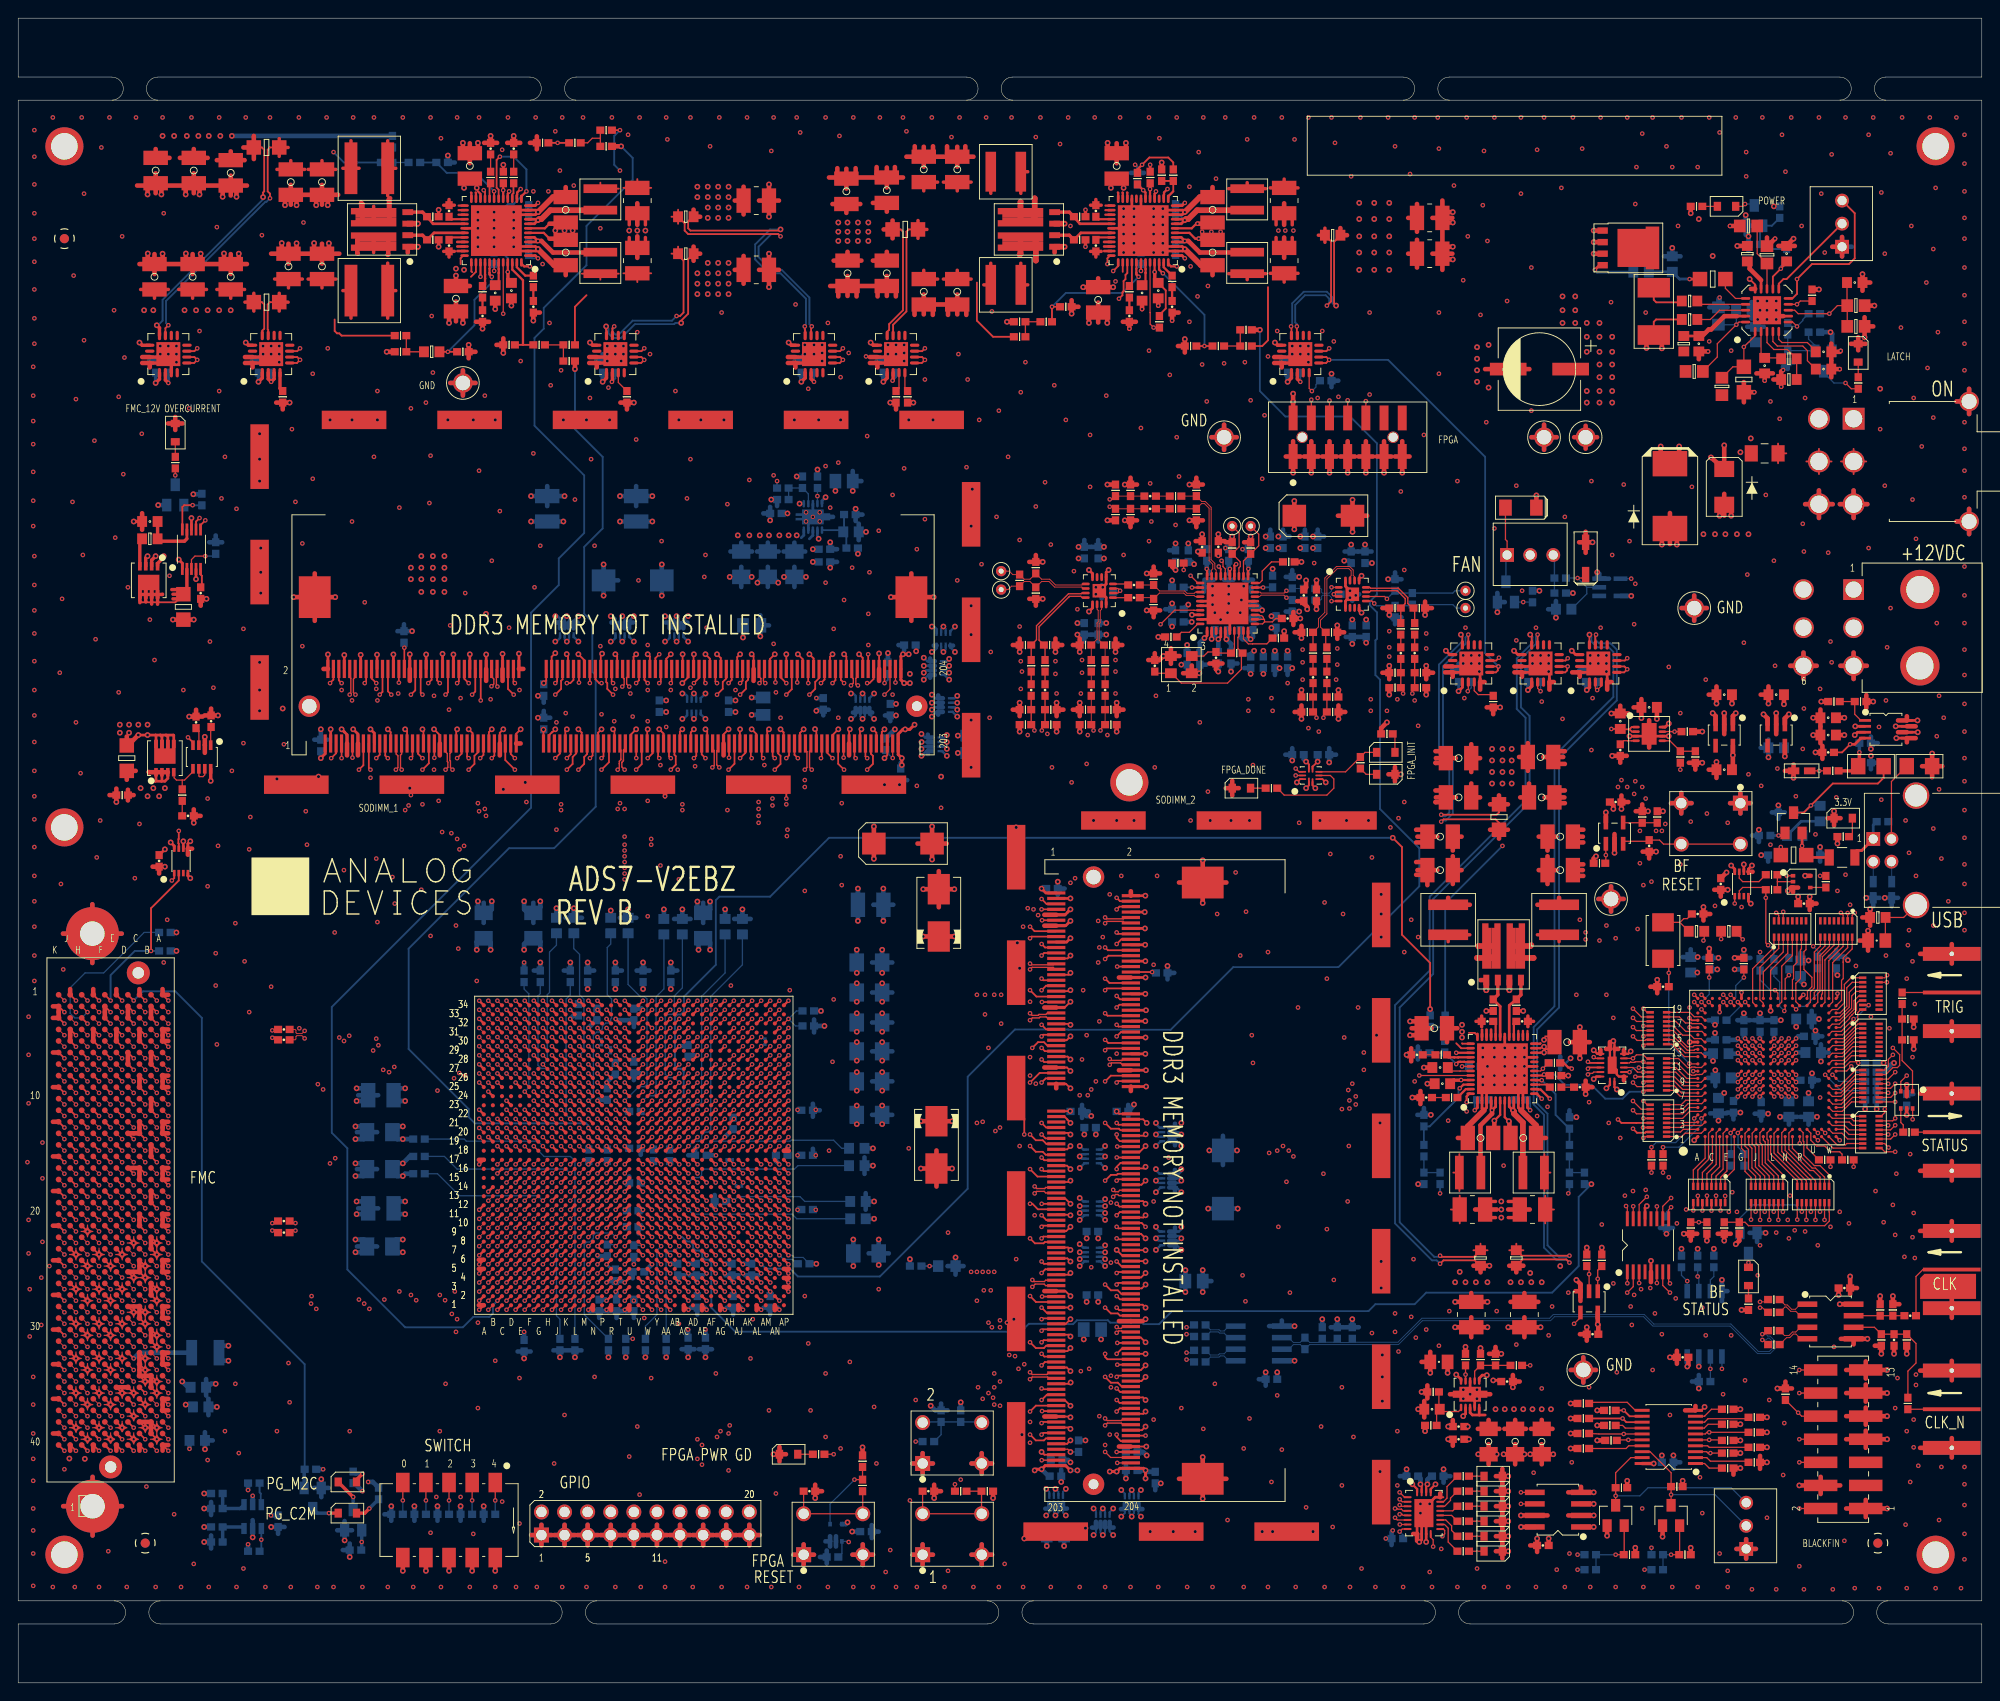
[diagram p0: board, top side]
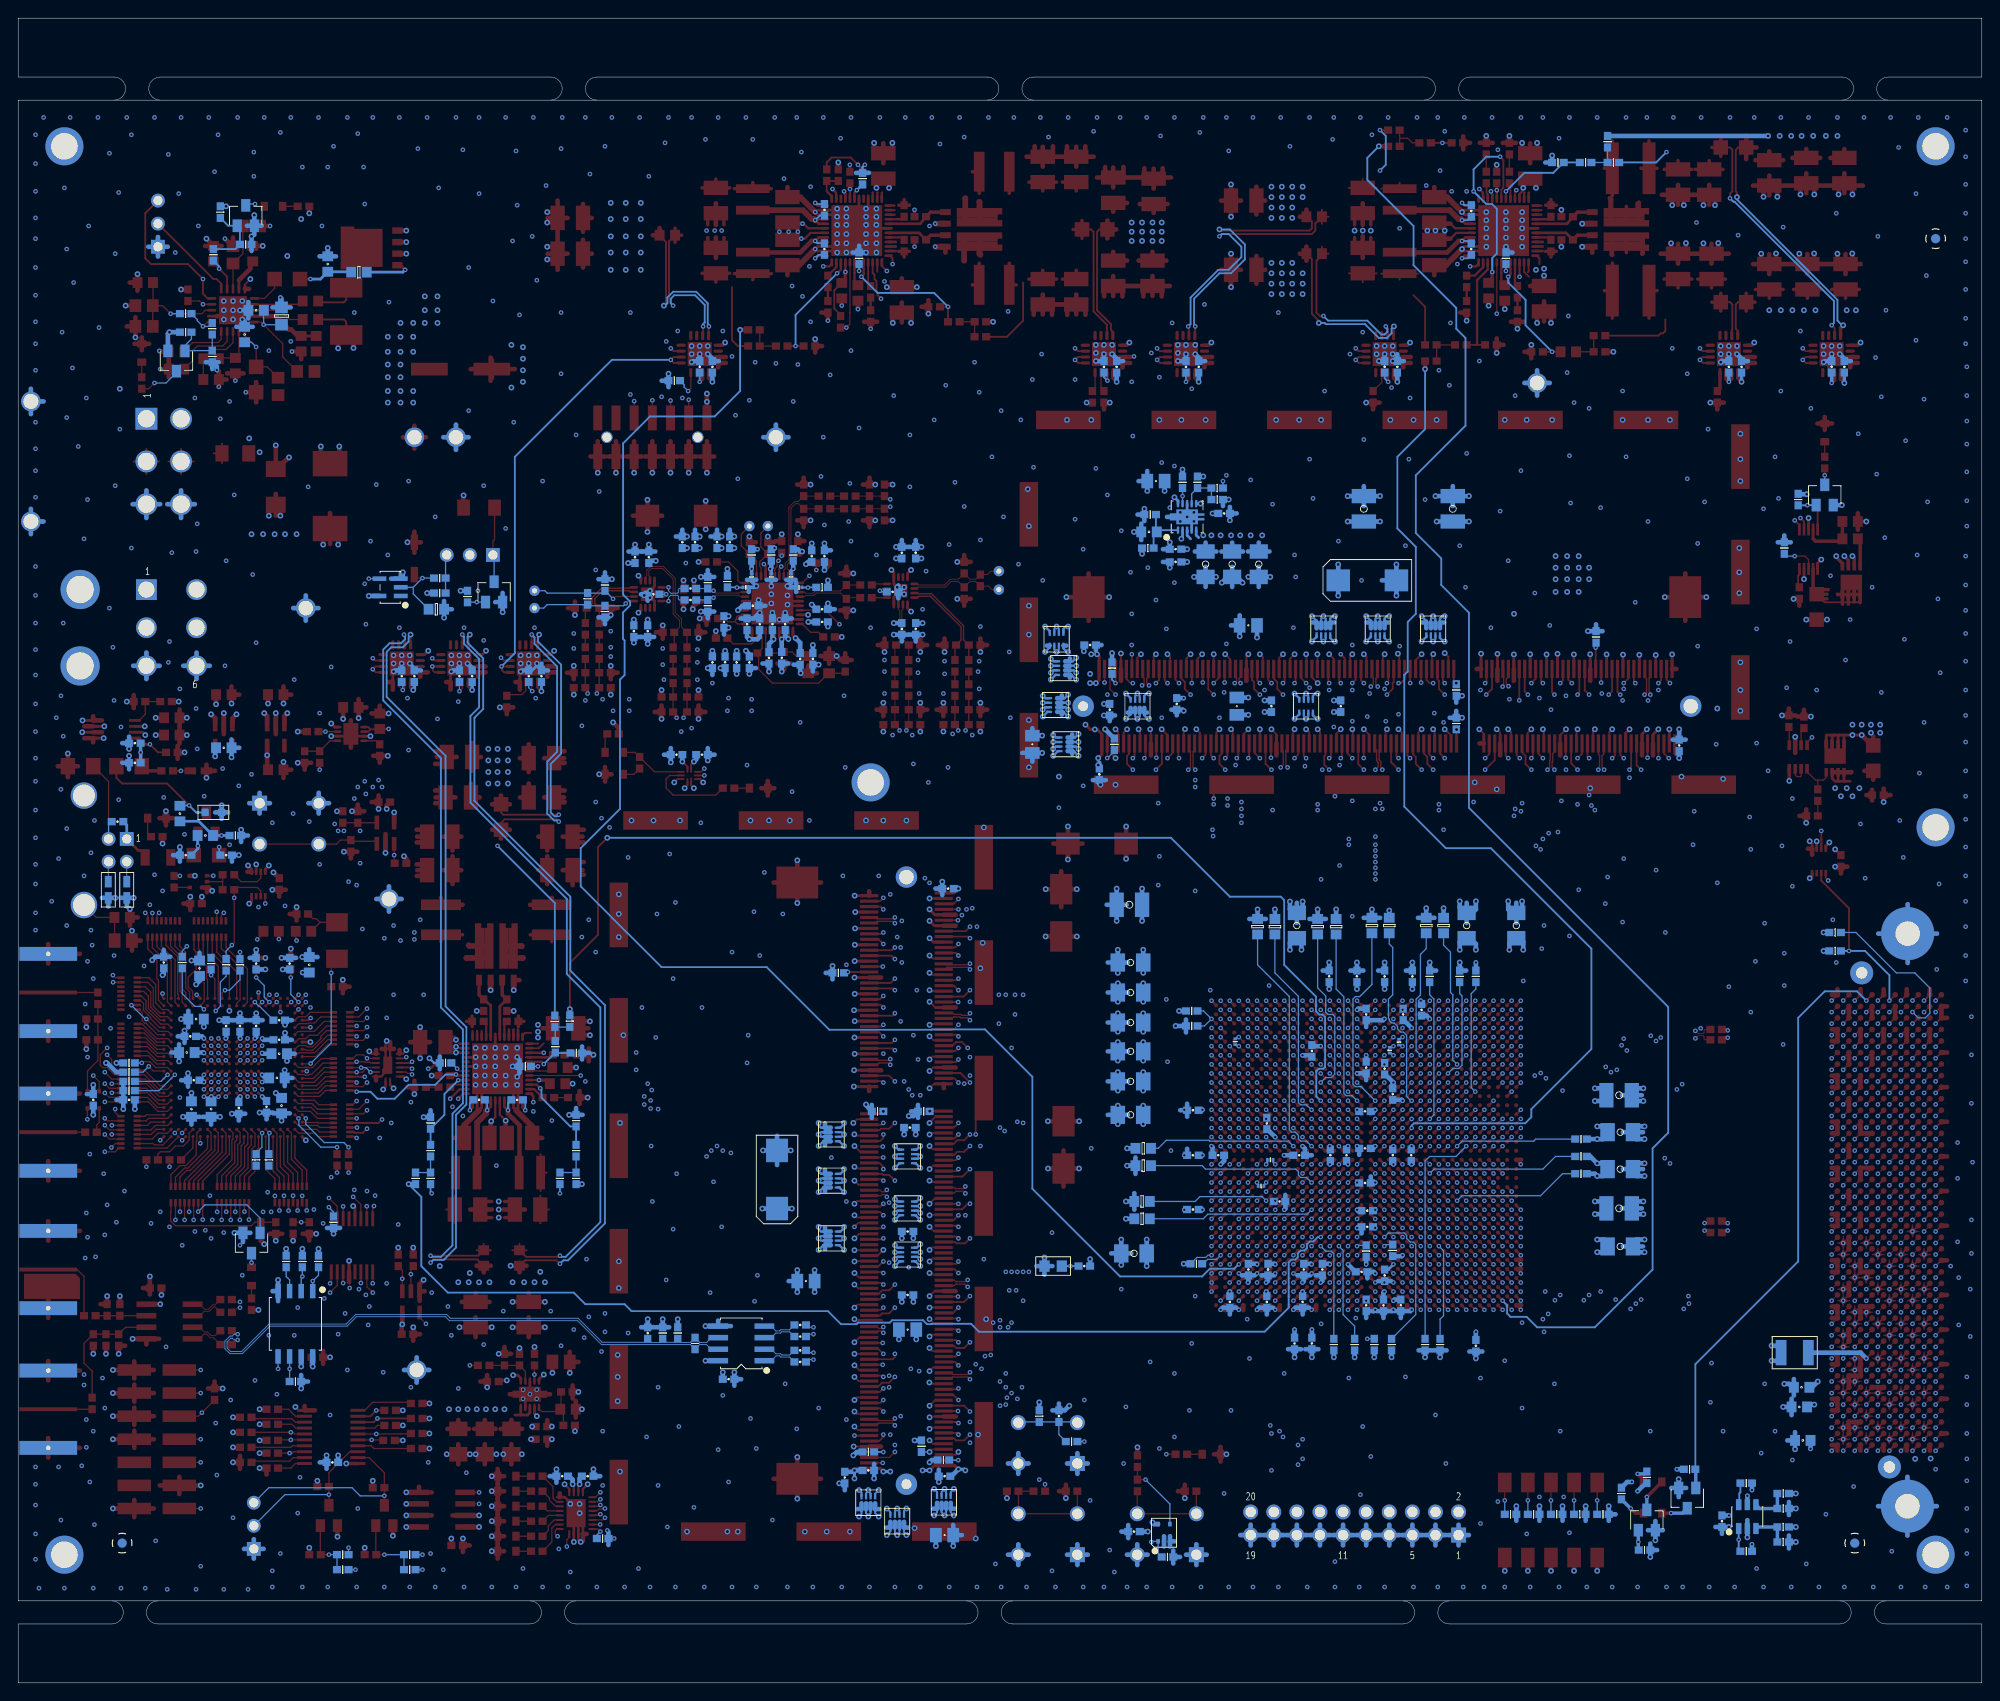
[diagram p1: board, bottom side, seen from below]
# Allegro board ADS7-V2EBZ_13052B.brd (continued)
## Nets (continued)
ADCMP671-1_OVB: R323.1(N1) U44.6(OV_N)
ADCMP671-1_PWRGD_3P3: R335.1(N1) U23.1(A1) U44.1(PWRGD)
ADDR1: RN1.3(N1) U31.AP27(IO_L24N_T3_A00_D16_14)
ADDR2: RN1.2(N1) U31.AN27(IO_L24P_T3_A01_D17_14)
ADDR3: RN1.1(N1) U31.AP26(IO_L23N_T3_A02_D18_14)
ADDR4: RN4.16(N2) U31.AP25(IO_L23P_T3_A03_D19_14)
ADDR5: RN4.15(N2) U31.AN28(IO_L22N_T3_A04_D20_14)
ADM1178_ALERTB_3P3: Q12.1(G) R223.2(N2) U10.10(ALERTB)
ADM1178_EN: R340.1(N1) RN6.14(N2) U10.3(ON)
ADM1276_GPO2_1P8: R28.1(N1) RN8.15(N2) U9.9(GPO2/ALERT2_N)
ADM1276_LATCHB: R219.2(N2) R342.1(N1) U9.6(LATCH_N)
ADM1276_PWRGD: C29.2(N2) R214.1(N1) U9.12(PWRGD)
ADP1715_EN: R111.2(N2) R112.1(N1) U21.1(EN)
ADP5054_#1_BST1: C110.1(N1) U27.32(BST1)
ADP5054_#1_BST2: C111.1(N1) U27.28(BST2)
ADP5054_#1_BST3: C282.1(N1) U27.1(BST3)
ADP5054_#1_BST4: C281.1(N1) U27.12(BST4)
ADP5054_#1_COMP1: R146.2(N2) U27.40(COMP1)
ADP5054_#1_COMP3: R150.2(N2) U27.47(COMP3)
ADP5054_#1_COMP4: R149.2(N2) U27.15(COMP4)
ADP5054_#1_DL1: Q7.2(G) R44.1(N1) U27.31(DL1)
ADP5054_#1_DL2: Q7.4(G) R143.1(N1) U27.29(DL2)
ADP5054_#1_FB1: R265.2(N2) R267.1(N1) U27.41(FB1)
ADP5054_#1_FB3: R280.1(N1) R290.2(N2) U27.46(FB3)
ADP5054_#1_FB4: R279.1(N1) R287.2(N2) U27.16(FB4)
ADP5054_#1_PWRGD: R148.2(N2) RN8.16(N2) U27.17(PWRGD)
ADP5054_#1_SENSE1: C91.1(N1) C94.1(N1) C98.1(N1) C99.1(N1) L9.2(N2) L10.2(N2) R127.1(N1) R264.1(N1) U14.11(SENSEN)
ADP5054_#1_SENSE3: C122.1(N1) L11.2(N2) R157.1(N1) R289.1(N1) U15.11(SENSEN)
ADP5054_#1_SENSE4: C123.1(N1) L12.2(N2) R158.1(N1) R288.1(N1) U16.11(SENSEN)
ADP5054_#1_VREG: C115.1(N1) R147.1(N1) U27.13(CFG34) U27.45(VREG) U27.48(EN3)
ADP5054_#2_BST1: C24.1(N1) U2.32(BST1)
ADP5054_#2_BST2: C18.1(N1) U2.28(BST2)
ADP5054_#2_BST3: C146.1(N1) U2.1(BST3)
ADP5054_#2_BST4: C144.1(N1) U2.12(BST4)
ADP5054_#2_COMP1: R25.2(N2) U2.40(COMP1)
ADP5054_#2_COMP3: R26.2(N2) U2.47(COMP3)
ADP5054_#2_DL1: Q2.2(G) R15.1(N1) U2.31(DL1)
ADP5054_#2_DL2: Q2.4(G) R14.1(N1) U2.29(DL2)
ADP5054_#2_FB1: R23.2(N2) R24.1(N1) U2.41(FB1)
ADP5054_#2_FB3: R45.1(N1) R47.2(N2) U2.46(FB3)
ADP5054_#2_PWRGD: R6.2(N2) RN8.13(N2) U2.17(PWRGD)
ADP5054_#2_SENSE1: C4.1(N1) C5.1(N1) C42.1(N1) C43.1(N1) L5.2(N2) L6.2(N2) R13.1(N1) R41.1(N1) U7.11(SENSEN)
ADP5054_#2_SENSE3: C20.1(N1) C26.1(N1) L7.2(N2) L8.2(N2) R16.1(N1) R49.1(N1) U8.11(SENSEN)
ADP5054_#2_VREG: C46.1(N1) R5.1(N1) R8.1(N1) R42.1(N1) U2.45(VREG)
ADP5054_#3_BST1: C21.1(N1) U1.32(BST1)
ADP5054_#3_BST2: C12.1(N1) U1.28(BST2)
ADP5054_#3_BST3: C147.1(N1) U1.1(BST3)
ADP5054_#3_BST4: C145.1(N1) U1.12(BST4)
ADP5054_#3_COMP1: R20.2(N2) U1.40(COMP1)
ADP5054_#3_COMP2: R2.2(N2) U1.20(COMP2)
ADP5054_#3_COMP3: R21.2(N2) U1.47(COMP3)
ADP5054_#3_COMP4: R4.2(N2) U1.15(COMP4)
ADP5054_#3_DL1: Q1.2(G) R10.1(N1) U1.31(DL1)
ADP5054_#3_DL2: Q1.4(G) R9.1(N1) U1.29(DL2)
ADP5054_#3_FB1: R32.2(N2) R33.1(N1) U1.41(FB1)
ADP5054_#3_FB2: R207.1(N1) R208.2(N2) U1.19(FB2)
ADP5054_#3_FB3: R34.1(N1) R35.2(N2) U1.46(FB3)
ADP5054_#3_FB4: R37.1(N1) R38.2(N2) U1.16(FB4)
ADP5054_#3_PWRGD: R3.2(N2) RN8.14(N2) U1.17(PWRGD)
ADP5054_#3_SENSE1: C33.1(N1) C34.1(N1) L2.2(N2) R19.1(N1) R30.1(N1) U4.11(SENSEN)
ADP5054_#3_SENSE2: C10.1(N1) C11.1(N1) L1.2(N2) R1.1(N1) R210.1(N1) U3.11(SENSEN)
ADP5054_#3_SENSE3: C23.1(N1) L4.2(N2) R12.1(N1) R36.1(N1) U5.11(SENSEN)
ADP5054_#3_SENSE4: C14.1(N1) L3.2(N2) R11.1(N1) R39.1(N1) U6.11(SENSEN)
ADP5054_#3_VREG: C37.1(N1) U1.13(CFG34) U1.18(CFG12) U1.45(VREG)
ADP5054_SYNC: R42.2(N2) U1.44(SYNC/MODE) U2.44(SYNC/MODE) U27.44(SYNC/MODE)
ADP7105_PWRGD: R121.2(N2) RN7.11(N2) U18.7(PG)
ARDY: R260.1(N1) U31.AP29(IO_L20N_T3_A07_D23_14)
AREB: R263.2(N2) U25.1(A1) U31.AN25(IO_L21N_T3_DQS_A06_D22_14)
ASYNC_AMS1: RN2.15(N2) U26.1(OE_N) U31.AM28(IO_L22P_T3_A05_D21_14)
AWEB: R135.2(N2) R262.2(N2) U25.2(B1) U31.AM25(IO_L21P_T3_DQS_14)
BF_CLKBUF: R138.1(N1) U29.C19(CLKBUF)
BF_CLKOUT: RN2.14(N2) U31.AK28(IO_L13P_T2_MRCC_14)
BF_FPGA_RESET: R320.2(N2) RN7.10(N2) U43.1(OE)
BF_JTAG_EMU: P10.2(N1) R153.2(N2)
BF_JTAG_TCK: P10.8(N4) U29.V2(TCK)
BF_JTAG_TDI: P10.12(N6) U29.R1(TDI)
BF_JTAG_TDO: P10.14(N7) R152.2(N2)
BF_JTAG_TMS: P10.6(N3) U29.U2(TMS)
BF_JTAG_TRST: P10.10(N5) R174.1(N1) U29.U1(TRST)
BF_PCA9545_RESETB: R160.1(N1) RN7.12(N2) U34.1(A)
BF_RESETB: R133.2(N2) U24.1(RESET_N) U29.B18(RESET_N)
BF_SCL: R326.2(N2) R640.1(N1)
BF_SDA: R339.2(N2) R639.1(N1)
BF_SPARE0: RN7.9(N2) U31.AM26(IO_L19P_T3_A10_D26_14)
BF_SPARE1: RN11.11(N2) U31.AL26(IO_L18N_T2_A11_D27_14)
BF_SPARE2: RN10.12(N2) U31.AL25(IO_L18P_T2_A12_D28_14)
BF_SPARE3: RN9.15(N2) U31.AJ25(IO_L17N_T2_A13_D29_14)
BF_SPARE4: U31.AH24(IO_L17P_T2_A14_D30_14)
BF_SPI_CLK: R314.1(N1) RN11.14(N2) U32.6(S4) U41.6(SCLK)
BF_SPI_FLASH_CS: R302.2(N2) RN11.15(N2) U41.1(CS_N)
BF_SPI_FPGA_CS: RN10.16(N2) U32.3(S1)
BF_SPI_MISO: R300.2(N2) RN11.13(N2) U32.11(S3) U41.2(SO/SIO1)
BF_SPI_MOSI: RN11.12(N2) U32.14(S2) U41.5(SI/SIO0)
BF_STATUS: Q14.1(G) RN11.10(N2)
BF_VCC1V2: C88.2(N2) C255.1(N1) C256.1(N1) C257.1(N1) C258.1(N1) C259.1(N1) C261.1(N1) C266.1(N1) C269.1(N1) R130.1(N1) U21.3(OUT) U29.G12(VDDINT1) U29.G13(VDDINT2) U29.G14(VDDINT3) U29.H14(VDDINT4) U29.J14(VDDINT5) U29.K14(VDDINT6) U29.L14(VDDINT7) U29.M14(VDDINT8) U29.N14(VDDINT9) U29.P12(VDDINT10) U29.P13(VDDINT11) U29.P14(VDDINT12)
BF_VCC1V8: C87.2(N2) C101.1(N1) C102.1(N1) C132.2(N2) C133.1(N1) C267.1(N1) C268.1(N1) C275.1(N1) C276.1(N1) C277.1(N1) C278.1(N1) C279.1(N1) C280.1(N1) C340.1(N1) C343.1(N1) Q8.1(G) Q9.1(G) R3.1(N1) R6.1(N1) R28.2(N2) R111.1(N1) R121.1(N1) R123.2(N2) R133.1(N1) R140.1(N1) R141.1(N1) R148.1(N1) R156.1(N1) R159.2(N2) R160.2(N2) R204.2(N2) R205.2(N2) R275.1(N1) R276.1(N1) R299.1(N1) R300.1(N1) R302.1(N1) R382.1(N1) R557.2(N2) U19.5(VOUT) U25.8(VCC) U26.5(VCC) U28.1(VCCA) U28.15(T_R1_N) U29.G7(VDDEXT1) U29.G8(VDDEXT2) U29.G9(VDDEXT3) U29.G10(VDDEXT4) U29.G11(VDDEXT5) U29.H7(VDDEXT6) U29.H8(VDDEXT7) U29.J7(VDDEXT8) U29.J8(VDDEXT9) U29.K7(VDDEXT10) U29.K8(VDDEXT11) U29.L7(VDDEXT12) U29.L8(VDDMEM1) U29.M7(VDDMEM2) U29.M8(VDDMEM3) U29.N7(VDDMEM4) U29.N8(VDDMEM5) U29.P7(VDDMEM6) U29.P8(VDDMEM7) U29.P9(VDDMEM8) U29.P10(VDDMEM9) U29.P11(VDDMEM10) U32.13(VDD) U34.5(VCC) U37.1(VCCA) U37.2(T_R_N) U41.7(RESET_N/SIO3) U41.8(VCC) U43.5(VCC)
BF_VCC2V5: C228.2(N2) C244.1(N1) C245.1(N1) U19.3(EN) U20.5(OUT) U29.L19(VPPOTP) U29.R20(VDDOTP)
CCLK: R136.2(N2) R311.1(N1) U31.T9(CCLK_0)
CSIB: RN9.13(N2) U31.AG25(IO_L16P_T2_CSI_B_14)
DATA0: RN12.16(N2) U31.AN33(IO_L1P_T0_D00_MOSI_14)
DATA1: RN12.15(N2) U31.AN34(IO_L1N_T0_D01_DIN_14)
DATA2: RN12.14(N2) U31.AK34(IO_L2P_T0_D02_14)
DATA3: RN12.13(N2) U31.AL34(IO_L2N_T0_D03_14)
DATA4: RN12.12(N2) U31.AK32(IO_L4P_T0_D04_14)
DATA5: RN12.11(N2) U31.AK33(IO_L4N_T0_D05_14)
DATA6: RN12.10(N2) U31.AM32(IO_L5P_T0_D06_14)
DATA7: RN12.9(N2) U31.AN32(IO_L5N_T0_D07_14)
DATA8: RN5.16(N2) U31.AM33(IO_L6N_T0_D08_VREF_14)
DATA9: RN5.15(N2) U31.AP30(IO_L7P_T1_D09_14)
DATA10: RN5.14(N2) U31.AP31(IO_L7N_T1_D10_14)
DATA11: RN5.13(N2) U31.AJ30(IO_L8P_T1_D11_14)
DATA12: RN5.12(N2) U31.AK31(IO_L8N_T1_D12_14)
DATA13: RN5.11(N2) U31.AN30(IO_L9N_T1_DQS_D13_14)
DATA14: RN5.10(N2) U31.AJ29(IO_L10P_T1_D14_14)
DATA15: RN5.9(N2) U31.AK29(IO_L10N_T1_D15_14)
DDR1_PWRGD_1P8: R557.1(N1) RN10.10(N2) U39.9(PGOOD)
DDR2_PWRGD_1P8: R123.1(N1) RN10.9(N2) U35.9(PGOOD)
DDR3-1_ADDR00: P6.98(N50) U31.U31(IO_L10P_T1_17)
DDR3-1_ADDR01: P6.97(N50) U31.R32(IO_L9N_T1_DQS_17)
DDR3-1_ADDR02: P6.96(N49) U31.T31(IO_L9P_T1_DQS_17)
DDR3-1_ADDR03: P6.95(N49) U31.M31(IO_L8N_T1_17)
DDR3-1_ADDR04: P6.92(N47) U31.M30(IO_L8P_T1_17)
DDR3-1_ADDR05: P6.91(N47) U31.N30(IO_L7N_T1_17)
DDR3-1_ADDR06: P6.90(N46) U31.N29(IO_L7P_T1_17)
DDR3-1_ADDR07: P6.86(N44) U31.P26(IO_L6P_T0_17)
DDR3-1_ADDR08: P6.89(N46) U31.T25(IO_L5N_T0_17)
DDR3-1_ADDR09: P6.85(N44) U31.T24(IO_L5P_T0_17)
DDR3-1_ADDR10: P6.107(N55) U31.P25(IO_L4N_T0_17)
DDR3-1_ADDR11: P6.84(N43) U31.P24(IO_L4P_T0_17)
DDR3-1_ADDR12: P6.83(N43) U31.N28(IO_L2N_T0_17)
DDR3-1_ADDR13: P6.119(N61) U31.N27(IO_L2P_T0_17)
DDR3-1_ADDR14: P6.80(N41) U31.N25(IO_L1N_T0_17)
DDR3-1_ADDR15: P6.78(N40) U31.N24(IO_L1P_T0_17)
DDR3-1_BA0: P6.109(N56) U31.N33(IO_L22P_T3_17)
DDR3-1_BA1: P6.108(N55) U31.N34(IO_L22N_T3_17)
DDR3-1_BA2: P6.79(N41) U31.U33(IO_L23P_T3_17)
DDR3-1_CASB: P6.115(N59) U31.R33(IO_L24P_T3_17)
DDR3-1_CK0_N: P6.103(N53) U31.T30(IO_L14N_T2_SRCC_17)
DDR3-1_CK0_P: P6.101(N52) U31.T29(IO_L14P_T2_SRCC_17)
DDR3-1_CK1_N: P6.104(N53) U31.P31(IO_L11N_T1_SRCC_17)
DDR3-1_CK1_P: P6.102(N52) U31.R31(IO_L11P_T1_SRCC_17)
DDR3-1_CKE0: P6.73(N38) R243.2(N2) U31.R26(IO_L15P_T2_DQS_17)
DDR3-1_CKE1: P6.74(N38) R242.2(N2) U31.U27(IO_L17N_T2_17)
DDR3-1_CLK_REF_N: C77.2(N2) R102.2(N2) R116.1(N1) R626.2(N2) U31.P30(IO_L12N_T1_MRCC_17)
DDR3-1_CLK_REF_P: C78.2(N2) R103.1(N1) R117.1(N1) R626.1(N1) U31.P29(IO_L12P_T1_MRCC_17)
DDR3-1_DM0: P6.11(N6) U31.L23(IO_L1P_T0_18)
DDR3-1_DM1: P6.28(N14) U31.G33(IO_L7P_T1_18)
DDR3-1_DM2: P6.46(N23) U31.K28(IO_L16P_T2_18)
DDR3-1_DM3: P6.63(N32) U31.K31(IO_L19P_T3_18)
DDR3-1_DM4: P6.136(N69) U31.AA33(IO_L1P_T0_16)
DDR3-1_DM5: P6.153(N45) U31.AB31(IO_L7P_T1_16)
DDR3-1_DM6: P6.170(N53) U31.V29(IO_L16P_T2_16)
DDR3-1_DM7: P6.187(N62) U31.Y26(IO_L19P_T3_16)
DDR3-1_DQ00: P6.5(N3) U31.K23(IO_L1N_T0_18)
DDR3-1_DQ01: P6.7(N4) U31.M27(IO_L2P_T0_18)
DDR3-1_DQ02: P6.15(N8) U31.L28(IO_L2N_T0_18)
DDR3-1_DQ03: P6.17(N9) U31.M26(IO_L4P_T0_18)
DDR3-1_DQ04: P6.4(N2) U31.L26(IO_L4N_T0_18)
DDR3-1_DQ05: P6.6(N3) U31.K26(IO_L5P_T0_18)
DDR3-1_DQ06: P6.16(N8) U31.K27(IO_L5N_T0_18)
DDR3-1_DQ07: P6.18(N9) U31.M25(IO_L6P_T0_18)
DDR3-1_DQ08: P6.21(N11) U31.F34(IO_L7N_T1_18)
DDR3-1_DQ09: P6.23(N12) U31.E32(IO_L8P_T1_18)
DDR3-1_DQ10: P6.33(N17) U31.E33(IO_L8N_T1_18)
DDR3-1_DQ11: P6.35(N18) U31.F33(IO_L10P_T1_18)
DDR3-1_DQ12: P6.22(N11) U31.E34(IO_L10N_T1_18)
DDR3-1_DQ13: P6.24(N12) U31.H32(IO_L11P_T1_SRCC_18)
DDR3-1_DQ14: P6.34(N17) U31.G32(IO_L11N_T1_SRCC_18)
DDR3-1_DQ15: P6.36(N18) U31.G30(IO_L12P_T1_MRCC_18)
DDR3-1_DQ16: P6.39(N20) U31.H29(IO_L13P_T2_MRCC_18)
DDR3-1_DQ17: P6.41(N21) U31.H30(IO_L13N_T2_MRCC_18)
DDR3-1_DQ18: P6.51(N26) U31.J30(IO_L14P_T2_SRCC_18)
DDR3-1_DQ19: P6.53(N27) U31.J31(IO_L14N_T2_SRCC_18)
DDR3-1_DQ20: P6.40(N20) U31.J29(IO_L16N_T2_18)
DDR3-1_DQ21: P6.42(N21) U31.G28(IO_L17P_T2_18)
DDR3-1_DQ22: P6.50(N25) U31.F29(IO_L17N_T2_18)
DDR3-1_DQ23: P6.52(N26) U31.L29(IO_L18P_T2_18)
DDR3-1_DQ24: P6.57(N29) U31.K32(IO_L20P_T3_18)
DDR3-1_DQ25: P6.59(N30) U31.K33(IO_L20N_T3_18)
DDR3-1_DQ26: P6.67(N34) U31.L33(IO_L22P_T3_18)
DDR3-1_DQ27: P6.69(N35) U31.L34(IO_L22N_T3_18)
DDR3-1_DQ28: P6.56(N28) U31.K34(IO_L23P_T3_18)
DDR3-1_DQ29: P6.58(N29) U31.J34(IO_L23N_T3_18)
DDR3-1_DQ30: P6.68(N34) U31.L30(IO_L24P_T3_18)
DDR3-1_DQ31: P6.70(N35) U31.L31(IO_L24N_T3_18)
DDR3-1_DQ32: P6.129(N66) U31.AA34(IO_L1N_T0_16)
DDR3-1_DQ33: P6.131(N67) U31.V34(IO_L2P_T0_16)
DDR3-1_DQ34: P6.141(N39) U31.W34(IO_L2N_T0_16)
DDR3-1_DQ35: P6.143(N40) U31.Y33(IO_L4P_T0_16)
DDR3-1_DQ36: P6.130(N66) U31.Y34(IO_L4N_T0_16)
DDR3-1_DQ37: P6.132(N67) U31.AC32(IO_L5P_T0_16)
DDR3-1_DQ38: P6.140(N38) U31.AC33(IO_L5N_T0_16)
DDR3-1_DQ39: P6.142(N39) U31.V32(IO_L6P_T0_16)
DDR3-1_DQ40: P6.147(N42) U31.AB32(IO_L7N_T1_16)
DDR3-1_DQ41: P6.149(N43) U31.U30(IO_L8P_T1_16)
DDR3-1_DQ42: P6.157(N47) U31.V30(IO_L8N_T1_16)
DDR3-1_DQ43: P6.159(N48) U31.W32(IO_L10P_T1_16)
DDR3-1_DQ44: P6.146(N41) U31.Y32(IO_L10N_T1_16)
DDR3-1_DQ45: P6.148(N42) U31.Y31(IO_L11P_T1_SRCC_16)
DDR3-1_DQ46: P6.158(N47) U31.AA31(IO_L11N_T1_SRCC_16)
DDR3-1_DQ47: P6.160(N48) U31.W30(IO_L12P_T1_MRCC_16)
DDR3-1_DQ48: P6.163(N50) U31.AA28(IO_L13P_T2_MRCC_16)
DDR3-1_DQ49: P6.165(N51) U31.AA29(IO_L13N_T2_MRCC_16)
DDR3-1_DQ50: P6.175(N56) U31.Y28(IO_L14P_T2_SRCC_16)
DDR3-1_DQ51: P6.177(N57) U31.Y29(IO_L14N_T2_SRCC_16)
DDR3-1_DQ52: P6.164(N50) U31.W29(IO_L16N_T2_16)
DDR3-1_DQ53: P6.166(N51) U31.W26(IO_L17P_T2_16)
DDR3-1_DQ54: P6.174(N55) U31.W27(IO_L17N_T2_16)
DDR3-1_DQ55: P6.176(N56) U31.AB27(IO_L18P_T2_16)
DDR3-1_DQ56: P6.181(N59) U31.V24(IO_L20P_T3_16)
DDR3-1_DQ57: P6.183(N60) U31.V25(IO_L20N_T3_16)
DDR3-1_DQ58: P6.191(N64) U31.W24(IO_L22P_T3_16)
DDR3-1_DQ59: P6.193(N65) U31.W25(IO_L22N_T3_16)
DDR3-1_DQ60: P6.180(N58) U31.Y24(IO_L23P_T3_16)
DDR3-1_DQ61: P6.182(N59) U31.AA25(IO_L23N_T3_16)
DDR3-1_DQ62: P6.192(N64) U31.AA23(IO_L24P_T3_16)
DDR3-1_DQ63: P6.194(N65) U31.AA24(IO_L24N_T3_16)
DDR3-1_DQS0_N: P6.10(N5) U31.K24(IO_L3N_T0_DQS_18)
DDR3-1_DQS0_P: P6.12(N6) U31.L24(IO_L3P_T0_DQS_18)
DDR3-1_DQS1_N: P6.27(N14) U31.F31(IO_L9N_T1_DQS_18)
DDR3-1_DQS1_P: P6.29(N15) U31.F30(IO_L9P_T1_DQS_18)
DDR3-1_DQS2_N: P6.45(N23) U31.H28(IO_L15N_T2_DQS_18)
DDR3-1_DQS2_P: P6.47(N24) U31.J27(IO_L15P_T2_DQS_18)
DDR3-1_DQS3_N: P6.62(N31) U31.H34(IO_L21N_T3_DQS_18)
DDR3-1_DQS3_P: P6.64(N32) U31.H33(IO_L21P_T3_DQS_18)
DDR3-1_DQS4_N: P6.135(N69) U31.AC34(IO_L3N_T0_DQS_16)
DDR3-1_DQS4_P: P6.137(N70) U31.AB33(IO_L3P_T0_DQS_16)
DDR3-1_DQS5_N: P6.152(N44) U31.AB30(IO_L9N_T1_DQS_16)
DDR3-1_DQS5_P: P6.154(N45) U31.AA30(IO_L9P_T1_DQS_16)
DDR3-1_DQS6_N: P6.169(N53) U31.V28(IO_L15N_T2_DQS_16)
DDR3-1_DQS6_P: P6.171(N54) U31.V27(IO_L15P_T2_DQS_16)
DDR3-1_DQS7_N: P6.186(N61) U31.AB26(IO_L21N_T3_DQS_16)
DDR3-1_DQS7_P: P6.188(N62) U31.AA26(IO_L21P_T3_DQS_16)
DDR3-1_ODT0: P6.116(N59) U31.R27(IO_L15N_T2_DQS_17)
DDR3-1_ODT1: P6.120(N61) U31.U28(IO_L16P_T2_17)
DDR3-1_RASB: P6.110(N56) U31.P34(IO_L24N_T3_17)
DDR3-1_REF_EN: R559.1(N1) RN6.16(N2)
DDR3-1_RESETB: P6.30(N15) R241.2(N2) U31.G31(IO_L12N_T1_MRCC_18)
DDR3-1_S0B: P6.114(N58) U31.T28(IO_L16N_T2_17)
DDR3-1_S1B: P6.121(N62) U31.U26(IO_L17P_T2_17)
DDR3-1_SYS_CLK_N: C69.2(N2) R104.1(N1) R105.2(N2) R627.2(N2) U31.R29(IO_L13N_T2_MRCC_17)
DDR3-1_SYS_CLK_P: C70.2(N2) R106.1(N1) R107.1(N1) R627.1(N1) U31.R28(IO_L13P_T2_MRCC_17)
DDR3-1_TEMP_EVENTB: P6.198(N67) R240.2(N2) U31.U25(IO_L18P_T2_17)
DDR3-1_WEB: P6.113(N58) U31.T34(IO_L23N_T3_17)
DDR3-2_ADDR00: P5.98(N50) U31.AJ17(IO_L10P_T1_AD15P_35)
DDR3-2_ADDR01: P5.97(N50) U31.AL14(IO_L9N_T1_DQS_AD7N_35)
DDR3-2_ADDR02: P5.96(N49) U31.AK14(IO_L9P_T1_DQS_AD7P_35)
DDR3-2_ADDR03: P5.95(N49) U31.AL18(IO_L8N_T1_AD14N_35)
DDR3-2_ADDR04: P5.92(N47) U31.AK18(IO_L8P_T1_AD14P_35)
DDR3-2_ADDR05: P5.91(N47) U31.AM15(IO_L7N_T1_AD6N_35)
DDR3-2_ADDR06: P5.90(N46) U31.AL15(IO_L7P_T1_AD6P_35)
DDR3-2_ADDR07: P5.86(N44) U31.AM17(IO_L6P_T0_35)
DDR3-2_ADDR08: P5.89(N46) U31.AP14(IO_L5N_T0_AD13N_35)
DDR3-2_ADDR09: P5.85(N44) U31.AN14(IO_L5P_T0_AD13P_35)
DDR3-2_ADDR10: P5.107(N55) U31.AP16(IO_L4N_T0_35)
DDR3-2_ADDR11: P5.84(N43) U31.AP17(IO_L4P_T0_35)
DDR3-2_ADDR12: P5.83(N43) U31.AN18(IO_L2N_T0_AD12N_35)
DDR3-2_ADDR13: P5.119(N61) U31.AM18(IO_L2P_T0_AD12P_35)
DDR3-2_ADDR14: P5.80(N41) U31.AP15(IO_L1N_T0_AD4N_35)
DDR3-2_ADDR15: P5.78(N40) U31.AN15(IO_L1P_T0_AD4P_35)
DDR3-2_BA0: P5.109(N56) U31.AC17(IO_L22P_T3_35)
DDR3-2_BA1: P5.108(N55) U31.AD17(IO_L22N_T3_35)
DDR3-2_BA2: P5.79(N41) U31.AD14(IO_L23P_T3_35)
DDR3-2_CASB: P5.115(N59) U31.AD16(IO_L24P_T3_35)
DDR3-2_CK0_N: P5.103(N53) U31.AG16(IO_L14N_T2_SRCC_35)
DDR3-2_CK0_P: P5.101(N52) U31.AF16(IO_L14P_T2_SRCC_35)
DDR3-2_CK1_N: P5.104(N53) U31.AK16(IO_L11N_T1_SRCC_35)
DDR3-2_CK1_P: P5.102(N52) U31.AJ16(IO_L11P_T1_SRCC_35)
DDR3-2_CKE0: P5.73(N38) R282.2(N2) U31.AF18(IO_L15P_T2_DQS_35)
DDR3-2_CKE1: P5.74(N38) R281.2(N2) U31.AH18(IO_L17N_T2_35)
DDR3-2_CLK_REF_N: C75.2(N2) R100.2(N2) R114.1(N1) R301.2(N2) U31.AJ15(IO_L12N_T1_MRCC_35)
DDR3-2_CLK_REF_P: C76.2(N2) R101.1(N1) R115.1(N1) R301.1(N1) U31.AH15(IO_L12P_T1_MRCC_35)
DDR3-2_DM0: P5.11(N6) U31.AN24(IO_L1P_T0_36)
DDR3-2_DM1: P5.28(N14) U31.AM20(IO_L7P_T1_36)
DDR3-2_DM2: P5.46(N23) U31.AJ19(IO_L16P_T2_36)
DDR3-2_DM3: P5.63(N32) U31.AC19(IO_L19P_T3_36)
DDR3-2_DM4: P5.136(N69) U31.AE9(IO_L1P_T0_34)
DDR3-2_DM5: P5.153(N45) U31.AF11(IO_L7P_T1_34)
DDR3-2_DM6: P5.170(N53) U31.AL10(IO_L16P_T2_34)
DDR3-2_DM7: P5.187(N62) U31.AM12(IO_L19P_T3_34)
DDR3-2_DQ00: P5.5(N3) U31.AP24(IO_L1N_T0_36)
DDR3-2_DQ01: P5.7(N4) U31.AN20(IO_L2P_T0_36)
DDR3-2_DQ02: P5.15(N8) U31.AP20(IO_L2N_T0_36)
DDR3-2_DQ03: P5.17(N9) U31.AN19(IO_L4P_T0_36)
DDR3-2_DQ04: P5.4(N2) U31.AP19(IO_L4N_T0_36)
DDR3-2_DQ05: P5.6(N3) U31.AP21(IO_L5P_T0_36)
DDR3-2_DQ06: P5.16(N8) U31.AP22(IO_L5N_T0_36)
DDR3-2_DQ07: P5.18(N9) U31.AM23(IO_L6P_T0_36)
DDR3-2_DQ08: P5.21(N11) U31.AM21(IO_L7N_T1_36)
DDR3-2_DQ09: P5.23(N12) U31.AK24(IO_L8P_T1_36)
DDR3-2_DQ10: P5.33(N17) U31.AL24(IO_L8N_T1_36)
DDR3-2_DQ11: P5.35(N18) U31.AK23(IO_L10P_T1_36)
DDR3-2_DQ12: P5.22(N11) U31.AL23(IO_L10N_T1_36)
DDR3-2_DQ13: P5.24(N12) U31.AL20(IO_L11P_T1_SRCC_36)
DDR3-2_DQ14: P5.34(N17) U31.AL21(IO_L11N_T1_SRCC_36)
DDR3-2_DQ15: P5.36(N18) U31.AJ22(IO_L12P_T1_MRCC_36)
DDR3-2_DQ16: P5.39(N20) U31.AG22(IO_L13P_T2_MRCC_36)
DDR3-2_DQ17: P5.41(N21) U31.AH22(IO_L13N_T2_MRCC_36)
DDR3-2_DQ18: P5.51(N26) U31.AJ21(IO_L14P_T2_SRCC_36)
DDR3-2_DQ19: P5.53(N27) U31.AK21(IO_L14N_T2_SRCC_36)
DDR3-2_DQ20: P5.40(N20) U31.AJ20(IO_L16N_T2_36)
DDR3-2_DQ21: P5.42(N21) U31.AH23(IO_L17P_T2_36)
DDR3-2_DQ22: P5.50(N25) U31.AJ24(IO_L17N_T2_36)
DDR3-2_DQ23: P5.52(N26) U31.AG20(IO_L18P_T2_36)
DDR3-2_DQ24: P5.57(N29) U31.AD22(IO_L20P_T3_36)
DDR3-2_DQ25: P5.59(N30) U31.AE22(IO_L20N_T3_36)
DDR3-2_DQ26: P5.67(N34) U31.AD21(IO_L22P_T3_36)
DDR3-2_DQ27: P5.69(N35) U31.AE21(IO_L22N_T3_36)
DDR3-2_DQ28: P5.56(N28) U31.AD19(IO_L23P_T3_36)
DDR3-2_DQ29: P5.58(N29) U31.AE19(IO_L23N_T3_36)
DDR3-2_DQ30: P5.68(N34) U31.AF21(IO_L24P_T3_36)
DDR3-2_DQ31: P5.70(N35) U31.AG21(IO_L24N_T3_36)
DDR3-2_DQ32: P5.129(N66) U31.AE8(IO_L1N_T0_34)
DDR3-2_DQ33: P5.131(N67) U31.AC10(IO_L2P_T0_34)
DDR3-2_DQ34: P5.141(N39) U31.AC9(IO_L2N_T0_34)
DDR3-2_DQ35: P5.143(N40) U31.AD10(IO_L4P_T0_34)
DDR3-2_DQ36: P5.130(N66) U31.AD9(IO_L4N_T0_34)
DDR3-2_DQ37: P5.132(N67) U31.AF9(IO_L5P_T0_34)
DDR3-2_DQ38: P5.140(N38) U31.AF8(IO_L5N_T0_34)
DDR3-2_DQ39: P5.142(N39) U31.AD12(IO_L6P_T0_34)
DDR3-2_DQ40: P5.147(N42) U31.AG11(IO_L7N_T1_34)
DDR3-2_DQ41: P5.149(N43) U31.AG8(IO_L8P_T1_34)
DDR3-2_DQ42: P5.157(N47) U31.AH8(IO_L8N_T1_34)
DDR3-2_DQ43: P5.159(N48) U31.AF10(IO_L10P_T1_34)
DDR3-2_DQ44: P5.146(N41) U31.AG10(IO_L10N_T1_34)
DDR3-2_DQ45: P5.148(N42) U31.AH10(IO_L11P_T1_SRCC_34)
DDR3-2_DQ46: P5.158(N47) U31.AJ10(IO_L11N_T1_SRCC_34)
DDR3-2_DQ47: P5.160(N48) U31.AH9(IO_L12P_T1_MRCC_34)
DDR3-2_DQ48: P5.163(N50) U31.AJ11(IO_L13P_T2_MRCC_34)
DDR3-2_DQ49: P5.165(N51) U31.AK11(IO_L13N_T2_MRCC_34)
DDR3-2_DQ50: P5.175(N56) U31.AJ12(IO_L14P_T2_SRCC_34)
DDR3-2_DQ51: P5.177(N57) U31.AK12(IO_L14N_T2_SRCC_34)
DDR3-2_DQ52: P5.164(N50) U31.AM10(IO_L16N_T2_34)
DDR3-2_DQ53: P5.166(N51) U31.AK9(IO_L17P_T2_34)
DDR3-2_DQ54: P5.174(N55) U31.AL9(IO_L17N_T2_34)
DDR3-2_DQ55: P5.176(N56) U31.AL11(IO_L18P_T2_34)
DDR3-2_DQ56: P5.181(N59) U31.AN9(IO_L20P_T3_34)
DDR3-2_DQ57: P5.183(N60) U31.AP9(IO_L20N_T3_34)
DDR3-2_DQ58: P5.191(N64) U31.AP12(IO_L22P_T3_34)
DDR3-2_DQ59: P5.193(N65) U31.AP11(IO_L22N_T3_34)
DDR3-2_DQ60: P5.180(N58) U31.AM13(IO_L23P_T3_34)
DDR3-2_DQ61: P5.182(N59) U31.AN13(IO_L23N_T3_34)
DDR3-2_DQ62: P5.192(N64) U31.AK13(IO_L24P_T3_34)
DDR3-2_DQ63: P5.194(N65) U31.AL13(IO_L24N_T3_34)
DDR3-2_DQS0_N: P5.10(N5) U31.AN22(IO_L3N_T0_DQS_36)
DDR3-2_DQS0_P: P5.12(N6) U31.AM22(IO_L3P_T0_DQS_36)
DDR3-2_DQS1_N: P5.27(N14) U31.AL19(IO_L9N_T1_DQS_36)
DDR3-2_DQS1_P: P5.29(N15) U31.AK19(IO_L9P_T1_DQS_36)
DDR3-2_DQS2_N: P5.45(N23) U31.AG23(IO_L15N_T2_DQS_36)
DDR3-2_DQS2_P: P5.47(N24) U31.AF23(IO_L15P_T2_DQS_36)
DDR3-2_DQS3_N: P5.62(N31) U31.AF20(IO_L21N_T3_DQS_36)
DDR3-2_DQS3_P: P5.64(N32) U31.AF19(IO_L21P_T3_DQS_36)
DDR3-2_DQS4_N: P5.135(N69) U31.AE11(IO_L3N_T0_DQS_34)
DDR3-2_DQS4_P: P5.137(N70) U31.AE12(IO_L3P_T0_DQS_34)
DDR3-2_DQS5_N: P5.152(N44) U31.AH12(IO_L9N_T1_DQS_34)
DDR3-2_DQS5_P: P5.154(N45) U31.AG12(IO_L9P_T1_DQS_34)
DDR3-2_DQS6_N: P5.169(N53) U31.AL8(IO_L15N_T2_DQS_34)
DDR3-2_DQS6_P: P5.171(N54) U31.AK8(IO_L15P_T2_DQS_34)
DDR3-2_DQS7_N: P5.186(N61) U31.AP10(IO_L21N_T3_DQS_34)
DDR3-2_DQS7_P: P5.188(N62) U31.AN10(IO_L21P_T3_DQS_34)
DDR3-2_ODT0: P5.116(N59) U31.AG18(IO_L15N_T2_DQS_35)
DDR3-2_ODT1: P5.120(N61) U31.AF15(IO_L16P_T2_35)
DDR3-2_RASB: P5.110(N56) U31.AD15(IO_L24N_T3_35)
DDR3-2_REF_EN: R658.1(N1) RN6.15(N2)
DDR3-2_RESETB: P5.30(N15) R268.2(N2) U31.AK22(IO_L12N_T1_MRCC_36)
DDR3-2_S0B: P5.114(N58) U31.AG15(IO_L16N_T2_35)
DDR3-2_S1B: P5.121(N62) U31.AH19(IO_L17P_T2_35)
DDR3-2_SYS_CLK_N: C71.2(N2) R98.2(N2) R108.1(N1) R331.2(N2) U31.AH17(IO_L13N_T2_MRCC_35)
DDR3-2_SYS_CLK_P: C72.2(N2) R99.1(N1) R109.1(N1) R331.1(N1) U31.AG17(IO_L13P_T2_MRCC_35)
DDR3-2_TEMP_EVENTB: P5.198(N67) R316.2(N2) U31.AH14(IO_L18P_T2_35)
DDR3-2_WEB: P5.113(N58) U31.AE13(IO_L23N_T3_35)
DDR3_1V5_EN: RN7.15(N2) U2.39(EN1)
DONE: R304.1(N1) RN9.12(N2) U22.9(A2) U31.V8(DONE_0)
FAN_PWM: Q13.1(G) R235.2(N2) RN10.14(N2) U31.AH28(IO_L18N_T2_A23_15)
FAN_TACH: RN10.15(N2) U31.AD26(IO_L19P_T3_A22_15) U40.4(Y)
FMC-1_3P3VAUX: F2.2(N2) P1.D32(N32)
FMC-1_CLK0_M2C_N: P1.H5(N5) U31.F21(IO_L13N_T2_MRCC_37)
FMC-1_CLK0_M2C_P: P1.H4(N4) U31.G21(IO_L13P_T2_MRCC_37)
FMC-1_CLK1_M2C_N: P1.G3(N3) U31.D16(IO_L13N_T2_MRCC_38)
FMC-1_CLK1_M2C_P: P1.G2(N2) U31.E16(IO_L13P_T2_MRCC_38)
FMC-1_CLK2_BIDIR_N: P1.K5(N5) U31.G22(IO_L14N_T2_SRCC_37)
FMC-1_CLK2_BIDIR_P: P1.K4(N4) U31.H22(IO_L14P_T2_SRCC_37)
FMC-1_CLK3_BIDIR_N: P1.J3(N3) U31.D17(IO_L14N_T2_SRCC_38)
FMC-1_CLK3_BIDIR_P: P1.J2(N2) U31.E17(IO_L14P_T2_SRCC_38)
FMC-1_CLK_DIR_1P8: RN8.11(N2) U28.3(A0) U31.AG32(IO_L3P_T0_DQS_AD1P_15)
FMC-1_CLK_DIR_3P3: P1.B1(N1) U28.14(B0)
FMC-1_DP0_C2M_N: P1.C3(N3) U31.D1(MGTHTXN0_118)
FMC-1_DP0_C2M_P: P1.C2(N2) U31.D2(MGTHTXP0_118)
FMC-1_DP0_M2C_N: P1.C7(N7) U31.G3(MGTHRXN0_118)
FMC-1_DP0_M2C_P: P1.C6(N6) U31.G4(MGTHRXP0_118)
FMC-1_DP1_C2M_N: P1.A23(N23) U31.C3(MGTHTXN1_118)
FMC-1_DP1_C2M_P: P1.A22(N22) U31.C4(MGTHTXP1_118)
FMC-1_DP1_M2C_N: P1.A3(N3) U31.E3(MGTHRXN1_118)
FMC-1_DP1_M2C_P: P1.A2(N2) U31.E4(MGTHRXP1_118)
FMC-1_DP2_C2M_N: P1.A27(N27) U31.B1(MGTHTXN2_118)
FMC-1_DP2_C2M_P: P1.A26(N26) U31.B2(MGTHTXP2_118)
FMC-1_DP2_M2C_N: P1.A7(N7) U31.D5(MGTHRXN2_118)
FMC-1_DP2_M2C_P: P1.A6(N6) U31.D6(MGTHRXP2_118)
FMC-1_DP3_C2M_N: P1.A31(N31) U31.A3(MGTHTXN3_118)
FMC-1_DP3_C2M_P: P1.A30(N30) U31.A4(MGTHTXP3_118)
FMC-1_DP3_M2C_N: P1.A11(N11) U31.B5(MGTHRXN3_118)
FMC-1_DP3_M2C_P: P1.A10(N10) U31.B6(MGTHRXP3_118)
FMC-1_DP4_C2M_N: P1.A35(N35) U31.M1(MGTHTXN0_117)
FMC-1_DP4_C2M_P: P1.A34(N34) U31.M2(MGTHTXP0_117)
FMC-1_DP4_M2C_N: P1.A15(N15) U31.N3(MGTHRXN0_117)
FMC-1_DP4_M2C_P: P1.A14(N14) U31.N4(MGTHRXP0_117)
FMC-1_DP5_C2M_N: P1.A39(N39) U31.K1(MGTHTXN1_117)
FMC-1_DP5_C2M_P: P1.A38(N38) U31.K2(MGTHTXP1_117)
FMC-1_DP5_M2C_N: P1.A19(N19) U31.L3(MGTHRXN1_117)
FMC-1_DP5_M2C_P: P1.A18(N18) U31.L4(MGTHRXP1_117)
FMC-1_DP6_C2M_N: P1.B37(N37) U31.H1(MGTHTXN2_117)
FMC-1_DP6_C2M_P: P1.B36(N36) U31.H2(MGTHTXP2_117)
FMC-1_DP6_M2C_N: P1.B17(N17) U31.K5(MGTHRXN2_117)
FMC-1_DP6_M2C_P: P1.B16(N16) U31.K6(MGTHRXP2_117)
FMC-1_DP7_C2M_N: P1.B33(N33) U31.F1(MGTHTXN3_117)
FMC-1_DP7_C2M_P: P1.B32(N32) U31.F2(MGTHTXP3_117)
FMC-1_DP7_M2C_N: P1.B13(N13) U31.J3(MGTHRXN3_117)
FMC-1_DP7_M2C_P: P1.B12(N12) U31.J4(MGTHRXP3_117)
FMC-1_DP8_C2M_N: P1.B29(N29) U31.Y1(MGTHTXN0_116)
FMC-1_DP8_C2M_P: P1.B28(N28) U31.Y2(MGTHTXP0_116)
FMC-1_DP8_M2C_N: P1.B9(N9) U31.AA3(MGTHRXN0_116)
FMC-1_DP8_M2C_P: P1.B8(N8) U31.AA4(MGTHRXP0_116)
FMC-1_DP9_C2M_N: P1.B25(N25) U31.V1(MGTHTXN1_116)
FMC-1_DP9_C2M_P: P1.B24(N24) U31.V2(MGTHTXP1_116)
FMC-1_DP9_M2C_N: P1.B5(N5) U31.W3(MGTHRXN1_116)
FMC-1_DP9_M2C_P: P1.B4(N4) U31.W4(MGTHRXP1_116)
FMC-1_GBTCLK0_M2C_C_N: C107.2(N2) U31.M5(MGTREFCLK0N_117)
FMC-1_GBTCLK0_M2C_C_P: C108.2(N2) U31.M6(MGTREFCLK0P_117)
FMC-1_GBTCLK0_M2C_N: C107.1(N1) P1.D5(N5)
FMC-1_GBTCLK0_M2C_P: C108.1(N1) P1.D4(N4)
FMC-1_GBTCLK1_M2C_C_N: C124.2(N2) U31.F5(MGTREFCLK0N_118)
FMC-1_GBTCLK1_M2C_C_P: C121.2(N2) U31.F6(MGTREFCLK0P_118)
FMC-1_GBTCLK1_M2C_N: C124.1(N1) P1.B21(N21)
FMC-1_GBTCLK1_M2C_P: C121.1(N1) P1.B20(N20)
FMC-1_HA00_N_CC: P1.F5(N5) U31.F10(IO_L12N_T1_MRCC_39)
FMC-1_HA00_P_CC: P1.F4(N4) U31.F11(IO_L12P_T1_MRCC_39)
FMC-1_HA01_N_CC: P1.E3(N3) U31.D11(IO_L11N_T1_SRCC_39)
FMC-1_HA01_P_CC: P1.E2(N2) U31.E11(IO_L11P_T1_SRCC_39)
FMC-1_HA02_N: P1.K8(N8) U31.A8(IO_L1N_T0_39)
FMC-1_HA02_P: P1.K7(N7) U31.A9(IO_L1P_T0_39)
FMC-1_HA03_N: P1.J7(N7) U31.A10(IO_L2N_T0_39)
FMC-1_HA03_P: P1.J6(N6) U31.A11(IO_L2P_T0_39)
FMC-1_HA04_N: P1.F8(N8) U31.B8(IO_L3N_T0_DQS_39)
FMC-1_HA04_P: P1.F7(N7) U31.C9(IO_L3P_T0_DQS_39)
FMC-1_HA05_N: P1.E7(N7) U31.B10(IO_L4N_T0_39)
FMC-1_HA05_P: P1.E6(N6) U31.B11(IO_L4P_T0_39)
FMC-1_HA06_N: P1.K11(N11) U31.C8(IO_L5N_T0_39)
FMC-1_HA06_P: P1.K10(N10) U31.D9(IO_L5P_T0_39)
FMC-1_HA07_N: P1.J10(N10) U31.B12(IO_L6N_T0_VREF_39)
FMC-1_HA07_P: P1.J9(N9) U31.C12(IO_L6P_T0_39)
FMC-1_HA08_N: P1.F11(N11) U31.E8(IO_L7N_T1_39)
FMC-1_HA08_P: P1.F10(N10) U31.E9(IO_L7P_T1_39)
FMC-1_HA09_N: P1.E10(N10) U31.D12(IO_L8N_T1_39)
FMC-1_HA09_P: P1.E9(N9) U31.E12(IO_L8P_T1_39)
FMC-1_HA10_N: P1.K14(N14) U31.F8(IO_L9N_T1_DQS_39)
FMC-1_HA10_P: P1.K13(N13) U31.F9(IO_L9P_T1_DQS_39)
FMC-1_HA11_N: P1.J13(N13) U31.C10(IO_L10N_T1_39)
FMC-1_HA11_P: P1.J12(N12) U31.D10(IO_L10P_T1_39)
FMC-1_HA12_N: P1.F14(N14) U31.J9(IO_L15N_T2_DQS_39)
FMC-1_HA12_P: P1.F13(N13) U31.J10(IO_L15P_T2_DQS_39)
FMC-1_HA13_N: P1.E13(N13) U31.G12(IO_L16N_T2_39)
FMC-1_HA13_P: P1.E12(N12) U31.H12(IO_L16P_T2_39)
FMC-1_HA14_N: P1.J16(N16) U31.J11(IO_L17N_T2_39)
FMC-1_HA14_P: P1.J15(N15) U31.K11(IO_L17P_T2_39)
FMC-1_HA15_N: P1.F17(N17) U31.G8(IO_L18N_T2_39)
FMC-1_HA15_P: P1.F16(N16) U31.H8(IO_L18P_T2_39)
FMC-1_HA16_N: P1.E16(N16) U31.J12(IO_L19N_T3_VREF_39)
FMC-1_HA16_P: P1.E15(N15) U31.K12(IO_L19P_T3_39)
FMC-1_HA17_N_CC: P1.K17(N17) U31.G10(IO_L13N_T2_MRCC_39)
FMC-1_HA17_P_CC: P1.K16(N16) U31.G11(IO_L13P_T2_MRCC_39)
FMC-1_HA18_N: P1.J19(N19) U31.H9(IO_L14N_T2_SRCC_39)
FMC-1_HA18_P: P1.J18(N18) U31.H10(IO_L14P_T2_SRCC_39)
FMC-1_HA19_N: P1.F20(N20) U31.K9(IO_L20N_T3_39)
FMC-1_HA19_P: P1.F19(N19) U31.L9(IO_L20P_T3_39)
FMC-1_HA20_N: P1.E19(N19) U31.K13(IO_L21N_T3_DQS_39)
FMC-1_HA20_P: P1.E18(N18) U31.L13(IO_L21P_T3_DQS_39)
FMC-1_HA21_N: P1.K20(N20) U31.L10(IO_L22N_T3_39)
FMC-1_HA21_P: P1.K19(N19) U31.M10(IO_L22P_T3_39)
FMC-1_HA22_N: P1.J22(N22) U31.M12(IO_L23N_T3_39)
FMC-1_HA22_P: P1.J21(N21) U31.M13(IO_L23P_T3_39)
FMC-1_HA23_N: P1.K23(N23) U31.L11(IO_L24N_T3_39)
FMC-1_HA23_P: P1.K22(N22) U31.M11(IO_L24P_T3_39)
FMC-1_HB00_N_CC: P1.K26(N26) U31.B28(IO_L12N_T1_MRCC_19)
FMC-1_HB00_P_CC: P1.K25(N25) U31.C27(IO_L12P_T1_MRCC_19)
FMC-1_HB01_N: P1.J25(N25) U31.B32(IO_L1N_T0_19)
FMC-1_HB01_P: P1.J24(N24) U31.B31(IO_L1P_T0_19)
FMC-1_HB02_N: P1.F23(N23) U31.C34(IO_L2N_T0_19)
FMC-1_HB02_P: P1.F22(N22) U31.D34(IO_L2P_T0_19)
FMC-1_HB03_N: P1.E22(N22) U31.A33(IO_L3N_T0_DQS_19)
FMC-1_HB03_P: P1.E21(N21) U31.B33(IO_L3P_T0_DQS_19)
FMC-1_HB04_N: P1.F26(N26) U31.B34(IO_L4N_T0_19)
FMC-1_HB04_P: P1.F25(N25) U31.C33(IO_L4P_T0_19)
FMC-1_HB05_N: P1.E25(N25) U31.D31(IO_L5N_T0_19)
FMC-1_HB05_P: P1.E24(N24) U31.E31(IO_L5P_T0_19)
FMC-1_HB06_N_CC: P1.K29(N29) U31.D27(IO_L11N_T1_SRCC_19)
FMC-1_HB06_P_CC: P1.K28(N28) U31.E27(IO_L11P_T1_SRCC_19)
FMC-1_HB07_N: P1.J28(N28) U31.C32(IO_L6N_T0_VREF_19)
FMC-1_HB07_P: P1.J27(N27) U31.D32(IO_L6P_T0_19)
FMC-1_HB08_N: P1.F29(N29) U31.B25(IO_L7N_T1_19)
FMC-1_HB08_P: P1.F28(N28) U31.C25(IO_L7P_T1_19)
FMC-1_HB09_N: P1.E28(N28) U31.A26(IO_L8N_T1_19)
FMC-1_HB09_P: P1.E27(N27) U31.A25(IO_L8P_T1_19)
FMC-1_HB10_N: P1.K32(N32) U31.D26(IO_L9N_T1_DQS_19)
FMC-1_HB10_P: P1.K31(N31) U31.E26(IO_L9P_T1_DQS_19)
FMC-1_HB11_N: P1.J31(N31) U31.B27(IO_L10N_T1_19)
FMC-1_HB11_P: P1.J30(N30) U31.B26(IO_L10P_T1_19)
FMC-1_HB12_N: P1.F32(N32) U31.C29(IO_L14N_T2_SRCC_19)
FMC-1_HB12_P: P1.F31(N31) U31.C28(IO_L14P_T2_SRCC_19)
FMC-1_HB13_N: P1.E31(N31) U31.A29(IO_L15N_T2_DQS_19)
FMC-1_HB13_P: P1.E30(N30) U31.A28(IO_L15P_T2_DQS_19)
FMC-1_HB14_N: P1.K35(N35) U31.D30(IO_L16N_T2_19)
FMC-1_HB14_P: P1.K34(N34) U31.D29(IO_L16P_T2_19)
FMC-1_HB15_N: P1.J34(N34) U31.A31(IO_L17N_T2_19)
FMC-1_HB15_P: P1.J33(N33) U31.A30(IO_L17P_T2_19)
FMC-1_HB16_N: P1.F35(N35) U31.E29(IO_L18N_T2_19)
FMC-1_HB16_P: P1.F34(N34) U31.E28(IO_L18P_T2_19)
FMC-1_HB17_N_CC: P1.K38(N38) U31.B30(IO_L13N_T2_MRCC_19)
FMC-1_HB17_P_CC: P1.K37(N37) U31.C30(IO_L13P_T2_MRCC_19)
FMC-1_HB18_N: P1.J37(N37) U31.H24(IO_L19N_T3_VREF_19)
FMC-1_HB18_P: P1.J36(N36) U31.J24(IO_L19P_T3_19)
FMC-1_HB19_N: P1.E34(N34) U31.H25(IO_L20N_T3_19)
FMC-1_HB19_P: P1.E33(N33) U31.J25(IO_L20P_T3_19)
FMC-1_HB20_N: P1.F38(N38) U31.F25(IO_L21N_T3_DQS_19)
FMC-1_HB20_P: P1.F37(N37) U31.G25(IO_L21P_T3_DQS_19)
FMC-1_HB21_N: P1.E37(N37) U31.F26(IO_L22N_T3_19)
FMC-1_HB21_P: P1.E36(N36) U31.G26(IO_L22P_T3_19)
FMC-1_LA00_N_CC: P1.G7(N7) U31.D21(IO_L12N_T1_MRCC_37)
FMC-1_LA00_P_CC: P1.G6(N6) U31.E21(IO_L12P_T1_MRCC_37)
FMC-1_LA01_N_CC: P1.D9(N9) U31.C20(IO_L11N_T1_SRCC_37)
FMC-1_LA01_P_CC: P1.D8(N8) U31.D20(IO_L11P_T1_SRCC_37)
FMC-1_LA02_N: P1.H8(N8) U31.K19(IO_L1N_T0_37)
FMC-1_LA02_P: P1.H7(N7) U31.L19(IO_L1P_T0_37)
FMC-1_LA03_N: P1.G10(N10) U31.L18(IO_L2N_T0_37)
FMC-1_LA03_P: P1.G9(N9) U31.M18(IO_L2P_T0_37)
FMC-1_LA04_N: P1.H11(N11) U31.H20(IO_L3N_T0_DQS_37)
FMC-1_LA04_P: P1.H10(N10) U31.J20(IO_L3P_T0_DQS_37)
FMC-1_LA05_N: P1.D12(N12) U31.J19(IO_L4N_T0_37)
FMC-1_LA05_P: P1.D11(N11) U31.K18(IO_L4P_T0_37)
FMC-1_LA06_N: P1.C11(N11) U31.L20(IO_L5N_T0_37)
FMC-1_LA06_P: P1.C10(N10) U31.M20(IO_L5P_T0_37)
FMC-1_LA07_N: P1.H14(N14) U31.G20(IO_L6N_T0_VREF_37)
FMC-1_LA07_P: P1.H13(N13) U31.H19(IO_L6P_T0_37)
FMC-1_LA08_N: P1.G13(N13) U31.A20(IO_L7N_T1_37)
FMC-1_LA08_P: P1.G12(N12) U31.A19(IO_L7P_T1_37)
FMC-1_LA09_N: P1.D15(N15) U31.D19(IO_L8N_T1_37)
FMC-1_LA09_P: P1.D14(N14) U31.E19(IO_L8P_T1_37)
FMC-1_LA10_N: P1.C15(N15) U31.A21(IO_L9N_T1_DQS_37)
FMC-1_LA10_P: P1.C14(N14) U31.B21(IO_L9P_T1_DQS_37)
FMC-1_LA11_N: P1.H17(N17) U31.B20(IO_L10N_T1_37)
FMC-1_LA11_P: P1.H16(N16) U31.C19(IO_L10P_T1_37)
FMC-1_LA12_N: P1.G16(N16) U31.F20(IO_L15N_T2_DQS_37)
FMC-1_LA12_P: P1.G15(N15) U31.F19(IO_L15P_T2_DQS_37)
FMC-1_LA13_N: P1.D18(N18) U31.G23(IO_L16N_T2_37)
FMC-1_LA13_P: P1.D17(N17) U31.H23(IO_L16P_T2_37)
FMC-1_LA14_N: P1.C19(N19) U31.J21(IO_L17N_T2_37)
FMC-1_LA14_P: P1.C18(N18) U31.K21(IO_L17P_T2_37)
FMC-1_LA15_N: P1.H20(N20) U31.J22(IO_L18N_T2_37)
FMC-1_LA15_P: P1.H19(N19) U31.K22(IO_L18P_T2_37)
FMC-1_LA16_N: P1.G19(N19) U31.D22(IO_L19N_T3_VREF_37)
FMC-1_LA16_P: P1.G18(N18) U31.E22(IO_L19P_T3_37)
FMC-1_LA17_N_CC: P1.D21(N21) U31.F15(IO_L12N_T1_MRCC_38)
FMC-1_LA17_P_CC: P1.D20(N20) U31.G15(IO_L12P_T1_MRCC_38)
FMC-1_LA18_N_CC: P1.C23(N23) U31.F16(IO_L11N_T1_SRCC_38)
FMC-1_LA18_P_CC: P1.C22(N22) U31.G16(IO_L11P_T1_SRCC_38)
FMC-1_LA19_N: P1.H23(N23) U31.H15(IO_L1N_T0_38)
FMC-1_LA19_P: P1.H22(N22) U31.J15(IO_L1P_T0_38)
FMC-1_LA20_N: P1.G22(N22) U31.L15(IO_L2N_T0_38)
FMC-1_LA20_P: P1.G21(N21) U31.M15(IO_L2P_T0_38)
FMC-1_LA21_N: P1.H26(N26) U31.M16(IO_L3N_T0_DQS_38)
FMC-1_LA21_P: P1.H25(N25) U31.M17(IO_L3P_T0_DQS_38)
FMC-1_LA22_N: P1.G25(N25) U31.K14(IO_L4N_T0_38)
FMC-1_LA22_P: P1.G24(N24) U31.L14(IO_L4P_T0_38)
FMC-1_LA23_N: P1.D24(N24) U31.J17(IO_L5N_T0_38)
FMC-1_LA23_P: P1.D23(N23) U31.K17(IO_L5P_T0_38)
FMC-1_LA24_N: P1.H29(N29) U31.J16(IO_L6N_T0_VREF_38)
FMC-1_LA24_P: P1.H28(N28) U31.K16(IO_L6P_T0_38)
FMC-1_LA25_N: P1.G28(N28) U31.E13(IO_L7N_T1_38)
FMC-1_LA25_P: P1.G27(N27) U31.F14(IO_L7P_T1_38)
FMC-1_LA26_N: P1.D27(N27) U31.H14(IO_L8N_T1_38)
FMC-1_LA26_P: P1.D26(N26) U31.J14(IO_L8P_T1_38)
FMC-1_LA27_N: P1.C27(N27) U31.G17(IO_L9N_T1_DQS_38)
FMC-1_LA27_P: P1.C26(N26) U31.H17(IO_L9P_T1_DQS_38)
FMC-1_LA28_N: P1.H32(N32) U31.F13(IO_L10N_T1_38)
FMC-1_LA28_P: P1.H31(N31) U31.G13(IO_L10P_T1_38)
FMC-1_LA29_N: P1.G31(N31) U31.D14(IO_L15N_T2_DQS_38)
FMC-1_LA29_P: P1.G30(N30) U31.E14(IO_L15P_T2_DQS_38)
FMC-1_LA30_N: P1.H35(N35) U31.E18(IO_L16N_T2_38)
FMC-1_LA30_P: P1.H34(N34) U31.F18(IO_L16P_T2_38)
FMC-1_LA31_N: P1.G34(N34) U31.C14(IO_L17N_T2_38)
FMC-1_LA31_P: P1.G33(N33) U31.D15(IO_L17P_T2_38)
FMC-1_LA32_N: P1.H38(N38) U31.C17(IO_L18N_T2_38)
FMC-1_LA32_P: P1.H37(N37) U31.C18(IO_L18P_T2_38)
FMC-1_LA33_N: P1.G37(N37) U31.B13(IO_L19N_T3_VREF_38)
FMC-1_LA33_P: P1.G36(N36) U31.C13(IO_L19P_T3_38)
FMC-1_PG_C2M_1P8: RN8.12(N2) U28.4(A1) U31.AH32(IO_L3N_T0_DQS_AD1N_15)
FMC-1_PG_C2M_3P3: P1.D1(N1) Q15.1(G) R322.1(N1) U28.13(B1)
FMC-1_PG_M2C_1P8: RN8.10(N2) U28.5(A2) U31.AH34(IO_L4P_T0_15)
FMC-1_PG_M2C_3P3: P1.F1(N1) R259.1(N1) U23.2(B1) U28.12(B2)
FMC-1_PRSNT_M2C_B_1P8: RN8.9(N2) U28.6(A3) U31.AJ34(IO_L4N_T0_15)
FMC-1_PRSNT_M2C_B_3P3: P1.H2(N2) R256.1(N1) U28.11(B3)
FMC-1_SCL: P1.C30(N30) R187.1(N1) U36.6(SC0)
FMC-1_SDA: P1.C31(N31) R184.1(N1) U36.5(SD0)
FMC-1_VIO_B_M2C: P1.J39(N39) P1.K40(N40) Q5.5(D1) Q5.6(D2) Q5.7(D3) Q5.8(D4) R113.1(N1) R324.2(N2) R336.2(N2)
FMC-1_VIO_B_M2C_ON: Q16.1(G) R486.2(N2) U17.4(ON-CLR_N) U23.7(Y1)
FMC-1_VIO_B_M2C_S: C243.2(N2) Q5.1(S1) Q5.2(S2) Q5.3(S3) R113.2(N2) R124.1(N1) R271.2(N2) U31.A32(VCCO_19_1) U31.B29(VCCO_19_2) U31.C26(VCCO_19_3) U31.D33(VCCO_19_4) U31.E30(VCCO_19_5) U31.F27(VCCO_19_6) U31.G24(VCCO_19_7)
FMC_1V8: C7.1(N1) C8.1(N1) C9.1(N1) C290.2(N2) C301.2(N2) C317.2(N2) C337.2(N2) P1.E39(N39) P1.F40(N40) P1.G39(N39) P1.H40(N40) R1.2(N2) R209.1(N1) R283.2(N2) R294.2(N2) R295.2(N2) U3.12(SENSEP) U3.13(VIN) U31.A12(VCCO_38_1) U31.A22(VCCO_37_1) U31.B9(VCCO_39_1) U31.B19(VCCO_37_2) U31.C16(VCCO_38_2) U31.D13(VCCO_38_3) U31.D23(VCCO_37_3) U31.E10(VCCO_39_2) U31.E20(VCCO_37_4) U31.F17(VCCO_38_4) U31.G14(VCCO_38_5) U31.H11(VCCO_39_3) U31.H21(VCCO_37_5) U31.J8(VCCO_39_4) U31.J18(VCCO_37_6) U31.K15(VCCO_38_6) U31.L12(VCCO_39_5) U31.M9(VCCO_39_6) U31.M19(VCCO_37_7)
FMC_1V8_EN: RN7.14(N2) U1.21(EN2)
FMC_3V3: C30.1(N1) C31.1(N1) C32.1(N1) C96.2(N2) C341.2(N2) C348.2(N2) P1.C39(N39) P1.D36(N36) P1.D38(N38) P1.D40(N40) R19.2(N2) R31.1(N1) R259.2(N2) R321.2(N2) R322.2(N2) R323.2(N2) R334.2(N2) R335.2(N2) U4.12(SENSEP) U4.13(VIN) U17.8(VCC) U23.8(VCC) U44.5(VDD)
FMC_3V3_EN: RN7.13(N2) U1.39(EN1)
FMC_12V0: C338.2(N2) P1.C35(N35) P1.C37(N37) Q4.1(S1) Q4.2(S2) Q4.3(S3)
FPGA_1V0: C84.1(N1) C85.1(N1) C92.1(N1) C93.1(N1) C97.P(N1) C103.P(N1) C120.P(N1) C287.2(N2) C295.2(N2) C296.2(N2) C297.2(N2) C298.2(N2) C299.2(N2) C300.2(N2) C305.2(N2) C306.2(N2) R127.2(N2) R266.1(N1) U14.12(SENSEP) U14.13(VIN) U31.AA10(VCCINT1) U31.AA12(VCCINT2) U31.AA16(VCCINT3) U31.AA18(VCCBRAM1) U31.AA22(VCCINT4) U31.AB11(VCCINT5) U31.AB15(VCCINT6) U31.AB17(VCCBRAM2) U31.AB19(VCCINT7) U31.AB23(VCCINT8) U31.M21(VCCINT9) U31.M23(VCCINT10) U31.N10(VCCINT11) U31.N12(VCCINT12) U31.N16(VCCINT13) U31.N18(VCCBRAM3) U31.N22(VCCINT14) U31.P11(VCCINT15) U31.P13(VCCINT16) U31.P15(VCCINT17) U31.P17(VCCINT18) U31.P19(VCCINT19) U31.P21(VCCINT20) U31.R10(VCCINT21) U31.R12(VCCINT22) U31.R16(VCCINT23) U31.R18(VCCBRAM4) U31.R22(VCCINT24) U31.T11(VCCINT25) U31.T15(VCCINT26) U31.T19(VCCINT27) U31.T23(VCCINT28) U31.U10(VCCINT29) U31.U12(VCCINT30) U31.U18(VCCBRAM5) U31.U22(VCCINT31) U31.V11(VCCINT32) U31.V15(VCCINT33) U31.V19(VCCINT34) U31.W10(VCCINT35) U31.W12(VCCINT36) U31.W18(VCCBRAM6) U31.W22(VCCINT37) U31.Y9(VCCINT38) U31.Y11(VCCINT39) U31.Y15(VCCINT40) U31.Y17(VCCINT41) U31.Y19(VCCINT42) U31.Y23(VCCINT43)
FPGA_1V0_EN: RN6.13(N2) U27.39(EN1)
FPGA_1V0_MGT: C27.1(N1) C28.1(N1) C310.2(N2) C311.2(N2) C312.2(N2) C314.2(N2) C315.2(N2) R16.2(N2) R48.1(N1) U8.12(SENSEP) U8.13(VIN) U31.AA6(MGTAVCC_G10_1) U31.AC6(MGTAVCC_G10_2) U31.AE6(MGTAVCC_G10_3) U31.AG6(MGTAVCC_G10_4) U31.AJ6(MGTAVCC_G10_5) U31.AL6(MGTAVCC_G10_6) U31.AN6(MGTAVCC_G10_7) U31.C6(MGTAVCC_G11_1) U31.E6(MGTAVCC_G11_2) U31.G6(MGTAVCC_G11_3) U31.J6(MGTAVCC_G11_4) U31.L6(MGTAVCC_G11_5) U31.U6(MGTAVCC_G10_8) U31.W6(MGTAVCC_G10_9)
FPGA_1V0_MGT_EN: RN6.10(N2) U2.48(EN3)
FPGA_1V2_MGT: C15.1(N1) C320.2(N2) C321.2(N2) C322.2(N2) C324.2(N2) C325.2(N2) R11.2(N2) R40.1(N1) R303.1(N1) U6.12(SENSEP) U6.13(VIN) U31.AC2(MGTAVTT_G10_1) U31.AD3(MGTAVTT_G10_2) U31.AG2(MGTAVTT_G10_3) U31.AH3(MGTAVTT_G10_4) U31.AL2(MGTAVTT_G10_5) U31.AM3(MGTAVTT_G10_6) U31.AP7(MGTAVTTRCAL_115) U31.C2(MGTAVTT_G11_1) U31.D3(MGTAVTT_G11_2) U31.G2(MGTAVTT_G11_3) U31.H3(MGTAVTT_G11_4) U31.L2(MGTAVTT_G11_5) U31.M3(MGTAVTT_G11_6) U31.R2(MGTAVTT_G10_7) U31.T3(MGTAVTT_G10_8) U31.W2(MGTAVTT_G10_9) U31.Y3(MGTAVTT_G10_10)
FPGA_1V2_MGT_EN: RN6.9(N2) U1.14(EN4)
FPGA_1V8: C125.1(N1) C129.1(N1) C230.2(N2) C240.2(N2) C249.2(N2) C262.2(N2) C271.2(N2) C308.2(N2) P3.2(N2) P9.2(N2) P9.20(N20) R62.2(N2) R65.2(N2) R144.1(N1) R158.2(N2) R191.2(N2) R193.2(N2) R235.1(N1) R272.2(N2) R286.1(N1) R304.2(N2) R305.2(N2) R308.2(N2) R309.2(N2) R310.2(N2) R311.2(N2) R319.2(N2) S4.6(N6) S4.7(N7) S4.8(N8) S4.9(N9) S4.10(N10) U16.12(SENSEP) U16.13(VIN) U22.1(DIR2) U22.7(VCCA) U22.10(DIR1) U30.5(VCC) U31.AB9(VCCO_0_1) U31.AB13(VCCAUX1) U31.AB21(VCCAUX2) U31.AC26(VCCO_15_1) U31.AD23(VCCO_15_2) U31.AD33(VCCO_15_3) U31.AE30(VCCO_15_4) U31.AF27(VCCO_15_5) U31.AG24(VCCO_14_1) U31.AG34(VCCO_15_6) U31.AH31(VCCO_15_7) U31.AJ28(VCCO_14_2) U31.AL32(VCCO_14_3) U31.AM29(VCCO_14_4) U31.AN26(VCCO_14_5) U31.AP34(VCCO_14_6) U31.T13(VCCAUX3) U31.T17(VCCADC_0) U31.T21(VCCAUX4) U31.V13(VCCAUX5) U31.V21(VCCAUX6) U31.W8(VCCO_0_2) U31.Y13(VCCAUX7) U31.Y21(VCCAUX8) U40.5(VCC)
FPGA_1V8_EN: RN6.12(N2) U27.14(EN4)
FPGA_1V8_MGT: C79.2(N2) C316.2(N2) C323.2(N2) C332.2(N2) C333.2(N2) C334.2(N2) U18.1(VOUT) U18.2(SENSE/ADJ) U31.N6(MGTVCCAUX_G11) U31.R6(MGTVCCAUX_G10)
FPGA_1V8_MGT_EN: R120.1(N1) RN7.16(N2)
FPGA_2V0: C39.1(N1) C166.2(N2) C167.2(N2) C289.2(N2) C307.2(N2) R12.2(N2) R54.1(N1) U5.12(SENSEP) U5.13(VIN) U31.AA14(VCCAUX_IO_G2_2) U31.AA20(VCCAUX_IO_G0_2) U31.AC14(VCCAUX_IO_G2_1) U31.AC20(VCCAUX_IO_G0_1) U31.N14(VCCAUX_IO_G3_3) U31.N20(VCCAUX_IO_G1_3) U31.R14(VCCAUX_IO_G3_2) U31.R20(VCCAUX_IO_G1_2) U31.U14(VCCAUX_IO_G3_1) U31.U20(VCCAUX_IO_G1_1) U31.W14(VCCAUX_IO_G2_3) U31.W20(VCCAUX_IO_G0_3)
FPGA_2V0_EN: RN6.11(N2) U1.48(EN3)
FPGA_DIP_SW0: R333.2(N2) S4.5(N5) U31.AC27(IO_0_VRN_15)
FPGA_DIP_SW1: R332.2(N2) S4.4(N4) U31.AJ31(IO_L5P_T0_AD9P_15)
FPGA_DIP_SW2: R330.2(N2) S4.3(N3) U31.AJ32(IO_L5N_T0_AD9N_15)
FPGA_DIP_SW3: R329.2(N2) S4.2(N2) U31.AG33(IO_L6P_T0_15)
FPGA_DIP_SW4: R328.2(N2) S4.1(N1) U31.AH33(IO_L6N_T0_VREF_15)
FPGA_GPIO_PB1: R192.2(N2) U31.AG27(IO_L20N_T3_A19_15)
FPGA_GPIO_PB2: R190.2(N2) U31.AG26(IO_L20P_T3_A20_15)
FPGA_LED0_1P8: U31.AE32(IO_L7P_T1_AD2P_15) U37.8(A5)
FPGA_LED0_3P3: R203.2(N2) U37.16(B5)
FPGA_LED1_1P8: U31.AE33(IO_L7N_T1_AD2N_15) U37.7(A4)
FPGA_LED1_3P3: R202.2(N2) U37.17(B4)
FPGA_LED2_1P8: U31.AC30(IO_L8P_T1_AD10P_15) U37.6(A3)
FPGA_LED2_3P3: R201.2(N2) U37.18(B3)
FPGA_LED3_1P8: U31.AD30(IO_L8N_T1_AD10N_15) U37.5(A2)
FPGA_LED3_3P3: R196.2(N2) U37.19(B2)
FPGA_LED4_1P8: U31.AG30(IO_L9P_T1_DQS_AD3P_15) U37.4(A1)
FPGA_LED4_3P3: R195.2(N2) U37.20(B1)
FPGA_LED5_1P8: U31.AH30(IO_L9N_T1_DQS_AD3N_15) U37.3(A0)
FPGA_LED5_3P3: R194.2(N2) U37.21(B0)
FPGA_PCA9545_RESETB: R159.1(N1) U31.AC23(IO_25_VRP_15) U34.2(B)
FPGA_RESETB: R315.2(N2) R319.1(N1) U31.AH27(IO_L18P_T2_A24_15) U43.4(Y)
FPGA_SCL: R338.2(N2) U31.AK26(IO_L14P_T2_SRCC_14)
FPGA_SDA: R327.2(N2) U31.AK27(IO_L14N_T2_SRCC_14)
FPGA_SPI_CLK: U31.AF30(IO_L11P_T1_SRCC_15) U32.7(D4)
FPGA_SPI_CS: U31.AF33(IO_L1P_T0_AD0P_15) U32.2(D1)
FPGA_SPI_EN: R296.1(N1) RN10.13(N2) U32.1(IN1) U32.8(IN4) U32.9(IN3) U32.16(IN2)
FPGA_SPI_MISO: U31.AD34(IO_L2P_T0_AD8P_15) U32.10(D3)
FPGA_SPI_MOSI: U31.AF34(IO_L1N_T0_AD0N_15) U32.15(D2)
HEADER_GPIO00_1P8: P9.18(N18) U31.AD24(IO_L24N_T3_RS0_15)
HEADER_GPIO01_1P8: P9.16(N16) U31.AC24(IO_L24P_T3_RS1_15)
HEADER_GPIO02_1P8: P9.14(N14) U31.AD25(IO_L23N_T3_FWE_B_15)
HEADER_GPIO03_1P8: P9.12(N12) U31.AC25(IO_L23P_T3_FOE_B_15)
HEADER_GPIO04_1P8: P9.10(N10) U31.AE24(IO_L22N_T3_A16_15)
HEADER_GPIO05_1P8: P9.8(N8) U31.AE23(IO_L22P_T3_A17_15)
HEADER_GPIO06_1P8: P9.6(N6) U31.AF26(IO_L21N_T3_DQS_A18_15)
HEADER_GPIO07_1P8: P9.4(N4) U31.AE26(IO_L21P_T3_DQS_15)
INITB: R305.1(N1) RN9.10(N2) U22.8(A1) U31.T8(INIT_B_0)
JTAG_TCK: P3.6(N6) U31.M8(TCK_0)
JTAG_TDI: P3.10(N10) U31.L8(TDI_0)
JTAG_TDO: P3.8(N8) U31.N8(TDO_0)
JTAG_TMS: P3.4(N4) U31.N9(TMS_0)
MGT_ALT_CLK_N: C326.1(N1) R167.2(N2) R306.1(N1) R307.2(N2) R343.2(N2) U42.6(NCLK)
MGT_ALT_CLK_P: R166.2(N2) R343.1(N1) U42.7(CLK)
MGTREFCLK1_117_C_N: C329.2(N2) U31.P5(MGTREFCLK1N_117)
MGTREFCLK1_117_C_P: C330.2(N2) U31.P6(MGTREFCLK1P_117)
MGTREFCLK1_117_N: C329.1(N1) U42.2(NQ0)
MGTREFCLK1_117_P: C330.1(N1) U42.1(Q0)
MGTREFCLK1_118_C_N: C327.2(N2) U31.H5(MGTREFCLK1N_118)
MGTREFCLK1_118_C_P: C328.2(N2) U31.H6(MGTREFCLK1P_118)
MGTREFCLK1_118_N: C327.1(N1) U42.4(NQ1)
MGTREFCLK1_118_P: C328.1(N1) U42.3(Q1)
PCA9545_RESETB_1P8: U34.4(Y) U37.9(A6)
PCA9545_RESETB_3P3: R185.1(N1) U36.3(RESET_N) U37.15(B6)
PCA9545_SCL_MAIN_1P8: Q9.2(S) R205.1(N1) R326.1(N1) R338.1(N1)
PCA9545_SCL_MAIN_3P3: P11.2(N2) Q9.3(D) R198.1(N1) U36.18(SCL)
PCA9545_SDA_MAIN_1P8: Q8.2(S) R204.1(N1) R327.1(N1) R339.1(N1)
PCA9545_SDA_MAIN_3P3: P11.3(N3) Q8.3(D) R197.1(N1) U36.19(SDA)
PG0: R155.1(N1) R156.2(N2) RN11.16(N2)
PG7: R154.1(N1) R382.2(N2) RN11.9(N2)
PMU_#3_VCAP: C206.1(N1) U16.2(VCAP) U16.3(ADR1)
PMU_#6_VCAP: C159.1(N1) U4.2(VCAP) U4.3(ADR1)
PMU_SCL: P2.2(N2) R178.1(N1) U3.7(SCL) U4.7(SCL) U5.7(SCL) U6.7(SCL) U7.7(SCL) U8.7(SCL) U9.11(SCL) U10.6(SCL) U14.7(SCL) U15.7(SCL) U16.7(SCL) U36.13(SC2)
PMU_SDA: P2.3(N3) R172.1(N1) U3.5(SDAI) U3.6(SDAO) U4.5(SDAI) U4.6(SDAO) U5.5(SDAI) U5.6(SDAO) U6.5(SDAI) U6.6(SDAO) U7.5(SDAI) U7.6(SDAO) U8.5(SDAI) U8.6(SDAO) U9.10(SDA) U10.7(SDA) U14.5(SDAI) U14.6(SDAO) U15.5(SDAI) U15.6(SDAO) U16.5(SDAI) U16.6(SDAO) U36.12(SD2)
PROGB: R310.1(N1) RN9.14(N2) U31.U8(PROGRAM_B_0)
PWRGD_LED: R341.1(N1) RN9.9(N2) U37.10(A7)
RD_RDY: RN10.11(N2) U31.AN29(IO_L20P_T3_A08_D24_14)
RDWRB: RN9.16(N2) U31.AJ26(IO_L15P_T2_DQS_RDWR_B_14)
SCL: P5.202(N69) P6.202(N69) R182.1(N1) U12.37(SCL) U36.16(SC3) U38.6(SCL)
SDA: P5.200(N68) P6.200(N68) R179.1(N1) U12.31(SDA) U36.15(SD3) U38.5(SDA)
SMA_GPIO0_N: R162.2(N2) U31.AF31(IO_L12N_T1_MRCC_15)
SMA_GPIO0_P: R161.2(N2) U31.AE31(IO_L12P_T1_MRCC_15)
SMA_GPIO_J5: U30.6(Y1) U31.AD29(IO_L13P_T2_MRCC_15)
SMA_GPIO_J6: U30.3(A2) U31.AE29(IO_L13N_T2_MRCC_15)
SYS_CLK_N: C56.2(N2) R62.1(N1) R63.2(N2) R670.2(N2) U31.AL30(IO_L12N_T1_MRCC_14)
SYS_CLK_P: C57.2(N2) R65.1(N1) R66.1(N1) R670.1(N1) U31.AL29(IO_L12P_T1_MRCC_14)
UNNAMED_1_CAP_I16_N1: C308.1(N1) E3.2(N2) U31.T16(GNDADC_0) U31.V16(VREFN_0) U31.V17(VREFP_0)
UNNAMED_1_CAP_I46_N2: C336.2(N2) R315.1(N1) S5.3(N3) S5.4(N4)
UNNAMED_1_CMOSNC7SZ125_I41_A: R134.1(N1) R135.1(N1) U26.2(A)
UNNAMED_1_CMOSNC7SZ125_I41_Y: R136.1(N1) U26.4(Y)
UNNAMED_1_DIOLED_I22_P: DS15.A(P) R126.1(N1)
UNNAMED_1_DIOLED_I25_P: DS16.A(P) R118.1(N1)
UNNAMED_1_DIOLED_I29_N: DS17.C(N) R118.2(N2) U22.5(B1)
UNNAMED_1_DIOLED_I29_P: DS17.A(P) R119.1(N1)
UNNAMED_1_ICNC7WZ08K_I31_Y1: R134.2(N2) U25.7(Y1)
UNNAMED_1_ICXC7VX330T_I1_M10: R308.1(N1) U31.AB8(M1_0)
UNNAMED_1_ICXC7VX330T_I1_M20: R309.1(N1) U31.Y8(M2_0)
UNNAMED_1_ICXC7VX330T_I2_IOL3PT: R272.1(N1) R274.2(N2) U31.AP32(IO_L3P_T0_DQS_PUDC_B_14)
UNNAMED_1_RES_I23_N2: R126.2(N2) U22.4(B2)
UNNAMED_5_ICXC7VX330T_I9_MGTRRE: R303.2(N2) U31.AN7(MGTRREF_115)
UNNAMED_10_ADSPBF52XV3_I35_EMU: R153.1(N1) U29.T2(EMU)
UNNAMED_10_ADSPBF52XV3_I35_TDO: R152.1(N1) U29.T1(TDO)
UNNAMED_10_ADSPBF52XV3_I35_US_1: C260.1(N1) U29.H19(USB_VREF)
UNNAMED_10_ADSPBF52XV3_I35_USBV: CR2.1(N1) R128.1(N1) U29.E19(USB_VBUS)
UNNAMED_10_ADSPBF52XV3_I35_USBX: R138.2(N2) U29.A19(USB_XI)
UNNAMED_10_CAP_I42_N1: C105.1(N1) P8.G2(GND2) R139.1(N1)
UNNAMED_10_CAP_I105_N1: C226.1(N1) C227.1(N1) E1.1(N1) R128.2(N2)
UNNAMED_10_CAP_I111_N1: C233.2(N2) C238.1(N1) E1.2(N2) Q6.3(D) R131.2(N2) V1.1(N1)
UNNAMED_10_CAP_I113_N1: C236.1(N1) C237.1(N1) F3.2(N2) Q6.2(S) R131.1(N1)
UNNAMED_10_CAP_I113_N2: C233.1(N1) C237.2(N2) Q6.1(G) R247.2(N2)
UNNAMED_10_CAP_I121_N1: C235.1(N1) F3.1(N1) P8.1(N1)
UNNAMED_10_CAP_I121_N2: C235.2(N2) E2.1(N1) P8.4(N4)
UNNAMED_11_ADP1715B_I46_SS: C89.2(N2) U21.4(SS)
UNNAMED_11_ADP7105_I21_EN: R120.2(N2) R122.1(N1) U18.5(EN/UVLO)
UNNAMED_11_ADP7105_I21_SS: C86.1(N1) U18.4(SS)
UNNAMED_11_DIOLED_I23_P: DS7.A(P) R132.1(N1)
UNNAMED_12_ADSPBF52XV3_I42_PF0: RN6.1(N1) U29.F1(PF0)
UNNAMED_12_ADSPBF52XV3_I42_PF1: RN6.2(N1) U29.E1(PF1)
UNNAMED_12_ADSPBF52XV3_I42_PF2: RN6.3(N1) U29.E2(PF2)
UNNAMED_12_ADSPBF52XV3_I42_PF3: RN6.4(N1) U29.D1(PF3)
UNNAMED_12_ADSPBF52XV3_I42_PF4: RN6.5(N1) U29.D2(PF4)
UNNAMED_12_ADSPBF52XV3_I42_PF5: RN6.6(N1) U29.C1(PF5)
UNNAMED_12_ADSPBF52XV3_I42_PF6: RN6.7(N1) U29.C2(PF6)
UNNAMED_12_ADSPBF52XV3_I42_PF7: RN6.8(N1) U29.B1(PF7)
UNNAMED_12_ADSPBF52XV3_I42_PF8: RN7.1(N1) U29.B2(PF8)
UNNAMED_12_ADSPBF52XV3_I42_PF9: RN7.2(N1) U29.A2(PF9)
UNNAMED_12_ADSPBF52XV3_I42_PF10: RN7.3(N1) U29.B3(PF10)
UNNAMED_12_ADSPBF52XV3_I42_PF11: RN7.4(N1) U29.A3(PF11)
UNNAMED_12_ADSPBF52XV3_I42_PF12: RN7.5(N1) U29.B5(PF12)
UNNAMED_12_ADSPBF52XV3_I42_PF13: RN7.6(N1) U29.A5(PF13)
UNNAMED_12_ADSPBF52XV3_I42_PF14: RN7.7(N1) U29.B6(PF14)
UNNAMED_12_ADSPBF52XV3_I42_PF15: RN7.8(N1) U29.A6(PF15)
UNNAMED_12_ADSPBF52XV3_I42_PG0: RN11.1(N1) U29.R2(PG0)
UNNAMED_12_ADSPBF52XV3_I42_PG1: RN11.2(N1) U29.P1(PG1)
UNNAMED_12_ADSPBF52XV3_I42_PG2: RN11.3(N1) U29.P2(PG2)
UNNAMED_12_ADSPBF52XV3_I42_PG3: RN11.4(N1) U29.N1(PG3)
UNNAMED_12_ADSPBF52XV3_I42_PG4: RN11.5(N1) U29.N2(PG4)
UNNAMED_12_ADSPBF52XV3_I42_PG5: RN11.6(N1) U29.M1(PG5)
UNNAMED_12_ADSPBF52XV3_I42_PG6: RN11.7(N1) U29.M2(PG6)
UNNAMED_12_ADSPBF52XV3_I42_PG7: RN11.8(N1) U29.L1(PG7)
UNNAMED_12_ADSPBF52XV3_I42_PG8: RN10.1(N1) U29.L2(PG8)
UNNAMED_12_ADSPBF52XV3_I42_PG9: RN10.2(N1) U29.K1(PG9)
UNNAMED_12_ADSPBF52XV3_I42_PG10: RN10.3(N1) U29.K2(PG10)
UNNAMED_12_ADSPBF52XV3_I42_PG11: RN10.4(N1) U29.J1(PG11)
UNNAMED_12_ADSPBF52XV3_I42_PG12: RN10.5(N1) U29.J2(PG12)
UNNAMED_12_ADSPBF52XV3_I42_PG13: RN10.6(N1) U29.H1(PG13)
UNNAMED_12_ADSPBF52XV3_I42_PG14: RN10.7(N1) U29.H2(PG14)
UNNAMED_12_ADSPBF52XV3_I42_PG15: RN10.8(N1) U29.G1(PG15)
UNNAMED_12_ADSPBF52XV3_I42_PH0: RN8.2(N1) U29.A7(PH0)
UNNAMED_12_ADSPBF52XV3_I42_PH1: RN8.1(N1) U29.B7(PH1)
UNNAMED_12_ADSPBF52XV3_I42_PH2: RN8.4(N1) U29.A8(PH2)
UNNAMED_12_ADSPBF52XV3_I42_PH3: RN8.3(N1) U29.B8(PH3)
UNNAMED_12_ADSPBF52XV3_I42_PH4: RN8.6(N1) U29.A9(PH4)
UNNAMED_12_ADSPBF52XV3_I42_PH5: RN8.5(N1) U29.B9(PH5)
UNNAMED_12_ADSPBF52XV3_I42_PH6: RN8.7(N1) U29.B10(PH6)
UNNAMED_12_ADSPBF52XV3_I42_PH7: RN8.8(N1) U29.B11(PH7)
UNNAMED_12_ADSPBF52XV3_I42_PH8: RN9.1(N1) U29.A12(PH8)
UNNAMED_12_ADSPBF52XV3_I42_PH9: RN9.2(N1) U29.B12(PH9)
UNNAMED_12_ADSPBF52XV3_I42_PH10: RN9.3(N1) U29.A13(PH10)
UNNAMED_12_ADSPBF52XV3_I42_PH11: RN9.4(N1) U29.B13(PH11)
UNNAMED_12_ADSPBF52XV3_I42_PH12: RN9.5(N1) U29.B14(PH12)
UNNAMED_12_ADSPBF52XV3_I42_PH13: RN9.6(N1) U29.B15(PH13)
UNNAMED_12_ADSPBF52XV3_I42_PH14: RN9.7(N1) U29.B16(PH14)
UNNAMED_12_ADSPBF52XV3_I42_PH15: RN9.8(N1) U29.B17(PH15)
UNNAMED_12_ADSPBF52XV3_I42_PPIC: R284.2(N2) U29.G2(PPI_CLK_TMRCLK)
UNNAMED_12_ADSPBF52XV3_I42_PPIF: R285.2(N2) U29.F2(PPI_FS1_TMR0)
UNNAMED_12_ADSPBF52XV3_I42_SCL: R640.2(N2) U29.A4(SCL)
UNNAMED_12_ADSPBF52XV3_I42_SDA: R639.2(N2) U29.B4(SDA)
UNNAMED_12_DIOLED_I83_N: DS32.C(N) Q14.3(D)
UNNAMED_12_DIOLED_I83_P: DS32.A(P) R165.1(N1)
UNNAMED_14_ADM6306_I147_MRN: C100.2(N2) S2.3(N3) S2.4(N4) U24.3(MR_N)
UNNAMED_14_ADM6306_I147_RSTIN: R129.1(N1) R130.2(N2) U24.4(RST IN)
UNNAMED_14_ADSPBF52XV3_I94_A_10: RN4.8(N1) U29.Y15(ADDR11)
UNNAMED_14_ADSPBF52XV3_I94_A_11: RN3.1(N1) U29.W14(ADDR12)
UNNAMED_14_ADSPBF52XV3_I94_A_12: RN3.2(N1) U29.Y14(ADDR13)
UNNAMED_14_ADSPBF52XV3_I94_A_13: RN3.3(N1) U29.W13(ADDR14)
UNNAMED_14_ADSPBF52XV3_I94_A_14: RN3.4(N1) U29.Y13(ADDR15)
UNNAMED_14_ADSPBF52XV3_I94_A_15: RN3.5(N1) U29.W12(ADDR16)
UNNAMED_14_ADSPBF52XV3_I94_A_16: RN3.6(N1) U29.Y12(ADDR17)
UNNAMED_14_ADSPBF52XV3_I94_A_17: RN3.7(N1) U29.W11(ADDR18)
UNNAMED_14_ADSPBF52XV3_I94_A_18: RN3.8(N1) U29.Y11(ADDR19)
UNNAMED_14_ADSPBF52XV3_I94_ABE0: RN1.13(N2) U29.V19(ABE0_N_SDQM0)
UNNAMED_14_ADSPBF52XV3_I94_ABE1: RN1.12(N2) U29.V20(ABE1_N_SDQM1)
UNNAMED_14_ADSPBF52XV3_I94_AD_1: RN1.15(N2) U29.W19(ADDR2)
UNNAMED_14_ADSPBF52XV3_I94_AD_2: RN1.16(N2) U29.Y19(ADDR3)
UNNAMED_14_ADSPBF52XV3_I94_AD_3: RN4.1(N1) U29.W18(ADDR4)
UNNAMED_14_ADSPBF52XV3_I94_AD_4: RN4.2(N1) U29.Y18(ADDR5)
UNNAMED_14_ADSPBF52XV3_I94_AD_5: RN4.3(N1) U29.W17(ADDR6)
UNNAMED_14_ADSPBF52XV3_I94_AD_6: RN4.4(N1) U29.Y17(ADDR7)
UNNAMED_14_ADSPBF52XV3_I94_AD_7: RN4.5(N1) U29.W16(ADDR8)
UNNAMED_14_ADSPBF52XV3_I94_AD_8: RN4.6(N1) U29.Y16(ADDR9)
UNNAMED_14_ADSPBF52XV3_I94_AD_9: RN4.7(N1) U29.W15(ADDR10)
UNNAMED_14_ADSPBF52XV3_I94_ADDR: RN1.14(N2) U29.W20(ADDR1)
UNNAMED_14_ADSPBF52XV3_I94_AMS0: RN2.1(N1) U29.J19(AMS0_N)
UNNAMED_14_ADSPBF52XV3_I94_AMS1: RN2.2(N1) U29.K19(AMS1_N)
UNNAMED_14_ADSPBF52XV3_I94_AMS2: RN2.5(N1) U29.M19(AMS2_N)
UNNAMED_14_ADSPBF52XV3_I94_AMS3: RN2.4(N1) U29.L20(AMS3_N)
UNNAMED_14_ADSPBF52XV3_I94_AOEN: R261.1(N1) U29.N20(AOE_N)
UNNAMED_14_ADSPBF52XV3_I94_ARDY: R260.2(N2) U29.P19(ARDY)
UNNAMED_14_ADSPBF52XV3_I94_AREN: R263.1(N1) U29.M20(ARE_N)
UNNAMED_14_ADSPBF52XV3_I94_AWEN: R262.1(N1) U29.N19(AWE_N)
UNNAMED_14_ADSPBF52XV3_I94_BM_1: R275.2(N2) U29.W10(BMODE1)
UNNAMED_14_ADSPBF52XV3_I94_BM_2: R277.1(N1) U29.Y9(BMODE2)
UNNAMED_14_ADSPBF52XV3_I94_BM_3: R278.1(N1) U29.W9(BMODE3)
UNNAMED_14_ADSPBF52XV3_I94_BMOD: R276.2(N2) U29.Y10(BMODE0)
UNNAMED_14_ADSPBF52XV3_I94_CLKI: C106.1(N1) U29.A11(CLKIN) Y2.1(N1)
UNNAMED_14_ADSPBF52XV3_I94_CLKO: RN2.3(N1) U29.K20(CLKOUT)
UNNAMED_14_ADSPBF52XV3_I94_D_10: RN5.3(N1) U29.Y3(DATA10)
UNNAMED_14_ADSPBF52XV3_I94_D_11: RN5.4(N1) U29.W3(DATA11)
UNNAMED_14_ADSPBF52XV3_I94_D_12: RN5.5(N1) U29.Y2(DATA12)
UNNAMED_14_ADSPBF52XV3_I94_D_13: RN5.6(N1) U29.W2(DATA13)
UNNAMED_14_ADSPBF52XV3_I94_D_14: RN5.7(N1) U29.W1(DATA14)
UNNAMED_14_ADSPBF52XV3_I94_D_15: RN5.8(N1) U29.V1(DATA15)
UNNAMED_14_ADSPBF52XV3_I94_DA_1: RN12.2(N1) U29.W8(DATA1)
UNNAMED_14_ADSPBF52XV3_I94_DA_2: RN12.3(N1) U29.Y7(DATA2)
UNNAMED_14_ADSPBF52XV3_I94_DA_3: RN12.4(N1) U29.W7(DATA3)
UNNAMED_14_ADSPBF52XV3_I94_DA_4: RN12.5(N1) U29.Y6(DATA4)
UNNAMED_14_ADSPBF52XV3_I94_DA_5: RN12.6(N1) U29.W6(DATA5)
UNNAMED_14_ADSPBF52XV3_I94_DA_6: RN12.7(N1) U29.Y5(DATA6)
UNNAMED_14_ADSPBF52XV3_I94_DA_7: RN12.8(N1) U29.W5(DATA7)
UNNAMED_14_ADSPBF52XV3_I94_DA_8: RN5.1(N1) U29.Y4(DATA8)
UNNAMED_14_ADSPBF52XV3_I94_DA_9: RN5.2(N1) U29.W4(DATA9)
UNNAMED_14_ADSPBF52XV3_I94_DATA: RN12.1(N1) U29.Y8(DATA0)
UNNAMED_14_ADSPBF52XV3_I94_NMIN: R140.2(N2) U29.B19(NMI_N)
UNNAMED_14_ADSPBF52XV3_I94_SA10: RN1.11(N2) U29.U19(SA10)
UNNAMED_14_ADSPBF52XV3_I94_SCAS: RN1.10(N2) U29.U20(SCAS_N)
UNNAMED_14_ADSPBF52XV3_I94_SCKE: RN2.6(N1) U29.P20(SCKE)
UNNAMED_14_ADSPBF52XV3_I94_SMSN: RN2.7(N1) U29.R19(SMS_N)
UNNAMED_14_ADSPBF52XV3_I94_SRAS: RN1.9(N2) U29.T19(SRAS_N)
UNNAMED_14_ADSPBF52XV3_I94_SWEN: RN2.8(N1) U29.T20(SWE_N)
UNNAMED_14_ADSPBF52XV3_I94_VRSE: R141.2(N2) U29.F19(VRSEL_VDDEXT)
UNNAMED_14_ADSPBF52XV3_I94_XTAL: R137.1(N1) U29.A10(XTAL)
UNNAMED_14_CAP_I115_N1: C104.1(N1) R137.2(N2) Y2.2(N2)
UNNAMED_14_ICMX25U3235F_I151_WP: R299.2(N2) U41.3(WP_N/SIO2)
UNNAMED_15_ADP5054_I113_CFG12: R43.1(N1) R147.2(N2) U27.18(CFG12)
UNNAMED_15_ADP5054_I113_RT: R46.2(N2) U27.42(RT)
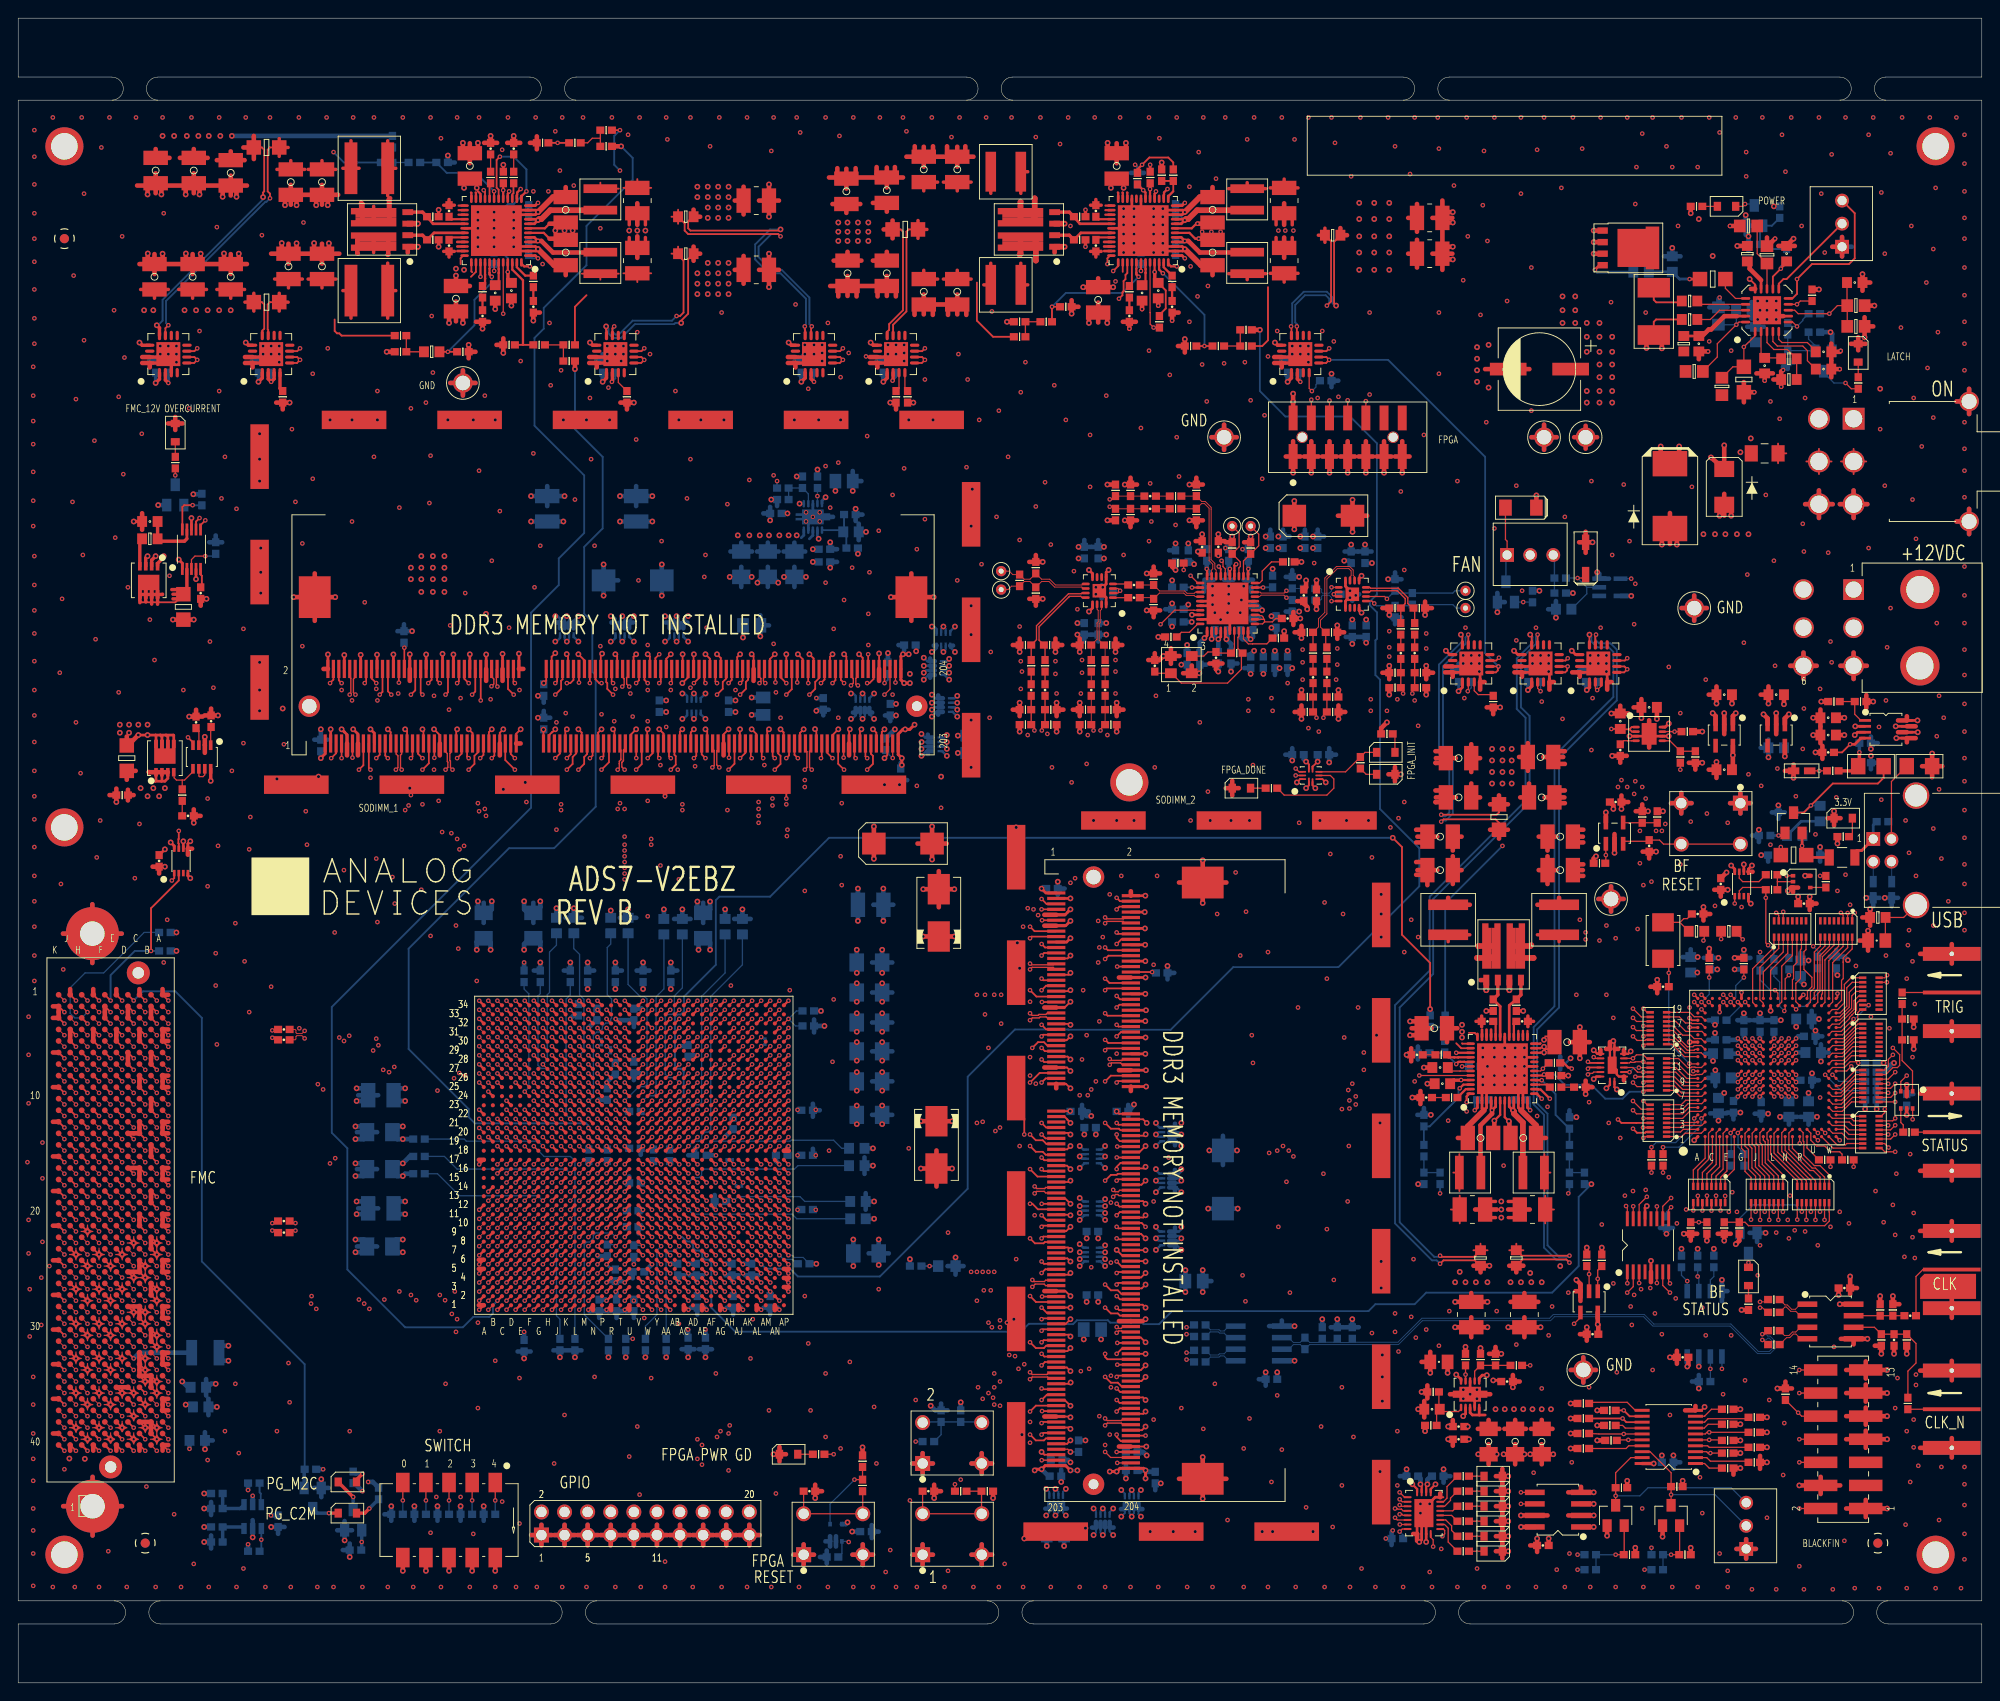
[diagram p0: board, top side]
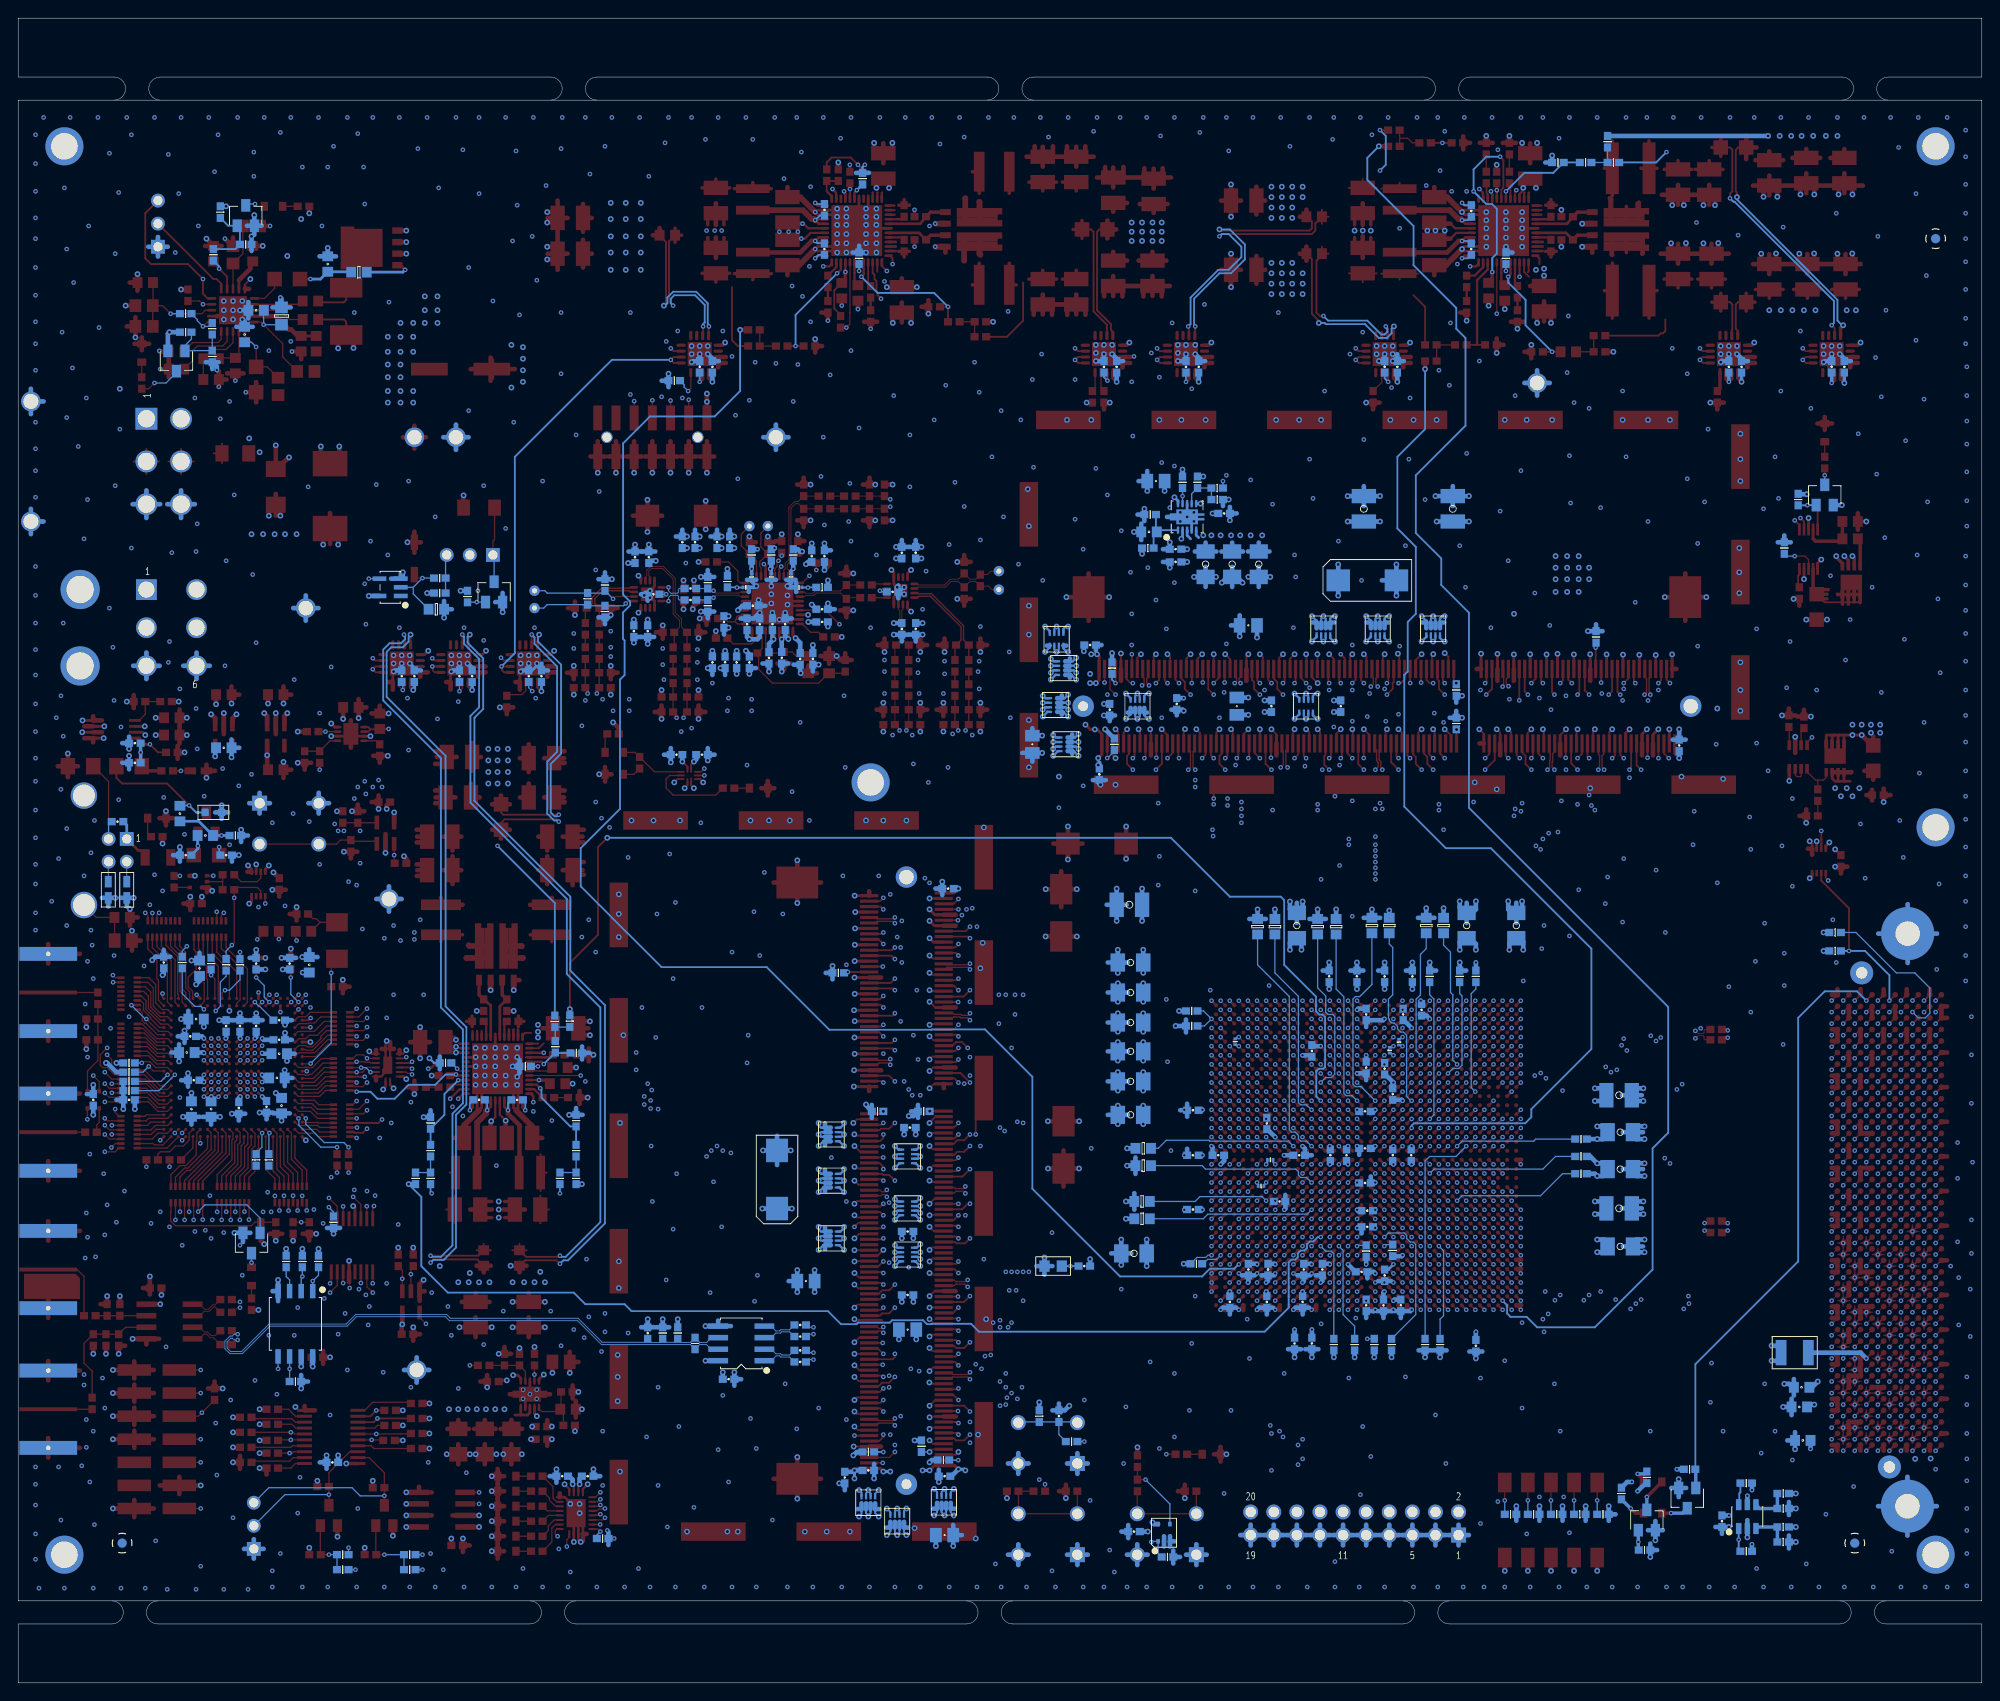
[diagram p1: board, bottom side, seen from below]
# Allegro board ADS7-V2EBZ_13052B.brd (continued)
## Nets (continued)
UNNAMED_15_ADP5054_I113_SW31: C282.2(N2) L11.1(N1) U27.4(SW3_1) U27.5(SW3_2)
UNNAMED_15_ADP5054_I113_VDD: C114.2(N2) U27.43(VDD)
UNNAMED_15_CAP_I13_N2: C110.2(N2) L9.1(N1) Q7.7(D_2) Q7.8(D_1) U27.33(SW1_1) U27.34(SW1_2) U27.35(SW1_3)
UNNAMED_15_CAP_I14_N2: C111.2(N2) L10.1(N1) Q7.5(D_2) Q7.6(D_1) U27.25(SW2_1) U27.26(SW2_2) U27.27(SW2_3)
UNNAMED_15_CAP_I42_N2: C281.2(N2) L12.1(N1) U27.8(SW4_1) U27.9(SW4_2)
UNNAMED_15_CAP_I71_N2: C113.2(N2) R146.1(N1)
UNNAMED_15_CAP_I84_N2: C117.2(N2) R150.1(N1)
UNNAMED_15_CAP_I87_N2: C116.2(N2) R149.1(N1)
UNNAMED_15_RES_I100_N2: R264.2(N2) R265.1(N1) R266.2(N2)
UNNAMED_15_RES_I105_N2: R289.2(N2) R290.1(N1) R291.2(N2)
UNNAMED_15_RES_I106_N2: R286.2(N2) R287.1(N1) R288.2(N2)
UNNAMED_16_ADCMP671_I40_INH: R336.1(N1) R337.2(N2) U44.3(INH)
UNNAMED_16_ADCMP671_I40_INL: R324.1(N1) R325.2(N2) U44.4(INL)
UNNAMED_16_ADM1170_I73_GATE: Q5.4(G) R125.1(N1) U17.5(GATE)
UNNAMED_16_ADM1170_I73_SENSE: U17.6(SENSE-) U17.7(SENSE+)
UNNAMED_16_ADM1170_I73_SS: C73.1(N1) U17.3(SS)
UNNAMED_16_ADM1170_I73_TIMER: C74.1(N1) U17.1(TIMER)
UNNAMED_16_CAP_I78_N1: C90.1(N1) R125.2(N2)
UNNAMED_16_DIOLED_I37_N: DS39.C(N) Q15.3(D)
UNNAMED_16_DIOLED_I37_P: DS39.A(P) R334.1(N1)
UNNAMED_16_DIOLED_I63_N: DS40.C(N) Q16.3(D)
UNNAMED_16_DIOLED_I63_P: DS40.A(P) R321.1(N1)
UNNAMED_17_ADM1293_I1_ADR1: R110.2(N2) U14.3(ADR1)
UNNAMED_17_ADM1293_I1_VCAP: C210.1(N1) U14.2(VCAP)
UNNAMED_17_ADM1293_I33_VCAP: C208.1(N1) U15.2(VCAP)
UNNAMED_17_ADM1293_I59_ADR1: R56.2(N2) U7.3(ADR1)
UNNAMED_17_ADM1293_I59_ADR2: R57.2(N2) U7.4(ADR2)
UNNAMED_17_ADM1293_I59_VCAP: C153.1(N1) U7.2(VCAP)
UNNAMED_17_ADM1293_I68_ADR2: R221.2(N2) U8.4(ADR2)
UNNAMED_17_ADM1293_I68_VCAP: C151.1(N1) U8.2(VCAP)
UNNAMED_17_ADM1293_I77_ADR2: R53.2(N2) U4.4(ADR2)
UNNAMED_17_ADM1293_I86_VCAP: C161.1(N1) U3.2(VCAP)
UNNAMED_17_ADM1293_I97_ADR1: R55.2(N2) U5.3(ADR1)
UNNAMED_17_ADM1293_I97_VCAP: C157.1(N1) U5.2(VCAP)
UNNAMED_17_ADM1293_I106_VCAP: C155.1(N1) U6.2(VCAP)
UNNAMED_18_CN204P2GND_I14_N69: P6.201(N69) R246.2(N2)
UNNAMED_18_CN204P2GND_I32_N67: P5.197(N67) R317.2(N2)
UNNAMED_18_CN204P2GND_I32_N69: P5.201(N69) R318.2(N2)
UNNAMED_19_AD9577_I478_LDO: C64.2(N2) U12.11(TST1B) U12.12(TST2B) U12.13(LDO)
UNNAMED_19_AD9577_I478_MARGIN: R76.2(N2) U12.20(MARGIN)
UNNAMED_19_AD9577_I478_MAXBW: R91.2(N2) U12.40(MAX_BW)
UNNAMED_19_AD9577_I478_OUT0N: C59.1(N1) R72.2(N2) U12.33(OUT0N)
UNNAMED_19_AD9577_I478_OUT0P: C63.1(N1) R78.2(N2) U12.34(OUT0P)
UNNAMED_19_AD9577_I478_OUT2N: C191.1(N1) R238.2(N2) U12.17(OUT2N)
UNNAMED_19_AD9577_I478_OUT2P: C190.1(N1) R226.2(N2) U12.18(OUT2P)
UNNAMED_19_AD9577_I478_OUT3N: R75.2(N2) U12.22(OUT3N) W2.1(N1)
UNNAMED_19_AD9577_I478_OUT3P: R74.2(N2) U12.23(OUT3P) W1.1(N1)
UNNAMED_19_AD9577_I478_REFSEL: R93.2(N2) U12.9(REFSEL)
UNNAMED_19_AD9577_I478_SSCG: R73.2(N2) U12.26(SSCG)
UNNAMED_19_AD9577_I478_VSM: C175.1(N1) R229.2(N2) U12.25(VSM)
UNNAMED_19_AD9577_I478_VSOB0A: C199.1(N1) R239.2(N2) U12.32(VSOB0A)
UNNAMED_19_AD9577_I478_VSOB1A: C176.1(N1) R230.2(N2) U12.30(VSOB1A)
UNNAMED_19_AD9577_I478_VSOB2B: C193.1(N1) R227.2(N2) U12.19(VSOB2B)
UNNAMED_19_AD9577_I478_VSOB3B: C174.1(N1) R228.2(N2) U12.21(VSOB3B)
UNNAMED_19_ADCLK944_I308_Q0: R89.1(N1) R90.2(N2) U11.15(Q0)
UNNAMED_19_ADCLK944_I308_Q0N: R87.2(N2) R88.1(N1) U11.14(Q0_N)
UNNAMED_19_ADCLK944_I308_Q1: R85.1(N1) R86.2(N2) U11.12(Q1)
UNNAMED_19_ADCLK944_I308_Q1N: R83.2(N2) R84.1(N1) U11.11(Q1_N)
UNNAMED_19_ADCLK944_I308_Q2: R70.2(N2) R77.2(N2) U11.10(Q2) W10.1(N1)
UNNAMED_19_ADCLK944_I308_Q2N: R70.1(N1) R71.2(N2) U11.9(Q2_N) W8.1(N1)
UNNAMED_19_ADCLK944_I308_VREF: C202.2(N2) U11.2(VT) U11.3(VREF)
UNNAMED_19_ADCLK944_I355_Q0: R96.1(N1) R97.2(N2) U13.15(Q0)
UNNAMED_19_ADCLK944_I355_Q0N: R94.2(N2) R95.1(N1) U13.14(Q0_N)
UNNAMED_19_ADCLK944_I355_Q1: R81.1(N1) R82.2(N2) U13.12(Q1)
UNNAMED_19_ADCLK944_I355_Q1N: R79.2(N2) R80.1(N1) U13.11(Q1_N)
UNNAMED_19_ADCLK944_I355_Q2: R225.2(N2) R236.2(N2) U13.10(Q2) W11.1(N1)
UNNAMED_19_ADCLK944_I355_Q2N: R236.1(N1) R237.2(N2) U13.9(Q2_N) W9.1(N1)
UNNAMED_19_ADCLK944_I355_VREF: C189.2(N2) U13.2(VT) U13.3(VREF)
UNNAMED_19_CAP_I319_N1: C57.1(N1) R68.2(N2)
UNNAMED_19_CAP_I321_N1: C56.1(N1) R67.2(N2)
UNNAMED_19_CAP_I331_N1: C78.1(N1) R89.2(N2)
UNNAMED_19_CAP_I334_N1: C77.1(N1) R88.2(N2)
UNNAMED_19_CAP_I342_N1: C76.1(N1) R85.2(N2)
UNNAMED_19_CAP_I347_N1: C75.1(N1) R84.2(N2)
UNNAMED_19_CAP_I362_N1: C70.1(N1) R96.2(N2)
UNNAMED_19_CAP_I366_N1: C69.1(N1) R95.2(N2)
UNNAMED_19_CAP_I375_N1: C72.1(N1) R81.2(N2)
UNNAMED_19_CAP_I380_N1: C71.1(N1) R80.2(N2)
UNNAMED_20_ADP5054_I24_CFG12: R5.2(N2) R213.1(N1) U2.18(CFG12)
UNNAMED_20_ADP5054_I24_CFG34: R7.1(N1) R8.2(N2) U2.13(CFG34)
UNNAMED_20_ADP5054_I24_RT: R216.2(N2) U2.42(RT)
UNNAMED_20_ADP5054_I24_SW11: C24.2(N2) L6.1(N1) Q2.7(D_2) Q2.8(D_1) U2.33(SW1_1) U2.34(SW1_2) U2.35(SW1_3)
UNNAMED_20_ADP5054_I24_SW21: C18.2(N2) L5.1(N1) Q2.5(D_2) Q2.6(D_1) U2.25(SW2_1) U2.26(SW2_2) U2.27(SW2_3)
UNNAMED_20_ADP5054_I24_SW31: C146.2(N2) L8.1(N1) U2.4(SW3_1) U2.5(SW3_2)
UNNAMED_20_ADP5054_I24_SW41: C144.2(N2) L7.1(N1) U2.8(SW4_1) U2.9(SW4_2)
UNNAMED_20_ADP5054_I24_VDD: C45.2(N2) U2.43(VDD)
UNNAMED_20_CAP_I5_N2: C47.2(N2) R26.1(N1)
UNNAMED_20_CAP_I9_N2: C50.2(N2) R25.1(N1)
UNNAMED_20_RES_I31_N2: R47.1(N1) R48.2(N2) R49.2(N2)
UNNAMED_20_RES_I78_N2: R22.2(N2) R23.1(N1) R41.2(N2)
UNNAMED_21_ADP5054_I24_RT: R217.2(N2) U1.42(RT)
UNNAMED_21_ADP5054_I24_SW11: C21.2(N2) L2.1(N1) Q1.7(D_2) Q1.8(D_1) U1.33(SW1_1) U1.34(SW1_2) U1.35(SW1_3)
UNNAMED_21_ADP5054_I24_SW21: C12.2(N2) L1.1(N1) Q1.5(D_2) Q1.6(D_1) U1.25(SW2_1) U1.26(SW2_2) U1.27(SW2_3)
UNNAMED_21_ADP5054_I24_SW31: C147.2(N2) L4.1(N1) U1.4(SW3_1) U1.5(SW3_2)
UNNAMED_21_ADP5054_I24_SW41: C145.2(N2) L3.1(N1) U1.8(SW4_1) U1.9(SW4_2)
UNNAMED_21_ADP5054_I24_VDD: C36.2(N2) U1.43(VDD)
UNNAMED_21_CAP_I3_N2: C3.2(N2) R4.1(N1)
UNNAMED_21_CAP_I5_N2: C38.2(N2) R21.1(N1)
UNNAMED_21_CAP_I9_N2: C49.2(N2) R20.1(N1)
UNNAMED_21_CAP_I83_N2: C2.2(N2) R2.1(N1)
UNNAMED_21_RES_I100_N1: R208.1(N1) R209.2(N2) R210.2(N2)
UNNAMED_21_RES_I103_N2: R30.2(N2) R31.2(N2) R32.1(N1)
UNNAMED_21_RES_I104_N2: R35.1(N1) R36.2(N2) R54.2(N2)
UNNAMED_21_RES_I105_N2: R38.1(N1) R39.2(N2) R40.2(N2)
UNNAMED_22_ADM1178_I115_GATE: C55.2(N2) R211.1(N1) U10.9(GATE)
UNNAMED_22_ADM1178_I115_SENSE: Q4.5(D1) Q4.6(D2) Q4.7(D3) Q4.8(D4) R273.2(N2) U10.2(SENSE)
UNNAMED_22_ADM1178_I115_TIMER: C62.2(N2) U10.5(TIMER)
UNNAMED_22_ADM1276_I200_ENABLE: C48.2(N2) R29.1(N1) R51.2(N2) R342.2(N2) U9.8(ENABLE)
UNNAMED_22_ADM1276_I200_FLB: R17.1(N1) R18.2(N2) U9.13(FLB)
UNNAMED_22_ADM1276_I200_GATE: R231.1(N1) U9.16(GATE)
UNNAMED_22_ADM1276_I200_ISET: R257.1(N1) R258.2(N2) U9.3(ISET)
UNNAMED_22_ADM1276_I200_OV: C149.2(N2) R59.1(N1) R60.2(N2) U9.1(OV)
UNNAMED_22_ADM1276_I200_SENSE: R245.1(N1) U9.18(SENSE+)
UNNAMED_22_ADM1276_I200_SENSE_1: R27.1(N1) U9.17(SENSE-)
UNNAMED_22_ADM1276_I200_SS: C54.2(N2) U9.4(SS)
UNNAMED_22_ADM1276_I200_TIMER: C52.2(N2) U9.5(TIMER)
UNNAMED_22_ADM1276_I200_UV: C150.2(N2) R58.1(N1) R538.2(N2) U9.20(UV)
UNNAMED_22_ADM1276_I200_VCAP: C53.2(N2) R257.2(N2) U9.2(VCAP)
UNNAMED_22_ADM1276_I200_VCC: C51.2(N2) R244.1(N1) U9.19(VCC)
UNNAMED_22_ADM1276_I200_VOUT: R206.1(N1) U9.14(VOUT)
UNNAMED_22_CAP_I213_N1: C148.1(N1) R231.2(N2) R518.1(N1)
UNNAMED_22_CN6P_I262_N1: P7.1(N1) P7.4(N4) S1.1(NC1) S1.4(NC2)
UNNAMED_22_DIOLED_I216_N: DS13.C(N) Q10.3(D)
UNNAMED_22_DIOLED_I216_P: DS13.A(P) R199.1(N1)
UNNAMED_22_DIOLED_I315_P: DS18.A(P) R52.1(N1)
UNNAMED_22_DIOLED_I318_P: DS14.A(P) R61.1(N1)
UNNAMED_22_FSFUSE_I289_N1: F1.1(N1) S1.2(C1) S1.5(C2)
UNNAMED_22_RES_I56_N2: Q4.4(G) R211.2(N2)
UNNAMED_22_RES_I206_N2: Q3.PAD R27.2(N2) R50.2(N2)
UNNAMED_22_RES_I212_N2: Q3.4(N4) R518.2(N2)
UNNAMED_22_RES_I217_N2: Q10.1(G) R212.1(N1) R214.2(N2) R215.1(N1)
UNNAMED_22_RES_I227_N1: Q11.1(G) R218.2(N2) R219.1(N1) R220.1(N1)
UNNAMED_22_RES_I263_N2: Q11.3(D) R52.2(N2)
UNNAMED_22_RES_I265_N2: Q12.3(D) R61.2(N2)
UNNAMED_24_CAP_I8_N2: C164.2(N2) R232.2(N2) R556.2(N2) U39.1(REFIN)
UNNAMED_24_CAP_I26_N2: C134.2(N2) R177.2(N2) R664.2(N2) U35.1(REFIN)
UNNAMED_24_ICTPS51200_I1_EN: R222.1(N1) R558.1(N1) R559.2(N2) U39.7(EN)
UNNAMED_24_ICTPS51200_I33_EN: R170.1(N1) R658.2(N2) R660.1(N1) U35.7(EN)
UNNAMED_25_74LVC1G17_I357_A: CR1.C(N) R224.2(N2) R233.1(N1) U40.2(A)
UNNAMED_25_CAP_I36_N2: C142.2(N2) R192.1(N1) R193.1(N1) S6.3(N3) S6.4(N4)
UNNAMED_25_CAP_I49_N2: C141.2(N2) R190.1(N1) R191.1(N1) S3.3(N3) S3.4(N4)
UNNAMED_25_CAP_I423_N2: C130.2(N2) R168.2(N2) R169.1(N1) R175.2(N2) U33.6(NCLK)
UNNAMED_25_CN3P_I305_N1: D3.A(P) P4.1(N1) Q13.3(D)
UNNAMED_25_CN3P_I305_N3: P4.3(N3) R224.1(N1) R234.2(N2)
UNNAMED_25_CNBNC5P_I329_CNTR: J6.1(CNTR) R151.2(N2)
UNNAMED_25_CNBNC5P_I336_CNTR: J5.1(CNTR) R142.1(N1)
UNNAMED_25_CNBNC5P_I370_CNTR: C127.2(N2) J3.1(CNTR)
UNNAMED_25_CNBNC5P_I378_CNTR: J4.1(CNTR) R175.1(N1)
UNNAMED_25_DIOLED_I452_P: DS8.A(P) R176.1(N1)
UNNAMED_25_DIOLED_I458_P: DS1.A(P) R203.1(N1)
UNNAMED_25_DIOLED_I459_P: DS2.A(P) R202.1(N1)
UNNAMED_25_DIOLED_I460_P: DS3.A(P) R201.1(N1)
UNNAMED_25_DIOLED_I461_P: DS4.A(P) R196.1(N1)
UNNAMED_25_DIOLED_I462_P: DS5.A(P) R195.1(N1)
UNNAMED_25_DIOLED_I463_P: DS6.A(P) R194.1(N1)
UNNAMED_25_ICFXL4245_I446_B7: R176.2(N2) U37.14(B7)
UNNAMED_25_ICICS85411_I427_NQ0: R162.1(N1) U33.2(NQ0)
UNNAMED_25_ICICS85411_I427_NQ1: R167.1(N1) U33.4(NQ1)
UNNAMED_25_ICICS85411_I427_Q0: R161.1(N1) U33.1(Q0)
UNNAMED_25_ICICS85411_I427_Q1: R166.1(N1) U33.3(Q1)
UNNAMED_25_NC7WZ04P6X_I339_A1: R142.2(N2) R144.2(N2) R145.1(N1) U30.1(A1)
UNNAMED_25_NC7WZ04P6X_I339_Y2: R151.1(N1) U30.4(Y2)
UNNAMED_25_RES_I367_N2: C127.1(N1) R163.2(N2) R164.1(N1) U33.7(CLK)
UNNAMED_28_ICPCA9545_I1_A0: R200.2(N2) U36.1(A0)
UNNAMED_28_ICPCA9545_I1_A1: R189.2(N2) U36.2(A1)
UNNAMED_28_ICPCA9545_I1_INT0N: R188.1(N1) U36.4(INT0_N)
UNNAMED_28_ICPCA9545_I1_INT1N: R183.1(N1) U36.7(INT1_N)
UNNAMED_28_ICPCA9545_I1_INT2N: R171.1(N1) U36.11(INT2_N)
UNNAMED_28_ICPCA9545_I1_INT3N: R181.1(N1) U36.14(INT3_N)
UNNAMED_28_ICPCA9545_I1_INTN: R180.1(N1) U36.17(INT_N)
UNNAMED_28_ICPCA9545_I1_SC1: R173.1(N1) U36.9(SC1)
UNNAMED_28_ICPCA9545_I1_SD1: R186.1(N1) U36.8(SD1)
USB_D_N: CR5.1(N1) P8.2(N2) U29.F20(USB_DM)
USB_D_P: CR4.1(N1) P8.3(N3) U29.E20(USB_DP)
VRN_16: R251.1(N1) U31.V23(IO_0_VRN_16)
VRN_17: R253.1(N1) U31.N23(IO_0_VRN_17)
VRN_18: R255.1(N1) U31.H27(IO_0_VRN_18)
VRN_19: R271.1(N1) U31.F24(IO_0_VRN_19)
VRN_34: R298.1(N1) U31.AC12(IO_0_VRN_34)
VRN_35: R292.1(N1) U31.AE18(IO_0_VRN_35)
VRN_36: R249.1(N1) U31.AC22(IO_0_VRN_36)
VRN_37: R283.1(N1) U31.H18(IO_0_VRN_37)
VRN_38: R294.1(N1) U31.L16(IO_0_VRN_38)
VRN_39: R295.1(N1) U31.H13(IO_0_VRN_39)
VRP_16: R250.2(N2) U31.AB25(IO_25_VRP_16)
VRP_17: R252.2(N2) U31.U23(IO_25_VRP_17)
VRP_18: R254.2(N2) U31.M28(IO_25_VRP_18)
VRP_19: R270.2(N2) U31.J26(IO_25_VRP_19)
VRP_34: R297.2(N2) U31.AH13(IO_25_VRP_34)
VRP_35: R293.2(N2) U31.AC15(IO_25_VRP_35)
VRP_36: R248.2(N2) U31.AC18(IO_25_VRP_36)
VRP_37: R269.2(N2) U31.L21(IO_25_VRP_37)
VRP_38: R312.2(N2) U31.G18(IO_25_VRP_38)
VRP_39: R313.2(N2) U31.K8(IO_25_VRP_39)
VTTDDR1: C183.2(N2) C184.2(N2) C185.2(N2) C220.2(N2) C221.2(N2) C222.2(N2) C223.2(N2) C224.2(N2) C225.2(N2) C231.2(N2) C234.2(N2) CN1.5(N5) CN1.6(N6) CN1.7(N7) CN1.8(N8) CN5.5(N5) CN5.6(N6) CN5.7(N7) CN5.8(N8) CN7.5(N5) CN7.6(N6) CN7.7(N7) CN7.8(N8) CN9.5(N5) CN9.6(N6) CN9.7(N7) CN9.8(N8) CN15.5(N5) CN15.6(N6) CN15.7(N7) CN15.8(N8) CN17.5(N5) CN17.6(N6) CN17.7(N7) CN17.8(N8) P6.203(N70) P6.204(N70) U39.3(VO) U39.5(VOSNS)
VTTDDR2: C138.2(N2) C139.2(N2) C140.2(N2) C283.2(N2) C302.2(N2) C319.2(N2) C331.2(N2) C344.2(N2) C345.2(N2) C346.2(N2) C347.2(N2) CN2.5(N5) CN2.6(N6) CN2.7(N7) CN2.8(N8) CN6.5(N5) CN6.6(N6) CN6.7(N7) CN6.8(N8) CN8.5(N5) CN8.6(N6) CN8.7(N7) CN8.8(N8) CN10.5(N5) CN10.6(N6) CN10.7(N7) CN10.8(N8) CN16.5(N5) CN16.6(N6) CN16.7(N7) CN16.8(N8) CN18.5(N5) CN18.6(N6) CN18.7(N7) CN18.8(N8) P5.203(N70) P5.204(N70) U35.3(VO) U35.5(VOSNS)
VTTREF1: C165.2(N2) C232.2(N2) C251.2(N2) C252.2(N2) C253.2(N2) C254.2(N2) C263.2(N2) C273.2(N2) P6.1(N1) P6.126(N64) U31.J32(IO_L19N_T3_VREF_18) U31.L25(IO_L6N_T0_VREF_18) U31.N32(IO_L19N_T3_VREF_17) U31.P27(IO_L6N_T0_VREF_17) U31.V33(IO_L6N_T0_VREF_16) U31.Y27(IO_L19N_T3_VREF_16) U39.6(REFOUT)
VTTREF2: C135.2(N2) C239.2(N2) C285.2(N2) C292.2(N2) C293.2(N2) C294.2(N2) C303.2(N2) C304.2(N2) P5.1(N1) P5.126(N64) U31.AD11(IO_L6N_T0_VREF_34) U31.AD20(IO_L19N_T3_VREF_36) U31.AG13(IO_L19N_T3_VREF_35) U31.AN12(IO_L19N_T3_VREF_34) U31.AN17(IO_L6N_T0_VREF_35) U31.AN23(IO_L6N_T0_VREF_36) U35.6(REFOUT)
WR_RDY: RN9.11(N2) U31.AM27(IO_L19N_T3_A09_D25_VREF_14)
XTAL1_25MHZ_AD9577: C67.1(N1) R92.1(N1) U12.8(XT1) Y1.1(N1)
XTAL2_25MHZ_AD9577: C68.1(N1) R92.2(N2) U12.7(XT2) Y1.3(N2)

Pads without a net: P1 B40 D29 D30 D31 D33 D34 H1 K1; P3 12 14; P5 77 122 125; P6 77 122 125; P7 2 5; P8 G1; P10 3 5; R261 2; R284 1; R285 1; RN1 4 5 6 7 8; RN2 9 10 11 12 13 16; RN3 9 10 11 12 13 14 15 16; RN4 9 10 11 12 13 14; U2 15 20; U3 4 8 9 10 14; U4 8 9 10 14; U5 4 8 9 10 14; U6 3 4 8 9 10 14; U7 8 9 10 14; U8 3 8 9 10 14; U11 6 7; U12 3; U13 6 7; U14 8 9 10 14; U15 3 8 9 10 14; U16 8 9 10 14; U19 4; U20 4; U23 3; U25 3; U27 20; U29 A15 A18 C20 D20 H20 J20; U31 A13 A14 A15 A16 A18 A23 A24 AB1 AB2 AB5 AB6 AB28 AC28 AC29 AD1 AD2 AD5 AD6 AD27 AD31 AD32 AE14 AE16 AE17 AE27 AE28 AE34 AF1 AF2 AF13 AF14 AF24 AF25 AF28 AF29 AG28 AG31 AH1 AH2 AH5 AH6 AH20 AH25 AH29 AJ9 AJ14 AJ27 AK1 AK2 AK5 AK6 AK17 AL16 AL28 AL31 AL33 AM1 AM2 AM11 AM16 AM30 AM31 AN3 AN4 AP1 AP2 AP33 B15 B16 B17 B18 B22 B23 C15 C22 C23 C24 D24 D25 E23 E24 F23 F28 G27 K29 M32 M33 P1 P2 P32 R7 R8 R23 R24 R34 T1 T2 T5 T6 T26 T33 U32 V5 V6 W31; U32 4 12; U40 1

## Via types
v1: diameter 0.508, hole 0.254, TOP to BOTTOM, 3374 vias
v2: diameter 0.635, hole 0.305, TOP to BOTTOM, 1433 vias
v3: diameter 0.635, hole 0.33, TOP to BOTTOM, 76 vias
v4: diameter 0.508, hole 0.305, TOP to BOTTOM, 10 vias

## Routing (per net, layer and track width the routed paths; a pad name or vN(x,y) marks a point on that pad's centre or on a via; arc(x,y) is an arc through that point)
DGND: length 3008
  TOP w0.203: v2(89.53,113.16) 89.26,112.88 P6.178 ; 4.45,46.48 v1(5.08,45.85) ; v2(142.62,98.42) 142.31,98.73 U22.2 ; 14.61,68.07 v1(15.24,67.44) ; U29.Y1 v1(200.28,59.69) ; 5.71,36.32 v1(6.35,35.69) ; 13.34,70.61 v1(13.97,69.98) ; U29.A17 184.01,72.89 183.77,73.13 v1(183.75,73.13) ; 12.07,73.15 v1(12.7,72.52) ; U29.J13 v1(190.68,70.09) ; P1.H36 v1(7.62,30.61) ; P5.189 115.54,28.09 v2(115.7,27.94) ; P1.A24 v1(16.51,45.85) ; P5.65 115.31,67.7 v2(115.7,67.31) ; P1.G4 v1(8.89,71.25) ; v1(110.62,60.33) 110.62,62.1 110.24,62.48 ; P1.D28 v1(12.7,40.77) ; 5.71,70.61 v1(6.35,69.98) ; P1.C13 v1(13.97,59.82) ; P6.173 87.75,104.78 v2(87.61,104.92) ; P6.138 77.26,112.74 v2(76.84,113.16) ; U29.K11 v1(191.48,68.49) ; U22.3 143.4,99.42 v2(143.76,99.06) ; P6.37 44.55,104.67 44.45,104.78 v2(44.45,104.9) ; U29.M11 v1(193.88,68.49) ; P1.G26 v1(8.89,43.31) ; v2(115.7,68.58) 115.38,68.89 P5.61 ; 15.88,70.61 v1(16.51,69.98) ; v2(115.7,74.93) 115.06,74.3 P5.43 ; v2(185.42,30.35) 185.04,29.98 U36.10 ; v2(45.72,104.9) 46.36,104.27 P6.43 ; v2(190.37,154.43) 190.98,153.83 U9.15 ; P6.150 80.86,112.95 v2(80.64,113.16) ; P6.65 52.95,104.52 v2(53.34,104.9) ; U29.N13 v1(194.68,70.09) ; P1.C24 v1(13.97,45.85) ; P1.C12 v1(13.97,61.09) ; 9.53,69.34 v1(10.16,68.71) ; v2(123.95,29.85) 123.7,29.6 P5.184 ; P1.A1 v1(16.51,75.06) ; v2(75.56,113.16) 76.05,112.67 P6.134 ; P5.49 115.59,72.49 v2(115.7,72.39) ; P5.156 123.42,38 v2(123.95,37.47) ; P5.138 123.53,43.39 v2(123.95,43.81) ; v2(115.7,80.01) 115.38,79.7 P5.25 ; v2(123.95,46.36) 123.91,46.39 P5.128 ; U29.M12 v1(193.88,69.29) ; 14.61,74.42 v1(15.24,73.79) ; U29.K10 v1(191.48,66.89) ; U29.H10 v1(189.88,66.89) ; P6.196 v2(94.65,113.24) ; v2(79.38,113.16) 79.05,112.84 P6.144 ; P1.J1 v1(6.35,75.06) ; P1.C17 v1(13.97,54.74) ; U29.N11 v1(194.68,68.49) ; v2(123.95,31.11) 123.67,31.39 P5.178 ; 14.61,64.26 v1(15.24,63.63) ; P6.197 94.96,104.61 v2(95.25,104.9) ; 9.53,61.72 v1(10.16,61.09) ; 15.88,36.32 v1(16.51,35.69) ; 9.53,42.67 v1(10.16,42.04) ; P1.H18 v1(7.62,53.47) ; U29.H11 v1(189.88,68.49) ; P1.B34 v1(15.24,33.15) ; P6.195 94.35,104.53 v2(93.98,104.9) ; v1(200.03,75.83) 200.03,75.83 200.03,75.44 U29.Y20 ; P6.145 79.35,104.75 79.38,104.78 v2(79.38,104.9) ; U29.L9 v1(193.08,66.09) ; v2(123.95,34.92) 123.42,34.39 P5.168 ; P1.F30 v1(10.16,38.23) ; P1.F21 v1(10.16,49.66) ; P1.B18 v1(15.24,53.47) ; P6.155 82.35,104.71 v2(82.55,104.9) ; v2(55.25,104.9) 54.76,104.41 P6.71 ; P5.37 115.47,76.1 115.57,76.2 v2(115.7,76.2) ; U29.N9 v1(194.68,66.09) ; 14.61,69.34 v1(15.24,68.71) ; P1.C16 v1(13.97,56.01) ; 4.45,65.53 v1(5.08,64.9) ; v2(91.44,104.9) 91.35,104.82 P6.185 ; P1.G35 v1(8.89,31.88) ; P1.E32 v1(11.43,35.69) ; 15.88,35.05 v1(16.51,34.42) ; U29.A20 v1(184.28,75.69) ; P1.J17 v1(6.35,54.74) ; v2(52.07,104.9) 51.76,104.59 P6.61 ; 13.34,40.13 v1(13.97,39.5) ; v2(87,113.16) 87.45,112.7 P6.172 ; 13.34,28.7 v1(13.97,28.07) ; P1.B22 v1(15.24,48.39) ; v2(115.7,78.11) 115.49,77.89 P5.31 ; U29.N12 v1(194.68,69.29) ; P5.134 123.46,44.6 v2(123.95,45.08) ; U29.L11 v1(193.08,68.49) ; P1.J11 v1(6.35,62.36) ; P1.D39 v1(12.7,26.8) ; U29.H9 v1(189.88,66.09) ; 12.07,52.83 v1(12.7,52.2) ; 5.71,28.7 v1(6.35,28.07) ; U29.H12 v1(189.88,69.29) ; U29.B20 v1(185.08,75.69) ; P1.A16 v1(16.51,56.01) ; 9.53,74.42 v1(10.16,73.79) ; P5.190 123.55,27.79 v2(123.95,28.19) ; P5.161 115.36,36.49 v2(115.7,36.83) ; P6.156 82.65,112.63 v2(83.19,113.16) ; v2(40.64,104.9) 40.95,104.59 P6.25 ; U29.K9 v1(191.48,66.09) ; 14.61,42.67 v1(15.24,42.04) ; P1.J23 v1(6.35,47.12) ; 4.45,50.29 v1(5.08,49.66) ; v2(123.95,33.66) 123.49,33.2 P5.172 ; v2(115.7,71.12) 115.27,70.7 P5.55 ; P1.H39 v1(7.62,26.8) ; P1.F24 v1(10.16,45.85) ; v2(115.7,38.1) 115.5,38.3 P5.155 ; P1.A13 v1(16.51,59.82) ; P1.J26 v1(6.35,43.31) ; U29.L13 v1(193.08,70.09) ; 8.26,70.61 v1(8.89,69.98) ; P1.B35 v1(15.24,31.88) ; v2(74.3,104.9) 73.95,104.56 P6.127 ; P1.E8 v1(11.43,66.17) ; v2(83.82,104.9) 84.16,104.57 P6.161 ; 12.07,64.26 v1(12.7,63.63) ; v2(123.95,40) 123.87,39.92 122.46,39.92 P5.150 ; P1.C9 v1(13.97,64.9) ; P1.H33 v1(7.62,34.42) ; P5.71 115.21,65.89 v2(115.7,65.41) ; v2(86.36,104.9) 85.96,104.5 P6.167 ; 8.26,28.7 v1(8.89,28.07) ; v2(74.3,113.16) 74.26,113.12 P6.128 ; P1.K36 v1(5.08,30.61) ; P6.31 42.76,104.69 v2(42.55,104.9) ; 5.71,32.51 v1(6.35,31.88) ; P5.133 115.51,44.9 v2(115.7,45.08) ; P1.C20 v1(13.97,50.93) ; U29.K12 v1(191.48,69.29) ; P1.E26 v1(11.43,43.31) ; v2(80.64,104.9) 81.16,104.39 P6.151 ; P1.A20 v1(16.51,50.93) ; P1.A17 v1(16.51,54.74) ; P1.E23 v1(11.43,47.12) ; P1.C28 v1(13.97,40.77) ; 6.98,69.34 v1(7.62,68.71) ; 12.07,49.02 v1(12.7,48.39) ; 15.88,31.24 v1(16.51,30.61) ; 6.98,61.72 v1(7.62,61.09) ; v2(115.7,46.36) 115.36,46.7 P5.127 ; 12.07,69.34 v1(12.7,68.71) ; v2(92.71,104.9) 92.56,104.75 P6.189 ; P1.C1 v1(13.97,75.06) ; P1.J8 v1(6.35,66.17) ; P1.D35 v1(12.7,31.88) ; 14.61,52.83 v1(15.24,52.2) ; P5.179 115.08,31.09 v2(115.7,30.48) ; P1.A25 v1(16.51,44.58) ; v2(123.95,41.28) 123.63,41.6 P5.144 ; P6.55 49.95,104.48 v2(49.53,104.9) ; P1.A21 v1(16.51,49.66) ; P1.K39 v1(5.08,26.8) ; P1.F33 v1(10.16,34.42) ; P1.K33 v1(5.08,34.42) ; 4.45,57.91 v1(5.08,57.28) ; v2(90.81,113.16) 91.05,112.91 P6.184 ; P1.A4 v1(16.51,71.25) ; P5.151 115.19,39.49 v2(115.7,40) ; P1.F39 v1(10.16,26.8) ; P5.162 v2(123.95,36.19) ; v2(75.56,104.9) 75.75,104.71 P6.133 ; P6.162 v2(84.45,113.16) ; v2(90.17,104.9) 89.56,104.29 P6.179 ; P1.B39 v1(15.24,26.8) ; P1.G32 v1(8.89,35.69) ; 5.71,40.13 v1(6.35,39.5) ; P1.B23 v1(15.24,47.12) ; 4.45,69.34 v1(5.08,68.71) ; 8.26,40.13 v1(8.89,39.5) ; P1.A9 v1(16.51,64.9) ; U29.L10 v1(193.08,66.89) ; P6.139 77.56,104.35 v2(78.11,104.9) ; P1.E14 v1(11.43,58.55) ; 4.45,54.1 v1(5.08,53.47) ; P6.190 92.86,112.76 v2(92.46,113.16) ; P1.B38 v1(15.24,28.07) ; P1.H21 v1(7.62,49.66) ; U29.J9 v1(190.68,66.09) ; 15.88,26.16 v1(16.51,25.53) ; P1.G20 v1(8.89,50.93) ; U29.N10 v1(194.68,66.89) ; 14.61,62.99 v1(15.24,62.36) ; P1.H15 v1(7.62,57.28) ; P1.E11 v1(11.43,62.36) ; P1.E17 v1(11.43,54.74) ; P1.G8 v1(8.89,66.17) ; 10.79,28.7 v1(11.43,28.07) ; P1.C32 v1(13.97,35.69) ; 12.07,74.42 v1(12.7,73.79) ; v1(84.45,97.28) 84.45,98.17 ; 6.98,65.53 v1(7.62,64.9) ; P1.G11 v1(8.89,62.36) ; P1.E4 v1(11.43,71.25) ; P1.E35 v1(11.43,31.88) ; 12.07,68.07 v1(12.7,67.44) ; P5.145 115.55,41.3 115.57,41.28 v2(115.7,41.28) ; 15.88,29.97 v1(16.51,29.34) ; P1.K30 v1(5.08,38.23) ; U29.H13 v1(189.88,70.09) ; P1.A12 v1(16.51,61.09) ; 8.26,26.16 v1(8.89,25.53) ; P1.F36 v1(10.16,30.61) ; 4.45,73.15 v1(5.08,72.52) ; U29.J12 v1(190.68,69.29) ; 12.07,60.45 v1(12.7,59.82) ; v2(115.7,29.21) 115.61,29.3 P5.185 ; v2(48.26,104.9) 48.16,104.8 P6.49 ; P1.C4 v1(13.97,71.25) ; P1.H30 v1(7.62,38.23) ; 12.07,56.64 v1(12.7,56.01) ; P1.B15 v1(15.24,57.28) ; U29.K13 v1(191.48,70.09) ; U29.M9 v1(193.88,66.09) ; 4.45,61.72 v1(5.08,61.09) ; P1.A8 v1(16.51,66.17) ; P5.167 115.29,34.69 v2(115.7,34.29) ; v2(115.7,26.67) 115.32,26.3 P5.195 ; 6.98,73.15 v1(7.62,72.52) ; P1.C36 v1(13.97,30.61) ; 6.98,42.67 v1(7.62,42.04) ; P1.D37 v1(12.7,29.34) ; P5.196 v2(124.04,26) ; 194.07,150.35 U9.7 ; P1.C33 v1(13.97,34.42) ; U29.M13 v1(193.88,70.09) ; P1.C34 v1(13.97,33.15) ; 5.71,26.16 v1(6.35,25.53) ; P1.G14 v1(8.89,58.55) ; P1.C25 v1(13.97,44.58) ; P1.J4 v1(6.35,71.25) ; P1.J20 v1(6.35,50.93) ; v2(85.73,113.16) 86.26,112.63 P6.168 ; P1.F15 v1(10.16,57.28) ; P1.B30 v1(15.24,38.23) ; 13.34,26.16 v1(13.97,25.53) ; P5.173 115.57,32.9 v2(115.72,33.04) ; P1.J14 v1(6.35,58.55) ; P5.139 115.15,43.09 v2(115.7,42.55) ; U29.J10 v1(190.68,66.89) ; 9.53,73.15 v1(10.16,72.52) ; P1.B26 v1(15.24,43.31) ; P1.E20 v1(11.43,50.93) ; 15.88,40.13 v1(16.51,39.5) ; P1.G1 v1(8.89,75.06) ; 15.88,41.4 v1(16.51,40.77) ; 14.61,59.18 v1(15.24,58.55) ; P1.E1 v1(11.43,75.06) ; U29.L12 v1(193.08,69.29) ; 4.45,74.42 v1(5.08,73.79) ; P1.H24 v1(7.62,45.85) ; 9.53,65.53 v1(10.16,64.9) ; P1.C8 v1(13.97,66.17) ; P1.G23 v1(8.89,47.12) ; 14.61,37.59 v1(15.24,36.96) ; P1.C21 v1(13.97,49.66) ; 10.79,70.61 v1(11.43,69.98) ; 12.07,45.21 v1(12.7,44.58) ; U29.J11 v1(190.68,68.49) ; 14.61,73.15 v1(15.24,72.52) ; 10.79,40.13 v1(11.43,39.5) ; 4.45,42.67 v1(5.08,42.04) ; P1.F18 v1(10.16,53.47) ; P1.G17 v1(8.89,54.74) ; 10.79,26.16 v1(11.43,25.53) ; U29.M10 v1(193.88,66.89)
  TOP w0.254: v1(75.69,47.04) U31.AE7 ; v1(64.69,43.04) U31.R3 ; v1(70.69,71.04) U31.Y30 ; v1(74.69,44.04) U31.AD4 ; v1(71.69,45.04) U31.AA5 ; v1(74.69,48.04) U31.AD8 ; v2(175.39,70.61) 175.51,70.49 U28.8 175.51,68.19 U28.PAD ; v1(81.69,68.04) U31.AL27 ; v1(70.69,56.04) U31.Y16 ; v1(60.69,47.04) U31.L7 ; v1(53.69,48.04) U31.D8 ; v1(69.69,49.04) U31.W9 ; v1(63.69,56.04) U31.P16 ; v1(68.69,44.04) U31.V4 ; v1(76.69,73.04) U31.AF32 ; U2.16 124.95,163.81 125.09,163.96 v1(125.09,164.08) ; v1(69.69,53.04) U31.W13 ; v1(63.69,59.04) U31.P18 ; U28.PAD 175.77,67.44 175.77,66.93 176,66.7 U28.2 ; U28.PAD 175.01,68.19 U28.9 ; v1(70.69,44.04) U31.Y4 ; v2(177.29,69.47) 177.02,69.19 U28.7 ; v1(66.69,42.04) U31.U2 ; v1(62.69,55.04) U31.N15 ; v1(54.69,41.04) U31.E1 ; v1(75.69,44.04) U31.AE4 ; v1(65.69,50.04) U31.T10 ; v1(69.69,41.04) U31.W1 ; v1(68.69,59.04) U31.V18 ; v1(68.69,67.04) U31.V26 ; v1(75.69,45.04) U31.AE5 ; v1(73.69,41.04) U31.AC1 ; v1(69.69,57.04) U31.W17 ; v1(63.69,69.04) U31.P28 ; v1(71.69,57.04) U31.AA17 ; v1(73.69,48.04) U31.AC8 ; v1(52.69,72.04) U31.C31 ; v1(58.69,41.04) U31.J1 ; v1(75.69,55.04) U31.AE15 ; v1(82.69,54.04) U31.AM14 ; v1(77.69,44.04) U31.AG4 ; v1(68.69,50.04) U31.V10 ; v1(61.69,75.04) U31.M34 ; v1(54.69,55.04) U31.E15 ; v1(84.69,48.04) U31.AP8 ; v1(58.69,74.04) U31.J33 ; v1(65.69,59.04) U31.T18 ; v1(66.69,45.04) U31.U5 ; v1(74.69,69.04) U31.AD28 ; v1(63.69,49.04) U31.P9 ; v1(79.69,64.04) U31.AJ23 ; v1(60.69,57.04) U31.L17 ; v1(70.69,63.04) U31.Y22 ; v1(70.69,47.04) U31.Y7 ; v1(68.69,49.04) U31.V9 ; v1(65.69,61.04) U31.T20 ; v1(72.69,44.04) U31.AB4 ; v1(70.69,59.04) U31.Y18 ; v1(64.69,41.04) U31.R1 ; v1(72.69,54.04) U31.AB14 ; v1(79.69,47.04) U31.AJ7 ; v1(80.69,71.04) U31.AK30 ; v1(63.69,50.04) U31.P10 ; v1(77.69,45.04) U31.AG5 ; v1(62.69,57.04) U31.N17 ; v1(63.69,61.04) U31.P20 ; v1(79.69,44.04) U31.AJ4 ; v1(59.69,50.04) U31.K10 ; v1(76.69,45.04) U31.AF5 ; v1(65.69,47.04) U31.T7 ; v1(58.69,53.04) U31.J13 ; v1(63.69,63.04) U31.P22 ; v1(62.69,62.04) U31.N21 ; v1(84.69,45.04) U31.AP5 ; v1(77.69,60.04) U31.AG19 ; v1(50.69,68.04) U31.A27 ; v1(79.69,42.04) U31.AJ2 ; v1(55.69,44.04) U31.F4 ; v1(57.69,67.04) U31.H26 ; U31.P8 v1(63.69,48.04) U31.P7 ; v1(82.69,46.04) U31.AM6 ; v1(72.69,75.04) U31.AB34 ; v1(81.69,47.04) U31.AL7 ; v1(61.69,65.04) U31.M24 ; v1(62.69,60.04) U31.N19 ; v1(72.69,63.04) U31.AB22 ; v1(62.69,42.04) U31.N2 ; v1(81.69,57.04) U31.AL17 ; v1(72.69,59.04) U31.AB18 ; v1(83.69,48.04) U31.AN8 ; v1(50.69,75.04) U31.A34 ; v1(50.69,45.04) U31.A5 ; v1(52.69,45.04) U31.C5 ; v1(63.69,44.04) U31.P4 ; v1(84.69,69.04) U31.AP28 ; v1(66.69,57.04) U31.U17 ; v1(56.69,49.04) U31.G9 ; v1(65.69,63.04) U31.T22 ; v1(66.69,53.04) U31.U13 ; v1(62.69,47.04) U31.N7 ; v1(65.69,73.04) U31.T32 ; v1(62.69,51.04) U31.N11 ; v1(72.69,43.04) U31.AB3 ; v1(82.69,45.04) U31.AM5 ; v1(80.69,61.04) U31.AK20 ; v1(71.69,47.04) U31.AA7 ; v1(71.69,51.04) U31.AA11 ; v1(81.69,45.04) U31.AL5 ; v1(82.69,44.04) U31.AM4 ; v1(79.69,41.04) U31.AJ1 ; v1(58.69,42.04) U31.J2 ; v1(75.69,66.04) U31.AE25 ; v1(54.69,42.04) U31.E2 ; v1(66.69,49.04) U31.U9 ; v1(66.69,62.04) U31.U21 ; v1(64.69,45.04) U31.R5 ; v1(76.69,47.04) U31.AF7 ; v1(55.69,63.04) U31.F22 ; v1(83.69,45.04) U31.AN5 ; v1(77.69,49.04) U31.AG9 ; v1(58.69,45.04) U31.J5 ; v1(57.69,44.04) U31.H4 ; v1(77.69,70.04) U31.AG29 ; v1(55.69,47.04) U31.F7 ; v1(68.69,47.04) U31.V7 ; v1(62.69,45.04) U31.N5 ; v1(58.69,47.04) U31.J7 ; v1(69.69,56.04) U31.W16 ; v1(50.69,57.04) U31.A17 ; v1(75.69,43.04) U31.AE3 ; v1(70.69,52.04) U31.Y12 ; v1(71.69,62.04) U31.AA21 ; v1(55.69,73.04) U31.F32 ; v1(71.69,60.04) U31.AA19 ; v1(52.69,62.04) U31.C21 ; v1(56.69,47.04) U31.G7 ; v1(78.69,47.04) U31.AH7 ; v1(72.69,56.04) U31.AB16 ; v1(83.69,41.04) U31.AN1 ; v1(81.69,43.04) U31.AL3 ; U2.14 125.95,163.68 125.98,163.72 125.98,163.96 v1(126.37,164.34) ; v1(64.69,44.04) U31.R4 ; v1(54.69,47.04) U31.E7 ; v1(64.69,57.04) U31.R17 ; v1(50.69,46.04) U31.A6 ; v1(50.69,41.04) U31.A1 ; v1(68.69,52.04) U31.V12 ; v1(78.69,44.04) U31.AH4 ; v1(78.69,56.04) U31.AH16 ; v1(70.69,45.04) U31.Y5 ; v1(83.69,51.04) U31.AN11 ; v1(68.69,61.04) U31.V20 ; v1(55.69,43.04) U31.F3 ; v1(73.69,72.04) U31.AC31 ; v1(53.69,44.04) U31.D4 ; v1(76.69,44.04) U31.AF4 ; v1(81.69,41.04) U31.AL1 ; v1(60.69,41.04) U31.L1 ; v1(68.69,63.04) U31.V22 ; v1(71.69,48.04) U31.AA8 ; v1(82.69,65.04) U31.AM24 ; v1(82.69,75.04) U31.AM34 ; v1(68.69,43.04) U31.V3 ; v1(84.69,59.04) U31.AP18 ; v1(65.69,52.04) U31.T12 ; v1(66.69,47.04) U31.U7 ; v1(55.69,52.04) U31.F12 ; v1(79.69,53.04) U31.AJ13 ; v1(70.69,50.04) U31.Y10 ; v1(80.69,47.04) U31.AK7 ; v1(66.69,56.04) U31.U16 ; v1(59.69,61.04) U31.K20 ; v1(80.69,50.04) U31.AK10 ; v1(59.69,44.04) U31.K4 ; v1(69.69,60.04) U31.W19 ; v1(62.69,72.04) U31.N31 ; v1(69.69,47.04) U31.W7 ; v1(61.69,63.04) U31.M22 ; v1(66.69,43.04) U31.U3 ; v1(53.69,59.04) U31.D18 ; v1(76.69,52.04) U31.AF12 ; v1(69.69,55.04) U31.W15 ; v1(70.69,61.04) U31.Y20 ; v1(63.69,52.04) U31.P12 ; v1(71.69,41.04) U31.AA1 ; v1(65.69,44.04) U31.T4 ; v1(56.69,70.04) U31.G29 ; v1(70.69,46.04) U31.Y6 ; v1(84.69,46.04) U31.AP6 ; v1(73.69,51.04) U31.AC11 ; v1(80.69,44.04) U31.AK4 ; v1(52.69,41.04) U31.C1 ; v1(70.69,54.04) U31.Y14 ; v1(72.69,61.04) U31.AB20 ; v1(82.69,48.04) U31.AM8 ; v1(51.69,54.04) U31.B14 ; v1(53.69,47.04) U31.D7 ; v1(73.69,62.04) U31.AC21 ; v1(51.69,65.04) U31.B24 ; v1(54.69,66.04) U31.E25 ; v1(51.69,47.04) U31.B7 ; v1(73.69,53.04) U31.AC13 ; v1(83.69,62.04) U31.AN21 ; v1(62.69,41.04) U31.N1 ; v1(66.69,60.04) U31.U19 ; v1(62.69,53.04) U31.N13 ; v1(57.69,47.04) U31.H7 ; v1(71.69,68.04) U31.AA27 ; v1(69.69,45.04) U31.W5 ; v1(69.69,62.04) U31.W21 ; v1(71.69,53.04) U31.AA13 ; v2(173.23,69.6) 173.63,69.19 U28.10 ; v1(52.69,47.04) U31.C7 ; v1(61.69,44.04) U31.M4 ; v1(66.69,70.04) U31.U29 ; v1(77.69,41.04) U31.AG1 ; v1(65.69,54.04) U31.T14 ; v1(54.69,45.04) U31.E5 ; v1(66.69,44.04) U31.U4 ; v1(63.69,43.04) U31.P3 ; v1(76.69,43.04) U31.AF3 ; v1(83.69,42.04) U31.AN2 ; v1(50.69,47.04) U31.A7 ; v1(83.69,72.04) U31.AN31 ; v1(79.69,74.04) U31.AJ33 ; v1(71.69,55.04) U31.AA15 ; v1(77.69,43.04) U31.AG3 ; v1(69.69,74.04) U31.W33 ; v1(60.69,45.04) U31.L5 ; v1(63.69,54.04) U31.P14 ; v1(60.69,68.04) U31.L27 ; v1(69.69,51.04) U31.W11 ; v1(74.69,47.04) U31.AD7 ; v1(56.69,45.04) U31.G5 ; v1(75.69,42.04) U31.AE2 ; v1(50.69,42.04) U31.A2 ; v1(52.69,51.04) U31.C11 ; v1(80.69,43.04) U31.AK3 ; v1(72.69,65.04) U31.AB24 ; v1(64.69,51.04) U31.R11 ; v1(64.69,55.04) U31.R15 ; v1(76.69,63.04) U31.AF22 ; v1(64.69,49.04) U31.R9 ; v1(59.69,43.04) U31.K3 ; v1(73.69,43.04) U31.AC3 ; v1(61.69,54.04) U31.M14 ; v1(79.69,45.04) U31.AJ5 ; v1(81.69,44.04) U31.AL4 ; v1(73.69,45.04) U31.AC5 ; v1(59.69,47.04) U31.K7 ; v1(68.69,54.04) U31.V14 ; v1(72.69,52.04) U31.AB12 ; v1(72.69,50.04) U31.AB10 ; v1(66.69,51.04) U31.U11 ; v1(66.69,41.04) U31.U1 ; v1(58.69,64.04) U31.J23 ; v1(53.69,69.04) U31.D28 ; v1(77.69,47.04) U31.AG7 ; v1(73.69,44.04) U31.AC4 ; v1(72.69,47.04) U31.AB7 ; v1(69.69,64.04) U31.W23 ; v1(84.69,44.04) U31.AP4 ; v1(51.69,43.04) U31.B3 ; v1(61.69,47.04) U31.M7 ; v1(74.69,59.04) U31.AD18 ; v1(71.69,49.04) U31.AA9 ; v1(56.69,41.04) U31.G1 ; v1(79.69,43.04) U31.AJ3 ; v1(75.69,41.04) U31.AE1 ; v1(64.69,53.04) U31.R13 ; v1(84.69,43.04) U31.AP3 ; v1(57.69,56.04) U31.H16 ; v1(59.69,71.04) U31.K30 ; v1(66.69,55.04) U31.U15 ; v1(64.69,66.04) U31.R25 ; v1(82.69,47.04) U31.AM7 ; v1(78.69,67.04) U31.AH26 ; v1(64.69,60.04) U31.R19 ; v1(73.69,47.04) U31.AC7 ; v1(56.69,60.04) U31.G19 ; v1(51.69,44.04) U31.B4 ; v1(76.69,46.04) U31.AF6 ; v1(64.69,62.04) U31.R21 ; v1(71.69,42.04) U31.AA2
  TOP w0.305: 158.88,111.25 158.79,111.17 U14.16 ; 158.88,111.25 v2(158.88,112.14) ; 158.88,111.25 159.13,111.51 ; v2(38.73,104.9) 39.16,104.48 P6.19 ; U12.16 133.22,118.99 U12.PAD ; P6.44 v2(46.65,113.2) ; 125.45,161.52 125.95,162.02 U2.11 128.05,162.02 v1(128.27,161.8) 127.99,161.52 U2.10 125.45,161.52 ; 125.45,161.52 U2.PAD ; 154.31,18.42 153.81,17.92 U37.11 ; 154.31,18.42 U37.PAD 154.81,18.42 U37.13 v2(154.81,15.5) ; 154.31,18.42 U37.12 154.31,15.75 v2(154.05,15.49) ; P6.2 v2(34.06,113.14) ; 123.45,160.02 U2.19 ; 123.45,160.02 122.45,161.02 U2.21 ; 123.45,160.02 U2.PAD ; 123.45,160.02 U2.30 ; P5.32 v2(123.95,77.59) ; 163.44,67.81 U27.PAD ; 163.44,67.81 U27.19 ; 163.44,67.81 v2(163.45,67.82) 164.44,68.81 U27.21 ; 163.44,67.81 U27.30 ; U27.PAD 161.44,65.81 ; U27.PAD 164.95,65.81 ; U13.16 145.93,120.64 v2(146.43,120.14) ; v2(177.17,104.14) U18.3 179.07,104.14 U18.PAD 179.57,104.14 U18.6 v2(181.48,104.14) ; v2(36.83,104.9) 37.36,104.38 P6.13 ; 132.72,118.5 U12.36 ; 132.72,118.5 131.22,116.99 U12.39 ; 132.72,118.5 U12.PAD ; P5.66 v2(123.99,67.4) ; 133.22,118.5 U12.15 ; 133.22,118.5 U12.PAD ; 133.22,118.5 U12.6 ; P6.48 v2(47.86,113.13) ; U23.6 v2(18.16,92.58) ; 164.95,65.81 165.44,65.31 U27.11 165.44,63.21 165.23,62.99 164.95,63.27 U27.10 164.95,65.81 ; P5.2 v2(123.93,86.59) ; P6.32 v2(43.06,113.15) ; U37.22 155.8,20.42 155.19,19.81 v2(155.19,19.68) 155.19,19.3 ; U21.5 v2(206.5,103.93) ; U25.6 v2(189.73,90.04) ; P6.3 v2(34.36,104.9) ; v2(190.63,89.92) 190.23,89.52 U25.5 ; U1.30 52.33,160.02 U1.PAD 54.33,158.02 ; P6.9 36.16,104.32 35.85,104.62 35.84,104.62 v2(35.56,104.9) ; U35.4 160.14,31 v4(160.39,31.25) ; U12.35 132.72,118.99 U12.PAD ; P6.38 v2(44.85,113.13) ; P5.44 v2(124,74) ; 173.41,111.82 v2(173.74,112.14) v2(174.62,111.25) 174.71,111.17 U16.4 ; 173.41,111.82 U16.15 ; 173.41,111.82 172.76,111.17 U16.16 ; P5.72 v2(124.02,65.59) ; P5.14 v2(123.89,83) ; 161.44,65.81 U27.3 161.44,63.27 161.16,62.99 160.95,63.21 U27.2 160.95,65.31 161.44,65.81 ; U13.5 145.93,119.01 U13.PAD ; v2(115.7,85.09) 115.42,84.81 115.42,84.8 115.11,84.49 P5.9 ; U2.PAD 125.45,158.02 ; U15.15 167.06,111.82 ; 167.06,111.82 v2(167.39,112.14) v2(168.28,111.25) 168.36,111.17 U15.4 ; 167.06,111.82 166.41,111.17 U15.16 ; P6.20 v2(39.46,113.12) ; P5.19 115.28,81.49 v2(115.7,81.92) ; P5.8 v2(123.87,84.8) ; C96.1 v2(16.13,89.79) ; U10.8 v2(19.05,128.14) ; U10.4 v2(19.55,121.42) ; 54.48,161.67 54.83,162.02 U1.11 56.93,162.02 v2(57.15,161.8) 56.87,161.52 U1.10 54.33,161.52 ; v2(119.89,122.43) 119.62,122.16 U11.5 119.62,120.89 v2(119.25,120.52) U11.PAD 119.62,119.39 U11.16 ; P5.54 v2(123.95,71) ; 125.45,158.02 125.95,157.52 U2.2 128.05,157.52 v1(128.27,157.73) 127.99,158.02 U2.3 125.45,158.02 ; U14.4 160.74,111.17 v2(160.66,111.25) v2(159.77,112.14) ; P5.60 v2(123.93,69.19) ; U32.5 v2(179.52,46.43) ; 54.33,158.02 54.83,157.52 U1.2 56.93,157.52 v2(57.15,157.73) 56.87,158.02 U1.3 54.33,158.02 ; v2(190.5,85.73) 190.23,85.99 U25.4 ; v2(115.7,83.82) 115.17,83.29 P5.13 ; P5.3 v2(115.7,86.29) ; P5.26 v2(123.93,79.4) ; P6.8 v2(35.85,113.07) ; U35.8 v4(159.64,31.75) ; v2(18.92,92.58) 18.66,92.32 U23.5 ; P5.48 v2(123.93,72.79) ; P5.20 v2(123.91,81.19) ; U21.8 v2(208.83,105.88) ; U29.A1 v2(184.28,59.69) ; U21.6 v2(208.86,104.58) ; P6.72 v2(55.06,113.22) ; P6.60 v2(51.46,113.14) ; U29.A14 v2(183.78,70.49) ; U29.G19 v1(189.08,74.89) ; U23.4 18.66,88.78 v2(18.92,88.52) ; 159.44,111.82 U14.15 ; P6.54 v2(49.65,113.15) ; P6.26 v2(41.25,113.14) ; P5.38 v2(123.93,75.8) ; P6.66 v2(53.25,113.2) ; P6.14 v2(37.65,113.09) ; U21.7 v2(206.43,105.23)
  TOP w0.381: U5.16 64.68,145.2 65.33,145.85 ; U30.2 v2(207.65,65.79) ; 138.3,159 138.3,158.24 138.68,157.86 C26.2 139.7,157.86 140.08,158.24 140.08,159 ; 67.18,160.4 67.18,161.29 67.56,161.67 C14.2 68.45,161.67 68.96,161.16 68.96,160.4 ; 138.3,160.4 138.3,161.29 138.68,161.67 C20.2 139.57,161.67 140.08,161.16 140.08,160.4 ; v2(65.66,146.18) 65.33,145.85 ; 65.33,145.85 U5.15 ; U6.15 87.18,145.85 ; 87.18,145.85 v2(87.5,146.18) ; 87.18,145.85 86.53,145.2 U6.16 ; R10.2 v2(46.23,157.99) ; 163.83,51.18 164.59,51.18 165.1,51.69 C123.2 165.1,52.58 164.72,52.96 163.83,52.96 ; R14.2 v1(117.35,162.05) ; U8.16 139.99,145.2 140.64,145.85 ; U3.3 16.84,145.85 v2(16.51,146.18) 16.18,145.85 ; 16.18,145.85 15.53,145.2 U3.16 ; 16.18,145.85 U3.15 ; 96.19,145.85 U7.15 ; 96.19,145.85 v2(96.52,146.18) ; 96.19,145.85 95.54,145.2 U7.16 ; 68.96,159 68.96,158.24 68.58,157.86 C23.2 67.56,157.86 67.18,158.24 67.18,159 ; 140.64,145.85 v2(140.97,146.18) ; 140.64,145.85 U8.15 ; 162.43,52.96 161.67,52.96 161.29,52.58 C122.2 161.29,51.56 161.67,51.18 162.43,51.18 ; v2(27.81,146.18) 27.49,145.85 U4.15 ; R143.2 v2(165.48,73.91) ; R44.2 v2(161.42,73.91) ; C55.1 v2(12.7,127.76) ; R9.2 v2(46.23,162.05) ; 26.84,145.2 U4.16 ; R15.2 v1(117.35,157.99)
  TOP w0.508: P10.7 203.14,27.74 ; P10.7 203.14,25.86 ; P10.7 200.99,26.8 ; P10.7 v2(205.49,26.8) ; U38.4 v2(173.23,20.96) ; U38.4 171.83,21.57 ; U38.4 170.43,20.96 ; 141.38,134.91 P3.3 ; P3.3 142.18,136.59 ; P3.3 v2(142.18,133.13) ; P3.3 142.98,134.91 ; R7.2 v2(125.73,167.26) ; 115.96,114.17 116.71,114.17 ; 116.71,114.17 v2(116.71,113.41) ; 116.71,114.17 116.71,114.88 ; 133.49,97.62 DS15.C ; DS15.C 133.49,99.23 ; DS15.C 132.77,98.42 ; DS15.C 134.2,98.42 ; 12.71,56.64 P1.C16 13.34,56.02 ; TP2.1 133.97,137.03 ; TP2.1 132.59,135.65 ; TP2.1 131.2,137.03 ; TP2.1 132.59,138.42 ; 129.46,125.6 C60.1 v2(130.17,126.37) ; 69.1,16.26 P9.11 ; P9.11 70.23,17.39 ; P9.11 71.36,16.26 ; P9.11 70.23,15.13 ; 122.3,127.14 R66.2 ; R66.2 123.01,127.89 ; R66.2 v2(121.67,127.89) ; C129.2 v2(167.39,39.12) ; C129.2 165.61,40.21 ; C129.2 165.61,38.02 ; C129.2 v2(163.83,39.12) ; v2(157.73,156.59) 157.1,156.59 156.59,157.1 ; 15.88,71.23 15.88,70.61 16.5,70.61 ; CR2.2 195.2,101.02 ; CR2.2 v2(195.2,99.57) ; CR2.2 194.26,100.33 ; C34.2 32.89,157.23 ; C34.2 33.4,158.32 ; C34.2 33.78,157.23 ; C34.2 33.4,156.13 ; 32.89,157.23 30.23,157.23 ; 32.89,157.23 32.53,157.59 v2(32.53,158.39) ; 209.12,49.72 J3.2 ; J3.2 212.6,48.65 ; J3.2 212.6,50.78 ; 162.47,14.48 DS1.C ; DS1.C 163.19,13.68 ; DS1.C v2(163.83,14.48) ; DS1.C 163.19,15.28 ; C39.2 83.64,155.45 ; C39.2 v2(82.55,157.23) ; C39.2 v2(82.55,153.54) ; C39.2 81.46,155.45 ; C52.1 200.28,146.43 v1(200.38,146.53) ; C52.1 199.35,147.33 ; C52.1 199.35,145.53 ; R94.1 141.1,116.28 ; R94.1 v2(141.1,114.94) ; R94.1 140.35,115.57 ; C138.1 v2(160.53,25.15) ; C138.1 161.67,24.04 ; C138.1 v2(162.56,25.15) ; C138.1 161.67,26.25 ; C140.1 v2(166.24,25.15) ; C140.1 v2(168.78,25.15) ; C140.1 167.51,26.25 ; C140.1 167.51,24.04 ; 61.48,16.26 P9.5 ; P9.5 62.61,15.13 ; P9.5 63.74,16.26 ; P9.5 62.61,17.39 ; 33.4,162.61 C11.2 ; C11.2 33.4,164.8 ; C11.2 33.02,163.7 ; C11.2 33.78,163.7 ; 15.88,66.15 P1.A9 16.5,65.53 ; GP1.2 8.18,22.66 ; GP1.2 4.95,19.43 ; GP1.2 11.41,19.43 ; GP1.2 8.18,16.2 ; U31.AP5 84.73,45.54 ; v2(188.34,128.4) 188.34,129.16 187.9,129.6 D1.A ; 80.39,15.13 P9.19 ; P9.19 80.39,17.39 ; P9.19 81.52,16.26 ; P9.19 79.26,16.26 ; C94.2 172.03,93.09 ; C94.2 170.94,93.47 171.32,93.85 172.09,93.85 ; C94.2 170.94,92.84 171.32,92.46 172.09,92.46 ; 98.31,24.13 S3.1 ; S3.1 100.57,24.13 ; S3.1 99.44,23 ; S3.1 99.44,25.26 ; C133.2 182.37,36.53 ; C133.2 v2(181.61,35.81) ; C133.2 182.37,35.1 ; 201.51,147.31 DS18.C ; DS18.C 202.31,146.6 ; DS18.C 203.11,147.31 ; DS18.C 202.31,148.02 ; C112.2 v2(171.7,72.14) ; C112.2 v2(171.7,68.71) ; C112.2 170.61,70.48 ; C112.2 172.8,70.48 ; C91.2 154.94,92.84 154.56,92.46 153.71,92.46 ; C91.2 153.85,93.09 ; C91.2 154.94,93.47 154.56,93.85 153.71,93.85 ; C91.2 156.03,93.09 ; 15.88,35.7 15.88,36.32 16.5,36.32 ; 160.2,52.07 C122.2 162.56,52.07 ; C120.N v2(102.68,56.58) ; C120.N 100.97,54.6 ; C120.N v2(99.25,56.58) ; C120.N 100.97,58.56 ; 110.11,114.17 110.11,114.88 ; 110.11,114.17 109.36,114.17 ; 110.11,114.17 v2(110.11,113.41) ; 15.88,56.02 P1.A16 16.5,56.64 ; C31.2 19.18,157.18 ; C31.2 18.8,156.08 ; C31.2 19.68,156.08 ; C31.2 19.18,154.99 ; 191.59,108.71 C82.1 ; C82.1 192.44,109.61 ; C82.1 v2(192.44,107.73) ; C313.N 161.29,144.53 ; C313.N 166.15,144.53 ; C313.N 163.83,143.52 ; C313.N 163.83,145.53 ; 77.56,102.03 P6.139 ; 27.81,157.23 29.34,157.23 ; 29.34,157.23 28.98,157.59 v2(28.98,158.39) ; 29.34,157.23 C33.2 ; C15.2 83.64,163.07 ; C15.2 v2(82.55,164.85) ; C15.2 81.46,163.07 ; C15.2 v2(82.55,161.29) ; 77.19,41 U31.AG1 ; 209.12,56.33 J6.4 ; J6.4 212.6,57.4 ; J6.4 212.6,55.26 ; C113.1 v2(152.65,69.09) ; C113.1 153.16,69.8 ; C113.1 153.16,68.38 ; P10.1 v2(205.49,19.18) ; P10.1 200.99,19.18 ; P10.1 203.14,18.24 ; P10.1 203.14,20.12 ; 112.83,43.09 P5.139 ; P3.1 v2(140.18,133.13) ; P3.1 140.18,136.59 ; P3.1 140.98,134.91 ; P3.1 139.38,134.91 ; C35.2 47.88,150.88 47.37,150.37 v2(47.37,149.61) ; C35.2 48.39,150.88 48.9,150.37 v2(48.9,149.61) ; C35.2 48.13,151.97 ; C35.2 48.13,149.78 ; P7.6 197.74,111.89 ; P7.6 194.84,111.89 ; P7.6 196.29,113.34 ; P7.6 196.29,110.44 ; 187.58,128.41 D1.A ; D1.A 187.52,129.6 187.07,129.16 v2(187.07,128.4) ; D1.A 187.58,130.8 ; 86.36,12.97 S5.1 ; S5.1 86.36,15.23 ; S5.1 87.49,14.1 ; S5.1 85.23,14.1 ; 57.53,15.13 P9.1 ; P9.1 58.66,16.26 ; P9.1 57.53,17.39 ; P9.1 56.4,16.26 ; J6.2 212.6,65.9 ; J6.2 209.12,64.83 ; J6.2 212.6,63.76 ; 160.74,109.27 U14.4 161.22,110.1 ; 3.82,65.53 4.45,65.53 ; 90.06,166.62 90.06,165.84 90.42,165.48 C16.2 ; 203.14,33.48 P10.13 ; P10.13 200.99,34.42 ; P10.13 203.14,35.36 ; P10.13 v2(205.49,34.42) ; 5.71,70.61 5.71,71.23 ; R51.1 v2(203.01,148.02) ; R51.1 203.01,150.23 ; R51.1 203.96,149.22 ; R71.1 v2(112.65,123.32) ; R71.1 111.18,123.32 ; R71.1 111.89,124.07 ; R64.1 129.54,132.58 ; R64.1 v2(128.78,131.83) ; R64.1 130.25,131.83 ; 151.38,134.91 P3.13 ; P3.13 152.18,136.59 ; P3.13 v2(152.18,133.13) ; P3.13 152.98,134.91 ; v2(173.23,18.41) U38.2 170.43,18.41 ; 168.36,109.27 U15.4 168.84,110.1 ; 127.58,150.75 C47.1 v1(126.87,149.86) ; C336.1 87.63,21.79 ; C336.1 v2(87.63,20.32) ; C336.1 88.38,21.08 ; S6.2 105.94,15.23 ; S6.2 105.94,12.97 ; S6.2 104.81,14.1 ; S6.2 107.07,14.1 ; C116.1 173.09,65.53 ; C116.1 v2(172.34,64.77) ; C116.1 172.34,66.24 ; C89.1 v2(197.61,102.36) ; C89.1 198.37,103.07 ; C89.1 198.37,101.65 ; S6.1 99.44,15.23 ; S6.1 99.44,12.97 ; S6.1 98.31,14.1 ; S6.1 100.57,14.1 ; C73.2 v2(18.8,106.3) ; C73.2 20.27,106.3 ; C73.2 19.56,107.05 ; v2(150.75,117.47) R79.1 150,118.24 ; C104.2 v2(185.29,85.34) ; C104.2 185.29,83.87 ; C104.2 186.04,84.58 ; R99.2 v2(154.81,111.89) ; R99.2 154.81,110.41 ; R99.2 155.56,111.12 ; 162.47,16.13 DS2.C ; DS2.C 163.19,15.33 ; DS2.C v2(163.83,16.13) ; DS2.C 163.19,16.93 ; R124.2 10.79,98.37 ; R124.2 v2(10.79,96.9) ; R124.2 10.05,97.66 ; 209.12,80.2 J5.2 ; J5.2 212.6,81.26 ; J5.2 212.6,79.13 ; 192.28,159 R18.1 192.34,158.05 v1(193.17,158.88) ; C98.2 156.03,89.41 ; C98.2 154.94,87.76 ; C98.2 154.94,89.92 154.56,90.3 153.71,90.3 ; C98.2 154.43,88.9 153.71,88.9 ; C98.2 153.85,89.41 ; 63.61,144.72 U5.16 62.79,145.2 ; 201.8,37.24 U33.5 ; U33.5 200.41,37.85 ; U33.5 203.2,37.85 ; D2.A 181.34,126.99 180.72,126.37 v2(180.72,125.22) ; D2.A 182,126.99 182.37,126.62 v2(182.37,125.22) ; D2.A 181.61,125.28 ; D2.A 181.61,128.69 ; 3.82,74.42 4.45,74.42 4.45,73.8 ; 157.72,110.68 U14.16 156.9,111.17 ; 14.61,63.64 14.61,64.26 ; 33.02,163.7 32.77,163.45 v2(32.77,162.56) ; 33.02,163.7 30.23,163.7 ; v2(22.63,157.25) 22.63,156.44 22.99,156.08 ; P5.GND2 132.84,22.44 ; P5.GND2 127.63,22.44 ; P5.GND2 v2(130.24,24.83) ; P5.GND2 v2(130.24,20.25) ; 14.61,68.72 14.61,69.34 ; R122.2 v2(185.17,101.22) ; R122.2 184.4,100.47 ; R122.2 183.69,101.22 ; C80.1 178.47,108.22 ; C80.1 v2(178.47,106.13) ; C80.1 177.62,107.31 ; R189.1 191.52,24.97 ; R189.1 v2(192.28,24.26) ; R189.1 191.52,23.55 ; C42.2 99.57,152.73 ; C42.2 98.93,151.64 98.55,151.26 98.55,150.5 ; C42.2 100.2,151.64 ; C42.2 99.57,150.55 ; 196.98,85.01 C102.2 ; C102.2 197.73,85.73 ; C102.2 v2(196.98,86.49) ; P2.1 200.53,159.06 ; P2.1 199.47,157.99 ; P2.1 200.53,156.92 ; 93.65,145.2 U7.16 94.48,144.72 ; v2(193.29,106.68) U20.2 193.29,104.37 ; 121.03,26 P5.196 ; 102.49,167.89 100.2,167.89 ; 102.49,167.89 C5.2 ; 102.49,167.89 102.13,168.25 102.13,169.04 ; 100.2,167.89 C4.2 ; 100.2,167.89 100.58,168.28 100.58,169.04 ; v2(19.94,163.74) 19.94,164.47 19.43,164.97 C8.2 ; 23.49,164.72 24,164.21 v2(24,163.49) ; 23.49,164.72 25.15,164.72 ; 23.49,164.72 C9.2 ; 145.11,128.4 C58.N ; C58.N v2(146.71,130.15) ; C58.N v2(146.71,126.62) ; C58.N 148.31,128.4 ; C10.2 29.97,164.8 ; C10.2 29.97,162.61 ; C10.2 29.72,163.7 29.34,163.32 v2(29.34,162.56) ; C10.2 30.23,163.7 ; 84.63,145.2 U6.16 85.46,144.72 ; 203.14,30.94 P10.11 ; P10.11 v2(205.49,31.88) ; P10.11 200.99,31.88 ; P10.11 203.14,32.82 ; U1.PAD 54.48,161.67 v2(54.48,161.8) ; C132.1 v2(172.47,39.12) ; C132.1 172.47,37.64 ; C132.1 171.72,38.35 ; v2(153.03,72.77) 153.8,72.77 154.31,72.26 C109.2 ; 203.62,83.3 R139.2 ; R139.2 202.77,84.2 ; R139.2 v2(203.62,85.13) ; 124.26,112.52 C67.2 ; C67.2 124.97,113.27 ; C67.2 125.48,112.52 v2(125.91,112.96) Y1.4 ; v2(48.9,169.42) 48.9,168.66 49.28,168.28 C1.2 ; P9.13 73.9,16.26 ; P9.13 72.77,15.13 ; P9.13 72.77,17.39 ; P9.13 71.64,16.26 ; 14.61,73.8 14.61,74.42 ; TP1.1 48.9,144.39 ; TP1.1 47.51,143 ; TP1.1 48.9,141.62 ; TP1.1 50.28,143 ; R98.1 v2(150.75,111.89) ; R98.1 150.75,110.41 ; R98.1 150,111.12 ; 139.19,156.77 C26.2 139.19,159 ; DS4.C 163.19,20.23 ; DS4.C v2(163.83,19.43) ; DS4.C 162.47,19.43 ; DS4.C 163.19,18.63 ; 162.18,106.57 R110.1 ; R110.1 v2(162.94,107.31) ; R110.1 161.47,107.31 ; P7.3 203.25,111.89 ; P7.3 201.8,113.34 ; P7.3 200.35,111.89 ; P7.3 201.8,110.44 ; C27.2 156.59,161.42 ; C27.2 157.68,161.16 ; C27.2 157.1,160.66 v2(157.73,160.66) ; C27.2 156.59,157.48 ; C27.2 155.5,161.16 ; 156.59,161.42 156.59,163.07 ; 156.59,161.42 156.97,161.8 v2(157.73,161.8) ; R78.1 125.55,117.98 ; R78.1 124.84,117.23 ; R78.1 v2(124.08,117.98) ; v2(18.41,163.74) 18.41,164.47 18.92,164.97 C8.2 ; 121.03,39.79 P5.150 123.65,39.79 ; 189.74,140.88 189.74,141.99 ; 189.74,141.99 v1(190.88,141.99) ; 189.74,141.99 189.74,143.09 ; 16.5,71.88 P1.A4 15.88,71.26 ; 16.5,66.8 P1.A8 15.88,66.18 ; 188.92,14.73 P11.1 ; P11.1 189.99,13.66 ; P11.1 191.06,14.73 ; P11.1 189.99,15.8 ; 13.34,66.18 P1.C8 ; P1.B39 14.61,28.05 ; v2(30.61,162.56) 30.61,163.32 30.23,163.7 ; C84.2 156.97,102.11 156.59,102.49 155.83,102.49 ; C84.2 158.06,101.73 ; C84.2 155.88,101.73 ; C84.2 156.97,101.6 156.57,101.2 155.85,101.2 155.83,101.22 ; C85.2 168.78,102.11 169.16,102.49 170.05,102.49 ; C85.2 167.69,101.85 ; C85.2 169.88,101.85 ; C85.2 168.78,101.47 169.16,101.09 170.05,101.09 ; 94.74,165.61 94.38,165.97 94.38,166.75 ; 94.74,165.61 C17.2 ; 94.74,165.61 89.15,165.61 ; 209.33,100.84 E2.2 ; E2.2 211.54,100.84 ; E2.2 210.44,99.63 ; E2.2 v2(210.44,102.23) ; 97.66,167.89 98.93,167.89 ; 98.93,167.89 98.57,168.25 98.57,169.04 ; 98.93,167.89 C4.2 ; P9.15 75.31,17.39 ; P9.15 74.18,16.26 ; P9.15 75.31,15.13 ; P9.15 76.44,16.26 ; C1.2 50.16,168.28 50.55,168.66 v2(50.55,169.42) ; C1.2 49.66,169.37 ; C1.2 49.66,167.18 ; 127.52,147.07 R45.2 ; R45.2 v2(128.27,147.83) ; R45.2 128.27,146.35 ; 96.01,165.61 96.39,165.99 96.39,166.75 ; 96.01,165.61 97.28,165.61 ; 96.01,165.61 C17.2 ; 185.88,100.46 C87.1 ; C87.1 v2(186.73,101.31) ; C87.1 186.73,99.55 ; C117.1 154.18,65.1 ; C117.1 v2(153.29,64.39) ; C117.1 154.18,63.68 ; C79.1 v2(175.17,106.64) ; C79.1 177.05,106.64 ; C79.1 176.15,107.49 ; C100.1 v2(180.09,91.44) ; C100.1 178.61,91.44 ; C100.1 179.32,90.69 ; 162.47,21.08 DS5.C ; DS5.C 163.19,21.88 ; DS5.C 163.19,20.28 ; DS5.C v2(163.83,21.08) ; J4.4 212.6,26.92 ; J4.4 209.12,25.85 ; J4.4 212.6,24.78 ; 14.61,53.48 P1.B18 ; C46.2 v1(125.35,151.51) ; 105.03,167.89 103.76,167.89 ; 103.76,167.89 C5.2 ; 103.76,167.89 104.14,168.28 104.14,169.04 ; R112.2 v2(203.96,107.95) ; R112.2 203.2,108.66 ; R112.2 203.2,107.24 ; 163.96,145.8 163.96,143.26 ; 128.08,111.07 Y1.2 ; Y1.2 v2(129.86,111.07) ; Y1.2 129.04,111.92 ; 94.87,153.67 94.49,153.29 94.49,152.53 ; 94.87,153.67 91.82,153.67 ; 94.87,153.67 C41.2 ; P1.C9 13.34,66.15 ; 8.26,70.61 8.26,71.23 ; C50.1 v1(122.17,148.97) ; C50.1 122.89,149.73 ; C50.1 121.46,149.73 ; 166.26,15.11 C143.1 ; C143.1 v2(167,15.88) ; C143.1 167,14.4 ; 150.66,99.95 DS16.C ; DS16.C 151.37,100.75 ; DS16.C 151.37,99.15 ; DS16.C v2(152.02,99.95) ; 175.01,70.49 U28.9 174.59,69.74 ; P3.7 146.98,134.91 ; P3.7 145.38,134.91 ; P3.7 v2(146.18,133.13) ; P3.7 146.18,136.59 ; 84.63,145.85 U6.15 ; U28.8 175.93,69.74 ; 114.14,65.41 P5.71 ; v2(201.42,44.7) C126.2 ; C126.2 202.17,43.43 ; C126.2 201.42,42.72 ; 177.85,95.89 R129.2 ; R129.2 v2(179.2,95.89) ; R129.2 178.56,96.63 ; R34.2 53.34,147.9 ; R34.2 52.59,147.19 ; R34.2 v2(53.34,146.3) ; S2.2 182.86,97.9 ; S2.2 182.86,95.64 ; S2.2 183.99,96.77 ; S2.2 181.73,96.77 ; 167.82,97.41 C93.2 ; C93.2 168.91,97.66 169.42,98.17 170.05,98.17 ; C93.2 170,97.41 ; C93.2 168.91,97.16 169.29,96.77 170.05,96.77 ; TP5.1 185.66,118.24 ; TP5.1 184.28,116.85 ; TP5.1 184.28,119.62 ; TP5.1 182.89,118.24 ; 13.34,35.67 P1.C33 13.34,34.43 ; 159.77,38.02 C128.2 ; C128.2 159.77,40.21 ; C128.2 v2(157.99,39.12) ; C128.2 v2(161.54,39.12) ; 190.52,153.35 U9.15 ; 112.83,74.3 P5.43 ; C86.2 176.86,101.98 ; C86.2 176.15,101.23 ; C86.2 v2(175.26,101.98) ; 98.88,92.33 C97.N ; C97.N v2(100.48,90.58) ; C97.N 102.08,92.33 ; C97.N v2(100.48,94.21) ; 212.6,33.28 J4.2 ; J4.2 209.12,34.35 ; J4.2 212.6,35.42 ; 112.83,84.49 P5.9 ; R101.2 114.92,107.06 ; R101.2 114.17,106.35 ; R101.2 v2(114.17,107.82) ; 166.19,52.07 C123.2 163.83,52.07 ; 156.9,111.82 U14.15 ; 4.93,82.42 GP1.1 ; GP1.1 8.15,79.2 ; GP1.1 11.38,82.42 ; GP1.1 8.15,85.65 ; 95.5,152.58 C41.2 ; C41.2 96.14,153.67 96.5,153.31 96.5,152.53 ; C41.2 95.5,154.76 ; C6.2 121.41,168.28 121.79,168.66 v2(121.79,169.42) ; C6.2 120.78,169.37 ; C6.2 120.14,168.28 119.78,168.63 v2(119.78,169.42) ; C6.2 120.78,167.18 ; 206.83,41.66 206.12,41.66 v2(206.12,42.55) ; v2(133.48,126.11) R74.1 132.77,125.48 ; P9.3 60.07,17.39 ; P9.3 60.07,15.13 ; P9.3 61.2,16.26 ; P9.3 58.94,16.26 ; 91.06,164.39 C16.2 ; C16.2 91.69,165.48 92.08,165.86 92.08,166.62 ; C16.2 91.06,166.57 ; v2(159.77,112.14) 159.13,111.51 v2(158.88,112.14) ; C3.1 55.19,169.42 ; C3.1 v2(54.48,170.18) ; C3.1 53.77,169.42 ; C48.1 v2(202.78,154.98) ; C48.1 203.63,154.05 ; C48.1 202.78,153.15 ; 29.72,156.13 C33.2 ; C33.2 29.72,158.32 ; C33.2 30.23,157.23 ; R72.1 v2(124.08,122.05) ; R72.1 124.84,122.8 ; R72.1 125.55,122.05 ; v2(15.88,157.23) 15.88,156.46 15.49,156.08 ; 14.61,156.08 14.25,156.44 v2(14.25,157.25) ; 14.61,156.08 C30.2 ; 14.61,156.08 13.34,156.08 ; P1.C21 13.34,50.91 ; 100.2,151.64 102.62,151.64 ; 100.2,151.64 100.56,151.28 100.56,150.5 ; 16.47,138.55 DS14.C ; DS14.C 17.27,137.84 ; DS14.C 18.07,138.55 ; DS14.C 17.27,139.26 ; P9.7 65.15,17.39 ; P9.7 65.15,15.13 ; P9.7 64.02,16.26 ; P9.7 66.28,16.26 ; v2(194.57,87.13) 194.93,87.49 U26.3 ; DS3.C v2(163.83,17.78) ; DS3.C 163.19,18.58 ; DS3.C 163.19,16.98 ; DS3.C 162.47,17.78 ; C139.1 v2(163.32,25.15) ; C139.1 v2(165.61,25.15) ; C139.1 164.59,26.25 ; C139.1 164.59,24.04 ; C99.2 172.03,89.41 ; C99.2 170.94,89.15 171.32,88.77 172.09,88.77 ; C99.2 170.94,89.66 171.32,90.04 172.09,90.04 ; 3.82,69.34 4.45,69.34 ; CR1.A v2(173.1,125.48) ; CR1.A 171.63,125.48 ; CR1.A 172.34,126.63 ; CR1.A 172.34,124.32 ; 16.5,60.45 P1.A13 15.88,61.07 ; R63.1 122.3,132.58 ; R63.1 v2(121.67,131.83) ; R63.1 123.01,131.83 ; 194.07,150.35 192.93,150.35 v2(192.28,151) ; 15.88,35.67 15.88,35.05 16.5,35.05 ; 15.88,50.94 P1.A20 16.5,51.56 ; 122.34,65.11 P5.72 ; 32.6,116.84 P6.GND1 ; P6.GND1 32.6,122.05 ; P6.GND1 v2(34.86,119.44) ; P6.GND1 v2(30.29,119.44) ; 162.47,22.73 DS6.C ; DS6.C 163.19,23.53 ; DS6.C v2(163.83,22.73) ; DS6.C 163.19,21.93 ; DS8.C 84.41,25.15 ; DS8.C 83.7,25.95 ; DS8.C v2(83.06,25.15) ; DS8.C 83.7,24.35 ; 3.82,42.67 4.45,42.67 ; C95.2 176.28,97.61 ; C95.2 v2(176.28,96.14) ; C95.2 177.03,96.9 ; 14.61,52.83 14.61,53.45 ; 179.32,105.89 U18.PAD 179.32,102.89 ; 207.66,106.33 U21.8 206.69,105.88 ; 77.85,15.13 P9.17 ; P9.17 77.85,17.39 ; P9.17 76.72,16.26 ; P9.17 78.98,16.26 ; C28.2 157.68,157.23 ; C28.2 156.59,157.1 ; C28.2 155.5,157.23 ; C28.2 156.59,157.48 ; 14.61,43.32 P1.B26 ; 16.5,41.4 15.88,41.4 15.88,40.78 ; 13.34,45.83 P1.C25 12.71,45.21 ; C131.1 155.26,36.41 ; C131.1 v2(155.26,34.1) ; C131.1 154.3,35.31 ; 155.88,97.41 C92.2 ; C92.2 156.97,97.79 156.59,98.17 155.83,98.17 ; C92.2 158.06,97.41 ; C92.2 156.97,97.28 156.57,96.88 155.85,96.88 155.83,96.9 ; R258.1 193.84,144.29 ; R258.1 192.99,143.38 ; R258.1 v1(193.84,142.58) ; 96.52,140.09 R56.1 v2(95.89,140.84) ; 14.78,89.79 C96.1 15.49,89.04 ; 14.61,58.56 14.61,59.18 ; P5.GND1 v2(130.24,90.49) ; P5.GND1 132.84,88.05 ; P5.GND1 127.63,88.05 ; P5.GND1 v2(130.24,85.79) ; 140.64,119 C65.1 141.35,118.75 141.73,118.36 v2(141.73,118.11) ; P10.4 v2(195.83,21.72) ; P10.4 198.18,20.78 ; P10.4 200.33,21.72 ; P10.4 198.18,22.66 ; 51.23,169.42 C2.1 ; C2.1 v2(51.94,170.18) ; C2.1 52.65,169.42 ; TP3.1 169.15,137.03 ; TP3.1 167.77,138.42 ; TP3.1 166.38,137.03 ; TP3.1 167.77,135.65 ; 180.21,75.87 C106.2 ; C106.2 v2(180.21,77.34) ; C106.2 179.46,76.58 ; 16.5,50.29 P1.A21 15.88,50.91 ; 139.19,162.76 C20.2 139.19,160.4 ; 201.8,128.16 S1.3 ; S1.3 201.8,131.18 ; S1.3 203.31,129.67 ; S1.3 200.29,129.67 ; C135.1 165.09,33.15 ; C135.1 164.34,33.86 ; C135.1 v2(164.34,32.51) ; C68.2 132.41,112.14 ; C68.2 130.99,112.14 ; C68.2 131.7,111.51 v2(131.95,111.25) ; 14.61,28.08 P1.B38 13.98,28.7 ; 16.5,31.24 15.88,31.24 15.88,30.62 ; S2.1 189.36,97.9 ; S2.1 188.23,96.77 ; S2.1 189.36,95.64 ; S2.1 190.49,96.77 ; 16.5,40.13 15.88,40.13 15.88,40.75 ; 13.34,40.78 P1.C28 12.71,41.4 ; 12.71,60.45 P1.C13 13.34,61.07 ; 67.19,41 U31.U1 ; 138.93,144.72 U8.16 138.1,145.2 ; 173.75,86.23 TP6.1 ; TP6.1 175.13,87.62 ; TP6.1 175.13,84.85 ; TP6.1 176.52,86.23 ; C8.2 19.3,166.07 ; C8.2 19.3,163.88 ; C30.2 14.99,154.99 ; C30.2 14.99,157.18 ; C30.2 15.49,156.08 ; 16.5,61.72 P1.A12 15.88,61.1 ; v2(189.36,23.62) R200.1 188.59,22.91 ; v2(119.74,149.61) 119.74,150.39 119.38,150.75 C44.2 ; v2(20.52,104.07) U17.2 20.52,102.32 ; 184.41,30.45 U36.10 183.28,29.98 ; 16.5,46.48 P1.A24 15.88,45.86 ; U34.3 171.77,43.88 v2(171.32,44.32) ; U34.3 171.21,43.08 ; U34.3 171.77,42.01 ; 50.66,41.54 U31.A1 ; 14.61,37.59 14.61,38.21 ; C17.2 95.5,166.7 ; C17.2 95.5,164.52 ; C40.2 91.82,153.67 ; C40.2 90.55,153.67 ; C40.2 91.19,152.58 ; C40.2 91.19,154.76 ; 91.82,153.67 92.18,153.31 92.18,152.53 ; S5.2 92.86,15.23 ; S5.2 93.99,14.1 ; S5.2 91.73,14.1 ; S5.2 92.86,12.97 ; C81.1 186.73,109.61 ; C81.1 v2(186.73,107.73) ; C81.1 185.88,108.71 ; 186.87,49.4 R155.2 ; R155.2 188.29,49.4 ; R155.2 v2(187.58,48.64) ; 12.07,68.72 12.07,69.34 ; 62.79,145.85 U5.15 ; C36.1 v2(52.45,151.13) ; 10.79,25.54 10.79,26.16 ; P3.5 v2(144.18,133.13) ; P3.5 144.98,134.91 ; P3.5 143.38,134.91 ; P3.5 144.18,136.59 ; 3.82,38.86 P1.K30 ; C5.2 103.25,168.99 ; C5.2 103.25,166.8 ; v2(34.16,158.37) 34.16,157.61 33.78,157.23 ; P6.71 55.24,103.34 ; 35.31,157.23 33.78,157.23 ; 212.6,42.28 J3.4 212.6,40.15 ; R170.2 v2(163.07,36.19) ; R170.2 161.72,36.19 ; R170.2 162.43,36.94 ; 196.48,129.67 S1.6 ; S1.6 197.99,131.18 ; S1.6 197.99,128.16 ; S1.6 199.5,129.67 ; 15.88,30.59 15.88,29.97 16.5,29.97 ; 113.95,157.35 Q2.1 ; 46.36,102.03 P6.43 ; 13.64,145.85 U3.15 ; 16.5,75.69 P1.A1 15.88,76.31 ; S1.GND2 214.5,129.15 ; S1.GND2 213.12,127.76 ; S1.GND2 214.5,126.38 ; C37.2 v2(54.23,151.51) ; 100.71,21.08 100.71,21.79 ; 100.71,21.08 v2(100.71,20.32) ; 100.71,21.08 101.46,21.08 ; 3.82,46.48 4.45,46.48 ; v2(20.07,157.23) 20.07,156.46 19.68,156.08 ; 29.08,140.09 R53.1 ; R53.1 v2(29.84,140.84) ; R53.1 28.37,140.84 ; C83.1 198.16,107.07 ; C83.1 198.16,105.27 ; C83.1 v2(197.36,106.17) ; 68.07,162.76 C14.2 68.07,160.4 ; 75.19,41 U31.AE1 ; 156.59,157.1 156.59,155.45 ; C4.2 99.57,166.8 ; C4.2 99.57,168.99 ; C44.2 118.75,149.66 ; C44.2 118.11,150.75 117.73,150.37 v2(117.73,149.61) ; C44.2 118.75,151.84 ; R174.2 195.02,32.39 ; R174.2 194.31,33.13 ; R174.2 v2(193.42,32.39) ; 91.35,102.03 P6.185 ; 3.82,73.15 4.45,73.15 4.45,73.77 ; R77.1 v2(112.65,119.25) ; R77.1 111.89,118.5 ; R77.1 111.18,119.25 ; C29.1 195.34,158.08 ; C29.1 194.44,158.12 v2(195.2,158.88) ; C29.1 193.53,158.08 ; C19.2 131.32,164.54 ; 9.53,73.8 9.53,74.42 ; R82.1 154.69,118.95 ; R82.1 v2(154.69,117.47) ; R82.1 155.44,118.24 ; 183.9,48.65 R154.2 ; R154.2 v2(183.13,49.4) ; R154.2 184.61,49.4 ; C103.N 101.22,89.29 ; C103.N v2(99.51,87.31) ; C103.N v2(102.93,87.31) ; C103.N 101.22,85.33 ; 12.07,73.8 12.07,74.42 ; TP7.1 173.47,34.42 ; TP7.1 172.09,33.03 ; TP7.1 170.7,34.42 ; TP7.1 172.09,35.8 ; C66.1 v2(142.75,118.11) ; 83.19,41 U31.AN1 ; 22.99,164.72 22.48,164.21 v2(22.48,163.49) ; 22.99,164.72 13.08,164.72 ; 22.99,164.72 C9.2 ; U28.7 176.55,69.61 ; R107.2 145.16,107.52 ; R107.2 145.91,106.81 ; R107.2 v2(145.16,106.05) ; 207.66,103.47 U21.5 208.62,103.93 ; 14.61,73.15 14.61,73.77 ; 14.61,48.4 P1.B22 ; v2(187.58,106.68) U19.2 187.58,104.37 ; R37.2 57.02,170.13 ; R37.2 56.27,169.42 ; R37.2 57.02,168.71 ; 171.69,110.68 U16.16 170.87,111.17 ; 126.74,112.11 Y1.4 ; Y1.4 126.74,113.81 ; Y1.4 127.69,112.96 ; 15.88,45.83 P1.A25 16.5,45.21 ; 176.55,66.28 U28.2 ; 14.61,33.16 P1.B34 13.98,33.78 ; 112.83,29.3 P5.185 ; 90.55,153.67 90.17,153.29 90.17,152.53 ; 90.55,153.67 89.28,153.67 ; 13.96,33.78 P1.C34 13.34,34.4 ; P1.J1 5.71,76.31 ; 51.46,110.23 P6.60 ; S3.2 105.94,25.26 ; S3.2 105.94,23 ; S3.2 104.81,24.13 ; S3.2 107.07,24.13 ; v2(24.26,157.23) 24.26,156.46 23.88,156.08 ; 199.35,143.62 C54.1 ; C54.1 v1(200.28,144.53) ; C54.1 199.35,145.43 ; 207.65,64.53 U30.2 ; 37.36,102.03 P6.13 ; 73.19,41 U31.AC1 ; v2(157.23,26.8) C137.1 157.73,26.09 ; v2(30.61,158.37) 30.61,157.61 30.23,157.23 ; 104.25,150.5 104.25,151.28 103.89,151.64 C43.2 ; v1(71.12,97.54) 71.12,98.42 ; v2(135.51,126.11) R75.1 134.8,125.48 ; R57.1 v2(98.42,140.84) ; 157.43,31.75 v4(159.64,31.75) 161.85,31.75 ; 191.12,144.06 C53.1 ; C53.1 192.93,144.06 ; C53.1 v1(192.02,143.26) ; 13.34,28.7 13.96,28.7 ; P6.GND2 98.21,122.05 ; P6.GND2 v2(95.95,119.44) ; P6.GND2 v2(100.65,119.44) ; P6.GND2 98.21,116.84 ; 147.38,134.91 P3.9 ; P3.9 v2(148.18,133.13) ; P3.9 148.18,136.59 ; P3.9 148.98,134.91 ; 138.1,145.85 U8.15 ; 14.47,144.72 U3.16 13.64,145.2 ; 213.12,140.97 S1.GND1 ; S1.GND1 214.5,142.35 ; S1.GND1 214.5,139.59 ; 23.37,154.99 C32.2 ; C32.2 23.37,157.18 ; C32.2 23.88,156.08 ; C32.2 22.99,156.08 ; 140.21,116.38 C64.1 ; C64.1 v2(140.97,117.09) ; C64.1 140.21,117.81 ; v2(165.23,18.41) U38.7 168.15,18.41 ; 153.81,15.62 U37.11 153.39,16.37 ; C119.2 167.97,59.94 ; 206.25,36.33 C130.1 ; R86.1 v2(114.05,113.41) ; R86.1 114.05,114.88 ; R86.1 114.8,114.17 ; 115.96,107.06 116.71,107.06 ; 116.71,107.06 v2(116.71,107.82) ; 116.71,107.06 116.71,106.35 ; P1.E35 11.42,32.51 ; 66.22,140.84 R55.1 ; R55.1 66.93,140.09 ; R55.1 v2(67.69,140.84) ; v2(34.04,162.56) 34.04,163.45 33.78,163.7 ; 102.62,151.64 C43.2 ; 102.62,151.64 102.23,151.26 102.23,150.5 ; R24.2 v2(115.82,150.62) ; R24.2 115.82,152.1 ; R24.2 116.57,151.38 ; 81.19,41 U31.AL1 ; P9.9 68.82,16.26 ; P9.9 66.56,16.26 ; P9.9 67.69,15.13 ; P9.9 67.69,17.39 ; P5.2 122.34,87.08 ; R105.1 141.1,107.52 ; R105.1 140.35,106.81 ; R105.1 v2(141.1,106.05) ; 156.59,157.48 157.1,157.99 v2(157.73,157.99) ; U26.3 195.7,87.49 ; U26.3 195.14,86.98 ; 49.53,145.72 R33.2 ; R33.2 50.28,146.43 ; R33.2 v2(49.53,147.19) ; 157.73,28.91 C136.1 v2(157.23,28.19) ; 20.5,106.43 C74.2 ; C74.2 v2(21.97,106.43) ; C74.2 21.21,107.18 ; v1(185.8,146.47) C51.1 184.78,145.62 ; 8.26,25.54 8.26,26.16 ; C114.1 v2(154.56,67.69) ; C43.2 103.25,152.73 ; C43.2 103.25,150.55 ; 22.99,156.08 19.68,156.08 ; 3.82,27.43 P1.K39 ; 36.16,102.03 P6.9 ; 18.8,156.08 18.44,156.44 v2(18.44,157.25) ; 18.8,156.08 15.49,156.08 ; 63.19,41 U31.N1 ; C90.2 19.3,96.09 ; C90.2 v2(19.3,94.62) ; C90.2 20.05,95.38 ; U31.AP4 84.73,44.54 ; P3.11 150.98,134.91 ; P3.11 150.18,136.59 ; P3.11 149.38,134.91 ; P3.11 v2(150.18,133.13) ; 25.77,144.72 U4.16 24.94,145.2 ; 13.63,126.86 C55.1 13.63,128.66 ; C45.1 v1(123.57,151.13) ; 3.82,31.24 P1.K36 ; 79.19,41 U31.AJ1 ; 110.11,107.06 v2(110.11,107.82) ; 110.11,107.06 109.36,107.06 ; 110.11,107.06 110.11,106.35 ; 145.03,114.86 R97.1 ; R97.1 145.78,115.57 ; R97.1 v2(145.03,116.33) ; C101.2 v2(187.96,87.25) ; C101.2 186.49,87.25 ; C101.2 187.2,86.5 ; R69.1 v2(128.78,127.89) ; R69.1 130.25,127.89 ; R69.1 129.54,127.14 ; 212.6,70.63 J5.4 212.6,72.76 ; 50.66,57.54 U31.A17 ; 50.34,149.73 C49.1 ; C49.1 51.77,149.73 ; C49.1 v2(51.05,148.97) ; 24.94,145.85 U4.15 ; v2(14.22,163.74) 14.22,164.47 14.73,164.97 C7.2 ; P1.C1 13.34,76.31 ; C9.2 23.37,165.81 ; C9.2 23.37,163.63 ; 13.34,25.54 13.34,26.16 ; 43.06,110.23 P6.32 ; 175.51,93.37 U24.2 v2(175.51,91.31) ; 164.52,111.17 U15.16 165.34,110.68 ; 35.18,163.7 33.78,163.7 ; 3.82,50.29 4.45,50.29 ; 5.71,25.54 5.71,26.16 ; 20.07,118.5 C62.1 v2(20.7,119.25) ; 203.39,80.56 C105.2 ; C105.2 v2(203.39,82.74) ; C105.2 202.44,81.66 ; C109.2 155.4,72.01 ; C109.2 154.31,71.76 153.8,71.25 v2(153.03,71.25) ; C109.2 153.21,72.01 ; 154.6,29.2 C134.1 ; C134.1 154.6,31 ; C134.1 v2(153.92,30.1) ; U31.AP3 84.73,43.54 ; R664.1 154.94,32.72 ; R664.1 154.94,31.29 ; R664.1 v2(154.31,32) ; 23.88,156.08 25.15,156.08 ; 204.14,37.08 R168.1 v2(204.85,36.19) ; P1.C17 13.34,55.99 ; 5.71,71.26 P1.J4 ; R90.1 120.65,114.88 ; R90.1 v2(120.65,113.41) ; R90.1 121.4,114.17 ; 174.71,109.27 U16.4 175.19,110.1 ; 18.66,91.11 U23.5 19.11,91.77 ; 33.57,111.54 P6.2 ; 12.07,68.07 12.07,68.69 ; 131.32,154.86 C25.2 ; 203.14,28.4 P10.9 ; P10.9 203.14,30.28 ; P10.9 v2(205.49,29.34) ; P10.9 200.99,29.34 ; DS7.C 200.37,95.12 ; DS7.C v2(199.65,95.89) ; DS7.C 199.65,94.32 ; DS7.C 198.94,95.12 ; 179.52,44.08 U32.5 ; 12.07,45.21 12.69,45.21 ; 14.61,38.24 P1.B30 ; 16.5,55.37 P1.A17 15.88,55.99 ; 13.34,70.61 13.34,71.23 ; 10.79,71.26 P1.E4 ; C7.2 15.11,166.07 ; C7.2 15.11,163.88 ; C7.2 15.24,164.97 15.75,164.47 v2(15.75,163.74) ; C88.1 v2(197.36,104.27) ; C88.1 198.16,105.17 ; C88.1 198.16,103.36 ; 3.82,35.05 P1.K33 ; 14.61,68.07 14.61,68.69 ; 112.83,83.29 P5.13 ; 155.19,19.3 U37.PAD ; 14.61,62.99 14.61,63.61 ; U31.AP18 84.73,58.54 ; 8.26,71.26 P1.G4 ; 53.25,110.23 P6.66 ; 50.66,45.54 U31.A5 ; 160.78,77.31 Q7.1 ; P1.D28 12.69,41.4 ; 9.53,73.15 9.53,73.77 ; 13.34,50.94 P1.C20 ; 50.66,46.54 U31.A6 ; 121.03,67.4 P5.66 ; P1.G1 8.26,76.31 ; 112.83,67.7 P5.65 ; 3.82,57.91 4.45,57.91 ; 80.86,110.23 P6.150 ; 13.34,40.13 13.34,40.75 ; R103.2 121.53,107.06 ; R103.2 v2(120.78,107.82) ; R103.2 120.78,106.35 ; v2(131.95,126.37) C61.1 132.66,125.6 ; 121.03,77.59 P5.32 ; 3.82,54.1 4.45,54.1 ; 15.88,25.54 15.88,26.16 16.5,26.16 ; 60.2,154.86 C22.2 ; v2(56.64,149.86) C38.1 57.35,150.75 ; U37.22 156.35,20.84 ; 11.44,32.51 P1.D35 ; C13.2 60.2,164.54 ; P1.B15 14.61,58.53 ; 158.29,59.94 C118.2 ; 164.52,111.82 U15.15 ; P1.B35 14.61,33.13 ; 13.34,35.7 P1.C32 ; 12.07,56.64 12.69,56.64 ; U25.5 190.69,89.23 ; 13.34,45.86 P1.C24 ; 3.82,61.72 4.45,61.72 ; 13.34,71.26 P1.C4 ; 65.19,41 U31.R1 ; 93.65,145.85 U7.15 ; 42.83,157.35 Q1.1 ; P1.B23 14.61,48.37 ; 12.07,73.15 12.07,73.77 ; R145.2 v2(208.41,69.72) ; 12.07,60.45 12.69,60.45 ; 52.95,102.03 P6.65 ; 10.79,70.61 10.79,71.23 ; P6.72 55.54,111.54 ; 14.61,42.67 14.61,43.29 ; U28.10 173.97,69.61 ; P1.E1 10.79,76.31 ; 94.65,110.23 P6.196 ; 13.34,61.1 P1.C12 ; C115.2 v2(154.94,65.91) ; 206.69,104.58 U21.6 ; U21.7 208.62,105.23 ; 68.07,156.77 C23.2 68.07,159.13
  TOP w0.635: C25.2 130.05,155.96 v1(128.27,157.73) ; v2(57.15,157.73) 58.93,155.96 C22.2 ; C13.2 58.8,163.45 v2(57.15,161.8) ; Q7.1 v2(161.42,76.2) ; Q1.1 v2(43.94,157.99) ; 165.23,62.99 166.88,61.34 C119.2 ; v1(128.27,161.8) 129.92,163.45 C19.2 ; Q7.3 v2(163.96,76.2) ; C118.2 159.38,61.21 161.16,62.99 ; Q1.3 v2(43.94,160.53) ; Q2.1 v1(115.06,157.99) ; Q2.3 v1(115.06,160.53)
  L11_POWER w0.508: J3.4 212.6,42.16 ; J3.4 212.6,40.28 ; J3.4 209.24,41.22 ; 212.6,72.64 J5.4 212.6,70.76 ; 172.09,33.16 TP7.1 ; TP7.1 170.83,34.42 ; TP7.1 172.09,35.67 ; TP7.1 173.34,34.42 ; P7.6 197.61,111.89 ; P7.6 196.29,110.57 ; P7.6 194.97,111.89 ; P7.6 196.29,113.21 ; 183.02,118.24 TP5.1 ; TP5.1 184.28,119.49 ; TP5.1 184.28,116.98 ; TP5.1 185.53,118.24 ; 212.6,24.91 J4.4 ; J4.4 209.24,25.85 ; J4.4 212.6,26.79 ; 209.24,56.33 J6.4 ; J6.4 212.6,57.27 ; J6.4 212.6,55.39 ; P11.1 189.99,15.67 ; P11.1 189.05,14.73 ; P11.1 189.99,13.79 ; P11.1 190.93,14.73 ; 212.6,65.77 J6.2 212.6,63.89 ; 212.6,48.78 J3.2 ; J3.2 212.6,50.66 ; J3.2 209.24,49.72 ; 212.6,79.26 J5.2 212.6,81.14 ; 209.24,34.35 J4.2 ; J4.2 212.6,35.29 ; J4.2 212.6,33.41 ; 200.48,111.89 P7.3 ; P7.3 201.8,113.21 ; P7.3 201.8,110.57 ; P7.3 203.12,111.89
  L12_POWER w0.508: S6.1 99.44,15.1 ; S6.1 98.44,14.1 ; S6.1 99.44,13.09 ; S6.1 100.44,14.1 ; 209.24,49.72 J3.2 ; J3.2 212.6,50.66 ; J3.2 212.6,48.78 ; P7.3 203.12,111.89 ; P7.3 200.48,111.89 ; P7.3 201.8,110.57 ; P7.3 201.8,113.21 ; 62.61,15.25 P9.5 ; P9.5 63.61,16.26 ; P9.5 61.61,16.26 ; P9.5 62.61,17.26 ; 72.77,15.25 P9.13 ; P9.13 73.77,16.26 ; P9.13 71.77,16.26 ; P9.13 72.77,17.26 ; J6.2 212.6,65.77 ; J6.2 212.6,63.89 ; J6.2 209.24,64.83 ; S5.2 93.86,14.1 ; S5.2 92.86,13.09 ; S5.2 92.86,15.1 ; S5.2 91.86,14.1 ; S5.1 87.36,14.1 ; S5.1 86.36,13.09 ; S5.1 86.36,15.1 ; S5.1 85.36,14.1 ; 212.6,24.91 J4.4 ; J4.4 209.24,25.85 ; J4.4 212.6,26.79 ; TP6.1 176.39,86.23 ; TP6.1 175.13,87.49 ; TP6.1 173.88,86.23 ; TP6.1 175.13,84.98 ; 212.6,79.26 J5.2 ; J5.2 212.6,81.14 ; J5.2 209.24,80.2 ; J3.4 212.6,42.16 ; J3.4 209.24,41.22 ; J3.4 212.6,40.28 ; S3.2 106.94,24.13 ; S3.2 105.94,23.13 ; S3.2 105.94,25.13 ; S3.2 104.94,24.13 ; 209.24,56.33 J6.4 ; J6.4 212.6,57.27 ; J6.4 212.6,55.39 ; TP7.1 173.34,34.42 ; TP7.1 172.09,35.67 ; TP7.1 172.09,33.16 ; P9.9 67.69,17.26 ; P9.9 67.69,15.25 ; P9.9 66.69,16.26 ; P9.9 68.69,16.26 ; P9.3 61.07,16.26 ; P9.3 60.07,17.26 ; P9.3 59.07,16.26 ; P9.3 60.07,15.25 ; 75.31,15.25 P9.15 ; P9.15 76.31,16.26 ; P9.15 74.31,16.26 ; P9.15 75.31,17.26 ; 182.86,95.77 S2.2 ; S2.2 181.85,96.77 ; S2.2 182.86,97.78 ; P9.17 77.85,17.26 ; P9.17 76.85,16.26 ; P9.17 77.85,15.25 ; P9.17 78.85,16.26 ; 56.53,16.26 P9.1 ; P9.1 58.53,16.26 ; P9.1 57.53,17.26 ; P9.1 57.53,15.25 ; 64.15,16.26 P9.7 ; P9.7 65.15,15.25 ; P9.7 66.15,16.26 ; P9.7 65.15,17.26 ; GP1.2 8.18,22.53 ; GP1.2 8.18,16.33 ; GP1.2 5.08,19.43 ; GP1.2 11.28,19.43 ; 104.94,14.1 S6.2 ; S6.2 106.94,14.1 ; S6.2 105.94,15.1 ; S6.2 105.94,13.09 ; 212.6,33.41 J4.2 ; J4.2 209.24,34.35 ; J4.2 212.6,35.29 ; S3.1 100.44,24.13 ; S3.1 99.44,25.13 ; S3.1 99.44,23.13 ; S3.1 98.44,24.13 ; P9.11 70.23,17.26 ; P9.11 70.23,15.25 ; P9.11 71.23,16.26 ; P9.11 69.23,16.26 ; P11.1 189.99,15.67 ; P11.1 190.93,14.73 ; P11.1 189.99,13.79 ; P11.1 189.05,14.73 ; P9.19 80.39,17.26 ; P9.19 81.39,16.26 ; P9.19 79.39,16.26 ; P9.19 80.39,15.25 ; 212.6,70.76 J5.4 ; J5.4 209.24,71.7 ; J5.4 212.6,72.64 ; 196.29,110.57 P7.6 ; P7.6 194.97,111.89 ; P7.6 197.61,111.89 ; P7.6 196.29,113.21
  BOTTOM w0.203: CN12.3 60.57,117.1 v2(60.33,117.35) 60.08,117.1 CN12.2 ; CN13.2 127.64,55.49 v2(127.89,55.25) 127.64,55 CN13.3 ; CN11.3 127.64,60.08 v2(127.89,60.33) 127.64,60.57 CN11.2 ; v2(113.03,18.41) 113.37,18.76 CN8.4 ; CN10.2 119.5,16.51 v2(119.25,16.26) 119,16.51 CN10.3 ; CN2.2 122.68,18.66 122.43,18.41 122.43,18.41 ; v2(115.19,18.41) 114.87,18.73 CN8.1 ; CN10.1 120,16.65 v2(120.4,16.26) ; CN4.3 72.64,117.1 v2(72.39,117.35) 72.14,117.1 CN4.2 ; CN2.1 123.18,18.55 v2(123.44,18.29) ; 122.43,18.41 v2(122.43,18.29) ; 122.43,18.41 122.18,18.66 CN2.3 ; CN10.4 118.5,16.52 v2(118.24,16.26) ; CN3.2 66.17,117.1 v2(66.42,117.35) 66.67,117.1 CN3.3 ; CN14.3 127.64,48.65 v2(127.89,48.89) 127.64,49.14 CN14.2 ; v2(121.28,18.29) 121.68,18.68 CN2.4 ; CN8.3 113.87,18.59 v2(114.05,18.41) 114.37,18.74 CN8.2 ; C150.1 190.82,151
  BOTTOM w0.254: v2(103.25,107.06) 102.99,107.32 CN9.3 ; CN7.1 102.1,112.38 v2(102.36,112.65) ; CN7.2 v2(102.36,111.88) ; v2(59.05,117.35) 59.31,117.35 59.57,117.08 CN12.1 ; CN1.3 101.85,103 v2(102.11,102.74) ; v2(127.89,50.17) 127.89,49.91 127.62,49.65 CN14.1 ; CN9.4 102.73,106.82 v2(103.25,106.3) ; CN9.2 v2(103.25,107.82) ; v2(127.89,59.06) 127.37,59.57 CN11.4 ; CN11.1 127.62,61.08 127.89,61.34 v2(127.89,61.59) ; 123.06,166.12 123.06,166.75 v1(122.81,167) ; v2(71.12,117.35) 71.37,117.35 71.64,117.08 CN4.1 ; v2(102.36,111.12) 102.1,111.38 CN7.3 ; CN1.4 101.59,102.5 v2(102.11,101.98) ; CN14.4 127.37,48.14 v2(127.89,47.62) ; v2(170.69,68.71) 170.18,68.2 169.55,68.2 ; v2(127.89,56.52) 127.89,56.26 127.62,56 CN13.1 ; v2(102.36,110.36) 101.84,110.88 CN7.4 ; v2(127.89,53.98) 127.37,54.49 CN13.4 ; CN1.1 101.84,104 v2(102.11,104.27) ; v2(65.15,117.35) 65.41,117.35 65.67,117.08 CN3.1 ; v2(61.59,117.35) 61.08,116.83 CN12.4 ; v2(67.69,117.35) 67.17,116.83 CN3.4 ; CN1.2 v2(102.1,103.5) ; CN9.1 102.99,108.32 v2(103.25,108.59) ; v2(73.66,117.35) 73.14,116.83 CN4.4
  BOTTOM w0.305: C210.2 159.38,111.38 158.88,111.89 ; C202.1 119,120.02 v2(118.49,120.52) ; C211.2 158.88,111.89 ; 158.88,111.89 v2(158.88,112.14) ; U39.8 v4(87.38,128.27) ; v4(86.63,127.77) 86.88,127.52 U39.4
  BOTTOM w0.381: C174.2 135.25,121.16 v2(134.75,120.65) 134.87,120.52 C193.2 ; C227.2 v2(203.71,101.98) ; C206.2 v2(173.74,112.14) ; C175.2 v2(133.1,120.65) ; C207.2 172.34,111.63 v2(172.85,112.14)
  BOTTOM w0.508: C285.1 88.13,62.99 ; C285.1 87.42,63.04 v1(87.69,63.04) ; C285.1 87.38,62.28 ; C285.1 87.38,63.7 ; v2(122.68,63.63) 122.68,63.58 122.09,62.87 122.05,62.87 ; R248.1 80.53,84.04 ; R248.1 v2(79.63,85.09) ; R248.1 78.73,84.04 ; v2(191.26,149.99) 191.01,149.73 C149.1 ; TP5.1 184.28,119.62 ; TP5.1 185.66,118.24 ; TP5.1 184.28,116.85 ; TP5.1 182.89,118.24 ; 125.02,21.2 C344.1 v2(125.63,21.95) ; 32.51,21.44 Q15.2 ; Q15.2 33.32,20.43 ; Q15.2 34.14,21.44 ; Q15.2 v2(33.32,22.4) ; 168.22,118.11 R233.2 ; R233.2 v2(169.08,117.18) ; R233.2 169.08,119.01 ; 79.5,120.56 79.5,121.67 ; 79.5,121.67 v2(78.23,121.67) ; 79.5,121.67 79.5,122.77 ; 79.5,121.67 v2(80.64,121.67) ; 146.56,124.46 v2(146.56,125.22) ; 146.56,124.46 145.85,124.46 ; 146.56,124.46 147.27,124.46 ; 67.18,55.7 C298.1 66.74,54.99 v1(66.69,55.04) ; 21.21,14.78 21.21,15.49 ; 21.21,15.49 v2(20.45,15.49) ; 21.21,15.49 21.21,16.21 ; 138.3,115.33 C192.1 v2(137.8,116.08) ; v2(135.51,111) C215.1 134.8,111.63 ; C340.2 93.85,17.35 ; C340.2 93.85,15.93 ; C340.2 94.6,16.64 ; v2(50.55,85.98) 50.55,85.09 50.93,84.71 C243.1 ; C256.2 v2(197.99,73.03) ; C256.2 197.19,72.12 ; C256.2 197.19,73.93 ; v1(69.69,57.04) 69.85,57.2 C296.1 ; C312.1 74.55,44.18 v1(74.69,44.04) ; C312.1 73.84,44.83 ; C312.1 75.26,44.83 ; 40.27,18.54 R333.1 ; R333.1 41.02,17.83 ; R333.1 v2(41.02,19.43) ; C274.1 65.58,66.93 v1(64.69,66.04) 64.77,65.96 C288.1 ; 160.48,111.38 C210.2 159.77,112.13 ; 63.88,40.14 C325.1 ; C325.1 62.84,40.89 v1(62.69,41.04) ; C325.1 64.59,40.89 ; 134.06,112.14 C216.1 v2(133.35,111.25) ; S5.2 93.99,14.1 ; S5.2 92.86,15.23 ; S5.2 91.73,14.1 ; S5.2 92.86,12.97 ; 171.63,111.38 C207.2 ; GP1.1 11.38,82.42 ; GP1.1 4.93,82.42 ; GP1.1 8.15,79.2 ; GP1.1 8.15,85.65 ; C295.1 71.63,57.1 v1(71.69,57.04) ; 191.59,102.87 C228.1 ; C228.1 192.44,103.77 ; C228.1 v2(192.44,101.82) ; 62.61,15.13 P9.5 ; P9.5 62.61,17.39 ; P9.5 61.48,16.26 ; P9.5 63.74,16.26 ; C176.2 131.45,121.35 ; C176.2 130.94,121.03 v2(131.32,120.65) 131.19,120.52 C199.2 ; C176.2 130.43,121.35 ; S6.2 105.94,15.23 ; S6.2 107.07,14.1 ; S6.2 105.94,12.97 ; S6.2 104.81,14.1 ; R216.1 124.16,157.35 ; R216.1 123.44,158.1 ; R216.1 v2(122.68,157.35) ; R486.1 v2(36.45,13.84) ; R486.1 35.7,14.61 ; R486.1 36.45,15.32 ; 192.82,95.76 V1.2 ; V1.2 194.24,95.76 ; V1.2 193.53,95.05 ; V1.2 v2(193.53,96.54) ; Q16.2 35.89,17.79 ; Q16.2 35.08,16.79 ; Q16.2 36.7,16.79 ; Q16.2 v2(35.89,15.67) ; C275.2 v2(204.34,63.12) ; C275.2 R278.2 R277.2 ; C275.2 205.09,64.14 ; R250.1 v2(73.03,85.09) ; R250.1 73.93,84.04 ; R250.1 72.12,84.04 ; 93.51,47.24 C309.1 ; C309.1 95.72,47.24 ; C309.1 v2(94.62,48.77) ; C309.1 v2(94.62,45.97) ; 71.64,116.02 CN4.1 71.21,116.65 ; 204.46,101.22 C227.2 203.71,100.51 ; 170.56,62.98 R279.2 v2(171.32,62.23) ; 190.59,151.91 C150.1 190.59,150.1 ; R220.2 195.28,145.29 ; R220.2 194.56,144.54 ; R220.2 193.85,145.29 ; R220.2 194.06,144.78 v1(194.06,144.42) ; C291.N v2(134.01,58.57) ; C291.N v2(130.96,58.57) ; C291.N 132.46,56.97 ; C291.N 132.46,60.17 ; v2(46.1,19.43) R330.1 46.1,17.83 ; v2(37.21,64.01) 38.1,64.01 38.48,64.39 C289.1 ; TP6.1 176.52,86.23 ; TP6.1 175.13,87.62 ; TP6.1 175.13,84.85 ; TP6.1 173.75,86.23 ; v2(140.97,146.18) C151.2 141.68,145.41 ; C250.1 v2(95,74.93) ; C250.1 96.1,75.95 ; C250.1 93.89,75.95 ; C250.1 v2(95,76.96) ; 190.25,157.53 R215.2 v2(190.25,159.13) ; C266.2 198.21,70.24 ; C266.2 199.06,69.34 ; C266.2 v2(198.21,68.36) ; 123.61,19.11 CN2.1 123.18,19.75 ; 74.18,16.26 P9.15 ; P9.15 75.31,17.39 ; P9.15 76.44,16.26 ; P9.15 75.31,15.13 ; S1.GND1 214.5,142.35 ; S1.GND1 213.12,140.97 ; S1.GND1 214.5,139.59 ; 185.5,69.22 C269.2 v2(186.35,68.41) ; v1(87.69,58.04) C292.1 87.38,58.75 ; 21.21,19.18 21.21,19.89 ; 21.21,19.18 21.21,18.47 ; 21.21,19.18 v2(20.45,19.18) ; CN8.2 114.37,19.8 ; C284.1 v2(95,61.47) ; C284.1 v2(95,63.5) ; C284.1 96.1,62.48 ; C284.1 93.89,62.48 ; 214.5,126.38 S1.GND2 ; S1.GND2 213.12,127.76 ; S1.GND2 214.5,129.15 ; 191.52,72.9 v2(191.52,73.66) ; 191.52,72.9 190.8,72.9 ; 191.52,72.9 192.23,72.9 ; 92.08,127.81 R556.1 ; R556.1 92.82,128.52 ; R556.1 v2(92.08,129.16) ; R296.2 v2(181.23,49.4) ; R296.2 181.94,50.04 ; R296.2 180.52,50.04 ; 65.67,116.02 CN3.1 65.24,116.65 ; C278.2 v2(192.41,62.61) ; C278.2 190.93,62.61 ; C278.2 191.64,61.86 ; C277.2 v2(193.71,62.27) ; C277.2 194.69,61.42 ; C277.2 195.59,62.27 ; C321.1 79.46,41.28 v1(79.69,41.04) ; C321.1 78.61,40.53 ; C321.1 77.9,41.28 ; 59.14,116.65 CN12.1 59.57,116.02 ; TP1.1 48.9,144.39 ; TP1.1 47.51,143 ; TP1.1 48.9,141.62 ; TP1.1 50.28,143 ; 138.18,110.88 C213.1 v2(138.68,111.63) ; C255.2 198.36,71.12 ; C255.2 197.61,70.41 ; C255.2 v2(197.61,71.76) ; 57.79,107.84 R242.1 v2(57.15,108.59) ; C158.2 64.26,146.16 ; C158.2 63.55,145.41 ; C158.2 v2(64.77,145.41) ; R221.1 v2(144.4,144.02) ; R221.1 145.15,143.26 ; R221.1 144.4,142.54 ; 139.33,102.11 C230.1 ; C230.1 v2(140.08,101.47) ; C230.1 140.08,102.82 ; R312.1 61.93,36.58 ; R312.1 60.5,36.58 ; R312.1 v2(61.21,35.81) ; v2(81.28,121.03) 81.92,121.67 82.42,121.67 ; C222.1 v1(87.76,108.33) ; C332.1 v2(75.56,35.81) ; C332.1 76.28,36.7 ; C332.1 74.85,36.7 ; 196.48,129.67 S1.6 ; S1.6 199.5,129.67 ; S1.6 197.99,131.18 ; S1.6 197.99,128.16 ; 190.37,49.5 Q14.2 ; Q14.2 191.19,48.5 ; Q14.2 v2(192.13,49.5) ; R254.1 v2(61.09,85.22) ; R254.1 61.99,84.16 ; R254.1 60.18,84.16 ; C339.1 v2(181.99,25.02) ; C339.1 181.99,23.55 ; C339.1 182.74,24.26 ; C234.1 97.74,99.31 ; C234.1 96.32,99.31 ; C234.1 97.03,98.93 v3(96.9,98.81) ; v2(186.56,72.39) C260.2 185.81,72.9 ; C280.2 187.85,62.65 ; C280.2 186.04,62.65 ; C280.2 v2(186.94,61.85) ; 66.56,16.26 P9.9 ; P9.9 67.69,15.13 ; P9.9 68.82,16.26 ; P9.9 67.69,17.39 ; C264.1 63.55,72.9 v1(62.69,72.04) ; 66.67,116.02 CN3.3 ; R340.2 21.72,126.23 ; R340.2 22.43,125.48 ; R340.2 21.01,125.48 ; 156.72,22.02 C342.2 ; C342.2 v2(156.72,23.5) ; C342.2 157.47,22.73 ; 85.39,145.41 C156.2 86.11,145.8 v2(86.49,146.18) ; C163.1 v2(91.76,131.13) ; C163.1 91.76,133.31 ; C163.1 92.71,132.21 ; 189.36,95.64 S2.1 ; S2.1 188.23,96.77 ; S2.1 190.49,96.77 ; S2.1 189.36,97.9 ; v2(89.28,125.48) C181.1 90.03,124.71 ; 82.68,40.53 C320.1 ; C320.1 83.46,41.28 v1(83.69,41.04) ; C320.1 81.97,41.28 ; 105.94,23 S3.2 ; S3.2 104.81,24.13 ; S3.2 107.07,24.13 ; S3.2 105.94,25.26 ; 207.65,65.52 207.65,64.77 208.36,64.77 ; v2(74.68,85.95) 74.68,85.09 75.06,84.71 C241.1 ; TP2.1 132.59,138.42 ; TP2.1 132.59,135.65 ; TP2.1 131.2,137.03 ; TP2.1 133.97,137.03 ; v2(15.62,146.18) 15.11,145.67 C162.2 14.4,145.41 ; v4(87.38,128.27) 89.59,128.27 ; R225.1 152.1,121.41 ; R225.1 v2(150.62,121.41) ; R225.1 151.38,122.16 ; 113.37,19.8 CN8.4 112.94,19.16 ; 128.52,111.26 C219.1 v2(127.89,112.01) ; 116.97,62.87 117.48,62.36 v2(117.98,62.36) ; 116.97,62.87 116.97,63.58 ; 116.97,62.87 117.72,62.87 ; 116.97,62.87 116.97,62.15 ; 187.32,41.99 U41.4 ; U41.4 187.94,43.09 ; U41.4 v2(187.32,44.32) ; C186.N v2(64.36,123.04) ; C186.N 65.96,121.28 ; C186.N v2(64.36,119.61) ; C205.1 81.6,117.44 ; C205.1 82.55,116.33 ; C205.1 v2(81.6,115.13) ; 118.03,124.97 C179.1 ; C179.1 v2(119.38,124.97) ; C179.1 118.75,125.72 ; 72.95,36.7 C333.1 ; C333.1 74.37,36.7 ; C333.1 v2(73.66,35.81) ; v2(140.08,146.18) 139.57,145.67 C152.2 138.86,145.41 ; CR5.2 204.65,86.36 ; CR5.2 v2(203.2,86.36) ; CR5.2 203.96,85.42 ; 115.3,19.16 CN8.1 114.87,19.8 ; 126.56,55.49 CN13.2 ; 65.15,15.13 P9.7 ; P9.7 66.28,16.26 ; P9.7 65.15,17.39 ; P9.7 64.02,16.26 ; P9.11 71.36,16.26 ; P9.11 69.1,16.26 ; P9.11 70.23,15.13 ; P9.11 70.23,17.39 ; C316.1 66.37,44.2 ; C316.1 64.95,44.2 ; C316.1 65.66,44.07 v1(65.69,44.04) ; 169.55,67.49 169.55,68.91 ; 85.34,121.67 85.34,122.77 ; 85.34,121.67 v2(84.2,121.67) ; 85.34,121.67 v2(86.61,121.67) ; 85.34,121.67 85.34,120.56 ; C248.2 183.9,80.7 ; C248.2 182.99,79.84 ; C248.2 v2(184.66,79.84) ; U40.3 174.9,121.47 ; U40.3 173.84,122.03 ; U40.3 173.68,121.47 173.61,121.54 v2(173.61,122.17) ; 86.36,12.97 S5.1 ; S5.1 86.36,15.23 ; S5.1 85.23,14.1 ; S5.1 87.49,14.1 ; 122.05,62.15 122.05,62.87 ; 122.05,62.87 122.05,63.58 ; 93.89,66.17 C271.1 ; C271.1 v2(95,65.15) ; C271.1 96.1,66.17 ; C271.1 v2(95,67.18) ; R293.1 v2(93.98,56.9) ; R293.1 93.05,55.99 ; R293.1 93.05,57.8 ; C148.2 182.77,156.93 ; C148.2 v2(181.86,157.86) ; C148.2 180.96,156.93 ; v2(37.08,48.77) 37.97,48.77 38.35,48.39 C317.1 ; 67.56,44.5 C315.1 66.86,45.21 v1(66.69,45.04) ; R243.1 57.79,106.92 ; R243.1 v2(57.15,106.17) ; R243.1 58.5,106.17 ; 200.35,111.89 P7.3 ; P7.3 201.8,110.44 ; P7.3 201.8,113.34 ; P7.3 203.25,111.89 ; 168.1,111.38 C208.2 v2(167.39,112.14) ; 127.19,59.14 CN11.4 126.56,59.57 ; S1.3 201.8,131.18 ; S1.3 201.8,128.16 ; S1.3 203.31,129.67 ; S1.3 200.29,129.67 ; v1(68.69,63.04) 68.52,62.87 C287.1 ; 89.92,15 U43.2 89.92,16.12 ; 63.32,78.36 C254.1 v2(62.61,79.25) ; R297.1 v2(94.11,52.96) ; R297.1 93.18,52.06 ; R297.1 93.18,53.86 ; C289.1 37.39,64.64 ; C289.1 38.48,64.77 38.35,64.9 38.48,65.02 38.1,65.41 v2(37.21,65.41) ; C289.1 39.57,64.64 ; C270.1 v2(95,70.48) ; C270.1 v2(95,68.45) ; C270.1 93.89,69.47 ; C270.1 96.1,69.47 ; 112.14,16.26 C347.1 ; C347.1 v2(113.09,15.05) ; C347.1 113.09,17.36 ; 80.39,15.13 P9.19 ; P9.19 80.39,17.39 ; P9.19 81.52,16.26 ; P9.19 79.26,16.26 ; v1(84.69,59.04) 84.58,58.93 C293.1 ; 73.23,44.83 C314.1 72.52,44.21 v1(72.69,44.04) ; C244.2 200.79,79.88 v2(201.17,79.5) ; C244.2 199.9,80.63 ; C244.2 199.19,79.88 ; 20.92,29.45 C337.1 ; C337.1 v2(21.84,30.35) ; C337.1 20.92,31.26 ; P7.6 196.29,113.34 ; P7.6 194.84,111.89 ; P7.6 197.74,111.89 ; P7.6 196.29,110.44 ; CN2.2 122.68,19.75 ; v2(37.08,59.82) 37.97,59.82 38.35,60.2 C290.1 ; 93.89,72.64 C262.1 ; C262.1 v2(95,71.63) ; C262.1 96.1,72.64 ; C262.1 v2(95,73.66) ; v2(83.57,121.03) 82.93,121.67 82.42,121.67 ; v2(186.94,79.76) C247.2 185.34,79.76 ; 37.25,48.01 C317.1 ; C317.1 39.46,48.01 ; C317.1 38.35,47.75 37.97,47.37 v2(37.08,47.37) ; 103.06,44.91 E3.1 ; E3.1 102.18,45.85 ; E3.1 103.94,45.85 ; E3.1 v2(103.06,46.8) ; C324.1 66.5,40.89 ; C324.1 64.84,40.89 v1(64.69,41.04) ; C324.1 65.79,40.14 ; 92.42,125.72 C164.1 ; C164.1 92.42,127.52 ; C164.1 v2(93.22,126.62) ; 8.18,16.2 GP1.2 ; GP1.2 11.41,19.43 ; GP1.2 4.95,19.43 ; GP1.2 8.18,22.66 ; v1(87.69,52.04) 87.66,52.07 C303.1 ; v1(78.69,44.04) 78.49,44.24 C311.1 ; C149.1 191.91,149.19 ; C149.1 190.11,149.19 ; C249.1 v2(95,80.64) ; C249.1 96.1,79.25 ; C249.1 93.89,79.25 ; C249.1 v2(95,78.11) ; v2(98.73,113.49) 98.73,114.12 C220.1 ; 133.74,118.49 C195.1 v2(134.49,119.13) ; 126.56,49.14 CN14.2 ; v2(52.32,157.99) R217.1 51.61,157.35 ; 72.64,116.02 CN4.3 ; v1(68.69,50.04) 68.57,50.17 C306.1 68.2,49.45 ; C232.1 v2(33.27,104.9) ; C232.1 32.56,103.76 ; C232.1 33.99,103.76 ; C267.2 v2(197.23,67.06) ; C267.2 197.23,65.58 ; C267.2 197.98,66.29 ; 151.9,22.73 C343.2 v2(152.65,23.5) ; 37.25,56.52 C301.1 ; C301.1 38.35,56.77 37.97,57.15 v2(37.08,57.15) ; C301.1 39.46,56.52 ; C301.1 38.35,56.13 37.97,55.75 v2(37.08,55.75) ; 74.68,40.53 C322.1 ; C322.1 75.46,41.28 v1(75.69,41.04) ; C322.1 73.96,41.28 ; v2(140.08,111.63) C212.1 139.57,110.88 ; v2(66.29,145.41) C157.2 65.66,146.16 ; 139.37,121.67 R226.1 ; R226.1 140.08,122.42 ; R226.1 v2(140.84,121.67) ; 56.64,83.6 C242.1 ; C242.1 56.64,85.81 ; C242.1 56.77,84.71 57.4,85.34 v2(57.4,85.98) ; C242.1 56.01,84.71 55.63,85.09 v2(55.63,85.98) ; P2.1 200.53,159.06 ; P2.1 201.6,157.99 ; P2.1 200.53,156.92 ; P2.1 199.47,157.99 ; 198.12,90.35 C236.2 ; C236.2 v2(198.12,91.95) ; C236.2 198.87,91.06 ; 140.08,117.11 140.08,117.86 ; 140.08,117.86 v2(140.84,117.86) ; 140.08,117.86 139.37,117.86 ; S6.1 100.57,14.1 ; S6.1 99.44,12.97 ; S6.1 98.31,14.1 ; S6.1 99.44,15.23 ; v2(89.28,122.68) C182.1 90.03,123.32 ; 189.74,72.9 v2(189.74,73.66) ; 189.74,72.9 190.45,72.9 ; 189.74,72.9 189.03,72.9 ; 191.39,92.51 R247.1 ; R247.1 v2(191.39,93.85) ; R247.1 190.64,93.22 ; C180.1 117.22,125.72 ; C180.1 v2(116.59,124.97) ; C180.1 117.93,124.97 ; 126.56,48.14 CN14.4 127.19,47.71 ; 134.75,121.35 C174.2 135.76,121.35 ; P9.3 61.2,16.26 ; P9.3 58.94,16.26 ; P9.3 60.07,15.13 ; P9.3 60.07,17.39 ; C286.1 78.56,60.91 v1(77.69,60.04) ; 144.15,102.11 144.89,102.11 ; 144.15,102.11 v2(144.15,101.26) ; 144.15,102.11 144.15,102.82 ; C335.2 v2(137.16,34.16) ; C335.2 136.41,33.4 ; C335.2 137.16,32.69 ; 72.14,116.02 CN4.2 ; C276.2 v2(197.78,62.27) ; C276.2 196.85,61.42 ; C276.2 195.95,62.27 ; C241.1 75.31,83.6 ; C241.1 75.69,84.71 76.07,85.09 v2(76.07,85.95) ; C241.1 75.31,85.81 ; v2(95.63,146.18) 95.12,145.67 C154.2 94.41,145.41 ; C231.1 v2(103.31,102.3) ; C231.1 104.39,101.35 ; C231.1 105.5,102.3 ; 43.56,17.83 R332.1 v2(43.56,19.43) ; Q13.2 163.45,118.9 ; Q13.2 162.64,119.9 ; Q13.2 v2(162.64,117.78) ; 126.56,60.08 CN11.3 ; 66.15,84.16 R252.1 ; R252.1 v2(67.06,85.09) ; R252.1 67.96,84.16 ; C226.2 v2(203.71,102.74) ; C226.2 204.46,103.38 ; C226.2 203.71,104.09 ; v1(74.69,69.04) 73.81,69.04 C272.1 ; R313.1 60.27,36.58 ; R313.1 v2(59.56,35.81) ; R313.1 58.85,36.58 ; Q10.2 190.75,160.3 ; Q10.2 189.94,159.3 ; Q10.2 189.13,160.3 ; Q10.2 v2(189.94,161.47) ; 96.52,146.16 C153.2 v2(97.41,145.41) ; 58.17,130.56 v2(60.07,130.56) ; 58.17,130.56 v2(56.39,130.56) ; 58.17,130.56 58.17,129.46 ; 58.17,130.56 58.17,131.65 ; 187.88,62.74 C279.2 ; C279.2 v2(189.36,62.74) ; C279.2 188.59,61.99 ; 20.66,31.61 C338.1 ; C338.1 20.66,33.41 ; C338.1 20.83,32.51 21.21,32.89 v2(21.72,32.89) ; v2(57.4,79.25) R270.1 56.69,78.36 ; U43.3 89.27,16.12 ; U43.3 88.76,15.56 ; U43.3 89.27,15 ; R237.1 151,117.22 v2(150.75,117.47) ; R237.1 152.1,117.22 ; R237.1 151.38,116.47 ; R314.2 184.78,33.86 ; R314.2 v2(184.78,32.39) ; R314.2 184.04,33.15 ; 66.17,116.02 CN3.2 ; C341.1 21.39,26.67 ; C341.1 20.54,27.57 ; C341.1 v2(20.54,25.69) ; 82.42,121.67 82.42,122.77 ; 82.42,121.67 82.42,120.56 ; 121.68,19.75 CN2.4 121.25,19.11 ; 188.92,14.73 P11.1 ; P11.1 189.99,15.8 ; P11.1 191.06,14.73 ; P11.1 189.99,13.66 ; v2(131.95,111.25) C217.1 131.24,112.14 ; 114.3,86.66 C239.1 ; C239.1 v2(114.3,88.14) ; C239.1 115.05,87.38 ; C318.1 v2(130.24,45.4) ; C318.1 131.19,44.2 ; C318.1 v2(130.24,42.99) ; R280.2 v2(155.32,62.48) ; R280.2 153.85,62.48 ; R280.2 154.56,63.23 ; R267.2 153.09,69.29 ; R267.2 153.9,70 ; R267.2 153.9,68.58 ; R268.1 v2(126.37,78.87) ; R268.1 126.37,77.39 ; R268.1 127.11,78.11 ; CN2.3 122.18,19.75 ; 37.25,60.58 C290.1 ; C290.1 38.35,60.83 37.97,61.21 v2(37.08,61.21) ; C290.1 39.46,60.58 ; C252.1 69.42,78.36 ; C252.1 v2(68.71,79.25) ; C252.1 68,78.36 ; 157.66,111.38 C211.2 158.37,112.13 ; C334.1 56.34,36.45 ; C334.1 54.91,36.45 ; C334.1 v2(55.63,35.69) ; C204.1 117.93,115.32 ; C204.1 v2(116.46,115.32) ; C204.1 117.22,114.57 ; 66.37,78.36 C253.1 v2(65.66,79.25) ; S3.1 100.57,24.13 ; S3.1 98.31,24.13 ; S3.1 99.44,23 ; S3.1 99.44,25.26 ; 77.77,44.83 C311.1 ; C311.1 79.2,44.83 ; C214.1 v2(136.91,111) ; 122.35,166.12 123.77,166.12 ; 126.56,55 CN13.3 ; 151,16.59 R341.2 151,15.16 ; 61.51,116.65 CN12.4 61.08,116.02 ; C307.1 38.48,52.32 38.35,52.45 38.48,52.58 38.1,52.96 v2(37.21,52.96) ; C307.1 39.57,52.2 ; C307.1 38.48,51.94 38.1,51.56 v2(37.21,51.56) ; C307.1 37.39,52.2 ; 72.47,78.36 C251.1 v2(71.75,79.25) ; v2(196.85,79.46) C245.2 195.96,80.32 ; C243.1 51.18,83.6 ; C243.1 51.69,84.71 52.07,85.09 v2(52.07,85.98) ; C243.1 51.18,85.81 ; v2(131.57,117.73) C198.1 130.86,117.09 ; 17.22,145.41 C161.2 v2(16.51,146.18) ; C188.1 147.4,115.06 ; C188.1 v2(146.69,114.3) ; C188.1 145.97,115.06 ; 87.5,72.26 v2(88.65,72.26) ; 87.5,72.26 87.5,72.97 ; 87.5,72.26 87.5,71.55 ; v1(68.69,52.04) 68.59,51.94 C305.1 ; C199.2 130.37,120.01 ; C199.2 130.37,121.03 ; 76.58,53.67 C304.1 76.58,52.15 v1(76.69,52.04) ; v2(186.56,71.5) C261.2 185.81,70.74 ; S2.2 182.86,97.9 ; S2.2 182.86,95.64 ; S2.2 183.99,96.77 ; S2.2 181.73,96.77 ; R538.1 187.95,151.32 ; R538.1 186.94,152.27 ; R538.1 185.94,151.32 ; R538.1 187.07,151.45 v1(187.07,152.4) ; v2(127.25,125.35) C178.1 126.54,124.59 ; 126.56,60.57 CN11.2 ; 205.99,85.42 CR4.2 ; CR4.2 v2(205.23,86.36) ; CR4.2 206.68,86.36 ; 56.4,16.26 P9.1 ; P9.1 57.53,17.39 ; P9.1 58.66,16.26 ; P9.1 57.53,15.13 ; P9.13 72.77,17.39 ; P9.13 72.77,15.13 ; P9.13 71.64,16.26 ; P9.13 73.9,16.26 ; C172.1 139.06,126.86 ; C172.1 139.78,126.11 ; C172.1 v2(138.56,126.11) ; 127.19,50.08 CN14.1 126.56,49.65 ; U42.5 v2(140.34,39.24) ; U42.5 138.94,39.85 ; U42.5 137.54,39.24 ; 126.56,48.65 CN14.3 ; CN8.3 113.87,19.8 ; v2(48.64,19.43) R329.1 48.64,17.83 ; 133.6,121.35 C175.2 132.59,121.35 ; 118.07,17.08 CN10.4 118.5,17.72 ; v1(68.69,59.04) C297.1 68.45,58.09 ; 118.75,114.57 C203.1 ; C203.1 118.03,115.32 ; C203.1 v2(119.63,115.32) ; v1(80.69,44.04) 80.64,44.09 C310.1 ; 67.95,130.56 67.95,131.65 ; 67.95,130.56 v2(69.72,130.56) ; 67.95,130.56 v2(66.17,130.56) ; 67.95,130.56 67.95,129.46 ; 114.68,23.44 C346.1 v2(114.68,22.1) ; C310.1 81.36,44.83 ; C310.1 79.93,44.83 ; 127.19,61.51 CN11.1 126.56,61.08 ; C170.1 v2(142.37,126.11) ; C170.1 142.88,126.86 ; C170.1 143.59,126.11 ; R46.1 160.78,68.53 ; R46.1 160.78,67.11 ; R46.1 v2(161.54,67.82) ; v2(25.78,16) U44.2 25.78,17.89 ; 135.57,120.01 C193.2 ; C209.2 165.99,111.63 v2(166.5,112.14) ; 59.99,78.36 R269.1 v2(60.71,79.25) ; R241.1 v2(43.31,115.7) ; R241.1 42.42,116.45 ; R241.1 41.71,115.7 ; 119.13,120.73 C202.1 119.13,119.3 ; TP3.1 167.77,138.42 ; TP3.1 167.77,135.65 ; TP3.1 169.15,137.03 ; TP3.1 166.38,137.03 ; v2(189.74,80.64) C246.2 190.45,79.76 ; 144.32,39.12 R306.2 ; R306.2 v2(145.03,40) ; R306.2 145.75,39.12 ; 130.63,112.01 C218.1 129.92,111.12 v2(129.86,111.07) ; v2(126.87,118.75) 126.87,118.11 126.12,118.11 ; 147.37,124.46 148.08,124.46 ; 148.08,124.46 148.79,124.46 ; 148.08,124.46 v2(148.08,125.22) ; 192.33,72.9 v2(193.8,72.9) ; v2(137.16,126.11) C173.1 137.67,126.86 ; 25.7,145.41 C160.2 26.42,145.67 v2(26.92,146.18) ; v2(82.8,130.18) R222.2 83.44,129.46 ; C326.2 v2(146.69,40) ; C326.2 147.4,39.12 ; C326.2 145.97,39.12 ; 87.5,146.16 C155.2 v2(88.39,145.41) ; 73.14,116.02 CN4.4 73.57,116.65 ; C299.1 64.77,57.12 v1(64.69,57.04) ; C240.1 v2(95.12,87.38) ; C240.1 v2(95.12,83.82) ; C240.1 96.22,85.6 ; C240.1 94.03,85.6 ; 67.69,72.15 C263.1 65.83,72.9 v1(65.69,73.04) ; 88.15,13.84 R320.1 ; R320.1 88.9,13.13 ; R320.1 88.9,14.55 ; 67.69,40.14 C323.1 66.84,40.89 v1(66.69,41.04) ; U13.PAD 147.43,119.76 ; U13.PAD 146.69,119.05 ; U13.PAD 146.69,119.89 v2(146.43,120.14) ; C141.1 101.47,30.72 ; C141.1 102.18,29.97 ; C141.1 100.84,29.97 v2(100.33,30.48) ; v1(62.69,57.04) 62.74,57.09 C300.1 ; 67.6,116.65 CN3.4 67.17,116.02 ; C206.2 174.45,111.38 ; v2(28.7,145.29) 28.57,145.41 C159.2 27.81,146.16 ; 192.41,90.35 C238.2 v2(191.64,91.06) ; 121.79,24.08 v2(121.79,22.48) ; C177.1 v2(128.65,125.35) ; 126.56,56 CN13.1 127.19,56.43 ; v2(51.18,19.43) R328.1 51.18,17.83 ; P9.17 78.98,16.26 ; P9.17 77.85,17.39 ; P9.17 77.85,15.13 ; P9.17 76.72,16.26 ; v1(74.69,59.04) 74.42,58.77 C294.1 73.67,58.04 ; C265.1 61.69,74.77 v1(61.69,75.04) ; v2(148.21,114.43) C187.1 147.5,115.06 ; 82.68,128.65 82.68,129.36 ; 82.68,128.65 81.93,128.65 ; 82.68,128.65 v2(82.68,127.89) ; C348.1 29.29,17.14 ; C348.1 28.57,16.4 ; C348.1 v2(27.81,17.14) ; 60.57,116.02 CN12.3 ; 120.44,17.08 CN10.1 120,17.72 ; 172.09,33.03 TP7.1 ; TP7.1 170.7,34.42 ; TP7.1 172.09,35.8 ; TP7.1 173.47,34.42 ; CN10.3 119,17.72 ; 185.75,66.55 C268.2 ; C268.2 v2(186.6,67.4) ; C268.2 186.6,65.65 ; 190.82,151 v2(191.52,151) ; 127.19,54.06 CN13.4 126.56,54.49 ; 141.48,126.86 C171.1 v2(140.97,126.11) ; 60.08,116.02 CN12.2 ; v1(68.69,67.04) 68.67,67.06 C273.1 67.69,66.31 ; v2(47.24,168.02) R207.2 47.99,167.26 ; CN10.2 119.5,17.72 ; C196.1 v2(134.37,117.73) 135,117.09 C194.1 136.47,117.09 ; 126.87,116.71 v2(126.87,116.2) ; C197.1 v2(132.97,117.73)
  vias: v1(1.02,57.28) v1(1.14,73.28) v1(1.14,69.09) v1(1.14,63.75) v1(1.14,50.93) v1(1.14,47.24) v1(1.27,43.31) v1(1.27,38.1) v1(1.65,144.78) v1(1.65,141.6) v1(1.65,138.81) v1(1.65,136.27) v1(1.65,133.22) v1(1.65,130.05) v1(1.65,127.25) v1(1.65,33.66) v1(1.65,30.61) v1(1.65,27.43) v1(1.65,24.64) v1(1.65,22.22) v1(1.65,19.18) v1(1.65,16.76) v1(1.65,14.22) v1(1.65,10.67) v1(1.78,170.81) v1(1.78,167.89) v1(1.78,164.85) v1(1.78,161.67) v1(1.78,158.88) v1(1.78,156.34) v1(1.78,153.29) v1(1.78,150.11) v1(1.78,147.32) v1(1.78,123.95) v1(1.78,120.78) v1(1.78,117.98) v1(1.78,115.44) v1(1.78,112.39) v1(1.78,109.22) v1(1.78,106.43) v1(1.78,103.51) v1(1.78,100.33) v1(1.78,97.54) v1(1.78,95) v1(1.78,91.95) v1(1.78,88.77) v1(1.78,85.98) v1(1.78,83.19) v1(1.78,80.01) v1(1.78,77.22) v1(2.54,39.37) v1(2.67,59.44) v1(2.67,55.5) v1(2.67,48.51) v1(3.81,172.21) v1(3.81,10.54) v1(4.57,111.12) v1(4.7,87.88) v1(4.83,119.25) v1(4.95,78.49) v1(5.08,23.5) v1(5.97,129.92) v1(6.1,154.81) v1(6.22,10.54) v1(6.35,141.22) v1(6.35,105.66) v1(6.86,100.08) v1(6.98,172.21) v1(7.11,124.08) v1(7.24,163.83) v1(7.24,147.7) v1(8.38,136.65) v1(8.51,114.81) v1(8.64,90.81) v1(8.89,10.54) v1(9.02,94.87) v1(9.14,168.91) v1(9.91,14.48) v1(10.03,172.21) v1(10.54,151) v1(10.67,125.98) v1(11.05,141.48) v1(11.05,108.97) v1(11.43,159.13) v1(11.56,132.97) v1(11.68,145.8) v1(11.94,10.54) v1(12.07,120.52) v1(12.83,88.52) v1(12.95,172.21) v1(13.34,94.49) v1(13.59,137.41) v1(14.1,21.59) v1(14.48,116.97) v1(14.99,112.52) v1(15.11,10.54) v1(15.88,172.21) v1(16,161.67) v1(16,79.25) v1(16.38,83.95) v1(16.64,121.79) v1(17.14,18.54) v1(17.91,10.54) v1(18.16,109.22) v1(18.8,140.21) v1(19.05,172.21) v1(19.3,13.08) v1(19.94,148.72) v1(20.83,97.28) v1(20.83,87.63) v1(20.83,24.51) v1(20.95,10.54) v1(21.08,114.55) v1(21.46,109.47) v1(21.72,80.26) v1(21.72,76.71) v1(21.84,160.15) v1(21.84,70.23) v1(21.97,92.08) v1(22.1,172.21) v1(22.1,142.11) v1(22.35,130.3) v1(22.73,134.87) v1(22.73,27.69) v1(23.49,100.33) v1(23.88,83.57) v1(23.88,32.89) v1(24,129.16) v1(24,10.54) v1(24.26,25.27) v1(24.76,115.95) v1(24.76,103.38) v1(24.76,12.57) v1(24.89,79.38) v1(25.02,172.21) v1(25.4,91.69) v1(25.4,73.79) v1(25.53,95.25) v1(26.8,159.26) v1(27.18,10.54) v1(27.69,172.21) v1(27.81,76.58) v1(28.45,27.69) v1(29.08,88.01) v1(29.21,103.25) v1(29.72,35.18) v1(29.84,30.86) v1(29.97,10.54) v1(30.1,137.92) v1(30.48,129.92) v1(30.86,172.21) v1(30.91,72.01) v1(31.24,125.35) v1(31.24,114.05) v1(31.37,160.66) v1(31.62,95.89) v1(31.75,92.2) v1(32.26,42.55) v1(32.38,144.02) v1(32.38,132.46) v1(32.89,10.54) v1(33.91,172.21) v1(34.04,146.81) v1(34.67,10.54) v1(34.8,82.55) v1(35.31,70.99) v1(35.56,109.22) v1(35.81,89.41) v1(36.45,27.69) v1(36.7,127.76) v1(36.7,108.08) v1(36.83,172.21) v1(37.47,42.16) v1(37.85,10.54) v1(38.1,118.87) v1(38.73,99.57) v1(39.12,172.21) v1(39.12,134.87) v1(39.37,109.35) v1(39.37,90.68) v1(39.37,70.87) v1(39.5,142.11) v1(39.5,108.08) v1(39.5,83.69) v1(40.13,67.44) v1(40.26,42.16) v1(40.64,10.54) v1(41.15,88.65) v1(41.4,85.73) v1(41.78,108.84) v1(41.91,129.29) v1(41.91,43.05) v1(42.29,172.21) v1(42.93,96.52) v1(43.18,140.21) v1(43.18,97.66) v1(43.43,10.54) v1(44.32,87.25) v1(44.83,140.84) v1(45.21,129.79) v1(45.34,172.21) v1(45.34,135) v1(45.34,82.17) v1(45.34,16.51) v1(45.47,150.37) v1(45.59,144.15) v1(45.72,108.59) v1(45.97,20.45) v1(46.1,65.15) v1(46.36,27.69) v1(46.48,169.93) v1(46.48,10.54) v1(46.61,93.6) v1(46.99,32.89) v1(47.37,107.06) v1(47.5,116.33) v1(48.01,43.05) v1(48.13,83.31) v1(48.13,38.61) v1(48.26,172.21) v1(48.39,80.77) v1(48.51,91.69) v1(48.64,108.33) v1(48.64,20.45) v1(49.15,119.89) v1(49.15,66.8) v1(49.66,10.54) v1(50.04,16.38) v1(50.42,77.22) v1(50.55,39.62) v1(50.55,30.23) v1(50.67,172.21) v1(50.67,133.35) v1(51.31,141.6) v1(51.31,96.14) v1(51.94,108.2) v1(52.07,123.44) v1(52.45,35.43) v1(52.45,10.54) v1(52.96,128.91) v1(53.21,168.66) v1(53.21,19.94) v1(53.85,172.21) v1(53.98,116.08) v1(54.74,10.54) v1(55.12,109.22) v1(55.12,33.53) v1(55.12,17.53) v1(55.25,145.41) v1(55.88,96.9) v1(56.64,164.08) v1(56.64,135.25) v1(56.77,120.52) v1(56.9,172.21) v1(57.02,10.54) v1(57.4,125.09) v1(57.66,156.08) v1(58.29,164.08) v1(58.42,149.61) v1(58.55,142.75) v1(58.93,24.13) v1(59.05,170.69) v1(59.18,105.66) v1(59.18,93.85) v1(59.56,166.37) v1(59.69,144.4) v1(59.69,96.01) v1(59.82,172.21) v1(59.82,10.54) v1(60.07,29.46) v1(60.2,106.68) v1(61.09,164.72) v1(61.21,130.18) v1(62.1,172.21) v1(62.48,10.54) v1(62.87,141.35) v1(62.99,134.62) v1(63.37,125.09) v1(63.37,33.66) v1(64.01,160.02) v1(64.01,114.05) v1(64.14,106.55) v1(64.9,142.49) v1(65.28,172.21) v1(65.53,105.79) v1(65.66,109.35) v1(65.66,10.54) v1(66.17,96.77) v1(66.67,93.09) v1(66.67,91.57) v1(66.67,90.3) v1(66.67,89.03) v1(67.06,170.31) v1(67.18,24.89) v1(67.31,108.84) v1(67.56,106.3) v1(67.95,136.78) v1(68.07,148.59) v1(68.07,28.19) v1(68.2,121.28) v1(68.33,172.21) v1(68.33,20.7) v1(68.45,10.54) v1(68.83,40.13) v1(69.22,114.17) v1(69.22,109.22) v1(69.22,105.79) v1(69.22,97.03) v1(69.22,84.33) v1(69.47,146.18) v1(69.6,92.84) v1(69.6,33.53) v1(70.61,100.97) v1(70.61,89.92) v1(70.74,125.6) v1(71.12,13.34) v1(71.12,10.54) v1(71.25,172.21) v1(71.25,105.16) v1(71.37,169.8) v1(71.75,109.22) v1(72.26,142.11) v1(72.52,100.46) v1(72.64,88.39) v1(72.64,39.5) v1(73.03,96.01) v1(73.53,130.3) v1(73.91,172.21) v1(73.91,134.62) v1(73.91,109.47) v1(74.17,10.54) v1(74.42,100.84) v1(74.68,26.8) v1(74.68,24.64) v1(75.44,121.67) v1(75.56,124.08) v1(75.69,116.08) v1(76.07,169.04) v1(76.71,34.04) v1(76.84,27.05) v1(77.09,172.21) v1(77.34,150.75) v1(77.34,10.54) v1(77.98,129.67) v1(77.98,96.01) v1(78.11,27.43) v1(78.11,23.37) v1(78.36,76.71) v1(78.87,109.22) v1(80.14,172.21) v1(80.14,10.54) v1(80.39,132.33) v1(80.52,35.69) v1(80.77,40) v1(82.04,100.97) v1(82.55,29.97) v1(82.8,168.53) v1(82.8,10.54) v1(83.06,172.21) v1(83.06,132.84) v1(83.06,114.3) v1(83.31,20.83) v1(84.58,93.85) v1(84.84,76.2) v1(85.47,151.64) v1(85.6,172.21) v1(85.85,10.54) v1(85.98,170.56) v1(86.49,87.12) v1(86.49,42.55) v1(86.87,142.37) v1(86.87,37.34) v1(87.12,29.97) v1(88.77,172.21) v1(88.77,133.86) v1(88.77,121.03) v1(88.77,27.05) v1(89.03,149.61) v1(89.03,10.54) v1(89.15,58.55) v1(89.28,129.29) v1(89.53,68.33) v1(89.66,115.95) v1(89.66,75.18) v1(90.17,134.24) v1(90.17,106.17) v1(90.3,170.18) v1(90.42,143.64) v1(90.42,90.93) v1(90.42,25.78) v1(90.55,96.77) v1(90.55,87.76) v1(90.81,119.13) v1(91.31,146.3) v1(91.44,35.31) v1(91.69,122.68) v1(91.82,172.21) v1(91.82,10.54) v1(93.22,145.92) v1(93.34,137.16) v1(93.47,143.13) v1(93.47,117.6) v1(93.47,114.17) v1(93.6,122.17) v1(93.98,10.54) v1(94.11,30.35) v1(94.36,24.13) v1(94.62,126.75) v1(94.62,43.31) v1(94.74,172.21) v1(95.38,12.19) v1(95.89,14.61) v1(96.14,130.68) v1(96.14,108.71) v1(96.52,10.54) v1(97.28,172.21) v1(97.41,133.6) v1(97.66,170.69) v1(97.92,58.8) v1(98.04,20.07) v1(98.68,31.11) v1(98.81,124.71) v1(98.81,98.68) v1(98.81,10.54) v1(99.7,143.38) v1(99.7,128.02) v1(100.46,172.21) v1(101.47,96.27) v1(101.85,10.54) v1(102.23,49.53) v1(102.23,12.32) v1(102.62,170.05) v1(103.25,121.28) v1(103.38,146.18) v1(103.5,172.21) v1(103.63,22.35) v1(104.27,133.73) v1(104.39,143.38) v1(105.03,10.54) v1(105.41,61.59) v1(105.41,45.21) v1(105.54,32.51) v1(105.66,138.94) v1(105.92,123.06) v1(106.17,43.18) v1(106.43,172.21) v1(106.68,69.85) v1(106.68,45.21) v1(106.68,39.62) v1(106.81,106.17) v1(106.93,113.41) v1(107.06,150.88) v1(107.19,31.37) v1(107.31,34.04) v1(107.44,60.71) v1(107.57,128.27) v1(107.82,139.95) v1(107.82,10.54) v1(107.95,30.48) v1(108.08,75.69) v1(108.46,13.08) v1(108.71,39.62) v1(108.84,134.87) v1(109.22,172.21) v1(109.6,35.94) v1(109.73,46.61) v1(109.98,34.54) v1(110.11,125.73) v1(110.11,116.2) v1(110.11,59.06) v1(110.24,141.99) v1(110.24,112.39) v1(110.24,109.35) v1(110.36,111.25) v1(110.49,10.54) v1(110.74,145.29) v1(111,104.27) v1(111,85.22) v1(111.25,74.93) v1(111.25,68.83) v1(111.25,66.8) v1(111.25,26.42) v1(111.76,51.44) v1(111.89,170.05) v1(111.89,129.41) v1(111.89,65.91) v1(112.14,84.45) v1(112.39,172.21) v1(112.9,132.08) v1(113.16,104.39) v1(113.54,125.22) v1(113.54,10.54) v1(113.67,100.71) v1(113.92,142.75) v1(114.05,112.39) v1(114.05,111) v1(114.17,108.84) v1(114.55,169.29) v1(115.19,138.94) v1(115.44,172.21) v1(115.7,160.27) v1(115.82,99.06) v1(116.08,122.3) v1(116.2,88.52) v1(116.46,118.11) v1(116.71,10.54) v1(116.84,108.84) v1(116.97,112.52) v1(116.97,111.12) v1(117.09,76.2) v1(117.48,101.09) v1(117.48,71.25) v1(117.6,104.27) v1(117.86,137.29) v1(117.86,131.57) v1(117.98,65.28) v1(117.98,45.72) v1(118.36,172.21) v1(118.49,66.17) v1(118.75,83.82) v1(118.75,79.25) v1(118.87,72.77) v1(118.87,29.34) v1(119.25,82.04) v1(119.51,26.16) v1(119.51,10.54) v1(119.63,141.6) v1(119.76,104.27) v1(120.02,86.74) v1(120.02,27.3) v1(120.14,52.83) v1(120.14,46.23) v1(120.14,33.78) v1(120.14,32.51) v1(120.65,112.52) v1(120.65,111.25) v1(120.65,108.84) v1(120.78,69.22) v1(121.16,172.21) v1(121.28,88.77) v1(121.54,124.08) v1(122.17,116.08) v1(122.3,10.54) v1(123.44,138.05) v1(124.33,172.21) v1(124.33,146.56) v1(124.33,125.6) v1(124.46,131.95) v1(124.59,127.76) v1(124.84,78.99) v1(124.84,52.96) v1(124.84,28.96) v1(124.97,100.71) v1(125.09,108.59) v1(125.22,88.77) v1(125.35,10.54) v1(125.48,169.93) v1(126.49,57.78) v1(126.62,143.89) v1(127.25,127.38) v1(127.38,172.21) v1(127.38,137.03) v1(127.64,132.72) v1(127.89,30.23) v1(128.52,10.54) v1(128.78,164.59) v1(128.78,149.73) v1(128.91,155.83) v1(128.91,94.87) v1(129.67,152.53) v1(129.79,168.4) v1(129.92,105.66) v1(130.17,145.03) v1(130.3,172.21) v1(130.3,27.94) v1(130.68,140.97) v1(130.81,153.67) v1(130.81,98.04) v1(131.32,10.54) v1(131.57,32.89) v1(131.7,165.48) v1(131.83,84.58) v1(132.59,145.16) v1(132.72,172.21) v1(132.97,17.91) v1(133.86,89.15) v1(134.37,80.01) v1(134.62,44.83) v1(134.75,25.78) v1(134.75,10.54) v1(134.87,145.29) v1(135,84.84) v1(135.13,169.8) v1(135.25,108.2) v1(135.25,106.93) v1(135.38,29.08) v1(135.51,141.1) v1(135.64,71.25) v1(135.76,100.97) v1(135.76,68.2) v1(135.89,172.21) v1(136.78,132.46) v1(137.03,139.45) v1(137.41,145.92) v1(137.41,80.39) v1(137.41,10.54) v1(137.54,58.29) v1(137.8,108.33) v1(137.8,22.1) v1(137.92,106.93) v1(138.43,148.72) v1(138.43,31.62) v1(138.56,159.77) v1(138.56,50.17) v1(138.94,172.21) v1(138.94,25.65) v1(139.06,59.06) v1(139.32,159.77) v1(139.45,55.12) v1(139.57,109.98) v1(139.83,42.93) v1(140.21,159.77) v1(140.21,57.91) v1(140.34,169.8) v1(140.46,10.54) v1(140.72,74.3) v1(140.84,94.62) v1(141.22,113.67) v1(141.22,112.27) v1(141.22,110.36) v1(141.6,19.3) v1(141.86,172.21) v1(141.86,105.03) v1(142.49,123.19) v1(142.88,141.35) v1(143,104.65) v1(143.26,28.19) v1(143.38,148.72) v1(143.51,56.01) v1(143.64,85.85) v1(143.64,10.54) v1(143.89,77.47) v1(143.89,49.91) v1(144.27,91.19) v1(144.4,172.21) v1(144.53,17.14) v1(144.65,147.57) v1(144.65,44.32) v1(144.78,169.42) v1(144.91,110.36) v1(145.03,113.79) v1(145.03,112.01) v1(145.16,141.48) v1(145.54,63.12) v1(145.54,32.51) v1(145.54,21.72) v1(145.8,70.99) v1(146.18,52.96) v1(146.3,59.06) v1(146.43,10.54) v1(146.56,165.74) v1(146.69,65.91) v1(146.81,27.05) v1(147.07,64.52) v1(147.07,63.63) v1(147.32,74.3) v1(147.57,172.21) v1(147.7,12.57) v1(147.96,69.34) v1(147.96,67.44) v1(148.59,150.75) v1(148.59,141.73) v1(148.72,108.2) v1(148.72,106.93) v1(148.84,90.81) v1(148.84,38.48) v1(149.22,10.54) v1(150.37,15.88) v1(150.5,106.93) v1(150.62,172.21) v1(150.75,115.7) v1(150.75,113.92) v1(150.75,112.9) v1(150.88,94.11) v1(151.13,16.76) v1(151.38,169.04) v1(151.38,40.64) v1(151.38,38.61) v1(151.64,108.2) v1(151.64,27.69) v1(151.64,21.72) v1(151.77,36.45) v1(152.02,131.06) v1(152.27,10.54) v1(152.4,122.43) v1(152.4,80.39) v1(153.03,165.99) v1(153.16,83.95) v1(153.16,40.26) v1(153.42,46.61) v1(153.54,172.21) v1(153.54,108.08) v1(153.54,66.17) v1(153.67,37.97) v1(153.92,105.28) v1(153.92,82.04) v1(154.56,137.29) v1(154.81,115.44) v1(154.81,113.79) v1(154.81,38.86) v1(155.19,12.19) v1(155.45,10.54) v1(156.08,172.21) v1(156.21,168.78) v1(156.21,150.75) v1(156.21,144.02) v1(156.21,37.08) v1(156.46,14.73) v1(157.23,61.85) v1(157.35,40.89) v1(157.86,164.72) v1(158.24,132.21) v1(158.24,10.54) v1(158.88,154.31) v1(159,108.33) v1(159.13,116.08) v1(159.26,172.21) v1(159.26,62.87) v1(159.38,159.13) v1(160.4,12.57) v1(160.78,150.5) v1(161.04,162.56) v1(161.16,168.53) v1(161.16,10.54) v1(161.42,138.68) v1(161.54,158.62) v1(162.31,172.21) v1(162.31,127) v1(162.56,40.89) v1(163.32,56.9) v1(163.7,152.02) v1(163.83,10.54) v1(164.72,131.7) v1(164.72,114.68) v1(164.72,37.21) v1(165.23,172.21) v1(165.23,163.83) v1(165.35,120.14) v1(166.37,155.7) v1(166.37,139.95) v1(166.62,23.11) v1(166.88,116.08) v1(166.88,10.54) v1(167,168.66) v1(167,62.36) v1(167.51,107.95) v1(167.51,32.39) v1(167.77,172.21) v1(168.15,63.37) v1(168.28,38.23) v1(168.66,41.4) v1(169.16,12.45) v1(169.67,164.47) v1(169.8,106.05) v1(170.05,128.27) v1(170.05,10.54) v1(170.43,42.93) v1(170.56,14.22) v1(170.81,24.26) v1(170.94,172.21) v1(171.32,75.69) v1(171.96,168.78) v1(172.72,63.88) v1(172.72,32.51) v1(172.85,10.54) v1(172.97,132.21) v1(172.97,102.62) v1(173.1,108.33) v1(173.99,172.21) v1(173.99,116.08) v1(174.12,50.42) v1(174.62,75.69) v1(174.88,61.59) v1(175.13,151.89) v1(175.26,124.08) v1(175.39,73.15) v1(175.39,43.94) v1(175.64,10.54) v1(175.77,34.16) v1(176.15,59.94) v1(176.28,99.31) v1(176.53,131.83) v1(176.66,53.59) v1(176.91,172.21) v1(177.16,125.6) v1(177.29,41.4) v1(177.42,39.37) v1(177.55,54.1) v1(177.67,116.46) v1(177.67,42.67) v1(177.8,162.69) v1(177.8,120.9) v1(177.8,99.19) v1(177.93,166.75) v1(178.05,82.93) v1(178.31,90.17) v1(178.44,43.31) v1(178.56,170.43) v1(178.56,19.18) v1(178.69,10.54) v1(178.94,150.75) v1(178.94,97.28) v1(178.94,54.23) v1(179.45,43.43) v1(179.58,88.14) v1(179.71,172.21) v1(179.71,34.42) v1(179.96,40.64) v1(180.72,38.35) v1(181.1,94.49) v1(181.23,169.04) v1(181.48,111.76) v1(181.48,55.63) v1(181.61,29.46) v1(181.86,166.75) v1(181.86,10.54) v1(182.25,42.29) v1(182.37,50.55) v1(182.5,160.27) v1(182.75,106.68) v1(182.75,90.04) v1(182.88,172.21) v1(183.39,52.07) v1(183.9,94.74) v1(184.02,131.57) v1(184.66,166.75) v1(184.66,10.54) v1(184.91,22.61) v1(185.17,41.28) v1(185.17,18.67) v1(185.55,110.36) v1(185.55,38.23) v1(185.67,95.63) v1(185.93,172.21) v1(185.93,147.57) v1(186.56,85.47) v1(187.07,170.56) v1(187.07,14.22) v1(187.45,31.75) v1(187.96,94.62) v1(187.96,12.32) v1(187.96,10.54) v1(188.09,51.82) v1(188.34,146.56) v1(188.34,38.23) v1(188.47,53.98) v1(188.85,172.21) v1(189.48,85.34) v1(189.74,114.43) v1(189.87,33.27) v1(189.99,168.4) v1(189.99,165.74) v1(190.12,121.92) v1(190.25,99.95) v1(190.63,10.29) v1(191.26,44.83) v1(191.52,48.13) v1(191.64,98.68) v1(191.77,172.21) v1(192.15,130.68) v1(192.28,18.16) v1(192.53,31.11) v1(192.66,140.97) v1(193.04,123.44) v1(193.17,111.89) v1(193.29,49.53) v1(193.29,10.29) v1(193.42,100.58) v1(193.68,139.06) v1(193.93,170.31) v1(194.06,22.86) v1(194.18,28.57) v1(194.31,166.24) v1(194.56,50.93) v1(194.69,48.89) v1(194.82,53.59) v1(194.94,172.21) v1(195.33,49.78) v1(195.45,97.54) v1(195.83,12.83) v1(196.09,160.27) v1(196.22,127.51) v1(196.22,102.74) v1(196.34,124.46) v1(196.34,107.19) v1(196.34,10.29) v1(196.47,141.35) v1(196.47,49.66) v1(197.61,93.34) v1(197.87,48.13) v1(197.99,172.21) v1(198.12,109.35) v1(198.12,64.39) v1(198.25,163.83) v1(198.63,157.35) v1(199.01,124.33) v1(199.26,114.55) v1(199.26,50.17) v1(199.39,168.15) v1(199.39,112.27) v1(199.52,10.29) v1(199.64,36.96) v1(199.9,97.41) v1(200.03,87.12) v1(200.28,51.82) v1(200.79,15.62) v1(200.91,172.21) v1(200.91,88.9) v1(201.3,50.55) v1(201.42,85.6) v1(201.93,10.41) v1(202.06,78.87) v1(203.45,170.31) v1(203.45,124.84) v1(203.71,73.28) v1(203.96,172.21) v1(204.22,54.1) v1(204.6,105.16) v1(204.6,10.41) v1(204.72,137.92) v1(204.85,163.96) v1(204.85,97.16) v1(205.1,50.67) v1(205.23,157.23) v1(205.23,131.7) v1(205.36,108.08) v1(205.36,80.01) v1(205.49,113.92) v1(205.74,72.01) v1(205.87,168.28) v1(205.87,118.24) v1(206.12,52.58) v1(206.38,49.28) v1(206.38,30.23) v1(206.5,56.01) v1(206.63,33.53) v1(207.01,149.1) v1(207.14,172.21) v1(207.39,46.86) v1(207.52,94.87) v1(207.52,17.4) v1(207.65,77.47) v1(207.65,27.69) v1(207.65,10.41) v1(207.77,81.15) v1(207.9,91.31) v1(207.9,82.8) v1(208.03,58.17) v1(208.03,22.1) v1(208.15,160.27) v1(208.28,130.18) v1(208.28,79.38) v1(208.28,68.83) v1(208.28,49.02) v1(208.41,141.35) v1(208.41,51.69) v1(208.41,28.96) v1(208.41,25.91) v1(208.53,74.68) v1(208.53,46.74) v1(208.66,125.86) v1(208.66,88.77) v1(208.66,33.91) v1(208.66,32.77) v1(208.91,23.88) v1(209.3,136.02) v1(209.8,154.05) v1(209.93,144.65) v1(210.19,172.21) v1(210.57,157.73) v1(210.57,139.19) v1(210.57,93.98) v1(210.57,83.31) v1(210.82,164.47) v1(210.82,10.41) v1(210.95,116.59) v1(210.95,104.14) v1(211.07,148.59) v1(211.2,108.59) v1(211.2,98.3) v1(211.2,17.91) v1(211.46,90.68) v1(211.46,23.75) v1(211.71,106.17) v1(212.22,85.98) v1(213.11,172.21) v1(213.61,10.41) v1(214,170.31) v1(214,167.13) v1(214,164.08) v1(214,161.16) v1(214,158.88) v1(214,155.7) v1(214,152.65) v1(214,149.73) v1(214,147.32) v1(214,144.4) v1(214,138.68) v1(214,135.76) v1(214,133.35) v1(214,130.43) v1(214,122.81) v1(214,119.63) v1(214,116.59) v1(214,113.67) v1(214,110.87) v1(214,107.7) v1(214,104.65) v1(214,101.73) v1(214,99.19) v1(214,96.01) v1(214,92.96) v1(214,90.04) v1(214,87.88) v1(214,84.71) v1(214,82.8) v1(214,23.75) v1(214,21.84) v1(214,19.56) v1(214,16.38) v1(214,13.59) v2(5.63,24.68) v2(15.62,147.07) v2(16.51,147.07) v2(17.4,147.07) v2(17.4,146.18) v2(17.4,145.29) v2(26.92,147.07) v2(27.81,147.07) v2(28.7,147.07) v2(28.7,146.18) v2(29.08,107.19) v2(43.18,122.68) v2(43.18,121.41) v2(44.32,123.95) v2(44.32,122.68) v2(44.32,121.41) v2(44.32,120.02) v2(45.59,123.95) v2(45.59,122.68) v2(45.59,121.41) v2(45.59,120.02) v2(46.86,123.95) v2(46.86,122.68) v2(46.86,121.41) v2(46.86,120.02) v2(50.55,161.8) v2(50.55,160.91) v2(50.55,160.02) v2(50.55,159) v2(50.55,157.99) v2(51.44,117.6) v2(52.32,161.8) v2(52.32,160.91) v2(52.32,160.02) v2(52.32,159) v2(54.48,160.91) v2(54.48,160.02) v2(54.48,159) v2(54.48,157.99) v2(64.77,147.07) v2(64.77,146.18) v2(65.66,147.07) v2(66.55,147.07) v2(66.55,146.18) v2(67.18,159.77) v2(68.07,159.77) v2(68.96,159.77) v2(86.49,147.19) v2(87.5,147.19) v2(88.39,147.19) v2(88.39,146.3) v2(95.63,147.19) v2(96.52,147.19) v2(97.41,147.19) v2(97.41,146.3) v2(98.04,111) v2(101.47,99.7) v2(118.49,119.76) v2(121.54,162.18) v2(121.54,161.29) v2(121.54,160.4) v2(121.54,159.38) v2(121.54,158.37) v2(121.54,157.35) v2(122.68,162.18) v2(122.68,161.29) v2(122.68,160.4) v2(122.68,159.38) v2(122.68,158.37) v2(124.84,162.18) v2(124.84,161.29) v2(124.84,160.4) v2(124.84,159.38) v2(124.84,158.37) v2(124.84,157.35) v2(125.86,162.18) v2(125.86,161.29) v2(125.86,160.4) v2(125.86,159.38) v2(125.86,158.37) v2(125.86,157.35) v2(131.32,119.63) v2(131.32,118.62) v2(132.21,116.97) v2(133.1,119.76) v2(133.1,118.75) v2(140.08,147.07) v2(140.97,147.07) v2(141.86,147.07) v2(141.86,146.18) v2(141.86,145.29) v2(146.43,119.38) v2(147.07,119.63) v2(154.18,19.68) v2(154.18,18.67) v2(158.88,113.03) v2(159.77,113.03) v2(160.4,146.94) v2(160.4,145.67) v2(160.4,144.4) v2(160.4,143.13) v2(160.66,113.03) v2(160.66,112.14) v2(161.04,69.85) v2(161.04,68.83) v2(161.04,66.67) v2(161.04,65.79) v2(161.67,147.19) v2(161.67,142.49) v2(162.31,69.85) v2(162.31,68.83) v2(162.31,66.8) v2(162.31,65.79) v2(163.07,52.96) v2(163.07,52.07) v2(163.07,51.18) v2(163.45,69.85) v2(163.45,68.83) v2(163.45,66.8) v2(163.45,65.79) v2(164.59,69.85) v2(164.59,68.83) v2(164.59,67.82) v2(164.59,66.8) v2(164.59,65.79) v2(165.61,69.85) v2(165.61,68.83) v2(165.61,67.82) v2(165.61,66.8) v2(165.61,65.79) v2(166.5,113.03) v2(167.39,113.03) v2(168.28,113.03) v2(168.28,112.14) v2(169.55,45.85) v2(172.85,113.03) v2(173.74,113.03) v2(174.62,113.03) v2(174.62,112.14) v2(184.78,161.04) v2(185.29,126.37) v2(186.31,156.97) v2(186.56,126.37) v2(187.71,126.37) v2(188.98,126.37) v2(190.25,126.37) v2(191.26,152.02) v2(192.28,152.02) v2(192.28,149.99) v2(193.29,152.02) v2(193.29,151) v2(193.29,149.99) v2(203.33,37.85) v2(204.72,142.37) v2(206.25,36.19) v3(26.54,137.41) v3(26.54,134.62) v3(26.54,132.21) v3(26.54,112.27) v3(26.54,109.22) v3(26.54,106.93) v3(26.67,124.84) v3(26.67,122.17) v3(26.67,119.89) v3(28.45,99.44) v3(33.02,99.7) v3(34.29,138.94) v3(36.7,138.94) v3(39.5,138.94) v3(43.05,98.42) v3(47.24,138.94) v3(50.04,138.94) v3(52.45,138.94) v3(53.34,98.3) v3(55.75,99.06) v3(59.94,138.94) v3(62.48,138.94) v3(65.02,138.94) v3(72.64,138.94) v3(75.06,138.94) v3(77.6,138.94) v3(85.34,138.94) v3(88.01,138.94) v3(90.42,138.94) v3(95.25,98.81) v3(97.92,138.94) v3(100.58,138.94) v3(104.78,127.25) v3(104.78,118.49) v3(104.78,115.32) v3(104.78,105.92) v3(104.78,100.71) v3(104.9,131.32) v3(109.47,40) v3(109.73,94.11) v3(109.86,81.41) v3(110.11,78.61) v3(110.36,27.3) v3(110.62,15.88) v3(117.35,17.02) v3(118.24,94.87) v3(120.78,94.87) v3(122.68,94.87) v3(124.46,16.64) v3(127,16.64) v3(129.41,16.64) v3(131.06,94.87) v3(133.35,94.87) v3(135.38,94.87) v3(136.78,16.64) v3(137.92,16.64) v3(142.37,16.64) v3(143.13,94.87) v3(146.05,94.87) v3(148.46,94.87) v3(149.35,71.25) v3(149.73,61.59) v3(149.73,23.24) v3(149.86,86.74) v3(149.86,84.58) v3(149.86,82.04) v3(149.86,46.36) v3(149.86,43.43) v3(149.99,36.07) v3(149.99,33.66) v3(149.99,30.99) v4(86.63,128.77) v4(88.13,128.77) v4(88.13,127.77) v4(158.89,32.25) v4(158.89,31.25) v4(160.39,32.25)
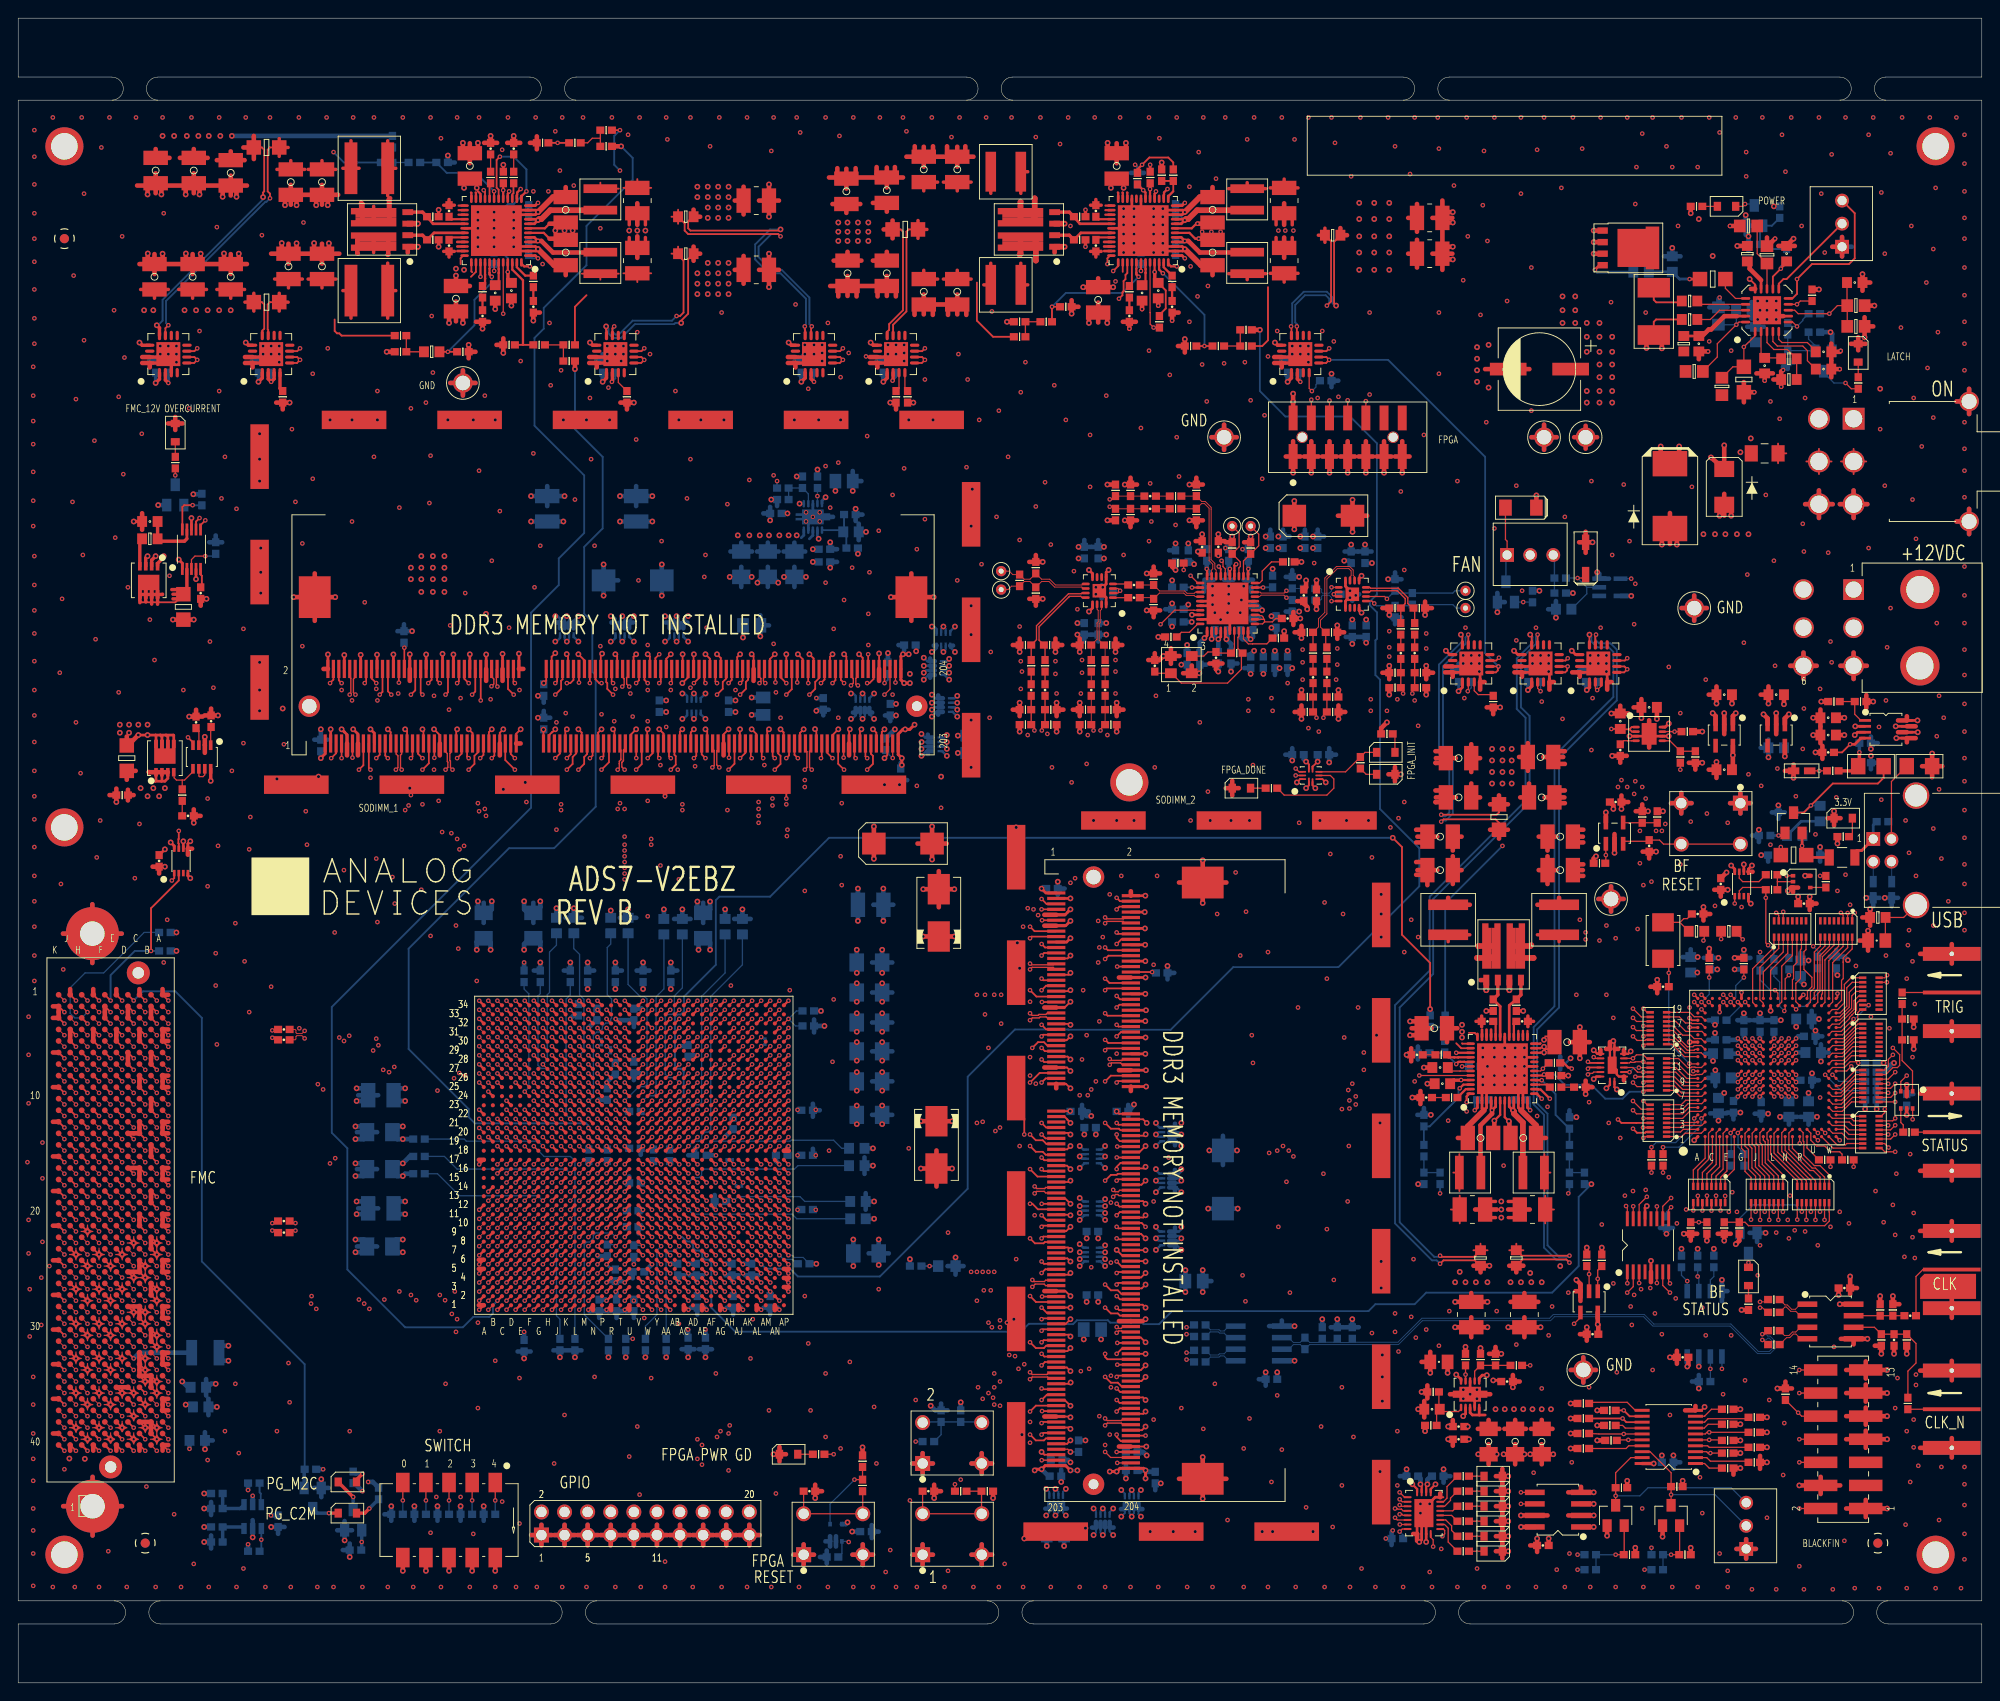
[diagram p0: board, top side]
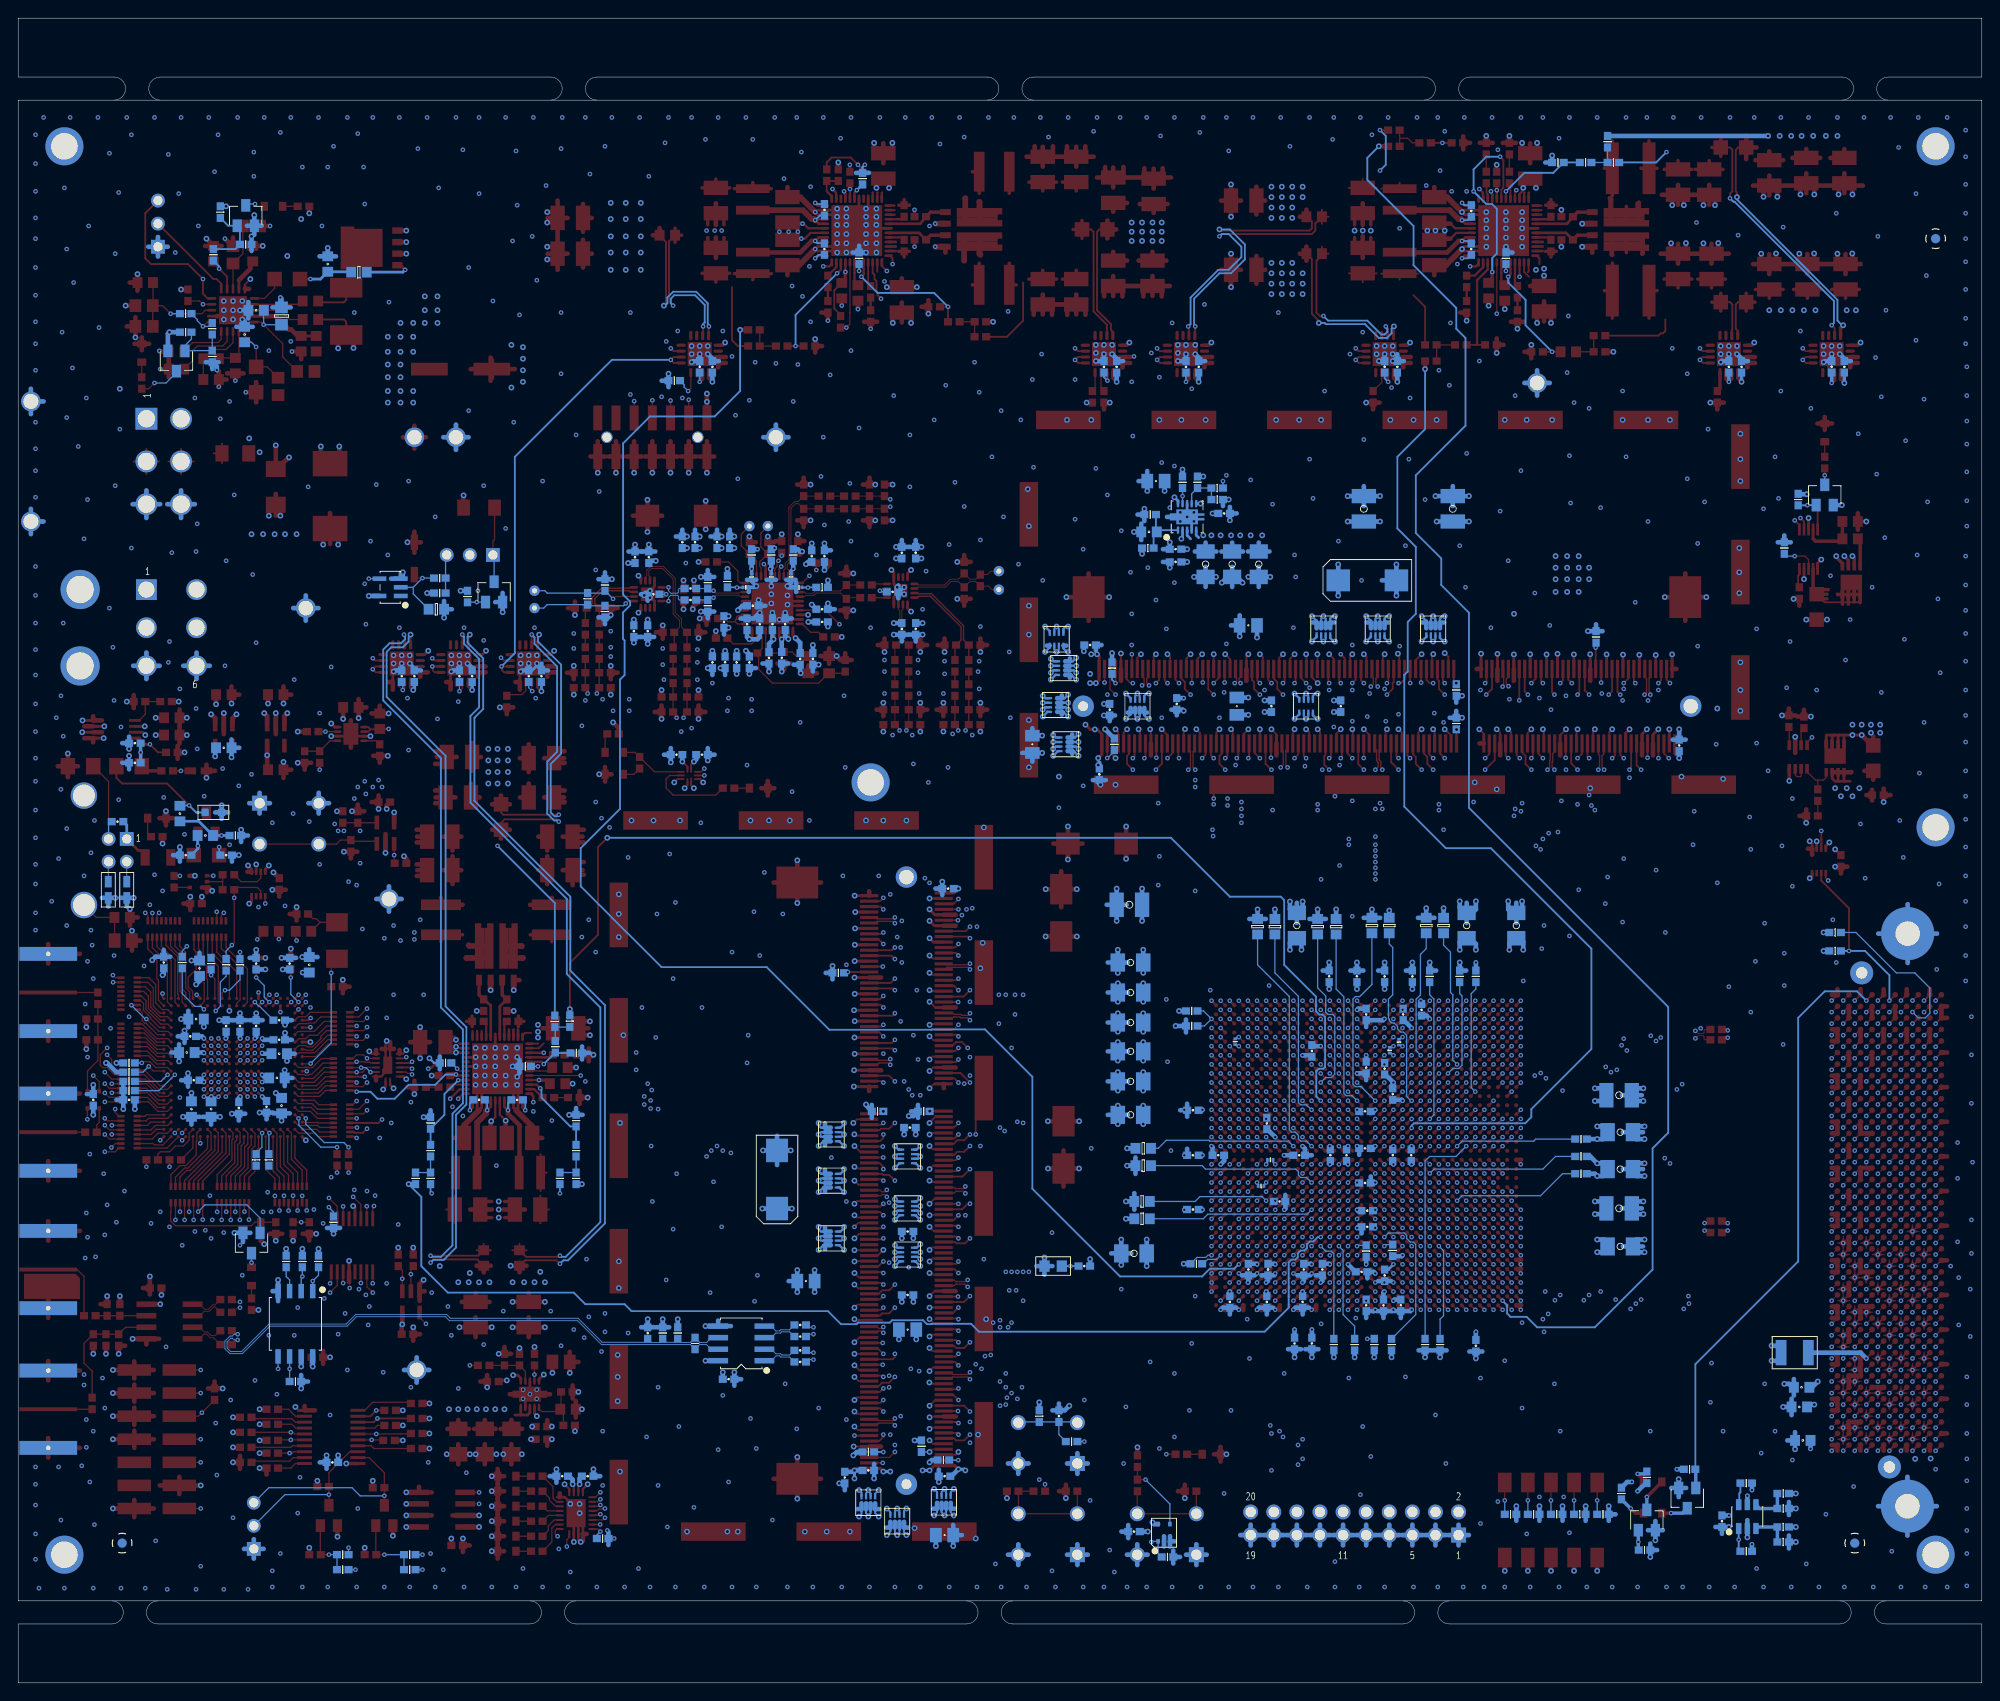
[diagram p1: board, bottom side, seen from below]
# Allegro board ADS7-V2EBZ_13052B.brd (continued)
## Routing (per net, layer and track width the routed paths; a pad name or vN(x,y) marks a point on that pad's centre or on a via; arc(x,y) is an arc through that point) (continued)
VCC1V5: length 218.1
  TOP w0.203: P5.75 115.04,62.3 115.37,61.97 115.37,61.92 v2(115.7,61.59) ; P6.82 60.46,113.03 v2(60.31,113.17) ; P6.75 58.35,104.25 58.68,104.57 58.73,104.57 v2(59.05,104.9) ; v2(69.22,104.9) 69.16,104.84 P6.111 ; P5.117 115.23,49.7 v2(115.7,50.17) ; v2(71.75,113.16) 71.25,112.66 P6.118 ; v1(68.69,72.04) U31.V31 ; v2(61.59,104.9) 61.95,104.54 P6.87 ; P5.99 115.55,55.09 v2(115.7,55.25) ; v2(123.97,60.34) 123.82,60.19 P5.82 ; P5.105 115.11,53.3 v2(115.7,52.7) ; v2(60.33,104.9) 60.16,104.73 P6.81 ; v2(115.7,59.06) 115.34,58.7 P5.87 ; P6.94 64.05,113.08 v2(64.2,113.22) ; v2(123.95,51.44) 123.71,51.19 P5.112 ; P5.93 115.32,56.89 v2(115.7,56.52) ; P6.105 67.35,104.31 v2(67.95,104.9) ; P6.93 63.76,104.52 v2(64.14,104.9) ; P5.106 123.66,53 v2(123.95,52.7) ; v2(115.7,60.33) 115.53,60.49 P5.81 ; v2(115.7,51.44) 115.64,51.49 P5.111 ; v2(123.95,48.89) 123.45,49.4 P5.118 ; P6.88 62.25,112.5 v2(61.59,113.16) ; v1(79.69,59.04) U31.AJ18 ; P6.123 72.75,104.63 v2(73.03,104.9) ; P6.76 58.65,112.88 v2(59.05,113.28) ; v2(123.95,59.06) 123.29,58.4 P5.88 ; P6.117 70.95,104.43 v2(70.48,104.9) ; v1(66.69,75.04) U31.U34 ; v2(123.95,55.25) 123.5,54.79 P5.100 ; P6.124 v2(73.05,113.16) ; P6.99 65.56,104.75 v2(65.41,104.9) ; v2(67.95,113.16) 67.65,112.87 P6.106 ; v2(124.08,61.59) 123.68,62 P5.76 ; v2(69.22,113.16) 69.46,112.92 P6.112 ; U7.12 95.54,148.63 95.76,148.84 95.76,149.48 97.28,151 97.28,159.64 97.03,159.89 R13.2 ; v2(115.7,47.62) 115.43,47.9 P5.123 ; P5.94 123.78,56.6 v2(123.95,56.77) ; P5.124 v2(123.95,47.6) ; P6.100 65.86,112.96 v2(65.66,113.16) ; v1(66.69,65.04) U31.U24
  TOP w0.254: v1(71.69,73.04) U31.AA32 ; v1(61.69,70.04) U31.M29 ; v1(78.69,51.04) U31.AH11 ; v1(60.69,73.04) U31.L32 ; v1(72.69,70.04) U31.AB29 ; v1(69.69,69.04) U31.W28 ; v1(83.69,56.04) U31.AN16 ; v1(81.69,63.04) U31.AL22 ; v1(79.69,48.04) U31.AJ8 ; v1(58.69,69.04) U31.J28 ; v1(80.69,55.04) U31.AK15 ; v1(75.69,50.04) U31.AE10 ; v1(64.69,71.04) U31.R30 ; v1(56.69,75.04) U31.G34 ; v1(80.69,66.04) U31.AK25 ; v1(57.69,72.04) U31.H31 ; v1(62.69,67.04) U31.N26 ; v1(59.69,66.04) U31.K25 ; v1(65.69,68.04) U31.T27 ; v1(82.69,49.04) U31.AM9 ; v1(75.69,61.04) U31.AE20 ; v1(70.69,66.04) U31.Y25 ; v1(84.69,53.04) U31.AP13 ; v1(60.69,63.04) U31.L22 ; v1(73.69,56.04) U31.AC16 ; v1(63.69,74.04) U31.P33 ; v1(63.69,64.04) U31.P23 ; v1(78.69,62.04) U31.AH21 ; v1(82.69,60.04) U31.AM19 ; v1(77.69,54.04) U31.AG14 ; v1(76.69,57.04) U31.AF17 ; v1(84.69,64.04) U31.AP23 ; v1(74.69,53.04) U31.AD13 ; v1(81.69,52.04) U31.AL12
  TOP w0.305: U35.2 159.14,29.6 v2(158.88,29.34)
  TOP w0.381: U7.13 94.02,147.15 v2(93.73,147.45)
  TOP w0.508: 95.16,159.89 R13.2 ; R13.2 96.14,160.87 ; R13.2 96.14,158.91 ; R106.2 v2(145.16,109.22) ; R109.2 v2(154.81,108.71) ; C137.2 v2(159.51,26.8) ; R108.2 v2(150.75,108.71) ; C40.1 91.19,157.43 ; C40.1 92.71,156.46 ; C40.1 89.66,156.46 ; R177.1 v2(154.69,27.69) ; 93.98,156.46 C41.1 95.5,157.43 ; 116.71,105.41 v2(116.71,104.65) ; 93.98,162.81 95.5,162.81 95.5,161.85 ; 110.11,105.41 v2(110.11,104.65) ; C16.1 92.58,162.69 ; C16.1 91.06,161.72 ; C16.1 89.53,162.69 ; R104.2 v2(141.1,109.22) ; C136.2 v2(159.38,28.19) ; R117.2 v2(120.78,104.65) ; R115.2 v2(114.17,104.65) ; R22.1 v2(108.71,149.73)
  BOTTOM w0.203: CN3.6 66.67,114.8 v2(66.42,114.55) 66.17,114.8 CN3.7 ; CN11.7 125.34,60.57 v2(125.09,60.33) 125.34,60.08 CN11.6 ; CN6.2 119.26,58.16 v2(119.51,57.91) ; CN13.7 125.34,55.49 v2(125.09,55.25) 125.34,55 CN13.6 ; CN5.3 74.54,108.59 v2(74.3,108.84) 74.05,108.59 CN5.2 ; CN4.6 72.64,114.8 v2(72.39,114.55) 72.14,114.8 CN4.7 ; CN12.7 60.08,114.8 v2(60.33,114.55) 60.57,114.8 CN12.6 ; CN15.3 93.09,108.59 v2(92.84,108.84) 92.59,108.59 CN15.2 ; CN17.3 101.98,115.96 v2(101.73,116.2) 101.48,115.96 CN17.2 ; CN14.6 125.34,48.65 v2(125.09,48.89) 125.34,49.14 CN14.7
  BOTTOM w0.254: CN18.2 v2(119.5,52.45) ; CN3.5 67.17,115.07 v2(67.69,114.55) ; v2(94.11,108.84) 93.59,108.32 CN15.4 ; v2(119.51,53.21) 119.24,52.95 CN18.1 ; v2(73.66,114.55) 73.14,115.07 CN4.5 ; CN17.4 102.48,115.69 v2(103,116.2) ; v2(119.51,56.64) 118.99,57.16 CN6.4 ; CN16.3 119.25,46.87 v2(119.51,46.61) ; v2(119.51,48.13) 119.24,47.87 CN16.1 ; CN4.8 71.64,114.95 71.25,114.55 v2(71.12,114.55) ; CN15.1 92.09,108.57 91.82,108.84 v2(91.57,108.84) ; CN13.8 125.49,56 125.09,56.39 v2(125.09,56.52) ; v2(119.51,51.69) 119.25,51.95 CN18.3 ; CN16.2 v2(119.5,47.37) ; v2(119.51,59.06) 119.11,58.66 CN6.1 ; CN12.8 59.57,114.95 59.18,114.55 v2(59.05,114.55) ; v2(125.09,53.98) 125.61,54.49 CN13.5 ; CN6.3 119.26,57.66 v2(119.51,57.91) ; CN17.1 100.98,115.94 100.71,116.2 v2(100.46,116.2) ; v2(73.03,108.84) 73.28,108.84 73.54,108.57 CN5.1 ; v2(119.51,50.93) 118.99,51.45 CN18.4 ; CN14.5 125.61,48.14 v2(125.09,47.62) ; CN12.5 61.08,115.07 v2(61.59,114.55) ; v2(75.56,108.84) 75.05,108.32 CN5.4 ; v2(125.09,50.17) 125.09,50.04 125.49,49.65 CN14.8 ; CN16.4 118.99,46.37 v2(119.51,45.85) ; CN11.5 125.61,59.57 v2(125.09,59.06) ; CN3.8 65.67,114.95 65.28,114.55 v2(65.15,114.55) ; CN11.8 125.49,61.08 125.09,61.47 v2(125.09,61.59)
  BOTTOM w0.305: v2(88.01,125.86) 87.88,125.99 U39.2
  BOTTOM w0.508: v1(63.69,64.04) 63.79,64.14 C288.2 ; R316.1 123.65,25.4 123.75,25.3 123.8,25.3 v2(124.08,25.02) ; R298.2 v2(94.11,51.05) ; v1(63.69,74.04) 63.69,74.1 C264.2 ; C205.2 v2(79.69,115) ; v2(70.76,119.61) C186.P v2(70.76,123.04) ; v2(134.09,52.17) C291.P v2(130.84,52.17) ; v1(78.69,62.04) 78.69,62.1 C286.2 ; v2(74.8,80.64) 74.8,81.41 C241.2 75.56,81.92 76.07,81.41 v2(76.07,80.64) ; v2(128.33,42.99) C318.2 v2(128.33,45.4) ; R240.1 v2(95.63,113.28) ; C221.1 v2(96.52,107.7) ; 118.49,61.09 v2(118.49,60.33) ; C181.2 v2(87.38,124.71) ; C225.1 v2(71.25,108.08) ; v2(91.82,45.85) C309.2 v2(91.82,48.77) ; C302.1 v2(118.75,48.89) ; C331.1 v2(119.06,37.78) ; v1(60.69,73.04) 61.06,73.41 C265.2 ; C224.1 v2(78.87,108.08) ; C319.1 v2(118.75,41.91) ; v1(72.69,70.04) 73.54,70.04 C272.2 ; v2(92.2,74.93) C250.2 v2(92.2,76.96) ; v2(92.2,68.45) C270.2 v2(92.2,70.48) ; R249.2 v2(77.72,85.09) ; C223.1 v2(80.64,106.49) ; v2(92.2,63.5) C284.2 v2(92.2,61.47) ; R253.2 v2(65.15,84.96) ; v2(55.63,80.64) 55.63,81.28 56.26,81.92 C242.2 57.02,81.92 57.4,81.53 v2(57.4,80.64) ; R292.2 v2(93.98,58.8) ; R251.2 v2(70.99,85.09) ; R232.1 v2(92.33,124.21) ; C182.2 v2(87.38,123.32) ; R255.2 v2(59.18,85.22)
  vias: v1(84.45,96.65) v2(90.17,160.66) v2(90.17,159.64) v2(90.17,158.62) v2(91.19,160.66) v2(91.19,159.64) v2(91.19,158.62) v2(92.33,160.66) v2(92.33,159.64) v2(92.33,158.62) v2(93.47,160.66) v2(93.47,159.64) v2(93.47,158.62)
VCC3V3: length 235.4
  TOP w0.203: P5.199 112.83,25.09 v2(112.52,25.4) ; U22.6 142.31,100.78 v2(142.88,101.35) ; 160.74,45.89 160.15,46.48 156.72,46.48 v1(156.34,46.1) ; U15.12 166.41,115.15 v2(166.24,115.32) ; v1(132,122.81) 131.95,122.81 132.22,122.54 U12.27 ; U29.A16 183.79,72.09 v1(183.77,72.12) ; v2(95.25,101.73) 95.56,102.03 P6.199
  TOP w0.254: U12.24 133.72,122.33 133.73,122.34 133.73,122.93 133.86,123.06 133.99,123.06 133.99,123.06 v1(133.92,123.06) ; v2(155.83,21.84) 155.31,21.32 U37.23 ; U37.24 154.81,21.71 v2(154.94,21.84) ; v2(174.62,65.41) 175.01,65.79 U28.16 ; U12.14 v2(136.77,117.99)
  TOP w0.305: v2(147.7,117.73) 147.44,117.99 U13.8 ; U11.13 118.12,118.25 v2(117.73,117.86) ; v2(135.51,114.81) 135.22,115.1 U12.10 ; U14.1 158.79,109.51 v2(158.37,109.09) ; U29.D19 187.08,73.79 v1(187.07,73.79) ; U11.8 118.12,122.04 v2(117.73,122.43) ; v2(132.84,114.81) 132.72,114.93 U12.5 ; v2(181.48,105.54) 181.09,105.14 U18.8 ; U12.1 130.72,115.23 v2(130.43,114.94) ; v2(164.47,113.54) 164.89,113.12 U15.13 ; U21.2 v2(201.99,105.23) ; v2(131.95,114.81) 132.22,115.07 U12.4 ; U29.G20 v1(189.48,75.95) ; v2(158.12,33.91) 158.64,33.38 U35.10 ; U13.13 147.44,121.53 v2(147.7,121.79) ; U12.38 v2(129.05,117.5) ; U12.2 v2(131.22,114.84)
  TOP w0.381: U8.1 139.99,143.55 v2(139.57,143.13) ; U7.1 95.54,143.55 v2(95.12,143.13) ; v2(26.42,143.13) 26.84,143.55 U4.1 ; v2(172.47,109.22) 172.76,109.51 U16.1 ; v2(64.26,143.13) 64.68,143.55 U5.1 ; v2(15.11,143) 15.53,143.42 U3.1 ; v2(86.11,143.13) 86.53,143.55 U6.1 ; v2(165.99,109.22) 166.41,109.64 U15.1 ; U36.20 v2(179.83,24.13)
  TOP w0.508: U33.8 v2(200.28,41.66) ; R119.2 149.86,105.03 v2(150.5,105.66) ; U38.3 v2(173.23,19.68) ; R180.2 v2(170.69,25.78) ; v2(175.39,96.14) 175.39,96.52 C95.1 ; R132.2 v2(200.03,92.33) ; R157.2 160.01,45.89 ; R157.2 v2(161.76,45.89) ; R157.2 160.78,45.16 ; U24.5 v2(174.56,95.76) ; R178.2 v2(170.69,29.08) ; v2(140.31,126.9) C58.P v2(140.31,130.02) ; C83.2 v2(200.79,106.17) ; R187.2 v2(192.28,27.56) ; R76.1 v2(141.1,123.32) ; 126.87,123.19 126.87,122.81 v2(127.25,122.43) ; v2(191.9,106.55) 192.34,106.11 U20.3 ; R179.2 v2(170.69,27.43) ; C143.2 v2(168.28,15.88) ; v2(188.85,106.68) 188.53,106.36 U19.1 ; C131.2 v2(157.16,34.1) ; R183.2 v2(189.36,28.45) ; C128.1 159.77,42.88 ; C128.1 v2(161.54,41.91) ; C128.1 v2(157.99,41.91) ; R93.1 v2(139.19,115.7) ; R181.2 v2(173.61,28.32) ; U38.1 v2(173.23,17.14) ; R198.2 v2(183.01,22.22) ; R197.2 v2(176.91,22.22) ; R171.2 v2(170.69,30.73) ; R172.2 v2(173.61,29.97) ; R184.2 v2(189.36,26.67) ; R165.2 v2(189.48,41.02) ; R173.2 v2(189.36,30.1) ; C61.2 v1(131.95,123.99) ; R660.2 v2(160.78,36.83) ; R185.2 v2(189.36,25.27) ; U38.8 v2(165.23,17.14) ; v2(129.71,124.46) 129.83,124.33 C60.2 ; R91.1 v2(125.35,115.06) ; C80.2 v2(180.17,106.05) ; C81.2 v2(188.43,107.73) ; R188.2 v2(192.28,25.91) ; R169.2 v2(207.65,36.19) ; C65.2 141.6,120.52 v2(141.6,121.28) ; U20.1 194.24,106.11 v2(194.69,106.55) ; C66.2 v2(142.75,121.28) ; 204.72,41.66 v2(204.72,42.55) ; C126.1 v2(200.15,42.67) ; R182.2 v2(173.61,26.67) ; C82.2 v2(194.14,107.66) ; R186.2 v2(192.28,29.21)
  BOTTOM w0.203: v2(166.24,115.32) 166.5,115.06 166.5,114.43 164.77,112.7 164.77,107.14 165.74,106.17 165.74,97.03 155.19,86.49 155.19,78.36 151.38,74.55 151.38,50.55 155.45,46.48 155.96,46.48 v1(156.34,46.1)
  BOTTOM w0.305: U39.10 88.38,130.03 v2(88.77,130.43) ; v2(158.37,109.09) C211.1
  BOTTOM w0.381: C209.1 v2(165.99,109.22) ; v2(26.42,143.13) C160.1 ; v2(172.47,109.22) 172.34,109.35 C207.1 ; v2(15.11,143) C162.1
  BOTTOM w0.508: C152.1 v2(139.57,143.13) ; v2(145.8,123.44) 146.3,123.44 C169.2 ; C194.2 135.76,115.06 v2(135.51,114.81) 134.62,114.81 134.37,115.06 C196.2 ; C215.2 135.51,113.16 v2(135.89,113.54) ; C179.2 v2(119.38,123.7) ; C172.2 v2(138.56,124.84) ; C195.2 136.27,118.49 v2(136.77,117.99) ; v2(19.25,130.76) 20.14,130.76 R223.1 ; v2(154.94,21.84) 154.94,22.35 155.32,22.73 C342.1 ; v2(129.29,123.06) 129.03,123.32 C177.2 ; C212.2 v2(139.57,113.54) ; v2(129.71,124.46) 129.92,124.46 130.17,124.71 R230.1 ; R229.1 132.84,124.71 132.72,124.84 v1(132.74,124.84) ; R291.1 v2(153.92,54.86) ; C213.2 v2(138.18,113.54) ; C198.2 131.57,115.19 v2(131.22,114.84) ; C248.1 v2(184.62,78.14) ; C335.1 v2(138.43,34.16) ; C158.1 v2(64.26,143.13) ; C163.2 v2(89.85,131.13) ; C173.2 v2(137.16,124.84) ; C219.2 v2(128.52,114.17) ; C168.2 v2(148.84,123.19) ; R228.1 v1(134.62,124.71) ; v2(130.43,114.94) 129.92,114.43 C218.2 ; C214.2 v2(136.91,113.54) ; R317.1 v2(117.35,26.67) ; C170.2 v2(142.37,124.84) ; C339.2 v2(180.72,25.02) ; v2(23.11,37.08) 22.48,37.08 22.07,36.68 F2.1 22.07,35.71 22.35,35.43 v2(23.11,35.43) ; C247.1 v2(186.82,78.49) ; C156.1 v2(86.11,143.13) ; R256.2 v2(17.4,82.55) ; C171.2 v2(140.97,124.84) ; R307.1 v2(143.38,40) ; 118.75,116.59 v2(119.63,116.59) ; R318.1 115.44,24.51 v2(115.7,24.26) ; R246.1 v2(96.39,104.9) ; 138.3,117.35 v2(137.8,117.35) ; R558.2 v2(85.6,132.72) ; 126.87,120.52 v2(126.87,121.28) ; C187.2 v2(148.21,116.97) ; R227.1 v2(137.92,122.56) ; C178.2 v2(127.25,122.43) ; C246.1 v2(188.72,78.49) ; 117.22,116.59 v2(116.46,116.59) ; C217.2 v2(131.95,114.81) ; C197.2 132.97,114.94 v2(132.84,114.81) 133.35,114.3 C216.2 ; C154.1 v2(95.12,143.13) ; Q12.2 v2(15.39,129.57) ; C201.2 v2(129.03,116.71) ; C180.2 v2(116.59,123.7) ; U42.8 v2(140.34,35.43) ; C188.2 v2(146.69,116.97) ; C229.2 v2(142.88,101.35) ; C200.2 v2(128.65,118.62)
  vias: v1(152.4,96.9) v2(157.99,44.07) v2(158.5,45.21) v2(159.13,44.07) v2(160.27,44.07) v2(161.54,44.07)
VIN: length 22.7
  TOP w0.203: R50.1 179.83,149.73 180.09,149.99 R245.2
  TOP w0.508: v2(180.59,136.02) 180.59,134.87 181.34,134.12 D2.C 182.13,134.12 182.63,134.62 v2(182.63,136.02) ; v2(179.03,146.85) 179.03,147.92 179.39,148.28 R50.1 180.27,148.28 180.72,147.83 v2(180.72,146.81) ; v2(187.58,136.14) D1.C v2(186.12,134.81) ; R29.2 v2(204.09,151.51)
  BOTTOM w0.508: Q11.2 199.44,148.41 v2(199.26,148.59) R218.1
  vias: v2(189.36,135.38) v2(190.5,136.91)
VIN_12V: length 98.3
  TOP w0.203: 49.91,155.19 49.83,155.28 U1.37 ; v1(119.76,156.08) 119.76,156.72 120.06,157.02 U2.36 ; U27.37 158.79,70.31 158.75,70.36 ; 158.12,70.36 158.66,69.81 U27.38 ; v1(120.4,155.32) 120.95,155.87 U2.37 ; 121.45,155.23 U2.38 ; v2(120.14,164.47) 120.14,165.23 120.4,165.48 C6.1 121.16,165.48 121.54,165.1 v2(121.54,164.47) ; U27.36 160.44,71.2 160.15,71.5 159.51,71.5 ; 49.78,154.69 50.33,155.23 U1.38 ; 167.89,71.12 168.66,71.12 168.91,70.87 C112.1 168.91,70.1 168.53,69.72 167.89,69.72 167.77,69.6 ; 48.64,156.08 48.64,156.72 48.94,157.02 U1.36 ; v2(49.02,164.47) 49.02,165.23 49.28,165.48 C1.1 50.04,165.48 50.42,165.1 v2(50.42,164.47) 50.55,164.34
  TOP w0.254: U2.23 121.45,163.92 121.41,163.96 ; 49.78,163.96 49.83,163.91 U1.24 ; 50.55,164.08 50.83,163.8 U1.22 ; U1.23 50.33,163.92 50.29,163.96 ; 167.39,70.36 167.34,70.31 U27.24 ; U2.24 120.95,163.91 120.9,163.96 ; U2.22 121.95,163.93 121.92,163.96 ; v1(129.67,160.53) 129.54,160.53 129.03,160.02 U2.7 ; 58.42,158.88 57.78,159.52 U1.6 ; 167.39,69.34 167.36,69.31 U27.22 ; v2(162.31,61.85) 162.95,62.49 U27.6 ; 58.42,160.53 57.91,160.02 U1.7 ; U27.23 167.35,69.81 167.39,69.85 ; U2.6 128.77,159.52 129.41,158.88 v1(129.79,158.88) ; U27.7 163.44,62.23 v2(163.89,61.79) 163.96,61.72
  TOP w0.305: U10.1 18.05,123.17 v2(17.65,123.57)
  TOP w0.508: v1(129.67,160.53) 131.06,160.53 C19.1 ; 172.34,135.78 TP4.1 ; TP4.1 172.34,138.29 ; TP4.1 173.6,137.03 ; TP4.1 171.08,137.03 ; 158.24,72.01 C109.1 157.1,70.48 ; Q3.1 v2(173.23,159.77) ; C118.1 162.31,60.07 v2(162.31,61.85) ; C13.1 59.94,160.53 58.42,160.53 ; 58.42,158.88 60.07,158.88 C22.1 ; v2(19.3,116.97) R273.1 v2(17.02,116.97) ; C44.1 118.75,154.51 ; C44.1 v2(120.4,153.54) ; C44.1 v2(117.09,153.54) ; C25.1 131.19,158.88 v1(129.79,158.88) ; R206.2 v2(189.01,158.08) ; Q3.3 v2(173.23,157.23) ; v2(48.13,154.81) C35.1 49.66,153.67 ; 174.21,158.5 v2(173.23,158.5) ; 163.96,61.72 163.96,60.2 C119.1 ; R199.2 v2(183.9,161.67) ; D3.C v2(166.93,130.63) ; R17.2 v1(188.21,160.27)
  L11_POWER w0.508: 172.34,135.78 TP4.1 ; TP4.1 172.34,138.29 ; TP4.1 171.08,137.03 ; TP4.1 173.6,137.03 ; P4.2 167.18,124.08 ; P4.2 166.24,125.02 ; P4.2 166.24,123.14 ; P4.2 165.3,124.08
  L12_POWER w0.508: P4.2 166.24,125.02 ; P4.2 166.24,123.14 ; P4.2 165.3,124.08 ; P4.2 167.18,124.08 ; 171.08,137.03 TP4.1 ; TP4.1 172.34,138.29 ; TP4.1 173.6,137.03 ; TP4.1 172.34,135.78
  BOTTOM w0.508: R234.1 v2(170.94,119.89) ; R212.2 v2(193.04,162.43)
  vias: v1(120.65,154.18) v1(130.17,159.64) v1(131.19,159.64) v1(132.21,159.64) v2(48.13,155.57) v2(49.02,155.45) v2(59.05,159.77) v2(60.07,159.77) v2(60.96,159.77) v2(158.75,72.39) v2(158.75,71.63) v2(158.75,70.99) v2(167.77,70.74) v2(167.77,69.98) v2(167.77,69.34) v2(169.8,152.53) v2(169.8,151) v2(169.8,149.61) v2(171.2,152.53) v2(171.2,151) v2(171.2,149.61) v2(172.47,149.61) v2(172.47,148.08) v2(172.47,146.43) v2(172.47,142.11) v2(172.47,140.84) v2(173.86,149.61) v2(173.86,148.08) v2(173.86,146.43) v2(173.86,145.03) v2(173.86,143.64) v2(173.86,142.11) v2(173.86,140.84) v2(175.26,148.08) v2(175.26,146.43) v2(175.26,145.03) v2(175.26,143.64) v2(175.26,142.11) v2(175.26,140.84)
AD9577_OUT0_N: length 1.7
  TOP w0.14: C59.2 121.93,120.89 U11.4
AD9577_OUT0_P: length 1.7
  TOP w0.14: U11.1 120.38,119.38 C63.2
AD9577_OUT1_N: length 11.6
  TOP w0.102: U12.28 131.72,122.41 131.57,122.56 131.57,123.16 131.17,123.56 131.17,129.13 131.17,129.13 131.17,129.32 130.52,129.96 130.14,129.96 R64.2 R67.1
AD9577_OUT1_P: length 11.2
  TOP w0.102: R68.1 R69.2 130.11,129.73 130.43,129.73 130.94,129.22 130.94,123.47 131.34,123.06 131.34,122.56 131.22,122.43 U12.29
AD9577_OUT2_N: length 3.5
  TOP w0.102: U13.4 145.17,119 v1(144.4,119)
  BOTTOM w0.102: v1(144.4,119) 144.4,119.39 144.15,119.65 143.42,119.65 143.32,119.55 143.32,119.23 143.21,119.13 142.62,119.13
AD9577_OUT2_P: length 3.5
  TOP w0.102: U13.1 145.17,120.52 v1(144.4,120.52)
  BOTTOM w0.102: v1(144.4,120.52) 144.4,120.13 144.15,119.88 143.42,119.88 143.32,119.98 143.32,120.29 143.21,120.4 142.62,120.4
ADCMP671-1_OVB: length 2.5
  BOTTOM w0.203: U44.6 26.67,19.66 26.67,20.83 26.54,20.96 R323.1
ADCMP671-1_PWRGD_3P3: length 80.1
  TOP w0.203: v1(16.89,88.27) 17.16,88.53 U23.1
  L13_POWER w0.203: v1(16.89,88.27) 16.89,86.49 22.48,80.9 22.48,46.99 26.54,42.93 26.54,16.76 26.73,16.58 v1(26.73,15.75)
  BOTTOM w0.203: U44.1 v1(26.73,15.75) 26.73,14.67 R335.1
ADDR1: length 136.6
  TOP w0.14: RN1.3 200.65,84.47 v1(200.41,84.71) ; v1(84.69,68.04) U31.AP27
  L16_SIGNAL w0.095: v1(84.69,68.04) 85.56,68.04 88.01,70.48 88.01,72.77 91.06,75.82 100.81,75.82 108.46,83.47 108.46,87.79 112.49,91.82 127.28,91.82 130.97,88.14 145.55,88.14 146.69,89.28 151.13,89.28 152.9,87.5 170.18,87.5 171.2,88.52 176.15,88.52 178.18,86.49 187.71,86.49 187.96,86.74 188.72,86.74 189.36,87.38 192.28,87.38 194.18,85.47 199.64,85.47 v1(200.41,84.71)
ADDR2: length 139.4
  TOP w0.14: RN1.2 v1(201.15,84.69) ; v1(83.69,68.04) U31.AN27
  L16_SIGNAL w0.095: v1(201.15,84.69) 199.86,85.98 194.56,85.98 192.66,87.88 186.44,87.88 185.55,87 178.31,87 176.4,88.9 170.94,88.9 169.93,87.88 153.06,87.88 151.28,89.66 146.53,89.66 145.39,88.52 131.13,88.52 127.44,92.2 112.33,92.2 108.08,87.95 108.08,83.63 100.65,76.2 89.28,76.2 87.63,74.55 87.63,70.74 85.34,68.45 84.2,68.45 83.79,68.04 v1(83.69,68.04)
ADDR3: length 137.3
  TOP w0.14: RN1.1 201.65,84.43 v1(201.93,84.71) ; v1(84.69,67.04) U31.AP26
  L16_SIGNAL w0.095: v1(201.93,84.71) 201.3,84.07 193.04,84.07 190.88,86.23 188.47,86.23 187.07,84.84 173.99,84.84 172.09,86.74 152.59,86.74 150.81,88.52 147,88.52 145.86,87.38 130.49,87.38 126.81,91.06 112.84,91.06 109.22,87.44 109.22,83.12 99.13,73.03 91.06,73.03 89.92,71.88 89.88,71.88 89.79,71.79 89.79,70.74 86.09,67.04 v1(84.69,67.04)
ADDR4: length 146
  TOP w0.14: v1(205.49,77.85) 205.2,77.57 RN4.16 ; v1(84.69,66.04) U31.AP25
  L16_SIGNAL w0.095: v1(205.49,77.85) 205.99,77.34 205.99,76.58 204.85,75.44 201.3,75.44 200.28,74.42 195.65,74.42 195.62,74.44 195.33,74.44 195.31,74.42 193.93,74.42 191.9,76.45 170.81,76.45 161.29,85.98 152.27,85.98 150.5,87.76 147.32,87.76 146.18,86.61 130.17,86.61 126.49,90.3 113.16,90.3 109.98,87.12 109.98,82.8 99.44,72.26 91.57,72.26 90.55,71.25 90.55,70.36 86.23,66.04 v1(84.69,66.04)
ADDR5: length 150.6
  TOP w0.14: v1(83.69,69.04) U31.AN28 ; RN4.15 v1(205.47,77.07)
  L16_SIGNAL w0.095: v1(205.47,77.07) 202.56,79.97 202.56,86.36 200.79,88.14 193.29,88.14 192.41,89.03 188.37,89.03 188.03,88.69 187.64,88.69 187.3,89.03 178.05,89.03 177.04,90.04 170.31,90.04 169.29,89.03 153.73,89.03 149.92,92.84 130.11,92.84 129.6,93.34 111.83,93.34 106.93,88.45 106.93,84.14 102.55,79.76 91.57,79.76 90.17,78.36 88.52,78.36 86.49,76.33 86.49,72.01 85.09,70.61 84.45,70.61 84.2,70.36 84.2,69.47 83.77,69.04 v1(83.69,69.04)
ADM1178_ALERTB_3P3: length 5.7
  TOP w0.203: v1(19.18,129.56) 18.25,129.56 18.05,129.35 U10.10
  BOTTOM w0.203: R223.2 19.19,129.54 v1(19.18,129.56) 19.17,129.57 Q12.1
ADM1178_EN: length 240.2
  TOP w0.14: v1(20.57,123.95) 19.43,123.95 19.05,123.57 U10.3 ; RN6.14 v1(186.68,53.58)
  L22_SIGNAL w0.095: v1(186.68,53.58) 186.68,51.68 185.1,50.1 180.02,50.1 178.31,51.82 178.31,54.23 175.9,56.64 173.61,56.64 166.37,63.88 166.37,79.88 164.85,81.41 164.85,85.09 158.12,91.82 158.12,98.68 157.23,99.57 157.23,105.41 151.64,111 138.43,111 137.16,112.27 135.64,112.27 133.86,114.05 133.86,121.16 132.84,122.17 132.84,124.08 131.19,125.73 131.19,128.14 129.54,129.79 122.3,129.79 121.16,130.94 109.6,130.94 105.54,135 76.96,135 74.93,132.97 52.45,132.97 50.8,131.32 27.94,131.32 v1(20.57,123.95)
  BOTTOM w0.14: R340.1 21.46,123.95 v1(20.57,123.95)
ADM1276_GPO2_1P8: length 99
  TOP w0.14: RN8.15 178.97,65.68 178.88,65.59 178,65.59 v1(177.55,66.04) ; U9.9 v1(195.58,151.65) 195.95,152.02 R28.1
  L7_SIGNAL w0.095: v1(177.55,66.04) 178.05,66.04 178.69,66.67 179.96,66.67 182.37,69.09 182.37,85.47 186.44,89.53 186.44,97.54 190.37,101.47 190.37,110.36 194.56,114.55 194.56,150.64 v1(195.58,151.65)
ADM1276_LATCHB: length 4.2
  TOP w0.14: U9.6 195.1,149.7 v1(195.58,149.22)
  BOTTOM w0.14: R219.2 194.94,149.22 v1(195.58,149.22) 196.22,149.86 196.22,149.99 R342.1
ADM1276_PWRGD: length 4.8
  TOP w0.203: U9.12 192.93,154.7 v1(193.8,155.57) 194.44,156.21 C29.2
  BOTTOM w0.203: R214.1 193.8,155.83 v1(193.8,155.57)
ADP1715_EN: length 4.5
  TOP w0.14: R111.2 R112.1 201.93,106.55 202.61,105.88 U21.1
ADP5054_#1_BST1: length 1.8
  TOP w0.254: C110.1 162.44,72.51 U27.32
ADP5054_#1_BST2: length 1.8
  TOP w0.254: U27.28 164.44,72.5 164.72,72.77
ADP5054_#1_BST3: length 2.4
  TOP w0.305: v1(160.15,62.99) 160.44,63.29 U27.1
  BOTTOM w0.203: v1(160.15,62.99) 160.15,63.88 C282.1
ADP5054_#1_BST4: length 2.5
  TOP w0.305: v1(166.24,62.99) 165.95,63.29 U27.12
  BOTTOM w0.203: C281.1 166.24,63.75 v1(166.24,62.99)
ADP5054_#1_COMP1: length 2.9
  TOP w0.254: R146.2 157.22,69.09 157.24,68.81 157.9,68.81 157.9,68.81 158.33,68.81 158.33,68.81 U27.40
ADP5054_#1_COMP3: length 1.8
  TOP w0.254: U27.47 159.17,65.31 R150.2
ADP5054_#1_COMP4: length 1.8
  TOP w0.203: R149.2 168.12,65.81 167.24,65.81 167.24,65.81 U27.15
ADP5054_#1_DL1: length 6.8
  TOP w0.305: U27.31 162.95,74.42 R44.1
  TOP w0.381: R44.1 162.69,75.69 Q7.2
ADP5054_#1_DL2: length 6.8
  TOP w0.305: U27.29 163.95,74.53 R143.1
  TOP w0.381: R143.1 165.23,75.69 Q7.4
ADP5054_#1_FB1: length 5.2
  TOP w0.203: U27.41 159.02,68.31
  TOP w0.254: 159.02,68.31 159.01,68.32 158.54,68.32 158.54,68.31 158.36,68.31 v1(158.12,68.07)
  BOTTOM w0.203: R267.1 156.79,69.29 R265.2 v1(158.12,68.07)
ADP5054_#1_FB3: length 9.6
  TOP w0.254: v1(158.5,65.41) 158.9,65.81 U27.46
  BOTTOM w0.203: v1(158.5,65.41) 158.37,65.28 158.37,64.39 155.19,61.21 R280.1 R290.2
ADP5054_#1_FB4: length 9.2
  TOP w0.254: U27.16 166.86,66.31 166.88,66.29 v1(167.51,66.29)
  BOTTOM w0.203: R287.2 170.56,60.96 169.04,62.48 169.04,64.77 v1(167.51,66.29)
ADP5054_#1_PWRGD: length 15
  TOP w0.203: RN8.16 178.84,65.18 v1(178.69,65.02) ; v1(167.77,66.93) 167.89,66.8 R148.2
  TOP w0.254: v1(167.77,66.93) 167.65,66.81 U27.17
  BOTTOM w0.203: v1(178.69,65.02) 177.16,65.02 176.4,64.26 174.5,64.26 172.97,65.79 170.05,65.79 168.91,66.93 v1(167.77,66.93)
ADP5054_#1_SENSE1: length 76.9
  TOP w0.203: U14.11 v1(159.44,115.32) ; R127.1 162.81,94.62 162.43,95 156.72,95 v1(156.46,94.74)
  TOP w0.508: 158.7,93.09 C91.1 157.73,91.57 ; C99.1 168.15,90.93 ; C99.1 169.11,89.41 ; C99.1 167.18,89.41 ; C99.1 168.15,87.88 ; 162.81,92.87 R127.1 ; R127.1 163.79,93.85 ; R127.1 161.84,93.85 ; 159.6,85.6 L9.2 157.23,86.36 ; 169.42,86.36 L10.2 167.04,85.6 ; 168.15,91.57 C94.1 ; C94.1 167.18,93.09 ; C94.1 169.11,93.09 ; C98.1 158.7,89.41 ; C98.1 157.73,90.93 ; C98.1 157.73,87.88
  BOTTOM w0.203: R264.1 156.9,85.78 v1(163.19,92.08) ; v1(156.46,94.74) 156.59,94.87 156.97,94.87 157.73,95.63 157.73,101.35 156.65,102.43 156.65,111.82 159.13,114.3 159.13,115.01 v1(159.44,115.32)
ADP5054_#1_SENSE3: length 96
  TOP w0.203: L11.2 158.46,58.17 ; L11.2 158.46,54.1 ; L11.2 157.8,56.13 ; v1(156.34,46.99) 156.46,46.86 160.06,46.86 R157.1 ; R157.1 160.78,48.31 ; R157.1 160.01,47.59 ; R157.1 161.56,47.59 ; 157.53,52.07 C122.1 ; C122.1 158.5,50.55 ; C122.1 158.5,53.59 ; U15.11 167.06,115.24 167.13,115.32 v1(167.06,115.32)
  BOTTOM w0.203: R289.1 v1(156.34,53.85) ; v1(156.34,46.99) 156.21,46.86 155.7,46.86 151.89,50.67 151.89,74.3 155.57,77.98 155.57,86.23 166.18,96.84 166.18,106.36 165.23,107.31 165.23,112.65 166.88,114.3 166.88,115.06 167.13,115.32 v1(167.06,115.32)
ADP5054_#1_SENSE4: length 95.5
  TOP w0.203: R158.1 164.72,48.31 ; R158.1 165.32,46.99 v1(170.56,46.99) ; R158.1 165.49,47.59 ; R158.1 163.94,47.59 ; C123.1 167.89,53.59 ; C123.1 167.89,50.55 ; C123.1 168.86,52.07 ; 167.81,54.1 L12.2 ; L12.2 168.47,56.13 ; L12.2 167.81,58.17 ; U16.11 173.41,115.19 173.54,115.32 v1(173.48,115.32)
  BOTTOM w0.203: R288.1 170.56,53.98 v1(170.43,53.85) ; v1(170.56,46.99) 170.43,46.86 169.42,46.86 168.15,48.13 168.15,62.61 167,63.75 167,71.88 169.42,74.3 169.42,101.73 175.77,108.08 175.77,113.67 175.07,114.36 173.8,114.36 173.35,114.81 173.35,115.19 v1(173.48,115.32)
ADP5054_#1_VREG: length 6.2
  TOP w0.254: 169.55,68.2 169.93,68.2 170.43,67.69 170.69,67.69 v1(170.81,67.56) ; U27.48 159.56,64.81 159.26,64.52 v1(159.26,63.88) ; v1(158.64,66.31) U27.45 ; U27.13 166.96,64.81 v1(167.51,64.26)
  TOP w0.381: C115.1 157.82,66.29 158.62,66.29 v1(158.64,66.31)
ADP5054_#2_BST1: length 1.8
  TOP w0.254: U2.32 118.76,159.02 C24.1
ADP5054_#2_BST2: length 1.8
  TOP w0.254: U2.28 118.77,161.02 118.49,161.29
ADP5054_#2_BST3: length 2.4
  TOP w0.305: v1(128.27,156.72) 127.97,157.02 U2.1
  BOTTOM w0.203: C146.1 127.89,157.1 v1(128.27,156.72)
ADP5054_#2_BST4: length 2.3
  TOP w0.305: v1(128.27,162.81) 127.97,162.52 U2.12
  BOTTOM w0.203: C144.1 128.14,162.69 v1(128.27,162.81)
ADP5054_#2_COMP1: length 2.7
  TOP w0.203: U2.40 122.45,153.94 R25.2
ADP5054_#2_COMP3: length 1.8
  TOP w0.254: R26.2 125.95,155.74 U2.47
ADP5054_#2_DL1: length 6.8
  TOP w0.305: R15.1 116.84,159.52 U2.31
  TOP w0.381: R15.1 115.57,159.26 Q2.2
ADP5054_#2_DL2: length 6.8
  TOP w0.305: R14.1 116.73,160.52 U2.29
  TOP w0.381: R14.1 115.57,161.8 Q2.4
ADP5054_#2_FB1: length 15.1
  TOP w0.203: R23.2 v1(113.67,151.38) R24.1 ; 122.95,155.59 U2.41
  TOP w0.254: v1(123.19,154.69) 122.95,154.93 122.95,155.11 122.94,155.11 122.94,155.58 122.95,155.59
  BOTTOM w0.203: v1(113.67,151.38) 115.19,152.91 121.41,152.91 v1(123.19,154.69)
ADP5054_#2_FB3: length 13
  TOP w0.203: R45.1 v1(130.43,147.07) R47.2
  TOP w0.254: U2.46 125.45,155.48 v1(125.86,155.07)
  BOTTOM w0.203: v1(130.43,147.07) 130.43,150.5 v1(125.86,155.07)
ADP5054_#2_PWRGD: length 141
  TOP w0.203: RN8.13 v1(177.8,66.68)
  TOP w0.254: U2.17 v1(124.45,164.34) 124.45,164.96 R6.2
  L20_SIGNAL w0.203: v1(124.45,164.34) 124.46,164.34 125.6,165.48 130.3,165.48 133.35,162.43 133.35,140.59 137.92,136.02 137.92,134.11 139.83,132.21 141.99,132.21 143.89,130.3 143.89,122.94 145.29,121.54 145.29,117.6 145.92,116.97 145.92,111.76 147.57,110.11 147.57,78.99 149.35,77.22 156.72,77.22 161.8,72.14 169.16,72.14 170.43,70.87 173.74,70.87 175.01,69.6 175.01,67.82 176.15,66.67 177.8,66.67 v1(177.8,66.68)
ADP5054_#2_SENSE1: length 43.9
  TOP w0.203: 105.41,154.05 105.41,149.86 107.19,148.08 R41.1 ; U7.11 96.19,149.41 97.66,150.88 97.66,159.64 97.92,159.89 R13.1
  TOP w0.381: 103.25,154.43 104.78,154.43 ; 103.25,154.43 101.73,154.43 ; 103.25,154.43 103.25,155.4 ; 98.93,158.91 R13.1 ; R13.1 98.93,160.87 ; R13.1 99.91,159.89 ; 101.73,165.1 C5.1 ; C5.1 103.25,164.13 ; C5.1 104.78,165.1 ; 99.57,155.4 99.57,154.43 101.09,154.43 ; 106.93,156.17 L6.2 106.17,153.8 ; 99.57,164.13 C4.1 101.09,165.1 ; 106.93,163.87 L5.2
ADP5054_#2_SENSE3: length 44.5
  TOP w0.203: v1(140.59,149.22) 140.59,148.28 U8.11 ; v1(143.89,151.51) 144.35,151.97 144.35,158.58 R16.1 ; 137.41,153.54 137.41,147.7 136.78,147.07 R49.1
  TOP w0.381: C20.1 139.19,165.43 ; C20.1 140.72,164.47 ; C20.1 137.67,164.47 ; C26.1 140.72,155.07 ; C26.1 137.67,155.07 ; C26.1 139.19,154.1 ; L7.2 137.16,164.38 ; L7.2 135.13,165.04 ; L7.2 133.1,164.38 ; R16.1 143.68,160.03 ; R16.1 143.68,158.48 ; R16.1 142.95,159.26 ; L8.2 137.16,155.03 ; L8.2 135.13,154.37 ; L8.2 133.1,155.03
  BOTTOM w0.203: v1(143.89,151.51) 144.15,151.77 144.15,152.27 143.76,152.65 141.48,152.65 140.41,151.59 140.41,149.66 140.59,149.48 v1(140.59,149.22)
ADP5054_#2_VREG: length 25.4
  TOP w0.203: R42.1 125.48,150.5 126.17,151.19 126.17,153.19 C46.1 ; v1(123.57,167) 124.37,167.81 126.45,167.81 127,167.26 R8.1
  TOP w0.254: v1(123.57,167) 123.06,166.5 123.06,166.12 ; U2.45 v1(124.95,155.21)
  TOP w0.381: C46.1 124.97,154.39 124.97,155.19 v1(124.95,155.21)
  L20_SIGNAL w0.203: v1(123.57,167) 122.94,166.37 122.94,163.45 123.83,162.56 123.83,156.34 v1(124.95,155.21)
ADP5054_#3_BST1: length 1.8
  TOP w0.254: C21.1 47.64,159.02 U1.32
ADP5054_#3_BST2: length 1.8
  TOP w0.254: U1.28 47.65,161.02 47.37,161.29
ADP5054_#3_BST3: length 2.4
  TOP w0.305: v1(57.15,156.72) 56.85,157.02 U1.1
  BOTTOM w0.203: C147.1 56.52,156.72 v1(57.15,156.72)
ADP5054_#3_BST4: length 2.3
  TOP w0.305: v1(57.15,162.81) 56.85,162.52 U1.12
  BOTTOM w0.203: C145.1 56.9,162.56 v1(57.15,162.81)
ADP5054_#3_COMP1: length 2.9
  TOP w0.254: U1.40 51.33,154.9 51.34,154.9 51.34,154.48 51.33,154.47 51.33,153.81 51.05,153.79 R20.2
ADP5054_#3_COMP2: length 1.8
  TOP w0.203: U1.20 51.83,164.86 R2.2
ADP5054_#3_COMP3: length 2.7
  TOP w0.254: U1.47 54.83,155.74 55.75,154.81 R21.2
ADP5054_#3_COMP4: length 1.8
  TOP w0.203: U1.15 54.33,163.75 54.46,163.88 54.46,164.95 R4.2
ADP5054_#3_DL1: length 6.8
  TOP w0.305: R10.1 45.72,159.52 U1.31
  TOP w0.381: Q1.2 44.45,159.26 R10.1
ADP5054_#3_DL2: length 6.8
  TOP w0.305: U1.29 45.61,160.52 R9.1
  TOP w0.381: R9.1 44.45,161.8 Q1.4
ADP5054_#3_FB1: length 13.9
  TOP w0.203: R32.2 v1(47.24,146.43) R33.1 ; U1.41 51.83,155.59
  TOP w0.254: v1(52.07,154.69) 51.83,154.93 51.83,155.11 51.82,155.11 51.82,155.58 51.83,155.59
  BOTTOM w0.203: v1(52.07,154.69) 52.07,154.05 50.16,152.15 50.16,149.35 v1(47.24,146.43)
ADP5054_#3_FB2: length 10.3
  TOP w0.203: v1(52.32,164.08) 52.32,163.27 U1.19
  BOTTOM w0.203: R208.2 R207.1 47.12,166.12 50.29,166.12 v1(52.32,164.08)
ADP5054_#3_FB3: length 11.6
  TOP w0.203: R34.1 R35.2
  TOP w0.254: U1.46 54.33,155.48 55.5,154.31 55.5,147.19
ADP5054_#3_FB4: length 10.7
  TOP w0.203: R37.1 v1(59.31,169.42) 60.58,169.42
  TOP w0.254: v1(53.98,164.08) 53.98,163.96 53.83,163.81 U1.16
  L5_SIGNAL w0.254: v1(53.98,164.08) v1(59.31,169.42)
ADP5054_#3_PWRGD: length 195.2
  TOP w0.203: RN8.14 178.83,66.18 v1(178.69,66.04)
  TOP w0.254: R3.2 53.33,164.96 v1(53.33,164.21) U1.17
  L22_SIGNAL w0.203: v1(53.33,164.21) 53.33,163.59 54.1,162.81 55.5,162.81 56.13,162.18 56.13,160.27 56.9,159.51 58.04,159.51 62.1,155.45 66.04,155.45 80.14,141.35 93.22,141.35 93.98,142.11 108.33,142.11 115.32,135.13 129.29,135.13 130.81,133.6 132.84,133.6 138.43,128.02 150.24,128.02 156.72,121.54 160.02,121.54 161.67,119.89 161.67,110.36 166.37,105.66 166.37,91.31 173.1,84.58 177.16,84.58 179.45,82.3 179.45,66.8 v1(178.69,66.04)
ADP5054_#3_SENSE1: length 27.8
  TOP w0.203: R30.1 35.56,148.21 35.31,148.46 35.05,148.46 34.8,148.72 34.8,149.99 ; U4.11 27.49,148.84 27.43,148.9 27.43,151.64 27.69,151.89 R19.1
  TOP w0.381: 36.59,150.14 L2.2 35.7,153.16 ; 29.72,153.47 C33.1 ; C33.1 28.19,154.43 ; C33.1 31.24,154.43 ; 28.7,150.91 R19.1 ; R19.1 28.7,152.87 ; R19.1 29.68,151.89 ; C34.1 34.93,154.43 ; C34.1 33.4,153.47 ; C34.1 31.88,154.43
ADP5054_#3_SENSE2: length 48.4
  TOP w0.203: v1(27.69,163.32) 27.69,163.83 27.43,164.08 27.43,168.66 27.69,168.91 R1.1 ; v1(16.51,149.35) 16.18,149.03 U3.11
  TOP w0.381: R1.1 29.68,168.91 ; R1.1 28.7,169.89 ; R1.1 28.7,167.93 ; 28.45,166.5 C10.1 ; C10.1 31.5,166.5 ; C10.1 29.97,167.46 ; 35.7,166.62 L1.2 ; L1.2 37.48,166.62 ; L1.2 36.59,169.65 ; C11.1 34.93,166.5 ; C11.1 33.4,167.46 ; C11.1 31.88,166.5
  BOTTOM w0.203: v1(27.69,163.32) 27.3,162.94 27.18,162.94 16.26,152.02 16.26,149.61 v1(16.51,149.35) ; R210.1 35.81,167.26 v1(34.67,168.4)
ADP5054_#3_SENSE3: length 33.6
  TOP w0.203: R12.1 72.56,157.06 73.15,156.46 73.15,150.75 72.77,150.37 v1(72.39,150.37) ; R12.1 71.83,157.23 ; R12.1 72.56,158 ; R36.1 61.21,151.38 62.48,152.65 ; v1(65.53,149.22) 65.33,149.03 U5.11 ; C23.1 69.6,155.07 ; C23.1 68.07,154.1 ; C23.1 66.55,155.07 ; 64.01,154.37 L4.2 ; L4.2 61.98,155.03 ; L4.2 66.04,155.03
  BOTTOM w0.203: v1(72.39,150.37) 71.88,149.86 67.56,149.86 66.04,148.34 65.66,148.34 65.36,148.64 65.36,148.92 65.53,149.1 v1(65.53,149.22)
ADP5054_#3_SENSE4: length 43.5
  TOP w0.203: R39.1 v1(66.17,170.81) ; C14.1 68.07,165.43 ; C14.1 69.6,164.47 ; C14.1 66.55,164.47 ; R11.1 72.56,162.07 ; R11.1 73.28,160.57 73.28,159.77 73.66,159.38 83.57,159.38 v1(83.82,159.13) ; R11.1 71.83,161.29 ; R11.1 72.56,160.51 ; v1(87.25,149.22) 87.18,149.15 U6.11 ; 66.04,164.38 L3.2 64.01,165.04
  BOTTOM w0.203: v1(66.17,170.81) 65.53,170.18 65.53,167 v1(66.17,166.37) ; v1(87.25,149.22) 87,149.48 87,152.4 83.95,155.45 82.8,155.45 81.41,156.84 81.41,157.99 82.8,159.38 83.57,159.38 v1(83.82,159.13)
ADP5054_#3_VREG: length 24.7
  TOP w0.203: v1(52.96,167.89) 52.6,167.54 52.6,164.49 52.83,164.26 U1.18
  TOP w0.254: U1.13 55.33,163.53 v1(55.88,164.08) ; v1(53.83,155.21) U1.45
  TOP w0.381: v1(53.83,155.21) 53.85,155.19 53.85,154.39 C37.1
  BOTTOM w0.203: v1(53.83,155.21) 53.83,156.74 53.34,157.23 53.34,162.18 53.85,162.69 54.48,162.69 v1(55.88,164.08) 55.88,166.5 54.48,167.89 v1(52.96,167.89)
ADP5054_SYNC: length 190.3
  TOP w0.14: R42.2 v1(124.84,149.1) 124.46,149.48 124.46,150.74 124.45,150.75 U2.44 ; v1(53.33,150.62) U1.44 ; v1(154.05,66.81) U27.44
  L9_SIGNAL w0.095: v1(124.84,149.1) 123.7,149.1 122.05,147.45 103.12,147.45 102.11,148.46 84.58,148.46 83.69,147.57 63.63,147.57 63.25,147.96 56,147.96 v1(53.33,150.62)
  L20_SIGNAL w0.095: v1(154.05,66.81) 154.04,66.8 152.4,66.8 142.11,77.09 142.11,92.08 134.62,99.57 134.62,115.44 135.76,116.59 135.76,119.25 136.4,119.89 136.4,129.67 129.29,136.78 129.29,142.49 126.87,144.91 126.87,147.07 v1(124.84,149.1)
ADP7105_PWRGD: length 49.2
  TOP w0.14: R121.2 182.88,104.64 v1(182.12,104.64) 181.71,104.64 181.69,104.66 181.27,104.66 181.25,104.64 U18.7 ; v1(177.55,62.99) 177.94,62.6 RN7.11
  L20_SIGNAL w0.095: v1(177.55,62.99) 178.69,62.99 180.21,64.52 180.21,74.42 179.2,75.44 179.2,94.87 179.96,95.63 179.96,98.93 182.12,101.09 v1(182.12,104.64)
ARDY: length 146.3
  TOP w0.14: v1(84.69,70.04) U31.AP29
  L16_SIGNAL w0.095: v1(197.36,81.03) 199.77,81.03 202.31,83.57 202.31,85.73 200.28,87.76 193.17,87.76 192.66,88.27 187.45,88.27 187.07,88.65 177.93,88.65 176.91,89.66 170.69,89.66 169.67,88.65 153.57,88.65 149.76,92.46 129.95,92.46 129.44,92.96 111.98,92.96 107.31,88.3 107.31,83.98 102.71,79.38 91.82,79.38 90.42,77.98 88.77,77.98 86.87,76.07 86.87,71.63 85.28,70.04 v1(84.69,70.04)
  BOTTOM w0.14: R260.1 197.87,80.52 v1(197.36,81.03)
AREB: length 131.3
  TOP w0.14: U25.1 v1(188.73,85.74) ; v1(83.69,66.04) U31.AN25
  L7_SIGNAL w0.095: v1(191.52,80.39) 191.52,81.53 188.73,84.32 v1(188.73,85.74)
  L16_SIGNAL w0.095: v1(188.73,85.74) 187.32,84.33 173.86,84.33 171.83,86.36 152.43,86.36 150.65,88.14 147.16,88.14 146.02,87 130.33,87 126.65,90.68 113,90.68 109.6,87.28 109.6,82.96 99.28,72.64 91.31,72.64 90.17,71.5 90.17,70.48 86.23,66.55 84.45,66.55 83.95,66.04 v1(83.69,66.04)
  BOTTOM w0.14: R263.2 v1(191.52,80.39)
ASYNC_AMS1: length 138
  TOP w0.14: v1(82.69,69.04) U31.AM28 ; v1(193.29,84.71) 193.57,84.43 RN2.15 ; U26.1 v1(194.45,88.79)
  L7_SIGNAL w0.095: v1(193.29,84.71) 193.29,87.63 v1(194.45,88.79)
  L16_SIGNAL w0.095: v1(194.45,88.79) 193.7,89.53 191.77,89.53 190.75,90.55 186.82,90.55 185.67,89.41 178.18,89.41 177.16,90.42 170.81,90.42 170.56,90.68 152.62,90.68 150.08,93.22 130.27,93.22 129.76,93.73 111.67,93.73 106.55,88.61 106.55,84.29 102.4,80.14 91.44,80.14 90.04,78.74 88.14,78.74 86.11,76.71 86.11,72.52 85.22,71.63 83.44,71.63 83.19,71.37 83.19,69.6 82.69,69.1 v1(82.69,69.04)
AWEB: length 141.2
  TOP w0.14: U25.2 189.23,87.13 189.61,87.5 191.9,87.5 R135.2 v1(192.15,86.36) 192.15,81.41 v1(192.41,81.15) ; v1(82.69,66.04) U31.AM25
  L16_SIGNAL w0.095: v1(82.69,66.04) 82.69,66.05 83.19,66.55 83.95,66.55 84.2,66.8 84.2,67.18 84.58,67.56 85.85,67.56 89.28,70.99 89.28,73.41 91.31,75.44 100.97,75.44 108.84,83.31 108.84,87.63 112.65,91.44 127.13,91.44 130.81,87.76 145.7,87.76 146.85,88.9 150.97,88.9 152.75,87.12 170.56,87.12 171.58,88.14 175.9,88.14 178.05,85.98 187.58,85.98 188.09,86.49 189.48,86.49 189.87,86.87 191.64,86.87 v1(192.15,86.36)
  BOTTOM w0.14: R262.2 193.04,80.52 v1(192.41,81.15)
BF_CLKBUF: length 12.6
  TOP w0.14: U29.C19 v1(185.88,74.89) ; R138.1 188.94,82.46 v1(189.61,81.79)
  L7_SIGNAL w0.095: v1(189.61,81.79) 189.23,81.41 189.23,77.98 188.72,77.47 188.72,74.68 188.21,74.17 186.56,74.17 185.88,74.85 v1(185.88,74.89)
BF_CLKOUT: length 139.4
  TOP w0.14: RN2.14 v1(194.07,84.82) ; v1(80.69,69.04) U31.AK28
  L16_SIGNAL w0.095: v1(192.66,92.2) 191.47,93.39 191.2,93.39 191.11,93.47 181.36,93.47 180.47,92.58 177.16,92.58 175.77,93.98 158.75,93.98 156.4,96.33 108.93,96.33 100.97,88.36 100.97,87.09 96.81,82.93 91.57,82.93 88.9,80.26 86.87,80.26 83.19,76.58 83.19,72.77 82.68,72.26 82.17,72.26 81.28,71.37 81.28,69.6 80.72,69.04 v1(80.69,69.04)
  L18_SIGNAL w0.095: v1(192.66,92.2) 192.66,86.23 v1(194.07,84.82)
BF_FPGA_RESET: length 112.2
  TOP w0.14: v1(177.55,64.01) 178.46,63.1 RN7.10
  L16_SIGNAL w0.095: v1(177.55,64.01) 176.66,63.12 176.66,61.47 173.74,58.55 167.39,58.55 139.06,30.23 130.17,30.23 126.75,26.8 119,26.8 118.24,26.04 110.74,26.04 105.92,21.21 97.66,21.21 91.95,15.49 v1(91.31,15.49)
  BOTTOM w0.14: v1(91.31,15.49) 91.25,15.56 U43.1 90.57,14.24 R320.2
BF_JTAG_EMU: length 44.5
  TOP w0.14: P10.2 v1(195.83,19.18) ; R153.2 v1(201.8,56.77)
  L3_SIGNAL w0.095: v1(201.8,56.77) 201.8,55.12 203.45,53.47 203.45,42.04 202.69,41.28 202.69,26.04 v1(195.83,19.18)
BF_JTAG_TCK: length 41
  TOP w0.14: P10.8 v1(195.83,26.8) ; U29.V2 v1(198.68,60.49)
  L3_SIGNAL w0.095: v1(198.68,60.49) 198.68,59.89 201.04,57.53 201.04,54.23 202.56,52.7 202.56,42.67 201.93,42.04 201.93,32.89 v1(195.83,26.8)
BF_JTAG_TDI: length 35.2
  TOP w0.14: P10.12 v1(195.83,31.88) ; U29.R1 v1(195.88,59.35)
  L3_SIGNAL w0.095: v1(195.83,31.88) 195.2,32.51 195.2,35.05 199.26,39.12 199.26,49.53 199.77,50.04 199.77,52.83 198.63,53.98 198.63,58.04 197.31,59.35 v1(195.88,59.35)
BF_JTAG_TDO: length 28.1
  TOP w0.14: R152.2 v1(199.26,56.77) ; P10.14 v1(195.83,34.42)
  L3_SIGNAL w0.095: v1(195.83,34.42) 200.79,39.37 200.79,52.83 199.26,54.36 v1(199.26,56.77)
BF_JTAG_TMS: length 46.7
  TOP w0.14: P10.6 v1(195.83,24.26) ; U29.U2 v1(197.88,60.49)
  L3_SIGNAL w0.095: v1(195.83,24.26) 202.31,30.73 202.31,41.78 203.07,42.55 203.07,52.89 201.45,54.52 201.45,56.92 201.55,57.01 201.55,59.56 199.9,61.21 198.37,61.21 197.88,60.72 v1(197.88,60.49)
BF_JTAG_TRST: length 39.5
  TOP w0.14: R174.1 v1(195.71,29.72) 196.09,29.34 P10.10 ; U29.U1 v1(197.88,59.69)
  L3_SIGNAL w0.095: v1(195.71,29.72) 201.42,35.43 201.42,42.55 201.93,43.05 201.93,52.58 200.53,53.98 200.53,57.28 198.12,59.69 v1(197.88,59.69)
BF_PCA9545_RESETB: length 23.5
  TOP w0.14: U34.1 v1(173.67,44.45) 173.67,45.4 R160.1 ; RN7.12 v1(178.69,62.1)
  L9_SIGNAL w0.095: v1(178.69,62.1) 178.18,61.59 178.18,60.45 175.39,57.66 175.39,46.1 173.74,44.45 v1(173.67,44.45)
BF_RESETB: length 26.2
  TOP w0.14: R133.2 174.56,90.24 v1(174.56,91.06) U24.1 ; U29.B18 v1(185.08,74.09)
  L9_SIGNAL w0.095: v1(185.08,74.09) 184.77,73.79 182.12,73.79 177.55,78.36 177.55,87.12 174.56,90.1 v1(174.56,91.06)
BF_SCL: length 43.5
  TOP w0.14: R640.1 v1(179.58,56.13)
  L16_SIGNAL w0.095: v1(179.58,14.86) 179.58,22.22 178.82,22.99 178.82,49.91 179.71,50.8 179.71,54.23 179.58,54.36 v1(179.58,56.13)
  BOTTOM w0.14: R326.2 v1(179.58,14.86)
BF_SDA: length 51.7
  TOP w0.14: R639.1 v1(180.85,56.13)
  L16_SIGNAL w0.095: v1(180.85,56.13) 179.96,57.02 179.2,57.02 178.18,56.01 178.18,51.82 177.67,51.31 177.67,43.31 178.18,42.8 178.18,26.67 172.34,20.83 172.34,13.34 v1(171.45,12.45)
  BOTTOM w0.14: R339.2 v1(171.45,12.45)
BF_SPARE0: length 117.4
  TOP w0.14: RN7.9 179.1,63.6 v1(178.69,64.01) ; v1(82.69,67.04) U31.AM26
  L3_SIGNAL w0.095: v1(178.69,64.01) 179.58,64.9 179.58,74.04 176.53,77.09 159,77.09 155.45,73.53 124.2,73.53 124.19,73.53 120.65,73.53 119.76,74.42 118.36,74.42 116.97,73.03 116.97,71.88 116.59,71.5 115.98,71.5 115.89,71.59 112.01,71.59 107.48,67.06 99.06,67.06 97.92,65.91 91.44,65.91 91.06,65.53 83.57,65.53 83.19,65.91 83.19,66.55 82.69,67.04 v1(82.69,67.04)
BF_SPARE1: length 146.8
  TOP w0.14: v1(81.69,67.04) U31.AL26 ; RN11.11 v1(196.61,50.93)
  L3_SIGNAL w0.095: 82.17,67.56 82.17,67.52 v1(81.69,67.04) 81.69,67.09 82.17,67.56 ; 82.17,67.56 82.17,68.2 82.42,68.45 87.38,68.45 88.27,67.56 91.57,67.56 91.82,67.82 106.93,67.82 112.65,73.53 116.33,73.53 118.11,75.31 120.53,75.31 120.63,75.21 120.92,75.21 121.02,75.31 151.16,75.31 151.42,75.05 155.28,75.05 158.21,77.98 176.69,77.98 181.74,72.93 181.74,59.06 184.02,56.77 188.59,56.77 189.74,55.63 189.74,50.93 190.37,50.29 195.97,50.29 v1(196.61,50.93)
BF_SPARE2: length 140.9
  TOP w0.14: v1(81.69,66.04) U31.AL25 ; RN10.12 v1(192.03,51.82)
  L3_SIGNAL w0.095: v1(81.69,66.04) 81.69,66.07 82.17,66.55 82.17,67.06 82.68,67.56 86.49,67.56 87.5,66.55 97.79,66.55 98.68,67.44 107.19,67.44 111.63,71.88 116.2,71.88 116.46,72.14 116.46,73.28 118.11,74.93 151,74.93 151.26,74.68 155.45,74.68 158.37,77.6 176.53,77.6 180.34,73.79 180.34,58.55 182.63,56.26 187.58,56.26 188.98,54.86 v1(188.98,51.82)
  L5_SIGNAL w0.095: v1(192.03,51.82) 191.27,52.58 189.74,52.58 v1(188.98,51.82)
BF_SPARE3: length 150.2
  TOP w0.14: v1(177.55,71.12) 178,70.67 178.88,70.67 178.97,70.76 RN9.15 ; v1(79.69,66.04) U31.AJ25
  L16_SIGNAL w0.095: v1(180.09,93.73) 179.32,92.96 177.42,92.96 176.02,94.36 159.1,94.36 156.68,96.77 153.39,96.77 153.16,96.55 151.77,96.55 151.54,96.77 144.17,96.77 143.58,97.37 142.17,97.37 141.58,96.77 108.84,96.77 100.58,88.52 100.58,87.25 96.65,83.31 91.31,83.31 88.65,80.64 86.36,80.64 82.17,76.45 82.17,72.9 80.66,71.39 80.54,71.39 80.34,71.19 80.34,66.62 79.75,66.04 v1(79.69,66.04)
  L18_SIGNAL w0.095: v1(177.55,71.12) 178.05,70.61 179.71,70.61 180.72,71.63 180.72,91.95 180.09,92.58 v1(180.09,93.73)
BF_SPARE4: length 0.7
  TOP w0.14: v1(78.69,65.04) U31.AH24
BF_SPI_CLK: length 39.8
  TOP w0.14: U32.6 v1(180.17,43.98) ; RN11.14 v1(198.11,51.83)
  L20_SIGNAL w0.095: v1(180.17,43.98) 180.17,42.08 186.06,36.19 v1(186.06,34.54)
  L22_SIGNAL w0.095: v1(198.11,51.83) 198.12,51.82 198.12,50.29 193.68,45.85 183.77,45.85 182.5,44.58 182.5,43.94 181.93,43.37 180.78,43.37 v1(180.17,43.98)
  BOTTOM w0.14: U41.6 v1(186.06,34.54) R314.1
BF_SPI_FLASH_CS: length 23.3
  TOP w0.14: v1(198.61,50.93) RN11.15
  L22_SIGNAL w0.095: v1(198.61,50.93) 198.61,49.89 194.18,45.47 187.2,45.47 185.93,44.2 v1(183.52,44.2)
  BOTTOM w0.14: R302.2 182.88,44.83 v1(183.52,44.2) U41.1
BF_SPI_FPGA_CS: length 22.7
  TOP w0.14: v1(194.03,51.82) RN10.16 ; U32.3 v1(178.22,43.98)
  L22_SIGNAL w0.095: v1(194.03,51.82) 194.06,51.79 194.06,49.4 192.41,47.75 190.12,47.75 188.72,46.36 183.39,46.36 181.74,44.7 178.94,44.7 v1(178.22,43.98)
BF_SPI_MISO: length 33.9
  TOP w0.14: U32.11 v1(180.17,52.41) ; RN11.13 v1(197.61,50.93)
  L3_SIGNAL w0.095: v1(184.66,44.7) 180.17,49.19 v1(180.17,52.41)
  L18_SIGNAL w0.095: v1(180.17,52.41) 180.81,52.41 181.23,52.83 182.12,52.83 183.52,51.44 197.1,51.44 v1(197.61,50.93)
  BOTTOM w0.14: U41.2 184.78,44.58 v1(184.66,44.7) R300.2
BF_SPI_MOSI: length 49.8
  TOP w0.14: RN11.12 v1(197.11,51.82) ; v1(179.07,53.47) 178.22,52.62 U32.14
  L18_SIGNAL w0.095: v1(179.07,53.47) 179.83,54.23 182.63,54.23 183.9,52.96 195.97,52.96 v1(197.11,51.82)
  L22_SIGNAL w0.095: v1(187.32,34.54) 198.75,45.97 198.75,48.89 199.77,49.91 199.77,51.31 198.63,52.45 197.74,52.45 v1(197.11,51.82)
  BOTTOM w0.14: U41.5 v1(187.32,34.54)
BF_STATUS: length 10.3
  TOP w0.14: RN11.10 v1(196.11,51.84)
  BOTTOM w0.14: Q14.1 189.31,51.13 190.75,52.58 195.37,52.58 v1(196.11,51.84)
BF_VCC1V2: length 17.1
  TOP w0.203: U29.P12 v1(195.48,69.29) ; U29.P13 v1(195.48,70.09) ; U29.G12 v1(189.08,69.29) ; U29.G14 v1(189.08,70.89) ; U29.K14 v1(191.48,70.89) ; U29.H14 v1(189.88,70.89) ; U29.M14 v1(193.88,70.89) ; U29.J14 v1(190.68,70.89) ; U29.G13 v1(189.08,70.09) ; U29.P14 v1(195.48,70.89) ; U29.N14 v1(194.68,70.89) ; U29.L14 v1(193.08,70.89)
  TOP w0.305: v2(201.93,104.27) 202.24,104.58 U21.3
  TOP w0.508: C88.2 v2(200.79,104.27) ; R130.1 v2(180.85,95.89)
  BOTTOM w0.508: C258.1 191.52,70.93 v1(191.48,70.89) ; C261.1 188.93,70.74 v1(189.08,70.89) ; v1(189.08,69.29) 189,69.22 C269.1 ; v1(193.08,70.89) 193.04,70.93 C257.1 ; v1(189.88,70.89) 189.74,71.03 C259.1 ; C256.1 v2(195.49,72.17) ; v1(195.48,70.89) 195.71,71.12 C255.1 ; v1(195.48,69.29) 195.53,69.34 C266.1
BF_VCC1V8: length 192.2
  TOP w0.203: U29.K8 v1(191.48,65.29) ; U29.H8 v1(189.88,65.29) ; U29.G11 v1(189.08,68.49) ; U29.P8 v1(195.48,65.29) ; U29.P10 v1(195.48,66.89) ; U29.G9 v1(189.08,66.09) ; U29.G7 v1(189.08,64.49) ; U29.L7 v1(193.08,64.49) ; U29.P11 v1(195.48,68.49) ; U29.N8 v1(194.68,65.29) ; U29.J8 v1(190.68,65.29) ; U29.M8 v1(193.88,65.29) ; U29.G10 v1(189.08,66.89) ; U29.K7 v1(191.48,64.49) ; U29.H7 v1(189.88,64.49) ; U29.P7 v1(195.48,64.49) ; U29.N7 v1(194.68,64.49) ; U29.M7 v1(193.88,64.49) ; U29.J7 v1(190.68,64.49) ; U29.L8 v1(193.08,65.29) ; U29.G8 v1(189.08,65.29) ; U29.P9 v1(195.48,66.09)
  TOP w0.254: U37.2 153.81,21.32 v2(153.29,21.84) ; U37.1 154.31,21.71 v2(154.18,21.84) ; v2(175.77,65.28) 175.51,65.54 U28.1 ; v2(173.23,66.42) 173.5,66.7 U28.15
  TOP w0.305: R3.1 v2(53.34,167) ; R6.1 v1(124.46,167) ; v2(179.07,52.45) 178.87,52.25 U32.13 ; v2(188.34,89.92) 188.73,89.52 U25.8 ; R148.1 v2(170.43,66.8)
  TOP w0.508: R382.1 v2(185.67,48.64) ; R204.2 v2(177.8,14.86) ; C132.2 173.74,39.36 v2(173.67,39.43) U34.5 ; R160.2 v2(174.12,47.88) ; 195.71,85.73 v2(195.71,86.49) ; v2(173.48,90.93) 173.23,90.68 R133.1 ; U26.5 v2(196.47,88.79) ; U19.5 v2(188.53,102.05) 188.53,100.56 C87.2 ; R121.1 v2(185.17,104.65) ; R156.1 189.23,48.64 v2(188.85,48.26) ; v2(183.52,34.8) 183.64,34.92 C133.1 ; Q8.1 v2(174.7,16.18) ; R123.2 v2(159.13,36.96) ; C101.1 v2(187.83,89.15) ; R141.1 v2(188.72,79.76) ; Q9.1 v2(180.8,16.08) ; R159.2 v2(172.47,47.88) ; R28.2 v2(197.99,153.29) ; R205.2 v2(183.9,14.86) ; R140.1 v2(185.93,80.77) ; R111.1 v2(198.25,107.95)
  L3_SIGNAL w0.508: v2(53.34,167) 53.85,167.51 69.09,167.51 70.87,165.74 70.87,146.56 75.44,141.99 80.64,141.99 87.88,134.75 v2(87.88,133.48)
  L9_SIGNAL w0.508: v2(91.19,17.65) 91.69,17.14 v2(91.69,16.64) 92.08,16.26 107.31,16.26 108.46,17.4 114.55,17.4 116.97,14.99 151.77,14.99 153.29,16.51 v2(153.29,21.84) v2(154.18,21.84)
  BOTTOM w0.508: C277.1 194.69,64.48 v1(194.68,64.49) ; R300.1 v2(184.66,47.75) ; v2(91.19,17.65) 90.99,17.46 U43.5 ; C280.1 187.03,64.35 v2(187.58,64.9) ; C278.1 191.64,64.33 v1(191.48,64.49) ; v1(189.08,66.89) 188.74,66.55 C268.1 ; v2(154.18,21.84) 154.18,22.48 C343.1 ; R557.2 v2(87.88,133.48) ; U41.7 v2(184.78,34.8) ; v1(195.48,66.09) 195.68,66.29 C267.1 ; R302.1 v2(182.88,47.75) ; U41.8 v2(183.52,34.8) ; C276.1 v2(196.85,64.9) ; R299.1 v2(186.44,47.75) ; C275.1 v2(203.07,63.12) ; C279.1 v1(189.08,64.49) ; R276.1 205.1,67.18 206.12,68.2 v2(206.25,68.2) ; C340.1 v2(91.69,16.64) ; R275.1 v2(205.1,68.2)
BF_VCC2V5: length 16.2
  TOP w0.305: U29.R20 v1(196.28,75.69) ; U29.L19 v2(192.68,73.93)
  TOP w0.508: v2(186.31,106.68) 186.63,106.36 U19.3 ; U20.5 v2(194.24,101.92)
  L7_SIGNAL w0.508: v2(200.03,77.85) 199.01,76.84 v2(196.34,76.84) 196.28,76.77 v1(196.28,75.69) 195.77,75.18 193.8,75.18 192.68,74.06 v2(192.68,73.93)
  BOTTOM w0.508: C228.2 194.24,102.77 v2(194.24,101.92) ; C244.1 199.9,77.98 v2(200.03,77.85) ; v2(196.34,76.84) 195.96,77.22 C245.1
CCLK: length 182.5
  TOP w0.14: R136.2 v1(198.12,88.77) ; v1(65.69,49.04) U31.T9
  L3_SIGNAL w0.095: v1(198.12,88.77) 197.49,88.14 185.8,88.14 184.91,89.03 170.69,89.03 167.39,85.73 148.46,85.73 147.32,84.58 v1(145.67,84.58)
  L16_SIGNAL w0.095: v1(65.69,49.04) 65.69,49.05 66.17,49.53 95.38,49.53 97.41,51.56 105.16,51.56 108.84,47.88 114.43,47.88 116.71,50.17 119.25,50.17 120.02,49.4 124.21,49.4 124.46,49.66 124.46,51.44 126.24,53.21 126.24,56.26 127.76,57.78 134.49,57.78 137.03,60.33 137.03,73.53 145.67,82.17 v1(145.67,84.58)
  BOTTOM w0.14: v1(65.69,49.04) 65.24,49.49 63.5,49.49 63.24,49.23 63.24,48.89 62.84,48.49 62.5,48.49 62.24,48.23 62.24,40.5 R311.1
CSIB: length 153
  TOP w0.14: v1(77.69,66.04) U31.AG25 ; v1(177.55,72.14) 177.92,71.76 RN9.13
  L16_SIGNAL w0.095: v1(178.31,93.73) 176.91,95.12 174.12,95.12 173.48,95.76 160.69,95.76 156.42,100.02 155.65,100.8 154.08,102.36 112.14,102.36 102.11,92.33 100.33,92.33 96.01,88.01 96.01,86.74 95,85.73 92.58,85.73 88.27,81.41 86.11,81.41 80.26,75.56 80.26,72.9 79.88,72.52 78.49,72.52 78.23,72.26 78.23,66.55 77.72,66.04 v1(77.69,66.04)
  L18_SIGNAL w0.095: v1(178.31,93.73) 178.31,92.08 180.09,90.3 180.09,78.87 179.58,78.36 179.58,76.62 180.09,76.11 180.09,73.15 179.58,72.64 179.58,72.14 179.2,71.76 177.93,71.76 v1(177.55,72.14)
DATA0: length 157.7
  TOP w0.14: v1(83.69,74.04) U31.AN33 ; RN12.16 205.2,67.41 205.62,67.82 205.62,68.59 v1(206.12,69.09)
  L16_SIGNAL w0.095: v1(206.12,69.09) 205.61,69.6 205.61,70.74 206.76,71.88 206.76,83.06 203.84,85.98 203.84,87 200.66,90.17 191.77,90.17 191.13,90.81 186.18,90.81 186.06,90.68 179.45,90.68 178.56,91.57 176.91,91.57 175.26,93.22 156.34,93.22 153.92,95.63 109.32,95.63 101.73,88.04 101.73,86.77 97.12,82.17 92.2,82.17 89.53,79.5 87.38,79.5 84.2,76.33 84.2,74.55 v1(83.69,74.04)
DATA1: length 160.1
  TOP w0.14: v1(206.12,69.85) 206.87,69.1 206.87,67.93 206.62,67.68 206.11,67.68 205.34,66.91 RN12.15 ; v1(83.69,75.04) U31.AN34
  L16_SIGNAL w0.095: v1(206.12,69.85) 207.26,70.99 207.26,83.57 204.47,86.36 204.47,87.5 201.42,90.55 193.17,90.55 192.02,91.69 191.01,91.69 190.5,91.19 185.8,91.19 185.55,90.93 179.71,90.93 178.69,91.95 177.16,91.95 175.51,93.6 156.59,93.6 154.18,96.01 109.16,96.01 101.35,88.2 101.35,86.93 96.97,82.55 91.82,82.55 89.15,79.88 87.12,79.88 83.69,76.45 v1(83.69,75.04)
DATA2: length 163.5
  TOP w0.14: v1(80.69,75.04) U31.AK34 ; v1(206.38,67.18) 205.6,66.41 RN12.14
  L5_SIGNAL w0.095: v1(206.38,67.18) 205.23,67.18 199.39,61.34 188.98,61.34 187.23,63.09 184.24,63.09 183.09,64.24 183.09,70.78 183.1,70.79 183.1,79.34 181.89,80.55 158.15,80.55 155.77,82.93 144.94,82.93 133.89,93.98 110.49,93.98 104.14,87.63 104.14,87.25 102.23,85.34 98.3,85.34 95.89,82.93 84.96,82.93 81.03,78.99 81.03,77.09 80.69,76.75 v1(80.69,75.04)
DATA3: length 159.6
  TOP w0.14: RN12.13 v1(205.61,65.91) ; v1(81.69,75.04) U31.AL34
  L5_SIGNAL w0.095: v1(205.61,65.91) 204.47,65.91 199.52,60.96 188.72,60.96 186.82,62.87 184.15,62.87 182.86,64.15 182.86,70.87 182.88,70.89 182.88,79.25 181.8,80.33 158.06,80.33 155.68,82.71 144.85,82.71 133.8,93.76 110.86,93.76 104.54,87.43 104.54,87.01 102.47,84.95 98.44,84.95 96.05,82.55 86.61,82.55 83.31,79.25 83.31,76.84 81.69,75.21 v1(81.69,75.04)
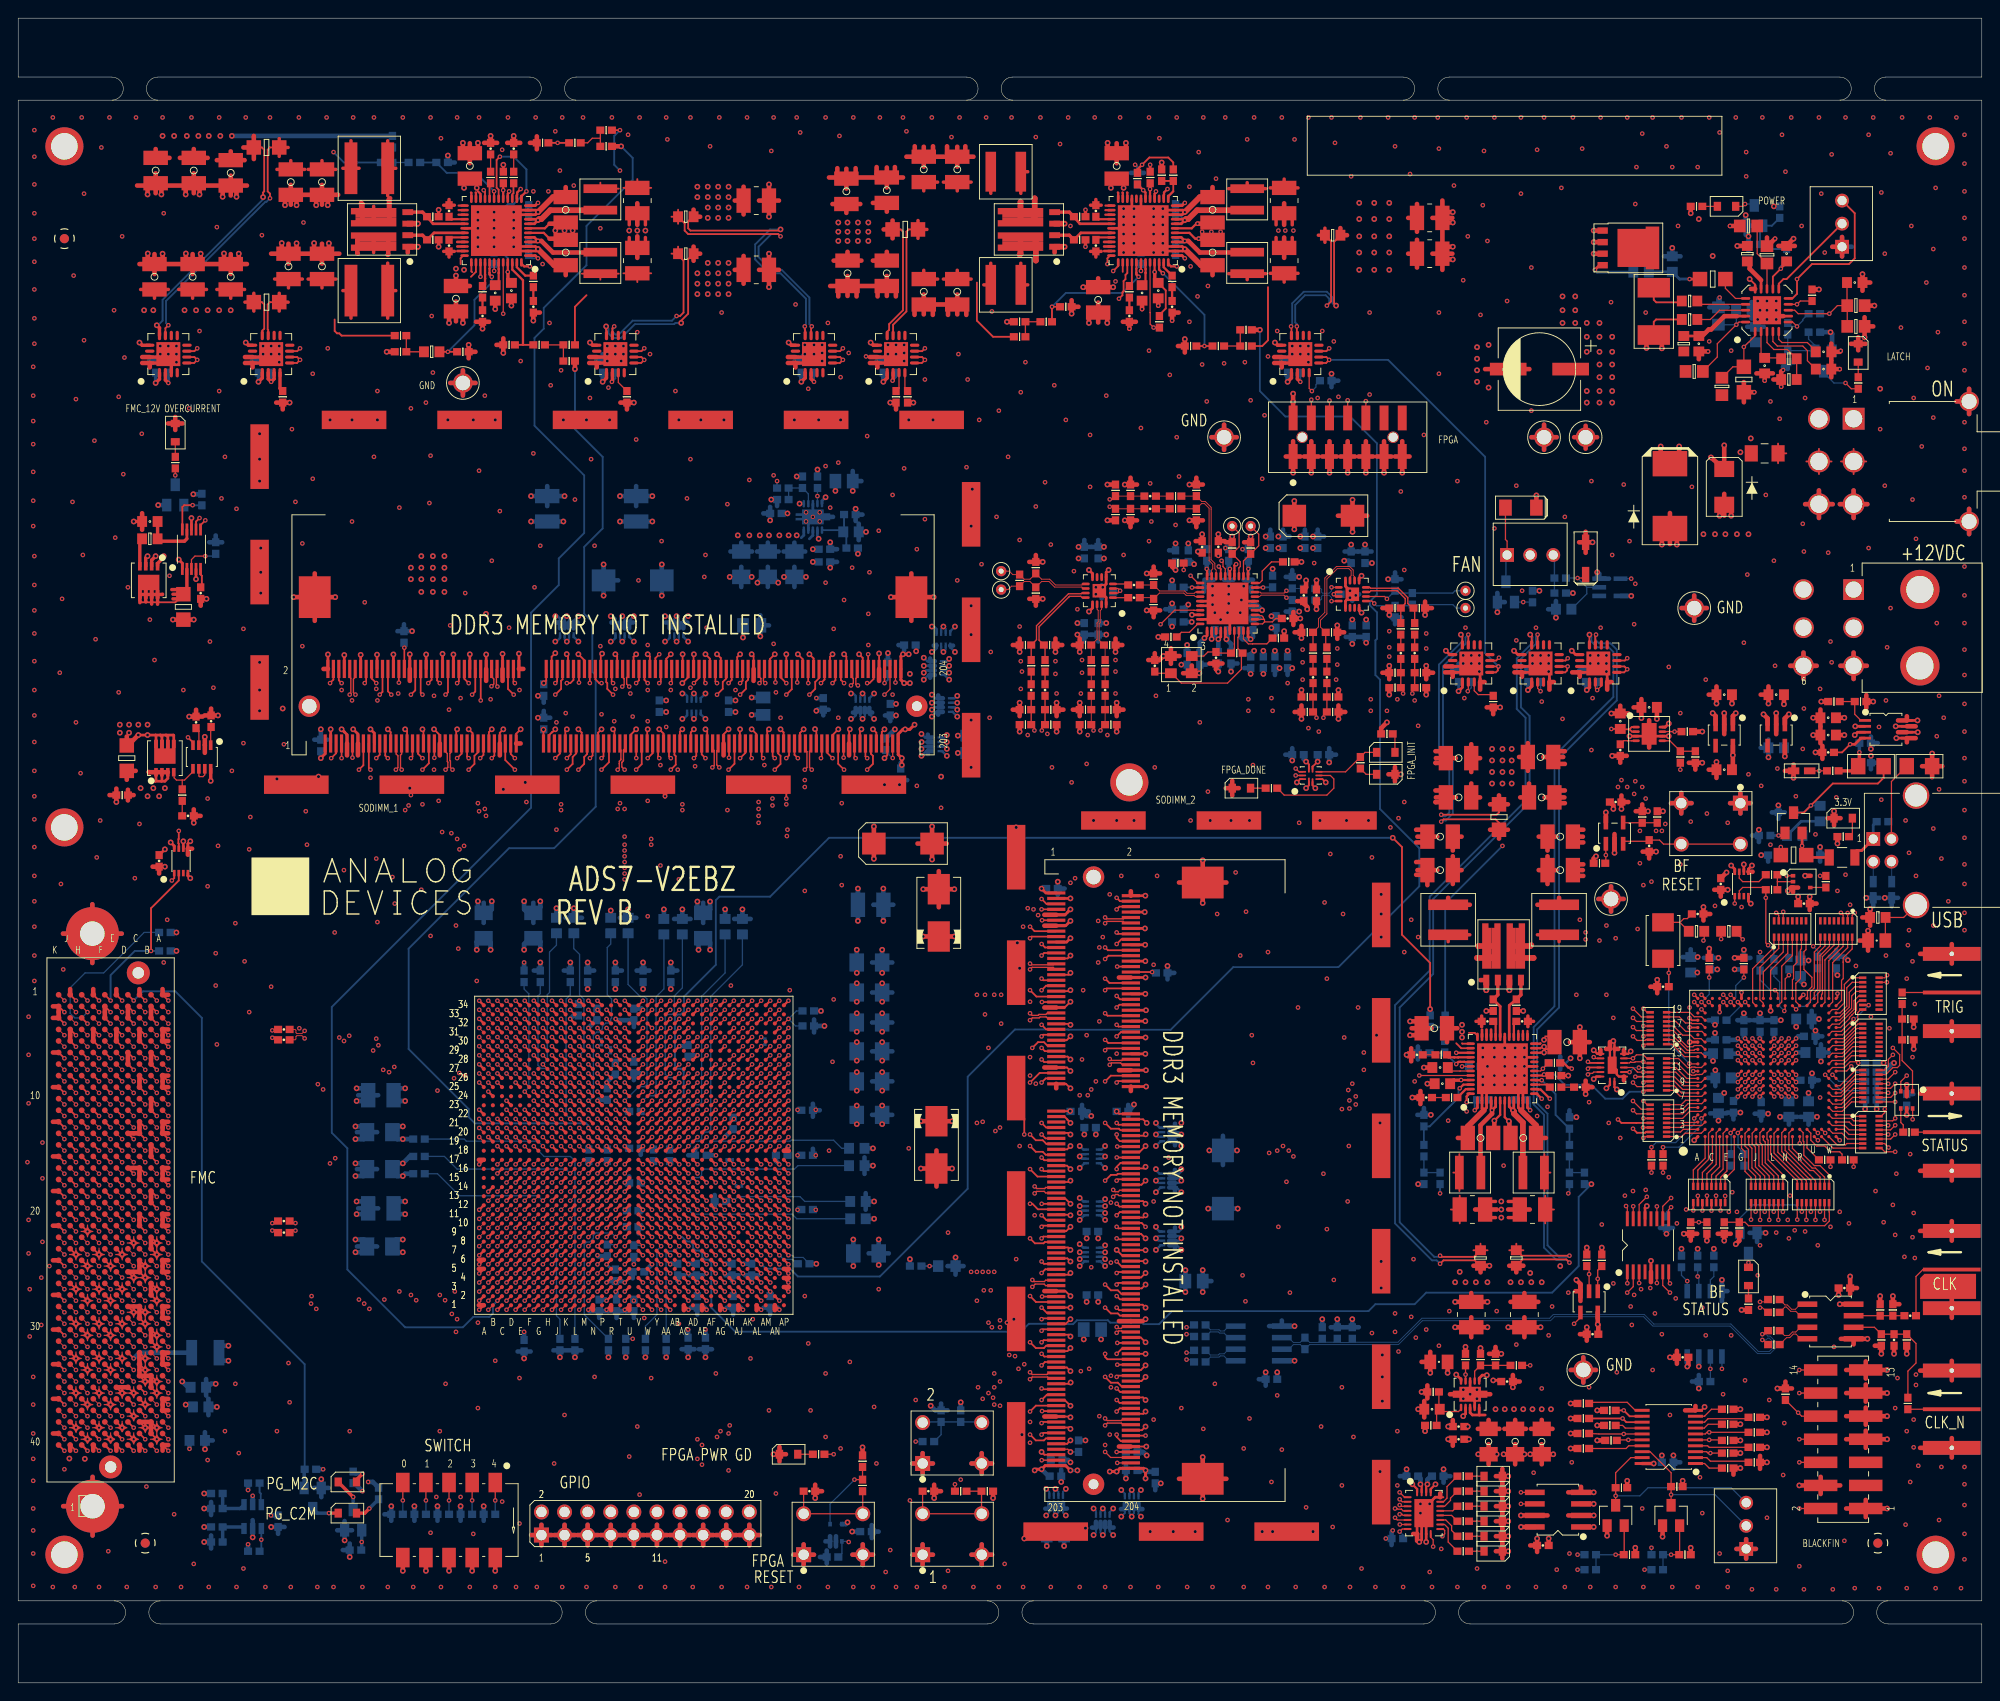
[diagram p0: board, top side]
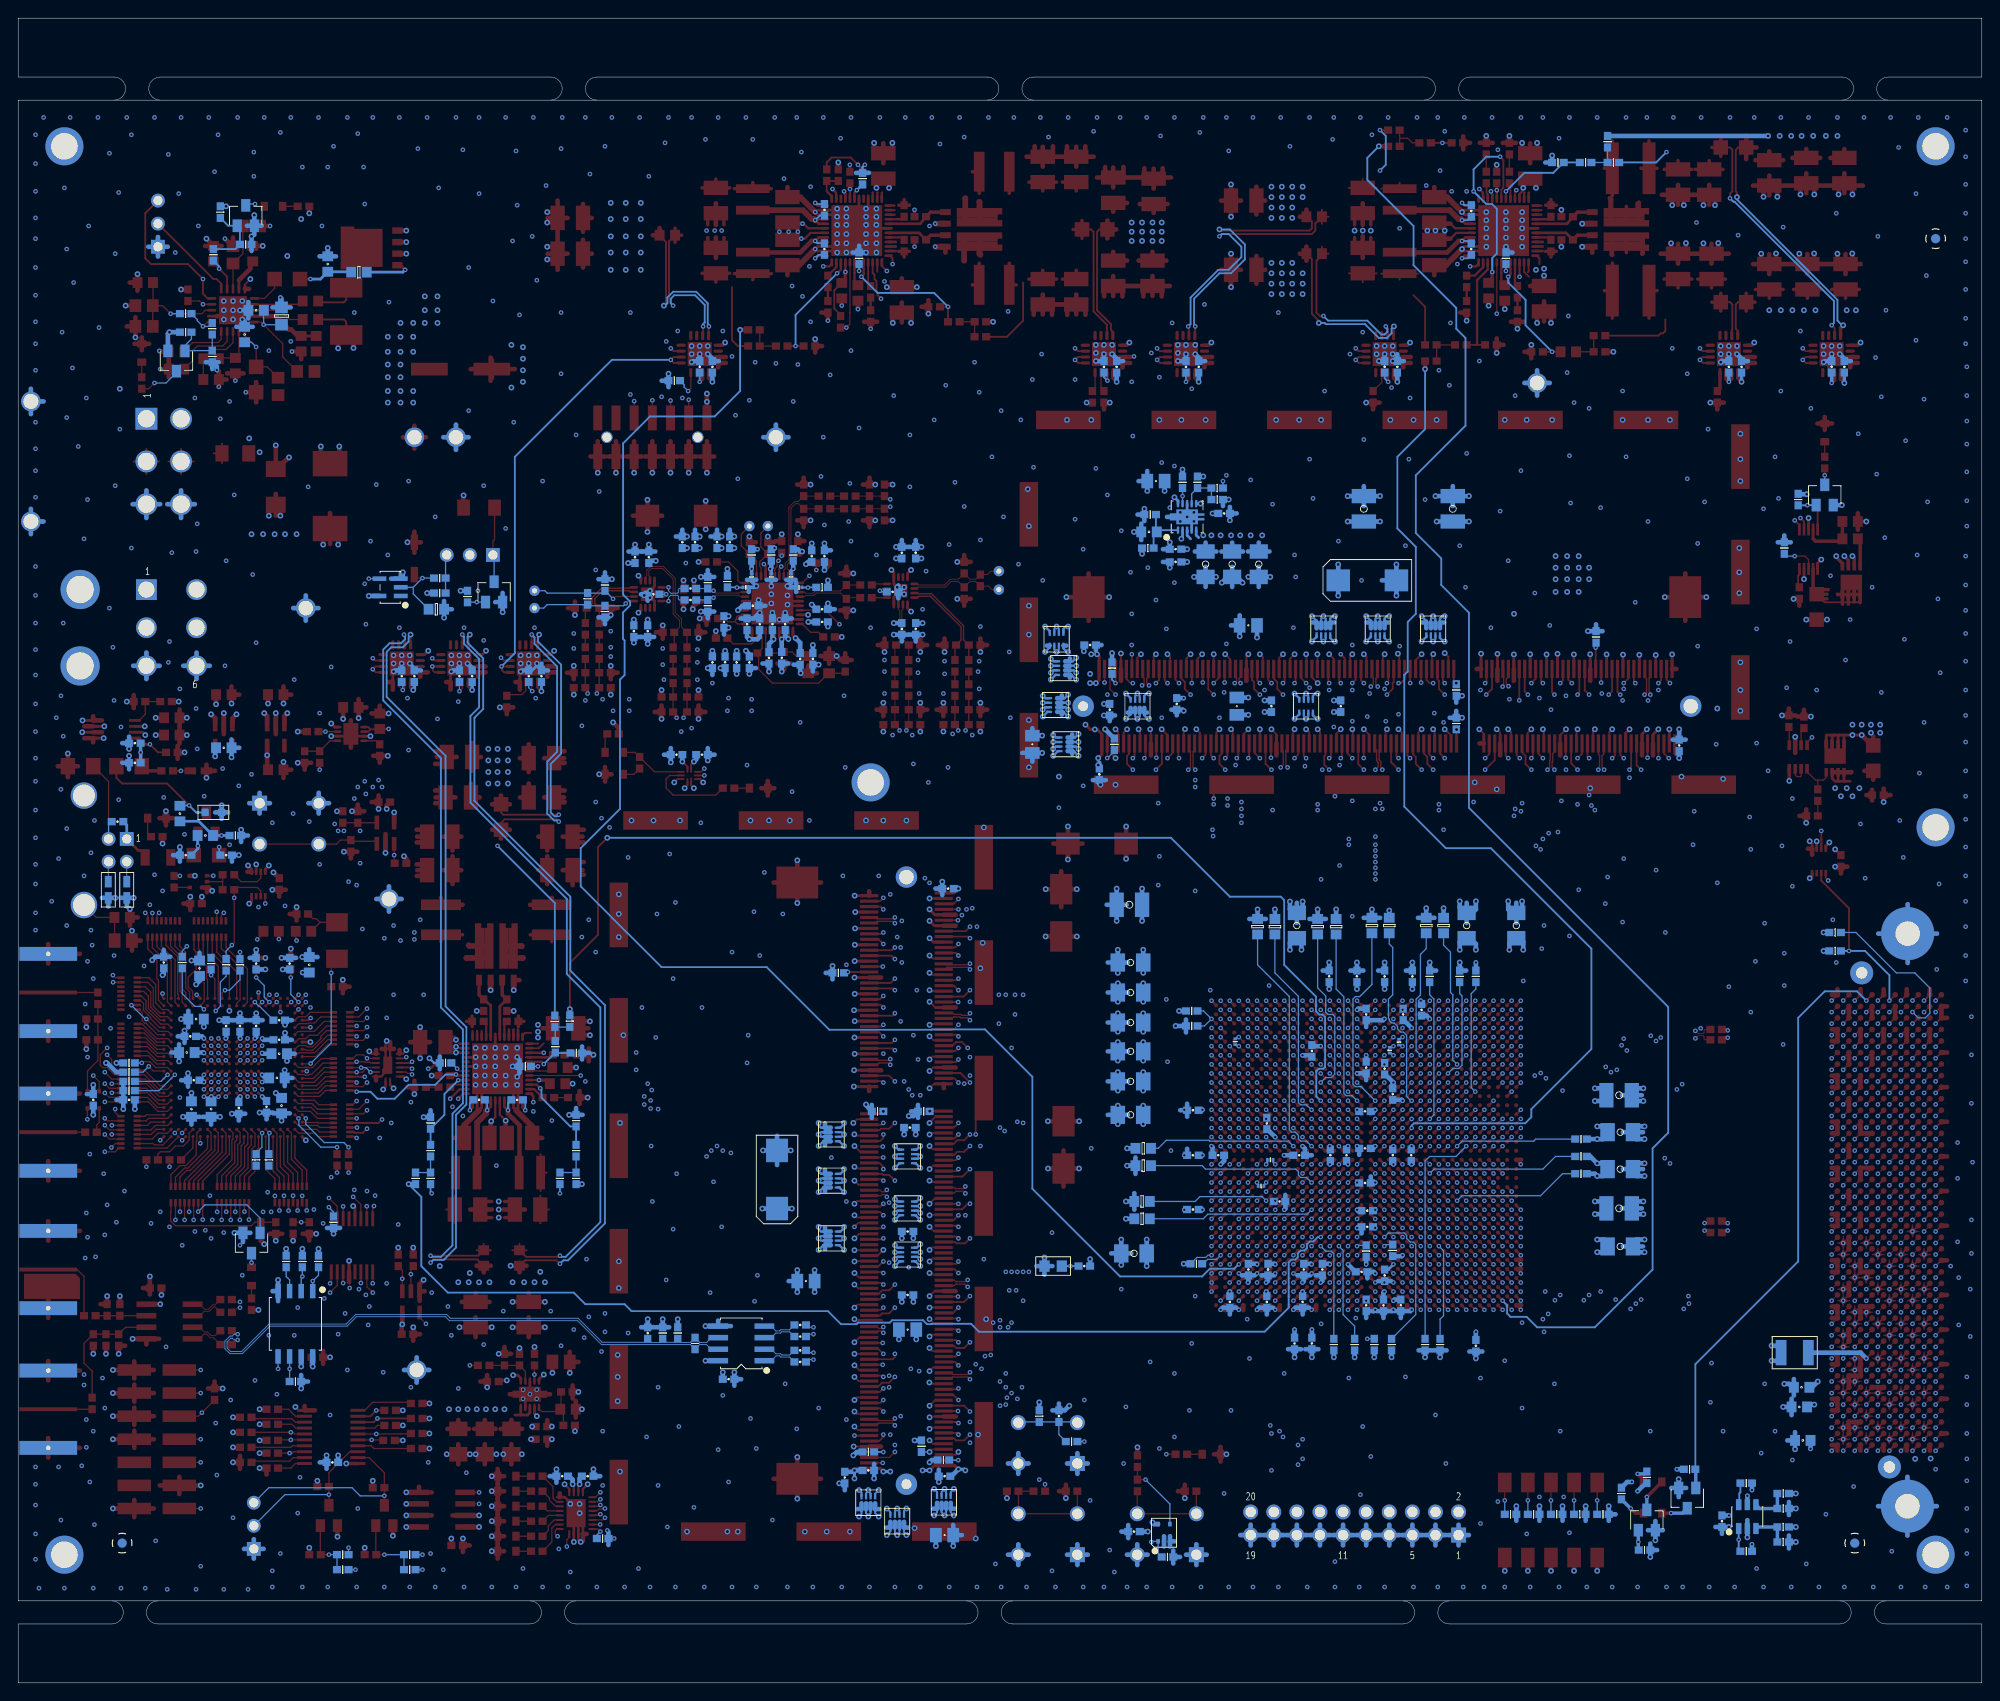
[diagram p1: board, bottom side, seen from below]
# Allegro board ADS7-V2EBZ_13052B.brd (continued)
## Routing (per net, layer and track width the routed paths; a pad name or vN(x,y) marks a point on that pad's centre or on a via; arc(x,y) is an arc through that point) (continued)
DATA4: length 167.6
  TOP w0.14: v1(206.38,65.91) 205.87,65.41 RN12.12 ; v1(80.69,73.04) U31.AK32
  L5_SIGNAL w0.095: v1(206.38,65.91) 205.99,65.53 205.99,64.52 205.73,64.25 205.73,62.98 205.23,62.48 203.58,62.48 201.3,60.2 200.15,60.2 198.88,58.93 198.37,58.93 197.61,58.17 188.09,58.17 185.29,60.96 184.28,60.96 182.12,63.12 182.12,78.61 181.07,79.66 157.78,79.66 157.69,79.76 146.68,79.76 133.47,92.96 111.51,92.96 105.73,87.19 105.73,86.15 101.24,81.66 99.71,81.66 99.69,81.64 99.31,81.64 99.29,81.66 88.14,81.66 85.47,78.99 85.47,75.06 84.07,73.66 81.28,73.66 80.69,73.07 v1(80.69,73.04)
DATA5: length 163.5
  TOP w0.14: v1(80.69,74.04) U31.AK33 ; RN12.11 v1(205.6,64.91)
  L5_SIGNAL w0.095: v1(205.6,64.91) 203.97,64.91 199.14,60.07 197.61,60.07 197.23,59.69 197.23,59.31 196.85,58.93 188.34,58.93 185.8,61.47 185.8,62.23 185.42,62.61 184.02,62.61 182.63,64.01 182.63,78.99 181.51,80.11 157.97,80.11 156.66,81.41 145.84,81.41 133.71,93.54 110.95,93.54 105.03,87.61 105.03,87 101.47,83.43 97.29,83.43 96.15,82.3 86.87,82.3 84.2,79.63 84.2,77.22 83.19,76.2 83.19,74.93 82.68,74.42 81.15,74.42 80.77,74.04 v1(80.69,74.04)
DATA6: length 164.2
  TOP w0.14: RN12.10 205.89,64.41 v1(206.38,64.9) ; v1(82.69,73.04) U31.AM32
  L5_SIGNAL w0.095: v1(206.38,64.9) 206.38,64.56 205.95,64.14 205.95,62.82 205.36,62.23 203.71,62.23 201.23,59.75 200.91,59.75 199.84,58.67 198.63,58.67 197.74,57.78 187.96,57.78 185.04,60.71 184.02,60.71 181.86,62.87 181.86,78.49 180.91,79.44 157.69,79.44 157.63,79.5 146.57,79.5 133.37,92.71 111.8,92.71 105.95,86.86 105.95,86.01 101.35,81.41 89.28,81.41 87,79.12 87,76.2 84.2,73.41 83.06,73.41 v1(82.69,73.04)
DATA7: length 162.3
  TOP w0.14: RN12.9 v1(206.38,63.91) ; v1(83.69,73.04) U31.AN32
  L5_SIGNAL w0.095: v1(206.38,63.91) 206.38,62.74 205.61,61.98 203.96,61.98 200.41,58.42 198.88,58.42 197.87,57.4 187.83,57.4 184.78,60.45 183.77,60.45 181.61,62.61 181.61,77.34 179.74,79.22 157.6,79.22 157.56,79.25 146.51,79.25 133.27,92.49 112.18,92.49 106.17,86.48 106.17,84.23 101.95,80.01 89.28,80.01 87.63,78.36 87.63,76.2 84.82,73.39 84.54,73.39 84.19,73.04 v1(83.69,73.04)
DATA8: length 161.1
  TOP w0.14: RN5.16 204.82,62.33 205.23,62.74 v1(205.23,63.12) ; v1(82.69,74.04) U31.AM33
  L5_SIGNAL w0.095: v1(82.69,74.04) 83.19,74.04 83.54,74.39 83.66,74.39 84.2,74.93 84.2,76.58 84.84,77.22 84.84,79.25 87.5,81.92 96.31,81.92 97.2,82.8 101.6,82.8 105.41,86.61 105.41,87.5 111.12,93.22 133.58,93.22 145.64,81.15 156.6,81.15 157.87,79.88 181.36,79.88 182.37,78.87 182.37,63.25 184.4,61.21 185.55,61.21 188.21,58.55 197.36,58.55 197.99,59.18 198.63,59.18 199.9,60.45 201.17,60.45 203.71,62.99 203.71,63.37 203.96,63.63 204.72,63.63 v1(205.23,63.12)
DATA9: length 161.5
  TOP w0.14: v1(84.69,71.04) U31.AP30 ; RN5.15 206.1,61.83 206.38,62.1 v1(206.38,62.1)
  L5_SIGNAL w0.095: v1(206.38,62.1) 206.38,62.1 206.88,61.59 206.88,59.82 206.5,59.44 205.23,59.44 201.3,55.5 186.44,55.5 180.09,61.85 180.09,74.93 177.04,77.98 145.4,77.98 136.13,87.25 129.54,87.25 125.84,90.95 113.44,90.95 108.59,86.09 108.59,84.06 102.88,78.36 97.03,78.36 96.2,77.53 91.76,77.53 90.39,76.17 89.76,76.17 86.11,72.52 86.11,71.37 85.77,71.04 v1(84.69,71.04)
DATA10: length 157.3
  TOP w0.14: v1(84.69,72.04) U31.AP31 ; RN5.14 v1(205.6,61.33)
  L5_SIGNAL w0.095: v1(205.6,61.33) 205.59,61.34 204.85,61.34 201.42,57.91 199.52,57.91 198.25,56.64 186.69,56.64 184.11,59.22 184.08,59.22 180.97,62.33 180.97,75.56 177.8,78.74 146.08,78.74 133,91.82 112.87,91.82 107.57,86.52 107.57,84.48 102.46,79.38 90.42,79.38 88.52,77.47 88.52,76.2 85.34,73.03 85.34,72.52 84.87,72.04 v1(84.69,72.04)
DATA11: length 165.1
  TOP w0.14: v1(79.69,71.04) U31.AJ30 ; RN5.13 205.86,60.83 v1(206.38,61.34)
  L5_SIGNAL w0.095: v1(206.38,61.34) 206.38,60.93 206.02,60.58 206.02,60.1 205.87,59.94 203.96,59.94 201.68,57.66 201.3,57.66 199.9,56.26 186.69,56.26 180.59,62.36 180.59,75.44 177.55,78.49 145.92,78.49 132.84,91.57 112.98,91.57 107.82,86.41 107.82,84.38 102.57,79.12 90.55,79.12 88.77,77.34 88.77,76.07 85.6,72.9 85.6,72.26 85.34,72.01 85.19,72.01 85.09,71.91 85.09,71.88 84.84,71.63 82.93,71.63 82.69,71.39 80.15,71.39 79.8,71.04 v1(79.69,71.04)
DATA12: length 164.3
  TOP w0.14: v1(80.69,72.04) U31.AK31 ; RN5.12 v1(205.61,60.33)
  L5_SIGNAL w0.095: v1(80.69,72.04) 80.69,72.05 81.15,72.52 84.74,72.52 84.84,72.61 84.84,72.64 85.09,72.9 85.09,73.15 88.01,76.07 88.01,77.85 89.79,79.63 102.11,79.63 106.55,84.07 106.55,86.07 112.69,92.2 133.1,92.2 146.3,78.99 179.58,78.99 181.36,77.22 181.36,62.48 183.64,60.2 184.53,60.2 187.71,57.02 198.12,57.02 199.26,58.17 200.66,58.17 204.22,61.72 205.74,61.72 205.99,61.47 205.99,61.09 205.61,60.71 205.61,60.33 v1(205.61,60.33)
DATA13: length 160.4
  TOP w0.14: RN5.11 205.88,59.83 v1(206.38,60.33) ; v1(83.69,71.04) U31.AN30
  L5_SIGNAL w0.095: v1(206.38,60.33) 206.38,59.94 206.12,59.69 204.34,59.69 201.93,57.28 201.55,57.28 200.15,55.88 186.56,55.88 180.34,62.1 180.34,75.18 177.29,78.23 145.69,78.23 132.73,91.19 113.14,91.19 108.2,86.25 108.2,84.22 102.72,78.74 90.81,78.74 89.53,77.47 89.53,76.45 85.85,72.77 85.85,71.76 85.49,71.39 84.22,71.39 83.87,71.04 v1(83.69,71.04)
DATA14: length 162.2
  TOP w0.14: v1(205.65,58.89) 205.21,59.33 RN5.10 ; v1(79.69,70.04) U31.AJ29
  L5_SIGNAL w0.095: v1(79.69,70.04) 80.27,70.61 84.93,70.61 85.98,70.61 86.49,71.12 86.49,72.01 87.88,73.41 88.65,73.41 91.69,76.45 95.76,76.45 97.28,77.98 103.04,77.98 108.97,83.9 108.97,85.94 113.45,90.42 115.24,90.42 115.26,90.45 118.98,90.45 119,90.42 125.83,90.42 129.25,87 135.84,87 145.24,77.6 177.04,77.6 179.83,74.8 179.83,61.59 186.31,55.12 202.18,55.12 205.65,58.59 v1(205.65,58.89)
DATA15: length 162.2
  TOP w0.14: RN5.9 204.82,58.83 205.23,58.42 v1(206.38,58.42) ; v1(80.69,70.04) U31.AK29
  L5_SIGNAL w0.095: v1(80.69,70.04) 80.71,70.04 81.06,70.39 84.84,70.39 84.87,70.36 86.11,70.36 86.74,70.99 86.74,71.5 88.39,73.15 88.9,73.15 91.69,75.95 95.89,75.95 97.66,77.72 103.15,77.72 109.22,83.8 109.22,85.83 113.56,90.17 115.3,90.17 115.35,90.22 118.89,90.22 118.94,90.17 125.77,90.17 129.19,86.75 135.73,86.75 145.14,77.34 176.78,77.34 179.58,74.55 179.58,61.34 186.18,54.74 202.69,54.74 v1(206.38,58.42)
DDR1_PWRGD_1P8: length 155.5
  TOP w0.14: RN10.10 v1(191.03,51.84)
  L18_SIGNAL w0.095: v1(191.03,51.84) 190.29,52.58 183.39,52.58 182.12,53.85 180.85,53.85 180.09,53.09 177.67,53.09 171.7,59.06 154.31,59.06 150.18,63.18 v1(146.37,63.18)
  L20_SIGNAL w0.095: v1(146.37,63.18) 126.11,83.44 126.11,101.22 118.63,108.7 118.63,118.36 118.11,118.87 112.93,118.87 112.84,118.79 107.53,118.79 100.71,125.6 96.77,125.6 92.58,129.79 88.14,129.79 87.88,130.05 87.88,130.55 v1(87.88,130.56)
  BOTTOM w0.14: R557.1 87.88,131.44 v1(87.88,130.56) U39.9
DDR2_PWRGD_1P8: length 45.8
  TOP w0.14: RN10.9 v1(190.53,50.95) ; R123.1 159.14,34.92 v1(159.14,33.91) U35.9
  L22_SIGNAL w0.095: v1(159.14,33.91) 160.03,34.8 163.7,34.8 164.47,34.04 168.02,34.04 171.32,37.34 173.48,37.34 175.83,39.69 175.83,45.02 179.2,48.39 184.4,48.39 185.42,49.4 186.31,49.4 187.86,50.95 v1(190.53,50.95)
DDR3-1_ADDR00: length 68.3
  TOP w0.197: v1(66.69,72.04) U31.U31 ; v1(65.41,109.98) 65.25,110.13 P6.98
  L9_SIGNAL w0.14: v1(65.41,109.98) 66.04,110.62 66.04,112.85 66.15,112.95 66.15,113.36 66.04,113.47 66.04,114.24 65.93,114.35 65.93,114.76 66.04,114.86 66.04,117.04 65.93,117.15 65.93,117.55 66.04,117.66 66.04,122.05 65.79,122.3 65.28,122.3 65.02,122.05 65.02,118.87 64.77,118.62 64.77,117.66 64.66,117.55 64.66,117.15 64.77,117.04 64.77,114.86 64.66,114.76 64.66,114.35 64.77,114.24 64.77,107.95 67.18,105.54 67.18,99.82 67.95,99.06 67.95,73.41 66.69,72.15 v1(66.69,72.04)
DDR3-1_ADDR01: length 71.8
  TOP w0.197: v1(64.14,100.46) 64.95,101.28 P6.97 ; v1(64.69,73.04) U31.R32
  L9_SIGNAL w0.14: v1(64.14,100.46) 63.37,101.22 63.37,117.73 63.12,117.98 62.48,117.98 62.23,117.73 62.23,101.22 64.14,99.31 64.14,84.84 67.44,81.53 67.44,74.17 66.67,73.41 65.85,73.41 65.85,73.41 65.07,73.41 v1(64.69,73.04)
DDR3-1_ADDR02: length 69.4
  TOP w0.197: v1(65.69,72.04) U31.T31 ; P6.96 64.65,110.1 64.77,109.98 64.77,109.35 v1(65.41,108.71)
  L7_SIGNAL w0.14: v1(65.69,72.04) 66.55,72.9 66.55,73.65 66.32,73.88 66.32,75.19 66.55,75.43 66.55,83.69 73.53,90.68 73.53,96.39 73.28,96.65 v1(73.03,96.65)
  L16_SIGNAL w0.14: v1(65.41,108.71) 66.29,107.82 69.22,107.82 71.75,105.28 71.75,102.74 71.12,102.11 71.12,99.44 72.01,98.55 73.03,98.55 73.66,99.19 73.66,106.81 73.91,107.06 74.68,107.06 74.93,106.81 74.93,99.57 73.03,97.66 v1(73.03,96.65)
DDR3-1_ADDR03: length 65.1
  TOP w0.197: P6.95 64.35,101.95 v1(64.14,101.73) ; v1(61.69,72.04) U31.M31
  L22_SIGNAL w0.14: v1(64.14,101.73) 64.62,102.22 64.62,107.46 63.37,108.71 63.37,110.24 62.36,111.25 62.36,116.59 62.1,116.84 61.34,116.84 61.09,116.59 61.09,86.74 61.72,86.11 61.72,84.45 61.21,83.95 61.21,72.52 v1(61.69,72.04)
DDR3-1_ADDR04: length 69.5
  TOP w0.197: P6.92 63.46,110.41 63.88,109.98 v1(64.14,109.98) ; v1(61.69,71.04) U31.M30
  L22_SIGNAL w0.14: v1(64.14,109.98) 63.5,110.62 63.5,120.65 62.99,121.16 60.2,121.16 59.69,120.65 59.69,112.9 60.71,111.89 60.71,108.33 59.69,107.31 59.69,99.7 60.2,99.19 60.2,71.88 60.58,71.5 61.21,71.5 61.68,71.04 v1(61.69,71.04)
DDR3-1_ADDR05: length 65.9
  TOP w0.197: P6.91 63.16,102.02 v1(62.87,101.73) ; v1(62.69,71.04) U31.N30
  L22_SIGNAL w0.14: v1(62.87,101.73) 63.25,101.35 63.25,99.57 62.61,98.93 62.61,95.4 62.46,95.25 62.25,95.25 62.1,95.4 62.1,99.06 62.74,99.7 62.74,100.71 61.98,101.47 61.98,103.38 62.74,104.14 62.74,105.92 62.48,106.17 62.48,109.22 62.23,109.47 61.72,109.47 61.47,109.22 61.47,105.79 62.1,105.16 62.1,104.14 61.59,103.63 61.59,101.35 62.1,100.84 62.1,99.95 61.59,99.44 61.59,87 62.48,86.11 62.48,83.82 61.98,83.31 61.98,78.23 62.23,77.98 62.23,76.64 62.12,76.53 62.12,71.74 62.69,71.17 v1(62.69,71.04)
DDR3-1_ADDR06: length 70.3
  TOP w0.197: v1(62.69,70.04) U31.N29 ; P6.90 v1(62.86,109.99)
  L3_SIGNAL w0.14: v1(62.86,109.99) 62.87,110 62.87,110.62 62.61,110.87 62.61,122.93 62.87,123.19 63.24,123.19 63.5,122.93 63.5,109.47 62.86,108.83 62.86,106.82 63.63,106.05 63.63,75.95 63.25,75.56 63.25,70.59 v1(62.69,70.04)
DDR3-1_ADDR07: length 66.7
  TOP w0.197: P6.86 v1(61.65,110.04) ; v1(63.69,67.04) U31.P26
  L16_SIGNAL w0.14: v1(61.65,110.04) 62.36,110.74 62.36,118.49 62.61,118.75 63.12,118.75 63.37,118.49 63.37,109.22 62.23,108.08 62.23,98.42 65.28,95.38 65.28,88.01 65.66,87.63 65.66,84.33 65.15,83.82 65.15,67.82 64.75,67.41 64.54,67.41 64.16,67.04 v1(63.69,67.04)
DDR3-1_ADDR08: length 69.6
  TOP w0.197: P6.89 62.56,102.18 62.23,101.85 62.23,101.09 v1(61.59,100.46) ; v1(65.69,66.04) U31.T25
  L5_SIGNAL w0.14: v1(61.59,100.46) 62.48,101.35 62.48,109.83 62.48,109.84 62.48,110.15 62.48,110.15 62.48,114.68 62.74,114.94 63.25,114.94 63.5,114.68 63.5,101.22 63.25,100.97 63.25,77.85 65.15,75.95 65.15,66.55 65.66,66.04 v1(65.69,66.04)
DDR3-1_ADDR09: length 72.5
  TOP w0.197: P6.85 61.35,102.25 60.96,101.85 60.96,101.09 v1(60.33,100.46) ; v1(65.69,65.04) U31.T24
  L5_SIGNAL w0.14: v1(65.69,65.04) 65.14,65.04 64.26,65.91 64.26,76.2 61.98,78.49 61.98,98.81 60.96,99.82 60.96,114.94 60.71,115.19 60.2,115.19 59.69,114.68 59.69,100.71 59.94,100.46 v1(60.33,100.46)
DDR3-1_ADDR10: length 66.6
  TOP w0.197: v1(63.69,66.04) U31.P25 ; P6.107 v1(67.95,101.74)
  L16_SIGNAL w0.14: v1(67.95,101.74) 68.45,102.23 68.45,106.93 68.2,107.19 67.44,107.19 67.18,106.93 67.18,98.93 66.8,98.55 65.91,98.55 65.53,98.93 65.53,104.01 65.28,104.27 64.9,104.27 64.64,104.01 64.64,98.93 67.18,96.39 67.18,95.38 66.17,94.36 66.17,67.18 65.53,66.55 64.26,66.55 63.75,66.04 v1(63.69,66.04)
DDR3-1_ADDR11: length 70.2
  TOP w0.197: P6.84 61.05,110.33 60.71,109.98 v1(60.33,109.98) ; v1(63.69,65.04) U31.P24
  L3_SIGNAL w0.14: v1(60.33,109.98) 59.69,110.62 59.69,119.52 60.06,119.89 60.59,119.89 60.96,119.52 60.96,110.74 60.81,110.6 60.81,100.42 60.58,100.18 60.58,84.07 61.47,83.19 61.47,78.36 62.23,77.6 62.23,76.64 62.12,76.53 62.12,68.18 62.32,67.99 62.32,67.88 62.54,67.66 62.64,67.66 63.32,66.99 63.32,65.88 63.69,65.51 v1(63.69,65.04)
DDR3-1_ADDR12: length 66.6
  TOP w0.197: v1(62.69,69.04) U31.N28 ; v1(60.33,101.73) 60.76,102.16 P6.83
  L16_SIGNAL w0.14: v1(62.69,69.04) 62.82,69.04 63.25,69.47 63.88,69.47 64.26,69.85 64.26,94.11 61.09,97.28 61.09,115.32 60.83,115.57 59.94,115.57 59.69,115.32 59.69,102.36 v1(60.33,101.73)
DDR3-1_ADDR13: length 66.3
  TOP w0.197: v1(71.75,101.73) 71.56,101.93 P6.119 ; v1(62.69,68.04) U31.N27
  L20_SIGNAL w0.14: v1(62.69,68.04) 63.32,67.41 63.32,66.88 63.54,66.66 64.07,66.66 64.31,66.42 67.06,66.42 67.58,66.94 67.58,68.39 68.07,68.88 68.07,69.19 67.56,69.7 67.56,75.18 66.8,75.95 66.8,82.93 68.96,85.09 68.96,90.55 70.48,92.08 70.48,95.38 70.1,95.76 70.1,104.59 70,104.7 70,105.1 70.1,105.21 70.1,111.25 70.36,111.51 70.87,111.51 71.12,111.25 71.12,108.99 71.75,108.36 v1(71.75,101.73)
DDR3-1_ADDR14: length 67.6
  TOP w0.197: v1(59.05,108.71) 59.69,109.35 59.69,110.24 59.86,110.4 P6.80 ; v1(62.69,66.04) U31.N25
  L22_SIGNAL w0.14: v1(62.69,66.04) 62.69,66.25 63.12,66.67 63.12,68.14 62.85,68.41 62.65,68.41 62.07,69 62.07,69.19 61.85,69.41 61.65,69.41 61.07,70 61.07,70.19 60.85,70.41 60.65,70.41 60.2,70.87 60.2,71.12 60.14,71.12 59.85,71.41 59.65,71.41 59.18,71.88 59.18,78.68 59.54,79.05 59.54,79.45 59.18,79.81 59.18,82.04 58.55,82.68 58.55,102.87 57.29,104.13 57.29,104.65 57.27,104.67 57.27,105.4 57.91,106.05 57.91,106.55 59.82,108.46 59.82,112.01 59.56,112.27 58.67,112.27 58.42,112.52 58.42,115.26 58.23,115.44 57.97,115.44 57.79,115.26 57.79,111.76 58.04,111.51 59.18,111.51 59.44,111.25 59.44,108.97 59.18,108.71 v1(59.05,108.71)
DDR3-1_ADDR15: length 66.5
  TOP w0.197: v1(62.69,65.04) U31.N24 ; P6.78 59.25,110.18 v1(59.05,109.98)
  L22_SIGNAL w0.14: v1(59.05,109.98) 59.05,110.49 58.8,110.74 57.66,110.74 57.4,111 57.4,116.97 57.15,117.22 56.9,117.22 56.64,116.97 56.64,104.01 57.91,102.74 57.91,82.04 58.32,81.64 58.32,71.88 58.54,71.66 58.64,71.66 59.31,70.99 59.31,70.61 60.51,69.41 60.85,69.41 61.07,69.19 61.07,68.88 61.54,68.41 61.85,68.41 62.07,68.19 62.07,65.82 62.23,65.66 62.69,65.2 v1(62.69,65.04)
DDR3-1_BA0: length 71
  TOP w0.197: P6.109 68.56,101.07 v1(67.95,100.46) ; v1(62.69,74.04) U31.N33
  L22_SIGNAL w0.14: v1(67.95,100.46) 67.44,100.97 66.29,100.97 66.04,101.22 66.04,103.51 66.8,104.27 66.8,109.98 66.55,110.24 66.55,112.14 66.29,112.39 65.66,112.39 65.41,112.14 65.41,111 66.13,110.27 66.13,109.84 66.05,109.76 66.05,104.4 65.41,103.76 65.41,100.08 63.63,98.3 63.63,88.01 63.5,87.88 63.12,87.88 62.99,88.01 62.99,93.16 62.81,93.34 62.54,93.34 62.36,93.16 62.36,87.5 63.63,86.23 63.63,76.07 63.25,75.69 63.25,74.55 62.74,74.04 v1(62.69,74.04)
DDR3-1_BA1: length 65.2
  TOP w0.197: P6.108 68.25,110.29 v1(67.95,109.98) ; v1(62.69,75.04) U31.N34
  L22_SIGNAL w0.14: v1(62.69,75.04) 62.69,75.65 63.12,76.07 63.12,86.11 61.98,87.25 61.98,94.23 63.12,95.38 63.12,98.68 65.02,100.58 65.02,104.59 64.92,104.7 64.92,105.1 65.02,105.21 65.02,113.79 64.52,114.3 64.52,117.86 65.02,118.36 65.02,121.41 65.28,121.67 66.67,121.67 66.93,121.41 66.93,116.08 67.06,115.95 67.06,110.87 v1(67.95,109.98)
DDR3-1_BA2: length 66.3
  TOP w0.197: v1(66.69,74.04) U31.U33 ; v1(59.05,101.73) 59.56,102.23 P6.79
  L9_SIGNAL w0.14: v1(66.69,74.04) 66.68,74.04 66.17,74.55 66.17,81.03 62.23,84.96 62.23,96.39 61.98,96.65 v1(59.69,96.65)
  L18_SIGNAL w0.14: v1(59.69,96.65) 59.69,99.19 59.31,99.57 59.05,99.57 58.67,99.19 58.67,94.19 58.34,93.85 57.87,93.85 57.53,94.19 57.53,99.31 57.15,99.7 56.39,99.7 56.01,100.08 56.01,107.44 56.39,107.82 58.04,107.82 58.42,107.44 58.42,100.71 58.8,100.33 59.31,100.33 59.69,100.71 59.69,101.09 v1(59.05,101.73)
DDR3-1_CASB: length 65.5
  TOP w0.197: v1(70.48,101.73) 70.35,101.86 P6.115 ; v1(64.69,74.04) U31.R33
  L7_SIGNAL w0.14: v1(66.67,89.66) 68.2,89.66 71.85,93.32 71.85,98.58 71.12,99.31 71.12,100.71 71.5,101.09 73.66,101.09 73.91,100.84 73.91,94.49 74.17,94.23 74.68,94.23 74.93,94.49 74.93,107.06 74.68,107.31 72.26,107.31 72.01,107.06 72.01,103.25 v1(70.48,101.73)
  L22_SIGNAL w0.14: v1(64.69,74.04) 64.69,84.73 64.66,84.76 64.66,87.65 v1(66.67,89.66)
DDR3-1_CK0_N: length 81.3
  TOP w0.152: P6.103 66.76,102.82 66.55,102.62 66.55,101.51 66.54,101.51 66.54,101.43 66.37,101.26 66.37,101.24 66.37,100.76 v1(66.67,100.46) ; v1(65.69,71.04) U31.T30
  L3_SIGNAL w0.127: v1(65.69,71.04) 66.07,70.66 66.84,70.66 67.31,71.13 67.31,78.49 65.77,80.03 65.77,94.47 66.17,94.87 66.17,95.89 v1(65.91,96.14)
  L5_SIGNAL w0.13: v1(65.91,96.14) 66.16,95.9 66.16,95.64 66.55,95.25 66.87,95.25 68.71,95.25 69.98,96.52 69.98,117.45 69.57,117.86 68.88,117.86 68.47,117.45 68.47,108.69 68.22,108.44 68.22,107.44 68.47,107.19 68.47,106.66 68.2,106.38 68.2,105.54 68.47,105.26 68.47,99.7 67.97,99.19 66.78,99.19 66.42,99.55 66.42,100.2 v1(66.67,100.46)
DDR3-1_CK0_P: length 80.8
  TOP w0.127: v1(65.69,70.04) U31.T29
  TOP w0.152: v1(65.91,100.46) 66.09,100.63 66.09,101.12 66.09,101.38 66.26,101.55 66.26,101.62 66.27,101.63 66.27,102.62 66.16,102.73 P6.101
  L3_SIGNAL w0.127: v1(66.67,96.14) 66.42,95.89 66.42,94.76 66.02,94.37 66.02,80.13 67.56,78.59 67.56,71.02 66.95,70.41 66.06,70.41 v1(65.69,70.04)
  L5_SIGNAL w0.13: v1(65.91,100.46) 66.16,100.21 66.16,99.44 66.67,98.93 68.07,98.93 68.73,99.59 68.73,105.37 68.45,105.64 68.45,106.27 68.73,106.55 68.73,107.29 68.48,107.55 68.48,108.33 68.73,108.59 68.73,117.35 68.99,117.6 69.47,117.6 69.72,117.35 69.72,96.63 68.6,95.51 66.76,95.51 66.65,95.51 66.41,95.75 66.41,95.88 v1(66.67,96.14)
DDR3-1_CK1_N: length 82.2
  TOP w0.152: P6.104 67.05,110.74 66.89,110.58 66.9,110.56 66.9,109.88 v1(67.18,109.6) ; v1(63.69,72.04) U31.P31
  L3_SIGNAL w0.127: v1(67.18,109.6) 66.93,109.86 66.93,114.02 67.16,114.25 67.16,114.86 66.93,115.09 66.93,116.59 66.67,116.84 64.9,116.84 64.64,116.59 64.64,115.09 64.41,114.86 64.41,114.25 64.64,114.02 64.64,113.81 64.9,113.56 64.9,112.63 64.64,112.37 64.64,108.23 65.05,107.82 66.54,107.82 66.65,107.72 66.65,106.13 66.65,106.13 66.65,105.92 66.65,105.92
  L3_SIGNAL w0.13: 66.65,105.92 66.65,104.36 66.65,104.36 66.65,104.15 66.67,104.13 66.67,103.39 67.07,102.99 68.1,102.99 68.51,102.57 68.51,92.76 68.21,92.46 67.78,92.46 67.47,92.76 67.47,101.09 66.96,101.6 65.24,101.6 64.64,101 64.64,86.97 64.13,86.47 64.13,74.73 64.06,74.66 64.06,72.41 v1(63.69,72.04)
DDR3-1_CK1_P: length 81.3
  TOP w0.127: v1(64.69,72.04) U31.R31
  TOP w0.152: P6.102 66.46,110.62 66.61,110.46 66.62,110.45 66.62,109.8 v1(66.42,109.6)
  L3_SIGNAL w0.127: v1(66.42,109.6) 66.67,109.86 66.67,114.13 66.9,114.35 66.9,114.75 66.67,114.98 66.67,116.48 66.57,116.59 65,116.59 64.9,116.48 64.9,114.98 64.67,114.75 64.67,114.35 64.9,114.13 64.9,113.92 65.15,113.67 65.15,112.52 64.9,112.27 64.9,108.33 65.15,108.08 66.65,108.08 66.9,107.82 66.9,106.03
  L3_SIGNAL w0.13: v1(64.69,72.04) 64.32,72.41 64.32,74.55 64.39,74.62 64.39,86.36 64.9,86.87 64.9,100.89 65.35,101.34 66.86,101.34 67.21,100.99 67.21,92.66 67.67,92.2 68.31,92.2 68.77,92.66 68.77,102.68 68.21,103.24 67.17,103.24 66.92,103.49 66.92,104.24 66.9,104.25 66.9,106.02 66.9,106.03
DDR3-1_CKE0: length 69.6
  TOP w0.197: P6.73 v3(57.76,104.87) ; v1(64.69,67.04) U31.R26
  L20_SIGNAL w0.14: v1(64.69,67.04) 65.09,67.44 66.55,67.44 66.78,67.66 66.85,67.66 67.31,68.13 67.31,69.22 67.06,69.47 65.79,69.47 65.59,69.66 65.54,69.66 65.32,69.88 65.32,74 65.02,74.3 65.02,83.19 63.5,84.71 63.5,102.49 63.88,102.87 64.39,102.87 64.77,103.25 64.77,113.54 64.52,113.79 64.52,114.94 64.26,115.19 63.75,115.19 63.5,114.94 63.5,109.73 62.99,109.22 62.1,109.22 v3(57.76,104.87)
DDR3-1_CKE1: length 69.2
  TOP w0.197: v3(57.79,109.98) 58.06,110.25 P6.74 ; v1(66.69,68.04) U31.U27
  L20_SIGNAL w0.14: v3(57.79,109.98) 57.79,117.86 58.04,118.11 59.44,118.11 59.69,117.86 59.69,108.46 57.79,106.55 57.79,105.92 57.27,105.4 57.27,104.66 59.82,102.1 60.48,102.1 60.73,101.85 61.98,101.85 62.99,100.84 62.99,84.45 64.39,83.06 64.39,74.27 64.32,74.19 64.32,68.88 64.54,68.66 64.56,68.66 64.77,68.45 66.28,68.45 v1(66.69,68.04)
DDR3-1_CLK_REF_N: length 78.2
  TOP w0.102: v1(118.24,104.78) 118.24,105.16 R116.1 R102.2 C77.2
  TOP w0.127: v1(63.69,71.04) U31.P30
  L18_SIGNAL w0.089: v1(63.69,71.04) 64.11,70.62 66.93,70.62 67.18,70.87 67.18,76.51 74.59,83.91 80.55,83.91 94.52,97.88 112.56,97.88 118.53,103.85 118.53,104.48 v1(118.24,104.78)
  BOTTOM w0.102: R626.2 63.93,70.8 v1(63.69,71.04)
DDR3-1_CLK_REF_P: length 78.6
  TOP w0.102: R117.1 R103.1 C78.2
  TOP w0.127: v1(63.69,70.04) U31.P29
  TOP w0.14: v1(119,104.78) 119,104.9 R117.1
  L18_SIGNAL w0.089: v1(63.69,70.04) 64.05,70.4 66.97,70.4 66.97,70.4 67.02,70.4 67.4,70.78 67.4,70.82 67.4,70.83 67.4,76.42 74.67,83.69 80.64,83.69 94.62,97.66 112.65,97.66 118.75,103.76 118.75,104.52 v1(119,104.78)
  BOTTOM w0.14: v1(63.69,70.04) 63.82,70.17 R626.1
DDR3-1_DM0: length 63.7
  TOP w0.197: v1(60.69,64.04) U31.L23 ; P6.11 v1(36.76,101.78)
  L5_SIGNAL w0.14: v1(60.69,64.04) 60.74,64.04 61.21,64.52 61.21,68.05 60.85,68.41 60.75,68.41 60.58,68.58 59.56,68.58 59.07,69.08 59.07,72.19 58.85,72.41 58.78,72.41 58.17,73.03 58.17,75.82 57.54,76.44 54.62,76.44 51.31,79.76 51.31,88.14 52.2,89.03 52.2,91.34 51.97,91.57 51.66,91.57 51.44,91.34 51.44,90.17 51.18,89.92 50.48,89.92 50.23,90.17 50.23,93.98 49.72,94.49 38.99,94.49 36.83,96.65 36.83,101.7 v1(36.76,101.78)
DDR3-1_DM1: length 63.7
  TOP w0.197: v1(56.69,74.04) U31.G33 ; P6.28 v1(41.85,110.04)
  L7_SIGNAL w0.14: v1(56.69,74.04) 56.39,74.04 56.13,74.29 56.13,77.98 56.52,78.36 56.52,82.3 53.98,84.84 53.98,98.42 52.58,99.82 52.58,103.12 50.29,105.41 49.4,105.41 49.15,105.66 49.15,109.09 48.64,109.6 48.01,109.6 47.62,109.98 47.62,110.49 47.37,110.74 45.85,110.74 45.59,110.49 45.59,109.09 44.45,107.95 40.64,107.95 40.39,108.2 40.39,110.62 40.13,110.87 38.73,110.87 38.48,111.12 38.48,111.89 38.73,112.14 40.26,112.14 40.64,111.76 41.6,111.76 41.85,111.51 v1(41.85,110.04)
DDR3-1_DM2: length 62.3
  TOP w0.197: v1(46.99,108.71) 47.25,108.98 P6.46 ; v1(59.69,69.04) U31.K28
  L16_SIGNAL w0.14: v1(59.69,69.04) 60.07,69.42 60.07,70.1 60.63,70.66 60.85,70.66 61.32,71.13 61.32,71.19 61.54,71.41 61.76,71.41 62.23,71.88 62.23,75.31 61.99,75.55 61.87,75.55 61.23,76.19 61.07,76.19 59.44,77.82 59.44,78.94 59.54,79.05 59.54,80.51 57.04,83.01 57.04,83.04 56.26,83.82 56.26,89.92 52.32,93.85 52.32,96.27 51.44,97.16 51.44,103.38 51.18,103.63 51.18,106.81 50.29,107.7 49.91,107.7 49.02,108.59 49.02,113.54 48.77,113.79 47.5,113.79 47.24,113.54 47.24,108.97 v1(46.99,108.71)
DDR3-1_DM3: length 50
  TOP w0.197: P6.63 52.35,102.01 v1(52.07,101.73) ; v1(59.69,72.04) U31.K31
  L20_SIGNAL w0.14: v1(52.07,101.73) 52.07,103.63 51.82,103.89 51.69,103.89 51.44,104.14 51.44,105.92 51.69,106.17 52.58,106.17 52.83,105.92 52.83,104.14 53.09,103.89 53.09,101.35 52.83,101.09 52.32,101.09 52.07,100.84 52.07,100.58 52.32,100.33 52.83,100.33 53.09,100.08 53.09,99.57 54.1,98.55 54.1,94.55 54.29,94.36 54.55,94.36 54.74,94.55 54.74,95 54.86,95.12 55.37,95.12 56.26,94.23 56.26,92.84 58.42,90.68 58.42,83.95 61.21,81.15 61.21,76.71 60.2,75.69 60.2,72.55 v1(59.69,72.04)
DDR3-1_DM4: length 50.9
  TOP w0.197: P6.136 76.65,110.16 v1(76.84,109.98) ; v1(71.69,74.04) U31.AA33
  L3_SIGNAL w0.14: v1(76.84,109.98) 76.84,110.11 77.72,111 79.63,111 82.68,107.95 82.68,107.44 83.19,106.93 83.19,104.14 83.57,103.76 83.57,95.63 82.55,94.62 v1(81.41,94.62)
  L20_SIGNAL w0.14: v1(81.41,94.62) 81.41,93.09 75.58,87.26 75.58,84.98 71.12,80.52 71.12,77.85 72.39,76.58 72.39,75.82 72.05,75.48 72.05,75.21 72.07,75.19 72.07,74.88 72.05,74.87 72.05,74.47 71.69,74.1 v1(71.69,74.04)
DDR3-1_DM5: length 54.2
  TOP w0.197: v1(72.69,72.04) U31.AB31 ; v1(81.92,101.73) 81.75,101.89 P6.153
  L5_SIGNAL w0.14: v1(81.92,101.73) 81.92,103.51 82.17,103.76 86.23,103.76 86.49,103.51 86.49,101.73 85.98,101.22 85.98,99.83 86.49,99.32 v1(86.49,99.31)
  L16_SIGNAL w0.14: v1(72.69,72.04) 73.17,72.52 73.79,72.52 75.32,74.05 75.32,74.19 75.54,74.41 75.68,74.41 76.2,74.93 76.2,75.44 84.45,83.69 84.45,85.34 84.71,85.6 85.34,85.6 85.6,85.34 85.6,83.95 85.85,83.69 86.23,83.69 88.01,85.47 88.01,99.31 87.5,99.82 86.61,99.82 86.49,99.7 v1(86.49,99.31)
DDR3-1_DM6: length 64.6
  TOP w0.197: P6.170 86.86,109.99 v1(86.87,109.98) ; v1(68.69,70.04) U31.V29
  L7_SIGNAL w0.14: v1(84.52,93.15) 84.52,92.65 76.71,84.84 76.71,83.69 73.66,80.64 73.66,80.26 68.96,75.56 68.45,75.56 68.2,75.31 68.2,70.53 v1(68.69,70.04)
  L9_SIGNAL w0.14: v1(86.87,109.98) 86.49,109.98 86.23,110.24 86.23,115.78 85.94,116.08 85.51,116.08 85.22,115.78 85.22,107.95 87,106.17 87,103.89 85.22,102.11 85.22,93.85 v1(84.52,93.15)
DDR3-1_DM7: length 65.2
  TOP w0.197: v1(92.08,101.73) 91.96,101.85 P6.187 ; v1(70.69,67.04) U31.Y26
  L3_SIGNAL w0.14: v1(92.08,101.73) 92.2,101.85 92.2,104.14 91.95,104.39 87.25,104.39 86.23,103.38 86.23,101.6 85.6,100.97 85.6,95.12 85.85,94.87 85.85,89.53 78.36,82.04 74.55,82.04 73.66,81.15 73.66,80.46 71.96,78.76 71.77,78.76 70.99,77.98 70.1,77.98 69.2,77.07 69.2,76.12 69.09,76.02 69.09,70.87 68.64,70.41 68.54,70.41 68.07,69.94 68.07,68.88 67.97,68.78 67.97,64.88 68.33,64.52 68.96,64.52 69.22,64.77 69.22,65.28 69.47,65.53 69.98,65.53 70.23,65.79 70.23,66.58 v1(70.69,67.04)
DDR3-1_DQ00: length 63.6
  TOP w0.197: v1(59.69,64.04) U31.K23 ; v1(34.42,101.73) 34.95,102.26 P6.5
  L5_SIGNAL w0.14: v1(59.69,64.04) 59.66,64.04 59.07,64.63 59.07,67.19 58.85,67.41 58.7,67.41 58.07,68.05 58.07,68.19 57.85,68.41 57.7,68.41 57.07,69.05 57.07,69.19 56.85,69.41 56.7,69.41 56.13,69.98 56.13,75.31 55.88,75.56 53.34,75.56 49.28,79.63 49.28,89.41 45.47,93.22 38.35,93.22 34.42,97.16 34.42,99.95 33.78,100.58 33.78,102.23 32.77,103.25 32.77,104.07 33.09,104.39 33.54,104.39 33.87,104.07 33.87,103.67 34.42,103.12 v1(34.42,101.73)
DDR3-1_DQ01: length 63.7
  TOP w0.197: P6.7 v1(35.55,101.73) ; v1(61.69,68.04) U31.M27
  L5_SIGNAL w0.14: v1(35.55,101.73) 35.81,101.73 36.07,101.98 36.07,103.25 36.32,103.51 37.58,103.51 37.83,103.25 37.83,100.62 37.84,100.61 37.84,100.3 37.83,100.3 37.83,97.29 39.75,95.38 46.86,95.38 47.12,95.63 47.12,97.41 47.37,97.66 50.42,97.66 53.34,94.74 53.34,79.5 55.63,77.22 58.67,77.22 60.32,75.57 60.32,72.88 60.54,72.66 60.69,72.66 61.21,72.14 61.21,68.52 v1(61.69,68.04)
DDR3-1_DQ02: length 63.6
  TOP w0.197: v1(37.47,100.46) 37.95,100.95 P6.15 ; v1(60.69,69.04) U31.L28
  L5_SIGNAL w0.14: v1(37.47,100.46) 37.47,96.77 39.37,94.87 47.5,94.87 47.75,95.12 47.75,96.9 48.01,97.16 48.51,97.16 48.77,96.9 48.77,95.12 49.02,94.87 50.8,94.87 51.05,94.62 51.05,92.3 51.28,92.08 51.59,92.08 51.82,92.3 51.82,94.62 52.07,94.87 52.45,94.87 52.83,94.49 52.83,79.38 55.5,76.71 58.42,76.71 59.18,75.95 59.18,72.64 59.31,72.52 59.94,72.52 60.2,72.26 60.2,69.6 60.69,69.1 v1(60.69,69.04)
DDR3-1_DQ03: length 63.8
  TOP w0.197: P6.17 38.55,100.64 v1(38.73,100.46) ; v1(61.69,67.04) U31.M26
  L5_SIGNAL w0.14: v1(38.73,100.46) 39.24,100.46 39.75,99.95 39.75,97.79 40.39,97.16 45.09,97.16 45.34,96.9 45.34,96.14 45.59,95.89 46.48,95.89 46.74,96.14 46.74,99.57 46.99,99.82 47.24,99.82 47.5,99.57 47.5,98.55 47.75,98.3 48.01,98.3 48.26,98.55 48.26,99.57 48.51,99.82 48.77,99.82 53.98,94.62 53.98,79.63 55.88,77.72 59.05,77.72 61.21,75.56 61.21,73.53 62.23,72.52 62.23,67.58 v1(61.69,67.04)
DDR3-1_DQ04: length 63.7
  TOP w0.197: v1(60.69,67.04) U31.L26 ; P6.4 34.65,110.36 34.29,110 v1(34.29,109.98)
  L5_SIGNAL w0.14: v1(34.29,109.98) 34.29,108.97 34.54,108.71 34.54,107.57 34.29,107.31 34.29,106.55 34.92,105.92 34.92,98.68 35.69,97.92 35.69,96.52 38.1,94.11 45.34,94.11 50.8,88.65 50.8,87.25 49.91,86.36 49.91,79.76 53.59,76.07 56.64,76.07 57.32,75.4 57.32,69.88 57.79,69.41 57.85,69.41 58.32,68.94 58.32,68.88 58.79,68.41 58.85,68.41 59.32,67.94 59.32,67.88 59.54,67.66 59.59,67.66 59.69,67.56 60.17,67.56 v1(60.69,67.04)
DDR3-1_DQ05: length 63.7
  TOP w0.197: P6.6 35.25,110.29 v1(35.56,109.98) ; v1(59.69,67.04) U31.K26
  L3_SIGNAL w0.14: v1(42.55,96.01) 47.75,96.01 52.2,91.57 52.2,90.42 56.26,86.36 56.26,85.34 60.07,81.53 60.07,78.23 61.21,77.09 61.21,68.03 60.85,67.66 60.32,67.66 v1(59.69,67.04)
  L5_SIGNAL w0.14: v1(42.55,96.01) 42.04,96.52 39.5,96.52 38.23,97.79 38.23,101.73 38.1,101.85 38.1,108.97 36.83,110.24 36.83,110.62 36.58,110.87 35.81,110.87 35.56,110.62 v1(35.56,109.98)
DDR3-1_DQ06: length 64.1
  TOP w0.197: v1(38.1,109.98) 38.25,110.14 P6.16 ; v1(59.69,68.04) U31.K27
  L3_SIGNAL w0.14: v1(59.69,68.04) 59.69,68.07 60.2,68.58 60.2,77.47 59.69,77.98 59.69,81.03 51.44,89.28 51.44,91.19 47.12,95.5 42.42,95.5 41.78,96.14 41.78,98.81 41.02,99.57 41.02,100.97 41.28,101.22 41.28,101.85 39.37,103.76 39.37,106.07 38.86,106.58 38.86,110.24 40.13,111.51 40.39,111.51 40.64,111.76 40.64,112.27 40.39,112.52 38.99,112.52 38.1,111.63 v1(38.1,109.98)
DDR3-1_DQ07: length 63.5
  TOP w0.197: v1(39.37,109.98) 38.85,110.5 P6.18 ; v1(61.69,66.04) U31.M25
  L5_SIGNAL w0.14: v1(61.69,66.04) 61.72,66.04 62.23,66.55 62.74,66.55 63.12,66.93 63.12,75.44 62.8,75.76 62.04,75.76 59.69,78.11 56.01,78.11 54.61,79.5 54.61,94.49 47.5,101.6 47.5,105.28 45.85,106.93 43.69,106.93 42.42,108.2 42.42,110.24 42.16,110.49 39.62,110.49 39.37,110.24 v1(39.37,109.98)
DDR3-1_DQ08: length 63.5
  TOP w0.197: v1(39.37,101.73) 39.76,102.11 P6.21 ; v1(55.69,75.04) U31.F34
  L5_SIGNAL w0.14: v1(46.23,97.03) 44.45,98.81 44.45,99.62 44.12,99.95 43.94,99.95 43.69,100.2 43.69,103 43.43,103.25 42.93,103.25 42.67,103 42.67,100.08 42.29,99.7 42.29,98.68 42.04,98.42 41.66,98.42 41.4,98.68 41.4,99.7 41.15,99.95 40.39,99.95 40.13,100.2 40.13,101.5 39.91,101.73 v1(39.37,101.73)
  L7_SIGNAL w0.14: v1(55.69,75.04) 55.69,78.3 56.13,78.74 56.13,81.41 53.47,84.07 53.47,97.16 52.58,98.04 52.58,99.19 51.44,100.33 51.44,103.38 50.67,104.14 48.9,104.14 48.64,103.89 48.64,98.3 47.88,97.54 46.36,97.54 46.23,97.41 v1(46.23,97.03)
DDR3-1_DQ09: length 63.6
  TOP w0.197: P6.23 40.36,102.01 v1(40.64,101.73) ; v1(54.69,73.04) U31.E32
  L5_SIGNAL w0.14: v1(45.72,100.46) 45.09,101.09 45.09,103.51 44.7,103.89 41.02,103.89 40.64,103.51 v1(40.64,101.73)
  L7_SIGNAL w0.14: v1(54.69,73.04) 54.6,73.04 54.1,73.53 53.34,73.53 53.09,73.79 53.09,81.79 49.66,85.22 49.66,89.79 49.4,90.04 49.02,90.04 48.77,89.79 48.77,88.39 48.51,88.14 47.37,88.14 45.97,89.53 45.97,92.71 45.72,92.96 45.34,92.96 45.09,92.71 45.09,90.93 44.83,90.68 44.58,90.68 44.32,90.93 44.32,94.36 44.07,94.62 43.82,94.62 43.56,94.36 43.56,92.33 43.31,92.08 42.42,92.08 42.16,92.33 42.16,98.23 42.85,98.91 42.91,98.91 42.93,98.93 45.21,98.93 45.59,99.31 45.59,99.44 45.72,99.57 v1(45.72,100.46)
DDR3-1_DQ10: length 63.4
  TOP w0.197: P6.33 43.36,101.9 v1(43.18,101.73) ; v1(54.69,74.04) U31.E33
  L7_SIGNAL w0.14: v1(43.18,101.73) 43.82,101.09 46.1,101.09 46.36,100.84 46.36,99.06 45.85,98.55 44.2,98.55 43.69,98.04 43.69,95.38 43.94,95.12 45.21,95.12 45.47,94.87 45.47,93.73 45.72,93.47 45.97,93.47 46.23,93.73 46.23,94.74 46.48,95 46.86,95 47.12,94.74 47.12,89.41 47.37,89.15 47.62,89.15 47.88,89.41 47.88,91.95 48.13,92.2 48.65,92.2 48.65,92.23 48.87,92.45 48.9,92.45 48.9,94.87 49.15,95.12 49.78,95.12 50.04,94.87 50.04,92.71 50.29,92.46 50.67,92.46 50.93,92.71 50.93,94.62 51.18,94.87 51.44,94.87 51.69,94.62 51.69,92.2 51.44,91.95 50.67,91.95 50.04,91.31 50.04,85.73 54.23,81.53 54.23,74.42 54.61,74.04 v1(54.69,74.04)
DDR3-1_DQ11: length 63.8
  TOP w0.197: v1(55.69,74.04) U31.F33 ; P6.35 43.95,102.22 v1(44.45,101.73)
  L7_SIGNAL w0.14: v1(55.69,74.04) 55.69,74.1 55.25,74.55 55.25,79.76 55.12,79.88 55.12,81.79 52.83,84.07 52.83,97.16 51.05,98.93 51.05,99.31 50.8,99.57 49.4,99.57 49.15,99.31 49.15,98.17 48.26,97.28 48.26,96.79 48.01,96.53 45.61,96.53 45.34,96.8 45.34,97.66 45.72,98.04 47.75,98.04 48.26,98.55 48.26,100.71 47.88,101.09 47.88,104.59 47.77,104.7 47.77,105.1 47.88,105.21 47.88,109.22 47.62,109.47 46.48,109.47 46.23,109.22 46.23,103 45.97,102.74 44.7,102.74 44.45,102.49 v1(44.45,101.73)
DDR3-1_DQ12: length 63.6
  TOP w0.197: v1(39.75,108.71) 40.06,109.02 P6.22 ; v1(54.69,75.04) U31.E34
  L3_SIGNAL w0.14: v1(39.75,108.71) 39.75,108.97 40.13,109.35 44.59,109.35 44.97,108.97 44.97,98.56 44.45,98.04 v1(44.45,96.65)
  L7_SIGNAL w0.14: v1(44.45,96.65) 44.45,96.14 44.96,95.63 49.4,95.63 49.66,95.89 49.66,98.04 49.91,98.3 51.05,98.3 52.32,97.03 52.32,88.87 52.1,88.65 51.79,88.65 51.56,88.87 51.56,91.06 51.31,91.31 50.93,91.31 50.67,91.06 50.67,87.63 51.18,87.12 51.18,85.22 54.69,81.71 v1(54.69,75.04)
DDR3-1_DQ13: length 63.5
  TOP w0.197: P6.24 40.65,109.08 v1(41.02,108.71) ; v1(57.69,73.04) U31.H32
  L7_SIGNAL w0.14: v1(57.69,73.04) 57.93,73.04 58.42,73.53 58.93,73.53 59.18,73.79 59.18,77.72 58.55,78.36 58.55,81.79 54.99,85.34 54.99,99.19 53.98,100.2 53.98,106.81 49.02,111.76 49.02,113.79 48.39,114.43 42.29,114.43 41.91,114.05 41.91,112.65 42.42,112.14 42.42,109.86 42.04,109.47 41.78,109.47 v1(41.02,108.71)
DDR3-1_DQ14: length 63.8
  TOP w0.197: P6.34 43.65,109.19 v1(43.18,108.71) ; v1(56.69,73.04) U31.G32
  L7_SIGNAL w0.14: v1(43.18,108.71) 43.43,108.71 43.69,108.97 43.69,113.67 43.94,113.92 48.39,113.92 48.64,113.67 48.64,111.63 51.31,108.97 51.31,106.17 51.56,105.92 52.2,105.92 52.45,106.17 52.45,107.19 52.58,107.31 52.83,107.31 53.59,106.55 53.59,106.05 52.71,105.16 52.71,104.27 53.47,103.51 53.47,100.2 54.61,99.06 54.61,85.22 58.17,81.66 58.17,73.91 57.79,73.53 57.15,73.53 56.69,73.07 v1(56.69,73.04)
DDR3-1_DQ15: length 63.8
  TOP w0.197: v1(44.45,108.71) 44.25,108.91 P6.36 ; v1(56.69,71.04) U31.G30
  L7_SIGNAL w0.14: v1(44.45,108.71) 44.45,112.27 44.7,112.52 45.34,112.52 45.59,112.27 45.59,111.38 45.85,111.12 46.61,111.12 46.86,111.38 46.86,112.27 47.12,112.52 47.5,112.52 47.75,112.27 47.75,111.38 48.39,110.74 48.64,110.74 49.15,110.24 49.15,109.6 49.28,109.47 50.16,109.47 50.29,109.35 50.29,108.2 49.53,107.44 49.53,105.92 49.66,105.79 50.04,105.79 50.16,105.92 50.16,107.31 50.29,107.44 50.67,107.44 50.93,107.19 50.93,105.28 52.96,103.25 52.96,99.95 54.34,98.56 54.34,85.11 56.9,82.55 56.9,78.36 57.28,77.98 57.28,74.17 57.07,73.96 57.07,73.88 56.85,73.66 56.77,73.66 56.26,73.15 56.26,71.5 56.69,71.07 v1(56.69,71.04)
DDR3-1_DQ16: length 62.4
  TOP w0.197: v1(44.45,100.46) 45.16,101.16 P6.39 ; v1(57.69,70.04) U31.H29
  L16_SIGNAL w0.14: v1(57.69,70.04) 57.07,70.66 56.54,70.66 56.32,70.88 56.32,75.13 55.63,75.82 54.36,75.82 51.31,78.87 51.31,83.82 49.53,85.6 49.53,92.2 49.21,92.52 48.84,92.52 48.78,92.46 48.1,92.46 47.89,92.68 47.89,92.99 47.89,93 47.89,93.1 48.13,93.34 48.13,93.85 45.47,96.52 45.47,99.31 44.96,99.82 44.96,105.66 45.21,105.92 45.72,105.92 45.97,106.17 45.97,107.31 45.72,107.57 45.21,107.57 44.96,107.82 44.96,109.35 44.7,109.6 44.2,109.6 43.94,109.35 43.94,100.71 44.2,100.46 v1(44.45,100.46)
DDR3-1_DQ17: length 62
  TOP w0.197: P6.41 v1(45.76,101.76) ; v1(57.69,71.04) U31.H30
  L16_SIGNAL w0.14: v1(48.26,92.84) 49.28,92.84 52.71,89.41 52.71,78.11 54.61,76.2 55.75,76.2 56.26,75.69 56.77,75.69 57.15,75.31 57.15,71.58 v1(57.69,71.04)
  L18_SIGNAL w0.14: v1(48.26,92.84) 48.26,99.69 48,99.95 47.63,99.95 47.37,99.69 47.37,98.42 47.12,98.17 46.1,98.17 45.72,98.55 45.72,98.68 46.1,99.06 46.48,99.06 46.86,99.44 46.86,99.82 46.23,100.46 46.23,101.09 46.86,101.73 46.86,103.25 47.74,104.13 47.74,105.12 47.75,105.13 47.75,106.43 47.5,106.68 43.31,106.68 43.05,106.43 43.05,104.39 43.31,104.14 45.34,104.14 45.72,103.76 45.72,101.8 v1(45.76,101.76)
DDR3-1_DQ18: length 61.8
  TOP w0.197: v1(58.69,71.04) U31.J30 ; P6.51 48.76,102.22 v1(48.26,101.73)
  L16_SIGNAL w0.14: v1(50.67,95.89) 50.67,94.23 54.61,90.3 54.61,84.07 56.64,82.04 56.64,78.61 57.4,77.85 57.91,77.85 60.32,75.45 60.32,72.66 60.07,72.41 60.07,71.88 59.85,71.66 59.32,71.66 v1(58.69,71.04)
  L18_SIGNAL w0.14: v1(50.67,95.89) 50.42,95.89 50.16,95.63 50.16,95.12 50.42,94.87 50.8,94.87 51.69,93.98 51.69,90.39 51.47,90.17 51.15,90.17 50.93,90.39 50.93,93.98 50.67,94.23 50.42,94.23 50.16,93.98 50.16,90.48 49.98,90.3 49.72,90.3 49.53,90.48 49.53,98.04 50.04,98.55 50.04,100.71 49.66,101.09 48.9,101.09 v1(48.26,101.73)
DDR3-1_DQ19: length 62.1
  TOP w0.197: v1(49.53,101.73) 49.35,101.9 P6.53 ; v1(58.69,72.04) U31.J31
  L16_SIGNAL w0.14: v1(50.55,96.77) 50.28,97.04 49.16,97.04 49.06,96.94 49.06,96.74 49.98,95.81 49.98,95.45 49.88,95.35 49.69,95.35 48.64,96.39 48.39,96.39 48.23,96.24 48.23,96.04 54.23,90.04 54.23,83.95 56.26,81.92 56.26,77.98 57.28,76.96 58.17,76.96 59.18,75.95 59.18,72.53 v1(58.69,72.04)
  L18_SIGNAL w0.14: v1(49.53,101.73) 49.53,104.01 50.16,104.65 50.16,107.23 50.5,107.57 50.97,107.57 51.31,107.23 51.31,106.05 50.8,105.54 50.8,102.74 50.29,102.23 50.29,101.35 50.67,100.97 51.69,100.97 52.07,100.58 52.07,98.23 51.88,98.04 51.62,98.04 51.44,98.23 51.44,99.82 51.18,100.08 50.8,100.08 50.55,99.82 v1(50.55,96.77)
DDR3-1_DQ20: length 62
  TOP w0.197: v1(58.69,70.04) U31.J29 ; P6.40 45.46,110.35 v1(45.09,109.98)
  L16_SIGNAL w0.14: v1(58.69,70.04) 59.32,70.66 59.85,70.66 60.32,71.13 60.32,71.19 60.54,71.41 60.6,71.41 61.21,72.03 61.21,75.56 58.42,78.36 58.42,80.9 54.99,84.33 54.99,90.55 51.44,94.11 v1(51.44,95.38)
  L18_SIGNAL w0.14: v1(51.44,95.38) 52.71,96.65 52.71,108.2 51.31,109.6 51.31,111.38 51.05,111.63 43.41,111.63 42.93,111.15 42.93,110.47 43.41,109.98 v1(45.09,109.98)
DDR3-1_DQ21: length 61.9
  TOP w0.197: v1(46.36,109.98) 46.06,110.28 P6.42 ; v1(56.69,69.04) U31.G28
  L16_SIGNAL w0.14: v1(47.62,93.47) 47.12,92.96 47.12,86.49 49.28,84.33 49.28,79.5 53.21,75.56 53.21,70.74 53.54,70.41 53.85,70.41 54.07,70.19 54.07,69.89 54.54,69.41 54.85,69.41 55.22,69.04 v1(56.69,69.04)
  L18_SIGNAL w0.14: v1(46.36,109.98) 45.72,109.35 44.28,109.35 43.94,109.01 43.94,108.54 44.28,108.2 47.02,108.2 47.24,107.98 47.24,107.67 47.02,107.44 42.16,107.44 41.91,107.19 41.91,103.63 43.69,101.85 43.69,99.44 45.59,97.54 47.24,97.54 47.62,97.16 v1(47.62,93.47)
DDR3-1_DQ22: length 61.8
  TOP w0.197: P6.50 48.46,110.18 v1(48.26,109.98) ; v1(55.69,70.04) U31.F29
  L16_SIGNAL w0.14: v1(49.02,92.08) 49.02,85.34 49.78,84.58 49.78,79.76 54.32,75.22 54.32,70.88 54.54,70.66 55.07,70.66 v1(55.69,70.04)
  L18_SIGNAL w0.14: v1(49.02,92.08) 49.02,100.08 47.37,101.73 47.37,103.25 47.61,103.49 47.9,103.49 48.13,103.25 48.13,102.62 48.26,102.49 48.64,102.49 48.9,102.74 48.9,105.16 49.53,105.79 49.53,107.82 49.91,108.2 50.29,108.2 50.55,108.46 50.55,111 50.29,111.25 49.38,111.25 49.12,111 49.12,106.42 48.87,106.17 48.51,106.17 48.26,106.42 v1(48.26,109.98)
DDR3-1_DQ23: length 62.7
  TOP w0.197: v1(60.69,70.04) U31.L29 ; P6.52 49.06,110.46 v1(49.53,109.98)
  L16_SIGNAL w0.14: v1(49.53,109.98) 49.91,109.98 50.16,110.24 50.16,115.7 50.42,115.95 50.8,115.95 51.05,115.7 51.05,113.43 50.97,113.34 50.97,112.93 51.05,112.85 51.05,109.98 51.44,109.6 51.44,107.57 51.69,107.31 51.69,106.3 52.71,105.28 52.71,97.41 53.34,96.77 53.34,93.47 56.64,90.17 56.64,83.95 59.82,80.77 59.82,77.98 61.98,75.82 62.36,75.82 62.76,75.41 62.85,75.41 63.16,75.1 63.16,71.17 63.07,71.07 63.07,70.88 62.79,70.61 61.59,70.61 61.02,70.04 v1(60.69,70.04)
DDR3-1_DQ24: length 50
  TOP w0.197: v1(49.53,100.46) 50.16,101.09 50.16,101.98 50.55,102.37 P6.57 ; v1(59.69,73.04) U31.K32
  L20_SIGNAL w0.14: v1(59.69,73.04) 59.32,73.41 58.54,73.41 58.07,73.89 58.07,81.25 56.39,82.93 56.01,82.93 55.75,82.68 55.75,82.1 55.57,81.92 55.3,81.92 55.12,82.1 55.12,89.41 49.4,95.12 49.4,99.06 49.02,99.44 49.02,105.41 49.28,105.66 49.66,105.66 49.91,105.41 49.91,105.21 50.02,105.1 50.02,104.7 49.91,104.59 49.91,100.71 49.66,100.46 v1(49.53,100.46)
DDR3-1_DQ25: length 50.2
  TOP w0.197: v1(50.8,101.73) 51.16,102.08 P6.59 ; v1(59.69,74.04) U31.K33
  L20_SIGNAL w0.14: v1(59.69,74.04) 59.18,74.55 59.18,75.82 59.56,76.2 59.56,81.41 56.64,84.33 56.64,89.92 56.8,90.07 56.99,90.07 57.15,89.92 57.15,87.26 57.29,87.12 57.43,87.12 57.57,87.26 57.57,90.26 55.25,92.58 53.85,92.58 53.28,93.15 53.28,96.71 53.09,96.9 52.89,96.9 52.71,96.72 52.71,95.79 52.55,95.63 52.32,95.63 52.16,95.79 52.16,97.95 51.82,98.3 51.82,99.67 51.67,99.82 51.46,99.82 51.31,99.67 51.31,97.3 51.16,97.16 50.95,97.16 50.8,97.3 v1(50.8,101.73)
DDR3-1_DQ26: length 50.1
  TOP w0.197: P6.67 53.55,101.51 v1(54.61,100.46) ; v1(60.69,74.04) U31.L33
  L20_SIGNAL w0.14: v1(60.69,74.04) 61.21,74.56 61.21,75.69 62.1,76.58 62.1,82.17 60.2,84.07 60.2,86.36 59.69,86.87 59.69,90.68 57.4,92.96 57.4,96.21 57.22,96.39 55.63,96.39 55.37,96.65 55.37,97.41 55.63,97.66 57.31,97.66 57.53,97.89 57.53,100.33 57.28,100.58 57.15,100.58 56.9,100.33 56.9,98.81 56.64,98.55 56.52,98.55 56.26,98.81 56.26,99.7 55.88,100.08 55.88,104.04 55.66,104.27 55.34,104.27 55.12,104.04 55.12,100.58 54.99,100.46 v1(54.61,100.46)
DDR3-1_DQ27: length 50.2
  TOP w0.197: v1(60.69,75.04) U31.L34 ; v1(54.61,101.73) 54.16,102.18 P6.69
  L20_SIGNAL w0.14: v1(60.69,75.04) 60.69,75.68 61.59,76.58 61.59,81.66 59.69,83.57 59.69,85.85 59.05,86.49 59.05,90.68 56.71,93.03 56.71,94.42 54.74,96.39 54.74,98.81 53.72,99.82 53.72,104.59 53.83,104.7 53.83,105.1 53.72,105.21 53.72,105.66 53.98,105.92 53.98,106.3 53.72,106.55 51.53,106.55 51.31,106.78 51.31,107.09 51.53,107.31 54.36,107.31 54.61,107.06 54.61,106.81 54.86,106.55 54.99,106.55 55.25,106.3 55.25,105.92 54.61,105.28 v1(54.61,101.73)
DDR3-1_DQ28: length 50
  TOP w0.197: v1(49.91,108.71) 50.25,109.06 P6.56 ; v1(59.69,75.04) U31.K34
  L20_SIGNAL w0.14: v1(49.91,108.71) 51.44,108.71 51.56,108.84 52.45,108.84 52.58,108.71 53.2,108.71 53.45,108.46 53.45,107.96 53.2,107.71 52.59,107.71 52.58,107.7 51.44,107.7 50.8,107.06 50.8,103.25 51.05,103 51.31,103 51.56,102.74 51.56,100.46 52.58,99.44 52.58,98.04 53.72,96.9 53.72,93.47 53.98,93.22 54.99,93.22 55.12,93.34 55.12,94.23 55.25,94.36 55.5,94.36 55.88,93.98 55.88,92.58 57.91,90.55 57.91,83.69 59.94,81.66 59.94,75.95 59.69,75.69 v1(59.69,75.04)
DDR3-1_DQ29: length 50.2
  TOP w0.197: P6.58 v1(50.86,108.08) ; v1(58.69,75.04) U31.J34
  L20_SIGNAL w0.14: v1(58.69,75.04) 58.42,75.31 58.42,81.66 56.13,83.95 56.13,89.28 49.91,95.5 49.91,97.16 50.29,97.54 50.29,105.92 50.04,106.17 48.9,106.17 48.64,106.43 48.64,107.09 48.42,107.31 48.1,107.31 47.88,107.09 47.88,106.43 47.62,106.17 47.24,106.17 46.99,106.43 46.99,107.31 47.62,107.95 49.4,107.95 49.66,107.7 49.66,107.31 49.91,107.06 50.04,107.06 50.29,107.31 50.29,107.51 v1(50.86,108.08)
DDR3-1_DQ30: length 50.2
  TOP w0.197: v1(60.69,71.04) U31.L30 ; v1(54.48,108.71) 53.86,109.34 P6.68
  L20_SIGNAL w0.14: v1(60.69,71.04) 61.32,71.66 61.85,71.66 62.07,71.88 62.07,72.19 62.54,72.66 62.85,72.66 63.07,72.88 63.07,73.41 63.25,73.59 63.25,75.44 63.88,76.07 63.88,82.68 62.48,84.07 62.48,86.11 60.83,87.76 60.83,91.31 58.42,93.73 58.42,102.87 56.52,104.78 56.52,109.6 56.26,109.86 55.88,109.86 55.63,109.6 55.63,108.97 55.37,108.71 v1(54.48,108.71)
DDR3-1_DQ31: length 50
  TOP w0.197: v1(54.61,109.98) 54.46,110.14 P6.70 ; v1(60.69,72.04) U31.L31
  L20_SIGNAL w0.14: v1(54.61,109.98) 54.61,111.63 54.36,111.89 53.98,111.89 53.72,111.63 53.72,108.33 53.98,108.08 54.36,108.08 55.88,106.55 55.88,104.78 57.91,102.74 57.91,93.34 60.2,91.06 60.2,87.5 61.72,85.98 61.72,83.95 63.37,82.3 63.37,76.4 62.81,75.84 62.76,75.84 62.23,75.31 62.23,73.58 v1(60.69,72.04)
DDR3-1_DQ32: length 51
  TOP w0.197: v1(74.3,101.73) 74.56,101.99 P6.129 ; v1(71.69,75.04) U31.AA34
  L3_SIGNAL w0.14: v1(74.3,101.73) 74.3,103.76 74.68,104.14 75.56,104.14 76.07,103.63 76.07,103.25 75.16,102.34 75.16,99.7 75.67,99.19 77.85,99.19 78.11,98.93 78.11,96.65 78.36,96.39 79.38,96.39 79.63,96.65 79.63,98.93 79.88,99.19 80.01,99.19 80.26,98.93 80.26,95.63 80.52,95.38 v1(81.41,95.38)
  L20_SIGNAL w0.14: v1(81.41,95.38) 80.9,94.87 80.9,93.09 75.31,87.5 75.31,85.09 70.74,80.52 70.74,76.65 71.51,75.88 71.51,75.22 v1(71.69,75.04)
DDR3-1_DQ33: length 51.1
  TOP w0.197: P6.131 75.16,102.14 v1(75.56,101.73) ; v1(68.69,75.04) U31.V34
  L20_SIGNAL w0.14: v1(68.69,75.04) 68.69,75.56 69.22,76.09 69.22,82.68 70.23,83.69 70.23,88.01 73.15,90.93 73.28,90.93 73.53,91.19 73.53,99.95 73.79,100.2 74.04,100.2 74.3,99.95 74.3,91.19 74.55,90.93 74.93,90.93 75.18,91.19 75.18,101.47 75.44,101.73 v1(75.56,101.73)
DDR3-1_DQ34: length 51.3
  TOP w0.197: P6.141 v1(78.16,101.78) ; v1(69.69,75.04) U31.W34
  L20_SIGNAL w0.14: v1(69.69,75.04) 69.69,82.52 71.5,84.33 71.5,88.39 72.83,89.73 75.76,89.73 77.34,91.31 77.34,98.81 77.09,99.06 76.71,99.06 76.45,98.81 76.45,91.88 76.27,91.69 76,91.69 75.82,91.88 75.82,99.57 76.07,99.82 77.34,99.82 77.6,100.08 77.6,101.22 v1(78.16,101.78)
DDR3-1_DQ35: length 51
  TOP w0.197: v1(78.11,100.46) 78.75,101.11 P6.143 ; v1(70.69,74.04) U31.Y33
  L3_SIGNAL w0.14: v1(81.41,96.14) 80.9,96.14 80.64,96.39 80.64,99.44 80.39,99.7 79.5,99.7 79.25,99.44 79.25,97.89 79.02,97.66 78.71,97.66 78.49,97.89 78.49,99.44 78.23,99.7 75.95,99.7 75.69,99.95 75.69,100.97 75.95,101.22 76.58,101.22 76.71,101.35 76.71,102.87 76.84,103 77.34,103 77.72,102.62 77.72,101.09 78.11,100.71 v1(78.11,100.46)
  L20_SIGNAL w0.14: v1(70.69,74.04) 70.98,74.33 70.98,74.41 71.25,74.67 71.25,75.56 70.36,76.45 70.36,80.64 74.04,84.33 74.04,86.87 80.52,93.34 80.52,95.25 v1(81.41,96.14)
DDR3-1_DQ36: length 51.1
  TOP w0.197: P6.130 74.86,110.54 v1(74.3,109.98) ; v1(70.69,75.04) U31.Y34
  L3_SIGNAL w0.14: v1(81.41,96.9) 81.86,96.9 82.04,97.09 82.04,99.13 80.01,101.16 80.01,101.85 78.99,102.87 78.74,102.87 77.91,103.7 77.91,103.95 76.45,105.41 76.45,106.55 74.93,108.08 74.93,112.08 74.74,112.27 74.48,112.27 74.3,112.08 v1(74.3,109.98)
  L20_SIGNAL w0.14: v1(81.41,96.9) 80.14,95.63 80.14,93.5 73.66,87.03 73.66,84.49 69.98,80.8 69.98,76.28 70.69,75.56 v1(70.69,75.04)
DDR3-1_DQ37: length 50.9
  TOP w0.197: v1(73.69,73.04) U31.AC32 ; v1(75.56,109.98) 75.46,110.09 P6.132
  L3_SIGNAL w0.14: v1(82.93,96.52) 82.52,96.93 82.52,99.57 81.28,100.81 81.28,104.01 81.03,104.27 80.77,104.27 80.52,104.01 80.52,103.56 80.33,103.38 80.07,103.38 79.88,103.56 79.88,104.01 79.63,104.27 78.99,104.27 78.74,104.52 78.74,105.28 76.33,107.7 76.33,109.22 v1(75.56,109.98)
  L20_SIGNAL w0.14: v1(82.93,96.52) 83.44,96.01 83.44,92.2 78.49,87.25 78.49,84.84 77.85,84.2 76.58,84.2 73.41,81.03 73.41,77.85 74.17,77.09 74.17,74.8 73.91,74.55 73.53,74.55 73.28,74.3 73.28,73.45 v1(73.69,73.04)
DDR3-1_DQ38: length 51.2
  TOP w0.197: v1(73.69,74.04) U31.AC33 ; P6.140 77.86,110.49 77.47,110.11 77.47,109.35 v1(76.84,108.71)
  L3_SIGNAL w0.14: v1(82.93,97.28) 82.93,99.82 82.68,100.08 82.68,102.18 82.17,102.69 82.17,103.76 82.01,103.92 82.01,107.1 81.79,107.31 81.49,107.31 81.28,107.1 81.28,106.17 81.03,105.92 79.83,105.92 79.58,106.17 79.58,106.99 78.99,107.57 77.98,107.57 v1(76.84,108.71)
  L20_SIGNAL w0.14: v1(82.93,97.28) 83.82,96.39 83.82,91.31 78.99,86.49 78.99,84.2 78.36,83.57 76.96,83.57 75.44,82.04 75.44,79.76 75.18,79.5 75.18,74.8 74.93,74.55 74.42,74.55 73.91,74.04 v1(73.69,74.04)
DDR3-1_DQ39: length 51.3
  TOP w0.197: P6.142 78.46,110.33 v1(78.11,109.98) ; v1(68.69,73.04) U31.V32
  L20_SIGNAL w0.14: v1(68.69,73.04) 68.07,73.66 68.07,82.17 69.72,83.82 69.72,88.39 72.26,90.93 72.26,99.44 73.28,100.46 73.28,104.01 73.53,104.27 74.68,104.27 74.93,104.52 74.93,112.39 75.18,112.65 77.85,112.65 78.11,112.39 v1(78.11,109.98)
DDR3-1_DQ40: length 54.1
  TOP w0.197: v1(72.69,73.04) U31.AB32 ; v1(79.38,101.73) 79.95,102.31 P6.147
  L5_SIGNAL w0.14: v1(86.49,98.55) 86.36,98.42 84.58,98.42 84.45,98.55 84.45,100.58 83.95,101.09 82.69,101.09 82.55,100.95 82.55,99.31 82.3,99.06 79.63,99.06 79.38,99.31 v1(79.38,101.73)
  L16_SIGNAL w0.14: v1(72.69,73.04) 72.7,73.03 73.15,73.03 73.32,73.19 73.32,73.19 73.54,73.41 73.6,73.41 74.07,73.88 74.07,73.94 74.54,74.41 74.67,74.41 75.06,74.8 75.07,74.8 75.07,75.07 83.95,83.95 83.95,87.5 84.2,87.76 85.6,87.76 85.85,87.5 85.85,85.98 86.11,85.73 86.87,85.73 87.12,85.98 87.12,98.3 86.87,98.55 v1(86.49,98.55)
DDR3-1_DQ41: length 54.3
  TOP w0.197: v1(66.69,71.04) U31.U30 ; P6.149 80.56,101.82 v1(80.64,101.73)
  L16_SIGNAL w0.14: v1(66.69,71.04) 67.18,71.53 67.18,76.84 69.47,79.12 69.98,79.12 72.01,81.15 72.01,81.79 75.44,85.22 75.44,86.49 78.74,89.79 78.74,100.46 80.14,101.85 80.14,108.71 80.39,108.97 80.9,108.97 81.15,108.71 81.15,102.23 v1(80.64,101.73)
DDR3-1_DQ42: length 54.2
  TOP w0.197: v1(83.19,101.73) 82.95,101.96 P6.157 ; v1(68.69,71.04) U31.V30
  L16_SIGNAL w0.14: v1(68.69,71.04) 67.69,72.04 67.69,76.58 69.96,78.85 70.09,78.85 70.1,78.87 70.48,78.87 72.77,81.15 72.77,81.66 79.12,88.01 79.12,100.33 79.38,100.58 81.28,100.58 81.53,100.84 81.53,107.76 81.72,107.95 81.98,107.95 82.17,107.76 82.17,107.44 82.42,107.19 82.8,107.19 83.06,106.93 83.06,101.85 v1(83.19,101.73)
DDR3-1_DQ43: length 54.3
  TOP w0.197: v1(83.19,100.46) 83.82,101.09 83.82,101.98 83.56,102.25 P6.159 ; U31.W32 v1(69.69,72.04)
  L16_SIGNAL w0.14: v1(83.19,100.46) 82.17,100.46 81.79,100.08 79.88,100.08 79.5,99.7 79.5,94.42 79.69,94.23 79.95,94.23 80.14,94.42 80.14,99.26 80.32,99.44 80.59,99.44 80.77,99.26 80.77,94.36 79.63,93.22 79.63,86.23 72.01,78.61 70.61,78.61 68.81,76.82 68.5,76.82 67.96,76.27 67.96,74.13 68.07,74.01 68.07,73.13 68.68,72.52 69.37,72.52 69.69,72.19 v1(69.69,72.04)
DDR3-1_DQ44: length 54.1
  TOP w0.197: v1(79.38,109.98) 79.65,110.26 P6.146 ; v1(70.69,73.04) U31.Y32
  L5_SIGNAL w0.14: v1(79.38,109.98) 80.01,109.35 82.93,109.35 v1(83.31,108.97)
  L16_SIGNAL w0.14: v1(70.69,73.04) 70.69,73.23 71.25,73.79 71.25,75.44 71.5,75.69 72.14,75.69 72.9,76.45 72.9,76.71 73.28,77.09 74.17,77.09 78.11,81.03 78.23,81.03 81.03,83.82 81.03,92.08 81.92,92.96 82.42,92.96 82.68,92.71 82.68,91.79 82.9,91.57 83.22,91.57 83.44,91.79 83.44,98.81 83.69,99.06 84.71,99.06 84.96,99.31 84.96,106.81 83.31,108.46 v1(83.31,108.97)
DDR3-1_DQ45: length 54.4
  TOP w0.197: v1(70.69,72.04) U31.Y31 ; v1(79.38,108.71) 80.01,109.35 80.01,110.11 80.26,110.35 P6.148
  L5_SIGNAL w0.14: v1(83.82,106.17) 82.93,106.17 82.68,106.43 82.68,108.2 81.92,108.97 79.63,108.97 v1(79.38,108.71)
  L16_SIGNAL w0.14: v1(83.82,106.17) 84.33,105.66 84.33,104.39 83.57,103.63 83.57,100.97 83.82,100.71 83.82,100.2 83.44,99.82 82.55,99.82 81.92,99.19 81.92,94.49 80.14,92.71 80.14,84.71 76.56,81.13 76.56,80.44 76.28,80.16 75.33,80.16 73.53,78.36 72.9,78.36 72.77,78.23 71.75,78.23 69.22,75.69 69.22,73.83 69.85,73.19 69.85,72.42 69.85,72.41 70.07,72.19 70.07,72.13 70.16,72.04 v1(70.69,72.04)
DDR3-1_DQ46: length 54
  TOP w0.197: v1(71.69,72.04) U31.AA31 ; P6.158 v1(83.26,110.05)
  L16_SIGNAL w0.14: v1(71.69,72.04) 71.32,72.41 71.32,73.19 71.54,73.41 71.64,73.41 72.26,74.04 72.26,75.31 73.53,76.58 74.55,76.58 81.72,83.76 81.72,91.49 81.93,91.69 82.22,91.69 82.42,91.49 82.42,89.36 82.5,89.28 83.19,89.28 85.34,91.44 85.34,101.98 85.85,102.49 85.85,105.92 85.34,106.43 85.34,108.71 84.71,109.35 83.96,109.35 v1(83.26,110.05)
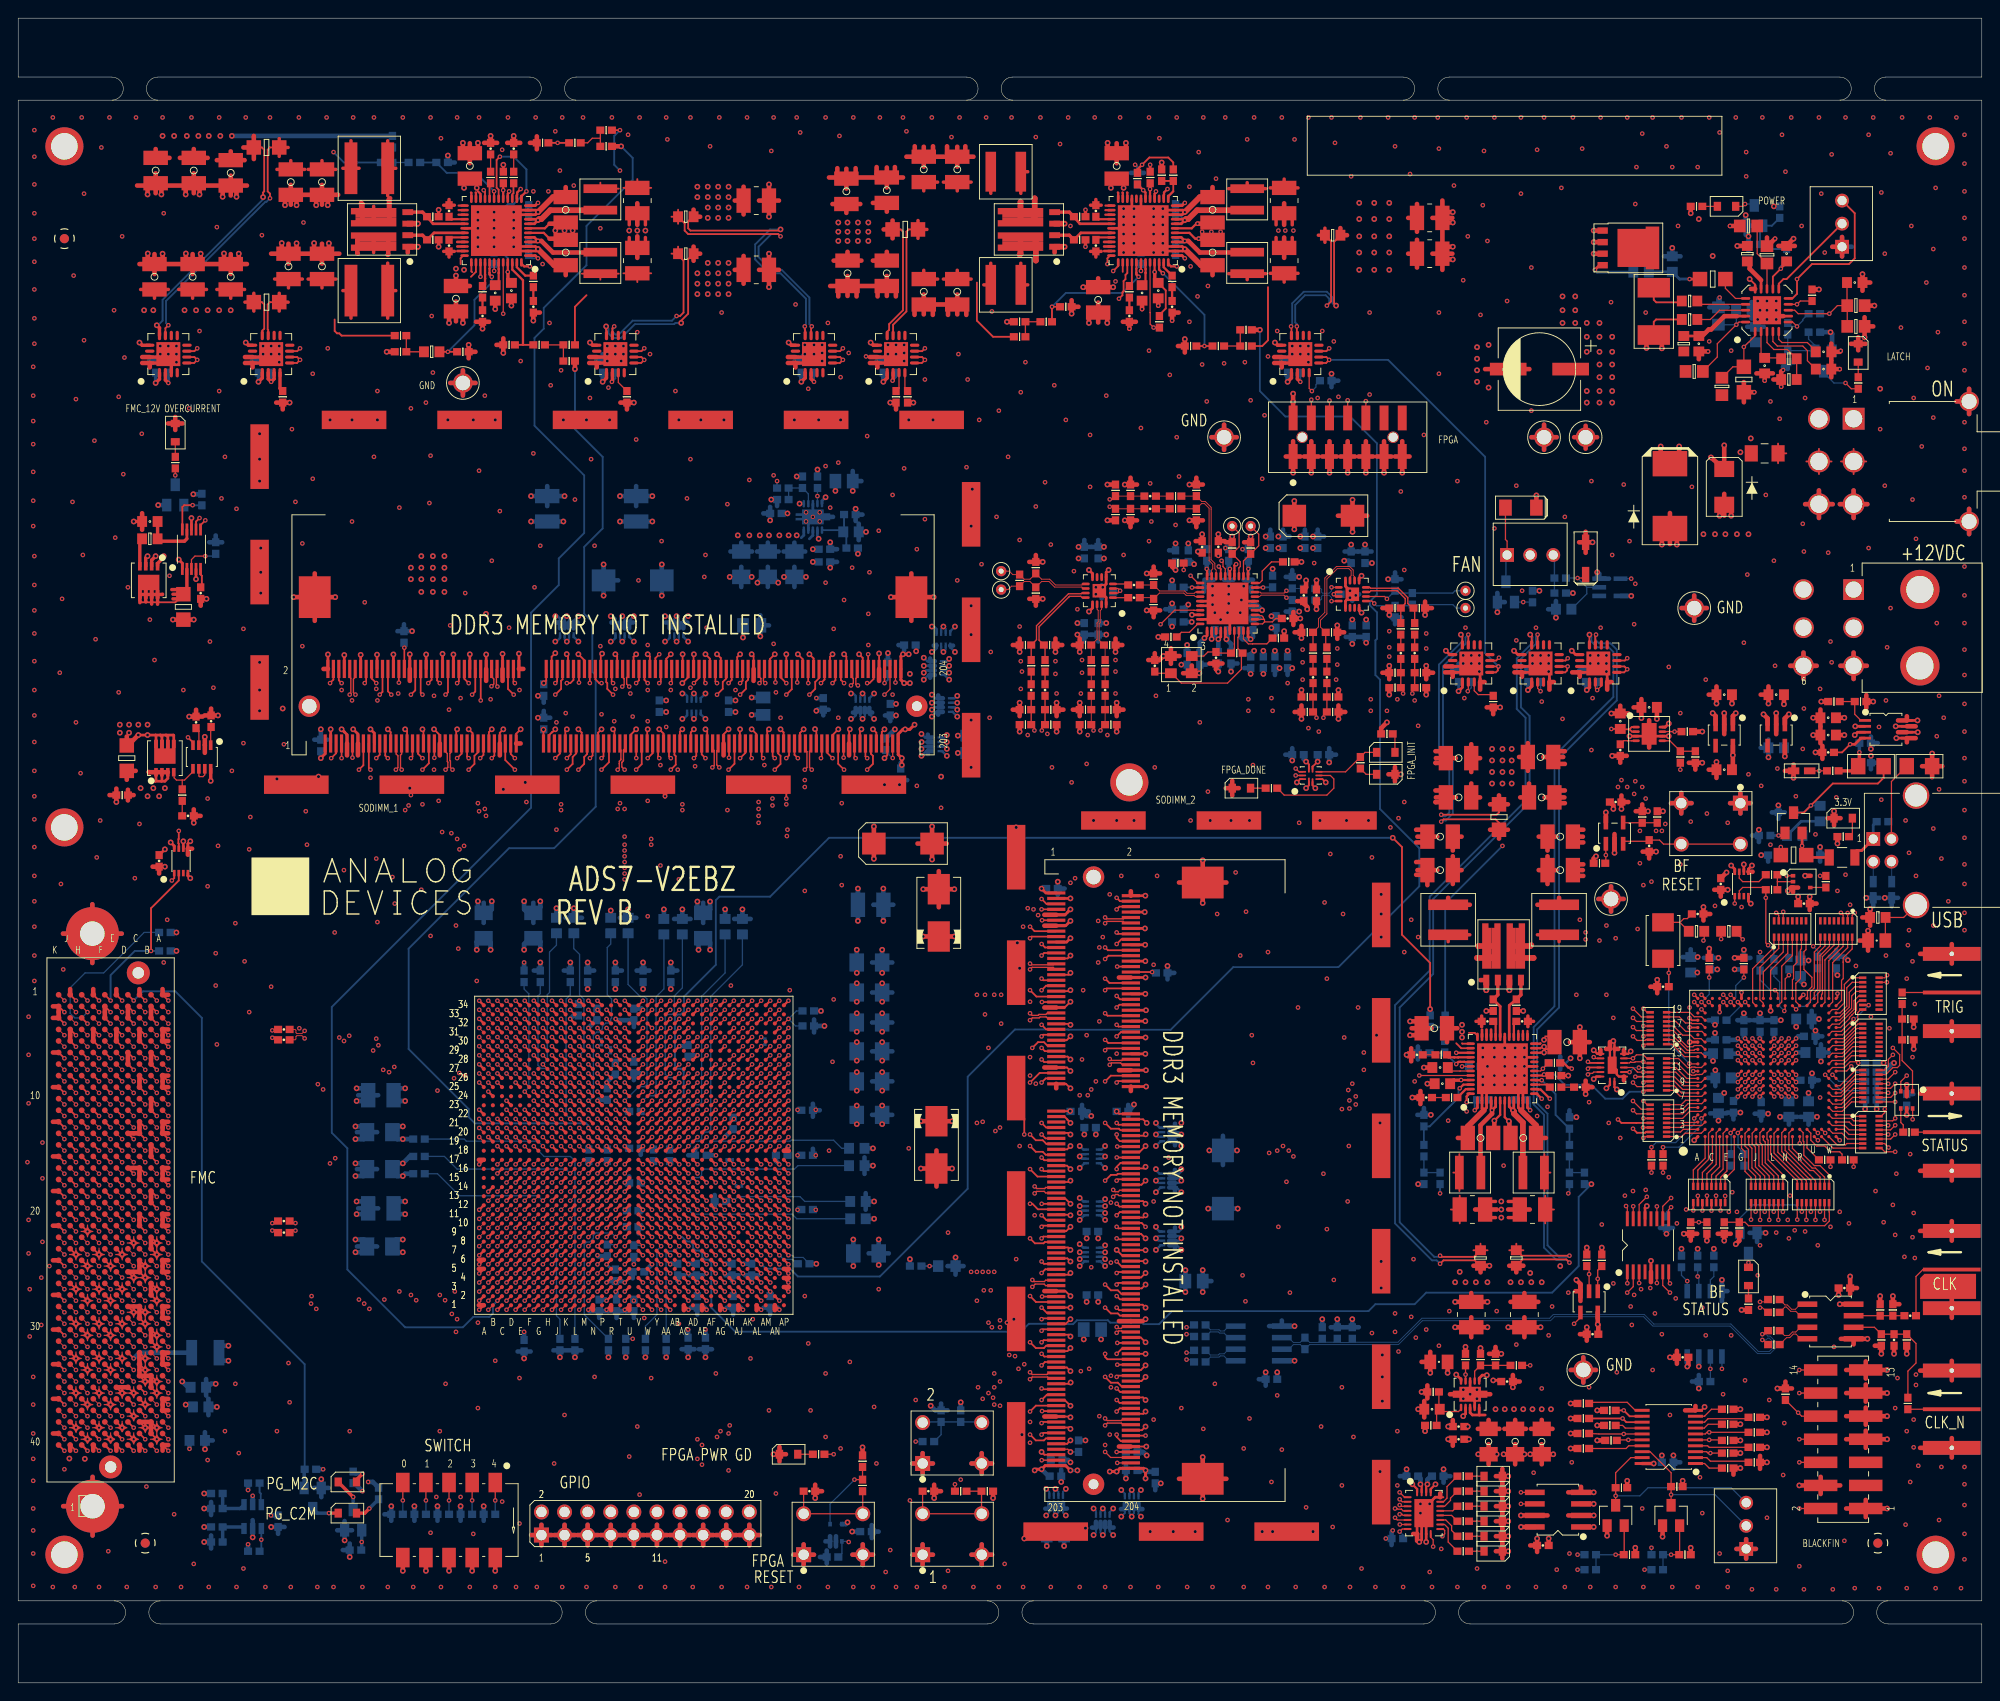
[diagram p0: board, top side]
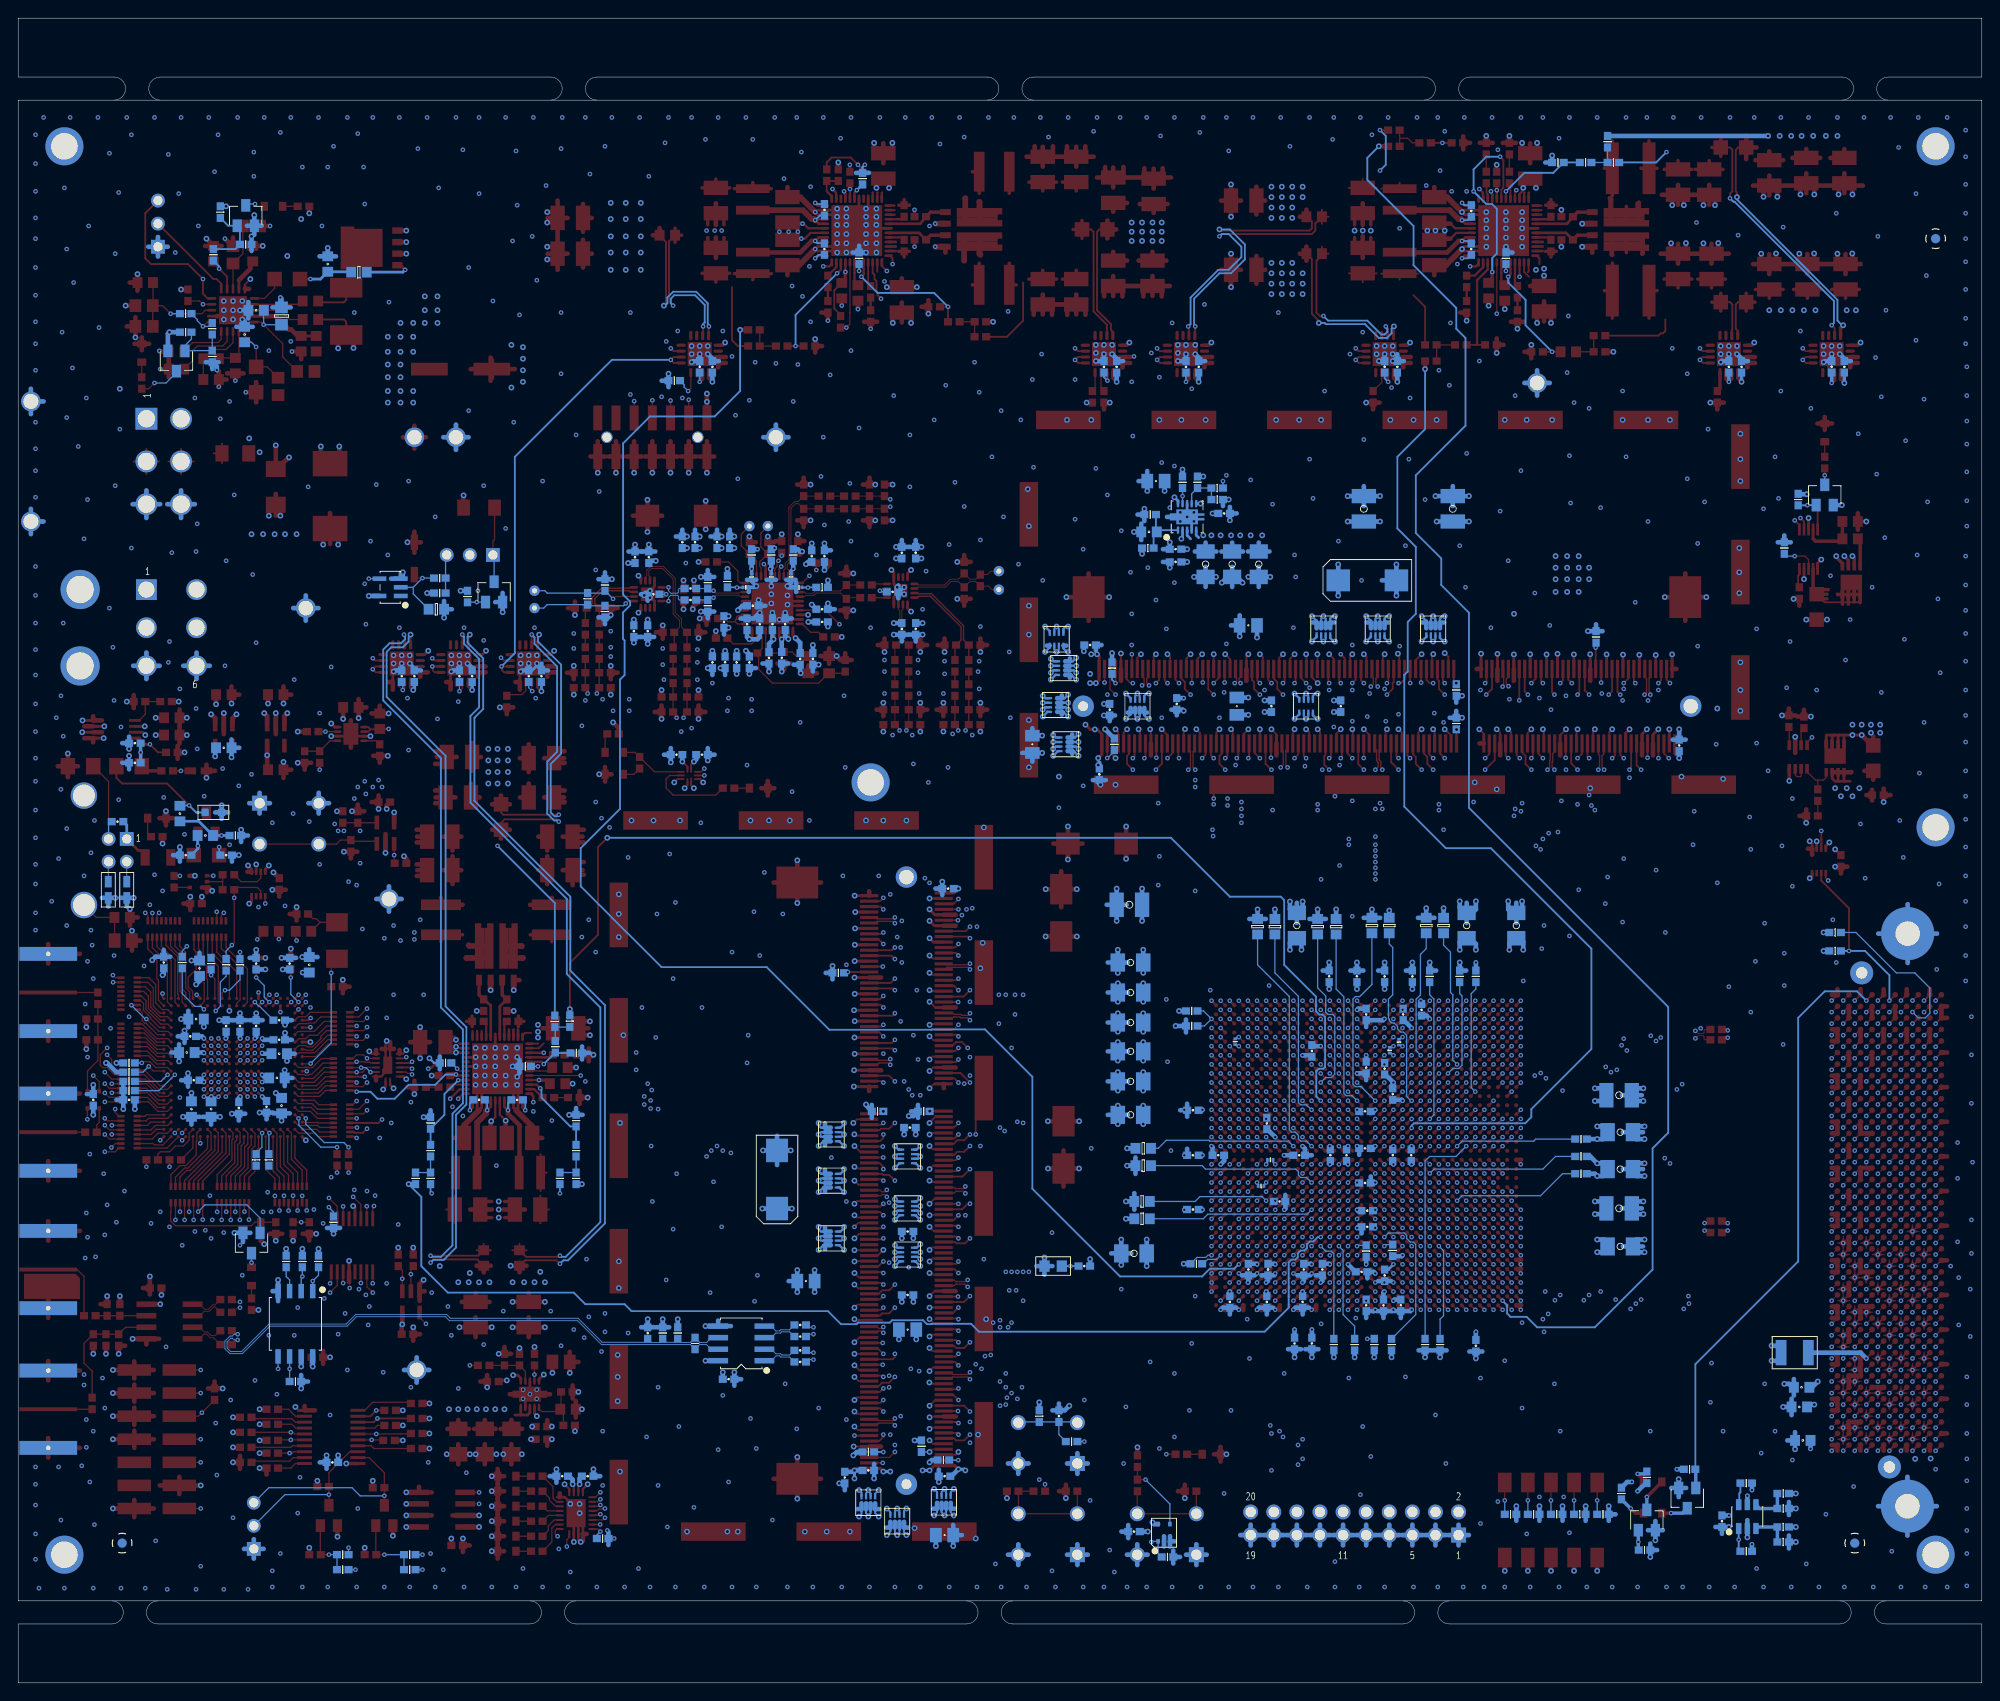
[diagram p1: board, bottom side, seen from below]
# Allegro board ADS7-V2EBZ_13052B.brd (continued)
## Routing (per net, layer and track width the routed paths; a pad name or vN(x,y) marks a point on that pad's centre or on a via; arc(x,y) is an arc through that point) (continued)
DDR3-1_DQ47: length 54.4
  TOP w0.197: P6.160 83.86,110.58 v1(84.45,109.98) ; v1(69.69,71.04) U31.W30
  L16_SIGNAL w0.14: v1(69.69,71.04) 70.16,71.04 70.54,71.41 70.68,71.41 71.16,71.89 71.16,72.09 71.07,72.19 71.07,72.19 70.85,72.41 70.59,72.41 70.23,72.77 70.23,75.82 71.12,76.71 71.12,76.84 72.2,77.91 74.49,77.91 80.52,83.95 80.52,92.33 82.3,94.11 82.3,98.93 82.92,99.56 83.68,99.56 84.33,100.2 84.33,100.97 83.95,101.35 83.95,103.38 84.65,104.08 84.65,106.36 82.68,108.33 82.68,110.24 82.93,110.49 84.2,110.49 84.45,110.24 v1(84.45,109.98)
DDR3-1_DQ48: length 62
  TOP w0.197: P6.163 84.75,102.03 v1(84.45,101.73) ; v1(71.69,69.04) U31.AA28
  L20_SIGNAL w0.14: v1(71.69,69.04) 72.47,69.04 74.32,70.89 74.32,71.19 74.54,71.41 74.84,71.41 75.32,71.89 75.32,72.19 75.54,72.41 75.84,72.41 76.32,72.89 76.32,73.19 76.54,73.41 76.84,73.41 77.32,73.89 77.32,74.19 77.54,74.41 77.84,74.41 78.23,74.8 78.23,75.31 77.85,75.69 77.85,80.39 81.15,83.69 81.15,85.34 83.82,88.01 85.09,88.01 88.01,90.93 88.01,98.17 87.76,98.42 87.25,98.42 87,98.68 87,99.44 87.25,99.7 87.76,99.7 88.01,99.95 88.01,100.97 87.76,101.22 87.76,103 88.14,103.38 88.14,106.17 87.88,106.43 87.12,106.43 86.85,106.15 86.85,104.7 86.74,104.59 86.74,101.47 86.49,101.22 86.23,101.22 85.98,100.97 85.98,99.95 85.73,99.7 84.71,99.7 84.45,99.95 v1(84.45,101.73)
DDR3-1_DQ49: length 62.2
  TOP w0.197: P6.165 85.35,102.1 v1(85.73,101.73) ; v1(71.69,70.04) U31.AA29
  L20_SIGNAL w0.14: v1(85.73,101.73) 85.73,103 85.34,103.38 85.34,105.03 85.6,105.28 85.82,105.28 86.23,105.69 86.23,106.27 85.82,106.68 85.35,106.68 85.09,106.94 85.09,107.31 85.35,107.57 85.85,107.57 86.11,107.82 86.11,109.35 85.85,109.6 85.47,109.6 85.22,109.35 85.22,108.33 84.96,108.08 84.71,108.08 84.45,107.82 84.45,103.49 83.96,103 83.96,99.81 87.12,96.65 87.12,91.82 84.2,88.9 83.82,88.9 80.64,85.73 80.64,84.07 79.12,82.55 78.61,82.55 77.32,81.25 77.32,75.03 76.7,74.41 76.54,74.41 76.32,74.19 76.32,74.03 75.7,73.41 75.54,73.41 75.32,73.19 75.32,73.03 73.7,71.41 73.54,71.41 73.32,71.19 73.32,71.03 72.77,70.48 72.14,70.48 v1(71.69,70.04)
DDR3-1_DQ50: length 64.8
  TOP w0.197: P6.175 88.35,101.82 v1(88.27,101.73) ; v1(70.69,69.04) U31.Y28
  L7_SIGNAL w0.14: v1(70.69,69.04) 70.23,69.5 70.23,75.56 74.82,80.16 75.01,80.16 75.29,80.44 75.29,81.01 77.47,83.19 77.85,83.19 79.12,84.45 79.12,85.6 86.87,93.34 86.87,96.52 87.12,96.77 87.5,96.77 87.76,96.52 87.76,93.34 83.06,88.65 83.06,88.39 83.19,88.27 83.69,88.27 88.65,93.22 88.65,101.35 v1(88.27,101.73)
DDR3-1_DQ51: length 64.9
  TOP w0.197: P6.177 88.96,102.31 v1(89.53,101.73) ; v1(70.69,70.04) U31.Y29
  L7_SIGNAL w0.14: v1(89.53,101.73) 89.53,102.49 89.28,102.74 89.15,102.74 88.9,103 88.9,109.12 89.12,109.35 89.44,109.35 89.66,109.12 89.66,103.63 90.17,103.12 90.17,101.47 90.3,101.35 90.3,99.7 90.55,99.44 90.55,98.27 90.33,98.04 90.01,98.04 89.79,98.27 89.79,100.58 89.66,100.71 89.41,100.71 89.15,100.46 89.15,92.84 83.57,87.25 83.05,87.25 78.36,82.56 78.36,82.17 71.6,75.41 71.54,75.41 71.07,74.94 71.07,70.88 70.69,70.51 v1(70.69,70.04)
DDR3-1_DQ52: length 62.2
  TOP w0.197: v1(84.45,108.71) 85.05,109.31 P6.164 ; v1(69.69,70.04) U31.W29
  L20_SIGNAL w0.14: v1(69.69,70.04) 70.23,70.58 70.23,70.99 70.32,71.08 70.32,71.19 70.54,71.41 70.65,71.41 71.32,72.08 71.32,72.19 71.54,72.41 73.68,72.41 75.32,74.05 75.32,74.19 75.54,74.41 75.6,74.41 76.07,74.88 76.07,75.05 76.58,75.56 76.58,81.92 77.85,83.19 78.87,83.19 80.14,84.45 80.14,86.36 84.96,91.19 84.96,98.17 83.69,99.44 83.69,102.62 83.19,103.12 83.19,106.81 82.68,107.31 82.68,111.51 82.42,111.76 81.88,111.76 81.66,111.98 81.66,112.3 81.88,112.52 83.57,112.52 83.82,112.27 83.82,109.35 v1(84.45,108.71)
DDR3-1_DQ53: length 64.9
  TOP w0.197: P6.166 v1(85.65,110.05) ; v1(69.69,67.04) U31.W26
  L7_SIGNAL w0.14: v1(85.65,110.05) 85.22,110.49 85.22,111.89 84.84,112.27 84.2,112.27 83.82,111.89 83.82,108.08 84.71,107.19 85.98,107.19 87,106.17 87.62,106.17 88.13,105.66 88.13,104.01 87.38,103.26 87.38,101.22 87.76,100.84 87.76,98.93 85.87,97.05 85.87,95.78 83.57,93.47 83.57,92.2 75.69,84.33 73.03,84.33 67.82,79.12 67.82,70.38 68.54,69.66 68.77,69.66 69.09,69.34 69.09,67.64 v1(69.69,67.04)
DDR3-1_DQ54: length 65
  TOP w0.197: v1(69.69,68.04) U31.W27 ; P6.174 88.05,110.53 87.63,110.11 87.63,109.35 v1(87,108.71)
  L7_SIGNAL w0.14: v1(69.69,68.04) 70.07,68.41 70.07,69.29 69.69,69.66 69.54,69.66 69.22,69.98 69.22,75.18 74.3,80.26 74.3,80.9 78.85,85.46 78.85,86.35 86.36,93.85 86.36,96.77 88.27,98.68 88.27,100.97 87.76,101.47 87.76,102.74 88.52,103.51 88.52,108.33 87.76,109.09 87.76,113.29 87.39,113.67 86.86,113.67 86.84,113.65 86.79,113.65 86.51,113.36 86.51,113.31 86.49,113.29 86.49,109.22 v1(87,108.71)
DDR3-1_DQ55: length 64.8
  TOP w0.197: v1(72.69,68.04) U31.AB27 ; P6.176 88.65,110.37 v1(88.27,109.98)
  L7_SIGNAL w0.14: v1(72.69,68.04) 72.14,68.59 72.14,75.31 79.38,82.55 80.64,82.55 89.66,91.57 89.66,97.28 89.92,97.54 91.31,97.54 91.57,97.79 91.57,103.12 90.81,103.89 90.81,107.31 90.17,107.95 90.17,113.92 89.92,114.17 88.52,114.17 88.27,113.92 v1(88.27,109.98)
DDR3-1_DQ56: length 65.4
  TOP w0.197: v1(68.69,65.04) U31.V24 ; v1(90.81,100.46) 90.16,101.11 P6.181
  L3_SIGNAL w0.14: v1(90.81,100.46) 90.17,101.09 90.17,102.11 89.79,102.49 89.25,102.49 89.03,102.71 89.03,103.03 89.25,103.25 91.6,103.25 91.82,103.47 91.82,103.79 91.6,104.01 87.5,104.01 86.61,103.12 86.61,101.35 85.98,100.71 85.98,95.76 86.36,95.38 86.36,89.28 78.61,81.53 74.68,81.53 74.04,80.9 74.04,80.39 71.37,77.72 71.12,77.72 71.1,77.71 70.85,77.71 70.07,76.92 70.07,70.88 69.85,70.66 69.74,70.66 69.07,69.99 69.07,68.88 68.85,68.66 68.66,68.66 68.32,68.32 68.32,65.41 v1(68.69,65.04)
DDR3-1_DQ57: length 65.1
  TOP w0.197: P6.183 v1(90.75,101.78) ; v1(68.69,66.04) U31.V25
  L3_SIGNAL w0.14: v1(68.69,66.04) 69.32,66.66 69.32,68.19 69.54,68.41 69.56,68.41 69.81,68.66 69.85,68.66 70.07,68.88 70.07,68.92 70.32,69.17 70.32,70.32 70.66,70.66 70.85,70.66 71.07,70.88 71.07,71.07 71.25,71.25 71.25,75.31 70.99,75.56 70.99,76.84 72.26,78.11 75.82,78.11 86.74,89.03 86.74,97.79 87.12,98.17 87.12,99.57 87.63,100.08 87.63,100.71 87.25,101.09 87.25,101.73 87.63,102.11 88.01,102.11 88.14,102.23 88.14,102.62 88.01,102.74 87.38,102.74 87.25,102.87 87.25,103.25 87.5,103.51 88.39,103.51 88.65,103.25 88.65,102.23 88.9,101.98 88.9,100.46 89.41,99.95 91.19,99.95 91.44,100.2 92.46,100.2 92.84,100.58 92.84,100.84 92.58,101.09 91.95,101.09 91.69,101.35 91.69,102.62 91.44,102.87 90.93,102.87 90.68,102.62 90.68,101.85 v1(90.75,101.78)
DDR3-1_DQ58: length 65.5
  TOP w0.197: v1(69.69,65.04) U31.W24 ; v1(93.34,101.73) 93.16,101.92 P6.191
  L3_SIGNAL w0.14: v1(69.69,65.04) 69.92,65.27 70.09,65.27 70.49,65.66 70.85,65.66 71.07,65.88 71.07,67.26 71.32,67.51 71.32,68.19 71.54,68.41 71.8,68.41 72.26,68.87 72.26,70.1 72.32,70.16 72.32,70.19 72.54,70.41 72.6,70.41 73.07,70.88 73.07,70.94 73.54,71.41 73.6,71.41 74.3,72.11 74.3,73.03 75.32,74.05 75.32,74.19 75.54,74.41 75.68,74.41 76.32,75.05 76.32,75.3 80.9,79.88 80.9,80.52 86.74,86.36 87,86.36 87.12,86.23 87.12,85.98 82.3,81.15 82.3,80.9 82.55,80.64 82.68,80.64 87.5,85.47 87.5,92.71 93.73,98.93 93.73,100.97 93.34,101.35 v1(93.34,101.73)
DDR3-1_DQ59: length 65.2
  TOP w0.197: v1(69.69,66.04) U31.W25 ; P6.193 93.75,102.21 93.98,101.98 93.98,101.09 v1(93.34,100.46)
  L3_SIGNAL w0.14: v1(69.69,66.04) 69.69,66.51 70.07,66.88 70.07,68.03 70.7,68.66 70.85,68.66 71.07,68.88 71.07,69.03 71.25,69.22 71.25,70.23 71.68,70.66 71.85,70.66 72.07,70.88 72.07,71.05 72.14,71.12 72.14,75.31 72.64,75.82 72.64,76.07 74.17,77.6 75.95,77.6 87.12,88.77 87.12,97.54 87.5,97.92 87.5,99.09 87.73,99.31 88.04,99.31 88.27,99.09 88.27,97.54 87.76,97.03 87.76,94.87 88.01,94.62 88.52,94.62 88.84,94.93 88.84,99.07 89.08,99.31 89.42,99.31 89.66,99.07 89.66,97.38 89.89,97.16 90.2,97.16 90.42,97.38 90.42,98.93 90.81,99.31 92.2,99.31 v1(93.34,100.46)
DDR3-1_DQ60: length 65.3
  TOP w0.197: P6.180 89.86,110.3 v1(89.53,109.98) ; v1(70.69,65.04) U31.Y24
  L3_SIGNAL w0.14: v1(70.69,65.04) 70.23,64.58 70.23,64.01 69.72,63.5 68.45,63.5 67.18,64.77 67.18,69.47 68.07,70.36 68.07,77.09 74.93,83.95 79.5,83.95 85.47,89.92 85.47,94.62 85.22,94.87 85.22,102.11 85.6,102.49 85.6,105.66 87.5,107.57 88.39,107.57 88.77,107.95 88.77,109.22 v1(89.53,109.98)
DDR3-1_DQ61: length 65.1
  TOP w0.197: v1(71.69,66.04) U31.AA25 ; v1(90.81,109.98) 90.45,110.33 P6.182
  L3_SIGNAL w0.14: v1(71.69,66.04) 72.32,66.66 72.85,66.66 73.07,66.88 73.07,67.41 73.32,67.66 73.32,68.19 73.66,68.54 73.66,68.83 74.49,69.66 74.85,69.66 75.07,69.88 75.07,70.19 75.54,70.66 75.85,70.66 76.07,70.88 76.07,71.19 76.54,71.66 76.85,71.66 77.07,71.88 77.07,72.19 77.54,72.66 77.85,72.66 78.07,72.88 78.07,73.19 78.54,73.66 78.85,73.66 79.07,73.88 79.07,74.19 79.54,74.66 79.85,74.66 80.07,74.88 80.07,75.24 88.65,83.82 88.65,91.95 94.74,98.04 94.74,105.23 95.05,105.54 95.5,105.54 95.76,105.79 95.76,106.17 95.5,106.43 94.62,106.43 94.36,106.68 94.36,106.93 94.74,107.31 95.5,107.31 95.76,107.57 95.76,107.82 95.5,108.08 91.06,108.08 90.42,108.71 90.42,108.97 90.81,109.35 v1(90.81,109.98)
DDR3-1_DQ62: length 65.1
  TOP w0.197: P6.192 v1(93.45,113.16) ; v1(71.69,64.04) U31.AA23
  L3_SIGNAL w0.14: v1(71.69,64.04) 72.16,64.04 72.54,64.41 73.6,64.41 74.07,64.88 74.07,65.05 74.68,65.66 74.85,65.66 75.07,65.88 75.07,66.05 75.31,66.29 75.31,68.2 75.78,68.66 75.85,68.66 76.07,68.88 76.07,68.95 77.78,70.66 77.85,70.66 78.07,70.88 78.07,70.95 78.78,71.66 78.85,71.66 79.07,71.88 79.07,71.95 79.78,72.66 79.85,72.66 80.07,72.88 80.07,72.95 80.78,73.66 80.85,73.66 82.07,74.88 82.07,74.95 89.66,82.55 89.66,91.62 92.1,94.06 92.28,94.06 96.39,98.17 96.39,101.45 96.53,101.59 96.53,101.9 96.39,102.04 96.39,103.63 97.01,104.25 97.01,108.96 96.08,109.89 96.08,110.04 95.38,110.74 95.38,111.76 93.98,113.16 v1(93.45,113.16)
DDR3-1_DQ63: length 65.3
  TOP w0.197: v1(71.69,65.04) U31.AA24 ; P6.194 94.05,110.44 93.6,109.98 v1(93.34,109.98)
  L3_SIGNAL w0.14: v1(71.69,65.04) 72.16,65.04 72.54,65.41 72.65,65.41 73.32,66.08 73.32,66.19 73.54,66.41 73.65,66.41 74.17,66.93 74.17,68.07 74.76,68.66 74.85,68.66 75.07,68.88 75.07,68.97 75.76,69.66 75.85,69.66 76.07,69.88 76.07,69.97 76.76,70.66 76.85,70.66 77.07,70.88 77.07,70.97 78.76,72.66 78.85,72.66 79.07,72.88 79.07,72.97 79.76,73.66 79.85,73.66 80.07,73.88 80.07,73.97 80.76,74.66 80.85,74.66 81.07,74.88 81.07,74.97 89.15,83.06 89.15,91.49 91.99,94.33 92.17,94.33 96.01,98.17 96.01,101.36 95.78,101.59 95.78,104.98 96.02,105.23 96.02,108.3 95.62,108.7 95.62,108.87 95.41,109.09 95.17,109.09 94.88,109.38 94.88,111.63 94.37,112.14 93.34,112.14 92.84,111.63 92.84,110.49 v1(93.34,109.98)
DDR3-1_DQS0_N: length 64.3
  TOP w0.152: v1(59.69,65.04) U31.K24 ; v1(36.45,108.71) 36.58,108.84 36.58,110.5 36.46,110.62 P6.10
  L3_SIGNAL w0.13: v1(36.45,108.71) 36.7,108.96 36.7,109.35 36.95,109.6 37.98,109.6 38.23,109.35 38.23,104.25 40.13,102.34 40.13,96.37 42.4,94.11 45.34,94.11 58.42,81.02 58.42,78.08 59.32,77.19 59.32,63.89 59.54,63.67 59.84,63.67 60.06,63.89 60.06,64.54 60.06,64.54 60.06,64.67 v1(59.69,65.04)
DDR3-1_DQS0_P: length 64.3
  TOP w0.14: v1(60.69,65.04) U31.L24
  TOP w0.152: v1(37.08,108.71) 36.86,108.94 36.86,110.42 37.06,110.62 P6.12
  L3_SIGNAL w0.13: v1(60.69,65.04) 60.32,64.67 60.32,64.43 60.32,64.43 60.32,63.78 59.95,63.41 59.43,63.41 59.06,63.78 59.06,77.08 58.17,77.98 58.17,80.92 45.23,93.85 42.29,93.85 39.88,96.27 39.88,97.26 39.88,97.26 39.88,97.37 39.88,102.24 37.97,104.14 37.97,109.24 37.87,109.34 37.06,109.34 36.96,109.24 36.96,108.84 v1(37.08,108.71)
DDR3-1_DQS1_N: length 64
  TOP w0.152: v1(55.69,72.04) U31.F31 ; P6.27 41.55,102.19 41.75,101.99 41.75,100.68 v1(41.53,100.46)
  L7_SIGNAL w0.13: v1(41.53,100.46) 41.66,100.59 41.65,100.6 41.65,105.81 41.55,105.92 40.54,105.92 40.13,106.32 40.13,107.31 40.39,107.57 44.96,107.57 45.21,107.31 45.21,103.51 44.96,103.25 42.91,103.25 42.8,103.15 42.8,99.57 42.55,99.31 42.04,99.31 41.79,99.06 41.79,91.67 41.89,91.57 42.78,91.57 51.31,83.04 51.31,79.99 52.32,78.98 52.32,71.89 52.54,71.67 55.32,71.67 v1(55.69,72.04)
DDR3-1_DQS1_P: length 63.6
  TOP w0.152: P6.29 42.16,102.18 42.03,102.06 42.03,100.66 42.16,100.53 v1(42.16,100.46) ; v1(55.69,71.04) U31.F30
  L7_SIGNAL w0.13: v1(42.16,100.46) 41.91,100.71 41.91,105.92 41.66,106.17 40.64,106.17 40.39,106.43 40.39,107.21 40.49,107.31 44.85,107.31 44.96,107.21 44.96,103.61 44.85,103.51 42.8,103.51 42.55,103.25 42.55,99.67 42.44,99.57 41.93,99.57 41.53,99.17 41.53,91.57 41.78,91.31 42.67,91.31 51.05,82.93 51.05,79.88 52.06,78.87 52.06,71.78 52.43,71.41 55.32,71.41 v1(55.69,71.04)
DDR3-1_DQS2_N: length 63
  TOP w0.152: v1(46.99,100.46) 47.24,100.71 47.24,101.29 47.18,101.36 47.18,102.23 46.95,102.46 P6.45 ; v1(57.69,69.04) U31.H28
  L16_SIGNAL w0.13: v1(46.99,100.46) 47.31,100.14 47.31,98.98 47.77,98.52 48.61,98.52 48.99,98.9 48.99,104.58 49,104.59 49,106.68 49.38,107.06 49.8,107.06 50.16,106.7 50.16,98.55 49.28,97.67 47.99,97.67 47.75,97.67 47.24,97.16 47.24,95.27 53.47,89.05 53.47,79.39 56.79,76.07 57.66,76.07 58.06,75.67 58.06,69.45 58.06,69.45 58.06,68.78 58.07,68.78 58.07,68.48 58,68.42 57.82,68.42 57.66,68.58 57.66,69.01 v1(57.69,69.04)
DDR3-1_DQS2_P: length 62.5
  TOP w0.14: v1(58.69,68.04) U31.J27
  TOP w0.152: P6.47 47.55,102.33 47.46,102.23 47.46,101.47 47.52,101.41 47.52,100.69 v1(47.75,100.46)
  L16_SIGNAL w0.13: v1(58.69,68.04) 58.32,68.41 58.32,68.89 58.32,69.56 58.32,69.56 58.32,75.78 57.77,76.33 56.9,76.33 53.72,79.5 53.72,89.15 47.5,95.37 47.5,97.05 47.86,97.41 47.88,97.41 49.38,97.41 50.42,98.45 50.42,106.8 49.91,107.31 49.28,107.31 48.74,106.78 48.74,104.7 48.73,104.69 48.73,99.01 48.5,98.78 47.87,98.78 47.56,99.09 47.56,100.27 v1(47.75,100.46)
DDR3-1_DQS3_N: length 49
  TOP w0.152: v1(57.69,75.04) U31.H34 ; v1(52.04,109.64) 52.3,109.9 52.3,110.43 52.06,110.67 P6.62
  L20_SIGNAL w0.13: v1(57.69,75.04) 57.69,74.92 57.44,74.67 56.54,74.67 56.32,74.89 56.32,76.63 54.1,78.85 54.1,88.75 48.64,94.21 48.64,98.78 48.51,98.91 48.51,100.95 47.12,102.34 47.12,105.48 46.23,106.37 46.23,107.7 46.61,108.07 47.11,108.07 47.13,108.09 47.25,108.09 48.26,109.09 50.17,109.09 51.31,110.23 51.96,110.23 52.19,110 52.19,109.79 v1(52.04,109.64)
DDR3-1_DQS3_P: length 50.2
  TOP w0.152: v1(52.69,109.6) 52.6,109.69 52.6,109.75 52.58,109.78 52.58,111.47 P6.64 ; v1(57.69,74.04) U31.H33
  L20_SIGNAL w0.13: v1(52.69,109.6) 52.45,109.84 52.45,110.11 52.07,110.49 51.2,110.49 50.06,109.35 48.15,109.35 47.14,108.34 47.02,108.34 47.01,108.33 46.5,108.33 45.97,107.8 45.97,106.26 46.86,105.37 46.86,102.24 48.26,100.84 48.26,98.81 48.39,98.68 48.39,94.11 53.85,88.65 53.85,78.74 56.06,76.52 56.06,74.78 56.43,74.41 57.32,74.41 v1(57.69,74.04)
DDR3-1_DQS4_N: length 50.9
  TOP w0.152: P6.135 76.35,102.74 76.53,102.57 76.53,100.91 v1(76.33,100.71) ; v1(73.69,75.04) U31.AC34
  L20_SIGNAL w0.13: v1(73.69,75.04) 73.28,75.45 73.28,76.96 72.57,77.67 72.57,80.97 76.96,85.36 76.96,87.5 82.8,93.34 82.8,95.87 82.43,96.25 82.43,97.01 80.27,99.17 80.27,103.63 80.01,103.89 79.23,103.89 78.87,104.25 78.87,105.92 78.36,106.43 77.34,106.43 76.96,106.04 76.96,104.25 76.73,104.01 75.82,104.01 75.31,103.51 75.31,102.99 75.82,102.49 76.35,102.49 76.58,102.26 76.58,100.96 v1(76.33,100.71)
DDR3-1_DQS4_P: length 51.1
  TOP w0.152: P6.137 76.95,102.69 76.81,102.55 76.81,100.99 v1(77.09,100.71) ; v1(72.69,74.04) U31.AB33
  L20_SIGNAL w0.13: v1(72.69,74.04) 72.9,74.25 72.9,74.72 73.06,74.89 73.06,75.31 73.02,75.34 73.02,76.86 72.31,77.56 72.31,81.08 76.71,85.47 76.71,87.61 82.55,93.45 82.55,95.76 82.17,96.14 82.17,96.9 80.01,99.06 80.01,103.53 79.91,103.63 79.12,103.63 78.61,104.14 78.61,105.81 78.25,106.17 77.45,106.17 77.22,105.94 77.22,104.14 76.83,103.76 75.93,103.76 75.57,103.4 75.57,103.1 75.93,102.74 76.45,102.74 76.84,102.36 76.84,100.97 v1(77.09,100.71)
DDR3-1_DQS5_N: length 55
  TOP w0.152: v1(72.69,71.04) U31.AB30 ; P6.152 81.46,110.7 81.66,110.49 81.66,110.13 v1(81.51,109.98)
  L16_SIGNAL w0.13: v1(72.69,71.04) 72.32,71.41 72.32,73.21 72.52,73.4 72.76,73.41 72.95,73.41 73.32,73.78 73.32,74.19 73.54,74.41 73.95,74.41 74.32,74.78 74.32,75.19 82.95,83.82 82.95,87.52 86.2,90.77 86.2,97.13 85.95,97.39 85.95,100.81 87.1,101.96 87.1,105.69 86.36,106.43 86.36,110.47 85.58,111.25 82.44,111.25 81.66,110.47 81.66,110.13 v1(81.51,109.98)
DDR3-1_DQS5_P: length 54.2
  TOP w0.152: v1(82.14,109.98) 82.14,110 81.94,110.2 81.94,110.52 82.05,110.63 P6.154 ; v1(71.69,71.04) U31.AA30
  L16_SIGNAL w0.13: v1(82.14,109.98) 81.92,110.21 81.92,110.36 82.55,111 85.47,111 86.1,110.36 86.1,106.32 86.84,105.58 86.84,102.07 85.69,100.91 85.69,97.28 85.94,97.03 85.94,90.88 82.7,87.63 82.7,83.93 74.06,75.29 74.06,74.89 73.84,74.67 73.43,74.67 73.06,74.29 73.06,73.89 72.84,73.67 72.58,73.67 72.58,73.66 72.57,73.66 72.41,73.66 72.06,73.31 72.06,71.41 v1(71.69,71.04)
DDR3-1_DQS6_N: length 63.7
  TOP w0.152: P6.169 86.56,102.62 86.73,102.44 86.73,100.7 v1(86.49,100.46) ; v1(68.69,69.04) U31.V28
  L7_SIGNAL w0.13: v1(86.49,100.46) 86.74,100.71 86.74,104.28 86.74,104.28 86.74,104.6 86.84,104.7 86.84,105.1 86.56,105.39 86.56,105.39 86.41,105.53 85.72,105.53 85.57,105.38 85.49,105.31 85.34,105.16 85.34,100.22 84.82,99.69 83.44,99.69 82.68,98.93 82.68,98.43 82.89,98.22 84.66,98.22 85.34,97.54 85.34,96.03 83,93.68 83,92.54 77.83,87.37 71.37,87.37 67.32,83.32 67.32,68.89 67.54,68.67 68.54,68.67 68.69,68.82 v1(68.69,69.04)
DDR3-1_DQS6_P: length 65
  TOP w0.14: v1(68.69,68.04) U31.V27
  TOP w0.152: P6.171 87.16,102.62 87.01,102.47 87.01,100.7 v1(87.25,100.46)
  L7_SIGNAL w0.13: v1(68.69,68.04) 68.69,68.3 68.58,68.41 67.43,68.41 67.06,68.78 67.06,83.43 71.27,87.63 77.72,87.63 82.74,92.65 82.74,93.79 85.09,96.14 85.09,97.09 85.09,97.09 85.09,97.43 84.56,97.96 82.78,97.96 82.7,98.04 82.42,98.32 82.42,99.04 83.33,99.95 84.71,99.95 85.09,100.33 85.09,105.26 85.39,105.56 85.46,105.64 85.54,105.71 85.62,105.79 86.51,105.79 86.66,105.64 86.67,105.64 87.1,105.21 87.1,104.59 87,104.49 87,104.39 87,100.71 v1(87.25,100.46)
DDR3-1_DQS7_N: length 64.4
  TOP w0.152: v1(91.57,109.73) 91.82,109.98 91.82,110.45 91.65,110.62 P6.186 ; v1(72.69,67.04) U31.AB26
  L3_SIGNAL w0.13: v1(91.57,109.73) 91.57,109.75 91.8,109.98 91.8,111.27 91.69,111.38 90.4,111.38 90.3,111.27 90.3,109.22 89.92,108.84 89.92,107.8 90.17,107.54 93.34,107.54 93.6,107.29 93.6,105.21 93.5,105.1 93.5,104.35 94.36,103.48 94.36,98.45 88.14,92.22 88.14,84.97 78.58,75.41 78.54,75.41 78.32,75.19 78.32,74.78 77.95,74.41 77.54,74.41 77.32,74.19 77.32,73.78 76.95,73.41 76.54,73.41 76.32,73.19 76.32,72.78 75.95,72.41 75.54,72.41 74.32,71.19 74.32,70.78 73.95,70.41 73.54,70.41 73.32,70.19 73.32,69.19 72.32,68.2 72.32,67.54 72.32,67.54 72.32,67.41 v1(72.69,67.04)
DDR3-1_DQS7_P: length 65.3
  TOP w0.14: v1(71.69,67.04) U31.AA26
  TOP w0.152: P6.188 92.26,110.64 92.1,110.49 92.1,109.87 92.09,109.86 92.22,109.73 v1(92.33,109.73)
  L3_SIGNAL w0.13: v1(92.33,109.73) 92.05,110 92.05,111.38 91.8,111.63 90.29,111.63 90.04,111.38 90.04,109.33 89.66,108.95 89.66,107.69 90.06,107.28 93.24,107.28 93.34,107.18 93.34,105.31 93.24,105.21 93.24,104.25 94.11,103.38 94.11,98.55 87.88,92.33 87.88,85.07 78.48,75.67 78.43,75.67 78.06,75.3 78.06,74.89 77.84,74.67 77.44,74.67 77.06,74.29 77.06,73.89 76.84,73.67 76.44,73.67 76.06,73.29 76.06,72.89 75.84,72.67 75.44,72.67 74.06,71.29 74.06,70.89 73.84,70.67 73.44,70.67 73.06,70.29 73.06,69.3 72.06,68.31 72.06,67.65 72.06,67.65 72.06,67.41 v1(71.69,67.04)
DDR3-1_ODT0: length 69.7
  TOP w0.197: v1(70.48,109.98) 70.65,110.15 P6.116 ; v1(64.69,68.04) U31.R27
  L7_SIGNAL w0.14: v1(70.48,109.98) 69.85,110.62 69.85,114.17 70.23,114.55 70.23,120.14 69.72,120.65 68.71,120.65 68.2,120.14 68.2,116.71 68.58,116.33 68.58,109.6 68.07,109.09 68.07,105.92 67.31,105.16 67.31,92.84 v1(66.67,92.2)
  L22_SIGNAL w0.14: v1(66.67,92.2) 67.18,91.69 67.18,86.23 65.15,84.2 65.15,68.58 64.69,68.12 v1(64.69,68.04)
DDR3-1_ODT1: length 69.5
  TOP w0.197: v1(66.69,69.04) U31.U28 ; P6.120 71.86,110.08 v1(71.75,109.98)
  L5_SIGNAL w0.14: v1(66.69,69.04) 66.69,69.1 67.31,69.72 67.31,83.57 66.57,84.31 66.57,86.63 67.44,87.5 67.44,90.17 v1(66.67,90.93)
  L7_SIGNAL w0.14: v1(71.75,109.98) 72.39,110.62 72.39,113.54 73.03,114.17 73.03,120.4 72.64,120.78 72.26,120.78 71.75,120.27 71.75,114.17 71.12,113.54 71.12,109.6 69.85,108.33 69.85,104.14 68.81,103.1 68.81,101.56 68.83,101.53 68.83,99.7 68.2,99.06 68.2,92.46 v1(66.67,90.93)
DDR3-1_RASB: length 40
  TOP w0.197: P6.110 68.86,110.34 v1(69.22,109.98) ; v1(63.69,75.04) U31.P34
  L22_SIGNAL w0.14: v1(69.22,109.98) 68.45,109.22 68.45,101.73 68.83,101.35 68.83,100.2 64.14,95.5 64.14,75.95 63.69,75.5 v1(63.69,75.04)
DDR3-1_REF_EN: length 159.7
  TOP w0.14: RN6.16 v1(187.68,53.57)
  L18_SIGNAL w0.095: v1(187.68,53.57) 183.84,57.4 177.55,57.4 174.75,60.2 154.05,60.2 150.18,64.07 v1(146.37,64.07)
  L20_SIGNAL w0.095: v1(146.37,64.07) 126.49,83.95 126.49,102.36 122.81,106.05 122.81,124.21 120.52,126.49 97.92,126.49 92.46,131.95 83.69,131.95 v1(83.44,132.21)
  BOTTOM w0.14: R559.1 v1(83.44,132.21)
DDR3-1_RESETB: length 58.5
  TOP w0.197: v1(56.69,72.04) U31.G31 ; P6.30 v1(42.46,113.88)
  L3_SIGNAL w0.14: v1(42.46,113.88) 39.33,113.88 36.07,110.62 36.07,98.93 53.85,81.15 53.85,78.36 56.13,76.07 56.13,72.52 56.61,72.04 v1(56.69,72.04)
  BOTTOM w0.197: R241.2 42.46,114.39 v1(42.46,113.88)
DDR3-1_S0B: length 48.6
  TOP w0.197: v1(65.69,69.04) U31.T28 ; P6.114 70.05,112.73 v1(70.48,113.16)
  L22_SIGNAL w0.14: v1(70.48,113.16) 69.98,112.65 69.98,100.46 67.82,98.3 67.82,84.45 66.17,82.8 66.17,69.6 65.69,69.12 v1(65.69,69.04)
DDR3-1_S1B: length 42.2
  TOP w0.197: v1(66.69,67.04) U31.U26 ; P6.121 72.16,102.09 72.3,101.95 72.3,101 v1(71.75,100.46)
  L5_SIGNAL w0.14: v1(66.67,88.39) 66.04,87.76 66.04,84.2 65.02,83.19 65.02,78.36 66.17,77.22 66.17,67.56 v1(66.69,67.04)
  L7_SIGNAL w0.14: v1(66.67,88.39) 68.33,88.39 72.26,92.33 72.26,99.95 v1(71.75,100.46)
DDR3-1_SYS_CLK_N: length 102.1
  TOP w0.127: v1(64.69,70.04) U31.R29
  TOP w0.14: v1(142.75,106.17) 142.75,106.43 R105.2 R104.1 C69.2
  L18_SIGNAL w0.089: v1(64.69,70.04) 65.12,69.61 67.14,69.61 67.98,70.45 67.98,75.09 67.98,75.27 68.49,75.78 69.76,75.78 74.08,80.1 74.26,80.1 80.94,80.1 96.46,95.63 114.24,95.63 123.1,104.49 135.29,104.49 141.9,104.49 143.04,105.63 143.04,105.88 v1(142.75,106.17)
  BOTTOM w0.102: R627.2 64.82,69.91 v1(64.69,70.04)
DDR3-1_SYS_CLK_P: length 102.4
  TOP w0.102: v1(64.69,69.04) U31.R28
  TOP w0.14: C70.2 143.89,106.81 143.51,106.43 v1(143.51,106.17)
  L18_SIGNAL w0.089: v1(143.51,106.17) 143.26,105.92 143.26,105.54 141.99,104.27 123.19,104.27 114.33,95.42 113.7,95.42 113.7,95.41 96.55,95.41 81.02,79.89 80.85,79.89 80.84,79.88 74.17,79.88 69.85,75.56 68.58,75.56 68.2,75.18 68.2,70.48 68.2,70.48 68.2,70.36 67.23,69.39 67.11,69.39 67.11,69.39 65.04,69.39 v1(64.69,69.04)
  BOTTOM w0.14: v1(64.69,69.04) 64.93,69.28 R627.1
DDR3-1_TEMP_EVENTB: length 66
  TOP w0.197: v1(66.69,66.04) U31.U25 ; P6.198 v1(95.26,109.98)
  L5_SIGNAL w0.14: v1(66.69,66.04) 66.8,66.04 68.07,67.31 68.07,80.39 68.71,81.03 68.71,85.47 76.71,93.47 83.31,93.47 85.09,95.25 87.5,95.25 90.17,97.92 90.17,103.38 90.81,104.01 90.81,106.93 91.69,107.82 94.11,107.82 94.74,108.46 94.74,109.47 v1(95.26,109.98)
  BOTTOM w0.197: R240.2 95.63,110.36 v1(95.26,109.98)
DDR3-1_WEB: length 32.3
  TOP w0.197: v1(65.69,75.04) U31.T34 ; P6.113 69.76,102.27 v1(69.22,101.73)
  L7_SIGNAL w0.14: v1(69.22,101.73) 70.36,100.58 70.36,92.96 v1(69.6,92.2)
  L20_SIGNAL w0.14: v1(69.6,92.2) 68.33,90.93 68.33,87.88 65.69,85.25 65.69,79.91 66.15,79.45 66.15,79.05 65.86,78.76 65.86,76.82 66.15,76.53 66.15,76.12 65.69,75.67 v1(65.69,75.04)
DDR3-2_ADDR00: length 65.5
  TOP w0.197: P5.98 120.93,55.4 v1(120.78,55.25) ; v1(79.69,57.04) U31.AJ17
  L3_SIGNAL w0.14: v1(120.78,55.25) 120.78,54.86 121.03,54.61 124.24,54.61 124.46,54.39 124.46,54.07 124.24,53.85 116.84,53.85 116.59,54.1 116.59,55.63 116.33,55.88 115.32,55.88 115.06,55.63 105.79,55.63 105.54,55.88 105.54,56.26 105.79,56.52 110.36,56.52 110.62,56.77 110.62,57.4 110.36,57.66 80.26,57.66 79.69,57.08 v1(79.69,57.04)
DDR3-2_ADDR01: length 64.1
  TOP w0.197: v1(81.69,54.04) U31.AL14 ; P5.97 112.07,55.7 v1(111.25,56.52)
  L9_SIGNAL w0.14: v1(111.25,56.52) 111.25,56.26 111.51,56.01 124.21,56.01 124.46,55.75 124.46,54.86 124.21,54.61 117.73,54.61 117.35,54.23 110.74,54.23 110.49,53.98 110.49,52.7 110.24,52.45 82.55,52.45 82.07,52.94 82.07,53.19 81.69,53.57 v1(81.69,54.04)
DDR3-2_ADDR02: length 63
  TOP w0.197: P5.96 120.89,56 120.78,55.88 120.14,55.88 v1(119.51,55.25) ; v1(80.69,54.04) U31.AK14
  L18_SIGNAL w0.14: v1(119.51,55.25) 119.76,54.99 119.76,54.16 118.75,53.14 118.75,51.68 116.37,49.3 114.91,49.3 113.28,50.93 111.12,50.93 110.49,51.56 105.21,51.56 105.03,51.38 105.03,51.11 105.21,50.93 110.39,50.93 110.62,50.7 110.62,50.39 110.39,50.17 104.01,50.17 103.12,51.05 99.44,51.05 95.5,54.99 89.03,54.99 88.39,55.63 82.75,55.63 82.32,55.19 82.32,55.01 82.04,54.74 81.92,54.74 81.66,54.48 81.13,54.48 v1(80.69,54.04)
DDR3-2_ADDR03: length 66.6
  TOP w0.197: v1(112.52,56.52) 112.74,56.3 P5.95 ; v1(81.69,59.04) U31.AL18
  L22_SIGNAL w0.14: v1(112.52,56.52) 112.52,57.02 112.78,57.28 127.39,57.28 127.76,57.65 127.76,58.18 127.39,58.55 106.3,58.55 106.05,58.29 106.05,58.04 105.79,57.78 88.77,57.78 87.88,58.67 85.73,58.67 85.22,58.17 82.56,58.17 v1(81.69,59.04)
DDR3-2_ADDR04: length 65.5
  TOP w0.197: v1(120.78,56.52) 120.78,56.77 121.2,57.19 P5.92 ; v1(80.69,59.04) U31.AK18
  L3_SIGNAL w0.14: v1(80.69,59.04) 81.32,59.66 81.85,59.66 82.07,59.88 82.07,60.19 82.45,60.58 85.6,60.58 86.23,59.94 102.36,59.94 103.76,58.55 110.62,58.55 111.12,58.04 111.76,58.04 112.14,58.42 112.14,58.93 112.39,59.18 112.78,59.18 113.16,58.8 113.16,58.04 113.54,57.66 113.79,57.66 114.05,57.91 114.05,58.8 114.43,59.18 114.81,59.18 115.06,58.93 115.06,57.66 115.44,57.28 117.09,57.28 117.48,57.66 117.48,59.44 117.73,59.69 118.62,59.69 118.87,59.44 118.87,57.66 119.13,57.4 123.77,57.4 123.9,57.53 125.73,57.53 125.98,57.28 125.98,56.13 125.73,55.88 121.03,55.88 120.78,56.13 v1(120.78,56.52)
DDR3-2_ADDR05: length 65.1
  TOP w0.197: v1(112.52,57.78) 112.81,57.49 P5.91 ; v1(82.69,55.04) U31.AM15
  L9_SIGNAL w0.14: v1(82.69,55.04) 82.73,55.04 83.19,55.5 99.31,55.5 102.74,58.93 107.19,58.93 109.47,61.21 114.43,61.21 114.68,60.96 125.35,60.96 125.86,60.45 125.86,57.78 125.35,57.28 112.78,57.28 112.52,57.53 v1(112.52,57.78)
DDR3-2_ADDR06: length 62.2
  TOP w0.197: v1(81.69,55.04) U31.AL15 ; P5.90 v1(120.79,57.79)
  L18_SIGNAL w0.14: v1(120.79,57.79) 121.54,57.79 121.79,58.05 121.79,58.29 121.54,58.55 120.4,58.55 120.14,58.29 120.14,56.41 119.89,56.15 119.67,56.15 119.13,55.62 119.13,55.09 119.14,55.08 119.14,54.24 118.24,53.34 118.24,51.69 116.2,49.66 115.44,49.66 114.17,50.93 114.17,51.31 114.43,51.56 114.71,51.56 114.94,51.79 114.94,52.11 114.71,52.33 112.7,52.33 112.69,52.32 112.38,52.32 112.37,52.33 110.61,52.33 109.86,53.09 103.31,53.09 103.12,52.9 103.12,52.64 103.31,52.45 104.55,52.45 104.78,52.23 104.78,51.91 104.55,51.69 101.98,51.69 101.6,52.07 100.2,52.07 99.82,51.69 99.57,51.69 97.66,53.59 97.66,54.23 98.04,54.61 98.04,54.86 97.54,55.37 89.79,55.37 88.78,56.39 84.87,56.39 84.85,56.41 82.96,56.41 81.69,55.15 v1(81.69,55.04)
DDR3-2_ADDR07: length 72.3
  TOP w0.197: P5.86 v1(120.84,59) ; v1(82.69,57.04) U31.AM17
  L3_SIGNAL w0.14: v1(120.84,59) 121.6,59 122.3,58.29 130.05,58.29 130.3,58.04 131.83,58.04 132.08,57.78 132.08,57.28 131.83,57.02 127.25,57.02 126.62,56.39 126.62,52.45 126.24,52.07 122.3,52.07 121.16,50.93 120.65,50.93 120.02,50.29 116.46,50.29 115.95,50.8 112.01,50.8 111.51,50.29 96.52,50.29 94.87,51.94 91.95,51.94 87.48,56.41 83.32,56.41 v1(82.69,57.04)
DDR3-2_ADDR08: length 64.2
  TOP w0.197: v1(84.69,54.04) U31.AP14 ; v1(111.25,59.06) 111.89,58.42 112.65,58.42 112.97,58.09 P5.89
  L9_SIGNAL w0.14: v1(84.69,54.04) 109.73,54.04 109.98,54.29 109.98,54.74 109.73,54.99 102.62,54.99 102.36,55.25 102.36,55.75 102.62,56.01 110.36,56.01 110.62,56.26 110.62,56.52 110.36,56.77 103.5,56.77 103.25,57.02 103.25,57.28 103.5,57.53 111,57.53 111.25,57.78 v1(111.25,59.06)
DDR3-2_ADDR09: length 65.4
  TOP w0.197: P5.85 113.04,59.3 112.65,59.69 111.89,59.69 v1(111.25,60.33) ; v1(83.69,54.04) U31.AN14
  L9_SIGNAL w0.14: v1(83.69,54.04) 83.69,54.1 84.2,54.61 99.44,54.61 103,58.17 107.31,58.17 108.71,59.56 114.11,59.56 114.3,59.38 114.3,59.11 114.11,58.93 113.16,58.93 113.03,58.8 113.03,58.55 113.16,58.42 124.21,58.42 124.46,58.67 124.46,59.44 124.21,59.69 115.32,59.69 114.17,60.83 111.51,60.83 111.25,60.58 v1(111.25,60.33)
DDR3-2_ADDR10: length 66.7
  TOP w0.197: P5.107 v1(112.53,52.7) ; v1(84.69,56.04) U31.AP16
  L22_SIGNAL w0.14: v1(84.69,56.04) 84.72,56.01 85.6,56.01 85.85,55.75 94.74,55.75 102.49,48.01 104.14,48.01 104.78,47.37 107.31,47.37 108.2,48.26 111.63,48.26 113.54,46.36 114.55,46.36 114.94,46.74 114.94,47.12 114.81,47.24 113.54,47.24 113.05,47.74 113.05,48.02 113.19,48.17 114.94,48.17 115.19,48.42 115.19,48.77 114.94,49.02 113.41,49.02 112.9,49.53 111.12,49.53 110.49,48.89 106.14,48.89 105.92,49.12 105.92,49.43 106.14,49.66 108.97,49.66 109.22,49.91 109.22,50.67 109.47,50.93 114.43,50.93 114.81,51.31 114.81,52.31 114.43,52.7 v1(112.53,52.7)
DDR3-2_ADDR11: length 63.2
  TOP w0.197: v1(120.78,60.33) 120.78,59.94 121.13,59.6 P5.84 ; v1(84.69,57.04) U31.AP17
  L18_SIGNAL w0.14: v1(84.69,57.04) 84.83,56.9 88.65,56.9 89.66,55.88 97.92,55.88 101.09,52.7 102.11,52.7 103,53.59 110.62,53.59 111,53.21 112.27,53.21 112.9,53.85 118.24,53.85 118.87,54.48 118.87,54.97 118.87,54.98 118.87,58.29 118.61,58.55 111,58.55 110.74,58.8 110.74,59.44 111,59.69 120.52,59.69 120.78,59.94 v1(120.78,60.33)
DDR3-2_ADDR12: length 61.6
  TOP w0.197: v1(83.69,59.04) U31.AN18 ; v1(112.52,60.33) 112.95,59.89 P5.83
  L22_SIGNAL w0.14: v1(112.52,60.33) 113.16,60.96 126.49,60.96 126.75,60.71 126.75,59.94 126.49,59.69 114.68,59.69 114.55,59.56 91.31,59.56 90.81,59.06 85.6,59.06 85.21,58.66 84.07,58.66 v1(83.69,59.04)
DDR3-2_ADDR13: length 64.3
  TOP w0.197: v1(82.69,59.04) U31.AM18 ; v1(112.52,48.89) 112.72,49.09 P5.119
  L9_SIGNAL w0.14: v1(112.52,48.89) 116.74,48.89 117.51,49.66 122.68,49.66 122.94,49.91 122.94,50.29 122.68,50.55 119.82,50.55 119.71,50.44 119.3,50.44 119.2,50.55 117.35,50.55 116.46,49.66 109.6,49.66 108.84,50.42 92.33,50.42 91.31,51.44 82.68,51.44 82.07,52.05 82.07,52.19 81.85,52.41 81.7,52.41 81.07,53.05 81.07,56.19 81.03,56.23 81.03,57.4 82.66,59.04 v1(82.69,59.04)
DDR3-2_ADDR14: length 62.5
  TOP w0.197: v1(84.69,55.04) U31.AP15 ; v1(119.51,61.59) 120.14,60.96 121.03,60.96 121.2,60.79 P5.80
  L18_SIGNAL w0.14: v1(119.51,61.59) 119,61.59 118.75,61.85 118.75,62.99 119,63.25 119.89,63.25 120.14,62.99 120.14,61.28 120.4,61.02 121.73,61.02 121.92,60.83 121.92,58.8 122.17,58.55 122.81,58.55 123.06,58.29 123.06,55.12 122.81,54.86 122.3,54.86 121.92,54.48 121.92,53.32 120.68,52.08 120.51,52.08 120.27,51.83 120.27,50.67 119.89,50.29 117.73,50.29 116.48,49.03 114.16,49.03 113.53,49.67 103.38,49.67 102.5,50.55 99.19,50.55 95.38,54.36 87.63,54.36 87,54.99 84.74,54.99 v1(84.69,55.04)
DDR3-2_ADDR15: length 62.6
  TOP w0.197: v1(120.78,61.59) 120.98,61.4 P5.78 ; v1(83.69,55.04) U31.AN15
  L18_SIGNAL w0.14: v1(83.69,55.04) 84.12,54.61 86.36,54.61 89.28,51.69 95.5,51.69 98.81,48.39 100.2,48.39 102.87,45.72 112.78,45.72 115.19,48.13 115.95,48.13 116.22,48.41 116.22,48.46 116.51,48.75 116.57,48.75 117.35,49.53 121.16,49.53 121.79,50.17 121.79,51.94 123.44,53.59 124.21,53.59 124.59,53.98 124.59,60.58 124.33,60.83 123.44,60.83 123.19,61.09 123.19,61.34 122.94,61.59 v1(120.78,61.59)
DDR3-2_BA0: length 61.4
  TOP w0.197: v1(73.69,57.04) U31.AC17 ; v1(111.25,52.7) 111.51,52.7 112.12,52.09 P5.109
  L22_SIGNAL w0.14: v1(73.69,57.04) 74.21,56.52 85.98,56.52 86.23,56.26 97.03,56.26 102.23,51.05 108.71,51.05 108.97,51.31 108.97,51.82 108.71,52.07 102.74,52.07 102.49,52.32 102.49,52.7 102.74,52.96 108.71,52.96 108.97,53.21 108.97,54.48 109.22,54.74 110.24,54.74 110.49,54.48 110.49,52.96 110.74,52.7 v1(111.25,52.7)
DDR3-2_BA1: length 64.7
  TOP w0.197: P5.108 121.09,52.4 v1(120.78,52.7) ; v1(74.69,57.04) U31.AD17
  L22_SIGNAL w0.14: v1(120.78,52.7) 121.54,53.47 127,53.47 127.25,53.72 127.25,55.75 127,56.01 105.92,56.01 104.78,57.15 94.87,57.15 94.61,57.41 75.07,57.41 v1(74.69,57.04)
DDR3-2_BA2: length 66.1
  TOP w0.197: P5.79 113.02,61.09 v1(112.52,61.59) ; v1(74.69,54.04) U31.AD14
  L5_SIGNAL w0.14: v1(74.69,54.04) 77.03,54.04 77.65,54.66 77.85,54.66 78.07,54.88 78.07,55.08 78.23,55.25 78.23,57.28 78.74,57.78 85.09,57.78 85.34,57.53 111.51,57.53 111.76,57.78 111.76,58.17 112.01,58.42 121.28,58.42 121.54,58.67 121.54,59.44 121.28,59.69 112.01,59.69 111.76,59.94 111.76,61.34 112.01,61.59 v1(112.52,61.59)
DDR3-2_CASB: length 66.5
  TOP w0.197: v1(74.69,56.04) U31.AD16 ; v1(112.52,50.17) 112.65,50.3 P5.115
  L22_SIGNAL w0.14: v1(74.69,56.04) 75.23,55.5 85.09,55.5 85.34,55.25 94.23,55.25 101.85,47.62 103.5,47.62 104.27,46.86 108.71,46.86 109.09,47.24 110.74,47.24 112.27,45.72 115.82,45.72 116.46,45.08 119.89,45.08 120.52,45.72 121.03,45.72 121.28,45.97 121.28,46.74 121.03,46.99 120.4,46.99 120.14,47.24 120.14,48.13 120.27,48.26 120.27,49.2 119.93,49.53 115.32,49.53 115.19,49.66 113.79,49.66 113.28,50.17 v1(112.52,50.17)
DDR3-2_CK0_N: length 77.3
  TOP w0.152: v1(77.69,56.04) U31.AG16 ; P5.103 112.98,53.89 112.81,54.07 111.98,54.07 v1(111.76,53.85)
  L18_SIGNAL w0.13: v1(111.76,53.85) 111.51,54.1 102.22,54.1 101.85,54.47 101.85,55 102.22,55.37 113.16,55.37 113.41,55.12 113.41,54.97 113.67,54.71 118.11,54.71 118.23,54.84 118.23,55.62 118.11,55.74 113.73,55.74 113.59,55.88 109.88,55.88 108.92,56.83 103.46,56.83 101.6,58.69 100.35,58.69 99.06,57.4 97.68,57.4 96.39,58.69 95.25,58.69 93.96,57.4 85.24,57.4 84.86,57.78 77.7,57.78 77.32,57.4 77.32,56.41 v1(77.69,56.04)
DDR3-2_CK0_P: length 77.7
  TOP w0.152: P5.101 112.98,54.49 112.86,54.37 112,54.37 v1(111.76,54.61) ; v1(76.69,56.04) U31.AF16
  L18_SIGNAL w0.13: v1(111.76,54.61) 111.51,54.36 102.33,54.36 102.11,54.58 102.11,54.89 102.33,55.12 113.05,55.12 113.15,55.01 113.15,54.86 113.56,54.46 118.24,54.46 118.49,54.71 118.49,55.74 118.24,56 113.9,56 113.77,56.13 109.98,56.13 109.03,57.09 103.57,57.09 101.71,58.95 100.24,58.95 98.95,57.66 97.78,57.66 96.5,58.95 95.14,58.95 93.85,57.66 85.34,57.66 84.96,58.04 77.6,58.04 77.06,57.51 77.06,56.41 v1(76.69,56.04)
DDR3-2_CK1_N: length 80.9
  TOP w0.152: v1(80.69,56.04) U31.AK16 ; v1(120.4,53.47) 120.65,53.72 120.9,53.72 121.03,53.6 P5.104
  L5_SIGNAL w0.13: v1(120.4,53.47) 120.14,53.72 117.22,53.72 116.97,53.97 116.97,54.61 117.22,54.87 123.65,54.87 123.75,54.76 132.74,54.76 132.84,54.87 132.84,55.62 132.74,55.73 115.15,55.73 114.47,55.05 114.47,54.38 113.18,53.08 104.29,53.08 103.02,54.35 94.38,54.35 92.32,56.41 81.4,56.41 80.92,56.89 80.62,56.89 80.04,56.31 80.04,56.18 80.21,56.01 80.66,56.01 v1(80.69,56.04)
DDR3-2_CK1_P: length 80.8
  TOP w0.152: P5.102 121.12,54.19 120.95,54.03 120.6,54.03 v1(120.4,54.23) ; v1(79.69,56.04) U31.AJ16
  L5_SIGNAL w0.13: v1(120.4,54.23) 120.14,53.98 117.33,53.98 117.22,54.08 117.22,54.51 117.33,54.61 123.54,54.61 123.64,54.5 132.84,54.5 133.1,54.76 133.1,55.73 132.84,55.99 115.04,55.99 114.22,55.16 114.22,54.48 113.07,53.34 104.39,53.34 103.12,54.61 94.49,54.61 92.43,56.67 81.51,56.67 81.03,57.15 80.52,57.15 79.76,56.39 79.76,56.1 v1(79.69,56.04)
DDR3-2_CKE0: length 65.5
  TOP w0.197: P5.73 v3(115.67,62.89) ; v1(76.69,59.04) U31.AF18
  L3_SIGNAL w0.14: v3(115.67,62.89) 115.64,62.87 115.06,62.87 114.68,63.25 114.68,64.52 114.94,64.77 116.08,64.77 116.33,65.02 116.33,66.29 116.59,66.55 121.03,66.55 121.28,66.8 121.28,67.18 121.03,67.44 116.59,67.44 116.08,67.95 113.79,67.95 113.54,67.69 113.54,63.75 113.03,63.25 105.18,63.25 104.42,62.48 87.38,62.48 86.36,63.5 80.62,63.5 80.07,62.94 80.07,62.88 79.6,62.41 79.54,62.41 79.07,61.94 79.07,61.88 77.6,60.41 77.54,60.41 77.32,60.19 77.32,60.17 77.22,60.07 77.22,59.56 v1(76.69,59.04)
DDR3-2_CKE1: length 68.8
  TOP w0.197: v1(78.69,59.04) U31.AH18 ; P5.74 121.05,62.59 v3(120.78,62.87)
  L3_SIGNAL w0.14: v3(120.78,62.87) 128.78,62.87 129.03,63.12 129.03,64.39 128.78,64.64 121.54,64.64 121.28,64.9 121.28,65.15 121.03,65.41 119.63,65.41 119.25,65.02 119.25,63.25 118.87,62.87 118.21,62.87 118.2,62.88 117.23,62.88 116.47,62.12 115.07,62.12 113.79,60.83 109.6,60.83 108.97,60.2 104.78,60.2 104.01,60.96 103.38,60.96 103.12,60.71 96.39,60.71 96.01,60.33 86.87,60.33 85.6,61.59 81.25,61.59 81.07,61.41 81.07,60.88 80.85,60.66 80.54,60.66 80.07,60.19 80.07,59.88 79.85,59.66 79.32,59.66 v1(78.69,59.04)
DDR3-2_CLK_REF_N: length 75.3
  TOP w0.152: C75.2 R100.2 R114.1 111.73,105.05 v1(111.73,104.78) ; v1(79.69,55.04) U31.AJ15
  L7_SIGNAL w0.13: v1(79.69,55.04) 79.32,54.67 79.32,54.46 79.55,54.23 79.88,54.23 80.32,54.67 86.23,54.67 90.55,58.98 90.55,84.43 95.65,89.54 98.05,89.54 112.01,103.5 112.01,104.5 v1(111.73,104.78)
  BOTTOM w0.152: v1(79.69,55.04) 79.57,54.91 R301.2
DDR3-2_CLK_REF_P: length 76.2
  TOP w0.152: v1(78.69,55.04) U31.AH15 ; C76.2 R101.1 R115.1 112.55,105.05 v1(112.55,104.78)
  L7_SIGNAL w0.13: v1(112.55,104.78) 112.27,104.5 112.27,103.4 98.15,89.28 95.76,89.28 90.81,84.33 90.81,58.87 86.34,54.41 80.43,54.41 79.99,53.97 79.45,53.97 79.06,54.36 79.06,54.67 v1(78.69,55.04)
  BOTTOM w0.152: v1(78.69,55.04) 78.93,54.8 R301.1
DDR3-2_DM0: length 66.5
  TOP w0.197: v1(83.69,65.04) U31.AN24 ; P5.11 v1(112.57,83.89)
  L7_SIGNAL w0.14: v1(111.63,85.09) 111.63,84.33 111.89,84.07 111.89,82.93 111.63,82.68 104.27,82.68 104.01,82.42 104.01,79.88 104.27,79.63 111.76,79.63 112.01,79.88 112.01,82.18 112.26,82.42 112.32,82.42 112.57,82.68 v1(112.57,83.89)
  L9_SIGNAL w0.14: v1(83.69,65.04) 83.69,65.03 84.2,64.52 86.36,64.52 91.82,69.98 95.76,69.98 96.39,70.61 96.39,72.14 100.97,76.71 100.97,76.84 109.86,85.73 110.24,85.73 110.49,85.47 110.49,84.98 110.74,84.72 111.39,84.72 111.63,84.96 v1(111.63,85.09)
DDR3-2_DM1: length 56.6
  TOP w0.197: P5.28 v1(120.83,78.8) ; v1(82.69,61.04) U31.AM20
  L18_SIGNAL w0.14: v1(82.69,61.04) 83.15,60.58 85.85,60.58 90.04,64.77 90.04,66.04 91.82,67.82 96.65,67.82 101.35,72.52 107.06,72.52 107.95,73.41 108.46,73.41 109.86,72.01 114.17,72.01 115.44,73.28 122.43,73.28 122.68,73.53 122.68,78.54 122.43,78.8 v1(120.83,78.8)
DDR3-2_DM2: length 56.3
  TOP w0.197: v1(79.69,60.04) U31.AJ19 ; P5.46 119.77,73.4 v1(119.51,73.66)
  L3_SIGNAL w0.14: v1(119.51,73.66) 119.51,71.88 119,71.37 119,68.71 118.49,68.2 117.35,68.2 v1(116.97,68.58)
  L5_SIGNAL w0.14: v1(116.97,68.58) 117.42,68.58 117.6,68.77 117.6,69.03 117.42,69.22 109.98,69.22 109.73,68.96 109.73,68.83 109.47,68.58 106.68,68.58 105.28,67.18 105.28,65.28 104.01,64.01 97.41,64.01 95.63,62.23 90.55,62.23 87,58.68 85.43,58.68 85.41,58.66 81.54,58.66 81.32,58.88 81.32,58.94 80.85,59.41 80.79,59.41 80.16,60.04 v1(79.69,60.04)
DDR3-2_DM3: length 55.5
  TOP w0.197: P5.63 112.81,68.3 v1(112.52,68.58) ; v1(73.69,60.04) U31.AC19
  L18_SIGNAL w0.14: v1(112.52,68.58) 113.57,68.58 113.79,68.8 113.79,69.12 113.57,69.34 109.6,69.34 109.35,69.6 109.35,71.25 v1(108.08,72.52)
  L22_SIGNAL w0.14: v1(108.08,72.52) 108.08,71.76 107.82,71.5 96.14,71.5 95.76,71.12 87.5,71.12 84.96,68.58 77.7,68.58 77.32,68.19 77.32,68.05 76.68,67.41 76.54,67.41 76.32,67.19 76.32,67.05 75.68,66.41 75.54,66.41 75.32,66.19 75.32,66.05 74.68,65.41 74.54,65.41 74.32,65.19 74.32,65.05 73.68,64.41 73.54,64.41 73.32,64.19 73.32,60.41 v1(73.69,60.04)
DDR3-2_DM4: length 57.4
  TOP w0.197: v1(120.78,43.81) 120.96,44 P5.136 ; v1(75.69,49.04) U31.AE9
  L5_SIGNAL w0.14: v1(120.78,43.81) 121.28,43.81 121.54,43.56 121.54,42.16 121.28,41.91 120.65,41.91 120.14,41.4 120.14,39.62 119.89,39.37 114.3,39.37 114.05,39.12 111.76,39.12 107.06,43.81 102.74,43.81 101.98,44.58 96.39,44.58 95.76,45.21 87.38,45.21 86.11,46.48 77.6,46.48 77.07,47.01 77.07,47.19 76.85,47.41 76.67,47.41 76.2,47.88 76.2,48.51 75.69,49.02 v1(75.69,49.04)
DDR3-2_DM5: length 63.6
  TOP w0.197: P5.153 112.68,38.9 v1(112.52,38.73) ; v1(76.69,51.04) U31.AF11
  L18_SIGNAL w0.14: v1(112.52,38.73) 113.67,38.73 113.92,38.48 113.92,30.92 113.73,30.73 113.47,30.73 113.28,30.92 113.28,37.72 113.03,37.97 110.49,37.97 110.24,37.72 110.24,37.47 109.98,37.21 105.93,37.21 105.55,37.59 94.87,37.59 88.27,44.2 86.87,44.2 85.6,45.47 79.63,45.47 78.07,47.03 78.07,47.19 77.85,47.41 77.68,47.41 77.22,47.88 77.22,50.55 76.72,51.04 v1(76.69,51.04)
DDR3-2_DM6: length 61.6
  TOP w0.197: v1(81.69,50.04) U31.AL10 ; P5.170 120.92,33.79 v1(120.78,33.66)
  L3_SIGNAL w0.14: v1(107.95,33.15) 107.57,33.53 105.03,33.53 103.38,35.18 98.68,35.18 88.46,45.4 88.46,46.67 87.25,47.88 87.25,48.26 85.98,49.53 82.17,49.53 81.69,50.01 v1(81.69,50.04)
  L9_SIGNAL w0.14: v1(107.95,33.15) 110.11,33.15 110.49,32.77 111.63,32.77 113.92,35.05 119.89,35.05 120.52,34.42 125.07,34.42 125.48,34.01 125.48,33.43 125.07,33.02 121.03,33.02 120.78,33.27 v1(120.78,33.66)
DDR3-2_DM7: length 59.5
  TOP w0.197: P5.187 112.64,28.69 v1(112.52,28.57) ; v1(82.69,52.04) U31.AM12
  L22_SIGNAL w0.14: v1(82.69,52.04) 82.07,51.41 81.54,51.41 81.22,51.1 81.22,49.21 81.32,49.11 81.32,48.88 81.54,48.66 81.76,48.66 82.17,48.26 82.17,48.03 82.54,47.66 82.64,47.66 83.32,46.99 83.32,46.88 83.54,46.66 83.64,46.66 83.82,46.48 85.73,46.48 85.98,46.74 89.28,46.74 99.95,36.07 100.58,36.07 106.05,30.61 106.3,30.61 107.82,29.08 108.97,29.08 109.22,29.34 109.22,29.97 105.41,33.78 105.41,34.16 105.66,34.42 106.05,34.42 108.97,31.5 108.97,30.86 110.62,29.21 111.89,29.21 v1(112.52,28.57)
DDR3-2_DQ00: length 66.6
  TOP w0.197: v1(84.69,65.04) U31.AP24 ; P5.5 113.06,85.7 v1(112.52,86.23)
  L9_SIGNAL w0.14: v1(84.69,65.04) 85.61,65.04 91.69,71.12 95.63,71.12 95.89,71.37 95.89,72.14 96.27,72.52 96.39,72.52 100.7,76.82 100.7,76.95 110.17,86.42 110.68,86.42 111.12,86.87 113.67,86.87 114.73,85.81 115.91,85.81 116.84,86.74 118.56,86.74 118.75,86.56 118.75,86.29 118.56,86.11 117.48,86.11 117.22,85.85 117.22,83.57 116.97,83.31 116.59,83.31 116.46,83.44 116.46,83.69 116.84,84.07 116.84,85.31 116.68,85.47 116.46,85.47 116.3,85.31 116.3,84.62 116.01,84.33 115.19,84.33 115.06,84.2 115.06,83.69 114.81,83.44 114.55,83.44 114.3,83.69 114.3,85.6 114.17,85.73 113.79,85.73 113.67,85.6 113.67,83.69 113.54,83.57 113.16,83.57 113.03,83.69 113.03,85.73 v1(112.52,86.23)
DDR3-2_DQ01: length 66.4
  TOP w0.197: P5.7 v1(112.52,85.1) ; v1(83.69,61.04) U31.AN20
  L7_SIGNAL w0.14: v1(110.49,83.19) 110.49,85.6 110.74,85.85 112.27,85.85 112.52,85.6 v1(112.52,85.1)
  L9_SIGNAL w0.14: v1(110.49,83.19) 109.6,83.19 105.41,78.99 105.41,78.74 105.54,78.61 108.97,78.61 109.86,79.5 112.52,79.5 112.65,79.63 114.94,79.63 115.19,79.38 115.19,78.49 114.94,78.23 111.89,78.23 111.7,78.04 104.46,78.04 98.3,71.88 98.3,69.47 96.65,67.82 91.69,67.82 88.52,64.64 88.39,64.64 87.12,63.37 87.12,62.61 86.11,61.59 84.2,61.59 83.69,61.08 v1(83.69,61.04)
DDR3-2_DQ02: length 66.6
  TOP w0.197: v1(84.69,61.04) U31.AP20 ; P5.15 111.74,82.7 v1(111.25,83.19)
  L9_SIGNAL w0.14: v1(111.25,83.19) 110.24,82.17 109.35,82.17 107.06,79.88 106.96,79.88 106.81,79.73 106.81,79.52 106.96,79.38 108.46,79.38 108.71,79.63 108.71,80.64 108.97,80.9 109.47,80.9 109.73,80.64 109.73,80.39 109.98,80.14 110.62,80.14 110.87,80.39 110.87,81.03 111.12,81.28 111.63,81.28 111.89,81.03 111.89,80.9 112.14,80.64 112.78,80.64 113.03,80.9 116.2,80.9 116.46,80.64 116.46,77.86 116.2,77.61 115.05,77.61 114.81,77.85 112.01,77.85 111.7,77.53 104.71,77.53 98.81,71.63 98.81,69.22 96.27,66.67 91.31,66.67 88.39,63.75 88.39,62.36 87.07,61.04 v1(84.69,61.04)
DDR3-2_DQ03: length 66.4
  TOP w0.197: v1(83.69,60.04) U31.AN19 ; P5.17 111.43,82.1 v1(111.25,81.92)
  L9_SIGNAL w0.14: v1(111.25,81.92) 111.38,82.04 114.81,82.04 115.57,81.28 116.59,81.28 116.84,81.03 116.84,77.85 117.09,77.6 118.39,77.6 118.62,77.82 118.62,78.14 118.39,78.36 117.48,78.36 117.22,78.61 117.22,79.25 117.48,79.5 117.98,79.5 118.24,79.25 118.24,78.99 118.49,78.74 118.87,78.74 119.13,78.49 119.13,77.23 118.87,76.97 104.79,76.97 100.33,72.52 100.33,69.72 96.77,66.17 91.44,66.17 88.9,63.63 88.9,62.1 87.38,60.58 84.2,60.58 83.69,60.07 v1(83.69,60.04)
DDR3-2_DQ04: length 66.6
  TOP w0.197: v1(120.78,86.36) 121.14,86 P5.4 ; v1(84.69,60.04) U31.AP19
  L7_SIGNAL w0.14: v1(120.78,86.36) 120.78,85.98 121.03,85.73 124.21,85.73 124.46,85.47 124.46,84.45 124.21,84.2 123.32,84.2 121.54,82.42 121.54,81.03 121.28,80.77 120.65,80.77 120.02,81.41 119.38,81.41 v1(118.87,80.9)
  L9_SIGNAL w0.14: v1(118.87,80.9) 118.87,80.52 119.13,80.26 120.02,80.26 120.27,80.01 120.27,77.85 120.52,77.6 120.52,76.96 120.27,76.71 105.28,76.71 100.84,72.26 100.84,69.6 97.03,65.79 91.82,65.79 89.41,63.37 89.41,61.85 87.6,60.04 v1(84.69,60.04)
DDR3-2_DQ05: length 66.5
  TOP w0.197: v1(84.69,62.04) U31.AP21 ; v1(120.78,85.09) 121.08,85.4 P5.6
  L9_SIGNAL w0.14: v1(120.78,85.09) 118.24,85.09 117.98,84.84 117.98,84.45 117.97,84.44 117.97,82.68 118.22,82.42 120.02,82.42 120.65,81.79 122.17,81.79 122.43,81.53 122.43,80.64 122.17,80.39 120.78,80.39 119.51,81.66 118.22,81.66 117.97,81.41 117.97,80.36 117.75,80.14 117.44,80.14 117.22,80.36 117.22,82.3 116.97,82.55 112.01,82.55 111.76,82.8 111.76,83.57 111.38,83.95 109.6,83.95 97.54,71.88 97.54,70.1 96.52,69.09 92.08,69.09 86.61,63.63 86.61,62.99 85.66,62.04 v1(84.69,62.04)
DDR3-2_DQ06: length 66.4
  TOP w0.197: P5.16 120.93,82.4 v1(120.78,82.55) ; v1(84.69,63.04) U31.AP22
  L9_SIGNAL w0.14: v1(120.78,82.55) 120.78,82.42 121.03,82.17 123.19,82.17 123.32,82.3 123.32,82.8 123.06,83.06 118.62,83.06 118.24,83.44 118.24,84.33 118.49,84.58 121.28,84.58 121.54,84.84 121.54,85.47 121.28,85.73 117.86,85.73 117.6,85.47 117.6,83.19 117.35,82.93 112.52,82.93 112.27,83.19 112.27,83.67 111.48,84.45 109.35,84.45 97.03,72.14 97.03,70.36 96.14,69.47 91.95,69.47 86.11,63.63 85.22,63.63 84.69,63.1 v1(84.69,63.04)
DDR3-2_DQ07: length 66.8
  TOP w0.197: v1(120.78,81.28) 121.29,81.8 P5.18 ; v1(82.69,64.04) U31.AM23
  L7_SIGNAL w0.14: v1(115.7,88.01) 115.7,91.44 115.95,91.69 116.46,91.69 116.71,91.44 116.71,86.36 116.97,86.11 120.02,86.11 120.27,85.85 120.27,81.79 v1(120.78,81.28)
  L9_SIGNAL w0.14: v1(82.69,64.04) 82.65,64.04 82.17,64.52 82.17,66.17 82.55,66.55 84.84,66.55 85.6,67.31 85.6,67.95 91.95,74.3 95.89,74.3 97.66,76.07 97.79,76.07 110.62,88.9 114.81,88.9 v1(115.7,88.01)
DDR3-2_DQ08: length 56.8
  TOP w0.197: v1(112.52,81.28) 112.91,80.89 P5.21 ; v1(82.69,62.04) U31.AM21
  L16_SIGNAL w0.14: v1(112.52,81.28) 117.63,81.28 117.86,81.06 117.86,80.74 117.63,80.52 110.87,80.52 110.62,80.26 110.62,78.11 110.11,77.6 106.68,77.6 105.92,76.84 105.92,74.68 106.3,74.3 v1(106.3,73.53)
  L18_SIGNAL w0.14: v1(82.69,62.04) 82.69,62.12 83.06,62.48 85.98,62.48 86.74,63.25 86.74,66.42 89.79,69.47 97.03,69.47 101.09,73.53 v1(106.3,73.53)
DDR3-2_DQ09: length 56.6
  TOP w0.197: v1(112.52,80.01) 112.81,80.29 P5.23 ; v1(80.69,65.04) U31.AK24
  L16_SIGNAL w0.14: v1(112.52,80.01) 112.52,79.76 112.78,79.5 116.33,79.5 116.59,79.76 116.59,79.88 116.84,80.14 118.87,80.14 119.13,79.88 119.13,78.99 118.87,78.74 112.27,78.74 112.01,78.49 112.01,77.85 111.76,77.6 111.12,77.6 110.36,76.84 107.44,76.84 v1(106.3,75.69)
  L18_SIGNAL w0.14: v1(106.3,75.69) 105.66,76.33 99.44,76.33 96.14,73.03 88.39,73.03 84.78,69.41 84.54,69.41 84.32,69.19 84.32,68.95 83.78,68.41 83.54,68.41 83.32,68.19 83.32,67.95 82.78,67.41 82.54,67.41 82.32,67.19 82.32,66.95 81.78,66.41 81.54,66.41 81.32,66.19 81.32,65.95 80.69,65.32 v1(80.69,65.04)
DDR3-2_DQ10: length 56.5
  TOP w0.197: v1(112.52,77.47) 112.7,77.29 P5.33 ; v1(81.69,65.04) U31.AL24
  L18_SIGNAL w0.14: v1(81.69,65.04) 82.18,65.53 85.09,65.53 85.73,66.17 85.73,67.82 90.17,72.26 96.49,72.26 99.03,74.8 108.59,74.8 108.84,75.06 110.74,75.06 111.12,75.44 112.39,75.44 112.78,75.82 113.79,75.82 114.81,76.84 116.97,76.84 117.22,77.09 117.22,79.25 116.97,79.5 112.01,79.5 111.76,79.76 111,79.76 110.74,79.5 110.74,77.72 111,77.47 v1(112.52,77.47)
DDR3-2_DQ11: length 56.9
  TOP w0.197: P5.35 113.02,76.7 v1(112.52,76.2) ; v1(80.69,64.04) U31.AK23
  L16_SIGNAL w0.14: v1(105.41,75.69) 105.41,73.15 105.66,72.9 106.93,72.9 107.44,73.41 107.44,74.93 107.7,75.18 110.11,75.18 110.36,75.44 112.9,75.44 114.05,74.3 117.32,74.3 117.73,74.7 117.73,75.28 117.32,75.69 113.79,75.69 113.28,76.2 v1(112.52,76.2)
  L18_SIGNAL w0.14: v1(80.69,64.04) 80.69,64.05 81.32,64.68 81.32,65.19 81.54,65.41 81.67,65.41 82.32,66.06 82.32,66.19 82.54,66.41 82.67,66.41 82.93,66.67 83.52,66.67 83.54,66.66 85.08,66.66 85.34,66.93 85.34,68.07 89.92,72.64 96.33,72.64 98.87,75.18 104.9,75.18 v1(105.41,75.69)
DDR3-2_DQ12: length 56.7
  TOP w0.197: v1(119.51,80.9) 119.81,80.59 P5.22 ; v1(81.69,64.04) U31.AL23
  L18_SIGNAL w0.14: v1(81.69,64.04) 82.17,64.52 85.09,64.52 86.09,65.52 86.09,67.55 89.66,71.12 95.89,71.12 99.19,74.42 107.95,74.42 108.08,74.3 112.65,74.3 113.79,75.44 117.35,75.44 117.6,75.69 117.6,79.88 117.86,80.14 121.44,80.14 121.67,80.36 121.67,80.68 121.44,80.9 v1(119.51,80.9)
DDR3-2_DQ13: length 56.6
  TOP w0.197: P5.24 119.87,80 v1(119.51,79.63) ; v1(81.69,61.04) U31.AL20
  L18_SIGNAL w0.14: v1(119.51,79.63) 120.27,78.87 120.27,78.49 120.52,78.23 120.78,78.23 121.03,77.98 121.03,76.33 120.78,76.07 120.52,76.07 120.27,75.82 120.27,74.68 119.76,74.17 118.86,74.17 118.36,73.67 115.19,73.67 114.41,72.9 112.27,72.9 111.76,72.39 110.11,72.39 108.83,73.67 107.45,73.67 106.68,72.9 101.22,72.9 97.41,69.09 91.31,69.09 89.53,67.31 89.53,65.41 87,62.87 87,62.36 86.23,61.59 82.17,61.59 81.69,61.12 v1(81.69,61.04)
DDR3-2_DQ14: length 56.5
  TOP w0.197: v1(81.69,62.04) U31.AL21 ; v1(119.51,77.47) 119.98,77 P5.34
  L18_SIGNAL w0.14: v1(81.69,62.04) 81.72,62.04 82.17,62.48 82.17,63.12 82.55,63.5 85.6,63.5 86.36,64.26 86.36,66.8 89.53,69.98 96.65,69.98 100.71,74.04 107.59,74.04 107.7,73.94 108.94,73.94 109.6,73.28 112.14,73.28 113.16,74.3 118.48,74.3 118.86,74.68 119.63,74.68 119.89,74.93 119.89,75.31 119.63,75.56 118.62,75.56 118.36,75.82 118.36,76.45 118.62,76.71 120.4,76.71 120.65,76.96 120.65,77.22 120.4,77.47 v1(119.51,77.47)
DDR3-2_DQ15: length 56.8
  TOP w0.197: P5.36 119.7,76.4 v1(119.51,76.2) ; v1(79.69,63.04) U31.AJ22
  L16_SIGNAL w0.14: v1(119.51,76.2) 119.51,76.58 119.76,76.84 120.65,76.84 120.9,77.09 120.9,77.72 120.65,77.98 117.35,77.98 117.09,77.72 117.09,76.96 116.84,76.71 110.87,76.71 110.36,76.2 107.82,76.2 v1(107.31,75.69)
  L18_SIGNAL w0.14: v1(107.31,75.69) 106.3,76.71 98.93,76.71 96.65,74.42 89.92,74.42 88.9,73.41 87.5,73.41 85.07,70.97 85.07,70.88 84.85,70.66 84.76,70.66 84.07,69.97 84.07,69.88 83.85,69.66 83.76,69.66 83.07,68.97 83.07,68.88 82.85,68.66 82.76,68.66 82.07,67.97 82.07,67.88 81.85,67.66 81.76,67.66 81.07,66.97 81.07,66.88 80.85,66.66 80.76,66.66 80.14,66.04 80.14,63.5 79.69,63.05 v1(79.69,63.04)
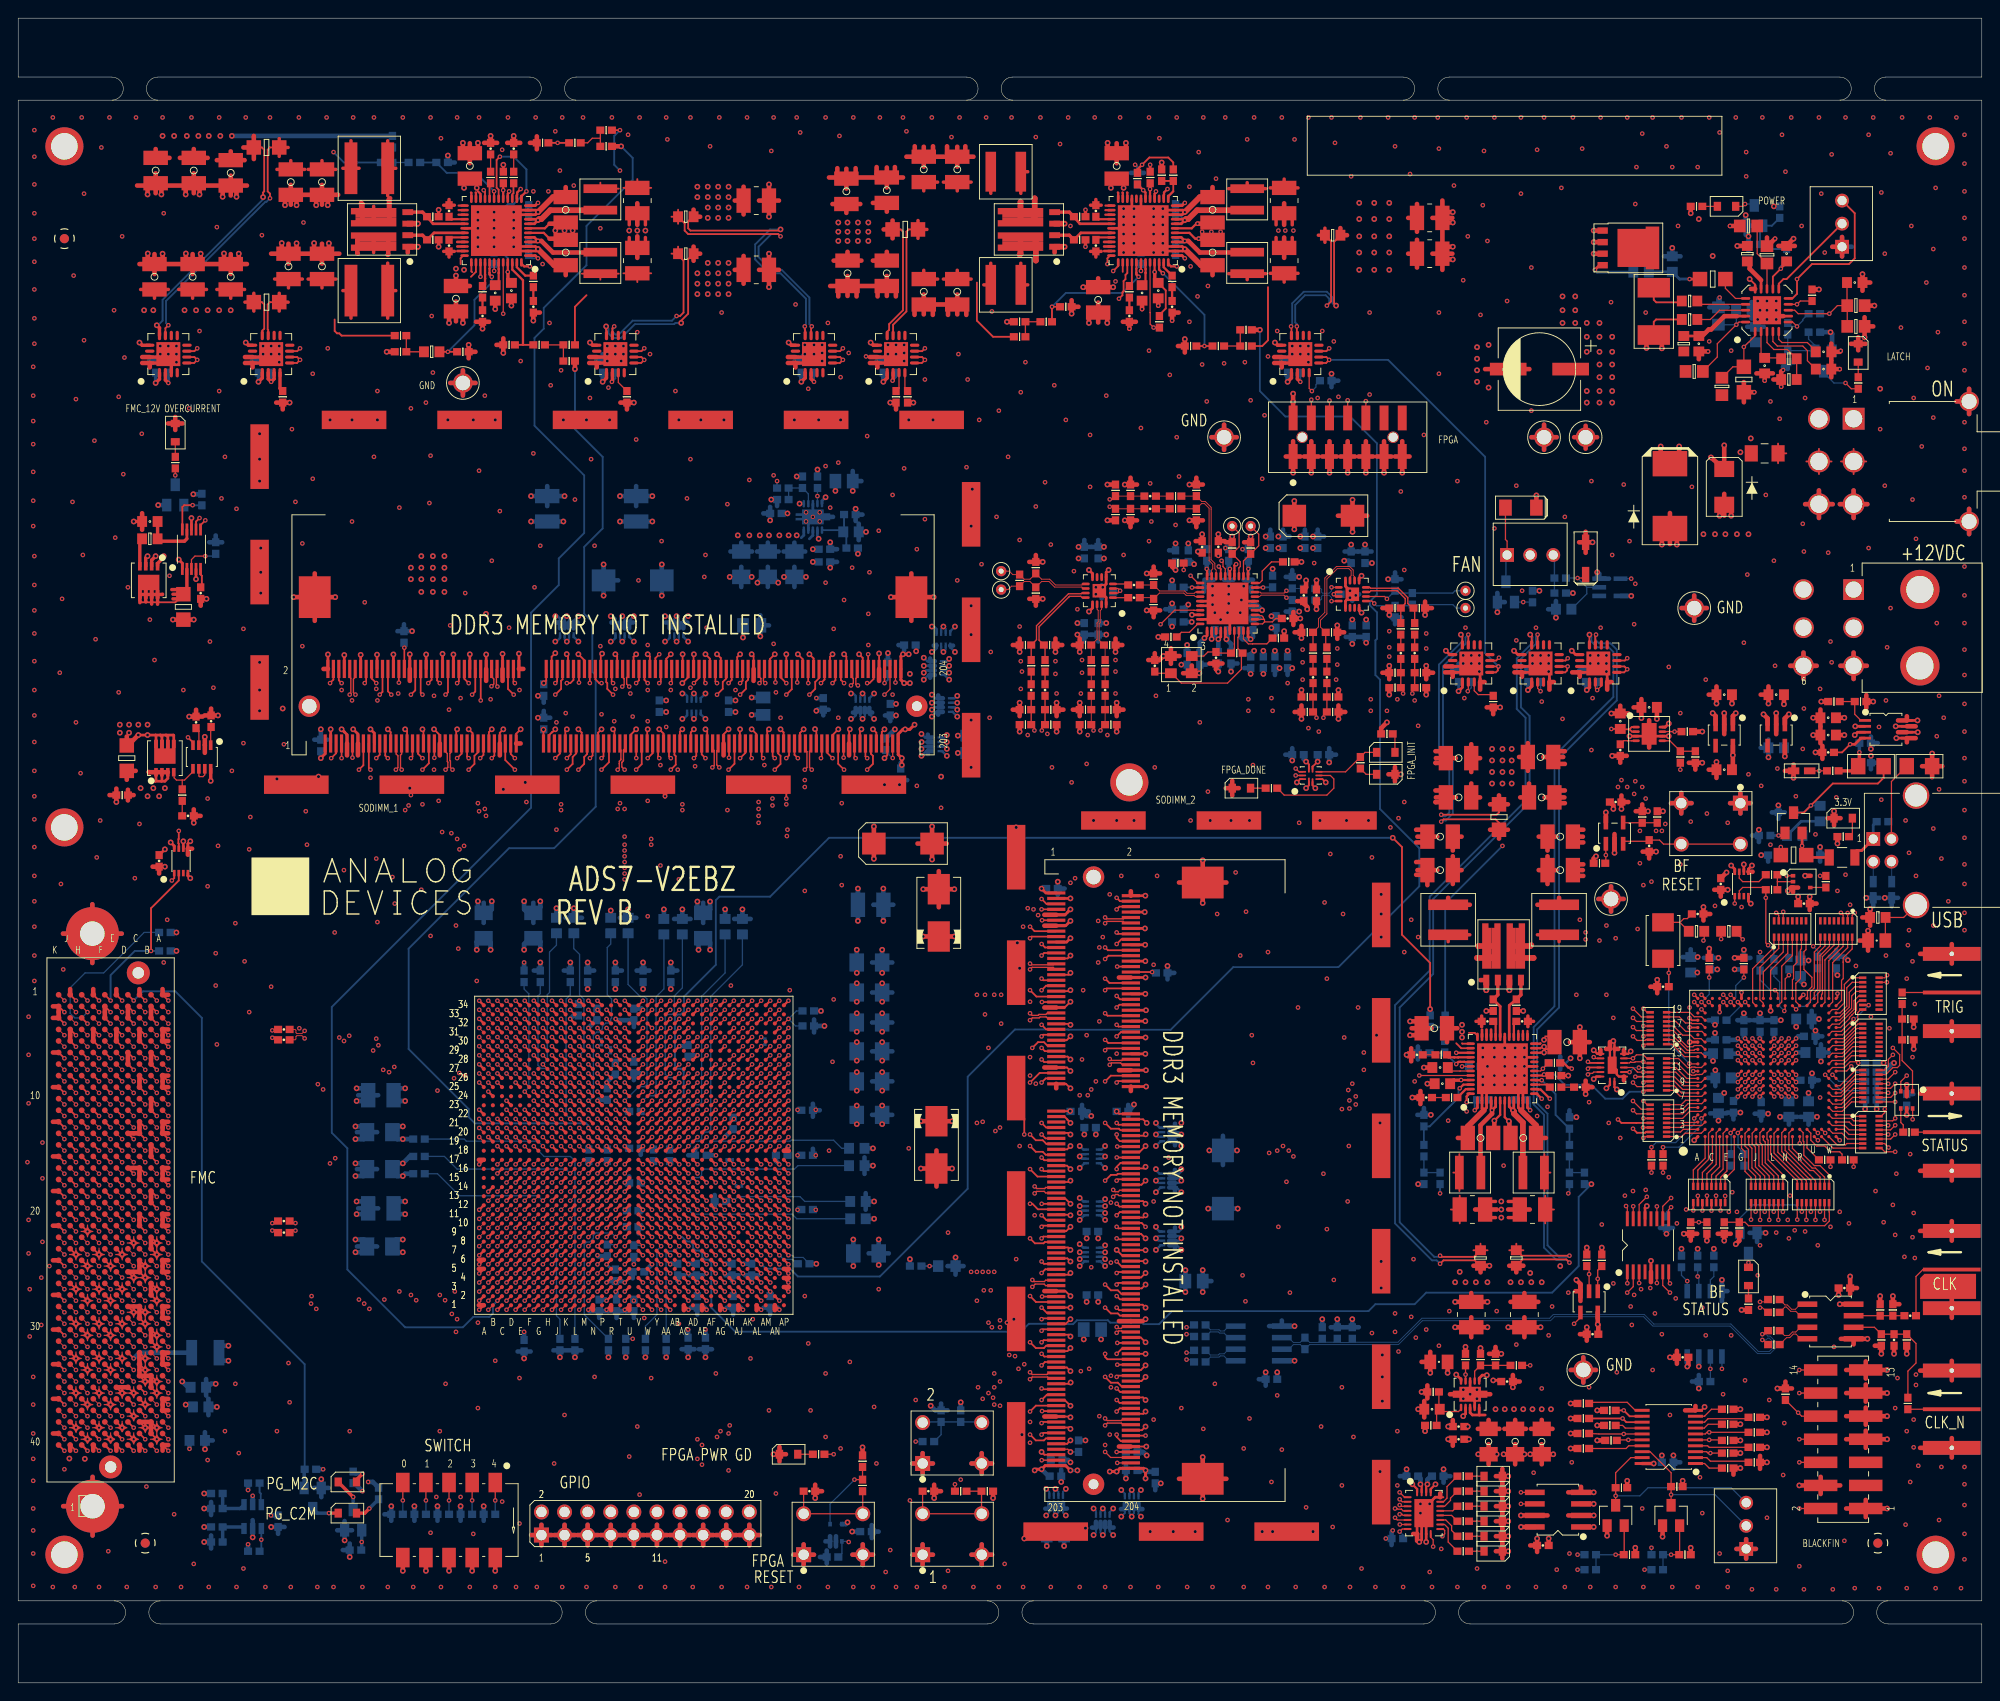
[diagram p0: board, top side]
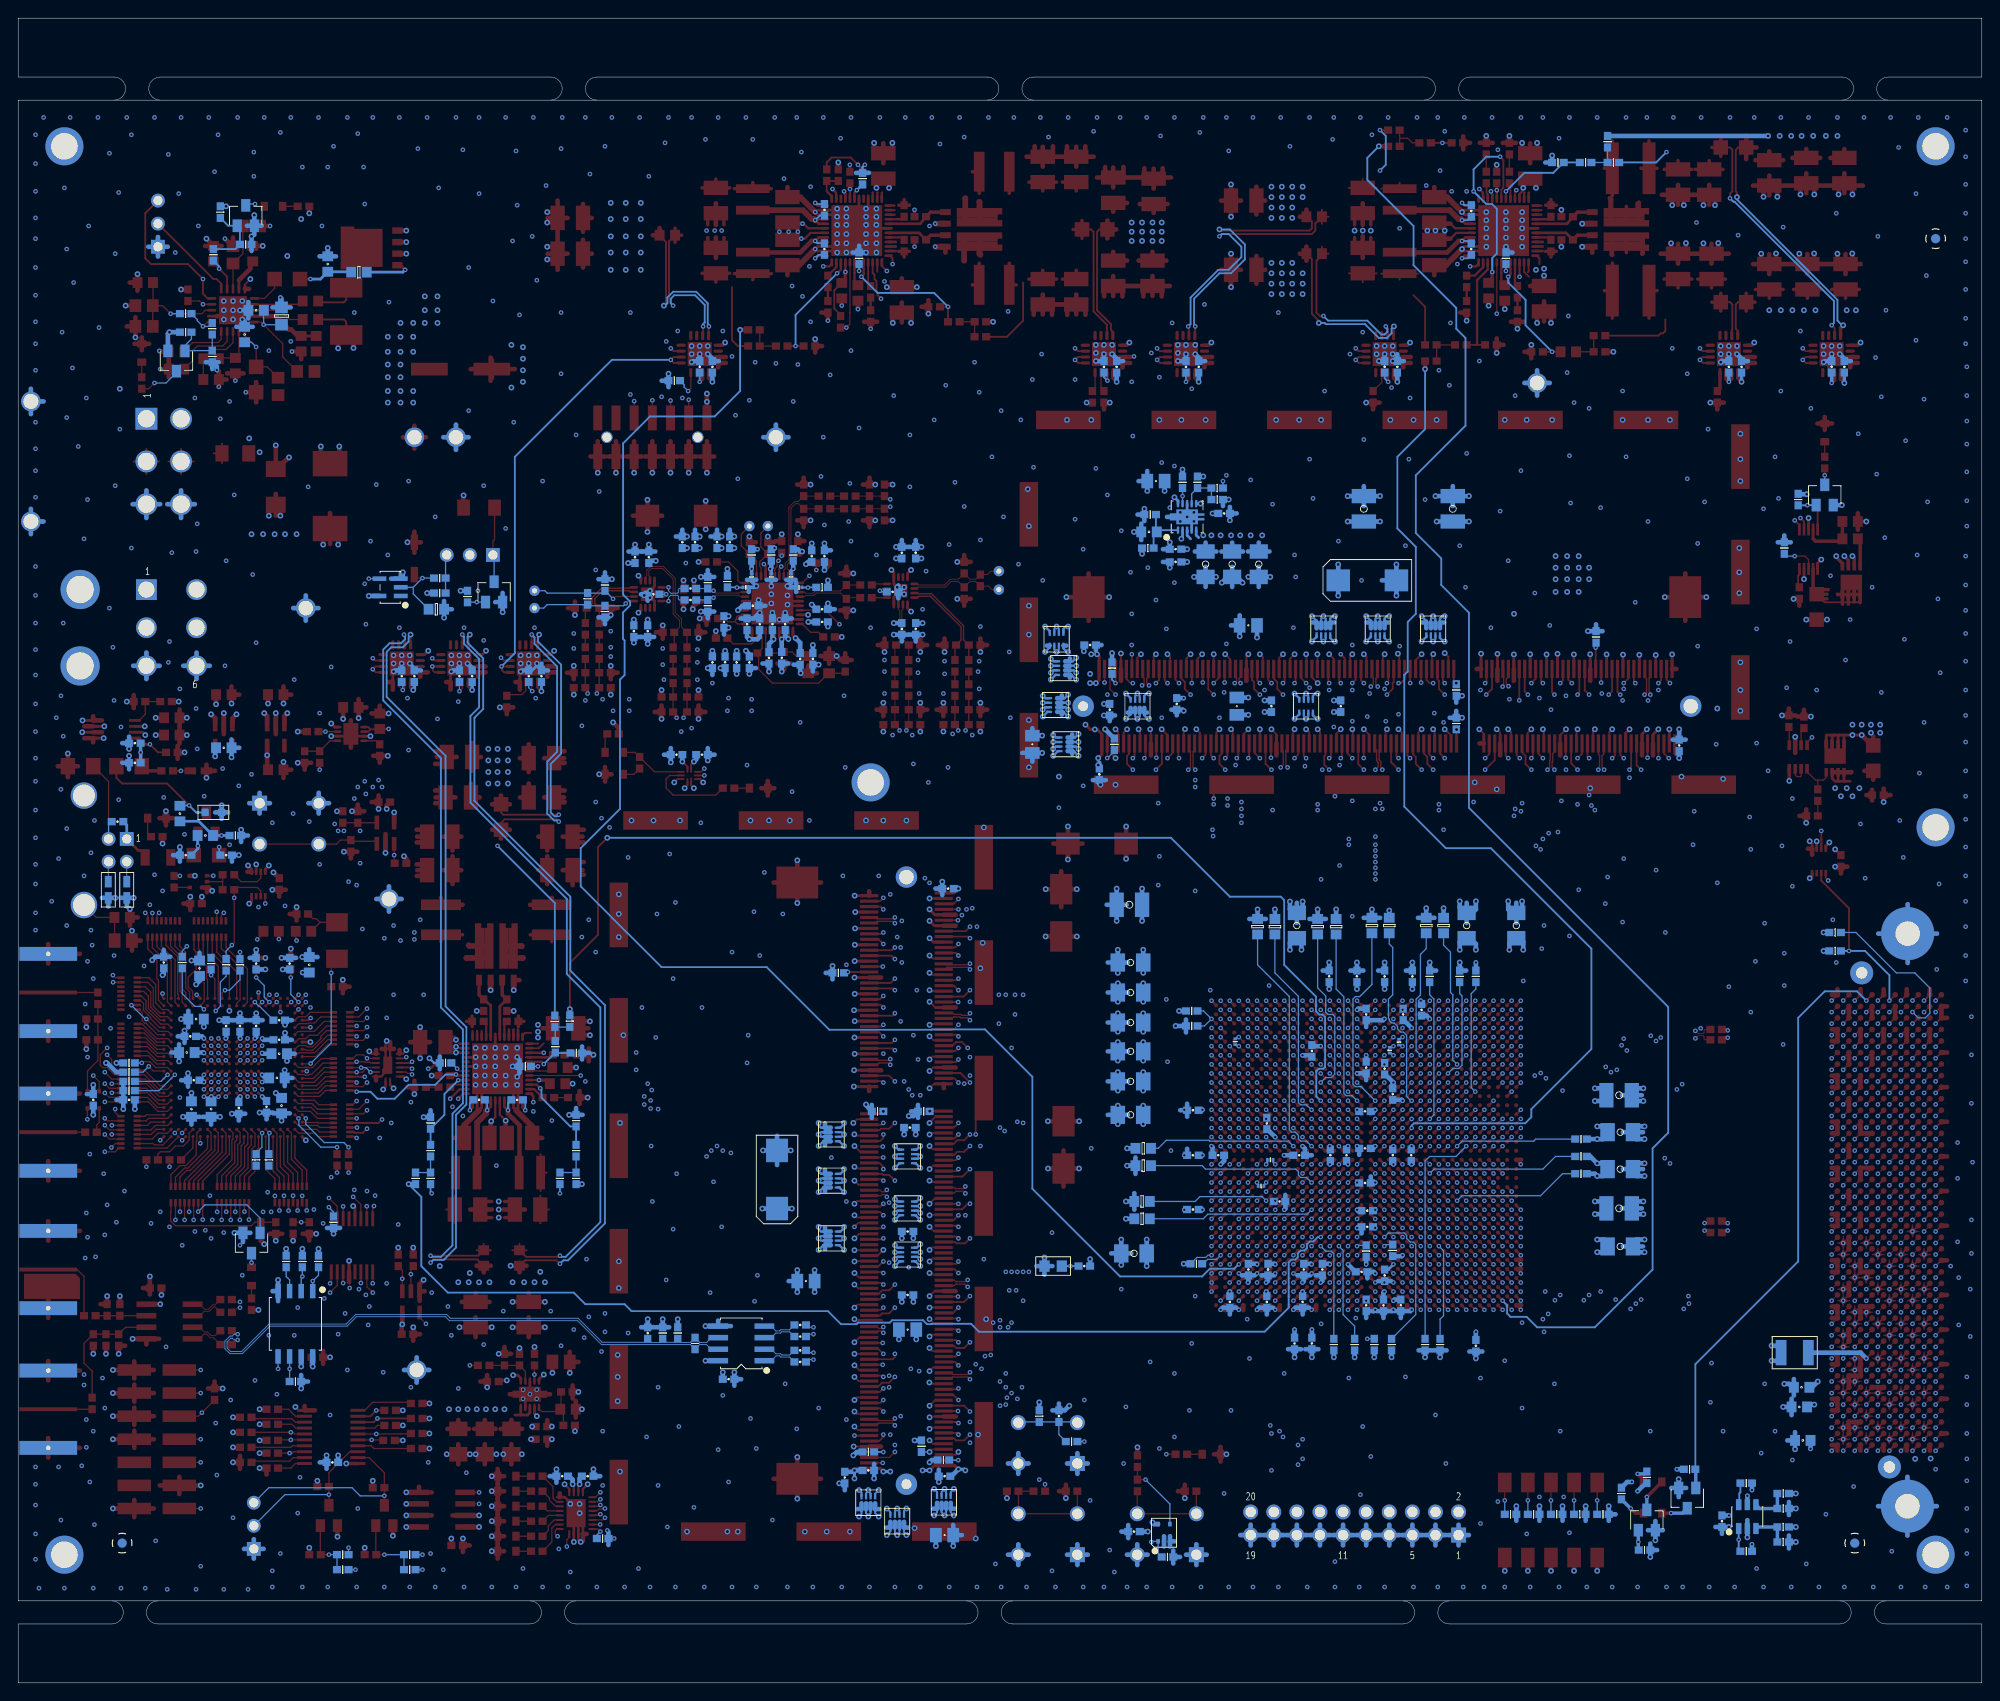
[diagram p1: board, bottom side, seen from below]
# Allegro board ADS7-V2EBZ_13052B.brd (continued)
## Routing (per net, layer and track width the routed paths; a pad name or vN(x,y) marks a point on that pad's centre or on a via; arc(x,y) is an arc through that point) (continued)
DDR3-2_DQ16: length 56.3
  TOP w0.197: P5.39 111.96,75.49 v1(111.25,76.2) ; v1(77.69,63.04) U31.AG22
  L5_SIGNAL w0.14: v1(111.25,76.2) 111.51,75.95 112.25,75.95 112.37,75.83 112.68,75.83 112.8,75.95 115.26,75.95 115.44,75.76 115.44,75.5 115.26,75.31 109.47,75.31 109.22,75.06 109.22,74.68 108.84,74.3 107.06,74.3 106.81,74.55 106.81,74.68 106.55,74.93 105.16,74.93 105.04,75.06 105.04,75.31 104.78,75.56 104.39,75.56 104.14,75.31 104.14,74.55 103.89,74.3 103.63,74.3 103.38,74.55 103.38,75.18 103.12,75.44 102.74,75.44 102.49,75.18 102.49,74.55 102.23,74.3 98.68,74.3 97.28,72.9 91.95,72.9 85.6,66.55 85.6,64.9 85.34,64.64 80.01,64.64 79.78,64.41 79.54,64.41 79.32,64.19 79.32,63.95 78.99,63.63 78.23,63.63 77.69,63.09 v1(77.69,63.04)
DDR3-2_DQ17: length 56.3
  TOP w0.197: v1(78.69,63.04) U31.AH22 ; P5.41 v1(112.56,74.89)
  L5_SIGNAL w0.14: v1(112.56,74.89) 114.08,74.89 114.43,74.55 115.06,74.55 115.32,74.3 116.08,74.3 116.71,74.93 118.9,74.93 119.13,74.71 119.13,74.39 118.9,74.17 116.59,74.17 116.08,73.66 114.3,73.66 113.79,74.17 109.6,74.17 109.47,74.04 108.96,74.04 108.95,74.03 106.95,74.03 106.94,74.04 105.79,74.04 105.54,73.79 99.19,73.79 96.52,71.12 91.57,71.12 86.11,65.66 86.11,64.01 85.6,63.5 79.38,63.5 78.91,63.04 v1(78.69,63.04)
DDR3-2_DQ18: length 56.5
  TOP w0.197: P5.51 113.02,71.89 v1(112.52,72.39) ; v1(79.69,62.04) U31.AJ21
  L5_SIGNAL w0.14: v1(112.52,72.39) 112.52,72.14 112.78,71.88 117.86,71.88 118.11,71.63 118.11,70.87 117.86,70.61 111.14,70.61 110.11,71.64 104.91,71.64 104.14,70.87 104.14,65.91 103.38,65.15 96.65,65.15 95.63,64.14 90.81,64.14 87.25,60.58 81.53,60.58 81.07,61.05 81.07,61.19 80.85,61.41 80.32,61.41 79.69,62.04 v1(79.69,62.04)
DDR3-2_DQ19: length 56.5
  TOP w0.197: v1(80.69,62.04) U31.AK21 ; v1(112.52,71.12) 112.7,71.3 P5.53
  L5_SIGNAL w0.14: v1(112.52,71.12) 112.39,71.25 112.39,71.88 112.15,72.13 112.15,72.55 112.5,72.9 117.73,72.9 117.98,73.15 117.98,73.41 117.73,73.66 116.71,73.66 116.33,73.28 113.79,73.28 113.41,73.66 112.01,73.66 111.76,73.41 111.76,72.64 111.12,72.01 104.52,72.01 103.63,71.12 103.63,66.29 103.01,65.67 100.47,65.67 100.46,65.66 96.65,65.66 95.5,64.52 90.17,64.52 87.25,61.59 81.15,61.59 80.71,62.04 v1(80.69,62.04)
DDR3-2_DQ20: length 56.5
  TOP w0.197: v1(120.78,75.56) 121.15,75.19 P5.40 ; v1(79.69,61.04) U31.AJ20
  L5_SIGNAL w0.14: v1(120.78,75.56) 121.16,75.56 121.41,75.31 121.41,72.01 121.16,71.76 119.89,71.76 118.24,70.1 114.3,70.1 114.17,70.23 109.35,70.23 109.09,69.98 109.09,69.6 108.84,69.34 104.9,69.34 104.65,69.09 104.65,65.41 103.76,64.52 97.16,64.52 95.38,62.74 90.17,62.74 87,59.56 81.53,59.56 81.07,60.03 81.07,60.19 80.85,60.41 80.68,60.41 80.06,61.04 v1(79.69,61.04)
DDR3-2_DQ21: length 56.3
  TOP w0.197: v1(78.69,64.04) U31.AH23 ; v1(120.78,74.3) 121.08,74.59 P5.42
  L5_SIGNAL w0.14: v1(78.69,64.04) 78.23,64.5 78.23,65.28 79.62,66.66 79.85,66.66 80.07,66.88 80.07,67.11 80.62,67.66 80.85,67.66 81.07,67.88 81.07,68.11 81.28,68.33 81.41,68.33 81.66,68.58 85.73,68.58 91.57,74.42 96.27,74.42 98.68,76.84 108.71,76.84 108.97,77.09 116.84,77.09 117.73,77.98 120.65,77.98 120.9,77.72 120.9,76.84 120.65,76.58 120.4,76.58 120.14,76.33 120.14,75.44 120.52,75.06 120.55,75.06 120.78,74.83 v1(120.78,74.3)
DDR3-2_DQ22: length 56.3
  TOP w0.197: v1(120.78,72.39) 120.97,72.19 P5.50 ; v1(79.69,65.04) U31.AJ24
  L5_SIGNAL w0.14: v1(79.69,65.04) 80.14,65.49 80.14,66.17 80.63,66.66 80.85,66.66 81.07,66.88 81.07,67.1 81.63,67.66 85.32,67.66 91.8,74.15 95.2,74.15 95.31,74.04 96.77,74.04 99.06,76.33 108.97,76.33 109.35,76.71 116.2,76.71 116.46,76.45 116.46,75.69 116.71,75.44 117.35,75.44 117.6,75.69 117.6,77.14 117.94,77.47 118.41,77.47 118.75,77.14 118.75,75.82 120.37,74.19 120.37,74.13 120.4,74.1 120.4,73.41 120.14,73.15 119.98,73.15 119.76,72.93 119.76,72.61 119.98,72.39 v1(120.78,72.39)
DDR3-2_DQ23: length 56.4
  TOP w0.197: P5.52 121.25,71.59 v1(120.78,71.12) ; v1(77.69,61.04) U31.AG20
  L5_SIGNAL w0.14: v1(77.69,61.04) 78.22,61.04 79.07,60.19 79.07,60.13 79.78,59.41 79.85,59.41 80.07,59.19 80.07,59.13 80.9,58.29 85.41,58.29 85.54,58.41 87.88,58.41 90.81,61.34 91.64,61.34 92,60.98 92.4,60.98 92.69,61.27 94.51,61.27 94.79,60.98 95.2,60.98 95.56,61.34 96.01,61.34 98.17,63.5 104.39,63.5 108.84,67.95 118.62,67.95 120.9,70.23 122.3,70.23 122.56,70.48 122.56,70.87 122.3,71.12 v1(120.78,71.12)
DDR3-2_DQ24: length 55.5
  TOP w0.197: v1(111.5,69.85) 112.13,70.48 112.78,70.48 113.17,70.1 P5.57 ; v1(74.69,63.04) U31.AD22
  L22_SIGNAL w0.14: v1(111.5,69.85) 110.87,69.85 110.49,69.47 110.49,68.45 110.23,68.2 104.71,68.2 104.52,68.38 104.52,68.65 104.71,68.83 109.09,68.83 109.35,69.09 109.35,69.22 109.09,69.47 102.67,69.47 102.56,69.36 102.16,69.36 102.05,69.47 99.88,69.47 99.77,69.36 99.37,69.36 99.26,69.47 96.64,69.47 96.52,69.34 87.88,69.34 84.96,66.41 77.54,66.41 76.07,64.94 76.07,64.88 75.6,64.41 75.54,64.41 75.07,63.94 75.07,63.88 74.85,63.66 74.84,63.66 74.68,63.5 74.68,63.05 v1(74.69,63.04)
DDR3-2_DQ25: length 55.6
  TOP w0.197: v1(75.69,63.04) U31.AE22 ; v1(112.52,69.85) 112.88,69.49 P5.59
  L22_SIGNAL w0.14: v1(75.69,63.04) 75.69,63.04 75.69,63.5 76.32,64.12 76.32,64.19 77.78,65.66 85.09,65.66 88.39,68.96 95.38,68.96 95.5,68.83 103.89,68.83 104.14,68.58 104.14,67.95 104.39,67.69 110.75,67.69 112.01,68.95 115.38,68.95 115.49,69.07 115.9,69.07 116.01,68.95 117.98,68.95 118.24,69.21 118.24,69.6 117.98,69.85 v1(112.52,69.85)
DDR3-2_DQ26: length 55.8
  TOP w0.197: v1(74.69,62.04) U31.AD21 ; v1(111.25,66.04) 112.31,67.1 P5.67
  L22_SIGNAL w0.14: v1(74.69,62.04) 74.69,62.12 75.24,62.66 75.85,62.66 76.07,62.88 76.07,62.98 76.75,63.66 76.85,63.66 77.07,63.88 77.07,63.98 77.6,64.52 84.96,64.52 88.27,67.82 95.5,67.82 96.14,67.18 102.62,67.18 102.87,67.44 102.87,67.56 102.62,67.82 97.98,67.82 97.79,68 97.79,68.27 97.98,68.45 103.38,68.45 103.63,68.2 103.63,67.44 103.89,67.18 110.11,67.18 v1(111.25,66.04)
DDR3-2_DQ27: length 55.7
  TOP w0.197: v1(112.52,66.04) 112.98,66.49 P5.69 ; v1(75.69,62.04) U31.AE21
  L22_SIGNAL w0.14: v1(112.52,66.04) 112.26,65.78 112.26,65.76 112.04,65.54 110.62,65.54 110.36,65.28 103.44,65.28 103.25,65.46 103.25,65.73 103.44,65.91 109.47,65.91 109.73,66.17 109.73,66.29 109.47,66.55 102.8,66.55 102.56,66.78 102.16,66.78 101.87,66.5 100.06,66.5 99.77,66.78 99.37,66.78 98.88,66.29 87.76,66.29 85.09,63.63 77.72,63.63 77.07,62.97 77.07,62.88 76.85,62.66 76.76,62.66 76.14,62.04 v1(75.69,62.04)
DDR3-2_DQ28: length 55.9
  TOP w0.197: v1(74.69,60.04) U31.AD19 ; v1(119.51,70.74) 119.85,70.4 P5.56
  L22_SIGNAL w0.14: v1(74.69,60.04) 74.07,61.09 74.07,63.94 74.54,64.41 74.6,64.41 75.07,64.88 75.07,64.94 75.54,65.41 75.6,65.41 77.07,66.88 77.07,66.94 77.54,67.41 84.45,67.41 87.76,69.72 95.89,69.72 96.65,70.48 119.25,70.48 v1(119.51,70.74)
DDR3-2_DQ29: length 55.4
  TOP w0.197: v1(119.51,69.6) 119.71,69.79 P5.58 ; v1(75.69,60.04) U31.AE19
  L18_SIGNAL w0.14: v1(119.51,69.6) 116.71,66.8 v1(116.71,64.64)
  L22_SIGNAL w0.14: v1(116.71,64.64) 112.9,64.64 111.76,63.5 108.46,63.5 108.2,63.25 108.2,62.74 107.95,62.48 106.93,62.48 106.68,62.74 106.68,63.25 106.43,63.5 96.39,63.5 95.56,62.66 87.81,62.66 85.6,60.45 78.99,60.45 78.12,61.33 77.98,61.33 77.72,61.58 76.57,61.58 76.2,61.21 76.2,60.55 v1(75.69,60.04)
DDR3-2_DQ30: length 55.5
  TOP w0.197: v1(119.51,66.17) 120.13,66.79 P5.68 ; v1(76.69,62.04) U31.AF21
  L22_SIGNAL w0.14: v1(76.69,62.04) 76.77,62.04 77.34,62.61 85.85,62.61 88.9,65.66 102.49,65.66 102.74,65.41 102.74,65.15 103,64.9 110.88,64.9 111.25,65.27 112.9,65.27 113.16,65.53 113.16,66.55 113.41,66.8 113.79,66.8 114.05,66.55 114.05,65.53 114.3,65.27 114.55,65.27 115.19,65.91 115.19,67.69 115.44,67.95 116.2,67.95 116.46,67.69 116.46,65.91 116.71,65.66 119,65.66 v1(119.51,66.17)
DDR3-2_DQ31: length 55.8
  TOP w0.197: P5.70 120.93,66.19 v1(120.78,66.04) ; v1(77.69,62.04) U31.AG21
  L18_SIGNAL w0.14: v1(117.6,64.64) 117.98,64.64 119.01,65.67 120.41,65.67 v1(120.78,66.04)
  L22_SIGNAL w0.14: v1(77.69,62.04) 78.04,62.04 78.49,61.59 85.6,61.59 88.01,64.01 101.09,64.01 101.35,64.26 101.35,64.39 101.09,64.64 98.36,64.64 98.17,64.83 98.17,65.09 98.36,65.28 101.98,65.28 102.23,65.02 102.23,64.39 102.49,64.14 111,64.14 111.77,64.91 116.09,64.91 116.33,65.15 117.09,65.15 v1(117.6,64.64)
DDR3-2_DQ32: length 57.2
  TOP w0.197: v1(112.52,46.36) 112.78,46.09 P5.129 ; v1(75.69,48.04) U31.AE8
  L3_SIGNAL w0.14: v1(105.41,42.04) 104.52,42.04 104.27,42.29 104.27,46.99 104.52,47.24 113.41,47.24 113.67,47.5 113.67,48.26 113.92,48.51 114.55,48.51 114.81,48.26 114.81,47.37 115.19,46.99 115.19,46.61 114.94,46.36 v1(112.52,46.36)
  L5_SIGNAL w0.14: v1(75.69,48.04) 75.69,47.57 76.07,47.19 76.07,47.12 76.78,46.41 76.85,46.41 77.07,46.19 77.07,46.12 77.6,45.59 85.85,45.59 86.74,44.7 95.25,44.7 95.89,44.07 101.22,44.07 102.87,42.42 105.03,42.42 v1(105.41,42.04)
DDR3-2_DQ33: length 57.4
  TOP w0.197: v1(112.52,45.08) 112.93,45.49 P5.131 ; v1(73.69,50.04) U31.AC10
  L5_SIGNAL w0.14: v1(73.69,50.04) 74.07,50.41 74.07,52.22 74.51,52.66 74.85,52.66 75.07,52.88 75.07,53.22 75.44,53.59 89.15,53.59 90.68,52.07 95.76,52.07 97.28,50.55 103,50.55 104.14,49.4 115.7,49.4 115.95,49.15 115.95,48.64 115.7,48.39 112.27,48.39 112.01,48.13 112.01,45.34 112.27,45.08 v1(112.52,45.08)
DDR3-2_DQ34: length 57.5
  TOP w0.197: P5.141 v1(112.57,42.49) ; v1(73.69,49.04) U31.AC9
  L3_SIGNAL w0.14: v1(112.57,42.49) 112,42.49 111.89,42.61 111.89,43.31 112.27,43.69 116.08,43.69 116.71,43.05 117.22,43.05 117.48,43.31 117.48,44.2 115.95,45.72 106.55,45.72 v1(106.05,45.21)
  L5_SIGNAL w0.14: v1(73.69,49.04) 73.69,49.05 74.17,49.53 88.65,49.53 90.68,47.5 95.25,47.5 96.65,46.1 99.19,46.1 99.45,46.36 101.21,46.36 101.47,46.1 105.16,46.1 v1(106.05,45.21)
DDR3-2_DQ35: length 57.5
  TOP w0.197: v1(74.69,50.04) U31.AD10 ; v1(111.25,42.55) 111.9,41.9 P5.143
  L3_SIGNAL w0.14: v1(111.25,42.55) 110.55,43.24 109.47,43.24 109.22,43.5 109.22,43.81 108.97,44.07 105.09,44.07 104.9,44.25 104.9,44.52 105.09,44.7 109.98,44.7 110.33,44.35 111,44.35 111.25,44.61 111.25,44.96 111,45.21 v1(107.31,45.21)
  L5_SIGNAL w0.14: v1(107.31,45.21) 104.9,47.62 95.76,47.62 95.38,48.01 90.93,48.01 88.39,50.55 75.18,50.55 74.69,50.05 v1(74.69,50.04)
DDR3-2_DQ36: length 57.5
  TOP w0.197: v1(74.69,49.04) U31.AD9 ; P5.130 121.34,45.79 v1(120.78,46.36)
  L3_SIGNAL w0.14: v1(106.93,43.18) 107.31,43.56 108.59,43.56 110.36,41.78 115.82,41.78 116.71,42.67 117.6,42.67 117.98,43.05 117.98,44.2 118.24,44.45 119.26,44.45 120.78,45.97 v1(120.78,46.36)
  L5_SIGNAL w0.14: v1(74.69,49.04) 74.69,49.01 75.18,48.51 75.18,46.99 75.76,46.41 75.85,46.41 76.07,46.19 76.07,46.11 76.76,45.41 76.85,45.41 77.07,45.19 77.07,45.11 77.72,44.45 85.73,44.45 85.98,44.2 95,44.2 95.63,43.56 101.09,43.56 102.74,41.91 104.65,41.91 105.16,41.4 105.66,41.4 106.49,42.23 106.49,42.74 v1(106.93,43.18)
DDR3-2_DQ37: length 56.2
  TOP w0.197: v1(76.69,49.04) U31.AF9 ; v1(120.78,45.08) 120.89,45.19 P5.132
  L5_SIGNAL w0.14: v1(76.69,49.04) 77.22,48.51 88.77,48.51 90.17,47.12 95.25,47.12 96.92,45.45 104.53,45.45 v1(104.78,45.21)
  L9_SIGNAL w0.14: v1(120.78,45.08) 120.78,45.47 121.03,45.72 121.54,45.72 121.79,45.97 121.79,46.1 122.05,46.36 122.81,46.36 123.06,46.1 123.06,44.7 122.81,44.45 120.4,44.45 119.76,45.08 117.22,45.08 116.59,44.45 112.39,44.45 111.89,44.96 109.6,44.96 109.09,44.45 105.54,44.45 v1(104.78,45.21)
DDR3-2_DQ38: length 57.4
  TOP w0.197: P5.140 121.29,42.79 120.9,43.18 120.14,43.18 v1(119.51,43.81) ; v1(76.69,48.04) U31.AF8
  L5_SIGNAL w0.14: v1(76.69,48.04) 76.69,48.02 77.22,47.5 88.77,47.5 89.53,46.74 95,46.74 96.65,45.08 102.36,45.08 103.37,44.08 107.56,44.08 112.01,39.63 113.29,39.63 113.67,40 114.94,40 115.57,40.64 116.59,40.64 116.84,40.89 116.84,42.42 117.09,42.67 117.86,42.67 118.11,42.42 118.11,40.77 118.36,40.51 118.87,40.51 119.13,40.77 119.13,41.6 119.23,41.71 119.23,42.11 119.13,42.22 119.13,43.56 119.38,43.81 v1(119.51,43.81)
DDR3-2_DQ39: length 57.2
  TOP w0.197: v1(74.69,52.04) U31.AD12 ; P5.142 121.13,42.19 v1(120.78,42.55)
  L5_SIGNAL w0.14: v1(120.78,42.55) 120.02,43.31 120.02,44.07 119.51,44.58 119,44.58 118.75,44.83 118.75,46.36 118.49,46.61 117.73,46.61 117.48,46.36 117.48,44.83 117.22,44.58 112.14,44.58 110.36,46.35 110.36,46.99 110.11,47.24 109.73,47.24 108.2,48.77 98.68,48.77 95.89,51.56 90.55,51.56 89.53,52.58 75.44,52.58 74.9,52.04 v1(74.69,52.04)
DDR3-2_DQ40: length 63.8
  TOP w0.197: v1(77.69,51.04) U31.AG11 ; P5.147 113.1,40.7 v1(112.52,41.28)
  L18_SIGNAL w0.14: v1(112.52,41.28) 108.97,41.28 108.2,42.04 106.15,42.04 105.67,42.52 105.67,42.54 105.28,42.93 104.52,42.93 103.76,42.16 98.1,42.16 97.92,42.35 97.92,42.61 98.1,42.8 101.35,42.8 101.47,42.93 101.47,43.31 101.35,43.43 96.96,43.43 96.77,43.62 96.77,43.88 96.96,44.07 100.08,44.07 100.33,44.32 100.33,44.58 100.08,44.83 95.69,44.83 95.5,45.02 95.5,45.28 95.69,45.47 97.28,45.47 97.54,45.72 97.54,46.1 95.76,47.88 91.57,47.88 90.3,49.15 86.74,49.15 85.85,50.04 85.85,51.05 85.22,51.69 85.22,52.07 84.71,52.58 79.5,52.58 79.25,52.32 79.25,51.82 78.99,51.56 78.21,51.56 v1(77.69,51.04)
DDR3-2_DQ41: length 63.9
  TOP w0.197: P5.149 112.61,40.09 v1(112.52,40) ; v1(77.69,48.04) U31.AG8
  L18_SIGNAL w0.14: v1(77.69,48.04) 78.07,48.04 78.7,47.41 78.85,47.41 79.07,47.19 79.07,47.05 79.63,46.48 85.34,46.48 87,44.83 88.52,44.83 95.12,38.23 105.81,38.23 106.19,37.85 109.22,37.85 110.62,39.24 114.17,39.24 114.43,38.99 114.43,31.34 114.65,31.11 114.97,31.11 115.19,31.34 115.19,39.75 114.94,40 v1(112.52,40)
DDR3-2_DQ42: length 63.6
  TOP w0.197: v1(78.69,48.04) U31.AH8 ; P5.157 112.75,37.7 v1(112.52,37.47)
  L16_SIGNAL w0.14: v1(112.52,37.47) 116.46,37.47 119.51,34.42 121.41,34.42 121.67,34.67 121.67,35.31 121.41,35.56 119.38,35.56 118.87,36.07 118.87,36.96 118.49,37.34 118.49,38.35 118.24,38.61 115.09,38.61 114.71,38.23 111.63,38.23 111.38,38.48 107.7,38.48 v1(107.06,39.12)
  L18_SIGNAL w0.14: v1(78.69,48.04) 78.71,48.04 79.25,47.5 85.22,47.5 87.38,45.34 88.77,45.34 95.38,38.73 104.9,38.73 105.28,39.12 v1(107.06,39.12)
DDR3-2_DQ43: length 63.7
  TOP w0.197: v1(76.69,50.04) U31.AF10 ; v1(111.25,37.47) 111.89,36.83 112.78,36.83 113.04,37.09 P5.159
  L18_SIGNAL w0.14: v1(111.25,37.47) 111.76,37.47 112.01,37.21 112.01,31.62 111.76,31.37 108.68,31.37 108.46,31.59 108.46,31.91 108.68,32.13 110.74,32.13 111,32.39 111,32.9 110.74,33.15 110.74,34.42 111.12,34.8 111.12,36.32 110.87,36.58 105.66,36.58 105.28,36.96 94.74,36.96 88.01,43.69 86.49,43.69 85.6,44.58 79.5,44.58 78.07,46.01 78.07,46.19 77.85,46.41 77.67,46.41 77.07,47.01 77.07,47.19 76.85,47.41 76.67,47.41 76.2,47.88 76.2,49.53 76.69,50.02 v1(76.69,50.04)
DDR3-2_DQ44: length 63.6
  TOP w0.197: v1(120.78,41.28) 121.06,41 P5.146 ; v1(77.69,50.04) U31.AG10
  L18_SIGNAL w0.14: v1(77.69,50.04) 78.32,50.66 78.85,50.66 79.07,50.88 79.07,51 79.63,51.56 84.84,51.56 85.47,50.93 85.47,49.91 86.61,48.77 90.04,48.77 91.31,47.5 91.82,47.5 97.66,41.66 105.57,41.66 105.67,41.77 107.98,41.77 108.32,41.43 108.32,41.41 108.97,40.77 117.73,40.77 117.98,40.51 117.98,38.61 118.24,38.35 118.88,38.35 119.13,38.61 119.13,39.5 119.39,39.75 122.17,39.75 122.43,40 122.43,40.39 122.17,40.64 119.25,40.64 119,40.89 119,41.47 119.23,41.71 119.23,41.88 119.39,42.04 120.52,42.04 120.78,41.78 v1(120.78,41.28)
DDR3-2_DQ45: length 63.6
  TOP w0.197: v1(119.51,41.28) 120.14,40.64 120.9,40.64 121.15,40.39 P5.148 ; v1(78.69,50.04) U31.AH10
  L16_SIGNAL w0.14: v1(119.51,41.28) 119.51,41.02 119.76,40.77 124.97,40.77 125.22,40.51 125.22,39.75 124.97,39.5 123.57,39.5 123.19,39.88 117.48,39.88 117.22,40.13 117.22,40.51 116.97,40.77 108.84,40.77 v1(107.95,39.88)
  L18_SIGNAL w0.14: v1(78.69,50.04) 78.74,50.04 79.36,49.41 84.85,49.41 85.07,49.19 85.07,49.05 86.61,47.5 88.14,47.5 95.76,39.88 104.52,39.88 105.41,40.77 107.06,40.77 v1(107.95,39.88)
DDR3-2_DQ46: length 63.8
  TOP w0.197: v1(79.69,50.04) U31.AJ10 ; P5.158 v1(120.85,37.39)
  L18_SIGNAL w0.14: v1(79.69,50.04) 79.69,50.1 80.14,50.55 84.71,50.55 85.07,50.19 85.07,50.19 85.09,50.17 85.09,49.66 86.49,48.26 89.28,48.26 90.55,46.99 91.57,46.99 97.41,41.15 107.55,41.15 107.79,40.9 107.83,40.9 108.52,40.21 108.99,40.21 109.27,40.49 109.68,40.49 110.32,39.85 111.84,39.85 112.37,40.38 115.38,40.38 115.49,40.49 116.33,40.49 116.59,40.24 116.59,35.43 116.84,35.18 118.62,35.18 118.87,34.92 118.87,34.8 119.13,34.54 123.64,34.54 123.75,34.44 124.15,34.44 124.46,34.74 124.46,35.31 124.21,35.56 121.67,35.56 121.41,35.81 121.41,37.14 121.16,37.39 v1(120.85,37.39)
DDR3-2_DQ47: length 63.6
  TOP w0.197: v1(120.78,36.19) 121.38,36.79 P5.160 ; v1(78.69,49.04) U31.AH9
  L16_SIGNAL w0.14: v1(120.78,36.19) 120.27,36.19 120.02,36.45 120.02,36.7 120.27,36.96 125.6,36.96 125.86,37.21 125.86,37.72 125.6,37.97 120.4,37.97 120.14,38.23 120.14,39.12 119.89,39.37 111,39.37 110.74,39.12 v1(107.95,39.12)
  L18_SIGNAL w0.14: v1(78.69,49.04) 78.72,49.04 79.25,48.51 84.96,48.51 86.49,46.99 87.88,46.99 95.63,39.24 104.65,39.24 105.66,40.26 106.81,40.26 v1(107.95,39.12)
DDR3-2_DQ48: length 62.9
  TOP w0.197: P5.163 112.82,35.9 v1(112.52,36.19) ; v1(79.69,51.04) U31.AJ11
  L3_SIGNAL w0.14: v1(79.69,51.04) 79.12,51.61 79.12,53.34 80.39,54.61 86.36,54.61 88.9,52.07 88.9,50.55 91.57,47.88 94.74,47.88 104.01,38.61 105.24,38.61 106.91,36.94 107.95,36.94 107.95,36.96 108.46,37.47 108.97,37.47 109.5,36.94 109.98,36.94 110.24,37.19 110.24,37.47 110.74,37.97 113.3,37.97 113.92,37.35 113.92,36.83 114.17,36.58 114.43,36.58 114.68,36.83 114.68,37.21 114.94,37.47 116.33,37.47 116.59,37.72 116.59,37.94 117,38.35 117.73,38.35 117.98,38.1 117.98,36.45 117.73,36.19 v1(112.52,36.19)
DDR3-2_DQ49: length 63
  TOP w0.197: P5.165 112.89,35.3 v1(112.52,34.92) ; v1(80.69,51.04) U31.AK11
  L3_SIGNAL w0.14: v1(80.69,51.04) 80.66,51.04 80.14,51.56 80.14,52.07 80.64,52.58 86.36,52.58 87.76,51.18 87.76,50.16 90.86,47.06 92.64,47.06 101.99,37.71 101.99,37.35 101.46,36.82 101.1,36.82 95.75,42.17 95.39,42.17 95.05,41.84 95.05,41.48 100.2,36.32 104.79,36.32 105.41,35.7 108.06,35.7 108.2,35.56 111.25,35.56 111.89,34.92 v1(112.52,34.92)
DDR3-2_DQ50: length 63.1
  TOP w0.197: v1(112.52,32.39) 112.61,32.3 P5.175 ; v1(79.69,52.04) U31.AJ12
  L3_SIGNAL w0.14: v1(112.52,32.39) 112,32.39 111.76,32.14 111.76,32 111.51,31.75 110.36,31.75 110.11,32 110.11,34.04 110.74,34.67 111.51,34.67 111.76,34.42 114.18,34.42 114.55,34.79 114.55,34.8 114.81,35.05 117.42,35.05 117.6,35.24 117.6,35.5 117.42,35.69 112.27,35.69 111.51,36.45 106.55,36.45 105.41,37.59 104.01,37.59 94.11,47.5 91.06,47.5 88.39,50.17 88.39,51.82 88.07,52.14 88.07,52.19 86.67,53.59 80.64,53.59 80.14,53.09 80.14,52.49 v1(79.69,52.04)
DDR3-2_DQ51: length 63.1
  TOP w0.197: v1(112.52,31.11) 113.1,31.69 P5.177 ; v1(80.69,52.04) U31.AK12
  L3_SIGNAL w0.14: v1(80.69,52.04) 80.8,52.04 81.28,51.56 86.61,51.56 87.25,50.93 87.25,50.04 90.17,47.12 90.17,45.59 99.82,35.94 103.89,35.94 104.89,34.94 109.22,34.94 109.47,34.68 109.47,31.75 109.22,31.5 109.09,31.5 108.84,31.24 108.84,30.96 109.06,30.73 109.35,30.73 109.73,31.11 111.76,31.11 112.27,31.62 112.78,31.62 113.03,31.88 113.03,32.96 113.22,33.15 113.48,33.15 113.67,32.96 113.67,31.88 113.92,31.62 114.17,31.62 115.1,32.55 115.92,32.55 116.26,32.89 117.69,32.89 117.98,32.6 117.98,32.17 117.69,31.88 114.94,31.88 114.17,31.11 v1(112.52,31.11)
DDR3-2_DQ52: length 63.2
  TOP w0.197: P5.164 119.76,35.6 119.51,35.85 v1(119.51,36.19) ; v1(82.69,50.04) U31.AM10
  L3_SIGNAL w0.14: v1(119.51,36.19) 118.49,37.21 118.49,38.86 118.24,39.12 116.84,39.12 116.59,38.86 116.59,38.84 116.33,38.59 113.28,38.59 113.05,38.35 110.52,38.35 110.38,38.49 110.37,38.48 106.05,38.48 105.41,39.12 104.52,39.12 99.95,43.69 95.1,48.53 95.1,48.97 94.82,49.26 94.38,49.26 94.11,49.53 92.46,49.53 86.47,55.51 80.66,55.51 80.56,55.41 80.54,55.41 80.32,55.19 80.32,55.13 78.85,53.66 78.79,53.66 78.22,53.1 78.22,51.07 78.32,50.97 78.32,50.88 78.54,50.66 82.05,50.66 82.68,50.04 v1(82.69,50.04)
DDR3-2_DQ53: length 61.6
  TOP w0.197: v1(80.69,49.04) U31.AK9 ; P5.166 v1(120.85,35)
  L3_SIGNAL w0.14: v1(106.05,31.24) 103.12,34.16 98.04,34.16 86.23,45.97 86.23,47.24 85.98,47.5 82.3,47.5 82.17,47.62 82.17,48.13 81.79,48.51 81.15,48.51 80.69,48.98 v1(80.69,49.04)
  L9_SIGNAL w0.14: v1(120.85,35) 123.08,35 123.32,35.23 123.32,35.57 123.08,35.81 110.11,35.81 109.86,35.56 109.86,35.05 109.6,34.8 108.33,34.8 108.08,35.05 108.08,35.56 107.82,35.81 107.19,35.81 106.05,34.67 v1(106.05,31.24)
DDR3-2_DQ54: length 61.3
  TOP w0.197: P5.174 121.33,32.6 120.9,33.02 120.14,33.02 v1(119.51,33.66) ; v1(81.69,49.04) U31.AL9
  L3_SIGNAL w0.14: v1(107.31,32.51) 106.81,33.02 104.9,33.02 103.25,34.67 98.3,34.67 86.61,46.36 86.61,48.13 86.23,48.51 82.3,48.51 81.77,49.04 v1(81.69,49.04)
  L9_SIGNAL w0.14: v1(119.51,33.66) 114.94,33.66 114.68,33.4 114.68,32.77 114.94,32.51 119.39,32.51 119.63,32.27 119.63,31.92 119.39,31.67 117.68,31.67 117.6,31.75 110.24,31.75 109.47,32.51 v1(107.31,32.51)
DDR3-2_DQ55: length 61.6
  TOP w0.197: v1(81.69,51.04) U31.AL11 ; v1(120.78,32.39) 121.17,32 P5.176
  L3_SIGNAL w0.14: v1(81.69,51.04) 82.56,51.04 83.06,50.55 85.47,50.55 86.11,49.91 86.49,49.91 89.53,46.86 89.53,45.34 99.31,35.56 103.63,35.56 104.52,34.67 108.08,34.67 108.46,34.29 108.46,31.24 108.2,30.99 106.93,30.99 106.68,31.24 v1(106.68,31.88)
  L9_SIGNAL w0.14: v1(120.78,32.39) 121.41,32.39 121.92,31.88 121.92,30.99 121.41,30.48 120.14,30.48 119.51,31.11 114.94,31.11 114.17,30.35 110.11,30.35 108.59,31.88 v1(106.68,31.88)
DDR3-2_DQ56: length 59.3
  TOP w0.197: v1(83.69,49.04) U31.AN9 ; P5.181 111.9,30.49 v1(111.25,29.85)
  L20_SIGNAL w0.14: v1(108.97,36.07) 108.97,26.54 109.22,26.29 109.6,26.29 109.86,26.54 109.86,32.64 110.11,32.89 111,32.89 111.25,32.64 v1(111.25,29.85)
  L22_SIGNAL w0.14: v1(108.97,36.07) 108.33,36.07 107.58,36.82 104.03,36.82 102.36,38.48 102.36,40 92.71,49.66 90.17,49.66 89.15,50.67 84.86,50.67 84.85,50.66 83.54,50.66 83.19,50.31 83.19,49.53 83.68,49.04 v1(83.69,49.04)
DDR3-2_DQ57: length 59.5
  TOP w0.197: P5.183 v1(112.57,29.9) ; v1(84.69,49.04) U31.AP9
  L20_SIGNAL w0.14: v1(112.57,29.9) 113.28,29.9 113.54,30.15 113.54,35.94 113.79,36.19 118.62,36.19 118.87,35.94 118.87,34.8 118.62,34.54 v1(117.75,34.54)
  L22_SIGNAL w0.14: v1(84.69,49.04) 84.98,49.04 85.6,49.66 88.77,49.66 89.15,49.28 92.46,49.28 101.85,39.88 101.85,38.35 103.76,36.45 106.81,36.45 110.62,32.64 111.89,32.64 112.27,33.02 114.68,33.02 114.94,33.27 114.94,33.53 115.19,33.78 117.48,33.78 117.73,34.04 117.73,34.52 v1(117.75,34.54)
DDR3-2_DQ58: length 59.5
  TOP w0.197: P5.191 112.71,27.49 v1(112.52,27.3) ; v1(84.69,52.04) U31.AP12
  L20_SIGNAL w0.14: v1(116.84,34.29) 116.84,33.27 117.09,33.02 119.51,33.02 119.76,32.77 119.76,31.88 119.51,31.62 115.06,31.62 114.81,31.37 114.81,29.59 v1(112.52,27.3)
  L22_SIGNAL w0.14: v1(116.84,34.29) 116.84,35.31 116.65,35.5 113.67,35.5 113.41,35.75 113.41,36.45 113.03,36.83 110.62,36.83 108.84,38.61 106.81,38.61 105.92,39.5 103.89,39.5 103.25,40.13 103.25,40.77 98.68,45.34 98.68,46.99 96.39,49.28 95.76,49.28 94.62,50.42 91.06,50.42 89.92,51.56 85.22,51.56 84.74,52.04 v1(84.69,52.04)
DDR3-2_DQ59: length 59.7
  TOP w0.197: P5.193 113,26.9 112.78,26.67 111.89,26.67 v1(111.25,27.3) ; v1(84.69,51.04) U31.AP11
  L20_SIGNAL w0.14: v1(110.62,35.05) 110.62,37.59 110.87,37.85 111.63,37.85 111.89,37.59 111.89,24.51 111.63,24.26 111.12,24.26 110.87,24.51 110.87,26.92 v1(111.25,27.3)
  L22_SIGNAL w0.14: v1(84.69,51.04) 89.42,51.04 90.42,50.04 94.36,50.04 95.38,49.02 95.38,48.01 102.87,40.51 102.87,38.99 103.89,37.97 108.46,37.97 110.62,35.81 v1(110.62,35.05)
DDR3-2_DQ60: length 59.5
  TOP w0.197: P5.180 121.1,30.79 v1(120.78,31.11) ; v1(82.69,53.04) U31.AM13
  L16_SIGNAL w0.14: v1(120.78,31.11) 114.68,31.11 112.78,29.21 111.76,29.21 v1(111.25,28.7)
  L22_SIGNAL w0.14: v1(111.25,28.7) 110.24,28.7 109.98,28.45 109.98,27.81 109.47,27.3 108.84,27.3 103.76,32.39 102.62,32.39 90.04,44.96 86.23,44.96 85.73,45.47 83.82,45.47 83.62,45.66 83.54,45.66 83.32,45.88 83.32,45.97 82.62,46.66 82.54,46.66 82.32,46.88 82.32,46.97 81.62,47.66 81.54,47.66 81.07,48.13 81.07,48.19 80.85,48.41 80.75,48.41 80.32,48.84 80.32,51.19 80.54,51.41 80.85,51.41 81.32,51.88 81.32,52.19 81.54,52.41 82,52.41 82.63,53.04 v1(82.69,53.04)
DDR3-2_DQ61: length 59.5
  TOP w0.197: P5.182 121.13,30.2 v1(120.78,29.85) ; v1(83.69,53.04) U31.AN13
  L16_SIGNAL w0.14: v1(107.31,30.61) 107.31,28.57 107.82,28.07 112.65,28.07 113.79,26.92 114.3,26.92 114.68,27.3 114.68,29.34 115.19,29.85 116.97,29.85 117.22,30.1 117.22,30.35 117.48,30.61 119.76,30.61 120.02,30.35 120.02,30.1 120.27,29.85 v1(120.78,29.85)
  L22_SIGNAL w0.14: v1(83.69,53.04) 83.65,53.04 83.19,52.58 83.19,51.82 82.22,50.85 82.22,49.23 82.32,49.13 82.32,48.88 82.54,48.66 82.78,48.66 83.19,48.26 83.19,48.01 83.69,47.5 85.34,47.5 85.73,47.12 89.86,47.12 91.62,45.36 91.8,45.36 99.63,37.53 99.88,37.53 105.41,32 105.92,32 v1(107.31,30.61)
DDR3-2_DQ62: length 59.8
  TOP w0.197: P5.192 v1(123.95,27.2) ; v1(80.69,53.04) U31.AK13
  L22_SIGNAL w0.14: v1(123.95,27.2) 122.94,28.21 122.94,29.59 120.78,31.75 120.27,31.75 118.57,33.45 118.57,35.05 116.16,37.47 115.06,37.47 113.28,39.24 112.52,39.24 110.36,41.4 106.68,41.4 100.71,47.37 100.33,47.37 97.54,50.17 97.03,50.17 95,52.2 92.46,52.2 90.04,54.61 81.53,54.61 81.15,54.23 81.15,53.59 80.69,53.13 v1(80.69,53.04)
DDR3-2_DQ63: length 59.7
  TOP w0.197: v1(120.78,27.3) 120.78,27.05 121.23,26.6 P5.194 ; v1(81.69,53.04) U31.AL13
  L22_SIGNAL w0.14: v1(81.69,53.04) 81.69,53.12 82.17,53.59 90.3,53.59 92.08,51.82 94.36,51.82 96.52,49.66 96.9,49.66 99.44,47.12 99.44,45.59 104.14,40.89 109.47,40.89 112.13,38.24 112.76,38.24 114.81,36.19 116.99,36.19 118.13,35.05 118.13,34.39 118.11,34.37 118.11,32.26 120.14,30.23 120.14,28.96 120.52,28.57 121.92,28.57 122.3,28.2 122.3,27.56 122.05,27.3 v1(120.78,27.3)
DDR3-2_DQS0_N: length 65.3
  TOP w0.152: v1(119.51,84.2) 119.66,84.05 121.52,84.05 121.67,84.19 P5.10 ; v1(83.69,63.04) U31.AN22
  L9_SIGNAL w0.13: v1(119.51,84.2) 119.85,84.2 120.04,84.01 124.48,84.01 124.58,84.11 124.58,87.02 124.48,87.12 119.61,87.12 119.51,87.02 113.9,87.02 112.91,88.01 111.1,88.01 95.48,72.39 92.08,72.39 85.09,65.41 84.85,65.41 84.84,65.41 84.54,65.41 84.53,65.41 83.85,65.41 83.84,65.41 83.54,65.41 83.32,65.19 83.32,65.16 83.32,65.15 83.32,63.65 83.32,63.65 83.32,63.41 v1(83.69,63.04)
DDR3-2_DQS0_P: length 66.6
  TOP w0.152: v1(82.69,63.04) U31.AM22 ; P5.12 121.67,83.59 121.49,83.77 119.71,83.77 v1(119.51,83.57)
  L9_SIGNAL w0.13: v1(119.51,83.57) 119.85,83.57 120.04,83.75 124.59,83.75 124.84,84.01 124.84,87.12 124.59,87.38 119.51,87.38 119.4,87.27 114,87.27 113.01,88.27 111,88.27 95.38,72.64 91.97,72.64 84.99,65.66 84.95,65.66 84.95,65.67 84.43,65.67 84.43,65.66 83.95,65.66 83.95,65.67 83.43,65.67 83.06,65.3 83.06,65.26 83.06,65.26 83.06,63.54 83.06,63.54 83.06,63.41 v1(82.69,63.04)
DDR3-2_DQS1_N: length 57.1
  TOP w0.152: v1(81.69,60.04) U31.AL19 ; P5.27 113.89,79.1 113.79,78.99 111.38,78.99 v1(111.25,79.12)
  L18_SIGNAL w0.13: v1(81.69,60.04) 81.66,60.07 81.41,60.07 81.32,60.16 81.32,60.65 81.32,60.65 81.32,61.3 80.95,61.67 79.54,61.67 79.32,61.89 79.32,66.16 79.32,66.16 79.32,66.19 79.54,66.41 79.57,66.41 79.57,66.41 79.95,66.41 80.32,66.78 80.32,66.98 80.32,66.99 80.32,67.19 80.54,67.41 80.74,67.41 80.75,67.41 80.95,67.41 81.32,67.78 81.32,67.98 81.32,67.99 81.32,68.19 81.54,68.41 81.74,68.41 82.32,68.99 82.32,69.19 82.54,69.41 82.74,69.41 82.75,69.41 82.95,69.41 83.32,69.78 83.32,69.98 83.32,69.99 83.32,70.19 83.54,70.41 83.87,70.41 83.87,70.41 83.95,70.41 84.32,70.78 84.32,70.86 84.32,70.86 84.32,71.19 84.54,71.41 84.74,71.41 84.75,71.41 84.95,71.41 85.32,71.78 85.32,71.98 89.28,75.95 96.01,75.95 97.28,77.21 109.62,77.21 110.13,76.71 113.52,76.71 114.18,77.36 114.18,78.28 113.52,78.93 111.44,78.93 v1(111.25,79.12)
DDR3-2_DQS1_P: length 56.7
  TOP w0.152: v1(111.25,78.49) 111.48,78.71 113.79,78.71 114.01,78.49 P5.29 ; v1(80.69,60.04) U31.AK19
  L18_SIGNAL w0.13: v1(80.69,60.04) 80.72,60.07 80.9,60.07 81.06,60.23 81.06,61.19 80.84,61.41 79.43,61.41 79.06,61.78 79.06,66.27 79.06,66.27 79.06,66.3 79.43,66.67 79.46,66.67 79.46,66.67 79.84,66.67 80.06,66.89 80.06,67.09 80.06,67.09 80.06,67.3 80.43,67.67 80.64,67.67 80.64,67.67 80.84,67.67 81.06,67.89 81.06,68.09 81.06,68.09 81.06,68.3 81.43,68.67 81.64,68.67 82.06,69.09 82.06,69.3 82.43,69.67 82.64,69.67 82.64,69.67 82.84,69.67 83.06,69.89 83.06,70.09 83.06,70.09 83.06,70.3 83.43,70.67 83.76,70.67 83.77,70.67 83.84,70.67 84.06,70.89 84.06,70.96 84.06,70.97 84.06,71.3 84.43,71.67 84.64,71.67 84.64,71.67 84.84,71.67 85.06,71.89 85.06,72.09 89.17,76.2 95.91,76.2 97.17,77.47 109.73,77.47 110.24,76.96 113.41,76.96 113.92,77.47 113.92,78.17 113.42,78.67 111.44,78.67 v1(111.25,78.49)
DDR3-2_DQS2_N: length 56
  TOP w0.152: v1(111.25,73.66) 111.48,73.43 112.14,73.43 112.24,73.53 112.99,73.53 113.16,73.7 P5.45 ; v1(77.69,64.04) U31.AG23
  L5_SIGNAL w0.13: v1(77.69,64.04) 77.32,63.67 77.32,62.89 77.54,62.67 86.49,62.67 87,63.17 87,65.91 87.5,66.42 95.5,66.42 96.27,67.18 100.58,67.18 101.09,67.69 101.09,67.84 100.73,68.2 96.67,68.2 96.01,68.85 96.01,69.58 99.33,72.9 106.93,72.9 107.31,73.28 110.87,73.28 v1(111.25,73.66)
DDR3-2_DQS2_P: length 56.3
  TOP w0.14: v1(76.69,64.04) U31.AF23
  TOP w0.152: P5.47 113.19,73.1 113.03,73.25 112.36,73.25 112.26,73.15 111.51,73.15 v1(111.25,72.9)
  L5_SIGNAL w0.13: v1(76.69,64.04) 77.06,63.67 77.06,62.78 77.44,62.41 86.59,62.41 87.25,63.07 87.25,65.81 87.61,66.16 95.61,66.16 96.37,66.93 100.69,66.93 101.35,67.58 101.35,67.95 100.84,68.45 96.77,68.45 96.27,68.96 96.27,69.47 99.44,72.64 107.31,72.64 107.7,73.02 110.98,73.02 111.05,73.1 v1(111.25,72.9)
DDR3-2_DQS3_N: length 55.6
  TOP w0.152: P5.62 121.49,68.59 121.35,68.46 121.32,68.48 120.17,68.48 v1(120.02,68.63) ; v1(76.69,61.04) U31.AF20
  L22_SIGNAL w0.127: v1(76.69,61.04) 77.06,60.67 77.63,60.67 77.94,60.67 78.32,60.29 78.32,60.08 78.32,59.89 78.54,59.67 85.73,59.67 87.02,60.96 106.43,60.96 107.3,61.84 109.48,61.84 110.64,62.99 111.78,62.99 113.05,64.26 118.51,64.26 120.02,65.76 120.02,66.57 119.66,66.93 118.49,66.93 118.11,67.31 118.11,67.95 118.55,68.39 119.78,68.39 v1(120.02,68.63)
DDR3-2_DQS3_P: length 55.6
  TOP w0.152: P5.64 121.41,68 121.21,68.2 120.22,68.2 v1(120.02,67.99) ; v1(76.69,60.04) U31.AF19
  L22_SIGNAL w0.127: v1(120.02,67.99) 119.87,68.14 118.66,68.14 118.36,67.84 118.36,67.42 118.6,67.18 119.76,67.18 120.27,66.67 120.27,65.66 118.62,64.01 113.16,64.01 111.89,62.74 110.74,62.74 109.59,61.58 107.41,61.58 106.53,60.71 87.12,60.71 85.83,59.42 78.43,59.42 78.07,59.78 78.07,60.18 77.84,60.41 77.73,60.41 77.06,60.41 v1(76.69,60.04)
DDR3-2_DQS4_N: length 58.1
  TOP w0.152: P5.135 112.98,44.3 112.83,44.15 111.7,44.15 111.69,44.14 v1(111.51,44.32) ; v1(75.69,51.04) U31.AE11
  L5_SIGNAL w0.13: v1(75.69,51.04) 76.06,51.41 88.44,51.41 90.06,49.78 95.78,49.78 97.56,48 106.83,48 109.09,45.74 109.09,43.33 111.91,40.51 114.81,40.51 115.06,40.77 115.06,41.65 115.17,41.76 116.05,41.76 116.44,42.14 116.44,43.46 115.82,44.07 111.76,44.07 v1(111.51,44.32)
DDR3-2_DQS4_P: length 57.3
  TOP w0.14: v1(75.69,52.04) U31.AE12
  TOP w0.152: v1(111.51,43.56) 111.81,43.87 112.81,43.87 112.98,43.7 P5.137
  L5_SIGNAL w0.13: v1(75.69,52.04) 76.06,51.67 88.54,51.67 90.17,50.04 95.89,50.04 97.66,48.26 106.93,48.26 109.35,45.85 109.35,43.44 112.02,40.77 114.7,40.77 114.81,40.87 114.81,41.76 115.06,42.02 115.95,42.02 116.18,42.25 116.18,43.35 115.72,43.81 111.76,43.81 v1(111.51,43.56)
DDR3-2_DQS5_N: length 62.4
  TOP w0.152: v1(78.69,52.04) U31.AH12 ; P5.152 121.49,39.19 121.28,38.99 120.93,38.99 v1(120.78,39.14)
  L18_SIGNAL w0.13: v1(120.78,39.14) 120.93,38.99 122.68,38.99 122.94,39.24 122.94,42.95 122.83,43.05 117.09,43.05 116.84,42.8 116.84,42.03 116.59,41.78 109.24,41.78 108.84,42.18 108.84,43.18 108.46,43.56 103.4,43.56 100.67,46.29 99.4,46.29 95.91,49.78 86.76,49.78 86.36,50.19 86.36,52.85 85.8,53.41 78.54,53.41 78.32,53.19 78.32,52.41 78.32,52.41 v1(78.69,52.04)
DDR3-2_DQS5_P: length 63.7
  TOP w0.14: v1(77.69,52.04) U31.AG12
  TOP w0.152: P5.154 121.42,38.6 121.31,38.71 121,38.71 120.8,38.51 v1(120.78,38.51)
  L18_SIGNAL w0.13: v1(120.78,38.51) 121,38.73 122.79,38.73 123.19,39.14 123.19,43.05 122.94,43.31 116.99,43.31 116.58,42.9 116.58,42.14 116.48,42.04 109.35,42.04 109.1,42.29 109.1,43.29 108.56,43.82 103.5,43.82 100.77,46.55 99.51,46.55 96.01,50.04 86.87,50.04 86.61,50.29 86.61,52.96 85.9,53.67 78.44,53.67 78.06,53.3 78.06,52.52 78.06,52.52 78.06,52.41 v1(77.69,52.04)
DDR3-2_DQS6_N: length 62.7
  TOP w0.152: v1(111.25,34.16) 111.49,33.92 113.11,33.92 113.28,34.09 P5.169 ; v1(81.69,48.04) U31.AL8
  L3_SIGNAL w0.13: v1(111.25,34.16) 111,33.91 110.74,33.91 110.49,33.66 110.49,33.02 110.87,32.64 111.51,32.64 112.52,33.66 112.65,33.66 112.65,33.65 115.29,33.65 115.39,33.55 116.11,33.55 116.11,33.55 118.38,33.55 118.74,33.19 118.74,31.73 118.38,31.37 115.08,31.37 114.32,30.61 112.27,30.61 112.26,30.62 110,30.62 109.49,30.1 106.41,30.1 103.99,32.51 103.68,32.51 100.33,32.51 99.44,33.4 99.12,33.4 99.02,33.4 97.66,33.4 85.6,45.47 85.6,46.23 85.16,46.67 81.54,46.67 81.32,46.89 81.32,47.67 v1(81.69,48.04)
DDR3-2_DQS6_P: length 63.1
  TOP w0.152: v1(111.25,33.4) 111.49,33.64 113.18,33.64 113.33,33.49 P5.171 ; v1(80.69,48.04) U31.AK8
  L3_SIGNAL w0.127: v1(111.25,33.4) 111,33.65 111,33.65
  L3_SIGNAL w0.13: v1(80.69,48.04) 81.06,47.67 81.06,46.78 81.44,46.41 85.05,46.41 85.34,46.12 85.34,45.36 97.56,33.14 99.12,33.14 99.23,33.14 99.33,33.14 100.22,32.26 103.78,32.26 103.89,32.26 106.3,29.85 109.59,29.85 110.11,30.36 112.15,30.36 112.16,30.35 114.43,30.35 115.19,31.11 118.49,31.11 119,31.62 119,33.3 118.49,33.81 116.01,33.81 116,33.81 115.5,33.81 115.39,33.91 112.76,33.91 112.75,33.91 112.42,33.91 111.4,32.9 110.98,32.9 110.75,33.13 110.75,33.55 110.85,33.65 111,33.65
DDR3-2_DQS7_N: length 59
  TOP w0.152: v1(84.69,50.04) U31.AP10 ; v1(119.51,29.08) 119.74,28.85 121.28,28.85 121.43,29 P5.186
  L22_SIGNAL w0.13: v1(84.69,50.04) 84.69,50.04 84.45,50.04 84.32,49.9 84.32,48.89 84.54,48.67 84.92,48.67 84.93,48.66 84.98,48.64 85.58,48.64 86.34,47.88 92.18,47.88 93.6,46.46 93.6,46.21 94.85,44.96 95.45,44.96 101.09,39.32 101.09,37.46 102.61,35.94 106.57,35.94 109.98,32.53 109.98,31.73 110.09,31.63 111.1,31.63 112.12,30.61 113.14,30.61 113.6,30.14 113.6,25.63 113.71,25.53 114.83,25.53 114.93,25.63 114.93,29.28 114.93,29.49 115.41,29.97 115.62,29.97 116.08,29.97 117.22,28.83 119.26,28.83 v1(119.51,29.08)
DDR3-2_DQS7_P: length 59.6
  TOP w0.14: v1(83.69,50.04) U31.AN10
  TOP w0.152: v1(119.51,28.32) 119.76,28.57 121.28,28.57 121.47,28.39 P5.188
  L22_SIGNAL w0.13: v1(83.69,50.04) 83.69,50.04 83.95,50.04 84.06,49.92 84.06,48.78 84.43,48.41 84.84,48.41 84.94,48.39 85.47,48.39 86.23,47.62 92.08,47.62 93.34,46.36 93.34,46.1 94.74,44.7 95.35,44.7 100.84,39.21 100.84,37.36 102.51,35.69 106.46,35.69 109.73,32.42 109.73,31.62 109.98,31.37 111,31.37 112.01,30.35 113.03,30.35 113.35,30.04 113.35,27.96 113.35,25.53 113.6,25.27 114.94,25.27 115.19,25.53 115.19,27.96 115.19,29.39 115.52,29.72 115.97,29.72 117.11,28.57 119.38,28.57 119.51,28.45 v1(119.51,28.32)
DDR3-2_ODT0: length 67.6
  TOP w0.197: v1(120.78,50.17) 120.95,50 P5.116 ; v1(77.69,59.04) U31.AG18
  L3_SIGNAL w0.14: v1(107.95,61.09) 107.44,61.09 107.31,61.21 107.31,61.85 107.57,62.1 109,62.1 109.22,62.33 109.22,62.64 109,62.87 107.19,62.87 106.81,62.48 106.81,61.09 106.37,60.65 104.9,60.65 104.11,61.44 103.03,61.44 102.89,61.29 95.51,61.29 95.2,60.98 94.79,60.98 94.51,61.27 92.69,61.27 92.4,60.98 92,60.98 91.54,61.44 87.02,61.44 85.85,62.61 80.64,62.61 80.07,62.03 80.07,61.88 79.85,61.66 79.7,61.66 78.11,60.07 78.11,59.45 v1(77.69,59.04)
  L20_SIGNAL w0.14: v1(120.78,50.17) 122.3,51.69 122.3,59.18 121.79,59.69 115.32,59.69 114.17,60.83 112.01,60.83 111.76,61.09 v1(107.95,61.09)
DDR3-2_ODT1: length 67.8
  TOP w0.197: v1(120.78,48.89) 120.88,48.79 P5.120 ; v1(76.69,55.04) U31.AF15
  L18_SIGNAL w0.14: v1(106.05,61.72) 105.64,62.13 103.48,62.13 103,62.61 89.28,62.61 85.33,58.66 76.57,58.66 75.95,58.04 75.95,55.78 v1(76.69,55.04)
  L20_SIGNAL w0.14: v1(120.78,48.89) 122.94,51.05 122.94,59.44 121.41,60.96 115.32,60.96 113.92,62.36 110.11,62.36 109.47,61.72 v1(106.05,61.72)
DDR3-2_RASB: length 60.2
  TOP w0.197: P5.110 121.14,51.79 v1(120.78,51.44) ; v1(74.69,55.04) U31.AD15
  L16_SIGNAL w0.14: v1(120.78,51.44) 121.54,52.2 121.54,54.36 121.03,54.86 120.52,54.86 120.14,55.25 120.14,59.56 118.75,60.96 109.86,60.96 109.09,60.2 92.08,60.2 87.5,55.63 75.31,55.63 74.72,55.04 v1(74.69,55.04)
DDR3-2_REF_EN: length 33.3
  TOP w0.14: R658.1 v1(166.24,34.92) ; RN6.15 v1(187.18,51.96)
  L22_SIGNAL w0.095: v1(187.18,51.96) 187.18,51.41 185.55,49.78 184.53,49.78 183.52,48.77 177.04,48.77 174.75,46.48 172.21,46.48 169.29,43.56 169.29,37.97 v1(166.24,34.92)
DDR3-2_RESETB: length 54.1
  TOP w0.197: v1(80.69,63.04) U31.AK22 ; P5.30 v1(124.68,78.19)
  L16_SIGNAL w0.14: v1(80.69,63.04) 81.15,63.5 85.22,63.5 87.88,66.17 97.41,66.17 103,71.76 113.79,71.76 115.82,73.79 118.24,73.79 119.38,74.93 122.05,74.93 124.68,77.56 v1(124.68,78.19)
  BOTTOM w0.197: v1(124.68,78.19) 125.01,78.19 R268.2
DDR3-2_S0B: length 59.8
  TOP w0.197: P5.114 123.52,50.6 v1(123.95,50.17) ; v1(77.69,55.04) U31.AG15
  L16_SIGNAL w0.14: v1(77.69,55.04) 77.69,55.02 78.11,54.61 87.63,54.61 92.71,59.69 117.22,59.69 118.24,58.67 118.24,51.18 119.01,50.41 119.88,50.41 120.4,50.93 123.19,50.93 v1(123.95,50.17)
DDR3-2_S1B: length 55.3
  TOP w0.197: v1(111.25,48.89) 111.8,48.35 112.74,48.35 112.88,48.49 P5.121 ; v1(78.69,60.04) U31.AH19
  L16_SIGNAL w0.14: v1(111.25,48.89) 108.2,51.94 91.82,51.94 90.81,50.93 85.98,50.93 85.34,51.56 74.55,51.56 74.07,52.05 74.07,59.19 74.31,59.44 78.11,59.44 78.69,60.02 v1(78.69,60.04)
DDR3-2_SYS_CLK_N: length 121
  TOP w0.152: C71.2 R98.2 R108.1 152.27,109.22 v1(152.27,108.84) ; v1(78.69,57.04) U31.AH17
  L7_SIGNAL w0.13: v1(78.69,57.04) 78.32,56.67 78.32,52.92 78.32,52.92 78.32,52.89 78.54,52.67 80.84,52.67 81.06,52.89 81.06,53.37 81.36,53.67 87.22,53.67 93.09,59.54 93.09,80.12 99.46,86.49 105.68,86.49 118.49,99.29 118.49,100.69 125.5,107.7 152.42,107.7 152.65,107.93 152.65,108.46 v1(152.27,108.84)
  BOTTOM w0.152: R331.2 78.55,57.18 v1(78.69,57.04)
DDR3-2_SYS_CLK_P: length 121.9
  TOP w0.152: C72.2 R99.1 R109.1 153.29,109.22 v1(153.29,108.84) ; v1(77.69,57.04) U31.AG17
  L7_SIGNAL w0.13: v1(77.69,57.04) 78.06,56.67 78.06,52.81 78.06,52.81 78.06,52.78 78.43,52.41 80.95,52.41 81.32,52.78 81.32,53.27 81.46,53.41 87.32,53.41 93.34,59.44 93.34,80.01 99.57,86.23 105.79,86.23 118.75,99.19 118.75,100.58 125.6,107.44 152.53,107.44 152.91,107.82 152.91,108.46 v1(153.29,108.84)
  BOTTOM w0.152: v1(77.69,57.04) 77.93,57.28 77.91,57.29 R331.1
DDR3-2_TEMP_EVENTB: length 69.1
  TOP w0.197: P5.198 v1(120.78,25.39) ; v1(78.69,54.04) U31.AH14
  L22_SIGNAL w0.14: v1(120.78,25.39) 120.02,24.64 118.87,24.64 116.46,22.22 116.46,21.34 115.57,20.45 110.62,20.45 109.6,21.46 105.54,21.46 104.14,22.86 104.14,25.91 101.98,28.07 101.98,31.62 90.55,43.05 85.47,43.05 84.86,43.66 84.54,43.66 84.32,43.88 84.32,44.19 83.85,44.66 83.54,44.66 83.32,44.88 83.32,45.19 82.85,45.66 82.54,45.66 82.32,45.88 82.32,46.19 81.85,46.66 81.54,46.66 81.32,46.88 81.32,47.19 80.85,47.66 80.54,47.66 80.32,47.88 80.32,48.21 79.25,49.28 79.25,53.47 78.69,54.02 v1(78.69,54.04)
  BOTTOM w0.197: 121.79,25.4 121.79,25.39 v1(120.78,25.39)
DDR3-2_WEB: length 40.1
  TOP w0.197: P5.113 113.06,50.89 v1(112.52,51.44) ; v1(75.69,53.04) U31.AE13
  L16_SIGNAL w0.14: v1(112.52,51.44) 111.89,52.07 110.24,52.07 109.73,52.58 94.42,52.58 94.31,52.47 76.31,52.47 75.74,53.04 v1(75.69,53.04)
DDR3_1V5_EN: length 138.9
  TOP w0.203: v1(121.03,152.27) 121.41,152.65 121.41,152.97 121.56,153.11 121.54,153.13 121.54,154.21 121.75,154.42 121.75,154.89 121.95,155.09 U2.39 ; v1(177.55,60.96) 178,60.51 178.88,60.51 178.97,60.6 RN7.15
  L18_SIGNAL w0.203: v1(177.55,60.96) 154.43,60.96 150.18,65.21 v1(146.24,65.21)
  L20_SIGNAL w0.203: v1(121.03,152.27) 121.03,151 122.17,149.86 122.94,149.86 125.73,147.07 125.73,118.24 124.08,116.59 124.08,107.06 127,104.14 127,84.45 v1(146.24,65.21)
DONE: length 180.8
  TOP w0.14: v1(68.69,48.04) U31.V8 ; RN9.12 v1(178.69,72.26) ; U22.9 v1(140.46,99.82)
  L7_SIGNAL w0.095: v1(178.69,72.26) 178.31,72.64 177.14,72.64 176.15,73.64 176.15,82.93 174.88,84.2 173.61,84.2 169.8,88.01 153.03,88.01 148.84,92.2 147.83,92.2 144.53,95.5 144.53,97.28 141.99,99.82 v1(140.46,99.82)
  L16_SIGNAL w0.095: v1(68.69,48.04) 68.69,48.02 69.22,47.5 95.76,47.5 98.04,45.21 103.76,45.21 104.52,45.97 114.3,45.97 114.68,45.59 116.08,45.59 116.59,45.08 119.89,45.08 120.4,45.59 124.84,45.59 126.11,46.86 126.11,50.55 131.95,56.39 136.27,56.39 v1(138.43,58.55)
  L18_SIGNAL w0.095: v1(140.46,99.82) 138.43,97.79 v1(138.43,58.55)
  BOTTOM w0.14: v1(68.69,48.04) 68.6,48.13 R304.1
FAN_PWM: length 224.2
  TOP w0.14: RN10.14 v1(193.03,51.83) ; v1(78.69,69.04) U31.AH28
  L3_SIGNAL w0.095: v1(193.03,51.83) 193.04,51.84 193.04,54.23 189.36,57.91 184.4,57.91 182.5,59.82 182.5,73.31 177.2,78.61 157.83,78.61 155.93,76.71 118.49,76.71 116.2,74.42 110.74,74.42 106.81,70.48 98.68,70.48 98.17,69.98 90.3,69.98 89.79,70.48 82.55,70.48 82.17,70.1 82.17,69.85 81.79,69.47 79.12,69.47 v1(78.69,69.04)
  L22_SIGNAL w0.095: v1(165.48,118.9) 165.48,118.87 169.42,114.94 169.42,108.2 173.61,104.01 173.61,95.63 183.01,86.23 183.01,57.15 185.17,54.99 189.87,54.99 v1(193.03,51.83)
  BOTTOM w0.14: Q13.1 v1(165.48,118.9) 166.47,118.9 R235.2
FAN_TACH: length 235.4
  TOP w0.14: v1(193.53,50.93) RN10.15 ; v1(74.69,67.04) U31.AD26
  L5_SIGNAL w0.095: v1(175.64,81.92) 174.37,81.92 173.1,83.19 171.83,83.19 171.57,82.92 161.12,82.92 158.84,85.21 154.92,85.21 150.78,89.34 143.07,89.34 129.61,102.8 113.09,102.8 102.8,92.52 99.76,92.52 98.49,91.25 98.49,88.71 95.44,85.66 83.63,85.66 75.18,77.22 75.18,71.03 74.34,70.19 74.34,69.89 75.18,69.05 75.18,67.56 74.69,67.07 v1(74.69,67.04)
  L7_SIGNAL w0.095: v1(175.64,81.92) 170.31,76.58 170.31,70.23 171.15,69.38 171.15,68.49 171.7,67.95 171.7,63.25 172.59,62.36 172.59,57.4 174.37,55.63 180.47,55.63 182.63,53.47 182.63,51.69 184.15,50.17 192.77,50.17 v1(193.53,50.93)
  L9_SIGNAL w0.095: v1(177.35,121.47) 176.28,120.4 176.28,111.12 177.93,109.47 177.93,103.12 171.07,96.27 171.07,85.22 174.37,81.92 v1(175.64,81.92)
  BOTTOM w0.14: U40.4 v1(177.35,121.47)
FMC-1_3P3VAUX: length 7.5
  TOP w0.203: P1.D32 v1(12.7,35.69)
  BOTTOM w0.508: F2.2 13.34,36.32 v1(12.7,35.69)
FMC-1_CLK0_M2C_N: length 96.7
  TOP w0.102: 6.98,70.61 v1(7.62,69.98)
  TOP w0.14: v1(55.69,62.04) U31.F21
  L5_SIGNAL w0.089: v1(7.62,69.98) 7.62,70.36 7.75,70.49 7.85,70.49 7.85,70.49 9.24,70.49 9.66,70.9 9.66,75.34 10.14,75.82 26.39,75.82 26.8,76.22 26.8,79.25 27.05,79.5 39.9,79.5 40.01,79.4 40.01,78.34 39.9,78.23 29.08,78.23 28.83,77.98 28.83,76.07 29.08,75.82 29.74,75.82 32.13,73.43 32.13,65.3 35.45,61.98 48.87,61.98 50.29,63.39 55.84,63.39 56.06,63.16 56.06,62.41 v1(55.69,62.04)
FMC-1_CLK0_M2C_P: length 97.1
  TOP w0.102: 6.98,71.88 v1(7.62,71.25)
  TOP w0.14: v1(56.69,62.04) U31.G21
  L5_SIGNAL w0.089: v1(7.62,71.25) 7.62,70.87 7.74,70.75 9.13,70.75 9.4,71.01 9.4,75.44 10.03,76.07 26.29,76.07 26.54,76.33 26.54,79.35 26.95,79.76 40.01,79.76 40.26,79.5 40.26,78.23 40.01,77.98 29.19,77.98 29.08,77.87 29.08,76.18 29.19,76.07 29.84,76.07 32.38,73.53 32.38,65.41 35.56,62.23 48.77,62.23 50.18,63.64 55.94,63.64 56.32,63.27 56.32,62.41 v1(56.69,62.04)
FMC-1_CLK1_M2C_N: length 97.5
  TOP w0.102: v1(53.69,56.04) U31.D16 ; P1.G3 v1(8.89,72.52)
  L9_SIGNAL w0.089: v1(8.89,72.52) 8.89,72.9 9.02,73.03 10.41,73.03 10.92,73.53 10.92,75.21 11.15,75.44 22.08,75.44 22.48,75.84 22.48,81.53 22.73,81.79 23.62,81.79 23.88,81.53 23.88,75.69 24.13,75.44 25.65,75.44 25.91,75.69 25.91,78.38 26.01,78.49 34.44,78.49 34.54,78.38 34.54,77.58 34.44,77.47 27.3,77.47 27.05,77.22 27.05,75.84 27.45,75.44 43.7,75.44 44.06,75.08 44.06,64.91 47.62,61.34 47.62,59.82 49.53,57.91 53.59,57.91 54.09,57.42 54.09,56.44 v1(53.69,56.04)
FMC-1_CLK1_M2C_P: length 97.9
  TOP w0.102: v1(54.69,56.04) U31.E16 ; P1.G2 v1(8.89,73.79)
  L9_SIGNAL w0.089: v1(8.89,73.79) 8.89,73.41 9.02,73.28 10.31,73.28 10.67,73.64 10.67,75.31 11.05,75.69 21.97,75.69 22.22,75.95 22.22,81.64 22.63,82.04 23.73,82.04 24.13,81.64 24.13,75.8 24.24,75.69 25.55,75.69 25.65,75.8 25.65,78.49 25.91,78.74 34.54,78.74 34.8,78.49 34.8,77.47 34.54,77.22 27.41,77.22 27.3,77.11 27.3,75.95 27.56,75.69 43.8,75.69 44.31,75.18 44.31,65.01 47.88,61.45 47.88,59.92 49.64,58.17 53.7,58.17 54.34,57.52 54.34,56.39 v1(54.69,56.04)
FMC-1_CLK2_BIDIR_N: length 67.2
  TOP w0.102: 4.45,70.61 v1(5.08,69.98)
  TOP w0.14: v1(56.69,63.04) U31.G22
  L18_SIGNAL w0.089: v1(56.69,63.04) 57.06,63.41 57.06,63.5 57.04,63.52 57.04,64.18 56.84,64.39 51.08,64.39 49.66,65.81 49.66,70.63 46.86,73.43 46.86,74.82 46.76,74.93 18.27,74.93 18.16,74.82 18.16,73.55 17.76,73.15 7.34,73.15 7.11,72.92 7.11,70.89 6.71,70.48 5.21,70.48 5.08,70.36 v1(5.08,69.98)
FMC-1_CLK2_BIDIR_P: length 67.6
  TOP w0.102: 4.45,71.88 v1(5.08,71.25)
  TOP w0.14: v1(57.69,63.04) U31.H22
  L18_SIGNAL w0.089: v1(5.08,71.25) 5.08,70.87 5.21,70.74 6.6,70.74 6.86,70.99 6.86,73.03 7.24,73.41 17.65,73.41 17.91,73.66 17.91,74.93 18.16,75.18 46.86,75.18 47.12,74.93 47.12,73.53 49.91,70.74 49.91,65.91 51.18,64.64 56.94,64.64 57.29,64.29 57.29,63.63 57.32,63.61 57.32,63.41 v1(57.69,63.04)
FMC-1_CLK3_BIDIR_N: length 60.7
  TOP w0.102: P1.J3 v1(6.35,72.52)
  TOP w0.14: v1(53.69,57.04) U31.D17
  L7_SIGNAL w0.089: v1(53.69,57.04) 53.74,57.04 54.1,57.4 54.1,57.68 53.74,58.04 46.76,58.04 46.1,58.7 46.1,61.36 45.74,61.72 43.05,61.72 42.8,61.98 42.8,62.99 42.55,63.25 36.34,63.25 35.94,63.65 35.94,66.19 34.82,67.31 33.8,67.31 28.09,73.03 6.44,73.03 6.35,72.94 v1(6.35,72.52)
FMC-1_CLK3_BIDIR_P: length 61
  TOP w0.102: P1.J2 v1(6.35,73.79)
  TOP w0.14: v1(54.69,57.04) U31.E17
  L7_SIGNAL w0.089: v1(54.69,57.04) 54.36,57.37 54.36,57.78 53.85,58.29 46.86,58.29 46.36,58.8 46.36,61.47 45.85,61.98 43.16,61.98 43.05,62.08 43.05,63.1 42.65,63.5 36.45,63.5 36.2,63.75 36.2,66.29 34.92,67.56 33.91,67.56 28.19,73.28 6.44,73.28 6.35,73.37 v1(6.35,73.79)
FMC-1_CLK_DIR_1P8: length 151.6
  TOP w0.14: RN8.11 v1(178.19,67.68) ; v1(177.16,67.18) 176.57,67.18 U28.3 ; v1(77.69,73.04) U31.AG32
  L16_SIGNAL w0.095: v1(77.69,73.04) 77.74,73.04 78.23,73.53 78.23,75.95 85.09,82.8 86.87,82.8 92.14,88.07 94.04,88.07 99.7,93.73 100.97,93.73 111.12,103.89 154.71,103.89 160.48,98.12 175.46,98.12 v1(175.9,98.55)
  L18_SIGNAL w0.095: v1(177.16,67.18) 176.02,68.33 176.02,85.35 176.39,85.71 176.39,86.75 176.02,87.12 176.02,93.98 176.78,94.74 176.78,97.54 175.9,98.42 v1(175.9,98.55)
  BOTTOM w0.14: v1(177.16,67.18) 177.66,67.68 v1(178.19,67.68)
FMC-1_CLK_DIR_3P3: length 205.7
  TOP w0.14: 14.61,75.69 v1(15.24,75.06) ; v1(172.59,66.93) 172.72,67.06 173.1,67.06 173.24,67.19 U28.14
  L18_SIGNAL w0.095: v1(172.59,66.93) 171.83,66.17 170.05,66.17 169.16,67.06 169.16,83.44 158.56,94.04 156.15,94.04 155.19,95 155.19,97.41 152.49,100.12 152.49,100.14 145.44,107.19 139.45,107.19 137.29,109.35 113.41,109.35 107.31,103.25 107.31,101.73 104.39,98.81 100.33,98.81 99.82,99.31 89.41,99.31 82.93,92.84 80.14,92.84 78.61,94.36 66.04,94.36 59.44,87.76 48.26,87.76 37.97,77.47 17.65,77.47 v1(15.24,75.06)
FMC-1_DP0_C2M_N: length 66.4
  TOP w0.102: P1.C3 v1(13.97,72.52)
  TOP w0.14: v1(53.69,41.04) U31.D1
  L9_SIGNAL w0.089: v1(13.97,72.52) 13.97,72.94 14.06,73.03 15.23,73.03 15.59,72.66 15.59,66.07 16.26,65.41 32.15,65.41 35.84,61.72 38.12,61.72 40.39,59.46 40.39,46.76 45.87,41.28 50.43,41.28 50.57,41.41 53.32,41.41 v1(53.69,41.04)
FMC-1_DP0_C2M_P: length 66.4
  TOP w0.102: P1.C2 v1(13.97,73.79)
  TOP w0.14: v1(53.69,42.04) U31.D2
  L9_SIGNAL w0.089: v1(13.97,73.79) 13.97,73.37 14.06,73.28 15.33,73.28 15.84,72.77 15.84,66.18 16.36,65.66 32.26,65.66 35.94,61.98 38.23,61.98 40.64,59.56 40.64,46.86 45.97,41.53 50.33,41.53 50.46,41.67 53.32,41.67 v1(53.69,42.04)
FMC-1_DP0_M2C_N: length 70.9
  TOP w0.102: P1.C7 v1(13.97,67.44)
  TOP w0.14: v1(56.69,43.04) U31.G3
  L9_SIGNAL w0.089: v1(13.97,67.44) 13.97,67.86 14.06,67.95 14.35,67.95 14.48,67.82 14.48,63.25 14.86,62.87 19.94,62.87 20.83,61.98 31.88,61.98 35.81,58.04 35.81,45.08 41.91,38.99 54.23,38.99 55.29,40.05 55.29,43.23 55.5,43.43 56.1,43.43 56.12,43.41 56.32,43.41 v1(56.69,43.04)
FMC-1_DP0_M2C_P: length 70.9
  TOP w0.102: P1.C6 v1(13.97,68.71)
  TOP w0.14: v1(56.69,44.04) U31.G4
  L9_SIGNAL w0.089: v1(13.97,68.71) 13.97,68.29 14.06,68.2 14.46,68.2 14.73,67.92 14.73,63.35 14.96,63.12 20.05,63.12 20.12,63.04 20.94,62.23 31.98,62.23 36.07,58.14 36.07,45.19 42.02,39.24 54.12,39.24 55.04,40.16 55.04,43.33 55.39,43.69 56.21,43.69 56.23,43.67 56.32,43.67 v1(56.69,44.04)
FMC-1_DP1_C2M_N: length 39.9
  TOP w0.102: P1.A23 v1(16.51,47.12)
  TOP w0.14: v1(52.69,43.04) U31.C3
  L18_SIGNAL w0.089: v1(16.51,47.12) 17.02,47.62 18.8,47.62 20.07,46.36 45.72,46.36 48.64,43.43 52.3,43.43 v1(52.69,43.04)
FMC-1_DP1_C2M_P: length 39.9
  TOP w0.102: P1.A22 v1(16.51,48.39)
  TOP w0.14: v1(52.69,44.04) U31.C4
  L18_SIGNAL w0.089: v1(52.69,44.04) 52.34,43.69 48.75,43.69 45.83,46.61 20.17,46.61 18.9,47.88 17.02,47.88 v1(16.51,48.39)
FMC-1_DP1_M2C_N: length 60.1
  TOP w0.102: P1.A3 v1(16.51,72.52)
  TOP w0.14: v1(54.69,43.04) U31.E3
  L9_SIGNAL w0.089: v1(54.69,43.04) 54.69,43.31 54.63,43.37 54.31,43.37 54.04,43.64 54.04,49.18 53.82,49.4 48.66,49.4 45.21,52.85 45.21,59.71 42.31,62.61 41.42,62.61 31.01,73.03 16.6,73.03 16.51,72.94 v1(16.51,72.52)
FMC-1_DP1_M2C_P: length 60.1
  TOP w0.102: P1.A2 v1(16.51,73.79)
  TOP w0.14: v1(54.69,44.04) U31.E4
  L9_SIGNAL w0.089: v1(16.51,73.79) 16.51,73.37 16.6,73.28 31.11,73.28 41.53,62.87 42.42,62.87 45.47,59.82 45.47,52.96 48.77,49.66 53.93,49.66 54.29,49.29 54.29,43.75 54.42,43.62 54.55,43.62 54.61,43.69 54.61,43.96 v1(54.69,44.04)
FMC-1_DP2_C2M_N: length 39.6
  TOP w0.102: 15.88,42.67 v1(16.51,42.04)
  TOP w0.14: v1(51.69,41.04) U31.B1
  L18_SIGNAL w0.089: v1(51.69,41.04) 51.32,41.41 51.23,41.41 51.22,41.4 48.64,41.4 45.06,44.98 20.95,44.98 18.52,42.55 17.02,42.55 v1(16.51,42.04)
FMC-1_DP2_C2M_P: length 39.6
  TOP w0.102: P1.A26 v1(16.51,43.31)
  TOP w0.14: v1(51.69,42.04) U31.B2
  L18_SIGNAL w0.089: v1(16.51,43.31) 17.02,42.8 18.41,42.8 20.85,45.23 45.17,45.23 48.75,41.66 51.11,41.66 51.12,41.67 51.32,41.67 v1(51.69,42.04)
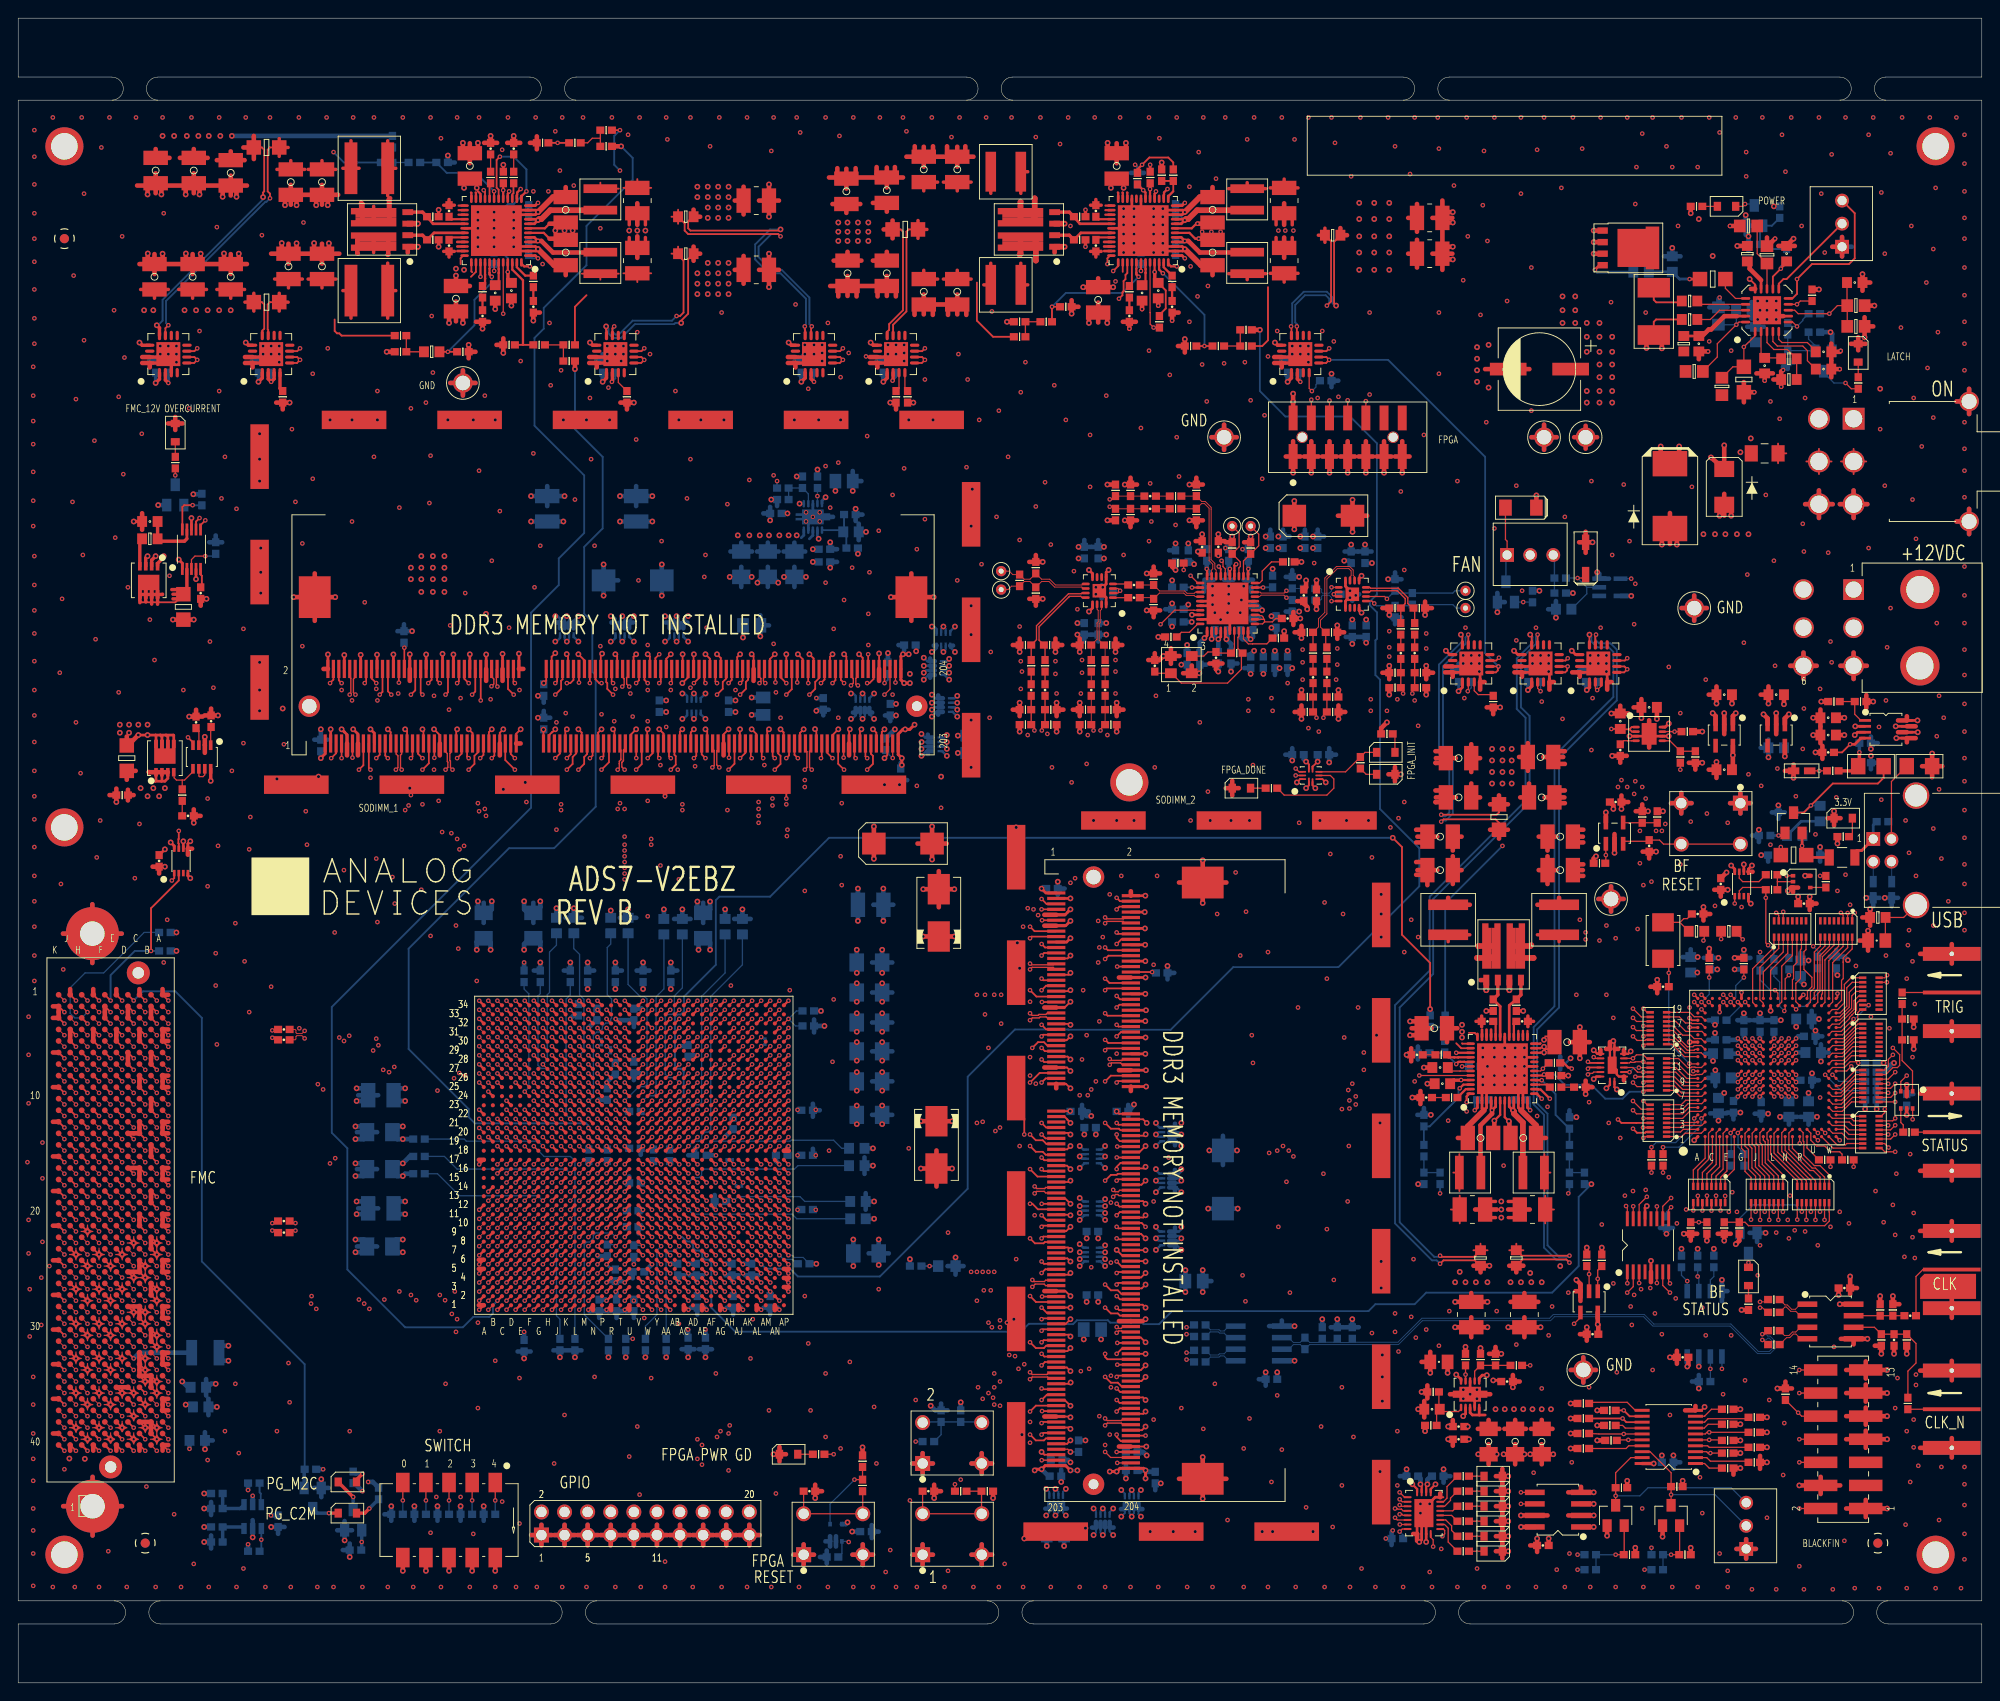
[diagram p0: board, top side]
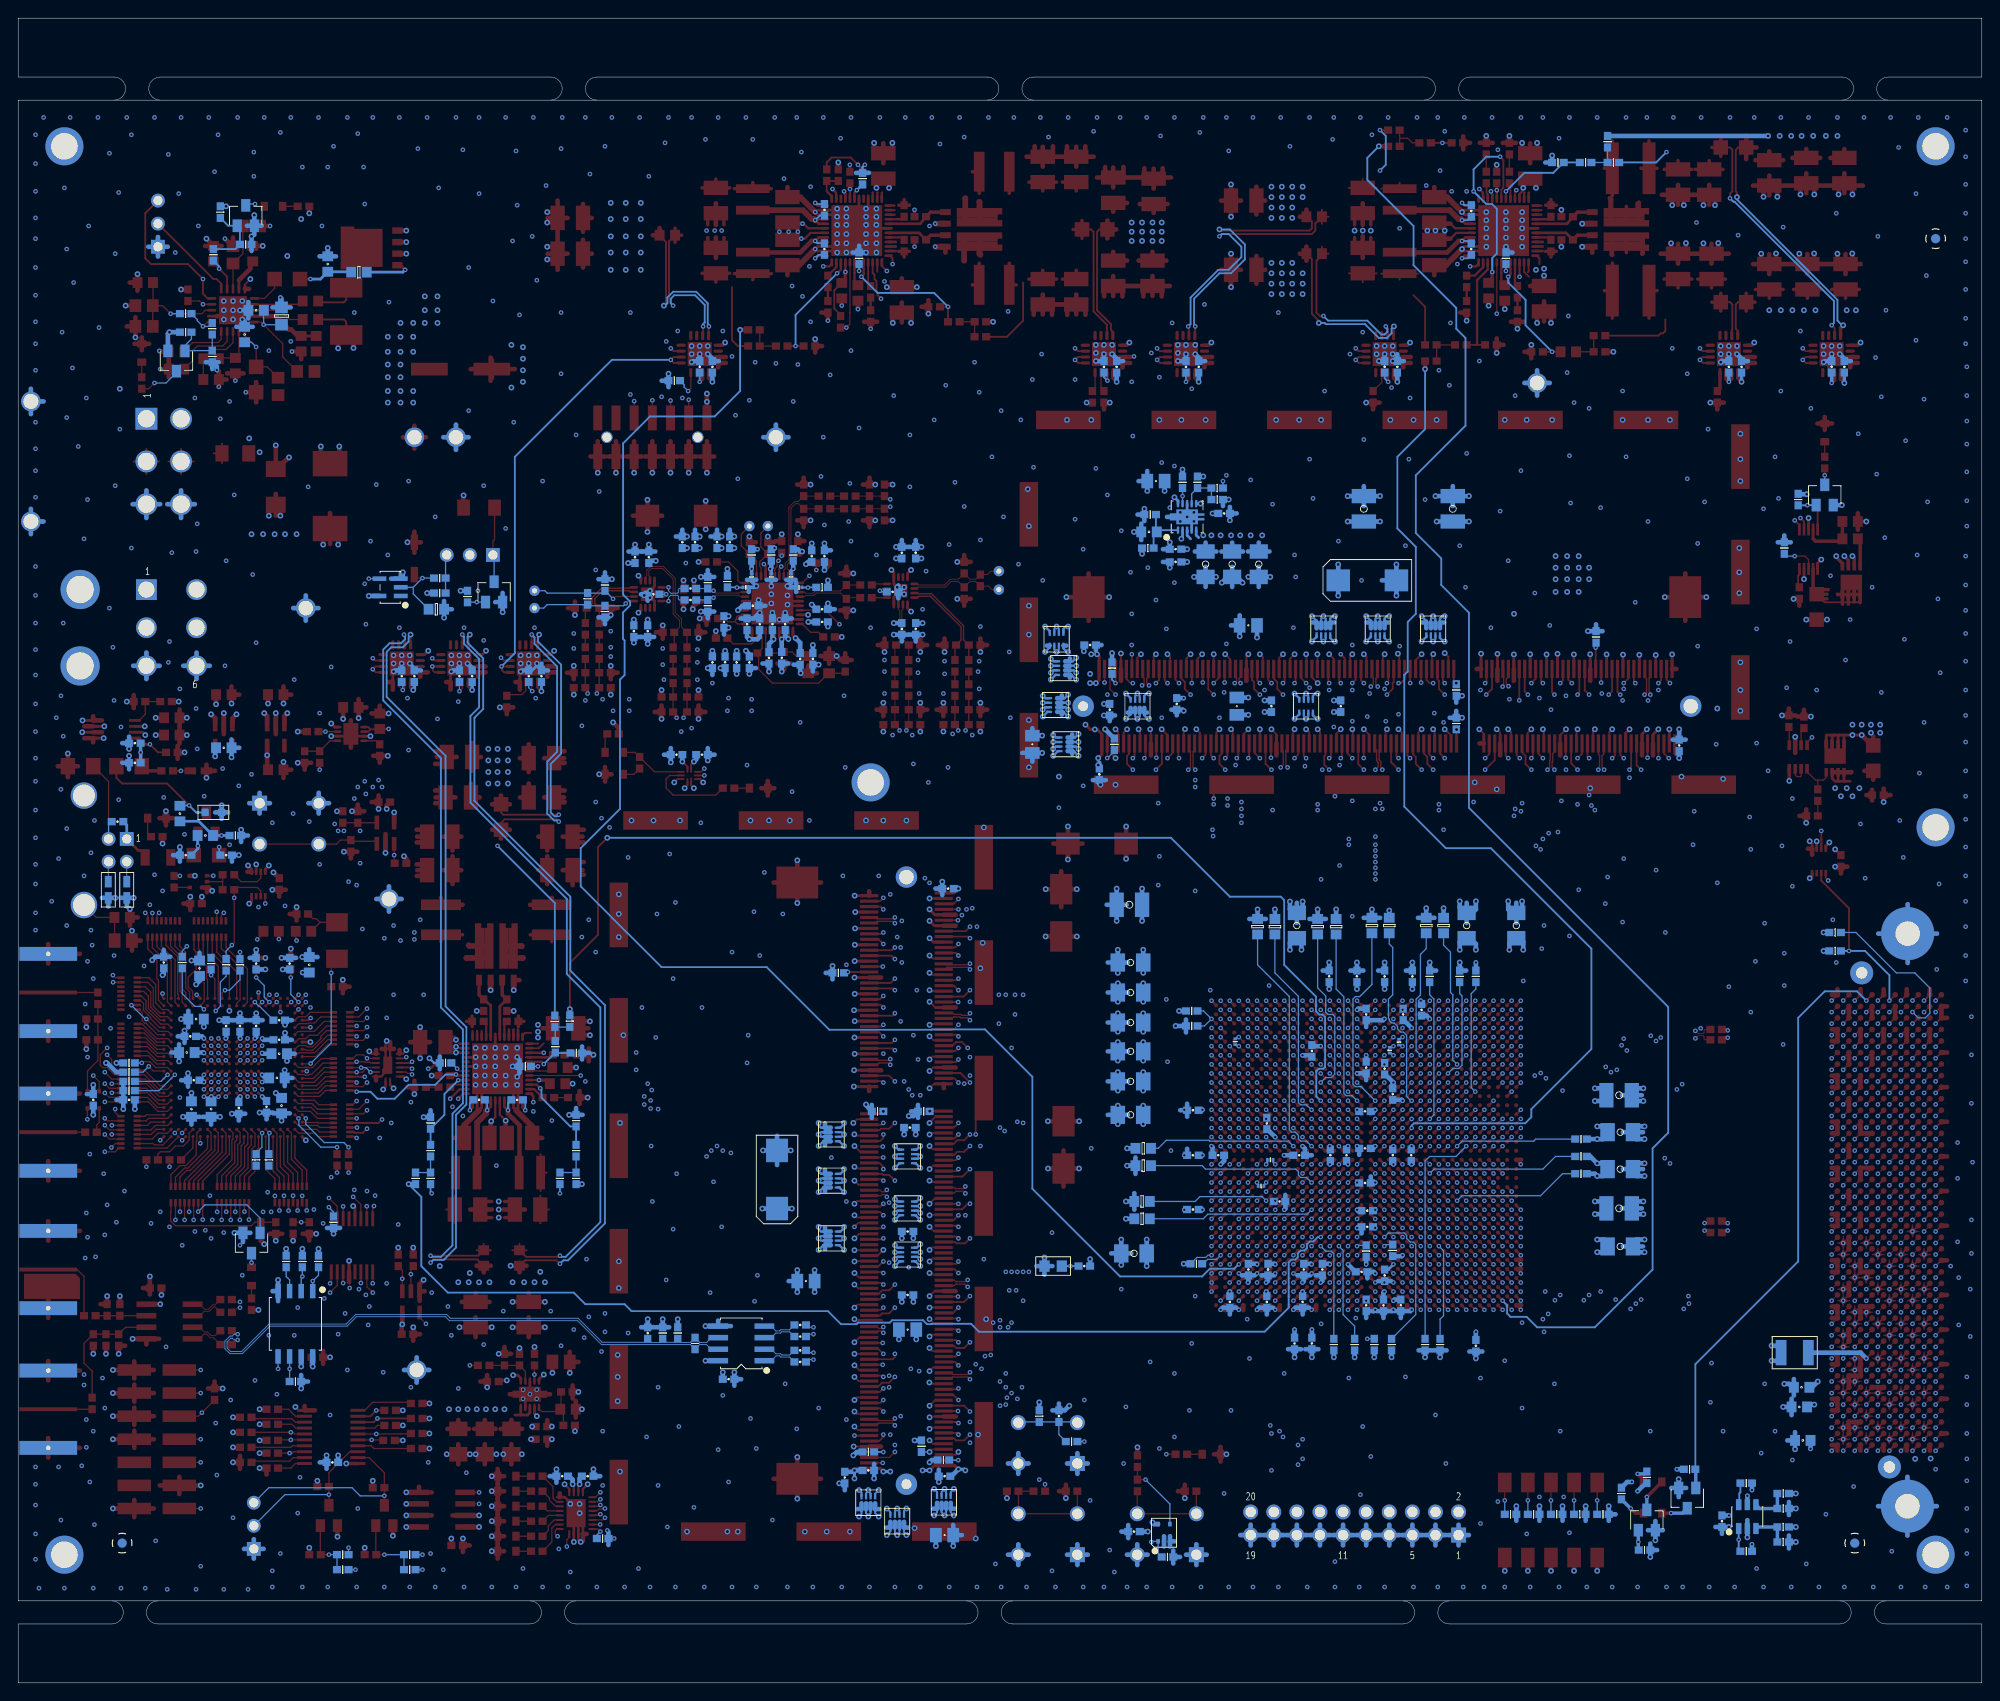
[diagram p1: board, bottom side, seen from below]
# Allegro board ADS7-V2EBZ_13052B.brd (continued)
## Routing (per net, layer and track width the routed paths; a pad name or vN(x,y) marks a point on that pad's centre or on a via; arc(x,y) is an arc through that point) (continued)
FMC-1_DP2_M2C_N: length 54.5
  TOP w0.102: P1.A7 v1(16.51,67.44)
  TOP w0.14: v1(53.69,45.04) U31.D5
  L9_SIGNAL w0.089: v1(16.51,67.44) 16.51,67.86 16.6,67.95 31.64,67.95 36.6,62.99 39.26,62.99 41.53,60.73 41.53,50.95 47.09,45.39 53.21,45.39 53.23,45.41 53.32,45.41 v1(53.69,45.04)
FMC-1_DP2_M2C_P: length 54.5
  TOP w0.102: P1.A6 v1(16.51,68.71)
  TOP w0.14: v1(53.69,46.04) U31.D6
  L9_SIGNAL w0.089: v1(53.69,46.04) 53.32,45.67 53.12,45.67 53.1,45.64 47.19,45.64 41.78,51.05 41.78,60.83 39.37,63.25 36.7,63.25 31.75,68.2 16.6,68.2 16.51,68.29 v1(16.51,68.71)
FMC-1_DP3_C2M_N: length 42.6
  TOP w0.102: 15.88,37.59 v1(16.51,36.96)
  TOP w0.14: v1(50.69,43.04) U31.A3
  L20_SIGNAL w0.089: v1(16.51,36.96) 17.02,37.47 17.89,37.47 19.28,36.07 46.99,36.07 49.15,38.23 49.15,43.05 49.53,43.43 50.3,43.43 v1(50.69,43.04)
FMC-1_DP3_C2M_P: length 42.6
  TOP w0.102: 15.88,38.86 v1(16.51,38.23)
  TOP w0.14: v1(50.69,44.04) U31.A4
  L20_SIGNAL w0.089: v1(50.69,44.04) 50.34,43.69 49.42,43.69 48.9,43.16 48.9,38.33 46.88,36.32 19.39,36.32 17.99,37.72 17.02,37.72 v1(16.51,38.23)
FMC-1_DP3_M2C_N: length 45.6
  TOP w0.102: P1.A11 v1(16.51,62.36)
  TOP w0.14: v1(51.69,45.04) U31.B5
  L5_SIGNAL w0.089: v1(51.69,45.04) 51.32,45.41 51.23,45.41 51.21,45.39 50.26,45.39 49.55,46.1 36.09,46.1 29.36,52.83 26.42,52.83 24.87,54.38 23.4,55.84 19.3,59.95 19.3,61.95 18.33,62.93 17.08,62.93 v1(16.51,62.36)
FMC-1_DP3_M2C_P: length 45.6
  TOP w0.102: P1.A10 v1(16.51,63.63)
  TOP w0.14: v1(51.69,46.04) U31.B6
  L5_SIGNAL w0.089: v1(51.69,46.04) 51.32,45.67 51.12,45.67 51.1,45.64 50.37,45.64 49.66,46.36 36.2,46.36 29.46,53.09 26.52,53.09 25.05,54.56 23.58,56.02 19.56,60.06 19.56,62.06 18.44,63.18 16.95,63.18 v1(16.51,63.63)
FMC-1_DP4_C2M_N: length 51.1
  TOP w0.102: 15.88,32.51 v1(16.51,31.88)
  TOP w0.14: v1(61.69,41.04) U31.M1
  L18_SIGNAL w0.089: v1(16.51,31.88) 17.02,32.39 20.04,32.39 21.82,34.16 48.49,34.16 53.57,39.24 58.75,39.24 60.34,40.84 60.34,41.18 60.55,41.39 61.21,41.39 61.23,41.41 61.32,41.41 v1(61.69,41.04)
FMC-1_DP4_C2M_P: length 51.1
  TOP w0.102: 15.88,33.78 v1(16.51,33.15)
  TOP w0.14: v1(61.69,42.04) U31.M2
  L18_SIGNAL w0.089: v1(16.51,33.15) 17.02,32.64 19.94,32.64 21.72,34.42 48.39,34.42 53.47,39.5 58.64,39.5 60.09,40.94 60.09,41.29 60.44,41.64 61.1,41.64 61.12,41.67 61.32,41.67 v1(61.69,42.04)
FMC-1_DP4_M2C_N: length 72.2
  TOP w0.102: P1.A15 v1(16.51,57.28)
  TOP w0.14: v1(62.69,43.04) U31.N3
  L7_SIGNAL w0.089: v1(16.51,57.28) 16.51,57.7 16.42,57.78 14.96,57.78 14.73,57.55 14.73,52.05 15.09,51.69 19.3,51.69 19.81,51.18 19.81,41.15 20.32,40.64 46.5,40.64 48.54,42.67 63.82,42.67 64.04,42.89 64.04,43.18 63.81,43.41 63.06,43.41 v1(62.69,43.04)
FMC-1_DP4_M2C_P: length 73.9
  TOP w0.102: P1.A14 v1(16.51,58.55)
  TOP w0.14: v1(62.69,44.04) U31.N4
  L7_SIGNAL w0.089: v1(62.69,44.04) 63.06,43.67 63.92,43.67 64.29,43.29 64.29,42.79 63.92,42.42 48.64,42.42 46.61,40.39 20.21,40.39 19.56,41.04 19.56,51.08 19.2,51.44 14.99,51.44 14.48,51.94 14.48,57.66 14.86,58.04 16.42,58.04 16.51,58.13 v1(16.51,58.55)
FMC-1_DP5_C2M_N: length 55.5
  TOP w0.102: 15.88,27.43 v1(16.51,26.8)
  TOP w0.14: v1(59.69,41.04) U31.K1
  L20_SIGNAL w0.089: v1(16.51,26.8) 17.02,27.3 17.5,27.3 18.52,28.32 53.21,28.32 57.28,32.39 57.28,38.73 58.29,39.75 58.29,41.15 58.55,41.4 59.22,41.4 59.23,41.41 59.32,41.41 v1(59.69,41.04)
FMC-1_DP5_C2M_P: length 55.5
  TOP w0.102: 15.88,28.7 v1(16.51,28.07)
  TOP w0.14: v1(59.69,42.04) U31.K2
  L20_SIGNAL w0.089: v1(16.51,28.07) 17.02,27.56 17.4,27.56 18.41,28.57 53.11,28.57 57.02,32.49 57.02,38.84 58.04,39.86 58.04,41.25 58.44,41.66 59.11,41.66 59.12,41.67 59.32,41.67 v1(59.69,42.04)
FMC-1_DP5_M2C_N: length 55
  TOP w0.102: 15.88,52.83 v1(16.51,52.2)
  TOP w0.14: v1(60.69,43.04) U31.L3
  L7_SIGNAL w0.089: v1(16.51,52.2) 16.51,52.58 16.64,52.7 20.57,52.7 21.08,52.2 21.08,44.09 21.74,43.43 60.3,43.43 v1(60.69,43.04)
FMC-1_DP5_M2C_P: length 54.9
  TOP w0.102: P1.A18 v1(16.51,53.47)
  TOP w0.14: v1(60.69,44.04) U31.L4
  L7_SIGNAL w0.089: v1(60.69,44.04) 60.34,43.69 21.84,43.69 21.34,44.2 21.34,52.3 20.68,52.96 16.73,52.96 16.64,53.05 16.64,53.34 v1(16.51,53.47)
FMC-1_DP6_C2M_N: length 51
  TOP w0.102: P1.B37 v1(15.24,29.34)
  TOP w0.14: v1(57.69,41.04) U31.H1
  L20_SIGNAL w0.089: v1(57.69,41.04) 57.32,41.41 57.23,41.41 57.21,41.39 56.55,41.39 56.34,41.18 56.34,38.18 49.66,31.5 18.52,31.5 16.87,29.85 15.75,29.85 v1(15.24,29.34)
FMC-1_DP6_C2M_P: length 51
  TOP w0.102: P1.B36 v1(15.24,30.61)
  TOP w0.14: v1(57.69,42.04) U31.H2
  L20_SIGNAL w0.089: v1(57.69,42.04) 57.32,41.67 57.12,41.67 57.1,41.64 56.44,41.64 56.09,41.29 56.09,38.29 49.55,31.75 18.41,31.75 16.76,30.1 15.75,30.1 v1(15.24,30.61)
FMC-1_DP6_M2C_N: length 57.1
  TOP w0.102: P1.B17 v1(15.24,54.74)
  TOP w0.14: v1(59.69,45.04) U31.K5
  L7_SIGNAL w0.089: v1(15.24,54.74) 15.75,55.25 17.17,55.25 17.27,55.14 17.27,54 17.67,53.59 22.1,53.59 22.35,53.34 22.35,45.09 23.01,44.44 57.94,44.44 58.29,44.79 58.29,45.23 58.47,45.41 59.32,45.41 v1(59.69,45.04)
FMC-1_DP6_M2C_P: length 57.4
  TOP w0.102: P1.B16 v1(15.24,56.01)
  TOP w0.14: v1(59.69,46.04) U31.K6
  L7_SIGNAL w0.089: v1(59.69,46.04) 59.32,45.67 58.37,45.67 58.04,45.34 58.04,44.89 57.84,44.69 23.11,44.69 22.61,45.2 22.61,53.45 22.2,53.85 17.78,53.85 17.53,54.1 17.53,55.25 17.27,55.5 15.64,55.5 15.5,55.36 15.37,55.5 15.33,55.5 15.24,55.59 v1(15.24,56.01)
FMC-1_DP7_C2M_N: length 46.6
  TOP w0.102: P1.B33 v1(15.24,34.42)
  TOP w0.14: v1(55.69,41.04) U31.F1
  L20_SIGNAL w0.089: v1(15.24,34.42) 15.75,34.92 17.63,34.92 18.65,33.91 48.13,33.91 54.34,40.12 54.34,41.18 54.55,41.39 54.6,41.39 54.61,41.4 55.22,41.4 55.23,41.41 55.32,41.41 v1(55.69,41.04)
FMC-1_DP7_C2M_P: length 46.6
  TOP w0.102: P1.B32 v1(15.24,35.69)
  TOP w0.14: v1(55.69,42.04) U31.F2
  L20_SIGNAL w0.089: v1(55.69,42.04) 55.32,41.67 55.12,41.67 55.11,41.66 54.6,41.66 54.45,41.66 54.09,41.29 54.09,40.22 48.03,34.16 18.75,34.16 17.74,35.18 15.75,35.18 v1(15.24,35.69)
FMC-1_DP7_M2C_N: length 52.7
  TOP w0.102: 14.61,60.45 v1(15.24,59.82)
  TOP w0.14: v1(58.69,43.04) U31.J3
  L5_SIGNAL w0.089: v1(15.24,59.82) 15.75,60.32 15.82,60.32 15.88,60.39 16.7,60.39 25.91,51.18 28.09,51.18 34.88,44.39 52.84,44.39 53.04,44.18 53.04,43.84 53.44,43.44 58.1,43.44 58.12,43.41 58.32,43.41 v1(58.69,43.04)
FMC-1_DP7_M2C_P: length 52.6
  TOP w0.102: 14.61,61.72 v1(15.24,61.09)
  TOP w0.14: v1(58.69,44.04) U31.J4
  L5_SIGNAL w0.089: v1(58.69,44.04) 58.32,43.67 58.23,43.67 58.21,43.69 53.55,43.69 53.29,43.94 53.29,44.29 52.94,44.64 34.99,44.64 28.19,51.44 26.01,51.44 16.81,60.64 15.68,60.64 v1(15.24,61.09)
FMC-1_DP8_C2M_N: length 89.4
  TOP w0.102: 14.61,40.13 v1(15.24,39.5) ; v1(70.69,41.04) U31.Y1
  L20_SIGNAL w0.089: v1(70.69,41.04) 71.04,41.39 71.92,41.39 72.14,41.17 72.14,40.26 57.4,25.53 34.57,25.53 33.04,24 13.34,24 12.32,25.02 12.32,39.77 12.55,40 15.15,40 15.24,39.92 v1(15.24,39.5)
FMC-1_DP8_C2M_P: length 91.1
  TOP w0.102: P1.B28 v1(15.24,40.77)
  TOP w0.14: v1(70.69,42.04) U31.Y2
  L20_SIGNAL w0.089: v1(70.69,42.04) 71.09,41.64 72.02,41.64 72.39,41.28 72.39,40.15 57.51,25.27 34.67,25.27 33.15,23.75 13.23,23.75 12.07,24.91 12.07,39.88 12.45,40.26 15.15,40.26 15.24,40.35 v1(15.24,40.77)
FMC-1_DP8_M2C_N: length 69.4
  TOP w0.102: 14.61,65.53 v1(15.24,64.9) ; v1(71.69,43.04) U31.AA3
  L5_SIGNAL w0.089: v1(15.24,64.9) 15.75,65.41 18.56,65.41 35.96,48.01 48.64,48.01 50.26,46.39 58.84,46.39 59.09,46.14 59.09,45.79 59.44,45.44 59.79,45.44 60.09,45.14 60.09,44.79 60.44,44.44 60.79,44.44 61.09,44.14 61.09,43.79 61.44,43.44 61.79,43.44 62.09,43.14 62.09,42.79 62.46,42.42 69.92,42.42 70.34,42.84 70.34,43.18 70.59,43.44 71.29,43.44 71.46,43.27 v1(71.69,43.04)
FMC-1_DP8_M2C_P: length 69.4
  TOP w0.102: v1(71.69,44.04) U31.AA4 ; 14.61,66.8 v1(15.24,66.17)
  L5_SIGNAL w0.089: v1(15.24,66.17) 15.75,65.66 18.67,65.66 36.07,48.26 48.75,48.26 50.36,46.64 58.94,46.64 59.34,46.24 59.34,45.89 59.55,45.69 59.89,45.69 59.94,45.64 60.34,45.24 60.34,44.89 60.55,44.69 60.89,44.69 60.94,44.64 61.34,44.24 61.34,43.89 61.55,43.69 61.89,43.69 61.94,43.64 62.34,43.24 62.34,42.89 62.56,42.67 69.82,42.67 70.09,42.94 70.09,43.29 70.49,43.69 71.34,43.69 v1(71.69,44.04)
FMC-1_DP9_C2M_N: length 90.6
  TOP w0.102: v1(68.69,41.04) U31.V1 ; P1.B25 v1(15.24,44.58)
  L20_SIGNAL w0.089: v1(68.69,41.04) 68.33,41.4 68.03,41.4 67.95,41.31 67.95,39.52 54.97,26.54 20.68,26.54 19.03,24.89 13.48,24.89 13.21,25.17 13.21,38.59 13.61,38.99 16.76,38.99 17.27,39.5 17.27,44.58 16.76,45.08 15.75,45.08 v1(15.24,44.58)
FMC-1_DP9_C2M_P: length 90.6
  TOP w0.102: P1.B24 v1(15.24,45.85)
  TOP w0.14: v1(68.69,42.04) U31.V2
  L20_SIGNAL w0.089: v1(68.69,42.04) 68.31,41.66 67.93,41.66 67.69,41.42 67.69,39.62 54.86,26.8 20.57,26.8 18.92,25.15 13.59,25.15 13.46,25.27 13.46,38.48 13.72,38.73 16.87,38.73 17.53,39.39 17.53,44.68 16.87,45.34 15.75,45.34 v1(15.24,45.85)
FMC-1_DP9_M2C_N: length 69.7
  TOP w0.102: 14.61,70.61 v1(15.24,69.98) ; v1(69.69,43.04) U31.W3
  L5_SIGNAL w0.089: v1(15.24,69.98) 15.75,70.48 17.67,70.48 20.45,67.71 20.45,65.64 36.68,49.4 49.15,49.4 50.16,48.39 59.84,48.39 60.07,48.15 60.07,47.75 60.39,47.44 64.2,47.44 66.04,45.59 66.04,44.83 66.48,44.39 66.84,44.39 67.04,44.18 67.04,43.83 67.44,43.43 69.3,43.43 v1(69.69,43.04)
FMC-1_DP9_M2C_P: length 69.7
  TOP w0.102: v1(69.69,44.04) U31.W4 ; 14.61,71.88 v1(15.24,71.25)
  L5_SIGNAL w0.089: v1(15.24,71.25) 15.75,70.74 17.78,70.74 20.7,67.82 20.7,65.74 36.79,49.66 49.25,49.66 50.27,48.64 59.94,48.64 60.33,48.26 60.33,47.86 60.49,47.69 64.3,47.69 66.29,45.7 66.29,44.94 66.59,44.64 66.94,44.64 67.29,44.29 67.29,43.94 67.54,43.69 69.34,43.69 v1(69.69,44.04)
FMC-1_GBTCLK0_M2C_C_N: length 57.8
  TOP w0.102: C107.2 30.44,71.88 30.54,71.78 30.54,71.53 30.64,71.42 31.2,71.42 v1(31.5,71.72)
  TOP w0.14: v1(61.69,45.04) U31.M5
  L7_SIGNAL w0.089: v1(61.69,45.04) 62.12,45.47 62.41,45.47 62.44,45.44 62.94,45.44 63.29,45.79 63.29,48.29 62.94,48.64 62.59,48.64 62.29,48.94 62.29,49.29 61.94,49.64 61.59,49.64 61.29,49.94 61.29,50.29 60.94,50.64 60.59,50.64 60.29,50.94 60.29,51.29 59.94,51.64 59.59,51.64 59.29,51.94 59.29,59.29 58.94,59.64 48.41,59.64 47.62,60.43 47.62,61.98 47.12,62.48 44.32,62.48 43.82,62.99 43.82,64.24 43.16,64.9 38.61,64.9 38.1,65.41 38.1,67.82 37.59,68.33 35.41,68.33 34.8,68.94 34.8,70.78 34.14,71.44 31.78,71.44 v1(31.5,71.72)
FMC-1_GBTCLK0_M2C_C_P: length 56.9
  TOP w0.102: C108.2 30.44,70.74 30.54,70.84 30.54,71.09 30.64,71.2 31.2,71.2 v1(31.5,70.9)
  TOP w0.14: v1(61.69,46.04) U31.M6
  L7_SIGNAL w0.089: v1(31.5,70.9) 31.78,71.18 34.04,71.18 34.54,70.68 34.54,68.83 35.31,68.07 37.49,68.07 37.85,67.71 37.85,65.3 38.5,64.64 43.05,64.64 43.56,64.14 43.56,62.89 44.22,62.23 47.01,62.23 47.37,61.87 47.37,60.33 48.31,59.39 58.84,59.39 59.04,59.18 59.04,51.84 59.49,51.39 59.84,51.39 60.04,51.18 60.04,50.84 60.49,50.39 60.84,50.39 61.04,50.18 61.04,49.84 61.49,49.39 61.84,49.39 62.04,49.18 62.04,48.84 62.49,48.39 62.84,48.39 63.04,48.18 63.04,45.89 62.84,45.69 62.55,45.69 62.52,45.72 62.01,45.72 v1(61.69,46.04)
FMC-1_GBTCLK0_M2C_N: length 22.5
  TOP w0.102: C107.1 28.47,71.78 v1(27.94,71.78) ; 12.07,70.61 v1(12.7,69.98)
  L18_SIGNAL w0.089: v1(12.7,69.98) 12.19,70.48 11.05,70.48 10.67,70.87 10.67,71.63 11.05,72.01 25.12,72.01 25.63,71.5 27.66,71.5 v1(27.94,71.78)
FMC-1_GBTCLK0_M2C_P: length 21.7
  TOP w0.102: C108.1 28.35,70.97 v1(27.94,70.97) ; 12.07,71.88 v1(12.7,71.25)
  L18_SIGNAL w0.089: v1(27.94,70.97) 27.66,71.25 25.53,71.25 25.02,71.76 11.15,71.76 10.92,71.52 10.92,70.97 11.15,70.74 12.19,70.74 v1(12.7,71.25)
FMC-1_GBTCLK1_M2C_C_N: length 28.9
  TOP w0.102: v1(30.48,49.75) 30.07,49.75 C124.2
  TOP w0.14: v1(55.69,45.04) U31.F5
  L7_SIGNAL w0.089: v1(55.69,45.04) 55.32,45.41 55.23,45.41 55.21,45.39 36.93,45.39 32.28,50.04 30.77,50.04 v1(30.48,49.75)
FMC-1_GBTCLK1_M2C_C_P: length 28.9
  TOP w0.102: C121.2 30.07,50.58 v1(30.48,50.58)
  TOP w0.14: v1(55.69,46.04) U31.F6
  L7_SIGNAL w0.089: v1(55.69,46.04) 55.32,45.67 55.12,45.67 55.1,45.64 37.03,45.64 32.38,50.29 30.77,50.29 v1(30.48,50.58)
FMC-1_GBTCLK1_M2C_N: length 14.9
  TOP w0.102: C124.1 28.35,49.76 v1(27.94,49.76) ; P1.B21 v1(15.24,49.66)
  L18_SIGNAL w0.089: v1(15.24,49.66) 15.24,49.91 15.49,50.17 27.57,50.17 27.66,50.08 27.66,50.04 v1(27.94,49.76)
FMC-1_GBTCLK1_M2C_P: length 14.8
  TOP w0.102: P1.B20 v1(15.24,50.93) ; C121.1 28.35,50.57 v1(27.94,50.57)
  L18_SIGNAL w0.089: v1(27.94,50.57) 27.79,50.42 15.49,50.42 15.24,50.67 v1(15.24,50.93)
FMC-1_HA00_N_CC: length 96
  TOP w0.102: v1(55.69,50.04) U31.F10 ; 9.53,70.61 v1(10.16,69.98)
  L9_SIGNAL w0.089: v1(55.69,50.04) 56.34,50.69 56.34,63.48 56.34,63.48 56.34,63.8 55.5,64.64 52.94,64.64 52.83,64.64 52.29,65.18 52.29,65.29 51.94,65.64 51.83,65.64 51.79,65.69 51.55,65.69 51.34,65.89 51.34,66.13 51.29,66.18 51.29,66.29 50.94,66.64 50.83,66.64 50.79,66.69 50.55,66.69 50.19,67.04 49.78,67.04 47.2,69.62 47.2,75.8 47.2,80.56 46.48,81.28 30.61,81.28 30.1,81.79 30.1,83.82 29.59,84.33 20.19,84.33 19.68,83.82 19.68,81.64 19.33,81.28 12.95,81.28 9.53,77.85 7.21,77.85 6.83,77.47 6.83,71.17 7,71 7,70.99 7.5,70.48 10.03,70.48 10.16,70.36 v1(10.16,69.98)
FMC-1_HA00_P_CC: length 95
  TOP w0.102: 9.53,71.88 v1(10.16,71.25) ; v1(55.69,51.04) U31.F11
  L9_SIGNAL w0.089: v1(10.16,71.25) 10.16,70.87 10.03,70.74 7.61,70.74 7.25,71.09 7.25,71.11 7.09,71.27 7.09,77.36 7.32,77.6 9.63,77.6 13.06,81.03 19.43,81.03 19.94,81.53 19.94,83.71 20.3,84.07 29.49,84.07 29.84,83.71 29.84,81.68 30.5,81.03 46.38,81.03 46.95,80.45 46.95,75.9 46.95,69.51 49.67,66.79 50.09,66.79 50.44,66.44 50.68,66.44 50.73,66.39 50.84,66.39 51.04,66.18 51.04,66.08 51.09,66.03 51.09,66 51.09,65.79 51.44,65.44 51.68,65.44 51.73,65.39 51.84,65.39 52.04,65.18 52.04,65.08 52.73,64.39 53.04,64.39 55.39,64.39 56.09,63.69 56.09,63.59 56.09,50.8 55.8,50.5 55.54,50.5 55.48,50.57 55.48,50.83 v1(55.69,51.04)
FMC-1_HA01_N_CC: length 92.8
  TOP w0.102: v1(53.69,51.04) U31.D11 ; P1.E3 v1(11.43,72.52)
  L9_SIGNAL w0.089: v1(11.43,72.52) 11.43,72.9 11.56,73.03 11.81,73.03 11.94,72.9 11.94,72.14 11.81,72.01 8.6,72.01 8.24,72.36 8.24,75.17 9.4,76.33 20.7,76.33 21.21,76.84 21.21,82.3 21.72,82.8 28.34,82.8 28.7,82.44 28.7,80.16 29.1,79.76 45.88,79.76 45.98,79.65 45.98,67.45 50.06,63.37 50.53,63.37 50.55,63.39 53.84,63.39 53.85,63.37 54.53,63.37 54.55,63.39 54.84,63.39 55.04,63.18 55.04,52.89 54.84,52.69 54.49,52.69 54.09,52.29 54.09,51.63 54.06,51.61 54.06,51.41 v1(53.69,51.04)
FMC-1_HA01_P_CC: length 94.9
  TOP w0.102: P1.E2 v1(11.43,73.79) ; v1(54.69,51.04) U31.E11
  L9_SIGNAL w0.089: v1(54.69,51.04) 54.32,51.41 54.32,51.5 54.34,51.52 54.34,52.18 54.59,52.44 54.94,52.44 55.29,52.79 55.29,63.29 54.94,63.64 54.44,63.64 54.43,63.63 53.96,63.63 53.94,63.64 50.44,63.64 50.43,63.63 50.16,63.63 46.24,67.55 46.24,79.76 45.98,80.01 29.21,80.01 28.96,80.26 28.96,82.55 28.45,83.06 21.61,83.06 20.95,82.4 20.95,76.94 20.6,76.58 9.29,76.58 7.99,75.28 7.99,72.26 8.49,71.76 11.92,71.76 12.19,72.03 12.19,73 11.92,73.28 11.56,73.28 11.43,73.41 v1(11.43,73.79)
FMC-1_HA02_N: length 92.3
  TOP w0.102: 4.45,66.8 v1(5.08,66.17) ; v1(50.69,48.04) U31.A8
  L20_SIGNAL w0.089: v1(5.08,66.17) 5.21,66.29 5.21,66.59 5.3,66.67 7.77,66.67 8.13,66.32 8.13,64.75 7.77,64.39 3.68,64.39 3.17,63.88 3.17,49.4 3.68,48.89 19.2,48.89 19.94,48.15 19.94,39.62 20.45,39.12 44.2,39.12 44.7,39.62 44.7,48.05 45.06,48.41 50.32,48.41 v1(50.69,48.04)
FMC-1_HA02_P: length 92.3
  TOP w0.102: 4.45,68.07 v1(5.08,67.44) ; v1(50.69,49.04) U31.A9
  L20_SIGNAL w0.089: v1(5.08,67.44) 5.08,67.06 5.21,66.93 7.87,66.93 8.38,66.42 8.38,64.64 7.87,64.14 3.79,64.14 3.43,63.78 3.43,49.51 3.79,49.15 19.3,49.15 20.19,48.26 20.19,39.73 20.55,39.37 44.09,39.37 44.45,39.73 44.45,48.16 44.96,48.67 50.32,48.67 v1(50.69,49.04)
FMC-1_HA03_N: length 97.6
  TOP w0.102: v1(50.69,50.04) U31.A10 ; P1.J7 v1(6.35,67.44)
  L5_SIGNAL w0.089: v1(34.28,57.14) 34.28,57.54 29.34,62.48 28.09,62.48 27.69,62.89 27.69,63.35 28.09,63.75 29.99,63.75 30.1,63.86 30.1,64.54 29.99,64.64 27.07,64.64 26.92,64.79 26.92,66.15 27.07,66.29 30.88,66.29 30.99,66.4 30.99,67.33 30.88,67.44 27.33,67.44 26.92,67.84 26.92,69.09 27.18,69.34 30.73,69.34 30.99,69.6 30.99,70.13 30.88,70.23 27.33,70.23 26.92,70.63 26.92,72.75 27.33,73.15 29.99,73.15 30.1,73.26 30.1,74.19 29.99,74.3 11.15,74.3 10.92,74.06 10.92,68.22 10.65,67.95 6.44,67.95 6.35,67.86 v1(6.35,67.44)
  L7_SIGNAL w0.089: v1(50.69,50.04) 50.32,50.41 47.12,50.41 46.61,50.92 46.61,54.23 46.1,54.74 35.96,54.74 35.31,55.39 35.31,56.52 34.67,57.15 34.29,57.15 v1(34.28,57.14)
FMC-1_HA03_P: length 97.6
  TOP w0.102: P1.J6 v1(6.35,68.71) ; v1(50.69,51.04) U31.A11
  L5_SIGNAL w0.089: v1(34.86,57.72) 34.46,57.72 29.44,62.74 28.19,62.74 27.94,62.99 27.94,63.25 28.19,63.5 30.1,63.5 30.35,63.75 30.35,64.64 30.1,64.9 27.18,64.9 27.18,66.04 30.99,66.04 31.24,66.29 31.24,67.44 30.99,67.69 27.43,67.69 27.18,67.95 27.18,68.98 27.28,69.09 30.84,69.09 31.24,69.49 31.24,70.23 30.99,70.48 27.43,70.48 27.18,70.74 27.18,72.64 27.43,72.9 30.1,72.9 30.35,73.15 30.35,74.3 30.1,74.55 11.05,74.55 10.67,74.17 10.67,68.33 10.54,68.2 6.44,68.2 6.35,68.29 v1(6.35,68.71)
  L7_SIGNAL w0.089: v1(50.69,51.04) 50.32,50.67 47.22,50.67 46.86,51.03 46.86,54.33 46.21,54.99 36.07,54.99 35.56,55.5 35.56,56.62 34.85,57.33 34.86,57.34 v1(34.86,57.72)
FMC-1_HA04_N: length 95.2
  TOP w0.102: v1(51.69,48.04) U31.B8 ; 9.53,66.8 v1(10.16,66.17)
  L7_SIGNAL w0.089: v1(51.69,48.04) 51.98,48.04 52.18,48.25 52.18,48.35 52.14,48.39 50.84,48.39 50.84,48.39 50.55,48.39 50.54,48.39 43.96,48.39 42.56,49.79 41.9,49.79 40.9,50.79 40.9,51.45 40.28,52.07 35.81,52.07 32.89,54.99 28.6,54.99 28.19,55.39 28.19,62.76 28.09,62.87 27.28,62.87 27.18,62.76 27.18,48.26 26.92,48.01 25.91,48.01 25.65,48.26 25.65,62.23 25.4,62.48 22.73,62.48 22.48,62.23 22.48,58.93 22.22,58.67 20.21,58.67 19.81,59.08 19.81,61.09 19.56,61.34 17.78,61.34 17.53,61.59 17.53,66.44 17.17,66.8 10.41,66.8 10.16,66.55 v1(10.16,66.17)
FMC-1_HA04_P: length 94.9
  TOP w0.102: 9.53,68.07 v1(10.16,67.44) ; v1(52.69,49.04) U31.C9
  L7_SIGNAL w0.089: v1(10.16,67.44) 10.54,67.06 17.27,67.06 17.78,66.55 17.78,61.7 17.89,61.59 19.66,61.59 20.07,61.19 20.07,59.18 20.32,58.93 22.12,58.93 22.22,59.03 22.22,62.34 22.63,62.74 25.51,62.74 25.91,62.34 25.91,48.37 26.01,48.26 26.82,48.26 26.92,48.37 26.92,62.87 27.18,63.12 28.19,63.12 28.45,62.87 28.45,55.5 28.7,55.25 33,55.25 35.92,52.32 40.39,52.32 41.16,51.55 41.16,50.89 42,50.05 42.66,50.05 44.07,48.64 47.9,48.64 47.9,48.64 50.94,48.64 50.94,48.64 52.29,48.64 v1(52.69,49.04)
FMC-1_HA05_N: length 98.8
  TOP w0.102: P1.E7 v1(11.43,67.44) ; v1(51.69,50.04) U31.B10
  L9_SIGNAL w0.089: v1(11.43,67.44) 11.43,67.86 11.52,67.95 12.93,67.95 13.46,68.47 13.46,73.94 13.82,74.3 42.57,74.3 42.93,73.94 42.93,73.53 42.67,73.28 34.29,73.28 34.04,73.03 34.04,71.94 34.44,71.53 42.95,71.53 43.05,71.43 43.05,69.19 42.57,68.71 38.59,68.71 38.48,68.81 38.48,70.34 38.08,70.74 37.08,70.74 36.83,70.49 36.83,68.73 39.52,66.04 40.39,66.04 40.64,65.79 40.64,65.02 41.15,64.52 42.82,64.52 46.48,60.85 46.48,53.74 49.81,50.42 51.12,50.42 51.12,50.41 51.32,50.41 v1(51.69,50.04)
FMC-1_HA05_P: length 98.8
  TOP w0.102: P1.E6 v1(11.43,68.71) ; v1(51.69,51.04) U31.B11
  L9_SIGNAL w0.089: v1(11.43,68.71) 11.43,68.29 11.52,68.2 12.83,68.2 13.21,68.58 13.21,74.04 13.72,74.55 42.67,74.55 43.18,74.04 43.18,73.64 43.18,73.43 42.78,73.03 34.4,73.03 34.29,72.92 34.29,72.04 34.54,71.79 43.05,71.79 43.31,71.53 43.31,69.09 42.67,68.45 38.48,68.45 38.23,68.71 38.23,70.23 37.97,70.49 37.19,70.49 37.08,70.38 37.08,68.83 39.62,66.29 40.49,66.29 40.89,65.89 40.89,65.13 41.25,64.77 42.93,64.77 46.74,60.96 46.74,53.85 49.91,50.67 51.22,50.67 51.23,50.67 51.32,50.67 v1(51.69,51.04)
FMC-1_HA06_N: length 98.6
  TOP w0.102: v1(52.69,48.04) U31.C8 ; 4.45,62.99 v1(5.08,62.36)
  L7_SIGNAL w0.089: v1(5.08,62.36) 5.08,62.74 4.95,62.87 4.47,62.87 4.06,63.27 4.06,67.54 4.72,68.2 18.39,68.2 18.8,67.8 18.8,62.59 18.9,62.48 21.1,62.48 21.21,62.59 21.21,63.8 21.61,64.2 24.91,64.2 25.02,64.3 25.02,66.27 25.42,66.67 29.21,66.67 29.46,66.42 29.46,65.55 29.06,65.15 26.39,65.15 26.29,65.05 26.29,64.52 26.54,64.26 31.37,64.26 31.62,64.01 31.62,59.94 31.88,59.69 34.67,59.69 34.92,59.44 34.92,58.55 34.67,58.29 29.57,58.29 29.46,58.19 29.46,56.77 29.72,56.52 33.38,56.52 36.05,53.85 42.78,53.85 46.98,49.64 54.08,49.64 54.34,49.38 54.34,48.79 53.94,48.39 53.55,48.39 53.54,48.39 53.04,48.39 v1(52.69,48.04)
FMC-1_HA06_P: length 96.9
  TOP w0.102: v1(53.69,49.04) U31.D9 ; 4.45,64.26 v1(5.08,63.63)
  L7_SIGNAL w0.089: v1(53.69,49.04) 53.34,49.04 53.25,48.95 53.25,48.73 53.34,48.64 53.44,48.64 53.44,48.64 53.84,48.64 54.09,48.89 54.09,49.28 53.98,49.39 46.88,49.39 42.67,53.59 35.94,53.59 33.27,56.26 29.61,56.26 29.21,56.66 29.21,58.29 29.46,58.55 34.57,58.55 34.67,58.65 34.67,59.33 34.57,59.44 31.77,59.44 31.37,59.84 31.37,63.9 31.26,64.01 26.44,64.01 26.04,64.41 26.04,65.15 26.29,65.41 28.96,65.41 29.21,65.66 29.21,66.32 29.1,66.42 25.53,66.42 25.27,66.17 25.27,64.2 25.02,63.94 21.72,63.94 21.46,63.69 21.46,62.48 21.21,62.23 18.8,62.23 18.54,62.48 18.54,67.69 18.29,67.95 4.83,67.95 4.32,67.44 4.32,63.37 4.57,63.12 4.95,63.12 5.08,63.25 v1(5.08,63.63)
FMC-1_HA07_N: length 94.8
  TOP w0.102: v1(51.69,52.04) U31.B12 ; P1.J10 v1(6.35,63.63)
  L5_SIGNAL w0.089: v1(51.69,52.04) 52.04,52.39 52.04,53.18 51.84,53.39 48.92,53.39 48.51,53.79 48.51,59.08 48.41,59.18 45.06,59.18 44.96,59.08 44.96,50.82 44.56,50.42 40.51,50.42 40.01,50.93 40.01,56.16 39.65,56.52 38.59,56.52 38.23,56.16 38.23,52.45 37.97,52.2 35.45,52.2 24.13,63.52 24.13,71.37 23.75,71.76 13.57,71.76 13.46,71.65 13.46,63.25 13.08,62.87 9.78,62.87 9.4,63.25 9.4,63.86 9.12,64.14 6.44,64.14 6.35,64.05 v1(6.35,63.63)
FMC-1_HA07_P: length 95.3
  TOP w0.102: v1(52.69,52.04) U31.C12 ; P1.J9 v1(6.35,64.9)
  L5_SIGNAL w0.089: v1(52.69,52.04) 52.29,52.44 52.29,53.29 51.94,53.64 49.02,53.64 48.77,53.9 48.77,59.18 48.51,59.44 44.96,59.44 44.7,59.18 44.7,50.93 44.45,50.67 40.62,50.67 40.26,51.03 40.26,56.26 39.75,56.77 38.48,56.77 37.97,56.26 37.97,52.56 37.87,52.45 35.56,52.45 24.38,63.63 24.38,71.48 23.85,72.01 13.46,72.01 13.21,71.76 13.21,63.35 12.98,63.12 9.88,63.12 9.65,63.35 9.65,63.96 9.23,64.39 6.44,64.39 6.35,64.48 v1(6.35,64.9)
FMC-1_HA08_N: length 98.5
  TOP w0.102: 9.53,62.99 v1(10.16,62.36) ; v1(54.69,48.04) U31.E8
  L7_SIGNAL w0.089: v1(10.16,62.36) 10.16,62.74 9.97,62.93 8.53,62.93 8.38,62.78 8.38,62.25 7.73,61.59 4.32,61.59 3.17,62.74 3.17,68.2 4.45,69.47 19.94,69.47 20.45,68.96 20.45,65.66 20.7,65.41 23.39,65.41 23.49,65.51 23.49,70.72 23.9,71.12 25.91,71.12 26.16,70.87 26.16,68.07 26.42,67.82 30.35,67.82 30.61,67.56 30.61,65.66 30.86,65.41 32.64,65.41 32.89,65.15 32.89,60.96 33.15,60.71 40.13,60.71 40.39,60.45 40.39,59.56 40.64,59.31 43.43,59.31 43.94,58.8 43.94,56.64 44.45,56.13 47.37,56.13 47.88,55.63 47.88,52 48.24,51.64 55.04,51.64 55.34,51.34 55.34,48.61 55.12,48.39 55.04,48.39 v1(54.69,48.04)
FMC-1_HA08_P: length 97
  TOP w0.102: v1(54.69,49.04) U31.E9 ; 9.53,64.26 v1(10.16,63.63)
  L7_SIGNAL w0.089: v1(54.69,49.04) 54.74,48.99 54.74,48.64 54.8,48.58 54.92,48.58 55.09,48.74 55.09,51.23 54.93,51.39 48.13,51.39 47.62,51.9 47.62,55.52 47.27,55.88 44.34,55.88 43.69,56.54 43.69,58.7 43.33,59.06 40.53,59.06 40.13,59.46 40.13,60.35 40.03,60.45 33.04,60.45 32.64,60.85 32.64,65.05 32.53,65.15 30.76,65.15 30.35,65.55 30.35,67.46 30.25,67.56 26.31,67.56 25.91,67.97 25.91,70.76 25.8,70.87 24,70.87 23.75,70.61 23.75,65.41 23.49,65.15 20.6,65.15 20.19,65.55 20.19,68.86 19.83,69.22 4.55,69.22 3.43,68.09 3.43,62.84 4.42,61.85 7.62,61.85 8.13,62.36 8.13,62.88 8.43,63.18 10.1,63.18 10.16,63.25 v1(10.16,63.63)
FMC-1_HA09_N: length 94.8
  TOP w0.102: P1.E10 v1(11.43,63.63) ; v1(53.69,52.04) U31.D12
  L5_SIGNAL w0.089: v1(11.43,63.63) 11.43,64.05 11.52,64.14 11.79,64.14 12.32,64.66 12.32,72.79 12.55,73.03 24.38,73.03 25.53,71.88 25.53,63.65 34.74,54.44 35.64,54.44 36.2,54.99 36.2,60.09 36.55,60.45 40.92,60.45 41.28,60.09 41.28,52.45 41.53,52.2 43.31,52.2 43.56,52.45 43.56,60.2 43.82,60.45 49.28,60.45 49.78,59.94 49.78,54.94 50.29,54.44 53.79,54.44 54.09,54.14 54.09,52.44 v1(53.69,52.04)
FMC-1_HA09_P: length 95.2
  TOP w0.102: P1.E9 v1(11.43,64.9) ; v1(54.69,52.04) U31.E12
  L5_SIGNAL w0.089: v1(11.43,64.9) 11.43,64.48 11.52,64.39 11.68,64.39 12.07,64.77 12.07,72.9 12.45,73.28 24.49,73.28 25.78,71.99 25.78,63.75 34.85,54.69 35.53,54.69 35.94,55.1 35.94,60.2 36.45,60.71 41.02,60.71 41.53,60.2 41.53,52.56 41.63,52.45 43.2,52.45 43.31,52.56 43.31,60.3 43.71,60.71 49.38,60.71 50.04,60.05 50.04,55.05 50.4,54.69 53.9,54.69 54.34,54.24 54.34,52.39 v1(54.69,52.04)
FMC-1_HA10_N: length 99.9
  TOP w0.102: 4.45,59.18 v1(5.08,58.55) ; v1(55.69,48.04) U31.F8
  L7_SIGNAL w0.089: v1(5.08,58.55) 5.08,58.93 4.95,59.06 4.34,59.06 2.16,61.24 2.16,68.18 4.72,70.74 17.78,70.74 17.78,71.12 18.29,71.63 21.06,71.63 21.46,71.23 21.46,67.18 21.72,66.93 22.1,66.93 22.35,67.18 22.35,71.88 22.61,72.14 26.65,72.14 27.05,71.73 27.05,68.81 27.16,68.71 31.22,68.71 31.62,68.3 31.62,66.65 31.73,66.55 34.42,66.55 34.67,66.29 34.67,62.87 34.92,62.61 40.87,62.61 41.28,62.21 41.28,60.81 41.38,60.71 44.58,60.71 45.09,60.2 45.09,57.66 45.59,57.15 49.91,57.15 50.42,56.64 50.42,52.69 55.9,52.69 56.34,52.24 56.34,48.59 56.13,48.39 56.04,48.39 v1(55.69,48.04)
FMC-1_HA10_P: length 98.4
  TOP w0.102: v1(55.69,49.04) U31.F9 ; 4.45,60.45 v1(5.08,59.82)
  L7_SIGNAL w0.089: v1(55.69,49.04) 55.75,48.98 55.75,48.73 55.84,48.64 56,48.64 56.09,48.73 56.09,52.14 55.79,52.44 50.31,52.44 50.16,52.58 50.16,56.54 49.81,56.9 45.49,56.9 44.83,57.55 44.83,60.09 44.47,60.45 41.28,60.45 41.02,60.71 41.02,62.1 40.77,62.36 34.82,62.36 34.42,62.76 34.42,66.19 34.31,66.29 31.62,66.29 31.37,66.55 31.37,68.2 31.11,68.45 27.05,68.45 26.8,68.71 26.8,71.63 26.54,71.88 22.71,71.88 22.61,71.78 22.61,67.08 22.2,66.67 21.61,66.67 21.21,67.08 21.21,71.12 20.95,71.37 18.39,71.37 18.03,71.01 18.03,70.63 17.89,70.48 4.83,70.48 2.41,68.07 2.41,61.34 4.45,59.31 4.95,59.31 5.08,59.44 v1(5.08,59.82)
FMC-1_HA11_N: length 91.8
  TOP w0.102: P1.J13 v1(6.35,59.82) ; v1(52.69,50.04) U31.C10
  L20_SIGNAL w0.089: v1(52.69,50.04) 53.09,50.43 53.09,51.18 52.83,51.44 49.91,51.44 48.77,50.29 44.07,50.29 43.56,49.78 43.56,43.81 42.55,42.8 42.55,40.77 42.04,40.26 34.16,40.26 33.66,40.77 33.66,47.01 33.3,47.37 31.98,47.37 31.62,47.01 31.62,40.77 31.11,40.26 21.84,40.26 21.34,40.77 21.34,49.81 20.98,50.17 7.75,50.17 7.59,50.32 7.37,50.32 6.86,50.84 6.86,60.2 6.73,60.33 6.48,60.33 6.35,60.2 v1(6.35,59.82)
FMC-1_HA11_P: length 92.2
  TOP w0.102: v1(53.69,50.04) U31.D10 ; P1.J12 v1(6.35,61.09)
  L20_SIGNAL w0.089: v1(6.35,61.09) 6.35,60.71 6.48,60.58 6.84,60.58 7.11,60.3 7.11,50.94 7.48,50.58 7.69,50.58 7.85,50.42 21.08,50.42 21.59,49.91 21.59,40.87 21.95,40.51 31.01,40.51 31.37,40.87 31.37,47.12 31.88,47.62 33.4,47.62 33.91,47.12 33.91,40.87 34.27,40.51 41.93,40.51 42.29,40.87 42.29,42.9 43.31,43.92 43.31,49.89 43.96,50.55 48.66,50.55 49.81,51.69 52.94,51.69 53.34,51.29 53.34,50.39 v1(53.69,50.04)
FMC-1_HA12_N: length 95.6
  TOP w0.102: 9.53,59.18 v1(10.16,58.55) ; v1(58.69,49.04) U31.J9
  L7_SIGNAL w0.089: v1(10.16,58.55) 10.16,58.93 10.42,59.19 10.56,59.06 17.04,59.06 17.4,58.7 17.4,57.17 18.06,56.52 18.44,56.52 18.54,56.41 18.54,54.89 18.94,54.48 19.41,54.48 19.81,54.89 19.81,56.41 19.92,56.52 20.72,56.52 20.83,56.41 20.83,54.89 21.23,54.48 21.97,54.48 22.22,54.74 22.22,56.26 22.48,56.52 22.86,56.52 23.37,56.01 23.37,46.1 23.88,45.59 34.27,45.59 34.67,46 34.67,46.59 34.27,46.99 29.82,46.99 29.72,47.1 29.72,47.65 29.82,47.75 32,47.75 32.26,48.01 32.26,48.62 31.86,49.02 29.95,49.02 29.84,49.13 29.84,51.75 30.35,52.26 31.81,52.26 34.67,49.4 37.47,49.4 40.43,46.44 58.12,46.44 58.34,46.66 58.34,49.33 58.48,49.47 58.61,49.47 58.67,49.4 58.67,49.06 v1(58.69,49.04)
FMC-1_HA12_P: length 95
  TOP w0.102: v1(58.69,50.04) U31.J10 ; 9.53,60.45 v1(10.16,59.82)
  L7_SIGNAL w0.089: v1(58.69,50.04) 58.09,49.44 58.09,46.76 58.01,46.69 40.54,46.69 37.57,49.66 34.78,49.66 31.92,52.51 30.25,52.51 29.59,51.86 29.59,49.02 29.84,48.77 31.75,48.77 32,48.51 32,48.11 31.9,48.01 29.72,48.01 29.46,47.75 29.46,46.99 29.72,46.74 34.16,46.74 34.42,46.48 34.42,46.1 34.16,45.85 23.98,45.85 23.62,46.21 23.62,56.11 22.97,56.77 22.37,56.77 21.97,56.37 21.97,54.84 21.87,54.74 21.34,54.74 21.08,54.99 21.08,56.52 20.83,56.77 19.81,56.77 19.56,56.52 19.56,54.99 19.3,54.74 19.05,54.74 18.8,54.99 18.8,56.52 18.54,56.77 18.16,56.77 17.65,57.28 17.65,58.8 17.14,59.31 10.67,59.31 v1(10.16,59.82)
FMC-1_HA13_N: length 96
  TOP w0.102: v1(56.69,52.04) U31.G12 ; P1.E13 v1(11.43,59.82)
  L7_SIGNAL w0.089: v1(11.43,59.82) 11.43,60.2 11.56,60.33 13.21,60.33 13.46,60.58 13.46,65.3 13.57,65.41 14.37,65.41 14.48,65.3 14.48,60.73 14.88,60.33 18.16,60.33 18.67,59.82 18.67,58.04 19.18,57.53 22.84,57.53 23.49,58.19 23.49,61.24 23.85,61.59 24.28,61.59 24.64,61.24 24.64,47.37 25.15,46.86 28.32,46.86 28.83,47.37 28.83,53.02 29.34,53.53 32.32,53.53 35.05,50.8 37.74,50.8 38.38,50.17 39.14,50.17 39.69,49.62 39.69,48.85 40.71,47.83 42.61,47.83 43.01,47.44 57.09,47.44 57.34,47.69 57.34,51.2 57.53,51.39 58.12,51.39 58.34,51.61 58.34,53.29 57.94,53.69 57.43,53.69 57.04,53.3 57.04,52.39 v1(56.69,52.04)
FMC-1_HA13_P: length 94.8
  TOP w0.102: v1(57.69,52.04) U31.H12 ; P1.E12 v1(11.43,61.09)
  L7_SIGNAL w0.089: v1(57.69,52.04) 57.29,52.44 57.29,53.2 57.53,53.44 57.84,53.44 58.09,53.19 58.09,51.72 58.01,51.64 57.43,51.64 57.09,51.3 57.09,47.8 56.98,47.69 43.12,47.69 42.72,48.09 40.81,48.09 39.94,48.96 39.94,49.72 39.24,50.42 38.48,50.42 37.85,51.05 35.16,51.05 32.43,53.78 29.23,53.78 28.57,53.13 28.57,47.48 28.22,47.12 25.25,47.12 24.89,47.48 24.89,61.34 24.38,61.85 23.75,61.85 23.24,61.34 23.24,58.29 22.73,57.78 19.28,57.78 18.92,58.14 18.92,59.92 18.27,60.58 14.99,60.58 14.73,60.83 14.73,65.41 14.48,65.66 13.46,65.66 13.21,65.41 13.21,60.68 13.1,60.58 11.56,60.58 11.43,60.71 v1(11.43,61.09)
FMC-1_HA14_N: length 98
  TOP w0.102: v1(58.69,51.04) U31.J11 ; P1.J16 v1(6.35,56.01)
  L9_SIGNAL w0.089: v1(58.69,51.04) 59.06,51.41 59.06,52.33 59.37,52.64 59.94,52.64 60.29,52.29 60.29,39.59 57.15,36.45 27.18,36.45 26.67,36.96 26.67,56.01 26.16,56.52 25.4,56.52 24.89,56.01 24.89,53.74 24.24,53.09 22.75,53.09 22.1,53.74 22.1,56.16 21.74,56.52 6.44,56.52 6.35,56.43 v1(6.35,56.01)
FMC-1_HA14_P: length 96.7
  TOP w0.102: v1(59.69,51.04) U31.K11 ; P1.J15 v1(6.35,57.28)
  L9_SIGNAL w0.089: v1(6.35,57.28) 6.35,56.86 6.44,56.77 21.84,56.77 22.35,56.26 22.35,53.85 22.86,53.34 24.13,53.34 24.64,53.85 24.64,56.11 25.29,56.77 26.27,56.77 26.92,56.11 26.92,37.06 27.28,36.7 57.04,36.7 60.04,39.7 60.04,52.18 59.84,52.39 59.48,52.39 59.32,52.23 59.32,51.41 v1(59.69,51.04)
FMC-1_HA15_N: length 91.8
  TOP w0.102: v1(56.69,48.04) U31.G8 ; P1.F17 v1(10.16,54.74)
  L20_SIGNAL w0.089: v1(10.16,54.74) 10.16,55.12 10.29,55.25 16.89,55.25 17.4,54.74 17.4,52.83 17.91,52.32 23.11,52.32 23.62,51.82 23.62,46.48 24.13,45.97 28.19,45.97 28.7,46.48 28.7,54.74 29.21,55.25 35.71,55.25 36.07,54.89 36.07,45.49 36.72,44.83 40.01,44.83 40.51,45.34 40.51,53.72 41.02,54.23 45.97,54.23 46.99,55.25 48.03,55.25 49.16,54.11 51.27,54.11 51.55,54.39 56.93,54.39 57.09,54.23 57.09,48.63 57.06,48.61 57.06,48.41 v1(56.69,48.04)
FMC-1_HA15_P: length 92.2
  TOP w0.102: v1(57.69,48.04) U31.H8 ; P1.F16 v1(10.16,56.01)
  L20_SIGNAL w0.089: v1(10.16,56.01) 10.16,55.63 10.29,55.5 17,55.5 17.65,54.84 17.65,52.94 18.01,52.58 23.22,52.58 23.88,51.92 23.88,46.59 24.24,46.23 28.09,46.23 28.45,46.59 28.45,54.84 29.1,55.5 35.81,55.5 36.32,54.99 36.32,45.59 36.83,45.08 39.9,45.08 40.26,45.44 40.26,53.83 40.92,54.48 45.87,54.48 46.88,55.5 48.13,55.5 49.27,54.36 51.16,54.36 51.44,54.64 57.04,54.64 57.34,54.34 57.34,48.52 57.32,48.5 57.32,48.41 v1(57.69,48.04)
FMC-1_HA16_N: length 94.9
  TOP w0.102: P1.E16 v1(11.43,56.01) ; v1(58.69,52.04) U31.J12
  L20_SIGNAL w0.089: v1(58.69,52.04) 59.09,52.44 59.09,55.14 58.84,55.39 55.55,55.39 55.53,55.37 54.85,55.37 54.84,55.39 49.15,55.39 48.03,56.52 42.67,56.52 42.59,56.43 37.85,56.43 37.59,56.69 37.59,62.74 37.34,62.99 36.05,62.99 35.69,62.63 35.69,57.09 35.03,56.43 27.94,56.43 27.43,55.92 27.43,48.13 26.92,47.62 25.27,47.62 24.76,48.13 24.76,52.96 24.26,53.47 18.92,53.47 18.41,53.98 18.41,54.74 18.92,55.25 24.76,55.25 25.27,55.75 25.27,56.16 24.91,56.52 11.56,56.52 11.43,56.39 v1(11.43,56.01)
FMC-1_HA16_P: length 95.3
  TOP w0.102: P1.E15 v1(11.43,57.28) ; v1(59.69,52.04) U31.K12
  L20_SIGNAL w0.089: v1(59.69,52.04) 59.34,52.39 59.34,55.24 58.94,55.64 55.44,55.64 55.42,55.63 54.96,55.63 54.94,55.64 49.26,55.64 48.13,56.77 42.57,56.77 42.48,56.69 37.95,56.69 37.85,56.79 37.85,62.84 37.44,63.25 35.94,63.25 35.43,62.74 35.43,57.19 34.92,56.69 27.83,56.69 27.18,56.03 27.18,48.24 26.82,47.88 25.38,47.88 25.02,48.24 25.02,53.06 24.36,53.72 19.03,53.72 18.67,54.08 18.67,54.63 19.03,54.99 24.87,54.99 25.53,55.65 25.53,56.26 25.02,56.77 11.56,56.77 11.43,56.9 v1(11.43,57.28)
FMC-1_HA17_N_CC: length 95.1
  TOP w0.102: v1(56.69,50.04) U31.G10 ; 4.45,55.37 v1(5.08,54.74)
  L9_SIGNAL w0.089: v1(56.69,50.04) 57.06,50.41 57.81,50.41 58.04,50.18 58.04,40.37 55.77,38.1 34.67,38.1 34.16,38.61 34.16,55.12 33.66,55.63 32.51,55.63 32,56.13 32,57.38 31.35,58.04 30.35,58.04 29.84,58.55 29.84,60.33 29.34,60.83 18.16,60.83 17.65,60.33 17.65,58.4 17.29,58.04 4.57,58.04 3.94,57.4 3.94,55.5 4.19,55.25 4.99,55.25 5.08,55.16 v1(5.08,54.74)
FMC-1_HA17_P_CC: length 95.1
  TOP w0.102: 4.45,56.64 v1(5.08,56.01) ; v1(56.69,51.04) U31.G11
  L9_SIGNAL w0.089: v1(56.69,51.04) 57.06,50.67 57.92,50.67 58.29,50.29 58.29,40.26 55.88,37.85 34.57,37.85 33.91,38.5 33.91,55.01 33.55,55.37 32.41,55.37 31.75,56.03 31.75,57.28 31.24,57.78 30.25,57.78 29.59,58.44 29.59,60.22 29.23,60.58 18.27,60.58 17.91,60.22 17.91,58.29 17.4,57.78 4.68,57.78 4.19,57.3 4.19,55.6 4.3,55.5 4.99,55.5 5.08,55.59 v1(5.08,56.01)
FMC-1_HA18_N: length 93.2
  TOP w0.102: 5.71,52.83 v1(6.35,52.2) ; v1(57.69,49.04) U31.H9
  L18_SIGNAL w0.089: v1(6.35,52.2) 6.35,52.62 6.44,52.7 6.75,52.7 6.86,52.6 6.86,42.95 7.26,42.55 9,42.55 9.81,43.36 9.81,43.45 10.17,43.81 13.19,43.81 13.46,44.09 13.46,50.95 13.95,51.44 28.32,51.44 28.57,51.18 28.57,47.88 28.83,47.62 31.5,47.62 31.75,47.88 31.75,52.18 31.6,52.32 30.03,52.32 29.84,52.51 29.84,52.77 30.03,52.96 33.02,52.96 33.27,52.7 33.27,48.26 33.53,48.01 48.51,48.01 48.77,48.26 48.77,51.46 48.87,51.56 49.55,51.56 49.66,51.46 49.66,49.81 50.06,49.41 57.32,49.41 v1(57.69,49.04)
FMC-1_HA18_P: length 93.2
  TOP w0.102: v1(57.69,50.04) U31.H10 ; P1.J18 v1(6.35,53.47)
  L18_SIGNAL w0.089: v1(6.35,53.47) 6.35,53.05 6.44,52.96 6.86,52.96 7.11,52.7 7.11,43.05 7.37,42.8 8.89,42.8 9.56,43.47 9.56,43.56 10.07,44.07 13.08,44.07 13.21,44.2 13.21,51.05 13.84,51.69 28.43,51.69 28.83,51.29 28.83,47.98 28.93,47.88 31.39,47.88 31.5,47.98 31.5,52.07 29.93,52.07 29.59,52.4 29.59,52.88 29.93,53.21 33.13,53.21 33.53,52.81 33.53,48.37 33.63,48.26 48.41,48.26 48.51,48.37 48.51,51.56 48.77,51.82 49.66,51.82 49.91,51.56 49.91,49.92 50.16,49.67 57.32,49.67 v1(57.69,50.04)
FMC-1_HA19_N: length 93.3
  TOP w0.102: P1.F20 v1(10.16,50.93) ; v1(59.69,49.04) U31.K9
  L20_SIGNAL w0.089: v1(59.69,49.04) 60.06,49.41 60.06,49.61 60.07,49.61 60.07,50.15 59.84,50.39 58.55,50.39 58.29,50.14 58.29,47.75 57.98,47.44 56.32,47.44 56.04,47.72 56.04,52.18 55.79,52.44 43.04,52.44 42.84,52.24 42.19,52.24 41.83,51.88 41.83,43.56 41.32,43.05 35.43,43.05 34.92,43.56 34.92,51.73 34.42,52.24 30.35,52.24 29.84,51.73 29.84,44.07 29.34,43.56 22.86,43.56 22.35,44.07 22.35,50.93 21.84,51.44 10.29,51.44 10.16,51.31 v1(10.16,50.93)
FMC-1_HA19_P: length 93.8
  TOP w0.102: v1(60.69,49.04) U31.L9 ; 9.53,52.83 v1(10.16,52.2)
  L20_SIGNAL w0.089: v1(10.16,52.2) 10.16,51.82 10.29,51.69 21.95,51.69 22.61,51.03 22.61,44.17 22.97,43.81 29.23,43.81 29.59,44.17 29.59,51.84 30.25,52.5 34.52,52.5 35.18,51.84 35.18,43.67 35.54,43.31 41.21,43.31 41.57,43.67 41.57,51.99 42.08,52.5 42.74,52.5 42.93,52.69 55.89,52.69 56.29,52.29 56.29,47.82 56.43,47.69 57.87,47.69 58.04,47.86 58.04,50.24 58.44,50.64 59.94,50.64 60.33,50.26 60.33,49.51 60.32,49.5 60.32,49.41 v1(60.69,49.04)
FMC-1_HA20_N: length 91.9
  TOP w0.102: 10.79,52.83 v1(11.43,52.2) ; v1(59.69,53.04) U31.K13
  L18_SIGNAL w0.089: v1(11.43,52.2) 11.43,52.58 11.56,52.7 13.06,52.7 13.46,53.11 13.46,53.87 13.57,53.98 34.31,53.98 34.42,53.87 34.42,52.47 34.82,52.07 37.57,52.07 37.97,52.47 37.97,52.98 38.08,53.09 38.61,53.09 38.86,52.83 38.86,51.56 39.12,51.31 40.26,51.31 40.51,51.56 40.51,52.96 40.77,53.21 41.55,53.21 41.66,53.11 41.66,52.47 42.06,52.07 46.38,52.07 46.48,51.96 46.48,51.03 46.38,50.93 34.67,50.93 34.42,50.67 34.42,50.04 34.67,49.78 43.33,49.78 43.43,49.68 43.43,49.3 43.84,48.89 45.09,48.89 45.34,49.15 45.34,49.53 45.59,49.78 46.1,49.78 46.36,49.53 46.36,49.15 46.61,48.89 47.62,48.89 47.88,49.15 47.88,52.18 48.13,52.44 57.94,52.44 58.34,52.83 58.34,54.18 58.55,54.39 59.84,54.39 60.04,54.18 60.04,53.52 60.06,53.5 60.06,53.41 v1(59.69,53.04)
FMC-1_HA20_P: length 92.3
  TOP w0.102: P1.E18 v1(11.43,53.47) ; v1(60.69,53.04) U31.L13
  L18_SIGNAL w0.089: v1(11.43,53.47) 11.43,53.09 11.56,52.96 12.95,52.96 13.21,53.21 13.21,53.98 13.46,54.23 34.42,54.23 34.67,53.98 34.67,52.58 34.92,52.32 37.47,52.32 37.72,52.58 37.72,53.09 37.97,53.34 38.71,53.34 39.12,52.94 39.12,51.67 39.22,51.56 40.15,51.56 40.26,51.67 40.26,53.06 40.66,53.47 41.66,53.47 41.91,53.21 41.91,52.58 42.16,52.32 46.48,52.32 46.74,52.07 46.74,50.93 46.48,50.67 34.78,50.67 34.67,50.57 34.67,50.14 34.78,50.04 43.43,50.04 43.69,49.78 43.69,49.4 43.94,49.15 44.98,49.15 45.09,49.25 45.09,49.64 45.49,50.04 46.21,50.04 46.61,49.64 46.61,49.25 46.71,49.15 47.52,49.15 47.62,49.25 47.62,52.29 48.03,52.69 57.84,52.69 58.09,52.94 58.09,54.29 58.44,54.64 59.94,54.64 60.29,54.29 60.29,53.63 60.32,53.61 60.32,53.41 v1(60.69,53.04)
FMC-1_HA21_N: length 96.3
  TOP w0.102: 4.45,51.56 v1(5.08,50.93) ; v1(60.69,50.04) U31.L10
  L9_SIGNAL w0.089: v1(5.08,50.93) 4.57,51.44 4.06,51.44 3.68,51.05 3.68,50.8 4.06,50.42 17.25,50.42 18.35,49.32 18.35,38.48 18.86,37.97 21.1,37.97 21.46,38.33 21.46,41.25 22.12,41.91 24.51,41.91 25.02,41.4 25.02,35.03 25.38,34.67 57.79,34.67 58.55,35.43 58.55,36.45 61.06,38.97 61.06,49.67 v1(60.69,50.04)
FMC-1_HA21_P: length 97.6
  TOP w0.102: 4.45,52.83 v1(5.08,52.2) ; v1(61.69,50.04) U31.M10
  L9_SIGNAL w0.089: v1(5.08,52.2) 4.57,51.69 3.96,51.69 3.43,51.16 3.43,50.69 3.96,50.17 17.14,50.17 18.1,49.21 18.1,38.38 18.75,37.72 21.21,37.72 21.72,38.23 21.72,41.15 22.22,41.66 24.41,41.66 24.76,41.3 24.76,34.92 25.27,34.42 57.89,34.42 58.8,35.33 58.8,36.34 61.32,38.86 61.32,49.67 v1(61.69,50.04)
FMC-1_HA22_N: length 93.7
  TOP w0.102: P1.J22 v1(6.35,48.39) ; v1(61.69,52.04) U31.M12
  L16_SIGNAL w0.089: v1(61.69,52.04) 61.69,52.23 61.46,52.46 61.29,52.3 61.29,51.64 61.05,51.39 60.55,51.39 60.34,51.18 60.34,48.81 59.92,48.39 46.36,48.39 45.85,47.88 45.85,46.74 46.36,46.23 47.37,46.23 47.62,45.97 47.62,44.2 47.37,43.94 46.21,43.94 45.85,43.58 45.85,38.48 46.36,37.97 48.51,37.97 49.02,37.47 49.02,36.19 48.51,35.69 24.79,35.69 24.28,36.19 19.05,36.19 18.54,36.7 18.54,38.23 18.03,38.73 7.37,38.73 6.86,39.24 6.86,48.79 6.75,48.89 6.44,48.89 6.35,48.81 v1(6.35,48.39)
FMC-1_HA22_P: length 93.6
  TOP w0.102: P1.J21 v1(6.35,49.66) ; v1(61.69,53.04) U31.M13
  L16_SIGNAL w0.089: v1(61.69,53.04) 61.68,53.04 61.04,52.4 61.04,51.74 60.94,51.64 60.44,51.64 60.09,51.29 60.09,48.91 59.82,48.64 46.25,48.64 45.59,47.99 45.59,46.63 46.25,45.97 47.27,45.97 47.37,45.87 47.37,44.3 47.27,44.2 46.1,44.2 45.59,43.69 45.59,38.38 46.25,37.72 48.41,37.72 48.77,37.36 48.77,36.3 48.41,35.94 24.89,35.94 24.38,36.45 19.16,36.45 18.8,36.81 18.8,38.33 18.14,38.99 7.47,38.99 7.11,39.35 7.11,48.89 6.86,49.15 6.44,49.15 6.35,49.24 v1(6.35,49.66)
FMC-1_HA23_N: length 92.5
  TOP w0.102: 4.45,47.75 v1(5.08,47.12) ; v1(60.69,51.04) U31.L11
  L16_SIGNAL w0.089: v1(60.69,51.04) 61.06,50.67 61.06,50.58 61.04,50.55 61.04,47.79 60.89,47.64 49.04,47.64 48.39,46.99 48.39,41.63 48.03,41.28 47.24,41.28 46.74,40.77 46.74,39.62 47.24,39.12 49.68,39.12 50.04,38.76 50.04,35.16 49.68,34.8 17.89,34.8 17.53,35.16 17.53,37.06 16.87,37.72 4.93,37.72 4.45,38.21 4.45,47.52 4.55,47.62 4.99,47.62 5.08,47.54 v1(5.08,47.12)
FMC-1_HA23_P: length 93.8
  TOP w0.102: 4.45,49.02 v1(5.08,48.39) ; v1(61.69,51.04) U31.M11
  L16_SIGNAL w0.089: v1(5.08,48.39) 5.08,47.97 4.99,47.88 4.45,47.88 4.19,47.62 4.19,38.1 4.83,37.47 16.76,37.47 17.27,36.96 17.27,35.05 17.78,34.54 49.78,34.54 50.29,35.05 50.29,38.86 49.78,39.37 47.35,39.37 46.99,39.73 46.99,40.66 47.35,41.02 48.13,41.02 48.64,41.53 48.64,46.88 49.15,47.39 60.89,47.39 61.09,47.39 61.29,47.6 61.29,47.89 61.29,50.45 61.32,50.47 61.32,50.67 v1(61.69,51.04)
FMC-1_HB00_N_CC: length 96.3
  TOP w0.102: v1(51.69,69.04) U31.B28 ; 4.45,43.94 v1(5.08,43.31)
  L3_SIGNAL w0.089: v1(33.52,65.28) 33.19,65.28 32.55,64.64 25.04,64.64 24.38,65.3 24.38,74.06 24.02,74.42 21.57,74.42 21.21,74.06 21.21,49.42 18.19,46.4 7.68,46.4 7.27,45.99 7.27,44.25 6.84,43.81 5.17,43.81 5.08,43.73 v1(5.08,43.31)
  L5_SIGNAL w0.089: v1(51.69,69.04) 52.09,68.64 53.94,68.64 54.34,68.24 54.34,66.03 52.71,64.39 45.21,64.39 43.18,66.42 34.27,66.42 33.52,65.68 v1(33.52,65.28)
FMC-1_HB00_P_CC: length 95.5
  TOP w0.102: v1(52.69,68.04) U31.C27 ; 4.45,45.21 v1(5.08,44.58)
  L3_SIGNAL w0.089: v1(32.95,65.86) 32.95,65.41 32.44,64.9 25.15,64.9 24.64,65.41 24.64,74.17 24.13,74.68 21.46,74.68 20.95,74.17 20.95,49.53 18.08,46.66 7.58,46.66 7.02,46.1 7.02,44.35 6.73,44.07 5.17,44.07 5.08,44.16 v1(5.08,44.58)
  L5_SIGNAL w0.089: v1(52.69,68.04) 52.66,68.07 52.32,68.07 52.2,68.2 52.2,68.3 52.29,68.39 53.84,68.39 54.09,68.14 54.09,66.13 52.6,64.64 45.32,64.64 43.29,66.67 34.16,66.67 33.35,65.86 v1(32.95,65.86)
FMC-1_HB01_N: length 99.3
  TOP w0.102: P1.J25 v1(6.35,44.58) ; v1(51.69,73.04) U31.B32
  L3_SIGNAL w0.089: v1(6.35,44.58) 6.35,45 6.26,45.08 5.86,45.08 5.59,45.36 5.59,47.48 5.99,47.88 17.04,47.88 19.42,50.26 19.42,85.09 19.93,85.6 31.24,85.6 31.75,85.09 31.75,79.12 32.26,78.61 49.28,78.61 49.78,78.11 49.78,73.15 50.29,72.64 51.1,72.64 51.12,72.67 51.32,72.67 v1(51.69,73.04)
FMC-1_HB01_P: length 98.4
  TOP w0.102: v1(51.69,72.04) U31.B31 ; P1.J24 v1(6.35,45.85)
  L3_SIGNAL w0.089: v1(6.35,45.85) 6.35,45.43 6.26,45.34 5.97,45.34 5.84,45.47 5.84,47.37 6.1,47.62 17.14,47.62 19.67,50.15 19.67,84.98 20.03,85.34 31.14,85.34 31.5,84.98 31.5,79.02 32.15,78.36 49.17,78.36 49.53,78 49.53,73.05 50.19,72.39 51.21,72.39 51.23,72.41 51.32,72.41 v1(51.69,72.04)
FMC-1_HB02_N: length 91.5
  TOP w0.102: P1.F23 v1(10.16,47.12) ; v1(52.69,75.04) U31.C34
  L22_SIGNAL w0.089: v1(10.16,47.12) 10.16,47.54 10.25,47.62 11.79,47.62 12.19,48.03 12.19,48.41 12.68,48.89 16.76,48.89 17.27,49.4 17.27,79.02 17.63,79.38 18.01,79.38 18.67,80.03 18.67,85.37 19.03,85.73 27.58,85.73 27.94,85.37 27.94,80.03 28.6,79.38 52.7,79.38 53.06,79.02 53.06,75.41 v1(52.69,75.04)
FMC-1_HB02_P: length 91.9
  TOP w0.102: v1(53.69,75.04) U31.D34 ; P1.F22 v1(10.16,48.39)
  L22_SIGNAL w0.089: v1(10.16,48.39) 10.16,47.97 10.25,47.88 11.68,47.88 11.94,48.13 11.94,48.51 12.57,49.15 16.66,49.15 17.02,49.51 17.02,79.12 17.53,79.63 17.91,79.63 18.41,80.14 18.41,85.47 18.92,85.98 27.69,85.98 28.19,85.47 28.19,80.14 28.7,79.63 52.81,79.63 53.32,79.12 53.32,75.41 v1(53.69,75.04)
FMC-1_HB03_N: length 95.9
  TOP w0.102: v1(50.69,74.04) U31.A33 ; P1.E22 v1(11.43,48.39)
  L3_SIGNAL w0.089: v1(11.43,48.39) 11.94,48.89 17.12,48.89 17.78,49.55 17.78,79.52 18.29,80.03 18.29,89.05 18.65,89.41 32.41,89.41 32.77,89.05 32.77,80.39 33.27,79.88 50.69,79.88 51.05,79.52 51.05,74.4 v1(50.69,74.04)
FMC-1_HB03_P: length 96.3
  TOP w0.102: P1.E21 v1(11.43,49.66) ; v1(51.69,74.04) U31.B33
  L3_SIGNAL w0.089: v1(51.69,74.04) 51.31,74.42 51.31,79.63 50.8,80.14 33.38,80.14 33.02,80.5 33.02,89.15 32.51,89.66 18.54,89.66 18.03,89.15 18.03,80.14 17.53,79.63 17.53,49.66 17.02,49.15 11.94,49.15 v1(11.43,49.66)
FMC-1_HB04_N: length 92.1
  TOP w0.102: v1(51.69,75.04) U31.B34 ; P1.F26 v1(10.16,43.31)
  L22_SIGNAL w0.089: v1(51.69,75.04) 52.04,74.69 52.04,74.57 51.86,74.39 51.55,74.39 51.34,74.18 51.34,73.95 51.05,73.66 50.16,73.66 49.66,74.17 49.66,77.22 49.15,77.72 26.29,77.72 26.29,81.15 25.78,81.66 20.32,81.66 19.81,81.15 19.81,78.36 19.3,77.85 18.82,77.85 18.16,77.19 18.16,46.97 17.8,46.61 8.66,46.61 8.13,46.08 8.13,44.22 8.53,43.81 9.65,43.81 v1(10.16,43.31)
FMC-1_HB04_P: length 91.5
  TOP w0.102: P1.F25 v1(10.16,44.58) ; v1(52.69,74.04) U31.C33
  L22_SIGNAL w0.089: v1(10.16,44.58) 9.65,44.07 8.64,44.07 8.38,44.32 8.38,45.97 8.76,46.36 17.91,46.36 18.41,46.86 18.41,77.09 18.92,77.6 19.41,77.6 20.07,78.25 20.07,81.05 20.43,81.41 25.68,81.41 26.04,81.05 26.04,77.62 26.18,77.47 49.04,77.47 49.4,77.11 49.4,74.06 50.06,73.41 51.16,73.41 51.44,73.69 51.84,73.69 52.04,73.89 52.04,74.21 52.22,74.39 52.34,74.39 v1(52.69,74.04)
FMC-1_HB05_N: length 96.7
  TOP w0.102: P1.E25 v1(11.43,44.58) ; v1(53.69,72.04) U31.D31
  L3_SIGNAL w0.089: v1(11.43,44.58) 11.43,45 11.52,45.08 18.65,45.08 22.35,48.79 22.35,62.51 22.65,62.8 33.76,62.8 34.42,63.46 34.42,66.53 33.76,67.18 27.28,67.18 26.92,67.54 26.92,76.98 27.28,77.34 47.52,77.34 47.88,76.98 47.88,72.16 48.54,71.5 50.38,71.5 50.44,71.44 51.94,71.44 52.32,71.82 52.32,73.17 52.56,73.41 53.87,73.41 54.04,73.24 54.04,72.39 v1(53.69,72.04)
FMC-1_HB05_P: length 97.1
  TOP w0.102: v1(54.69,72.04) U31.E31 ; P1.E24 v1(11.43,45.85)
  L3_SIGNAL w0.089: v1(11.43,45.85) 11.43,45.43 11.52,45.34 18.54,45.34 22.1,48.89 22.1,62.61 22.54,63.06 33.66,63.06 34.16,63.56 34.16,66.42 33.66,66.93 27.18,66.93 26.67,67.44 26.67,77.09 27.18,77.6 47.62,77.6 48.13,77.09 48.13,72.26 48.64,71.76 50.48,71.76 50.55,71.69 51.84,71.69 52.07,71.92 52.07,73.28 52.45,73.66 53.97,73.66 54.29,73.34 54.29,72.44 v1(54.69,72.04)
FMC-1_HB06_N_CC: length 91.8
  TOP w0.102: v1(53.69,68.04) U31.D27 ; 4.45,40.13 v1(5.08,39.5)
  L22_SIGNAL w0.089: v1(53.69,68.04) 54.09,68.44 54.09,69.29 54.44,69.64 55.8,69.64 56.09,69.93 56.09,72.18 55.88,72.39 34.29,72.39 31.24,69.34 25.68,69.34 25.02,70 25.02,71.27 24.66,71.63 19.94,71.63 19.43,71.12 19.43,42.31 17.12,40 5.59,40 v1(5.08,39.5)
FMC-1_HB06_P_CC: length 92.2
  TOP w0.102: P1.K28 v1(5.08,40.77) ; v1(54.69,68.04) U31.E27
  L22_SIGNAL w0.089: v1(54.69,68.04) 54.34,68.39 54.34,69.18 54.55,69.39 55.9,69.39 56.34,69.83 56.34,72.29 56.27,72.36 55.99,72.64 34.18,72.64 31.14,69.6 25.78,69.6 25.27,70.1 25.27,71.37 24.76,71.88 19.83,71.88 19.18,71.23 19.18,42.42 17.02,40.26 5.59,40.26 v1(5.08,40.77)
FMC-1_HB07_N: length 99.6
  TOP w0.102: 5.71,41.4 v1(6.35,40.77) ; v1(52.69,73.04) U31.C32
  L3_SIGNAL w0.089: v1(6.35,40.77) 6.35,41.19 6.26,41.28 4.72,41.28 4.32,41.68 4.32,42.4 4.72,42.8 7.61,42.8 7.97,43.16 7.97,43.38 8.66,44.07 19.2,44.07 23.37,48.24 23.37,60.67 24.02,61.33 26.27,61.33 26.92,60.67 26.92,49.64 27.28,49.28 30.88,49.28 31.24,49.64 31.24,60.67 31.9,61.33 34.05,61.33 36.07,63.35 36.07,65.89 40.82,70.64 52.79,70.64 53.04,70.89 53.04,72.55 53.06,72.58 53.06,72.67 v1(52.69,73.04)
FMC-1_HB07_P: length 99.2
  TOP w0.102: v1(53.69,73.04) U31.D32 ; 5.71,42.67 v1(6.35,42.04)
  L3_SIGNAL w0.089: v1(6.35,42.04) 6.35,41.62 6.26,41.53 4.83,41.53 4.57,41.78 4.57,42.29 4.83,42.55 7.71,42.55 8.22,43.06 8.22,43.28 8.76,43.81 19.3,43.81 23.62,48.13 23.62,60.57 24.13,61.08 26.16,61.08 26.67,60.57 26.67,49.53 27.18,49.02 30.99,49.02 31.5,49.53 31.5,60.57 32,61.08 34.15,61.08 36.32,63.25 36.32,65.79 40.92,70.39 52.89,70.39 53.29,70.79 53.29,72.45 53.32,72.47 53.32,72.67 v1(53.69,73.04)
FMC-1_HB08_N: length 97
  TOP w0.102: 9.53,40.13 v1(10.16,39.5)
  TOP w0.14: v1(51.69,66.04) U31.B25
  L3_SIGNAL w0.089: v1(51.69,66.04) 52.06,65.67 52.06,64.92 51.79,64.64 49.66,64.64 43.31,58.29 43.31,54.74 42.8,54.23 41.93,54.23 41.28,53.57 41.28,41.53 41.78,41.02 43.18,41.02 43.69,40.51 43.69,30.84 43.33,30.48 25.53,30.48 25.02,30.99 25.02,33.13 24.36,33.78 20.85,33.78 20.19,33.13 20.19,31.73 19.83,31.37 8.74,31.37 8.22,31.89 8.22,32.13 7.87,32.48 7.63,32.48 7.11,33 7.11,39.65 7.47,40 9.65,40 v1(10.16,39.5)
FMC-1_HB08_P: length 98.3
  TOP w0.102: P1.F28 v1(10.16,40.77)
  TOP w0.14: v1(52.69,66.04) U31.C25
  L3_SIGNAL w0.089: v1(10.16,40.77) 9.65,40.26 7.37,40.26 6.86,39.75 6.86,32.89 7.52,32.23 7.76,32.23 7.97,32.02 7.97,31.78 8.64,31.11 19.94,31.11 20.45,31.62 20.45,33.02 20.95,33.53 24.26,33.53 24.76,33.02 24.76,30.88 25.42,30.23 43.43,30.23 43.94,30.73 43.94,40.62 43.29,41.28 41.89,41.28 41.53,41.63 41.53,53.47 42.04,53.98 42.9,53.98 43.56,54.63 43.56,58.19 49.76,64.39 51.89,64.39 52.32,64.81 52.32,65.67 v1(52.69,66.04)
FMC-1_HB09_N: length 96.1
  TOP w0.102: P1.E28 v1(11.43,40.77) ; v1(50.69,67.04) U31.A26
  L3_SIGNAL w0.089: v1(38.04,41.72) 38.05,41.71 38.43,41.71 40.01,43.29 40.01,54.1 40.64,54.74 40.64,58.51 41.15,59.02 42.64,59.02 45.47,61.84 45.47,62.61 49.52,66.67 50.32,66.67 v1(50.69,67.04)
  L5_SIGNAL w0.089: v1(38.04,41.72) 38.04,41.32 37.11,40.39 31.98,40.39 30.2,42.16 25.93,42.16 25.27,41.51 25.27,27.69 24.76,27.18 19.68,27.18 19.18,27.69 19.18,41.76 18.14,42.8 9.93,42.8 9.4,42.27 9.4,41.68 9.8,41.28 10.92,41.28 v1(11.43,40.77)
FMC-1_HB09_P: length 95.3
  TOP w0.102: 10.79,42.67 v1(11.43,42.04)
  TOP w0.14: v1(50.69,66.04) U31.A25
  L3_SIGNAL w0.089: v1(50.69,66.04) 50.32,66.41 49.63,66.41 45.72,62.51 45.72,61.74 42.74,58.76 41.25,58.76 40.89,58.4 40.89,54.63 40.26,54 40.26,43.18 38.61,41.53 38.61,41.15 v1(38.62,41.14)
  L5_SIGNAL w0.089: v1(11.43,42.04) 10.92,41.53 9.91,41.53 9.65,41.78 9.65,42.16 10.03,42.55 18.03,42.55 18.92,41.66 18.92,27.58 19.58,26.92 24.87,26.92 25.53,27.58 25.53,41.4 26.04,41.91 30.1,41.91 31.88,40.13 37.21,40.13 38.22,41.14 v1(38.62,41.14)
FMC-1_HB10_N: length 95.3
  TOP w0.102: P1.K32 v1(5.08,35.69) ; v1(53.69,67.04) U31.D26
  L3_SIGNAL w0.089: v1(5.08,35.69) 5.08,36.07 4.87,36.28 4.51,36.28 4.45,36.22 4.45,31.75 4.83,31.37 6.86,31.37 7.11,31.11 7.11,30.35 7.37,30.1 20.72,30.1 21.08,30.46 21.08,30.97 21.74,31.62 23.11,31.62 23.62,31.11 23.62,29.08 24.13,28.57 44.32,28.57 45.59,29.85 45.59,58.79 50.44,63.64 52.21,63.64 54.06,65.49 54.06,66.67 v1(53.69,67.04)
FMC-1_HB10_P: length 96.4
  TOP w0.102: v1(54.69,67.04) U31.E26 ; 4.45,37.59 v1(5.08,36.96)
  L3_SIGNAL w0.089: v1(5.08,36.96) 5.08,36.75 4.87,36.53 4.4,36.53 4.19,36.32 4.19,31.64 4.72,31.11 6.75,31.11 6.86,31.01 6.86,30.25 7.26,29.85 20.83,29.85 21.34,30.35 21.34,30.86 21.84,31.37 23.01,31.37 23.37,31.01 23.37,28.98 24.02,28.32 44.43,28.32 45.85,29.74 45.85,58.69 50.55,63.39 52.32,63.39 54.32,65.39 54.32,66.67 v1(54.69,67.04)
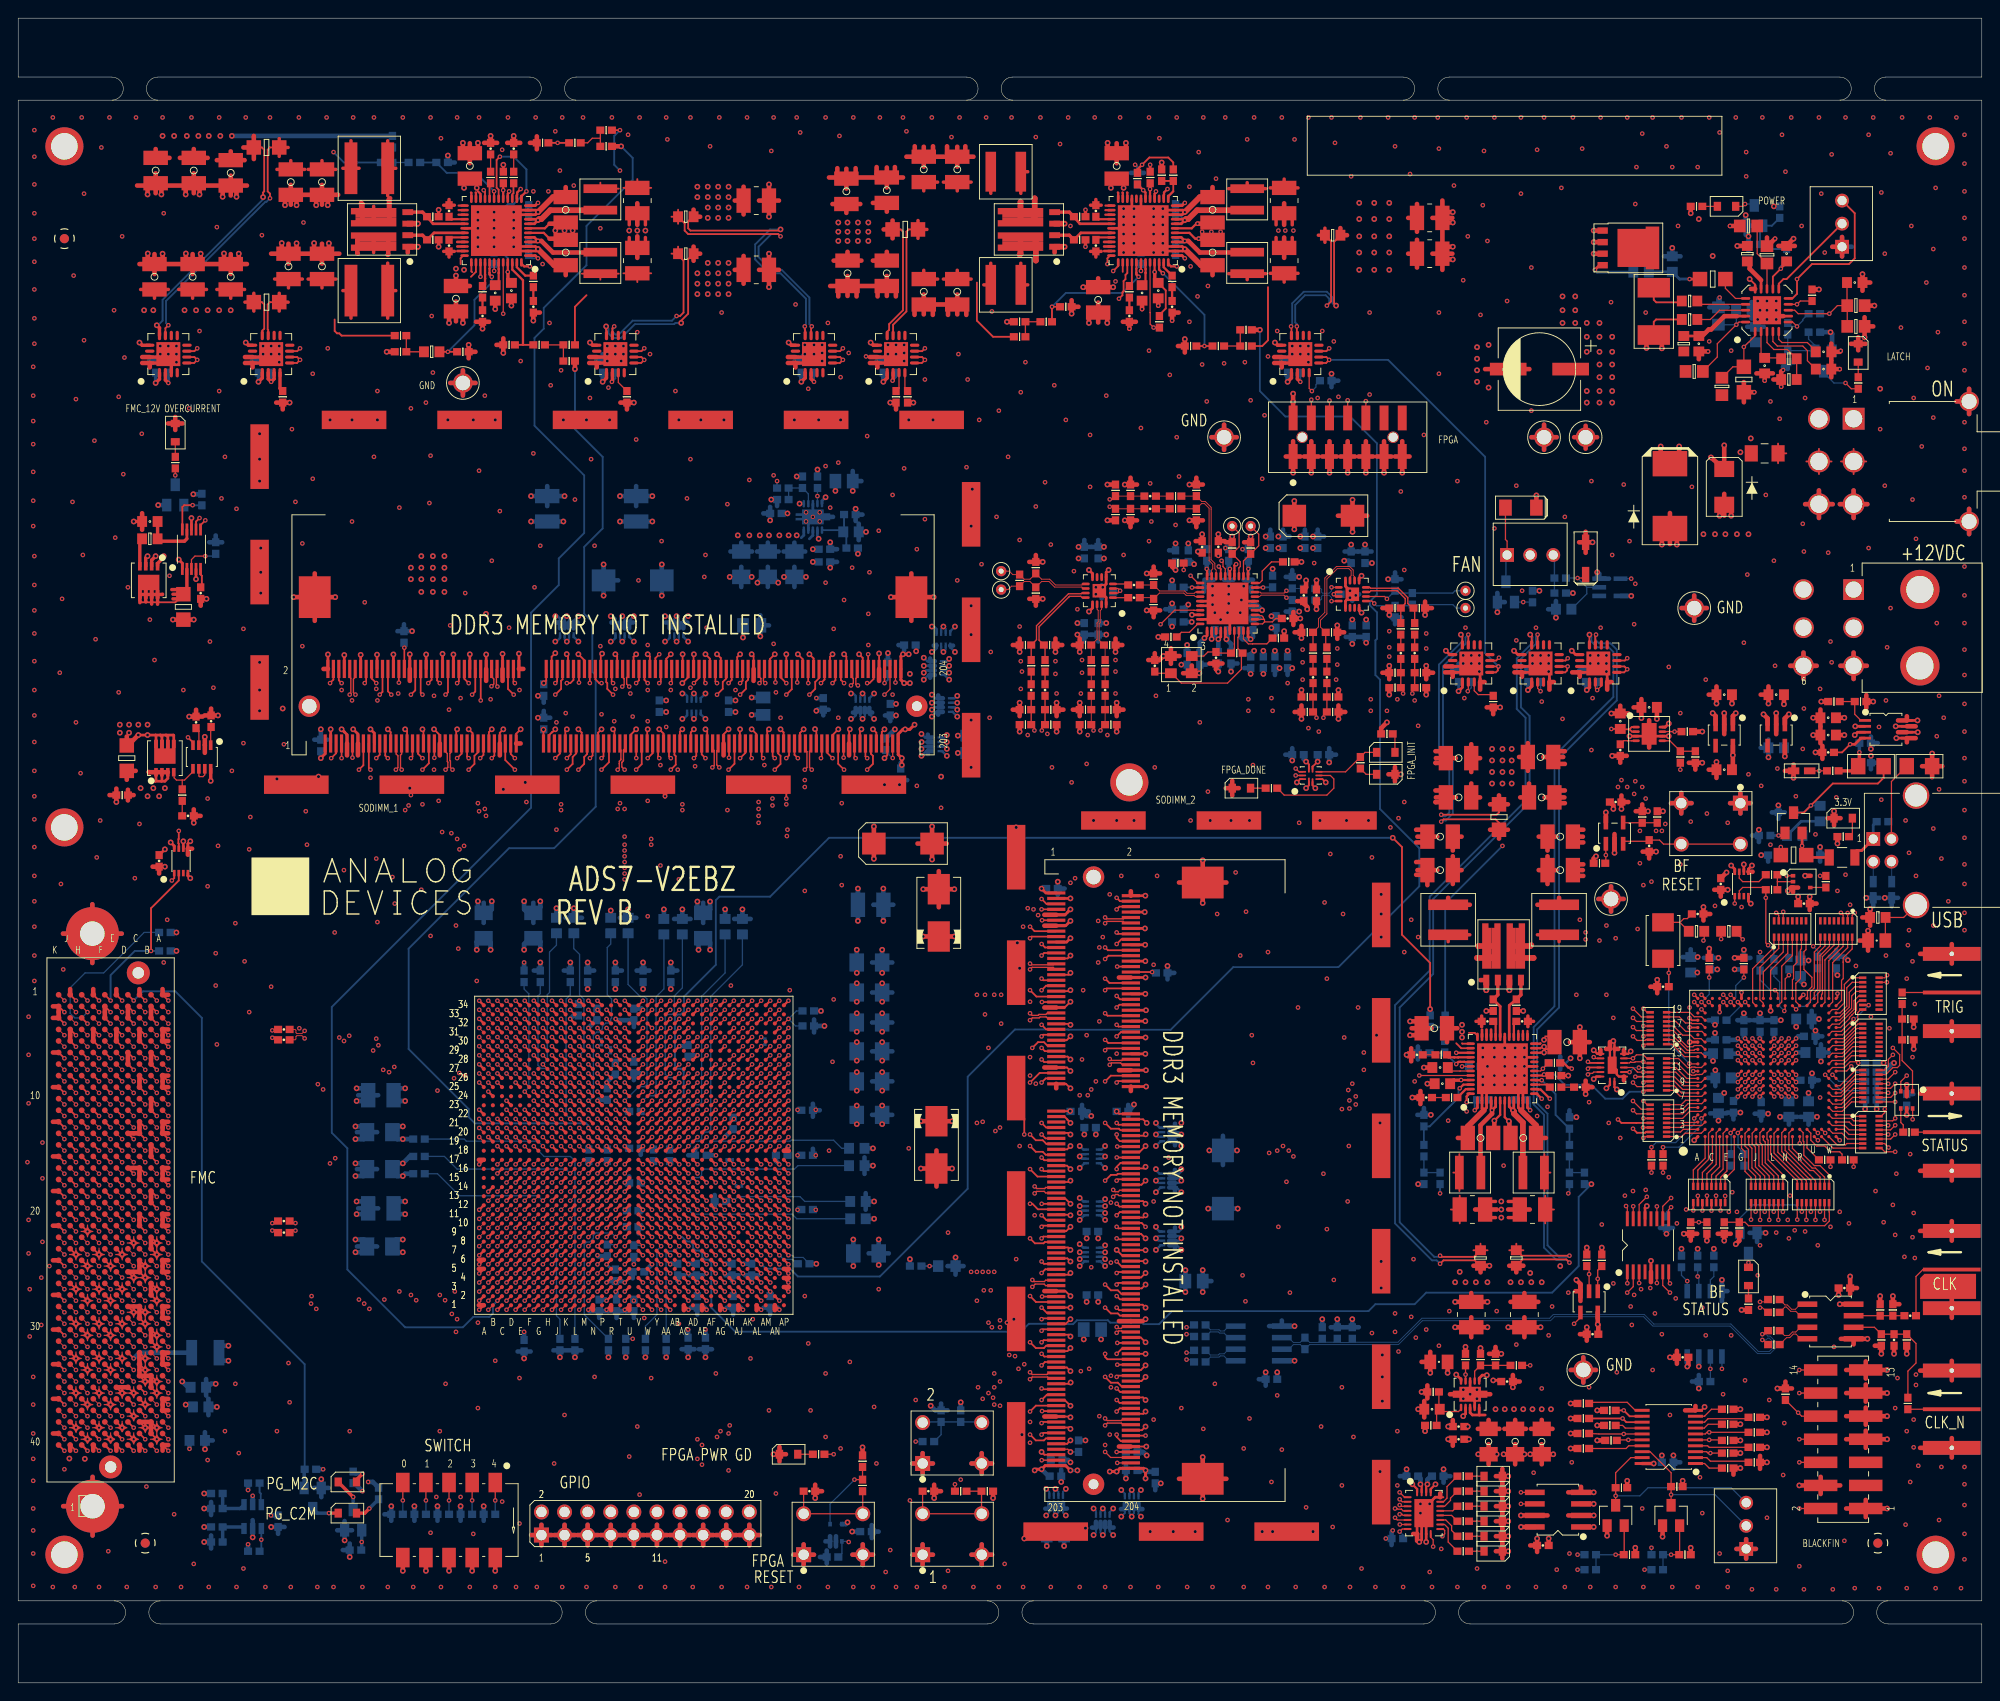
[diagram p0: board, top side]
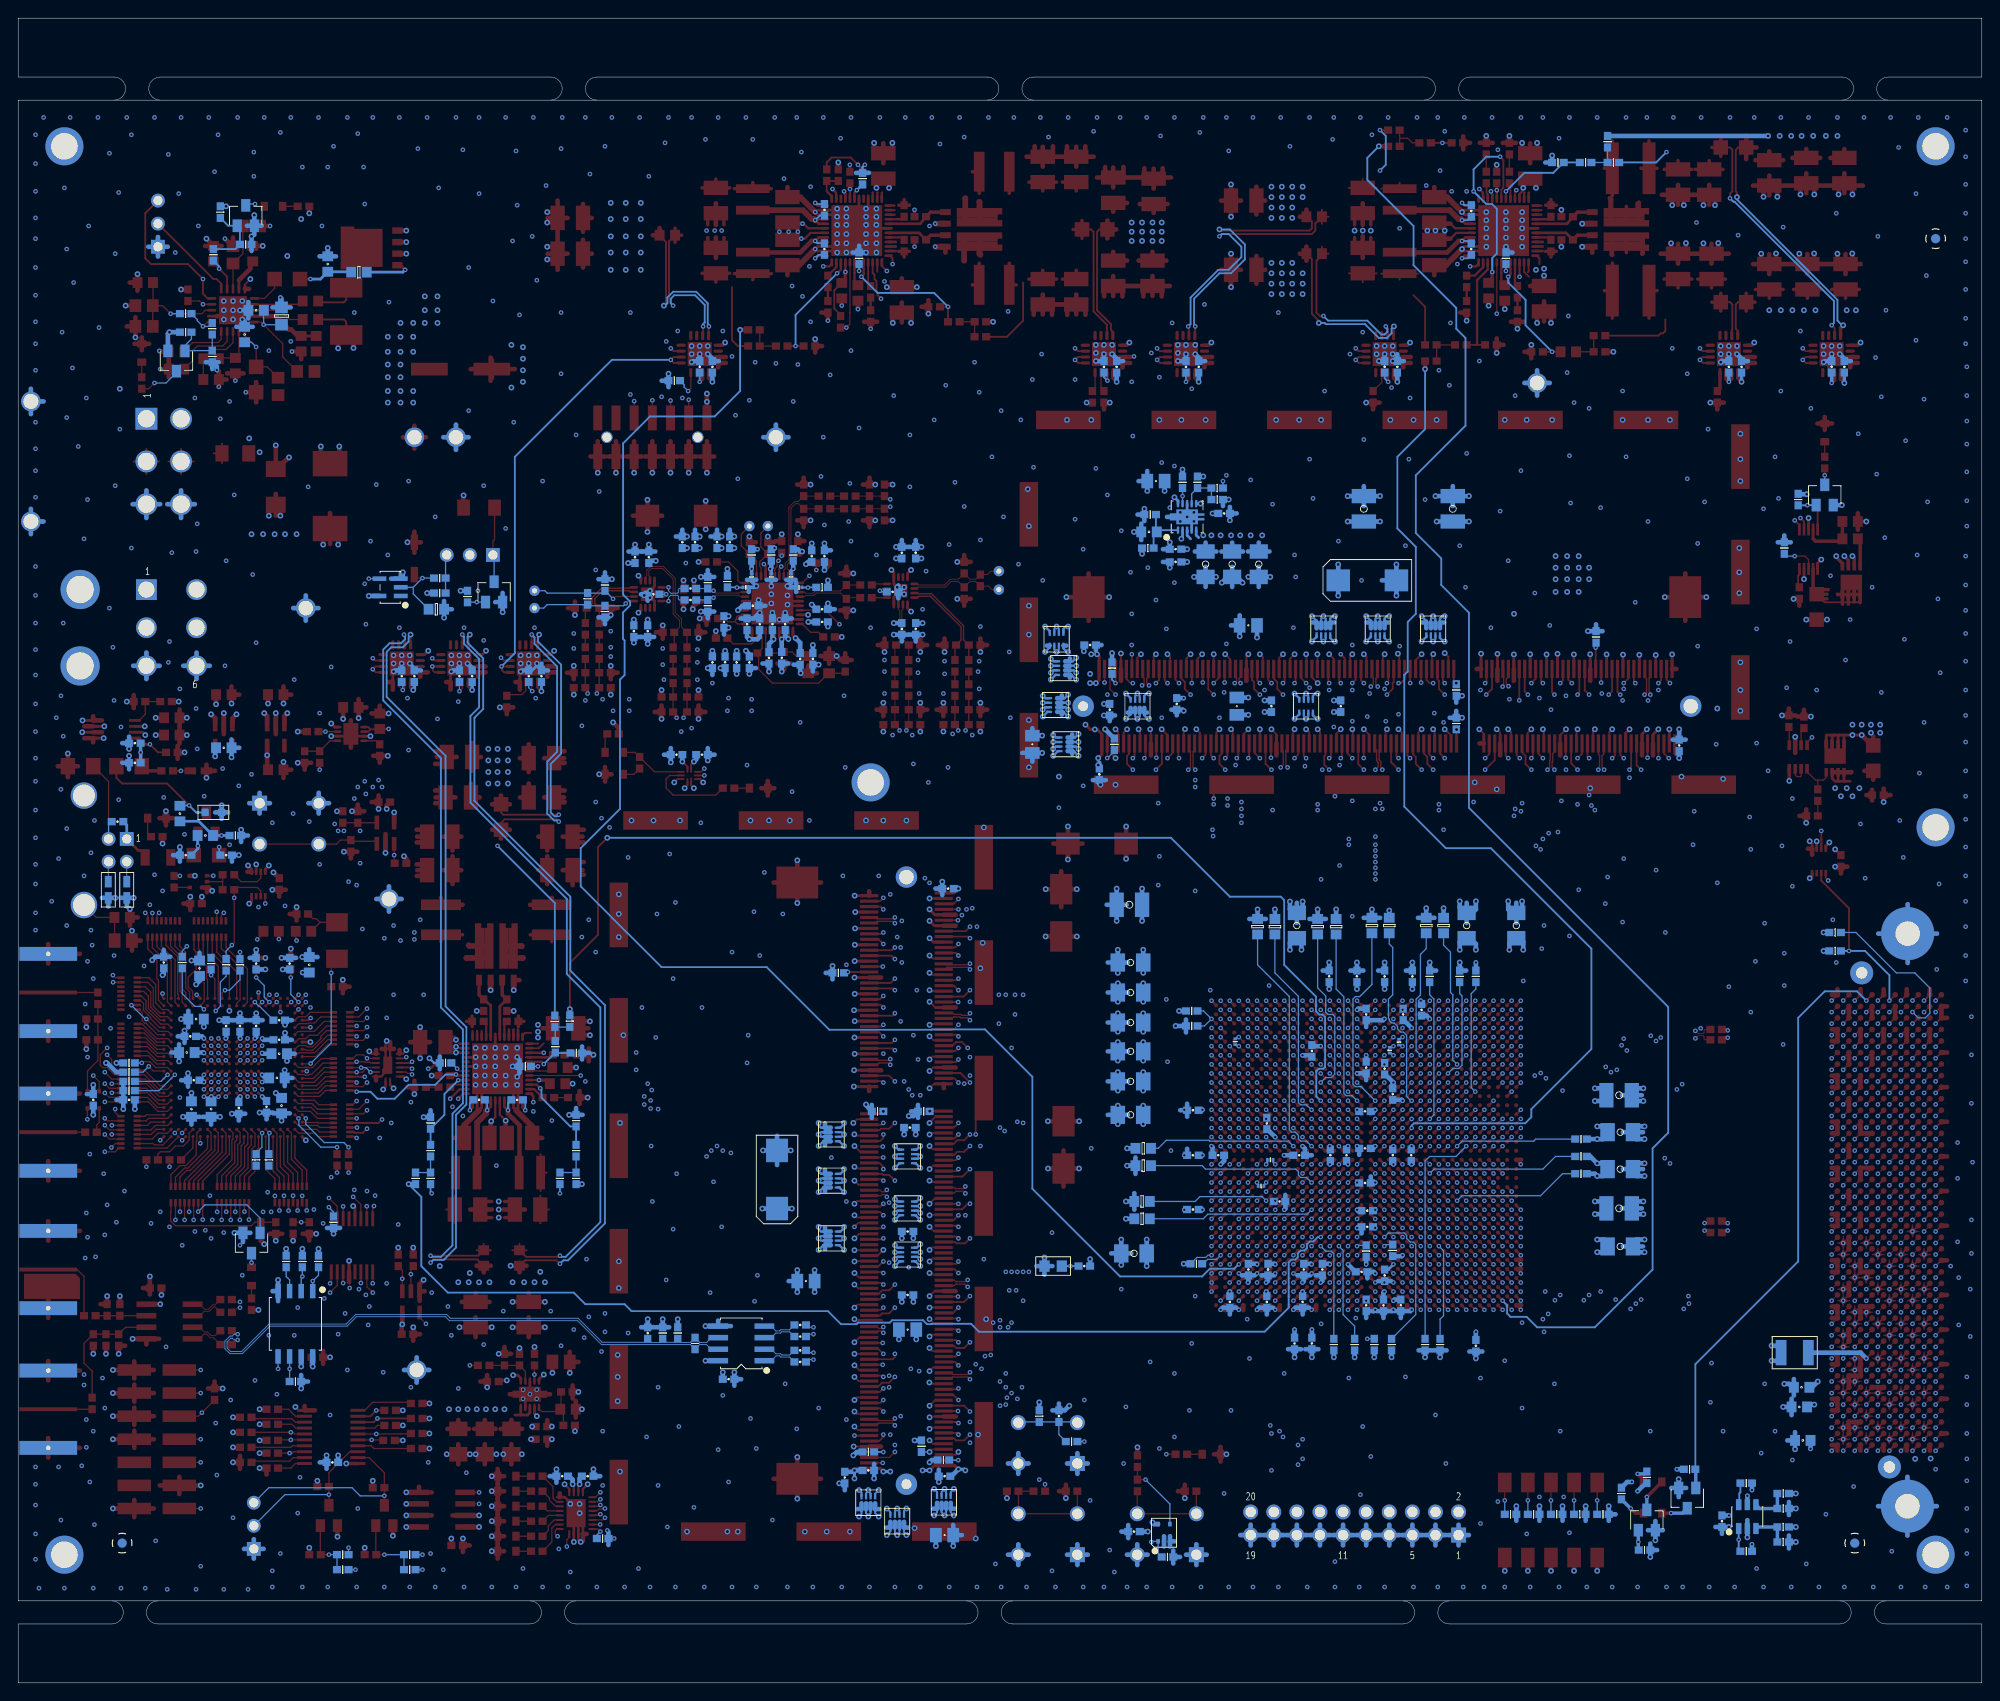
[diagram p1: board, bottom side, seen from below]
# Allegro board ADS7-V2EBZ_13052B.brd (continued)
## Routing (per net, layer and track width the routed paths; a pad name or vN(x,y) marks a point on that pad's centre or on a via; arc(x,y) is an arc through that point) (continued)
FMC-1_HB11_N: length 91.4
  TOP w0.102: 5.71,37.59 v1(6.35,36.96) ; v1(51.69,68.04) U31.B27
  L22_SIGNAL w0.089: v1(51.69,68.04) 52.06,67.67 52.15,67.67 52.18,67.69 52.84,67.69 53.09,67.94 53.09,69.34 52.99,69.44 49.35,69.44 48.62,68.71 40.62,68.71 38.97,67.06 36.3,67.06 35.56,66.32 35.56,64.92 34.9,64.26 22.08,64.26 21.72,63.9 21.72,62.87 22.22,62.36 27.94,62.36 28.45,61.85 28.45,60.83 27.94,60.33 22.22,60.33 21.72,59.82 21.72,41.04 18.14,37.47 6.86,37.47 v1(6.35,36.96)
FMC-1_HB11_P: length 92.2
  TOP w0.102: v1(51.69,67.04) U31.B26 ; 5.71,38.86 v1(6.35,38.23)
  L22_SIGNAL w0.089: v1(6.35,38.23) 6.86,37.72 18.03,37.72 21.46,41.15 21.46,59.92 22.12,60.58 27.83,60.58 28.19,60.94 28.19,61.74 27.83,62.1 22.12,62.1 21.46,62.76 21.46,64.01 21.97,64.52 34.8,64.52 35.31,65.02 35.31,66.42 36.2,67.31 38.86,67.31 40.51,68.96 48.51,68.96 49.24,69.69 53.1,69.69 53.34,69.45 53.34,67.83 52.94,67.44 52.28,67.44 52.26,67.41 52.06,67.41 v1(51.69,67.04)
FMC-1_HB12_N: length 95.8
  TOP w0.102: v1(52.69,70.04) U31.C29 ; P1.F32 v1(10.16,35.69)
  L3_SIGNAL w0.089: v1(10.16,35.69) 9.65,36.19 8.64,36.19 8.26,35.81 8.26,35.43 8.51,35.18 17.29,35.18 17.65,35.54 17.65,35.67 18.31,36.32 26.9,36.32 27.56,35.67 27.56,33.13 27.92,32.77 40.79,32.77 41.15,33.13 41.15,38.5 40.79,38.86 35.58,38.86 34.92,39.52 34.92,43.05 35.94,44.07 35.94,58.4 36.6,59.06 37.72,59.06 38.73,60.07 38.73,63.12 44.26,68.64 50.48,68.64 50.57,68.65 50.58,68.66 50.65,68.66 50.67,68.67 50.81,68.67 51.04,68.89 51.04,69.24 51.46,69.67 52.32,69.67 v1(52.69,70.04)
FMC-1_HB12_P: length 96.6
  TOP w0.102: 9.53,37.59 v1(10.16,36.96) ; v1(52.69,69.04) U31.C28
  L3_SIGNAL w0.089: v1(52.69,69.04) 52.32,69.41 51.57,69.41 51.29,69.14 51.29,68.79 50.89,68.39 50.67,68.39 50.59,68.38 50.58,68.39 50.49,68.39 44.36,68.39 38.99,63.01 38.99,59.97 37.82,58.8 36.7,58.8 36.2,58.29 36.2,43.96 35.18,42.95 35.18,39.62 35.69,39.12 40.89,39.12 41.4,38.61 41.4,33.02 40.89,32.51 27.81,32.51 27.3,33.02 27.3,35.56 26.8,36.07 18.41,36.07 17.91,35.56 17.91,35.43 17.4,34.92 8.4,34.92 8,35.33 8,35.92 8.53,36.45 9.65,36.45 v1(10.16,36.96)
FMC-1_HB13_N: length 96.8
  TOP w0.102: v1(50.69,70.04) U31.A29 ; 10.79,37.59 v1(11.43,36.96)
  L3_SIGNAL w0.089: v1(50.69,70.04) 50.32,69.67 41.34,69.67 37.85,66.17 37.85,60.94 37.49,60.58 34.18,60.58 33.53,59.92 33.53,38.23 34.04,37.72 39.65,37.72 40.01,37.36 40.01,34.01 39.65,33.66 29.06,33.66 28.7,34.01 28.7,37.97 28.19,38.48 25.15,38.48 24.76,38.1 17.89,38.1 17.53,38.46 17.53,39.6 16.87,40.26 11.18,40.26 10.67,39.75 10.67,37.85 11.05,37.47 11.21,37.47 11.3,37.38 11.3,37.08 v1(11.43,36.96)
FMC-1_HB13_P: length 96.1
  TOP w0.102: P1.E30 v1(11.43,38.23) ; v1(50.69,69.04) U31.A28
  L3_SIGNAL w0.089: v1(50.69,69.04) 50.32,69.41 41.45,69.41 38.1,66.06 38.1,60.83 37.59,60.33 34.29,60.33 33.78,59.82 33.78,38.33 34.14,37.97 39.75,37.97 40.26,37.47 40.26,33.91 39.75,33.4 28.96,33.4 28.45,33.91 28.45,37.87 28.09,38.23 25.25,38.23 24.87,37.85 17.78,37.85 17.27,38.35 17.27,39.5 16.76,40 11.28,40 10.92,39.65 10.92,37.95 11.15,37.72 11.3,37.72 11.43,37.85 v1(11.43,38.23)
FMC-1_HB14_N: length 92.1
  TOP w0.102: P1.K35 v1(5.08,31.88) ; v1(53.69,71.04) U31.D30
  L22_SIGNAL w0.089: v1(5.08,31.88) 5.59,32.39 6.73,32.39 7.11,32.77 7.11,34.67 6.6,35.18 6.22,35.18 5.84,35.56 5.84,38.48 6.22,38.86 17.91,38.86 20.45,41.4 20.45,68.35 20.81,68.71 22.5,68.71 23.39,67.82 33.27,67.82 33.78,68.33 33.78,68.83 34.29,69.34 36.81,69.34 38.85,71.39 54.84,71.39 55.04,71.18 55.04,70.85 54.84,70.64 54.09,70.64 v1(53.69,71.04)
FMC-1_HB14_P: length 93
  TOP w0.102: v1(53.69,70.04) U31.D29 ; P1.K34 v1(5.08,33.15)
  L22_SIGNAL w0.089: v1(53.69,70.04) 54.04,70.39 54.94,70.39 55.29,70.74 55.29,71.29 54.94,71.64 38.75,71.64 36.7,69.6 34.18,69.6 33.53,68.94 33.53,68.43 33.17,68.07 23.49,68.07 22.61,68.96 20.7,68.96 20.19,68.45 20.19,41.51 17.8,39.12 6.12,39.12 5.59,38.59 5.59,35.45 6.12,34.92 6.5,34.92 6.86,34.57 6.86,32.87 6.63,32.64 5.59,32.64 v1(5.08,33.15)
FMC-1_HB15_N: length 96.4
  TOP w0.102: v1(50.69,72.04) U31.A31 ; 5.71,33.78 v1(6.35,33.15)
  L20_SIGNAL w0.089: v1(50.69,72.04) 50.32,71.67 49.85,71.67 45.44,76.07 5.1,76.07 1.78,72.75 1.78,36.34 4.47,33.66 6.26,33.66 6.35,33.57 v1(6.35,33.15)
FMC-1_HB15_P: length 95.6
  TOP w0.102: 5.71,35.05 v1(6.35,34.42) ; v1(50.69,71.04) U31.A30
  L20_SIGNAL w0.089: v1(6.35,34.42) 6.35,34 6.26,33.91 4.57,33.91 2.03,36.45 2.03,72.64 5.21,75.82 45.34,75.82 49.75,71.41 50.32,71.41 v1(50.69,71.04)
FMC-1_HB16_N: length 98.1
  TOP w0.102: P1.F35 v1(10.16,31.88) ; v1(54.69,70.04) U31.E29
  L3_SIGNAL w0.089: v1(10.16,31.88) 9.65,32.39 8.51,32.39 8.26,32.64 8.26,33.53 8.64,33.91 18.8,33.91 19.81,34.92 25.38,34.92 26.04,34.27 26.04,32.11 26.39,31.75 42.06,31.75 42.42,32.11 42.42,39.52 42.06,39.88 36.85,39.88 36.2,40.53 36.2,42.27 36.85,42.93 38.12,42.93 38.48,43.29 38.48,54.59 39.14,55.25 39.39,55.25 39.75,55.6 39.75,60.2 47.24,67.69 50.54,67.69 50.55,67.69 52.84,67.69 53.04,67.89 53.04,69.24 53.46,69.67 54.32,69.67 v1(54.69,70.04)
FMC-1_HB16_P: length 97.2
  TOP w0.102: P1.F34 v1(10.16,33.15) ; v1(54.69,69.04) U31.E28
  L3_SIGNAL w0.089: v1(54.69,69.04) 54.32,69.41 53.57,69.41 53.29,69.14 53.29,67.79 52.94,67.44 50.44,67.44 50.44,67.44 47.35,67.44 40.01,60.09 40.01,55.5 39.5,54.99 39.24,54.99 38.73,54.48 38.73,43.18 38.23,42.67 36.96,42.67 36.45,42.16 36.45,40.64 36.96,40.13 42.16,40.13 42.67,39.62 42.67,32 42.16,31.5 26.29,31.5 25.78,32 25.78,34.16 25.27,34.67 19.92,34.67 18.9,33.66 8.74,33.66 8.51,33.42 8.51,32.74 8.61,32.64 9.65,32.64 v1(10.16,33.15)
FMC-1_HB17_N_CC: length 94.5
  TOP w0.102: v1(51.69,71.04) U31.B30 ; P1.K38 v1(5.08,28.07)
  L16_SIGNAL w0.089: v1(5.08,28.07) 5.08,28.49 5.17,28.57 6.71,28.57 7.24,29.1 7.24,35.92 6.58,36.58 4.55,36.58 3.43,37.7 3.43,45.06 2.92,45.57 2.92,46.63 3.81,47.52 3.81,61.74 4.93,62.87 18.14,62.87 25.25,69.98 28.3,69.98 30.71,72.39 51.65,72.39 51.88,72.39 52.09,72.18 52.09,71.44 v1(51.69,71.04)
FMC-1_HB17_P_CC: length 94.9
  TOP w0.102: v1(52.69,71.04) U31.C30 ; v1(5.08,29.34) P1.K37
  L16_SIGNAL w0.089: v1(52.69,71.04) 52.34,71.39 52.34,72.29 51.99,72.64 51.76,72.64 51.76,72.64 30.61,72.64 28.19,70.23 25.15,70.23 18.03,63.12 4.83,63.12 3.56,61.85 3.56,47.62 2.67,46.74 2.67,45.47 3.17,44.96 3.17,37.59 4.45,36.32 6.48,36.32 6.98,35.81 6.98,29.21 6.6,28.83 5.17,28.83 5.08,28.92 v1(5.08,29.34)
FMC-1_HB18_N: length 94.8
  TOP w0.102: 5.71,29.97 v1(6.35,29.34)
  TOP w0.14: v1(57.69,65.04) U31.H24
  L3_SIGNAL w0.089: v1(6.35,29.34) 6.35,29.76 6.26,29.85 5.95,29.85 5.84,29.74 5.84,28.93 5.95,28.83 21.31,28.83 21.72,28.43 21.72,27.03 21.82,26.92 48.92,26.92 49.53,27.54 49.53,59.24 49.93,59.64 57.79,59.64 58.09,59.94 58.09,64.64 v1(57.69,65.04)
FMC-1_HB18_P: length 96.1
  TOP w0.102: 5.71,31.24 v1(6.35,30.61)
  TOP w0.14: v1(58.69,65.04) U31.J24
  L3_SIGNAL w0.089: v1(6.35,30.61) 6.35,30.19 6.26,30.1 5.84,30.1 5.59,29.85 5.59,28.83 5.84,28.57 21.21,28.57 21.46,28.32 21.46,26.92 21.72,26.67 49.02,26.67 49.78,27.43 49.78,59.13 50.04,59.39 57.89,59.39 58.34,59.84 58.34,64.69 v1(58.69,65.04)
FMC-1_HB19_N: length 94.8
  TOP w0.102: P1.E34 v1(11.43,33.15)
  TOP w0.14: v1(57.69,66.04) U31.H25
  L16_SIGNAL w0.089: v1(57.69,66.04) 58.06,66.41 58.06,67.27 58.44,67.64 61.99,67.64 62.34,67.29 62.34,46.72 62.01,46.39 50.04,46.39 49.78,46.13 49.78,40.77 50.29,40.26 51.18,40.26 51.69,39.75 51.69,34.31 51.03,33.66 11.94,33.66 v1(11.43,33.15)
FMC-1_HB19_P: length 93.5
  TOP w0.102: P1.E33 v1(11.43,34.42)
  TOP w0.14: v1(58.69,66.04) U31.J25
  L16_SIGNAL w0.089: v1(11.43,34.42) 11.94,33.91 50.93,33.91 51.44,34.42 51.44,39.65 51.08,40 50.19,40 49.53,40.66 49.53,46.24 49.93,46.64 61.9,46.64 62.09,46.83 62.09,67.18 61.88,67.39 58.55,67.39 58.32,67.16 58.32,66.41 v1(58.69,66.04)
FMC-1_HB20_N: length 97
  TOP w0.102: P1.F38 v1(10.16,28.07)
  TOP w0.14: v1(55.69,66.04) U31.F25
  L22_SIGNAL w0.089: v1(10.16,28.07) 10.16,28.49 10.25,28.57 22.84,28.57 23.85,29.59 45.72,29.59 52.45,36.32 58.44,36.32 58.65,36.32 61.34,39.01 61.34,39.22 61.34,68.03 61.29,68.08 61.29,68.29 60.94,68.64 60.73,68.64 60.68,68.69 56.55,68.69 56.53,68.71 55.37,68.71 55.04,68.38 55.04,66.84 55.37,66.51 55.44,66.44 55.8,66.44 55.9,66.33 56.12,66.33 56.18,66.27 56.18,66.09 56.12,66.02 55.71,66.02 v1(55.69,66.04)
FMC-1_HB20_P: length 95.4
  TOP w0.102: P1.F37 v1(10.16,29.34)
  TOP w0.14: v1(56.69,66.04) U31.G25
  L22_SIGNAL w0.089: v1(10.16,29.34) 10.16,28.92 10.25,28.83 22.73,28.83 23.75,29.85 45.61,29.85 52.35,36.58 58.55,36.58 61.09,39.12 61.09,67.93 61.04,67.97 61.04,68.18 60.84,68.39 60.63,68.39 60.58,68.44 56.44,68.44 56.42,68.45 55.48,68.45 55.29,68.27 55.29,66.94 55.55,66.69 55.9,66.69 56.01,66.59 56.22,66.59 56.69,66.12 v1(56.69,66.04)
FMC-1_HB21_N: length 94
  TOP w0.102: P1.E37 v1(11.43,29.34)
  TOP w0.14: v1(55.69,67.04) U31.F26
  L22_SIGNAL w0.089: v1(11.43,29.34) 11.43,29.76 11.52,29.85 20.45,29.85 20.7,30.1 20.7,30.61 20.95,30.86 28.83,30.86 29.08,31.11 29.08,34.06 29.44,34.42 30.35,34.42 30.61,34.16 30.61,31.5 31.37,30.73 42.8,30.73 51.69,39.62 51.79,39.62 59.67,39.62 60.33,40.28 60.33,67.03 60.29,67.06 60.29,67.29 59.94,67.64 59.72,67.64 59.67,67.69 57.55,67.69 57.54,67.69 56.34,67.69 v1(55.69,67.04)
FMC-1_HB21_P: length 93.5
  TOP w0.102: P1.E36 v1(11.43,30.61)
  TOP w0.14: v1(56.69,67.04) U31.G26
  L22_SIGNAL w0.089: v1(11.43,30.61) 11.43,30.19 11.52,30.1 20.34,30.1 20.45,30.2 20.45,30.71 20.85,31.11 28.72,31.11 28.83,31.22 28.83,34.16 29.34,34.67 30.46,34.67 30.86,34.27 30.86,31.6 31.47,30.99 42.69,30.99 51.58,39.88 51.9,39.88 51.9,39.88 59.56,39.88 60.07,40.39 60.07,66.93 60.04,66.96 60.04,67.18 59.84,67.39 59.61,67.39 59.56,67.44 57.44,67.44 57.44,67.44 56.45,67.44 56.13,67.12 56.13,66.93 56.26,66.8 56.45,66.8 v1(56.69,67.04)
FMC-1_LA00_N_CC: length 92.7
  TOP w0.102: P1.G7 v1(8.89,67.44)
  TOP w0.14: v1(53.69,62.04) U31.D21
  L18_SIGNAL w0.089: v1(8.89,67.44) 9.4,67.95 17,67.95 17.65,68.6 17.65,70.25 18.01,70.61 23.64,70.61 24,70.25 24,69.74 24.66,69.09 37.06,69.09 37.72,69.74 37.72,72.62 37.06,73.28 30.83,73.28 30.61,73.5 30.61,73.82 30.83,74.04 43.07,74.04 43.43,73.68 43.43,65.02 43.94,64.52 44.81,64.52 45.47,65.17 45.47,71.52 45.83,71.88 46.76,71.88 47.12,71.52 47.12,65.02 47.62,64.52 49.3,64.52 49.66,64.16 49.66,64.03 50.31,63.37 50.53,63.37 50.55,63.39 53.84,63.39 54.04,63.18 54.04,62.39 v1(53.69,62.04)
FMC-1_LA00_P_CC: length 93.1
  TOP w0.102: P1.G6 v1(8.89,68.71)
  TOP w0.14: v1(54.69,62.04) U31.E21
  L18_SIGNAL w0.089: v1(8.89,68.71) 9.4,68.2 16.89,68.2 17.4,68.71 17.4,70.36 17.91,70.87 23.75,70.87 24.26,70.36 24.26,69.85 24.76,69.34 36.96,69.34 37.47,69.85 37.47,72.52 36.96,73.03 30.72,73.03 30.35,73.4 30.35,73.92 30.72,74.3 43.18,74.3 43.69,73.79 43.69,65.13 44.05,64.77 44.7,64.77 45.21,65.28 45.21,71.63 45.72,72.14 46.86,72.14 47.37,71.63 47.37,65.13 47.73,64.77 49.4,64.77 49.91,64.26 49.91,64.14 50.42,63.63 50.43,63.63 50.44,63.64 53.94,63.64 54.29,63.29 54.29,62.44 v1(54.69,62.04)
FMC-1_LA01_N_CC: length 91.5
  TOP w0.102: 12.07,65.53 v1(12.7,64.9)
  TOP w0.14: v1(52.69,61.04) U31.C20
  L18_SIGNAL w0.089: v1(12.7,64.9) 12.7,65.32 12.61,65.41 12.3,65.41 12.19,65.3 12.19,64.75 12.55,64.39 19.2,64.39 19.3,64.49 19.3,68.43 19.71,68.83 21.72,68.83 21.97,68.58 21.97,67.31 22.22,67.06 40.13,67.06 40.39,66.8 40.39,64.77 40.13,64.52 32.53,64.52 32.13,64.92 32.13,65.81 32.03,65.91 24.49,65.91 24.38,65.81 24.38,65 24.49,64.9 30.97,64.9 31.37,64.49 31.37,63.61 31.47,63.5 40.51,63.5 40.77,63.25 40.77,60.96 41.02,60.71 46.71,60.71 47.86,59.56 52.36,59.56 52.44,59.64 52.79,59.64 53.04,59.89 53.04,60.55 53.06,60.58 53.06,60.67 v1(52.69,61.04)
FMC-1_LA01_P_CC: length 92.8
  TOP w0.102: 12.07,66.8 v1(12.7,66.17)
  TOP w0.14: v1(53.69,61.04) U31.D20
  L18_SIGNAL w0.089: v1(12.7,66.17) 12.7,65.75 12.61,65.66 12.19,65.66 11.94,65.41 11.94,64.64 12.45,64.14 19.3,64.14 19.56,64.39 19.56,68.33 19.81,68.58 21.61,68.58 21.72,68.47 21.72,67.2 22.12,66.8 40.03,66.8 40.13,66.7 40.13,64.88 40.03,64.77 32.64,64.77 32.38,65.02 32.38,65.91 32.13,66.17 24.38,66.17 24.13,65.91 24.13,64.9 24.38,64.64 30.86,64.64 31.11,64.39 31.11,63.5 31.37,63.25 40.41,63.25 40.51,63.14 40.51,60.85 40.92,60.45 46.61,60.45 47.75,59.31 52.47,59.31 52.55,59.39 52.89,59.39 53.29,59.79 53.29,60.45 53.32,60.47 53.32,60.67 v1(53.69,61.04)
FMC-1_LA02_N: length 96.1
  TOP w0.102: 6.98,66.8 v1(7.62,66.17)
  TOP w0.14: v1(59.69,60.04) U31.K19
  L18_SIGNAL w0.089: v1(7.62,66.17) 7.62,66.55 7.75,66.67 18.01,66.67 18.67,67.33 18.67,69.24 19.03,69.6 22.12,69.6 22.48,69.24 22.48,68.6 23.14,67.95 39.73,67.95 40.13,68.35 40.13,68.86 40.24,68.96 42.57,68.96 42.67,68.86 42.67,66.65 42.57,66.55 41.68,66.55 41.53,66.4 41.53,63.01 42.19,62.36 48.66,62.36 49.63,61.39 55.89,61.39 56.29,61.79 56.29,62.22 56.52,62.44 72.92,62.44 73.03,62.33 73.03,62.2 73.04,62.18 73.04,61.89 73.03,61.88 73.03,61.75 72.92,61.64 60.44,61.64 60.07,61.27 60.07,60.42 v1(59.69,60.04)
FMC-1_LA02_P: length 96.5
  TOP w0.102: 6.98,68.07 v1(7.62,67.44)
  TOP w0.14: v1(60.69,60.04) U31.L19
  L18_SIGNAL w0.089: v1(60.69,60.04) 60.33,60.41 60.33,61.17 60.55,61.39 73.03,61.39 73.28,61.64 73.28,61.77 73.29,61.79 73.29,62.29 73.28,62.3 73.28,62.44 73.03,62.69 56.41,62.69 56.04,62.32 56.04,61.89 55.79,61.64 49.74,61.64 48.77,62.61 42.29,62.61 41.78,63.12 41.78,66.29 42.67,66.29 42.93,66.55 42.93,68.96 42.67,69.22 40.13,69.22 39.88,68.96 39.88,68.45 39.62,68.2 23.24,68.2 22.73,68.71 22.73,69.34 22.22,69.85 18.92,69.85 18.41,69.34 18.41,67.44 17.91,66.93 7.75,66.93 7.62,67.06 v1(7.62,67.44)
FMC-1_LA03_N: length 92.4
  TOP w0.102: P1.G10 v1(8.89,63.63)
  TOP w0.14: v1(60.69,59.04) U31.L18
  L20_SIGNAL w0.089: v1(60.69,59.04) 61.06,59.41 61.06,59.5 61.04,59.53 61.04,59.89 61.04,59.89 61.04,60.24 61.44,60.64 61.81,60.64 62.05,60.89 62.05,65.15 62.04,65.16 62.04,65.18 61.82,65.41 46.61,65.41 46.36,65.66 46.36,67.69 46.61,67.95 49.53,67.95 49.78,68.2 49.78,68.71 49.53,68.96 45.85,68.96 45.59,69.22 45.59,70.48 45.85,70.74 47.12,70.74 47.37,70.99 47.37,71.76 47.12,72.01 43.96,72.01 43.56,72.41 43.56,73 43.96,73.41 44.96,73.41 45.21,73.66 45.21,74.17 44.96,74.42 18.52,74.42 17.53,73.43 17.53,64.66 17,64.14 8.98,64.14 8.89,64.05 v1(8.89,63.63)
FMC-1_LA03_P: length 92.8
  TOP w0.102: P1.G9 v1(8.89,64.9)
  TOP w0.14: v1(61.69,59.04) U31.M18
  L20_SIGNAL w0.089: v1(61.69,59.04) 61.32,59.41 61.32,59.61 61.29,59.63 61.29,59.79 61.29,59.79 61.29,60.14 61.55,60.39 61.91,60.39 62.3,60.78 62.3,65.28 61.92,65.66 46.71,65.66 46.61,65.76 46.61,67.59 46.71,67.69 49.64,67.69 50.04,68.09 50.04,68.81 49.64,69.22 45.95,69.22 45.85,69.32 45.85,70.38 45.95,70.48 47.22,70.48 47.62,70.89 47.62,71.86 47.22,72.26 44.07,72.26 43.82,72.52 43.82,72.9 44.07,73.15 45.06,73.15 45.47,73.55 45.47,74.27 45.06,74.68 18.41,74.68 17.27,73.53 17.27,64.77 16.89,64.39 8.98,64.39 8.89,64.48 v1(8.89,64.9)
FMC-1_LA04_N: length 94.9
  TOP w0.102: 6.98,62.99 v1(7.62,62.36)
  TOP w0.14: v1(57.69,61.04) U31.H20
  L18_SIGNAL w0.089: v1(57.69,61.04) 57.86,61.04 58.04,61.21 58.04,61.33 57.93,61.44 57.55,61.44 57.29,61.18 57.29,59.69 57.55,59.69 58.55,59.69 59.55,59.69 60.55,59.69 61.55,59.69 62.55,59.69 63.55,59.69 64.55,59.69 65.55,59.69 66.55,59.69 68.55,59.69 69.55,59.69 70.55,59.69 71.55,59.69 72.01,59.69 72.26,59.44 72.26,59.32 72.29,59.29 72.29,58.79 72.26,58.76 72.26,58.42 72.01,58.17 46.99,58.17 46.48,58.67 39.52,58.67 39.12,59.08 39.12,61.92 39.01,62.03 31.06,62.03 30.23,62.87 23.64,62.87 23.24,63.27 23.24,65.81 23.14,65.91 20.55,65.91 20.45,65.81 20.45,63.27 20.04,62.87 7.75,62.87 7.62,62.74 v1(7.62,62.36)
FMC-1_LA04_P: length 95.4
  TOP w0.102: 6.98,64.26 v1(7.62,63.63)
  TOP w0.14: v1(58.69,61.04) U31.J20
  L18_SIGNAL w0.089: v1(7.62,63.63) 7.62,63.25 7.75,63.12 19.94,63.12 20.19,63.37 20.19,65.91 20.45,66.17 23.24,66.17 23.49,65.91 23.49,63.37 23.75,63.12 30.33,63.12 31.17,62.28 39.12,62.28 39.37,62.03 39.37,59.18 39.62,58.93 46.59,58.93 47.1,58.42 71.9,58.42 72.01,58.53 72.01,58.86 72.04,58.89 72.04,59.18 72.01,59.22 72.01,59.33 71.9,59.44 71.44,59.44 71.44,59.44 70.94,59.44 70.94,59.44 70.44,59.44 70.44,59.44 69.94,59.44 69.94,59.44 69.44,59.44 69.44,59.44 68.94,59.44 68.94,59.44 68.44,59.44 68.44,59.44 66.94,59.44 66.94,59.44 66.44,59.44 66.44,59.44 65.94,59.44 65.94,59.44 65.44,59.44 65.44,59.44 64.94,59.44 64.94,59.44 64.44,59.44 64.44,59.44 63.94,59.44 63.94,59.44 63.44,59.44 63.44,59.44 62.94,59.44 62.94,59.44 62.44,59.44 62.44,59.44 61.94,59.44 61.94,59.44 61.44,59.44 61.44,59.44 60.94,59.44 60.94,59.44 60.44,59.44 60.44,59.44 59.94,59.44 59.94,59.44 59.44,59.44 59.44,59.44 58.94,59.44 58.94,59.44 58.44,59.44 58.44,59.44 57.94,59.44 57.94,59.44 57.44,59.44 57.44,59.44 57.19,59.44 57.04,59.58 57.04,61.29 57.44,61.69 58.04,61.69 58.29,61.44 58.29,61.3 58.38,61.21 58.52,61.21 v1(58.69,61.04)
FMC-1_LA05_N: length 93.8
  TOP w0.102: 12.07,61.72 v1(12.7,61.09)
  TOP w0.14: v1(58.69,60.04) U31.J19
  L20_SIGNAL w0.089: v1(12.7,61.09) 12.7,61.47 12.83,61.59 30.46,61.59 31.11,62.25 31.11,64.49 30.46,65.15 20.43,65.15 20.07,65.51 20.07,72.03 20.43,72.39 41.04,72.39 41.15,72.28 41.15,70 41.55,69.6 42.69,69.6 43.05,69.24 43.05,62.64 43.31,62.39 59.84,62.39 60.04,62.18 60.04,60.55 59.88,60.39 59.55,60.39 59.34,60.18 59.34,60.1 59.31,60.07 58.72,60.07 v1(58.69,60.04)
FMC-1_LA05_P: length 94.3
  TOP w0.102: 12.07,62.99 v1(12.7,62.36)
  TOP w0.14: v1(59.69,59.04) U31.K18
  L20_SIGNAL w0.089: v1(12.7,62.36) 12.7,61.98 12.83,61.85 30.35,61.85 30.86,62.36 30.86,64.39 30.35,64.9 20.32,64.9 19.81,65.41 19.81,72.14 20.32,72.64 41.15,72.64 41.4,72.39 41.4,70.1 41.66,69.85 42.8,69.85 43.31,69.34 43.31,62.75 43.41,62.64 59.94,62.64 60.29,62.29 60.29,60.44 60.04,60.19 60.04,59.89 59.69,59.54 59.69,59.04 v1(59.69,59.04)
FMC-1_LA06_N: length 92.3
  TOP w0.102: P1.C11 v1(13.97,62.36)
  TOP w0.14: v1(60.69,61.04) U31.L20
  L20_SIGNAL w0.089: v1(60.69,61.04) 61.06,61.41 61.06,63.16 60.84,63.39 50.55,63.39 50.53,63.37 49.3,63.37 48.15,64.52 44.58,64.52 44.32,64.77 44.32,70.74 44.07,70.99 42.95,70.99 42.55,71.4 42.55,73.05 42.44,73.15 19.03,73.15 18.67,72.79 18.67,64.62 19.03,64.26 29.69,64.26 30.1,63.85 30.1,63.27 29.69,62.87 14.1,62.87 13.97,62.74 v1(13.97,62.36)
FMC-1_LA06_P: length 92.7
  TOP w0.102: P1.C10 v1(13.97,63.63)
  TOP w0.14: v1(61.69,61.04) U31.M20
  L20_SIGNAL w0.089: v1(61.69,61.04) 61.32,61.41 61.32,63.27 60.94,63.64 50.44,63.64 50.43,63.63 49.4,63.63 48.26,64.77 44.68,64.77 44.58,64.88 44.58,70.84 44.17,71.25 43.05,71.25 42.8,71.5 42.8,73.15 42.55,73.41 18.92,73.41 18.41,72.9 18.41,64.52 18.92,64.01 29.58,64.01 29.84,63.75 29.84,63.38 29.58,63.12 14.1,63.12 13.97,63.25 v1(13.97,63.63)
FMC-1_LA07_N: length 93.6
  TOP w0.102: 6.98,59.18 v1(7.62,58.55)
  TOP w0.14: v1(56.69,61.04) U31.G20
  L20_SIGNAL w0.089: v1(56.69,61.04) 56.69,60.91 57.03,60.57 57.16,60.57 57.28,60.69 57.84,60.69 58.04,60.89 58.04,61.18 57.84,61.39 49.3,61.39 48.24,60.33 41.8,60.33 41.15,60.98 41.15,66.04 41.4,66.29 41.66,66.29 41.91,66.55 41.91,68.2 41.66,68.45 36.83,68.45 36.58,68.71 36.58,69.49 36.22,69.85 22.84,69.85 22.48,69.49 22.48,66.53 22.84,66.17 31.35,66.17 32,65.51 32,59.56 31.5,59.06 7.75,59.06 7.62,58.93 v1(7.62,58.55)
FMC-1_LA07_P: length 94.3
  TOP w0.102: 6.98,60.45 v1(7.62,59.82)
  TOP w0.14: v1(57.69,60.04) U31.H19
  L20_SIGNAL w0.089: v1(57.69,60.04) 57.63,59.97 57.5,59.97 57.28,60.2 57.28,60.32 57.39,60.44 57.94,60.44 58.29,60.79 58.29,61.29 57.94,61.64 49.2,61.64 48.13,60.58 41.91,60.58 41.4,61.09 41.4,65.93 41.51,66.04 41.76,66.04 42.16,66.44 42.16,68.3 41.76,68.71 36.94,68.71 36.83,68.81 36.83,69.6 36.32,70.1 22.73,70.1 22.22,69.6 22.22,66.42 22.73,65.91 31.24,65.91 31.75,65.41 31.75,59.67 31.39,59.31 7.75,59.31 7.62,59.44 v1(7.62,59.82)
FMC-1_LA08_N: length 93.4
  TOP w0.102: P1.G13 v1(8.89,59.82)
  TOP w0.14: v1(50.69,61.04) U31.A20
  L7_SIGNAL w0.089: v1(50.69,61.04) 50.32,60.67 50.23,60.67 50.19,60.71 49.28,60.71 48.77,61.21 48.77,62.61 48.26,63.12 45.21,63.12 44.7,63.63 44.7,69.34 45.21,69.85 47.1,69.85 47.75,70.51 47.75,75.44 47.24,75.95 40.13,75.95 39.62,75.44 39.62,74.7 40.28,74.04 45.23,74.04 45.59,73.68 45.59,72.11 45.23,71.76 44.09,71.76 43.43,71.1 43.43,66.93 42.93,66.42 39.6,66.42 39.24,66.78 39.24,68.33 38.35,69.22 37.97,69.22 36.4,70.79 v1(36.4,71.19)
  L16_SIGNAL w0.089: v1(8.89,59.82) 8.89,60.2 8.76,60.33 8.26,60.33 8,60.58 8,61.34 8.51,61.85 18.41,61.85 25.27,68.71 32,68.71 34.92,71.63 35.56,71.63 36,71.19 v1(36.4,71.19)
FMC-1_LA08_P: length 92.5
  TOP w0.102: P1.G12 v1(8.89,61.09)
  TOP w0.14: v1(50.69,60.04) U31.A19
  L7_SIGNAL w0.089: v1(50.69,60.04) 50.32,60.41 50.12,60.41 50.08,60.45 49.17,60.45 48.51,61.11 48.51,62.51 48.15,62.87 45.11,62.87 44.45,63.52 44.45,69.45 45.11,70.1 46.99,70.1 47.5,70.61 47.5,75.33 47.14,75.69 40.24,75.69 39.88,75.33 39.88,74.8 40.39,74.3 45.34,74.3 45.85,73.79 45.85,72.01 45.34,71.5 44.2,71.5 43.69,70.99 43.69,66.82 43.03,66.17 39.5,66.17 38.99,66.67 38.99,68.22 38.25,68.96 37.87,68.96 36.22,70.61 v1(35.82,70.61)
  L16_SIGNAL w0.089: v1(35.82,70.61) 35.82,71.01 35.45,71.37 35.03,71.37 32.11,68.45 25.38,68.45 18.52,61.59 8.61,61.59 8.26,61.24 8.26,60.68 8.36,60.58 8.76,60.58 8.89,60.71 v1(8.89,61.09)
FMC-1_LA09_N: length 93.6
  TOP w0.102: 12.07,57.91 v1(12.7,57.28)
  TOP w0.14: v1(53.69,60.04) U31.D19
  L20_SIGNAL w0.089: v1(53.69,60.04) 54.07,60.04 54.1,60.07 54.1,60.22 53.89,60.44 49.49,60.44 48.37,59.31 44.2,59.31 43.69,58.8 39.5,58.8 39.24,59.06 39.24,66.8 38.99,67.06 34.67,67.06 34.42,67.31 34.42,68.58 34.16,68.83 23.9,68.83 23.49,68.42 23.49,67.85 23.9,67.44 33.25,67.44 33.66,67.03 33.66,66.4 33.76,66.29 38.21,66.29 38.61,65.89 38.61,65.15 38.1,64.64 34.78,64.64 34.42,64.28 34.42,58.44 33.76,57.78 12.83,57.78 12.7,57.66 v1(12.7,57.28)
FMC-1_LA09_P: length 93.9
  TOP w0.102: 12.07,59.18 v1(12.7,58.55)
  TOP w0.14: v1(54.69,60.04) U31.E19
  L20_SIGNAL w0.089: v1(12.7,58.55) 12.7,58.17 12.83,58.04 33.66,58.04 34.16,58.55 34.16,64.39 34.67,64.9 37.99,64.9 38.35,65.26 38.35,65.79 38.1,66.04 33.66,66.04 33.4,66.29 33.4,66.93 33.15,67.18 23.8,67.18 23.24,67.74 23.24,68.53 23.8,69.09 34.27,69.09 34.67,68.69 34.67,67.42 34.78,67.31 39.09,67.31 39.5,66.91 39.5,59.16 39.6,59.06 43.58,59.06 44.09,59.56 48.26,59.56 49.39,60.69 53.99,60.69 54.36,60.33 54.36,60.16 54.44,60.07 54.66,60.07 v1(54.69,60.04)
FMC-1_LA10_N: length 95.6
  TOP w0.102: P1.C15 v1(13.97,57.28)
  TOP w0.14: v1(50.69,62.04) U31.A21
  L7_SIGNAL w0.089: v1(39.03,69.56) 39.4,69.56 40.01,68.96 40.75,68.96 41.4,69.62 41.4,71.35 40.75,72.01 35.03,72.01 34.01,73.03 31.11,73.03 30.61,73.53 30.61,77.34 31.11,77.85 49.04,77.85 49.4,77.49 49.4,68.3 49.04,67.95 47.01,67.95 46.36,67.29 46.36,65.43 47.01,64.77 49.55,64.77 51.05,63.27 51.05,62.4 v1(50.69,62.04)
  L16_SIGNAL w0.089: v1(39.03,69.56) 39.03,69.96 38.5,70.48 38.33,70.48 38.23,70.38 38.23,67.2 37.7,66.67 27.05,66.67 18.16,57.78 14.06,57.78 13.97,57.7 v1(13.97,57.28)
FMC-1_LA10_P: length 96.1
  TOP w0.102: P1.C14 v1(13.97,58.55)
  TOP w0.14: v1(51.69,62.04) U31.B21
  L7_SIGNAL w0.089: v1(51.69,62.04) 51.31,62.42 51.31,63.37 49.66,65.02 47.12,65.02 46.61,65.53 46.61,67.18 47.12,67.69 49.15,67.69 49.66,68.2 49.66,77.6 49.15,78.11 31.01,78.11 30.35,77.45 30.35,73.43 31.01,72.77 33.91,72.77 34.92,71.76 40.64,71.76 41.15,71.25 41.15,69.72 40.64,69.22 40.11,69.22 39.6,69.72 v1(39.6,70.14)
  L16_SIGNAL w0.089: v1(39.6,70.14) 39.21,70.14 38.61,70.74 38.23,70.74 37.97,70.48 37.97,67.31 37.59,66.93 26.95,66.93 18.06,58.04 14.06,58.04 13.97,58.13 v1(13.97,58.55)
FMC-1_LA11_N: length 95
  TOP w0.102: P1.H17 v1(7.62,54.74)
  TOP w0.14: v1(51.69,61.04) U31.B20
  L7_SIGNAL w0.089: v1(51.69,61.04) 52.04,60.69 52.84,60.69 53.09,60.94 53.09,61.34 52.99,61.44 50.19,61.44 49.53,62.09 49.53,63.47 49.17,63.83 46.12,63.83 45.47,64.49 45.47,68.58 45.97,69.09 47.88,69.09 48.39,69.6 48.39,76.48 48.03,76.84 38.84,76.84 38.48,76.48 38.48,73.51 38.84,73.15 41.89,73.15 42.55,72.5 42.55,67.7 41.89,67.04 41.31,67.04 41.17,67.18 v1(40.78,67.18)
  L16_SIGNAL w0.089: v1(7.62,54.74) 7.62,55.16 7.71,55.25 10.52,55.25 10.92,55.65 10.92,56.41 11.03,56.52 18.52,56.52 18.67,56.66 18.67,57.02 27.3,65.66 32.15,65.66 32.26,65.55 32.26,64.92 32.66,64.52 39.09,64.52 39.24,64.66 39.24,64.79 39.62,65.17 39.62,67.59 39.86,67.82 40.53,67.82 40.78,67.58 v1(40.78,67.18)
FMC-1_LA11_P: length 95.6
  TOP w0.102: P1.H16 v1(7.62,56.01)
  TOP w0.14: v1(52.69,60.04) U31.C19
  L7_SIGNAL w0.089: v1(41.35,67.76) 41.35,67.36 41.41,67.3 41.78,67.3 42.29,67.81 42.29,72.39 41.78,72.9 38.73,72.9 38.23,73.41 38.23,76.58 38.73,77.09 48.13,77.09 48.64,76.58 48.64,69.49 47.98,68.83 46.08,68.83 45.72,68.47 45.72,64.59 46.23,64.08 49.28,64.08 49.78,63.57 49.78,62.2 50.29,61.69 52.89,61.69 52.99,61.69 53.1,61.69 53.27,61.52 53.34,61.45 53.34,60.83 52.94,60.44 52.39,60.44 52.37,60.41 52.37,60.36 v1(52.69,60.04)
  L16_SIGNAL w0.089: v1(41.35,67.76) 40.96,67.76 40.64,68.07 39.75,68.07 39.37,67.69 39.37,65.28 38.99,64.9 38.99,64.77 32.77,64.77 32.51,65.02 32.51,65.66 32.26,65.91 27.2,65.91 18.41,57.13 18.41,56.77 10.92,56.77 10.67,56.52 10.67,55.75 10.41,55.5 7.71,55.5 7.62,55.59 v1(7.62,56.01)
FMC-1_LA12_N: length 92.5
  TOP w0.102: P1.G16 v1(8.89,56.01)
  TOP w0.14: v1(55.69,61.04) U31.F20
  L7_SIGNAL w0.089: v1(47.92,66.51) 48.32,66.51 48.83,66 49.42,65.41 56.92,65.41 57.04,65.28 57.04,60.89 56.79,60.64 56.09,60.64 v1(55.69,61.04)
  L16_SIGNAL w0.089: v1(47.92,66.51) 47.92,66.91 47.24,67.59 47.24,68.33 47.61,68.69 51.84,68.69 52.04,68.89 52.04,69.25 52.07,69.28 52.07,69.91 52.04,69.94 52.04,70.18 51.84,70.39 51.55,70.39 51.52,70.36 50.87,70.36 50.84,70.39 50.55,70.39 50.52,70.36 49.78,70.36 49.53,70.61 49.53,71.37 49.28,71.63 48.9,71.63 48.64,71.37 48.64,70.61 48.39,70.36 47.5,70.36 47.24,70.61 47.24,71.01 46.88,71.37 46.36,71.37 45.85,70.87 45.85,67.95 45.34,67.44 44.7,67.44 44.2,67.95 44.2,71.01 43.84,71.37 43.16,71.37 42.8,71.01 42.8,69.09 42.29,68.58 41.78,68.58 41.28,69.09 41.28,70.87 40.64,71.5 37.7,71.5 37.34,71.14 37.34,68.09 36.68,67.44 26.52,67.44 18.14,59.06 9.76,59.06 9.65,58.95 9.65,56.92 9.25,56.52 8.98,56.52 8.89,56.43 v1(8.89,56.01)
FMC-1_LA12_P: length 93.3
  TOP w0.102: P1.G15 v1(8.89,57.28)
  TOP w0.14: v1(55.69,60.04) U31.F19
  L7_SIGNAL w0.089: v1(48.5,67.09) 48.5,66.69 49.53,65.66 57.02,65.66 57.29,65.39 57.29,60.79 56.89,60.39 56.04,60.39 v1(55.69,60.04)
  L16_SIGNAL w0.089: v1(48.5,67.09) 48.1,67.09 47.5,67.69 47.5,68.22 47.71,68.44 51.94,68.44 52.29,68.79 52.29,69.15 52.32,69.17 52.32,70.01 52.32,70.02 52.29,70.05 52.29,70.29 51.94,70.64 51.44,70.64 51.41,70.61 50.97,70.61 50.94,70.64 50.44,70.64 50.41,70.61 49.89,70.61 49.78,70.72 49.78,71.48 49.38,71.88 48.79,71.88 48.39,71.48 48.39,70.72 48.28,70.61 47.6,70.61 47.5,70.72 47.5,71.12 46.99,71.63 46.25,71.63 45.59,70.97 45.59,68.05 45.23,67.69 44.81,67.69 44.45,68.05 44.45,71.12 43.94,71.63 43.05,71.63 42.55,71.12 42.55,69.19 42.19,68.83 41.89,68.83 41.53,69.19 41.53,70.97 40.75,71.76 37.59,71.76 37.08,71.25 37.08,68.2 36.58,67.69 26.42,67.69 18.03,59.31 9.65,59.31 9.4,59.06 9.4,57.02 9.14,56.77 8.98,56.77 8.89,56.86 v1(8.89,57.28)
FMC-1_LA13_N: length 94.3
  TOP w0.102: 12.07,54.1 v1(12.7,53.47)
  TOP w0.14: v1(56.69,64.04) U31.G23
  L16_SIGNAL w0.089: v1(12.7,53.47) 12.7,53.89 12.61,53.98 12.19,53.98 11.98,54.19 11.98,55.03 12.45,55.5 18.41,55.5 24.38,61.47 35.33,61.47 35.43,61.57 35.43,62.12 35.33,62.23 26.42,62.23 26.16,62.48 26.16,62.97 26.56,63.37 27.05,63.37 27.3,63.63 27.3,64.9 27.56,65.15 27.92,65.15 28.32,64.75 28.32,63.35 28.43,63.25 28.7,63.25 28.96,63.5 28.96,65.02 29.21,65.28 29.84,65.28 30.1,65.02 30.1,63.35 30.2,63.25 30.5,63.25 30.61,63.35 30.61,64.75 31.01,65.15 31.37,65.15 31.62,64.9 31.62,64.26 31.88,64.01 36.17,64.01 36.58,63.61 36.58,63.5 36.83,63.25 40.53,63.25 40.64,63.35 40.64,63.73 41.04,64.14 41.66,64.14 41.91,63.88 41.91,62.36 42.16,62.1 42.69,62.1 42.8,62.21 42.8,62.84 43.2,63.25 45.19,63.25 45.59,62.84 45.59,61.7 45.7,61.59 46.25,61.59 46.36,61.7 46.36,62.08 46.76,62.48 47.35,62.48 47.75,62.08 47.75,61.7 47.86,61.59 48.41,61.59 48.51,61.7 48.51,65.15 49.02,65.66 55.91,65.66 55.93,65.64 55.94,65.64 56.29,65.29 56.29,62.89 56.55,62.64 56.79,62.64 57.04,62.89 57.04,63.55 57.06,63.58 57.06,63.67 v1(56.69,64.04)
FMC-1_LA13_P: length 93.9
  TOP w0.102: 12.07,55.37 v1(12.7,54.74)
  TOP w0.14: v1(57.69,64.04) U31.H23
  L16_SIGNAL w0.089: v1(12.7,54.74) 12.7,54.32 12.61,54.23 12.3,54.23 12.23,54.29 12.23,54.93 12.55,55.25 18.52,55.25 24.49,61.21 35.43,61.21 35.69,61.47 35.69,62.23 35.43,62.48 26.52,62.48 26.42,62.59 26.42,62.87 26.67,63.12 27.16,63.12 27.56,63.52 27.56,64.79 27.66,64.9 27.81,64.9 28.07,64.64 28.07,63.25 28.32,62.99 28.81,62.99 29.21,63.39 29.21,64.92 29.32,65.02 29.74,65.02 29.84,64.92 29.84,63.25 30.1,62.99 30.61,62.99 30.86,63.25 30.86,64.64 31.11,64.9 31.26,64.9 31.37,64.79 31.37,64.16 31.77,63.75 36.07,63.75 36.32,63.5 36.32,63.39 36.72,62.99 40.64,62.99 40.89,63.25 40.89,63.63 41.15,63.88 41.55,63.88 41.66,63.78 41.66,62.25 42.06,61.85 42.8,61.85 43.05,62.1 43.05,62.74 43.31,62.99 45.09,62.99 45.34,62.74 45.34,61.59 45.59,61.34 46.36,61.34 46.61,61.59 46.61,61.98 46.86,62.23 47.24,62.23 47.5,61.98 47.5,61.59 47.75,61.34 48.51,61.34 48.77,61.59 48.77,65.05 49.13,65.41 55.81,65.41 55.82,65.39 55.84,65.39 56.04,65.18 56.04,62.79 56.44,62.39 56.89,62.39 57.29,62.79 57.29,63.45 57.32,63.47 57.32,63.67 v1(57.69,64.04)
FMC-1_LA14_N: length 93.7
  TOP w0.102: 13.34,52.83 v1(13.97,52.2)
  TOP w0.14: v1(58.69,62.04) U31.J21
  L16_SIGNAL w0.089: v1(58.69,62.04) 59.07,61.66 59.07,60.92 58.65,60.51 58.01,60.51 57.94,60.44 54.44,60.44 54.09,60.79 54.09,62.15 53.85,62.39 53.55,62.39 53.34,62.18 53.34,60.69 53.09,60.44 52.35,60.44 52.2,60.58 52.2,60.68 52.09,60.79 52.09,63.12 51.83,63.37 51.41,63.37 51.31,63.27 51.31,60.58 51.16,60.44 50.27,60.44 50.16,60.33 50.16,58.44 49.76,58.04 43.94,58.04 43.69,58.29 43.69,58.8 43.43,59.05 28.57,59.05 28.07,58.55 28.07,56.77 27.81,56.52 24.53,56.52 24.38,56.37 24.38,56.16 24.53,56.01 27.81,56.01 28.07,55.75 28.07,54.99 27.81,54.74 21.7,54.74 21.59,54.63 21.59,54.21 21.7,54.1 27.66,54.1 28.07,53.7 28.07,52.96 27.81,52.7 24.11,52.7 24,52.6 24,52.07 24.26,51.82 26.16,51.82 26.42,51.56 26.42,50.95 26.01,50.55 23.24,50.55 22.99,50.8 22.99,52.45 22.73,52.7 14.06,52.7 13.97,52.62 v1(13.97,52.2)
FMC-1_LA14_P: length 94.5
  TOP w0.102: P1.C18 v1(13.97,53.47)
  TOP w0.14: v1(59.69,62.04) U31.K21
  L16_SIGNAL w0.089: v1(13.97,53.47) 13.97,53.05 14.06,52.96 22.84,52.96 23.24,52.56 23.24,50.91 23.35,50.8 25.91,50.8 26.16,51.05 26.16,51.46 26.06,51.56 24.15,51.56 23.75,51.96 23.75,52.7 24,52.96 27.71,52.96 27.81,53.06 27.81,53.59 27.56,53.85 21.59,53.85 21.34,54.1 21.34,54.74 21.59,54.99 27.71,54.99 27.81,55.1 27.81,55.65 27.71,55.75 24.43,55.75 24.13,56.05 24.13,56.47 24.43,56.77 27.71,56.77 27.81,56.87 27.81,58.65 28.47,59.31 43.54,59.31 43.94,58.91 43.94,58.4 44.05,58.29 49.66,58.29 49.91,58.55 49.91,60.44 50.16,60.69 51.05,60.69 51.05,63.37 51.31,63.63 51.94,63.63 52.34,63.22 52.34,60.89 52.45,60.78 52.45,60.69 52.98,60.69 53.09,60.8 53.09,62.29 53.44,62.64 53.95,62.64 54.34,62.25 54.34,60.89 54.55,60.69 57.84,60.69 58.34,61.2 58.34,62.18 58.42,62.26 58.42,62.36 58.51,62.45 59.6,62.45 59.69,62.36 v1(59.69,62.04)
FMC-1_LA15_N: length 94.3
  TOP w0.102: P1.H20 v1(7.62,50.93)
  TOP w0.14: v1(58.69,63.04) U31.J22
  L16_SIGNAL w0.089: v1(7.62,50.93) 7.62,51.35 7.71,51.44 21.84,51.44 22.1,51.18 22.1,49.78 22.35,49.53 27.18,49.53 27.43,49.78 27.43,51.08 27.54,51.18 28.55,51.18 28.96,51.58 28.96,57.53 29.21,57.78 33.31,57.78 33.69,58.17 35.45,58.17 35.84,57.78 42.93,57.78 43.31,57.4 58.04,57.4 58.29,57.66 58.29,58.42 58.04,58.67 51.28,58.67 51.05,58.9 51.05,59.21 51.28,59.44 56.94,59.44 56.94,59.44 57.44,59.44 57.44,59.44 60.96,59.44 61.34,59.82 61.34,66.42 61.09,66.67 59.32,66.67 59.06,66.42 59.06,63.41 v1(58.69,63.04)
FMC-1_LA15_P: length 93
  TOP w0.102: 6.98,52.83 v1(7.62,52.2)
  TOP w0.14: v1(59.69,63.04) U31.K22
  L16_SIGNAL w0.089: v1(59.69,63.04) 59.32,63.41 59.32,66.32 59.42,66.42 60.98,66.42 61.09,66.32 61.09,59.92 60.85,59.69 57.55,59.69 51.17,59.69 50.8,59.32 50.8,58.79 51.17,58.42 57.93,58.42 58.04,58.31 58.04,57.76 57.93,57.66 43.41,57.66 43.03,58.04 35.94,58.04 35.56,58.42 33.59,58.42 33.21,58.04 29.1,58.04 28.7,57.64 28.7,51.69 28.45,51.44 27.43,51.44 27.18,51.18 27.18,49.89 27.07,49.78 22.46,49.78 22.35,49.89 22.35,51.29 21.95,51.69 7.71,51.69 7.62,51.78 v1(7.62,52.2)
FMC-1_LA16_N: length 93.4
  TOP w0.102: 8.26,52.83 v1(8.89,52.2)
  TOP w0.14: v1(53.69,63.04) U31.D22
  L16_SIGNAL w0.089: v1(53.69,63.04) 54.1,63.45 54.1,64.16 53.74,64.52 52.02,64.52 51.94,64.44 51.44,64.44 51.36,64.52 50.14,64.52 49.85,64.22 49.85,61.28 49.02,60.45 48.64,60.45 48.39,60.2 48.39,59.18 48.13,58.93 47.24,58.93 46.99,59.18 46.99,60.2 46.74,60.45 46.1,60.45 45.85,60.2 45.85,59.18 45.59,58.93 44.7,58.93 44.45,59.18 44.45,62.12 44.34,62.23 44.07,62.23 43.82,61.98 43.82,60.71 43.56,60.45 41.02,60.45 40.77,60.71 40.77,61.98 40.51,62.23 40.11,62.23 40.01,62.12 40.01,60.2 39.75,59.94 38.99,59.94 38.73,60.2 38.73,62.25 38.63,62.36 38.06,62.36 37.8,62.1 37.8,60.83 37.72,60.75 37.72,60.71 37.47,60.45 27.56,60.45 27.3,60.2 27.3,57.66 27.05,57.4 26.56,57.4 26.16,57.81 26.16,60.47 26.06,60.58 25.76,60.58 25.65,60.47 25.65,57.74 25.32,57.4 24.85,57.4 24.51,57.74 24.51,59.71 24.41,59.82 23.98,59.82 23.88,59.71 23.88,57.55 23.73,57.4 21.7,57.4 21.59,57.3 21.59,56.87 21.7,56.77 23.35,56.77 23.75,56.37 23.75,55.88 23.49,55.63 21.21,55.63 20.95,55.37 20.95,53.59 20.7,53.34 20.07,53.34 19.81,53.59 19.81,54.23 19.56,54.48 19.3,54.48 19.05,54.23 19.05,53.59 18.8,53.34 17.8,53.34 17.4,53.74 17.4,53.87 17.29,53.98 13.72,53.98 13.46,53.72 13.46,53.09 13.08,52.7 11.2,52.7 10.79,53.11 10.79,54 10.69,54.1 10.03,54.1 9.78,53.85 9.78,52.96 9.53,52.7 8.98,52.7 8.89,52.62 v1(8.89,52.2)
FMC-1_LA16_P: length 93.8
  TOP w0.102: P1.G18 v1(8.89,53.47)
  TOP w0.14: v1(54.69,63.04) U31.E22
  L16_SIGNAL w0.089: v1(8.89,53.47) 8.89,53.05 8.98,52.96 9.42,52.96 9.53,53.06 9.53,53.95 9.93,54.36 10.79,54.36 11.05,54.1 11.05,53.21 11.3,52.96 12.98,52.96 13.21,53.19 13.21,53.83 13.61,54.23 17.4,54.23 17.65,53.98 17.65,53.85 17.91,53.59 18.69,53.59 18.8,53.7 18.8,54.33 19.2,54.74 19.66,54.74 20.07,54.33 20.07,53.7 20.17,53.59 20.6,53.59 20.7,53.7 20.7,55.48 21.1,55.88 23.39,55.88 23.49,55.99 23.49,56.26 23.24,56.52 21.59,56.52 21.34,56.77 21.34,57.4 21.59,57.66 23.62,57.66 23.62,59.82 23.88,60.07 24.51,60.07 24.76,59.82 24.76,57.84 24.95,57.66 25.21,57.66 25.4,57.84 25.4,60.58 25.65,60.83 26.16,60.83 26.42,60.58 26.42,57.91 26.67,57.66 26.95,57.66 27.05,57.76 27.05,60.3 27.45,60.71 37.36,60.71 37.47,60.81 37.47,60.86 37.55,60.94 37.55,62.21 37.95,62.61 38.73,62.61 38.99,62.36 38.99,60.3 39.09,60.2 39.65,60.2 39.75,60.3 39.75,62.23 40.01,62.48 40.62,62.48 41.02,62.08 41.02,60.81 41.13,60.71 43.46,60.71 43.56,60.81 43.56,62.08 43.96,62.48 44.45,62.48 44.7,62.23 44.7,59.29 44.81,59.18 45.49,59.18 45.59,59.29 45.59,60.3 46,60.71 46.84,60.71 47.24,60.3 47.24,59.29 47.35,59.18 48.03,59.18 48.13,59.29 48.13,60.3 48.54,60.71 48.92,60.71 49.59,61.38 49.59,64.33 50.04,64.77 51.47,64.77 51.55,64.69 51.84,64.69 51.92,64.77 53.85,64.77 54.36,64.26 54.36,63.37 v1(54.69,63.04)
FMC-1_LA17_N_CC: length 93.2
  TOP w0.102: v1(55.69,55.04) U31.F15 ; 12.07,50.29 v1(12.7,49.66)
  L18_SIGNAL w0.089: v1(12.7,49.66) 12.19,50.17 11.18,50.17 10.67,50.67 10.67,55.25 10.92,55.5 32.15,55.5 32.26,55.6 32.26,56.03 32.15,56.13 17.53,56.13 17.27,56.39 17.27,57.02 17.53,57.28 33.27,57.28 33.53,57.02 33.53,55.5 35.31,55.5 35.56,55.25 35.56,54.48 35.81,54.23 43.29,54.23 43.82,53.69 44.7,53.69 44.96,53.94 44.96,54.61 45.21,54.86 46.48,54.86 46.74,54.61 46.74,53.94 46.99,53.69 48.39,53.69 48.64,53.94 48.64,54.61 48.9,54.86 50.8,54.86 51.05,54.61 51.05,53.94 51.31,53.69 55.85,53.69 56.06,53.91 56.06,54.67 v1(55.69,55.04)
FMC-1_LA17_P_CC: length 92.7
  TOP w0.102: 12.07,51.56 v1(12.7,50.93)
  TOP w0.14: v1(56.69,55.04) U31.G15
  L18_SIGNAL w0.089: v1(56.69,55.04) 56.32,54.67 56.32,53.8 55.95,53.44 51.2,53.44 50.8,53.84 50.8,54.5 50.69,54.61 49,54.61 48.9,54.5 48.9,53.84 48.49,53.44 46.88,53.44 46.48,53.84 46.48,54.5 46.38,54.61 45.32,54.61 45.21,54.5 45.21,53.84 44.81,53.44 43.72,53.44 43.18,53.98 35.71,53.98 35.31,54.38 35.31,55.14 35.2,55.25 33.42,55.25 33.27,55.39 33.27,56.92 33.17,57.02 17.63,57.02 17.53,56.92 17.53,56.49 17.63,56.39 32.26,56.39 32.51,56.13 32.51,55.5 32.26,55.25 11.03,55.25 10.92,55.14 10.92,50.78 11.28,50.42 12.19,50.42 v1(12.7,50.93)
FMC-1_LA18_N_CC: length 93.8
  TOP w0.102: v1(55.69,56.04) U31.F16 ; P1.C23 v1(13.97,47.12)
  L16_SIGNAL w0.089: v1(55.69,56.04) 56.06,55.67 56.06,54.92 55.84,54.69 45.11,54.69 44.7,54.29 44.7,53.83 44.6,53.72 34.31,53.72 33.91,53.32 33.91,44.81 33.8,44.7 27.79,44.7 27.43,45.06 27.43,45.49 27.79,45.85 32.51,45.85 33.02,46.36 33.02,46.84 32.62,47.24 26.44,47.24 26.04,46.84 26.04,41.25 25.68,40.89 23.88,40.89 23.37,41.4 23.37,47.27 22.88,47.75 22.2,47.75 21.72,47.27 21.72,44.07 21.46,43.81 20.32,43.81 20.07,44.07 20.07,48.75 19.66,49.15 18.94,49.15 18.54,48.75 18.54,47.6 18.44,47.5 17.5,47.5 17.4,47.6 17.4,48.75 17,49.15 13.46,49.15 13.21,48.89 13.21,47.88 13.46,47.62 13.88,47.62 13.97,47.54 v1(13.97,47.12)
FMC-1_LA18_P_CC: length 93.3
  TOP w0.102: v1(56.69,56.04) U31.G16 ; P1.C22 v1(13.97,48.39)
  L16_SIGNAL w0.089: v1(13.97,48.39) 13.97,47.97 13.88,47.88 13.57,47.88 13.46,47.98 13.46,48.79 13.57,48.89 16.89,48.89 17.14,48.64 17.14,47.5 17.4,47.24 18.54,47.24 18.8,47.5 18.8,48.64 19.05,48.89 19.56,48.89 19.81,48.64 19.81,43.96 20.21,43.56 21.57,43.56 21.97,43.96 21.97,47.16 22.31,47.5 22.78,47.5 23.11,47.16 23.11,41.3 23.77,40.64 25.78,40.64 26.29,41.15 26.29,46.74 26.54,46.99 32.51,46.99 32.77,46.74 32.77,46.46 32.41,46.1 27.69,46.1 27.18,45.59 27.18,44.96 27.69,44.45 33.91,44.45 34.16,44.7 34.16,53.21 34.42,53.47 44.7,53.47 44.96,53.72 44.96,54.18 45.21,54.44 55.94,54.44 56.32,54.81 56.32,55.67 v1(56.69,56.04)
FMC-1_LA19_N: length 95
  TOP w0.102: P1.H23 v1(7.62,47.12) ; v1(57.69,55.04) U31.H15
  L16_SIGNAL w0.089: v1(7.62,47.12) 7.62,47.5 7.75,47.62 9.01,47.62 9.51,48.13 9.51,49.54 10.14,50.17 20.45,50.17 20.7,49.91 20.7,48.89 20.95,48.64 29.72,48.64 29.97,48.89 29.97,56.13 30.23,56.39 31.24,56.39 31.5,56.13 31.5,48.39 31.75,48.13 32.64,48.13 32.89,48.39 32.89,56.05 33.15,56.31 42.67,56.31 42.93,56.05 42.93,55.5 42.67,55.25 37.47,55.25 37.21,54.99 37.21,54.48 37.47,54.23 44.07,54.23 44.32,54.48 44.32,56.05 44.58,56.31 52.46,56.31 52.55,56.39 57.84,56.39 58.04,56.18 58.04,55.52 58.06,55.5 58.06,55.41 v1(57.69,55.04)
FMC-1_LA19_P: length 95.4
  TOP w0.102: P1.H22 v1(7.62,48.39) ; v1(58.69,55.04) U31.J15
  L16_SIGNAL w0.089: v1(7.62,48.39) 7.62,48.01 7.75,47.88 8.9,47.88 9.26,48.23 9.26,49.64 10.03,50.42 20.55,50.42 20.95,50.02 20.95,49 21.06,48.89 29.61,48.89 29.72,49 29.72,56.24 30.12,56.64 31.35,56.64 31.75,56.24 31.75,48.49 31.86,48.39 32.53,48.39 32.64,48.49 32.64,56.16 33.04,56.56 42.78,56.56 43.18,56.16 43.18,55.39 42.78,54.99 37.57,54.99 37.47,54.89 37.47,54.59 37.57,54.48 43.96,54.48 44.07,54.59 44.07,56.16 44.47,56.56 52.36,56.56 52.44,56.64 57.94,56.64 58.29,56.29 58.29,55.63 58.32,55.61 58.32,55.41 v1(58.69,55.04)
FMC-1_LA20_N: length 95.7
  TOP w0.102: v1(60.69,55.04) U31.L15 ; P1.G22 v1(8.89,48.39)
  L18_SIGNAL w0.089: v1(60.69,55.04) 60.34,55.39 43.96,55.39 43.56,54.99 36.34,54.99 36.2,55.14 36.2,59.2 36.09,59.31 33.89,59.31 33.78,59.2 33.78,58.19 33.38,57.78 20.15,57.78 19.81,58.12 19.81,58.59 20.15,58.93 32.28,58.93 32.38,59.03 32.38,59.33 32.28,59.44 18.14,59.44 18.03,59.33 18.03,58.19 17.63,57.78 9.91,57.78 9.65,57.53 9.65,49.28 9.4,49.02 9.11,49.02 9.02,48.93 9.02,48.51 v1(8.89,48.39)
FMC-1_LA20_P: length 96.6
  TOP w0.102: P1.G21 v1(8.89,49.66) ; v1(61.69,55.04) U31.M15
  L18_SIGNAL w0.089: v1(61.69,55.04) 61.09,55.64 43.85,55.64 43.46,55.25 36.45,55.25 36.45,59.31 36.2,59.56 33.78,59.56 33.53,59.31 33.53,58.29 33.27,58.04 20.25,58.04 20.07,58.22 20.07,58.49 20.25,58.67 32.38,58.67 32.64,58.93 32.64,59.44 32.38,59.69 18.03,59.69 17.78,59.44 17.78,58.29 17.53,58.04 9.8,58.04 9.4,57.64 9.4,49.38 9.29,49.28 9.02,49.28 8.89,49.4 v1(8.89,49.66)
FMC-1_LA21_N: length 92.8
  TOP w0.102: v1(61.69,56.04) U31.M16 ; P1.H26 v1(7.62,43.31)
  L18_SIGNAL w0.089: v1(61.69,56.04) 61.32,56.41 38.5,56.41 38.1,56.81 38.1,60.22 37.99,60.33 30.37,60.33 29.97,60.73 29.97,61.62 29.87,61.72 29.06,61.72 28.96,61.62 28.96,60.73 28.55,60.33 27.56,60.33 27.3,60.58 27.3,61.85 27.05,62.1 26.14,62.1 26.04,62 26.04,60.73 25.63,60.33 25.17,60.33 24.76,60.73 24.76,62 24.66,62.1 24,62.1 23.75,61.85 23.75,60.58 23.49,60.33 22.73,60.33 22.48,60.58 22.48,64.64 22.22,64.9 21.59,64.9 21.34,64.64 21.34,60.58 21.08,60.33 8.74,60.33 8.38,59.97 8.38,44.09 8.11,43.81 7.62,43.81 v1(7.62,43.31)
FMC-1_LA21_P: length 92.7
  TOP w0.102: v1(61.69,57.04) U31.M17 ; P1.H25 v1(7.62,44.58)
  L18_SIGNAL w0.089: v1(7.62,44.58) 7.62,44.16 7.71,44.07 8,44.07 8.13,44.2 8.13,60.07 8.64,60.58 20.98,60.58 21.08,60.68 21.08,64.75 21.48,65.15 22.33,65.15 22.73,64.75 22.73,60.68 22.84,60.58 23.39,60.58 23.49,60.68 23.49,61.95 23.9,62.36 24.76,62.36 25.02,62.1 25.02,60.83 25.27,60.58 25.53,60.58 25.78,60.83 25.78,62.1 26.04,62.36 27.16,62.36 27.56,61.95 27.56,60.68 27.66,60.58 28.45,60.58 28.7,60.83 28.7,61.72 28.96,61.98 29.97,61.98 30.23,61.72 30.23,60.83 30.48,60.58 38.1,60.58 38.35,60.33 38.35,56.92 38.61,56.67 61.32,56.67 v1(61.69,57.04)
FMC-1_LA22_N: length 93
  TOP w0.102: P1.G25 v1(8.89,44.58) ; v1(59.69,54.04) U31.K14
  L16_SIGNAL w0.089: v1(8.89,44.58) 8.89,45 8.8,45.08 8.51,45.08 8.26,45.34 8.26,46.23 8.64,46.61 10.67,46.61 10.92,46.36 10.92,41.63 11.03,41.53 16.74,41.53 17.4,40.87 17.4,40.64 17.91,40.13 19.3,40.13 19.81,39.62 19.81,38.33 20.17,37.97 44.34,37.97 44.7,38.33 44.7,38.61 44.2,39.12 37.47,39.12 37.21,39.37 37.21,40.39 37.47,40.64 44.2,40.64 44.7,41.15 44.7,42.19 44.2,42.69 44.2,49.15 44.7,49.66 58.82,49.66 59.09,49.92 59.09,52.4 59.33,52.64 59.79,52.64 60.09,52.94 60.09,53.64 v1(59.69,54.04)
FMC-1_LA22_P: length 92.5
  TOP w0.102: v1(60.69,54.04) U31.L14 ; P1.G24 v1(8.89,45.85)
  L16_SIGNAL w0.089: v1(60.69,54.04) 60.34,53.69 60.34,52.84 59.89,52.39 59.44,52.39 59.34,52.29 59.34,49.82 58.93,49.4 44.81,49.4 44.45,49.04 44.45,42.8 44.96,42.29 44.96,41.04 44.3,40.39 37.57,40.39 37.47,40.28 37.47,39.48 37.57,39.37 44.3,39.37 44.96,38.71 44.96,38.23 44.45,37.72 20.07,37.72 19.56,38.23 19.56,39.52 19.2,39.88 17.8,39.88 17.14,40.53 17.14,40.77 16.64,41.28 10.92,41.28 10.67,41.53 10.67,46.25 10.56,46.36 8.74,46.36 8.51,46.12 8.51,45.44 8.61,45.34 8.8,45.34 8.89,45.43 v1(8.89,45.85)
FMC-1_LA23_N: length 94.4
  TOP w0.102: v1(58.69,57.04) U31.J17 ; 12.07,46.48 v1(12.7,45.85)
  L16_SIGNAL w0.089: v1(12.7,45.85) 13.21,46.36 18.29,46.36 18.8,45.85 18.8,42.42 19.3,41.91 20.43,41.91 21.06,42.55 21.8,42.55 22.1,42.25 22.1,40 22.61,39.5 31.5,39.5 32,40 32,40.64 31.5,41.15 27.81,41.15 27.3,41.66 27.3,42.8 27.81,43.31 33.27,43.31 33.78,42.8 33.78,40.26 34.29,39.75 34.92,39.75 35.18,40 35.18,51.99 35.43,52.24 43.31,52.24 43.82,51.73 43.82,51.69 44.32,51.18 45.09,51.18 45.59,51.69 45.59,52.96 46.1,53.47 46.48,53.47 46.99,52.96 46.99,51.69 47.5,51.18 48.11,51.18 48.77,51.84 48.77,51.99 50.22,53.44 56.94,53.44 57.29,53.79 57.29,54.14 57.59,54.44 59.94,54.44 60.33,54.82 60.33,57.76 59.92,58.17 59.33,58.17 59.05,57.89 59.05,57.4 v1(58.69,57.04)
FMC-1_LA23_P: length 93.2
  TOP w0.102: v1(59.69,57.04) U31.K17 ; 12.07,47.75 v1(12.7,47.12)
  L16_SIGNAL w0.089: v1(12.7,47.12) 13.21,46.61 18.39,46.61 19.05,45.95 19.05,42.52 19.41,42.16 20.32,42.16 20.95,42.8 21.91,42.8 22.35,42.35 22.35,40.11 22.71,39.75 31.39,39.75 31.75,40.11 31.75,40.53 31.39,40.89 27.71,40.89 27.05,41.55 27.05,42.9 27.71,43.56 33.38,43.56 34.04,42.9 34.04,40.36 34.4,40 34.82,40 34.92,40.11 34.92,52.09 35.33,52.5 43.41,52.5 44.07,51.84 44.07,51.79 44.43,51.44 44.98,51.44 45.34,51.79 45.34,53.06 46,53.72 46.59,53.72 47.24,53.06 47.24,51.79 47.6,51.44 48.01,51.44 48.51,51.94 48.51,52.09 50.11,53.69 56.84,53.69 57.04,53.89 57.04,54.25 57.48,54.69 59.84,54.69 60.07,54.93 60.07,57.66 59.82,57.91 59.44,57.91 59.31,57.78 59.31,57.42 v1(59.69,57.04)
FMC-1_LA24_N: length 95.9
  TOP w0.102: v1(58.69,56.04) U31.J16 ; 6.98,40.13 v1(7.62,39.5)
  L20_SIGNAL w0.089: v1(58.69,56.04) 59.06,56.41 59.06,57.27 59.44,57.64 59.55,57.64 59.61,57.71 60.88,57.71 61.29,57.29 61.29,46.79 60.94,46.44 46.48,46.44 45.97,45.93 45.97,38.35 45.47,37.85 19.3,37.85 18.54,38.61 18.54,45.85 16.76,47.62 11.28,47.62 10.92,47.27 10.92,39.24 10.41,38.73 9.78,38.73 9.4,39.12 9.4,39.77 9.17,40 7.75,40 7.62,39.88 v1(7.62,39.5)
FMC-1_LA24_P: length 94.6
  TOP w0.102: P1.H28 v1(7.62,40.77) ; v1(59.69,56.04) U31.K16
  L20_SIGNAL w0.089: v1(7.62,40.77) 7.62,40.39 7.75,40.26 9.27,40.26 9.65,39.88 9.65,39.22 9.88,38.99 10.31,38.99 10.67,39.35 10.67,47.37 11.18,47.88 16.87,47.88 18.8,45.95 18.8,38.71 19.41,38.1 45.36,38.1 45.72,38.46 45.72,46.03 46.38,46.69 60.84,46.69 61.04,46.89 61.04,57.18 60.77,57.45 59.72,57.45 59.65,57.39 59.55,57.39 59.32,57.16 59.32,56.41 v1(59.69,56.04)
FMC-1_LA25_N: length 90.8
  TOP w0.102: P1.G28 v1(8.89,40.77) ; v1(54.69,53.04) U31.E13
  L18_SIGNAL w0.089: v1(8.89,40.77) 8.89,41.19 8.8,41.28 7.34,41.28 7.11,41.04 7.11,40.49 7.34,40.26 21.87,40.26 21.97,40.36 21.97,42.4 22.37,42.8 24.13,42.8 24.51,42.42 24.51,40.39 24.64,40.26 31.14,40.26 31.92,41.04 32.2,41.32 v1(32.2,41.72)
  L22_SIGNAL w0.089: v1(54.69,53.04) 55.02,53.37 55.05,53.37 55.07,53.36 55.07,46.92 54.84,46.69 49.12,46.69 43.84,41.4 42.95,41.4 42.55,41 42.55,37.95 41.8,37.21 35.67,37.21 34.92,37.95 34.92,45.19 34.52,45.59 29.1,45.59 28.7,45.19 28.7,44.34 29.1,43.94 33.42,43.94 33.53,43.84 33.53,42.65 32.59,41.72 v1(32.2,41.72)
FMC-1_LA25_P: length 92.4
  TOP w0.102: v1(55.69,54.04) U31.F14 ; 8.26,42.67 v1(8.89,42.04)
  L18_SIGNAL w0.089: v1(32.77,41.14) 32.38,41.14 31.24,40 24.53,40 24.26,40.28 24.26,42.31 24.02,42.55 22.48,42.55 22.22,42.29 22.22,40.26 21.97,40 7.24,40 6.86,40.39 6.86,41.15 7.24,41.53 8.8,41.53 8.89,41.62 v1(8.89,42.04)
  L22_SIGNAL w0.089: v1(32.77,41.14) 32.77,41.54 33.78,42.55 33.78,43.94 33.53,44.2 29.21,44.2 28.96,44.45 28.96,45.08 29.21,45.34 34.42,45.34 34.67,45.08 34.67,37.85 35.56,36.96 41.91,36.96 42.8,37.85 42.8,40.89 43.05,41.15 43.94,41.15 49.23,46.44 54.94,46.44 55.32,46.81 55.32,53.16 55.34,53.19 55.34,53.69 v1(55.69,54.04)
FMC-1_LA26_N: length 93.9
  TOP w0.102: 12.07,42.67 v1(12.7,42.04) ; v1(57.69,54.04) U31.H14
  L16_SIGNAL w0.089: v1(12.7,42.04) 12.7,42.46 12.61,42.55 12.32,42.55 12.07,42.8 12.07,43.81 12.32,44.07 17.53,44.07 18.03,43.56 18.03,41.78 18.54,41.28 20.43,41.28 21.08,40.62 21.08,39.35 21.44,38.99 35.58,38.99 35.94,39.35 35.94,49.76 36.6,50.42 37.72,50.42 38.23,49.91 38.23,43.16 38.59,42.8 39.26,42.8 39.62,43.16 39.62,50.04 39.88,50.29 41.15,50.29 41.4,50.04 41.4,44.32 41.91,43.81 42.69,43.81 43.05,44.17 43.05,49.91 43.56,50.42 48.77,50.42 50.04,51.69 57.84,51.69 58.04,51.89 58.04,53.69 v1(57.69,54.04)
FMC-1_LA26_P: length 93.5
  TOP w0.102: 12.07,43.94 v1(12.7,43.31) ; v1(58.69,54.04) U31.J14
  L16_SIGNAL w0.089: v1(12.7,43.31) 12.7,42.89 12.61,42.8 12.42,42.8 12.32,42.9 12.32,43.71 12.42,43.81 17.42,43.81 17.78,43.46 17.78,41.68 18.44,41.02 20.32,41.02 20.83,40.51 20.83,39.24 21.34,38.73 35.69,38.73 36.2,39.24 36.2,49.66 36.7,50.17 37.61,50.17 37.97,49.81 37.97,43.05 38.48,42.55 39.37,42.55 39.88,43.05 39.88,49.93 39.98,50.04 41.04,50.04 41.15,49.93 41.15,44.22 41.8,43.56 42.8,43.56 43.31,44.07 43.31,49.81 43.67,50.17 48.87,50.17 50.14,51.44 57.94,51.44 58.29,51.79 58.29,53.64 v1(58.69,54.04)
FMC-1_LA27_N: length 92.3
  TOP w0.102: v1(56.69,57.04) U31.G17 ; 13.34,42.67 v1(13.97,42.04)
  L18_SIGNAL w0.089: v1(46.36,42.67) 46.36,42.27 46.25,42.16 45.19,42.16 45.09,42.27 45.09,43.69 44.83,43.94 41.3,43.94 40.89,43.54 40.89,41.25 40.79,41.15 39.88,41.15 39.62,41.4 39.62,43.69 39.37,43.94 36.96,43.94 36.7,43.69 36.7,40.39 36.45,40.13 35.94,40.13 35.69,40.39 35.69,43.69 35.43,43.94 34.57,43.94 34.16,43.54 34.16,42.27 34.06,42.16 33.4,42.16 33.15,42.42 33.15,43.69 32.89,43.94 31.9,43.94 31.5,43.54 31.5,42.52 31.39,42.42 30.71,42.42 30.61,42.52 30.61,43.69 30.35,43.94 29.46,43.94 29.21,43.69 29.21,41.78 28.96,41.53 28.45,41.53 28.19,41.78 28.19,43.69 27.94,43.94 27.05,43.94 26.8,43.69 26.8,41.66 26.54,41.4 25.91,41.4 25.65,41.66 25.65,43.69 25.4,43.94 21.23,43.94 20.83,43.54 20.83,41.63 20.72,41.53 12.28,41.53 12.19,41.62 12.19,42.42 12.32,42.55 13.46,42.55 v1(13.97,42.04)
  L22_SIGNAL w0.089: v1(56.69,57.04) 57.06,56.67 57.06,45.92 56.84,45.69 49.78,45.69 46.75,42.67 v1(46.36,42.67)
FMC-1_LA27_P: length 93.6
  TOP w0.102: v1(57.69,57.04) U31.H17 ; P1.C26 v1(13.97,43.31)
  L18_SIGNAL w0.089: v1(46.93,42.09) 46.54,42.09 46.36,41.91 45.09,41.91 44.83,42.16 44.83,43.58 44.73,43.69 41.4,43.69 41.15,43.43 41.15,41.15 40.89,40.89 39.77,40.89 39.37,41.3 39.37,43.58 39.26,43.69 37.06,43.69 36.96,43.58 36.96,40.28 36.55,39.88 35.84,39.88 35.43,40.28 35.43,43.58 35.33,43.69 34.67,43.69 34.42,43.43 34.42,42.16 34.16,41.91 33.3,41.91 32.89,42.31 32.89,43.58 32.79,43.69 32,43.69 31.75,43.43 31.75,42.42 31.5,42.16 30.61,42.16 30.35,42.42 30.35,43.58 30.25,43.69 29.57,43.69 29.46,43.58 29.46,41.68 29.06,41.28 28.34,41.28 27.94,41.68 27.94,43.58 27.83,43.69 27.16,43.69 27.05,43.58 27.05,41.55 26.65,41.15 25.8,41.15 25.4,41.55 25.4,43.58 25.29,43.69 21.34,43.69 21.08,43.43 21.08,41.53 20.83,41.28 12.18,41.28 11.94,41.51 11.94,42.52 12.21,42.8 13.46,42.8 v1(13.97,43.31)
  L22_SIGNAL w0.089: v1(46.93,42.09) 46.93,42.49 49.88,45.44 56.94,45.44 57.32,45.81 57.32,56.67 v1(57.69,57.04)
FMC-1_LA28_N: length 93.7
  TOP w0.102: P1.H32 v1(7.62,35.69) ; v1(55.69,53.04) U31.F13
  L22_SIGNAL w0.089: v1(55.69,53.04) 56.04,53.39 56.04,56.18 55.84,56.39 46.38,56.39 45.72,57.04 45.72,62.25 45.36,62.61 30.71,62.61 30.35,62.25 30.35,59.46 29.7,58.8 23.09,58.8 22.73,58.44 22.73,55.99 23.09,55.63 28.19,55.63 28.7,55.12 28.7,52.2 28.19,51.69 23.47,51.69 23.24,51.46 23.24,40.66 19.2,36.62 19.2,36.28 19.07,36.15 18.89,36.15 18.84,36.19 7.75,36.19 7.62,36.07 v1(7.62,35.69)
FMC-1_LA28_P: length 94.1
  TOP w0.102: 6.98,37.59 v1(7.62,36.96) ; v1(56.69,53.04) U31.G13
  L22_SIGNAL w0.089: v1(7.62,36.96) 7.62,36.58 7.75,36.45 18.94,36.45 18.94,36.72 22.99,40.77 22.99,51.56 23.37,51.94 28.09,51.94 28.45,52.3 28.45,55.01 28.09,55.37 22.99,55.37 22.48,55.88 22.48,58.55 22.99,59.06 29.59,59.06 30.1,59.56 30.1,62.36 30.61,62.87 45.47,62.87 45.97,62.36 45.97,57.15 46.48,56.64 55.94,56.64 56.29,56.29 56.29,53.44 v1(56.69,53.04)
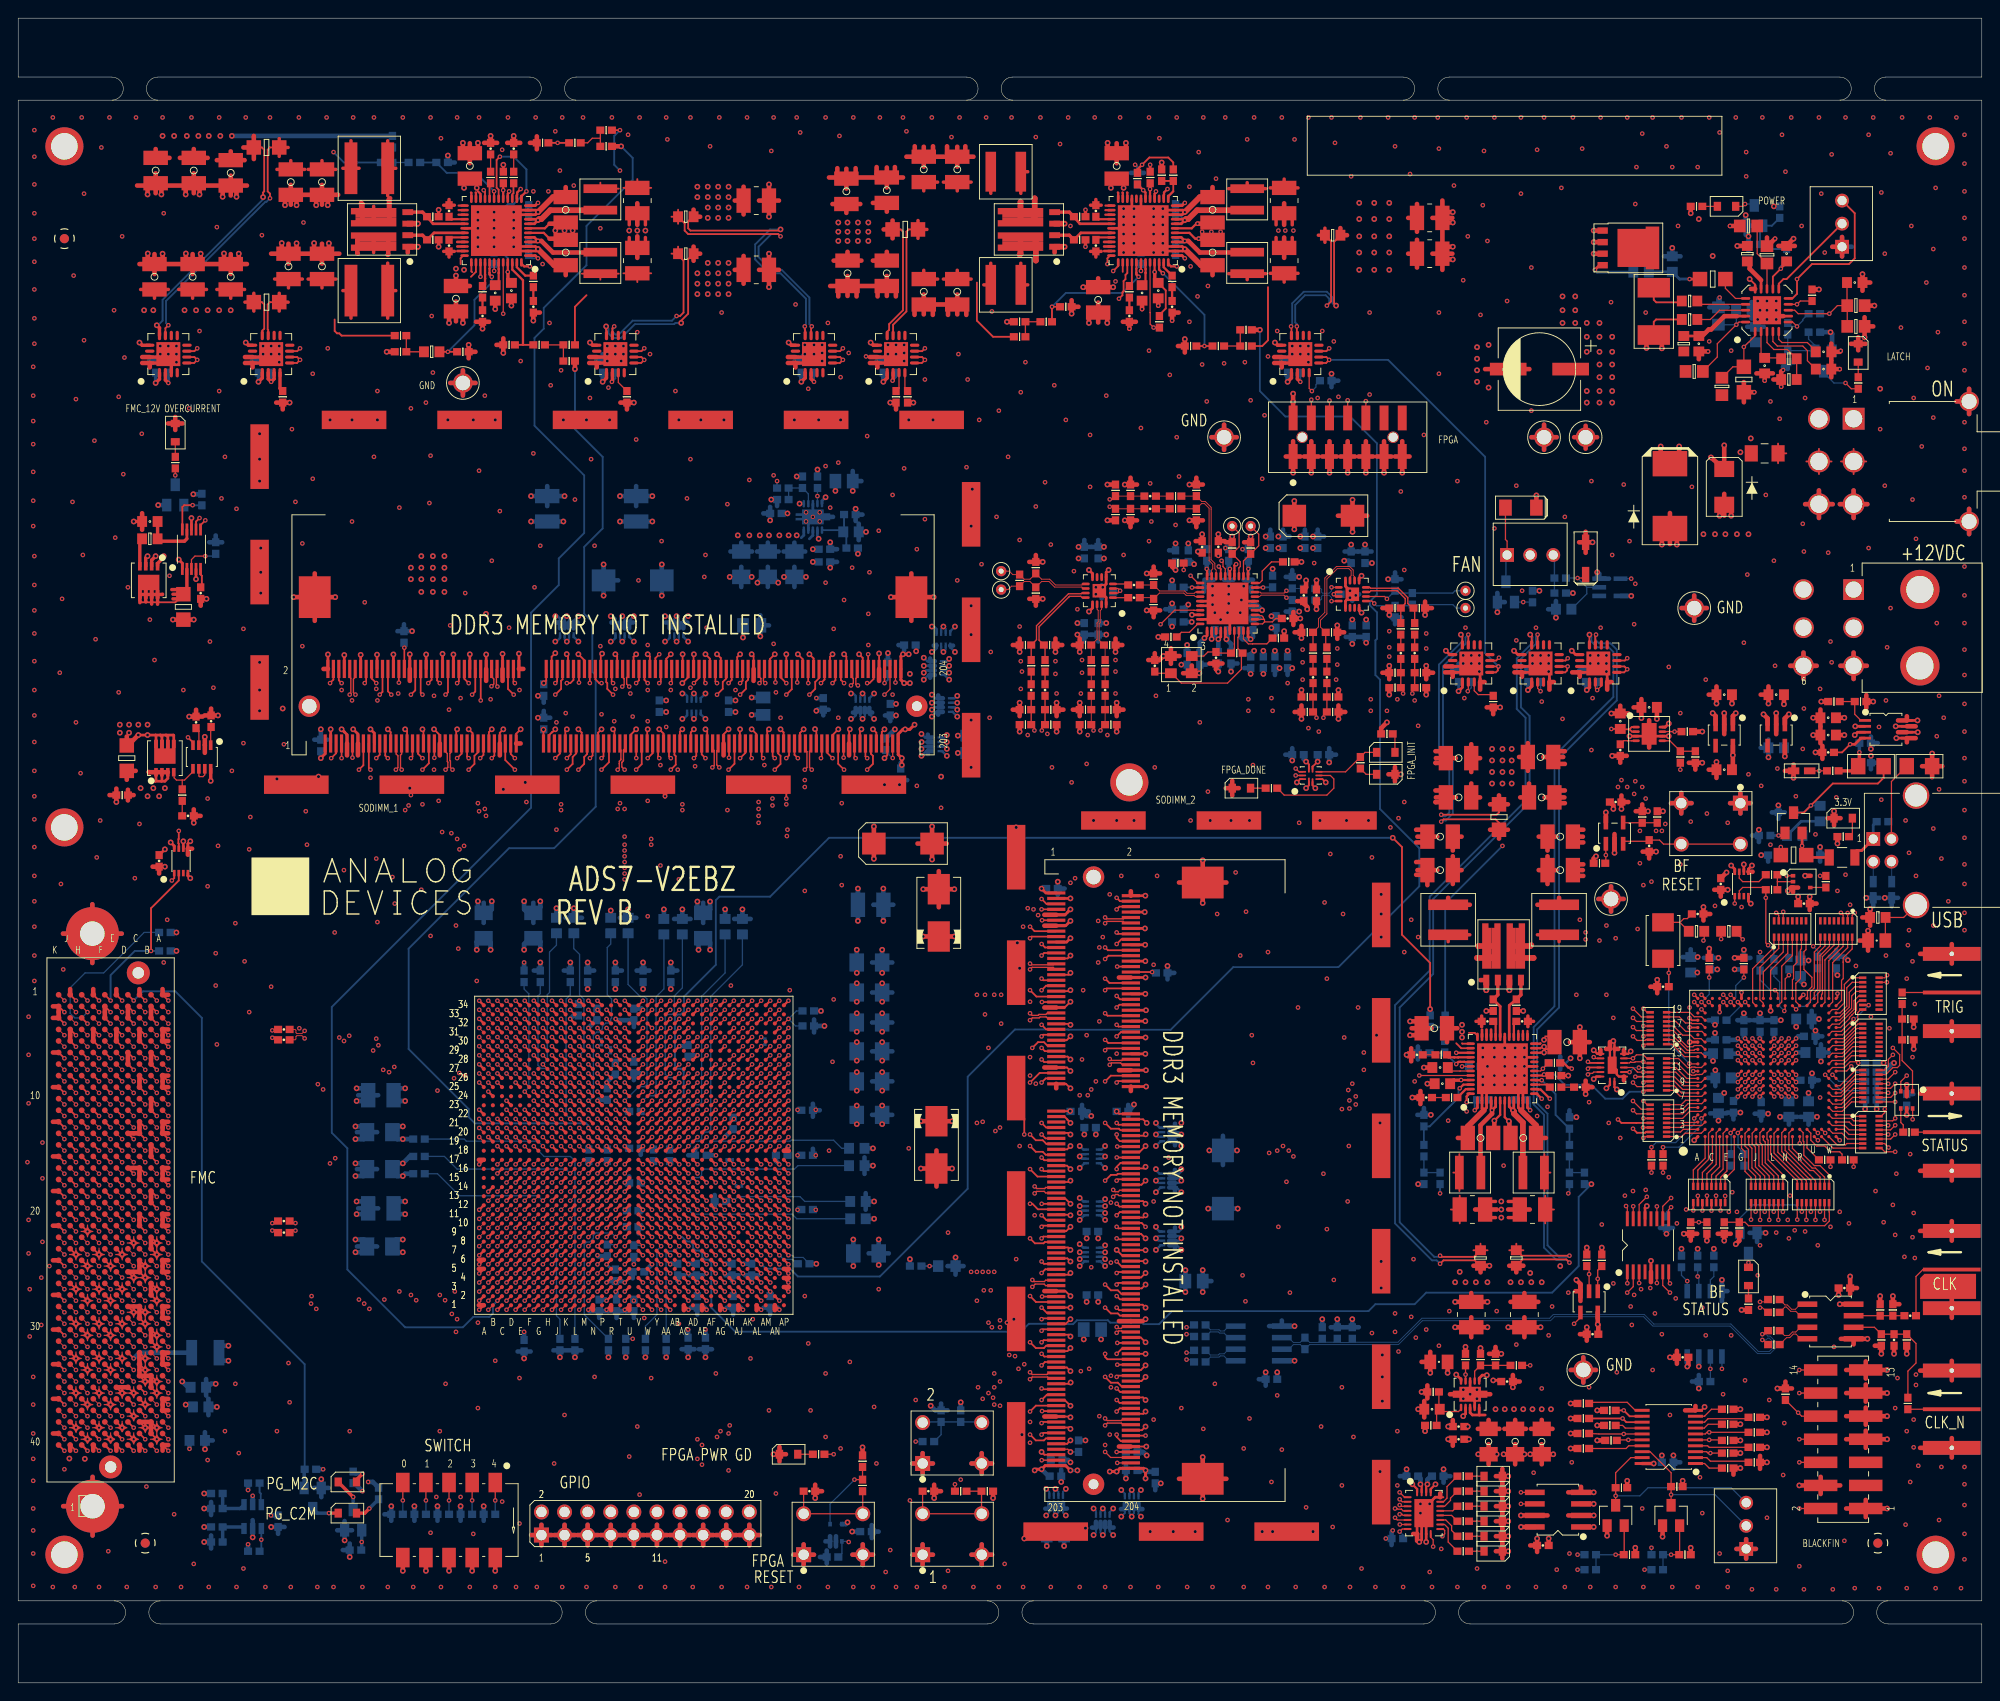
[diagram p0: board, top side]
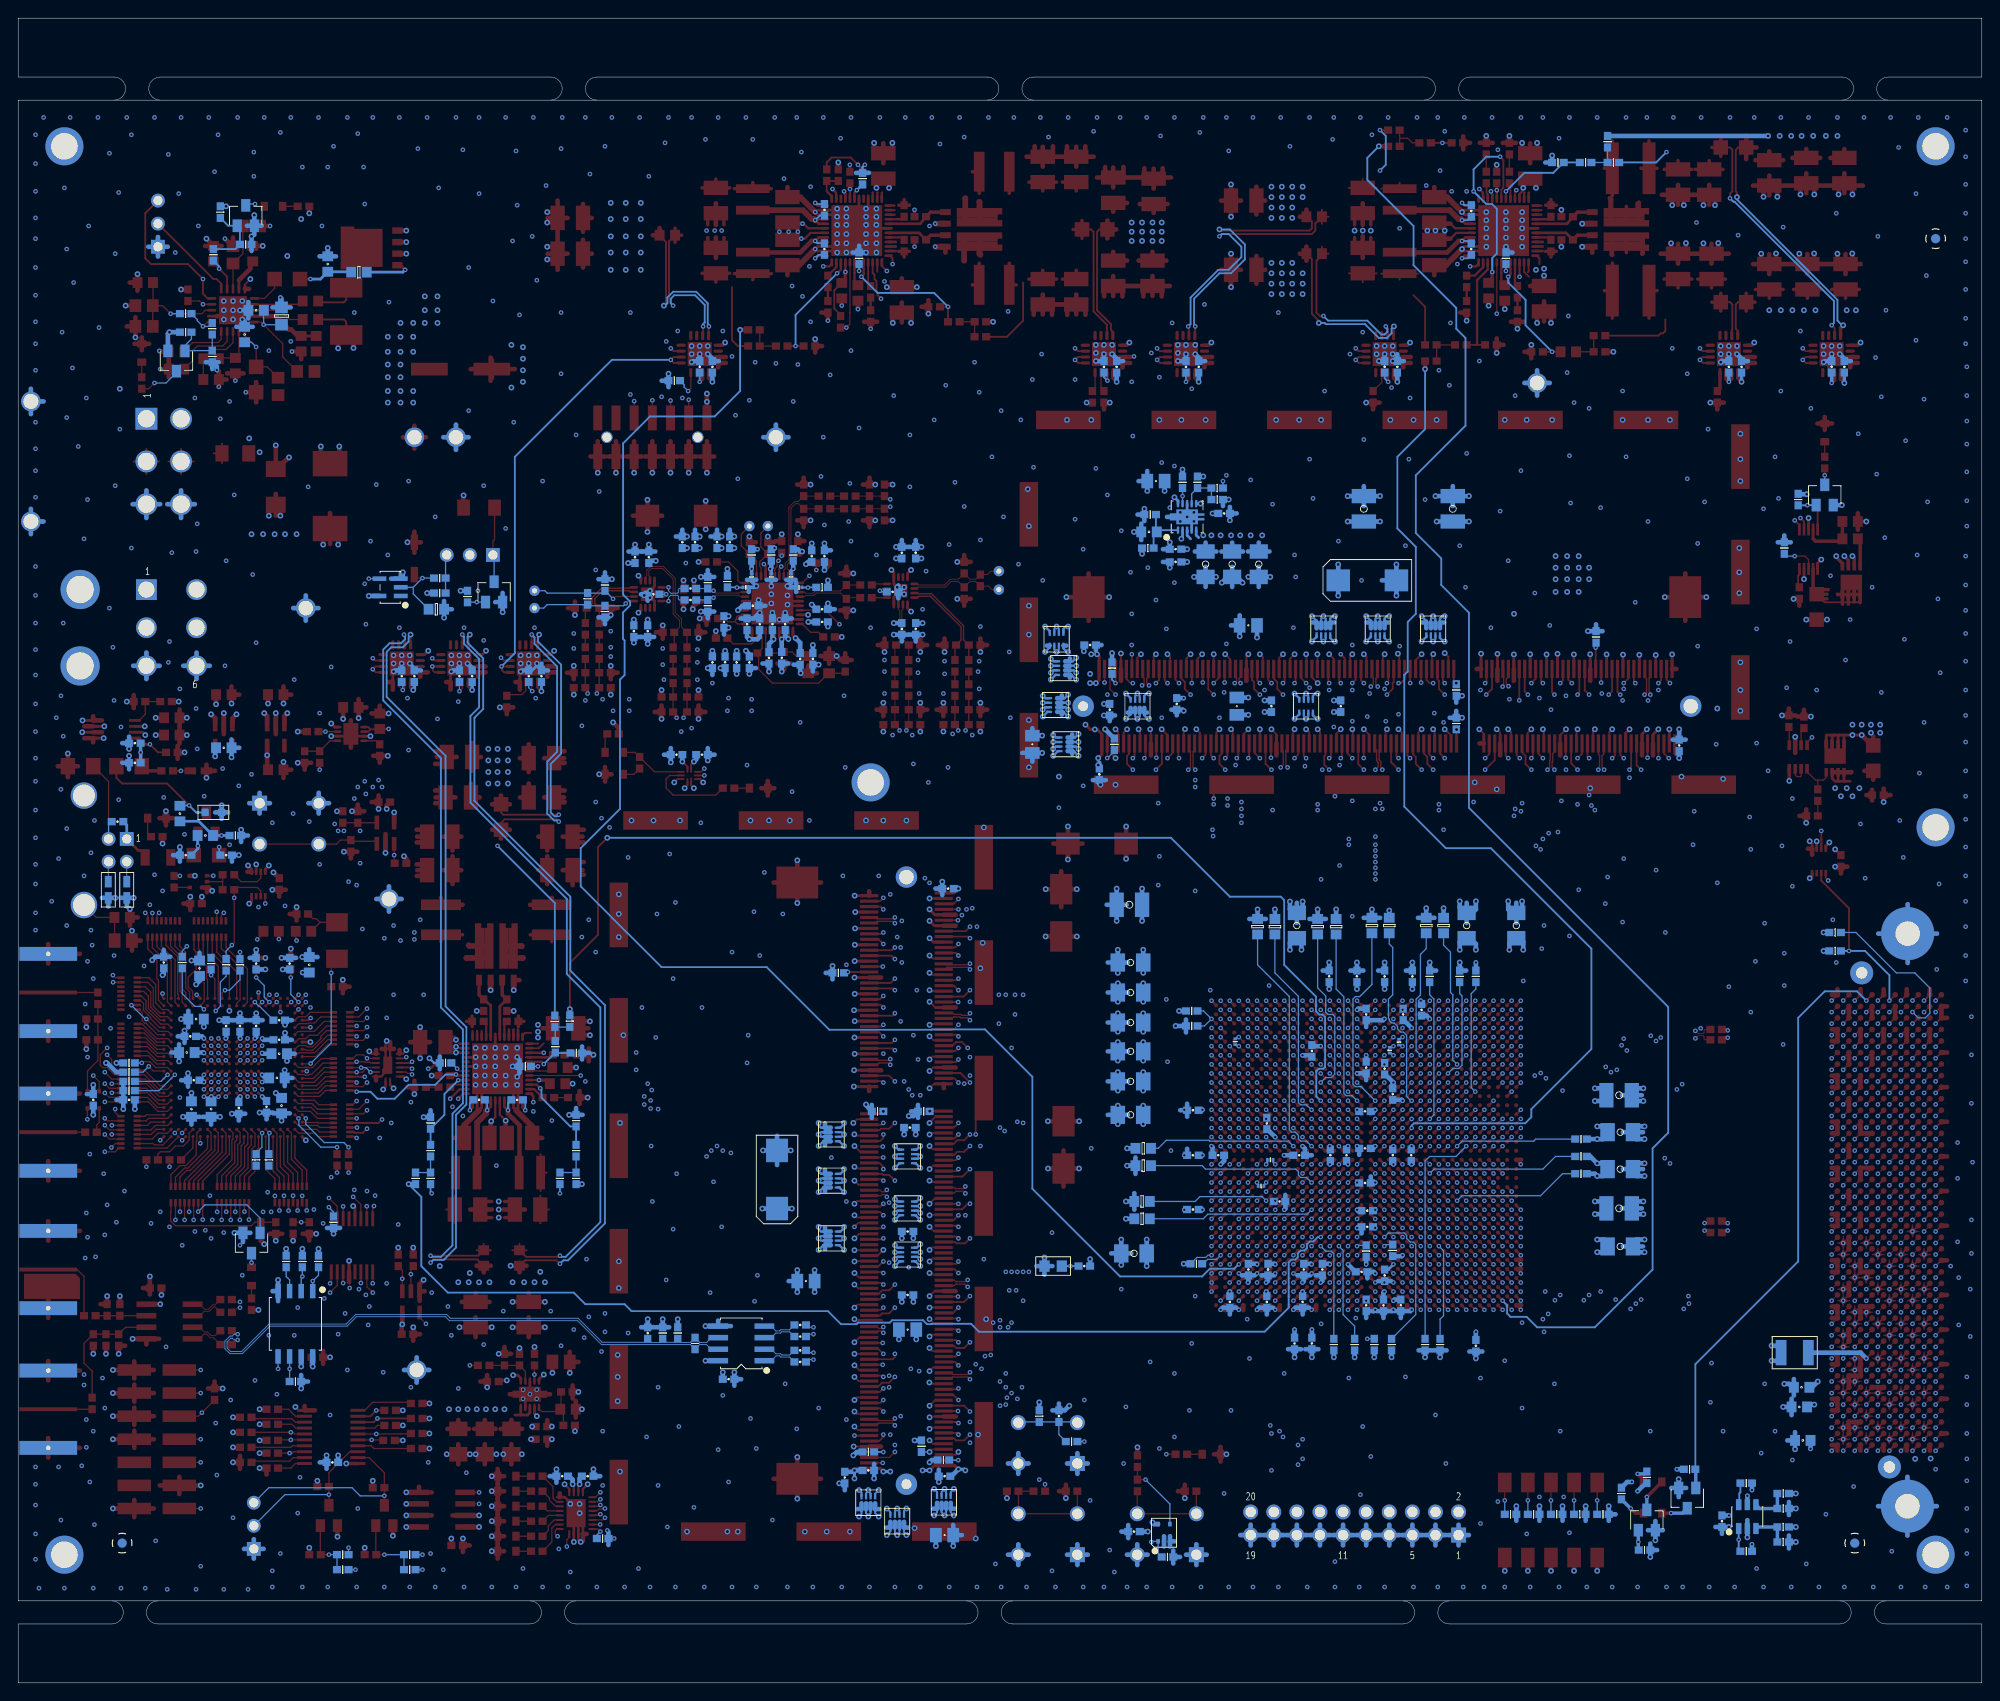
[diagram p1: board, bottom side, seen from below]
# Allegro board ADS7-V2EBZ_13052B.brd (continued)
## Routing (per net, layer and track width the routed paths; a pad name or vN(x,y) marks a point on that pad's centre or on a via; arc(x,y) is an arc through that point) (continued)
FMC-1_LA29_N: length 95.6
  TOP w0.102: v1(53.69,54.04) U31.D14 ; 8.26,37.59 v1(8.89,36.96)
  L18_SIGNAL w0.089: v1(8.89,36.96) 8.89,37.34 8.76,37.47 7.13,37.47 6.86,37.74 6.86,38.59 7.39,39.12 18.9,39.12 19.28,38.73 41.3,38.73 41.66,39.09 41.66,40.75 43.18,42.27 v1(43.18,42.67)
  L22_SIGNAL w0.089: v1(43.18,42.67) 43.58,42.67 44.45,43.54 44.45,43.69 44.2,43.94 39.11,43.94 38.73,44.31 38.73,44.84 39.11,45.21 44.34,45.21 44.45,45.32 44.45,52.45 44.7,52.7 45.72,52.7 45.97,52.45 45.97,46.23 46.23,45.97 47.14,45.97 47.24,46.08 47.24,52.3 47.65,52.7 48.39,52.7 48.64,52.45 48.64,49.94 48.9,49.69 53.84,49.69 54.06,49.92 54.06,53.67 v1(53.69,54.04)
FMC-1_LA29_P: length 95.1
  TOP w0.102: v1(54.69,54.04) U31.E14 ; P1.G30 v1(8.89,38.23)
  L18_SIGNAL w0.089: v1(8.89,38.23) 8.76,38.1 8.76,37.81 8.67,37.72 7.24,37.72 7.11,37.85 7.11,38.48 7.49,38.86 18.8,38.86 19.18,38.48 41.4,38.48 41.91,38.99 41.91,40.64 43.36,42.09 v1(43.76,42.09)
  L22_SIGNAL w0.089: v1(54.69,54.04) 54.32,53.67 54.32,49.81 53.94,49.44 48.79,49.44 48.39,49.84 48.39,52.35 48.28,52.45 47.75,52.45 47.5,52.2 47.5,45.97 47.24,45.72 46.12,45.72 45.72,46.12 45.72,52.35 45.61,52.45 44.81,52.45 44.7,52.35 44.7,45.21 44.45,44.96 39.21,44.96 38.99,44.73 38.99,44.42 39.21,44.2 44.3,44.2 44.7,43.79 44.7,43.43 43.76,42.49 v1(43.76,42.09)
FMC-1_LA30_N: length 92.9
  TOP w0.102: P1.H35 v1(7.62,31.88)
  TOP w0.14: v1(54.69,59.04) U31.E18
  L18_SIGNAL w0.089: v1(48.26,40.01) 47.86,40.01 47.75,39.9 47.75,38.99 47.5,38.73 43.22,38.73 42.93,38.44 42.93,38.02 43.22,37.72 47.5,37.72 47.75,37.47 47.75,36.6 47.35,36.19 19.92,36.19 17.38,33.66 11.3,33.66 10.92,33.27 10.92,32.77 10.54,32.39 7.71,32.39 7.62,32.3 v1(7.62,31.88)
  L22_SIGNAL w0.089: v1(48.26,40.01) 48.26,40.4 48.39,40.53 50.27,42.42 58.92,42.42 59.29,42.79 59.29,60.32 58.97,60.64 55.44,60.64 55.06,60.27 55.06,59.41 v1(54.69,59.04)
FMC-1_LA30_P: length 91.7
  TOP w0.102: P1.H34 v1(7.62,33.15)
  TOP w0.14: v1(55.69,59.04) U31.F18
  L18_SIGNAL w0.089: v1(47.68,40.58) 47.68,40.19 47.5,40 47.5,39.09 47.39,38.99 43.12,38.99 42.67,38.54 42.67,37.91 43.12,37.47 47.39,37.47 47.5,37.36 47.5,36.7 47.24,36.45 19.81,36.45 17.27,33.91 11.2,33.91 10.67,33.38 10.67,32.87 10.44,32.64 7.71,32.64 7.62,32.73 v1(7.62,33.15)
  L22_SIGNAL w0.089: v1(55.69,59.04) 55.32,59.41 55.32,60.16 55.55,60.39 58.86,60.39 59.04,60.21 59.04,42.89 58.82,42.67 50.16,42.67 48.08,40.58 v1(47.68,40.58)
FMC-1_LA31_N: length 95
  TOP w0.102: v1(52.69,54.04) U31.C14 ; P1.G34 v1(8.89,33.15)
  L22_SIGNAL w0.089: v1(52.69,54.04) 52.77,54.04 53.09,54.36 53.09,54.55 53.02,54.61 52.85,54.61 52.47,54.99 44.85,54.99 44.7,55.14 44.7,58.31 44.34,58.67 36.43,58.67 36.07,58.31 36.07,50.17 35.18,49.28 35.18,48.77 34.67,48.26 33.8,48.26 33.15,48.92 33.15,60.73 32.79,61.09 31.73,61.09 31.37,60.73 31.37,48.92 30.71,48.26 25.89,48.26 24.89,47.27 24.89,40.03 19.79,34.92 11.3,34.92 10.92,34.54 10.92,34.04 10.54,33.66 9.02,33.66 8.89,33.53 v1(8.89,33.15)
FMC-1_LA31_P: length 94.9
  TOP w0.102: v1(53.69,55.04) U31.D15 ; P1.G33 v1(8.89,34.42)
  L22_SIGNAL w0.089: v1(8.89,34.42) 8.89,34.04 9.02,33.91 10.44,33.91 10.67,34.14 10.67,34.65 11.2,35.18 19.68,35.18 24.64,40.13 24.64,47.37 25.78,48.51 30.61,48.51 31.11,49.02 31.11,60.83 31.62,61.34 32.89,61.34 33.4,60.83 33.4,49.02 33.91,48.51 34.57,48.51 34.92,48.87 34.92,49.38 35.81,50.27 35.81,58.42 36.32,58.93 44.45,58.93 44.96,58.42 44.96,55.25 52.58,55.25 52.96,54.86 53.52,54.86 v1(53.69,55.04)
FMC-1_LA32_N: length 92.4
  TOP w0.102: P1.H38 v1(7.62,28.07) ; v1(52.69,57.04) U31.C17
  L22_SIGNAL w0.089: v1(52.69,57.04) 52.71,57.05 52.71,57.66 52.83,57.78 57.79,57.78 58.04,57.53 58.04,44.81 57.92,44.69 50.4,44.69 44.38,38.66 44.38,35.41 44.27,35.31 39.76,35.31 39.36,34.9 39.36,33 39.25,32.89 32.11,32.89 32,33 32,36.81 31.6,37.21 27.96,37.21 27.56,36.81 27.56,34.29 27.05,33.78 21.08,33.78 18.67,31.37 9.78,31.37 9.4,30.99 9.4,27.92 9.04,27.56 7.37,27.56 7.11,27.81 7.11,28.45 7.24,28.57 7.53,28.57 7.62,28.49 v1(7.62,28.07)
FMC-1_LA32_P: length 94.3
  TOP w0.102: P1.H37 v1(7.62,29.34)
  TOP w0.14: v1(52.69,59.04) U31.C18
  L22_SIGNAL w0.089: v1(7.62,29.34) 7.62,28.92 7.53,28.83 7.13,28.83 6.86,28.55 6.86,27.71 7.26,27.3 9.14,27.3 9.65,27.81 9.65,30.88 9.88,31.11 18.77,31.11 21.19,33.53 27.16,33.53 27.81,34.18 27.81,36.7 28.07,36.96 31.5,36.96 31.75,36.7 31.75,32.89 32,32.64 39.36,32.64 39.61,32.89 39.61,34.8 39.87,35.05 44.38,35.05 44.63,35.31 44.63,38.56 50.51,44.44 58.02,44.44 58.29,44.71 58.29,57.64 57.89,58.04 52.83,58.04 52.71,58.17 52.71,59.03 v1(52.69,59.04)
FMC-1_LA33_N: length 92.1
  TOP w0.102: P1.G37 v1(8.89,29.34) ; v1(51.69,53.04) U31.B13
  L22_SIGNAL w0.089: v1(51.69,53.04) 52.06,52.67 52.06,51.88 51.87,51.69 50.02,51.69 49.91,51.79 49.91,53.57 49.51,53.98 44.09,53.98 43.43,53.32 43.43,46.48 43.18,46.23 40.89,46.23 40.64,46.48 40.64,57.02 40.13,57.53 38.86,57.53 38.35,57.02 38.35,47.24 37.85,46.74 26.54,46.74 26.04,46.23 26.04,36.96 25.53,36.45 22.35,36.45 18.54,32.64 8.51,32.64 8.13,32.26 8.13,29.97 8.34,29.76 8.68,29.76 8.89,29.55 v1(8.89,29.34)
FMC-1_LA33_P: length 91.8
  TOP w0.102: v1(52.69,53.04) U31.C13 ; P1.G36 v1(8.89,30.61)
  L22_SIGNAL w0.089: v1(8.89,30.61) 8.89,30.23 8.68,30.01 8.45,30.01 8.38,30.08 8.38,32.15 8.61,32.39 18.65,32.39 22.46,36.19 25.63,36.19 26.29,36.85 26.29,46.12 26.65,46.48 37.95,46.48 38.61,47.14 38.61,56.92 38.97,57.28 40.03,57.28 40.39,56.92 40.39,46.38 40.79,45.97 43.29,45.97 43.69,46.38 43.69,53.21 44.2,53.72 49.4,53.72 49.66,53.47 49.66,51.69 49.91,51.44 51.97,51.44 52.32,51.78 52.32,52.67 v1(52.69,53.04)
FMC-1_PG_C2M_1P8: length 153.9
  TOP w0.14: RN8.12 v1(178.69,67.18) 178.06,67.18 178.01,67.23 178.01,67.23 177.74,67.49 177.74,67.49 177.55,67.69 176.56,67.69 U28.4 ; v1(78.69,73.04) U31.AH32
  L16_SIGNAL w0.095: v1(78.69,73.04) 78.75,73.04 79.25,73.53 79.25,75.69 85.73,82.17 88.01,82.17 92.2,86.36 93.34,86.36 100.01,93.03 101.54,93.03 111.63,103.12 154.4,103.12 156.87,100.65 160.23,97.29 176.54,97.29 177.8,98.55 v1(178.56,98.55)
  L18_SIGNAL w0.095: v1(178.69,67.18) 179.2,67.69 179.2,68.71 176.91,70.99 176.91,83.44 177.29,83.82 177.29,87.76 176.91,88.14 176.91,93.6 177.8,94.49 177.8,97.03 178.56,97.79 v1(178.56,98.55)
FMC-1_PG_C2M_3P3: length 270.9
  TOP w0.203: U28.13 172.72,67.7 v1(172.59,67.56) ; 12.07,75.69 v1(12.7,75.06)
  L18_SIGNAL w0.203: v1(12.7,75.06) 13.46,75.82 14.48,75.82 16.51,77.85 37.82,77.85 48.1,88.14 59.28,88.14 65.88,94.74 78.77,94.74 80.29,93.22 82.77,93.22 89.25,99.7 100.08,99.7 100.69,99.08 104.04,99.08 106.81,101.85 106.81,103.25 113.28,109.73 137.44,109.73 139.6,107.57 145.57,107.57 169.55,83.6 169.55,68.71 170.18,68.07 171.58,68.07 172.09,67.56 v1(172.59,67.56)
  BOTTOM w0.203: v1(12.7,75.06) 13.72,76.07 17.27,76.07 20.19,73.15 20.19,46.36 31.5,35.05 R322.1
  BOTTOM w0.381: R322.1 31.45,23.44 Q15.1
FMC-1_PG_M2C_1P8: length 150.1
  TOP w0.14: U28.5 177.16,68.19 177.29,68.33 177.36,68.26 177.73,68.26 177.8,68.33 v1(178.69,68.33) 178.84,68.18 RN8.10 ; v1(78.69,75.04) U31.AH34
  L16_SIGNAL w0.095: v1(78.69,75.04) 78.69,75.9 85.34,82.55 87.88,82.55 92.08,86.74 93.34,86.74 99.95,93.34 101.22,93.34 111.38,103.51 154.56,103.51 160.4,97.66 176.02,97.66 v1(176.91,98.55)
  L18_SIGNAL w0.095: v1(178.69,68.33) 178.56,68.2 177.16,68.2 176.4,68.96 176.4,85.22 176.66,85.47 176.66,87.25 176.28,87.63 176.28,93.73 177.16,94.62 177.16,97.92 176.91,98.17 v1(176.91,98.55)
FMC-1_PG_M2C_3P3: length 226.1
  TOP w0.203: v1(172.59,68.33) 172.72,68.19 U28.12 ; U23.2 17.66,88.27 14.61,85.22 v1(14.61,80.52) ; 9.53,75.69 v1(10.16,75.06)
  L18_SIGNAL w0.203: v1(172.59,68.33) 172.59,68.83 169.93,71.5 169.93,83.75 145.73,107.95 139.76,107.95 137.6,110.11 109.47,110.11 105.92,106.55 105.92,103.63 103.25,100.97 100.37,100.97 99.48,100.08 93.54,100.08 93.51,100.05 90.64,100.05 90.61,100.08 89.09,100.08 82.62,93.6 80.45,93.6 78.93,95.12 65.72,95.12 59.12,88.52 47.94,88.52 37.66,78.23 15.88,78.23 13.97,76.33 11.43,76.33 v1(10.16,75.06)
  BOTTOM w0.203: v1(10.16,75.06) 10.16,77.85 12.83,80.52 v1(14.61,80.52) R259.1
FMC-1_PRSNT_M2C_B_1P8: length 147.7
  TOP w0.14: v1(79.69,75.04) U31.AJ34 ; RN8.9 179.1,68.68 178.69,69.09 177.93,69.09 v1(177.55,68.71) 177.53,68.7 U28.6
  L16_SIGNAL w0.095: v1(79.69,75.04) 79.69,75.63 85.85,81.79 88.27,81.79 92.46,85.98 94.62,85.98 95.76,87.12 95.76,88.27 100.2,92.71 101.85,92.71 111.97,102.83 154.28,102.83 160.18,96.93 176.81,96.93 v1(177.67,97.79)
  L18_SIGNAL w0.095: v1(177.67,97.79) 177.67,97.28 177.39,97 177.39,94.46 176.61,93.68 176.61,87.93 176.91,87.63 176.91,85.09 176.66,84.84 176.66,70.76 177.76,69.66 177.76,69.64 177.93,69.47 177.93,69.09 v1(177.55,68.71)
FMC-1_PRSNT_M2C_B_3P3: length 230
  TOP w0.14: v1(173.23,68.83) 173.37,68.7 U28.11 ; 6.98,74.42 v1(7.62,73.79)
  L18_SIGNAL w0.095: v1(7.62,73.79) 8.26,74.42 8.26,76.33 11.68,79.76 14.35,79.76 15.49,78.61 37.5,78.61 47.79,88.9 58.96,88.9 65.57,95.5 79.09,95.5 80.61,93.98 82.46,93.98 89.57,101.09 95.89,101.09 96.52,100.46 99.31,100.46 100.2,101.35 103.12,101.35 105.54,103.76 105.54,106.81 109.22,110.49 137.76,110.49 139.92,108.33 145.89,108.33 170.31,83.91 170.31,71.76 v1(173.23,68.83)
  BOTTOM w0.14: R256.1 13.84,82.55 9.4,78.11 7.37,78.11 5.71,76.45 5.71,73.66 6.22,73.15 6.98,73.15 v1(7.62,73.79)
FMC-1_SCL: length 200.7
  TOP w0.14: U36.6 185.49,27.38 185.67,27.56 v1(185.93,27.56) R187.1 ; P1.C30 v1(13.97,38.23)
  L7_SIGNAL w0.095: v1(185.93,27.56) 179.9,27.56 178.12,25.78 173.86,25.78 171.07,22.99 171.07,17.65 167.26,13.84 110.49,13.84 107.06,17.27 98.55,17.27 96.39,19.43 96.39,24.64 88.9,32.13 23.49,32.13 21.72,33.91 20.45,33.91 16.76,37.59 14.61,37.59 v1(13.97,38.23)
FMC-1_SDA: length 197.3
  TOP w0.14: 13.34,37.59 v1(13.97,36.96) ; R184.1 187.27,26.73 v1(185.93,26.73) U36.5
  L7_SIGNAL w0.095: v1(13.97,36.96) 14.61,36.32 16.89,36.32 21.84,31.37 88.39,31.37 95.38,24.38 95.38,19.18 98.17,16.38 106.81,16.38 109.98,13.21 167.77,13.21 171.58,17.02 171.58,22.1 174.5,25.02 178.44,25.02 180.14,26.73 v1(185.93,26.73)
FMC-1_VIO_B_M2C: length 15.8
  TOP w0.203: 5.71,27.43 v1(6.35,26.8) ; P1.K40 v1(5.08,25.53)
  TOP w0.305: 16.26,104.27 16.45,104.07 Q5.6 ; 16.26,104.27 15.62,104.27 ; 16.26,104.27 17.06,104.27 17.1,104.23 Q5.5 ; 15.11,104.27 15.15,104.23 Q5.8 ; 15.11,104.27 v2(14.22,104.27) v2(13.21,104.27) ; 15.11,104.27 15.62,104.27 ; 15.62,104.27 15.8,104.08 Q5.7
  TOP w0.508: 11.94,104.1 R113.1 12.19,103.25 v2(13.21,104.27)
  L20_SIGNAL w0.203: v1(6.35,26.8) v1(5.08,25.53)
  BOTTOM w0.508: 21.21,17.14 v2(20.45,17.14) ; 21.21,20.83 v2(20.45,20.83)
  vias: v2(11.18,105.41) v2(11.18,104.52) v2(12.19,105.41) v2(12.19,104.52) v2(13.21,105.41) v2(14.22,105.41)
FMC-1_VIO_B_M2C_ON: length 105.5
  TOP w0.203: U23.7 17.66,92.31 17.61,92.35 17.61,92.81 17.66,92.85 v1(17.66,93.72) ; v1(18.67,104.01) 19.22,103.46 U17.4
  L13_POWER w0.203: v1(37.77,15.49) 38.35,16.08 38.35,17.27 36.45,19.18 32.38,19.18 27.18,24.38 27.18,43.31 22.99,47.5 22.99,81.41 17.78,86.61 17.78,90.81 17.53,91.06 17.53,93.59 v1(17.66,93.72) 18.67,94.73 v1(18.67,104.01)
  BOTTOM w0.381: R486.2 37.77,14.66 v1(37.77,15.49) Q16.1
FMC-1_VIO_B_M2C_S: length 20.1
  TOP w0.254: v1(52.69,67.04) U31.C26 ; v1(50.69,73.04) U31.A32 ; v1(56.69,65.04) U31.G24 ; v1(54.69,71.04) U31.E30 ; v1(51.69,70.04) U31.B29 ; v1(53.69,74.04) U31.D33 ; v1(55.69,68.04) U31.F27
  TOP w0.305: 15.75,99.19 16.13,99.19 16.45,99.51 Q5.3 ; 15.75,99.19 15.07,99.19 ; 15.75,99.19 15.8,99.24 Q5.2 ; 15.07,99.19 15.15,99.27 Q5.1 ; 15.07,99.19 14.48,99.19
  TOP w0.508: 14.35,100.2 14.38,100.18 Q5.1 Q5.2 Q5.3 ; 12.07,97.08 R124.1 ; R124.1 12.07,98.25 ; R124.1 12.69,97.66 ; 11.94,99.35 R113.2 12.92,100.33
  BOTTOM w0.508: v2(51.94,80.64) 51.94,81.41 51.44,81.92 C243.2 50.8,81.92 50.42,81.53 v2(50.42,80.64) ; R271.2 v1(55.63,79.25)
  vias: v2(13.46,98.42) v2(14.22,97.54) v2(14.86,98.42) v2(15.49,97.54) v2(16.13,98.42)
FMC_1V8: length 91.1
  TOP w0.203: R1.2 26.8,168.91 27.05,168.66 27.05,164.08 26.92,163.96 v2(26.92,163.45)
  TOP w0.254: v1(57.69,51.04) U31.H11 ; v1(51.69,60.04) U31.B19 ; v1(58.69,59.04) U31.J18 ; v1(56.69,54.04) U31.G14 ; v1(50.69,63.04) U31.A22 ; P1.H40 v1(7.62,25.53) ; v1(53.69,53.04) U31.D13 ; v1(54.69,50.04) U31.E10 ; 8.26,27.43 v1(8.89,26.8) ; v1(61.69,60.04) U31.M19 ; v1(50.69,52.04) U31.A12 ; P1.F40 v1(10.16,25.53) ; v1(55.69,57.04) U31.F17 ; v1(52.69,56.04) U31.C16 ; 10.79,27.43 v1(11.43,26.8) ; v1(58.69,48.04) U31.J8 ; v1(51.69,49.04) U31.B9 ; v1(59.69,55.04) U31.K15 ; v1(60.69,52.04) U31.L12 ; v1(57.69,62.04) U31.H21 ; v1(54.69,61.04) U31.E20 ; v1(61.69,49.04) U31.M9 ; v1(53.69,64.04) U31.D23
  TOP w0.381: v2(15.24,149.35) 15.53,149.06 U3.12 ; v2(13.34,147.45) 13.63,147.15 U3.13
  TOP w0.508: R1.2 25.91,170.18 ; R1.2 25.91,167.64 ; R1.2 24.76,168.91 ; C8.1 19.3,168.73 ; C8.1 17.78,167.77 ; C8.1 20.83,167.77 ; 15.11,168.73 C7.1 16.64,167.77 ; C9.1 23.37,168.48 ; C9.1 21.84,167.51 ; C9.1 24.89,167.51
  BOTTOM w0.203: v2(15.24,149.35) 15.37,149.35 15.88,149.86 15.88,152.15 26.92,163.19 v2(26.92,163.45)
  BOTTOM w0.508: R294.2 43.05,57.91 v2(42.29,57.15) 41.53,57.15 41.15,56.77 C301.2 41.15,56.26 41.66,55.75 v2(42.29,55.75) 42.55,56.01 R295.2 ; R283.2 v2(42.29,59.82) 41.66,59.82 41.15,60.33 C290.2 41.15,60.83 41.53,61.21 v2(42.29,61.21) ; v2(42.29,47.37) 41.66,47.37 41.15,47.88 C317.2 41.15,48.39 41.53,48.77 v2(42.29,48.77) ; v2(18.41,30.61) 18.96,30.61 C337.2 ; R209.1 v2(23.49,170.18)
  vias: v2(15.88,170.18) v2(17.14,170.18) v2(18.54,170.18) v2(19.81,170.18) v2(20.95,170.18) v2(22.22,170.18)
FMC_1V8_EN: length 197.5
  TOP w0.203: v1(178.65,61.09) 179.43,61.09 RN7.14 ; v1(51.18,164.21) 51.33,164.06 U1.21
  L22_SIGNAL w0.203: v1(51.18,164.21) 51.18,163.7 52.07,162.81 52.96,162.81 53.47,162.31 53.47,157.86 53.98,157.35 55.63,157.35 58.93,154.05 66.55,154.05 80.14,140.46 93.09,140.46 95.76,137.8 111.51,137.8 115.19,134.11 129.16,134.11 130.43,132.84 132.72,132.84 138.18,127.38 140.06,127.38 140.09,127.42 149.69,127.42 156.59,120.52 156.59,115.32 157.86,114.05 157.86,111.38 158.62,110.62 159.77,110.62 160.78,109.6 160.78,93.34 168.78,85.34 168.78,82.42 176.02,75.18 176.02,66.67 178.18,64.52 178.18,61.56 v1(178.65,61.09)
FMC_3V3: length 36.6
  TOP w0.203: U4.12 26.84,148.76 27.05,148.97 27.05,151.64 26.8,151.89 R19.2 ; 13.34,27.43 v1(13.97,26.8) ; P1.D36 v1(12.7,30.61) ; P1.D38 v1(12.7,28.07) ; P1.D40 v1(12.7,25.53)
  TOP w0.305: C96.2 v2(16.13,91.69) ; U23.8 17.16,92.06 v2(16.76,92.46)
  TOP w0.381: 23.37,152.32 C32.1 ; C32.1 21.84,153.29 ; C32.1 24.89,153.29 ; v2(25.02,147.45) 25.31,147.15 U4.13 ; R19.2 25.91,152.87 ; R19.2 24.93,151.89 ; R19.2 25.91,150.91 ; 19.18,152.32 C31.1 ; C31.1 17.65,153.29 ; C31.1 20.7,153.29 ; 14.99,152.32 C30.1 ; C30.1 16.51,153.29 ; C30.1 13.46,153.29 ; U17.8 v2(21.17,99.23)
  TOP w0.508: R31.1 v2(40.51,146.43)
  BOTTOM w0.508: R321.2 36.96,21.97 v1(37.85,21.08) ; U44.5 v1(25.78,20.57) ; C348.2 v1(27.79,18.41) ; R334.2 38.99,22.1 v1(38.48,22.1) ; R322.2 v1(33.53,23.5) ; 25.27,21.97 v1(25.27,21.21) ; R259.2 v2(17.4,80.52) ; C341.2 v1(18.83,25.74) ; 25.27,14.48 v1(25.27,15.24)
  vias: v1(2.54,44.58) v1(3.43,45.85) v2(7.33,24.64) v2(13.84,151) v2(14.86,151) v2(18.29,151) v2(19.56,151) v2(20.83,151) v2(22.1,151) v2(23.37,151)
FMC_3V3_EN: length 192
  TOP w0.203: RN7.13 177.92,61.6 177.92,61.59 176.28,61.59 v1(175.9,61.98)
  TOP w0.254: v1(50.83,154.69) U1.39
  L22_SIGNAL w0.203: v1(50.83,154.69) 50.83,153.9 51.56,153.16 57.66,153.16 58.42,152.4 66.04,152.4 82.3,136.14 110.87,136.14 114.3,132.72 126.37,132.72 128.27,130.81 132.33,130.81 134.37,128.78 134.37,125.86 136.91,123.32 139.06,123.32 139.83,122.56 151.26,122.56 153.16,120.65 153.16,112.65 157.85,107.96 157.85,99.96 158.62,99.19 158.62,92.84 165.74,85.73 165.74,82.68 173.99,74.42 173.99,63.88 v1(175.9,61.98)
FMC_12V0: length 6.9
  TOP w0.203: P1.C35 v1(13.97,31.88) ; P1.C37 v1(13.97,29.34)
  TOP w0.381: Q4.2 14.68,123.52 v2(15.11,123.95) ; v2(16,123.95) 16,123.82 15.33,123.15 Q4.1 ; v2(14.22,123.95) 14.03,123.75 Q4.3
  BOTTOM w0.508: v2(18.03,33.15) 18.67,32.51 C338.2
FPGA_1V0: length 219.9
  TOP w0.203: v2(155.24,74.12) 155.24,79.2 152.15,82.3 152.15,91.95 v2(151.13,92.96) ; v1(156.46,95.5) 162.56,95.5 162.81,95.76 R127.2 ; U14.12 158.79,115.15 v2(158.62,115.32)
  TOP w0.254: v1(63.69,53.04) U31.P13 ; v1(68.69,51.04) U31.V11 ; v1(70.69,64.04) U31.Y23 ; v1(62.69,56.04) U31.N16 ; v1(62.69,59.04) U31.N18 ; v1(66.69,59.04) U31.U18 ; v1(63.69,57.04) U31.P17 ; v1(62.69,63.04) U31.N22 ; v1(66.69,50.04) U31.U10 ; v1(70.69,51.04) U31.Y11 ; v1(70.69,55.04) U31.Y15 ; v1(63.69,60.04) U31.P19 ; v1(65.69,55.04) U31.T15 ; v1(61.69,64.04) U31.M23 ; v1(69.69,59.04) U31.W18 ; v1(65.69,51.04) U31.T11 ; v1(72.69,51.04) U31.AB11 ; v1(70.69,57.04) U31.Y17 ; v1(63.69,55.04) U31.P15 ; v1(66.69,63.04) U31.U22 ; v1(71.69,50.04) U31.AA10 ; v1(61.69,62.04) U31.M21 ; v1(65.69,60.04) U31.T19 ; v1(69.69,52.04) U31.W12 ; v1(70.69,60.04) U31.Y19 ; v1(64.69,50.04) U31.R10 ; v1(72.69,60.04) U31.AB19 ; v1(68.69,55.04) U31.V15 ; v1(64.69,63.04) U31.R22 ; v1(62.69,50.04) U31.N10 ; v1(70.69,49.04) U31.Y9 ; v1(62.69,52.04) U31.N12 ; v1(68.69,60.04) U31.V19 ; v1(65.69,64.04) U31.T23 ; v1(72.69,55.04) U31.AB15 ; v1(69.69,50.04) U31.W10 ; v1(63.69,51.04) U31.P11 ; v1(64.69,56.04) U31.R16 ; v1(72.69,57.04) U31.AB17 ; v1(64.69,59.04) U31.R18 ; v1(71.69,63.04) U31.AA22 ; v1(71.69,52.04) U31.AA12 ; v1(64.69,52.04) U31.R12 ; v1(71.69,56.04) U31.AA16 ; v1(63.69,62.04) U31.P21 ; v1(72.69,64.04) U31.AB23 ; v1(69.69,63.04) U31.W22 ; v1(66.69,52.04) U31.U12 ; v1(71.69,59.04) U31.AA18
  TOP w0.305: v2(156.97,113.54) 157.39,113.12 U14.13
  TOP w0.508: 159.77,98.93 C92.1 160.73,97.41 ; v2(94.08,94.21) C97.P v2(94.08,90.65) ; C85.1 165.99,103.38 ; C85.1 165.02,101.85 ; C85.1 165.99,100.33 ; v2(99.25,61.78) C120.P v2(102.68,61.78) ; R127.2 163.79,96.65 ; R127.2 162.81,97.63 ; R127.2 161.84,96.65 ; 165.15,97.41 C93.1 166.12,98.93 ; v2(102.94,82.11) C103.P v2(99.5,82.11) ; 159.77,100.2 C84.1 ; C84.1 159.77,103.25 ; C84.1 160.73,101.73
  BOTTOM w0.203: v1(72.69,64.04) 73.17,64.52 73.17,67.24 73.15,67.26 73.15,67.31 72.9,67.56 72.89,67.56 72.4,67.56 72.21,67.75 72.21,73.24 72.49,73.52 72.86,73.52 73.21,73.87 73.21,75.49 76.71,78.99 76.71,86.11 77.09,86.49 82.68,86.49 89.15,92.96 v2(151.13,92.96) ; v1(156.46,95.5) 156.64,95.33 156.93,95.33 157.35,95.76 157.35,101.09 156.21,102.23 156.21,112.01 158.75,114.55 158.75,115.19 v2(158.62,115.32)
  BOTTOM w0.508: v1(68.69,55.04) 68.64,54.99 C298.2 ; C296.2 69.85,58.88 v1(69.69,59.04) ; C297.2 66.93,58.8 v1(66.69,59.04) ; v1(66.69,63.04) 66.86,62.87 C287.2 ; v1(71.69,59.04) 71.63,58.98 C295.2 ; C306.2 66.8,50.04 v1(66.69,50.04) ; v1(66.69,52.04) 66.79,51.94 C305.2 ; C299.2 64.77,58.96 v1(64.69,59.04) ; C300.2 62.74,58.99 v1(62.69,59.04) ; R266.1 v2(155.24,74.12)
  vias: v2(162.05,102.74) v2(162.05,101.47) v2(162.05,100.2) v2(162.05,98.93) v2(163.19,102.74) v2(163.19,101.47) v2(163.19,100.2) v2(163.19,98.93) v2(164.21,102.74) v2(164.21,101.47) v2(164.21,100.2) v2(164.21,98.93)
FPGA_1V0_EN: length 41.1
  TOP w0.203: RN6.13 v1(186.18,51.95)
  TOP w0.254: v1(158.12,69.31) U27.39
  L20_SIGNAL w0.203: v1(186.18,51.95) 185.42,52.7 183.39,52.7 181.23,54.86 177.67,54.86 175.01,57.53 168.91,57.53 165.1,61.34 165.1,63.5 164.34,64.26 161.29,64.26 160.27,65.28 160.27,68.83 159.79,69.31 v1(158.12,69.31)
FPGA_1V0_MGT: length 215.4
  TOP w0.203: v1(139.95,149.22) 139.99,149.18 U8.12 ; v1(58.69,46.04) U31.J6 ; v2(144.91,151.51) 144.91,151.54 144.68,151.77 144.68,158.52 145.38,159.22 R16.2
  TOP w0.254: v1(77.69,46.04) U31.AG6 ; v1(71.69,46.04) U31.AA6 ; v1(75.69,46.04) U31.AE6 ; v1(60.69,46.04) U31.L6 ; v1(54.69,46.04) U31.E6 ; v1(79.69,46.04) U31.AJ6 ; v1(69.69,46.04) U31.W6 ; v1(56.69,46.04) U31.G6 ; v1(81.69,46.04) U31.AL6 ; v1(73.69,46.04) U31.AC6 ; v1(66.69,46.04) U31.U6 ; v1(52.69,46.04) U31.C6 ; v1(83.69,46.04) U31.AN6
  TOP w0.381: U8.13 138.47,147.15 v2(138.18,147.45)
  TOP w0.508: 145.38,160.03 R16.2 146.1,159.26 ; C27.1 153.8,162.69 ; C27.1 153.8,159.64 ; C27.1 152.83,161.16 ; 153.8,155.7 C28.1 ; C28.1 153.8,158.75 ; C28.1 152.83,157.23 ; R48.1 v2(136.53,148.84)
  BOTTOM w0.203: v2(144.91,151.51) 144.78,151.51 144.53,151.77 144.53,152.4 143.89,153.03 141.35,153.03 140.08,151.77 140.08,149.48 139.95,149.35 v1(139.95,149.22) ; v2(136.53,148.84) 136.53,142.11 139.32,139.32 146.43,139.32 149.39,136.36 149.39,119.72 148.62,118.95 148.62,118.54 149.4,117.76 149.4,114.86 149.22,114.68 149.22,110.87 149.73,110.36 149.73,96.14 154.05,91.82 154.05,87.63 145.16,78.74 133.6,78.74 126.71,71.84 115.47,71.84 115.43,71.88 109.6,71.88 104.39,66.67 104.39,54.36 94.74,44.7 85.73,44.7 84.87,45.56 82.21,45.56 81.72,46.04 v1(81.69,46.04)
  BOTTOM w0.508: v1(79.69,46.04) 79.75,46.1 C310.2 ; v1(69.69,46.04) 68.86,45.21 C315.2 ; C312.2 73.75,46.1 v1(73.69,46.04) ; v1(77.69,46.04) 77.75,46.1 C311.2 ; C314.2 71.75,46.1 v1(71.69,46.04)
  vias: v2(147.45,162.81) v2(147.45,161.04) v2(147.45,159.13) v2(147.45,157.35) v2(147.45,155.45) v2(149.1,162.81) v2(149.1,161.04) v2(149.1,159.13) v2(149.1,157.35) v2(149.1,155.45) v2(150.75,162.81) v2(150.75,161.04) v2(150.75,159.13) v2(150.75,157.35) v2(150.75,155.45)
FPGA_1V0_MGT_EN: length 141.8
  TOP w0.203: RN6.10 v1(184.68,53.57)
  TOP w0.254: U2.48 126.45,156.13 126.75,155.83 v1(127.38,155.83)
  L20_SIGNAL w0.203: v1(184.68,53.57) 184.66,53.59 184.66,54.23 181.99,56.9 176.91,56.9 175.39,58.42 170.69,58.42 167.64,61.47 167.64,63.12 166.5,64.26 166.5,69.98 165.42,71.06 161.73,71.06 157.23,75.56 149.22,75.56 146.69,78.11 146.69,109.47 143.76,112.39 143.76,121.92 143.13,122.56 143.13,129.67 141.35,131.44 139.06,131.44 136.91,133.6 136.91,135.76 131.7,140.97 131.7,151.51 v1(127.38,155.83)
FPGA_1V2_MGT: length 218.6
  TOP w0.203: v1(86.49,149.22) 86.49,148.84 86.53,148.8 U6.12 ; v2(83.82,159.89) 83.69,159.77 73.91,159.77 73.66,160.02 73.66,160.78 74.17,161.29 R11.2
  TOP w0.254: v1(53.69,43.04) U31.D3 ; v1(74.69,43.04) U31.AD3 ; v1(60.69,42.04) U31.L2 ; v1(78.69,43.04) U31.AH3 ; v1(56.69,42.04) U31.G2 ; v1(70.69,43.04) U31.Y3 ; v1(64.69,42.04) U31.R2 ; v1(82.69,43.04) U31.AM3 ; v1(65.69,43.04) U31.T3 ; v1(57.69,43.04) U31.H3 ; v1(77.69,42.04) U31.AG2 ; v1(61.69,43.04) U31.M3 ; v1(81.69,42.04) U31.AL2 ; v1(52.69,42.04) U31.C2 ; v1(69.69,42.04) U31.W2 ; v1(84.69,47.04) U31.AP7 ; v1(73.69,42.04) U31.AC2
  TOP w0.381: v2(84.71,147.45) 85,147.15 U6.13
  TOP w0.508: C15.1 79.76,164.59 ; C15.1 79.76,161.54 ; C15.1 78.79,163.07 ; 74.98,161.29 R11.2 74.26,162.07 ; R40.1 v2(66.29,169.04)
  BOTTOM w0.127: R303.1 86.3,46.8 85.33,46.8 85.09,47.04 v1(84.69,47.04)
  BOTTOM w0.203: v1(86.49,149.22) 86.61,149.35 86.61,152.27 83.82,155.07 82.55,155.07 81.03,156.59 81.03,158.24 82.68,159.89 v2(83.82,159.89) ; v2(66.29,169.04) 67.56,167.77 67.56,165.35 62.48,160.27 62.48,155.96 57.79,151.26 57.79,148.97 56.77,147.96 56.77,138.3 62.23,132.84 62.23,126.49 59.44,123.7 59.44,120.78 56.39,117.73 56.39,96.27 34.48,74.36 34.48,60.52 36.2,58.8 36.2,45.47 42.55,39.12 48.9,39.12 50.04,40.26 51.82,40.26 52.2,40.64 52.2,41.55 v1(52.69,42.04)
  BOTTOM w0.508: v1(82.69,43.04) 82.68,43.03 C320.2 ; C325.2 64.57,42.16 v1(64.69,42.04) ; R303.1 v2(87.76,46.1) ; C324.2 65.79,42.94 v1(65.69,43.04) ; v1(74.69,43.04) 74.68,43.02 C322.2 ; v1(78.69,43.04) 78.61,42.96 C321.2
  vias: v2(74.68,164.59) v2(74.68,163.45) v2(75.82,164.59) v2(75.82,163.45) v2(75.82,162.31) v2(75.82,161.16) v2(76.96,164.59) v2(76.96,163.45) v2(76.96,162.31) v2(76.96,161.16) v2(78.11,164.59) v2(78.11,163.45) v2(78.11,162.31) v2(78.11,161.16)
FPGA_1V2_MGT_EN: length 216
  TOP w0.203: RN6.9 v1(184.18,51.97)
  TOP w0.254: v1(55.25,164.34) 54.86,163.96 54.86,163.72 54.83,163.68 U1.14
  L22_SIGNAL w0.203: v1(184.18,51.97) 182.25,53.9 182.25,81.66 174.62,89.28 172.85,89.28 171.32,90.81 171.32,94.11 167.89,97.54 167.89,105.79 163.7,109.98 163.7,120.14 161.42,122.43 157.1,122.43 150.75,128.78 139.06,128.78 133.35,134.49 131.06,134.49 129.54,136.02 115.44,136.02 112.65,138.81 112.65,153.67 108.84,157.48 84.2,157.48 81.66,160.02 74.42,160.02 69.22,165.23 56.13,165.23 v1(55.25,164.34)
FPGA_1V8: length 275.9
  TOP w0.203: v2(140.59,99.06) 140.95,99.42 U22.10 ; U22.7 141.91,101.04 v2(141.6,101.35) ; v2(172.76,115.32) U16.12 ; v1(69.69,48.04) U31.W8 ; R158.2 165.42,46.58 170.21,46.58 v1(170.56,46.23) ; v2(141.6,98.42) 141.91,98.73 U22.1
  TOP w0.254: v1(74.69,74.04) U31.AD33 ; v1(78.69,72.04) U31.AH31 ; v1(72.69,53.04) U31.AB13 ; v1(77.69,65.04) U31.AG24 ; v1(65.69,53.04) U31.T13 ; v1(68.69,62.04) U31.V21 ; v1(79.69,69.04) U31.AJ28 ; v1(84.69,75.04) U31.AP34 ; v1(77.69,75.04) U31.AG34 ; v1(75.69,71.04) U31.AE30 ; v1(73.69,67.04) U31.AC26 ; v1(72.69,62.04) U31.AB21 ; v1(74.69,64.04) U31.AD23 ; v1(83.69,67.04) U31.AN26 ; v1(82.69,70.04) U31.AM29 ; v1(81.69,73.04) U31.AL32 ; v1(65.69,62.04) U31.T21 ; v1(72.69,49.04) U31.AB9 ; v1(76.69,68.04) U31.AF27 ; v1(70.69,53.04) U31.Y13 ; v1(70.69,62.04) U31.Y21 ; v1(68.69,53.04) U31.V13 ; v1(65.69,57.04) U31.T17
  TOP w0.305: U16.13 171.24,113.12 v2(170.81,113.54)
  TOP w0.381: U30.5 v2(207.65,62.48)
  TOP w0.508: P3.2 v2(140.18,140.94) v2(140.18,141.83) ; S4.7 v2(44.83,12.32) ; 163.94,45.89 R158.2 ; R158.2 164.72,45.16 ; R158.2 165.49,45.89 ; R319.2 v2(92.84,25.91) ; S4.8 v2(47.37,12.32) ; R65.2 v2(119.76,127.89) ; R193.2 v2(107.19,20.32) ; R144.1 v2(208.41,72.14) ; C129.1 167.13,41.91 ; C129.1 165.61,42.88 ; C129.1 164.08,41.91 ; S4.10 v2(52.45,12.32) ; S4.9 v2(49.91,12.32) ; S4.6 v2(42.29,12.32) ; R62.2 v2(119.76,131.83)
  L14_POWER w0.508: 57.53,17.79 P9.2 ; P9.2 58.53,18.8 ; P9.2 56.53,18.8 ; P9.2 57.53,19.8 ; P9.20 81.39,18.8 ; P9.20 79.39,18.8 ; P9.20 80.39,19.8 ; P9.20 80.39,17.79
  BOTTOM w0.203: v2(172.97,54.86) 171.58,53.47 171.58,45.85 168.66,42.93 154.81,42.93 153.54,41.66 149.22,41.66 148.46,40.89 126.87,40.89 125.44,39.46 123.73,39.46 123.56,39.62 120.07,39.62 119.8,39.89 116.42,39.89 115.98,39.46 115.47,39.46 115.43,39.5 111.12,39.5 110.26,38.63 78.84,38.63 76.21,41.27 76.21,46.24 75.89,46.56 75.49,46.56 75.21,46.84 75.21,47.24 74.89,47.56 74.49,47.56 74.21,47.84 74.21,48.22 73.87,48.56 73.49,48.56 73.01,49.04 v1(72.69,49.04) ; v2(172.76,115.32) 172.76,115.28 172.97,115.06 172.97,114.55 173.61,113.92 174.88,113.92 175.39,113.41 175.39,108.46 168.91,101.98 168.91,74.42 166.62,72.14 166.62,63.63 167.77,62.48 167.77,47.88 169.11,46.53 170.26,46.53 v1(170.56,46.23)
  BOTTOM w0.508: R305.2 63.79,46.94 v1(63.69,47.04) ; v2(92.2,80.64) C249.2 v2(92.2,78.11) ; C308.2 v2(98.04,46.61) ; 87.5,73.91 v2(88.27,73.91) ; v2(92.2,71.63) C262.2 v2(92.2,73.66) ; R308.2 v2(71.25,35.81) ; R304.2 v1(67.69,46.04) ; R310.2 v2(66.8,35.81) ; v2(92.2,67.18) C271.2 v2(92.2,65.15) ; U40.5 v2(177.36,119.57) ; v2(141.6,101.35) 141.35,101.6 C230.2 ; v2(92.33,87.38) v2(92.33,83.82) ; C125.1 v2(207.65,62.48) ; R309.2 v2(68.96,35.81) ; R235.1 v2(167.26,120.14) ; R191.2 v2(103.63,30.86) ; R286.1 v2(172.97,54.86) ; R311.2 v2(64.9,35.81)
  vias: v2(164.08,44.07) v2(165.23,44.07) v2(166.24,45.08) v2(166.37,44.07) v2(167.51,44.07)
FPGA_1V8_EN: length 25.1
  TOP w0.203: RN6.12 v1(185.68,53.59)
  TOP w0.254: U27.14 167.11,65.31 167.14,65.28 167.39,65.28 v1(168.4,64.26)
  L20_SIGNAL w0.203: v1(168.4,64.26) 170.56,64.26 177.04,57.78 182.25,57.78 185.67,54.36 185.67,53.59 v1(185.68,53.59)
FPGA_1V8_MGT: length 191
  TOP w0.203: 177.16,104.9 176.19,104.9 C79.2 v1(175.17,104.94) ; 177.16,104.9 177.41,105.14 U18.1 ; 177.16,104.9 177.42,104.64 U18.2
  TOP w0.254: v1(62.69,46.04) U31.N6 ; v1(64.69,46.04) U31.R6
  L5_SIGNAL w0.203: v1(62.69,46.04) 63.14,45.59 64.26,45.59 64.69,46.02 v1(64.69,46.04)
  L7_SIGNAL w0.203: 65.79,40.13 64.77,39.12 56.13,39.12 v1(55.63,38.61) ; 65.79,40.13 67.69,40.13 ; 65.79,40.13 65.15,40.77 65.15,45.58 v1(64.69,46.04) ; v1(175.17,104.94) 174.16,104.94 171.07,101.85 168.15,101.85 165.86,99.57 160.02,99.57 157.48,97.03 153.67,97.03 v1(151.77,95.12) ; 67.69,40.13 68.96,38.86 v1(73.66,38.86) v1(75.56,38.86) 77.72,36.7 115.09,36.7 115.48,36.31 115.91,36.31 116.33,36.73 124.87,36.73 125.6,37.47 130.43,37.47 v1(134.94,41.97) ; 67.69,40.13 v1(67.69,42.04)
  L9_SIGNAL w0.203: v1(151.77,95.12) 151.77,81.66 141.6,71.5 141.6,48.64 v1(134.94,41.97)
  BOTTOM w0.305: v1(64.69,46.04) 65.26,45.47 C316.2
  BOTTOM w0.508: C332.2 v1(75.56,38.86) ; C333.2 v1(73.66,38.86) ; C334.2 v1(55.63,38.61)
FPGA_1V8_MGT_EN: length 45
  TOP w0.14: RN7.16 178.84,60.1 v1(178.69,59.94) ; R120.1 v1(182.75,100.46)
  L20_SIGNAL w0.095: v1(178.69,59.94) 179.96,59.94 182.25,62.23 182.25,79.25 181.61,79.88 181.61,99.31 v1(182.75,100.46)
FPGA_2V0: length 162.7
  TOP w0.203: R12.2 73.66,156.63 73.66,150.62 72.9,149.86 v2(72.9,149.61) ; v2(64.64,149.22) 64.64,148.84 64.68,148.8 U5.12
  TOP w0.254: v1(64.69,54.04) U31.R14 ; v1(71.69,54.04) U31.AA14 ; v1(64.69,61.04) U31.R20 ; v1(71.69,61.04) U31.AA20 ; v1(69.69,54.04) U31.W14 ; v1(66.69,61.04) U31.U20 ; v1(69.69,61.04) U31.W20 ; v1(66.69,54.04) U31.U14 ; v1(62.69,61.04) U31.N20 ; v1(73.69,54.04) U31.AC14 ; v1(62.69,54.04) U31.N14 ; v1(73.69,61.04) U31.AC20
  TOP w0.381: v2(62.87,147.45) 63.16,147.15 U5.13
  TOP w0.508: C39.1 79.76,156.97 ; C39.1 78.79,155.45 ; C39.1 79.76,153.92 ; 74.26,156.45 R12.2 ; R12.2 74.98,157.23 ; R12.2 74.26,158 ; R54.1 v2(61.21,144.53)
  BOTTOM w0.203: v1(62.69,61.04) 62.69,61.3 62.44,61.56 50.2,61.56 49.53,62.23 49.53,63.12 42.93,69.72 42.93,80.77 53.98,91.82 58.93,91.82 63.5,96.39 63.5,110.87 63.12,111.25 63.12,116.71 62.23,117.6 62.23,124.97 64.26,127 64.26,134.87 61.21,137.92 v2(61.21,144.53) ; v2(64.64,149.22) 64.9,148.97 64.9,148.46 65.41,147.96 66.29,147.96 67.82,149.48 72.14,149.48 72.26,149.61 v2(72.9,149.61)
  BOTTOM w0.508: 41.4,65.02 41.78,65.41 v2(42.55,65.41) ; 41.4,65.02 41.28,64.9 C289.2 ; 41.4,65.02 41.4,64.52 41.91,64.01 v2(42.55,64.01) ; v2(56.39,127.76) C167.2 v2(59.94,127.76) ; 41.4,52.58 41.28,52.45 C307.2 ; 41.4,52.58 41.4,52.07 41.91,51.56 v2(42.55,51.56) ; 41.4,52.58 41.78,52.96 v2(42.55,52.96) ; v2(69.72,127.76) C166.2 v2(66.17,127.76)
  vias: v2(74.68,155.07) v2(74.68,153.92) v2(74.68,152.78) v2(75.82,156.21) v2(75.82,155.07) v2(75.82,153.92) v2(75.82,152.78) v2(76.96,156.21) v2(76.96,155.07) v2(76.96,153.92) v2(76.96,152.78) v2(78.11,156.21) v2(78.11,155.07) v2(78.11,153.92) v2(78.11,152.78)
FPGA_2V0_EN: length 202.2
  TOP w0.203: RN6.11 v1(185.18,51.95)
  TOP w0.254: U1.48 55.33,156.13 55.63,155.83 v1(56.26,155.83)
  L22_SIGNAL w0.203: v1(56.26,155.83) 58.8,153.29 66.29,153.29 79.88,139.7 92.84,139.7 95.5,137.03 111.25,137.03 114.81,133.48 128.78,133.48 130.3,131.95 132.59,131.95 137.8,126.75 137.8,124.59 138.43,123.95 145.57,123.95 145.58,123.96 152.01,123.96 155.7,120.27 155.7,112.01 157.86,109.86 159.51,109.86 160.02,109.35 160.02,92.58 166.75,85.85 166.75,82.68 174.5,74.93 174.5,67.31 176.66,65.15 176.66,57.4 180.85,53.21 180.85,52.07 181.8,51.12 184.34,51.12 v1(185.18,51.95)
FPGA_DIP_SW0: length 71.5
  TOP w0.14: S4.5 v1(42.29,20.07) ; v1(73.69,68.04) U31.AC27
  L9_SIGNAL w0.095: v1(73.69,68.04) 73.69,68.04 73.15,68.58 66.73,68.58 66.34,68.19 66.34,68.12 65.04,66.82 65.04,40.89 64.84,40.69 64.56,40.69 60.2,36.32 60.2,35.69 57.02,32.51 54.74,32.51 v1(42.29,20.07)
  BOTTOM w0.14: v1(42.29,20.07) R333.2
FPGA_DIP_SW1: length 77.6
  TOP w0.14: v1(79.69,72.04) U31.AJ31 ; S4.4 v1(44.83,20.07)
  L9_SIGNAL w0.095: v1(79.69,72.04) 79.47,72.04 78.99,72.52 77.67,72.52 74.34,69.19 74.34,68.19 73.84,67.69 66.42,67.69 65.28,66.55 65.28,40.64 62.1,37.47 61.98,37.47 60.58,36.07 60.58,35.18 57.4,32 56.13,32 44.83,20.7 v1(44.83,20.07)
  BOTTOM w0.14: v1(44.83,20.07) R332.2
FPGA_DIP_SW2: length 76.6
  TOP w0.14: v1(79.69,73.04) U31.AJ32 ; S4.3 v1(47.37,20.07)
  L9_SIGNAL w0.095: v1(47.37,20.07) 47.37,21.59 57.28,31.5 57.6,31.5 61.85,35.75 61.85,36.32 66.04,40.52 66.04,66.19 66.04,66.19 66.04,66.8 66.34,67.1 66.34,67.19 66.54,67.39 74,67.39 74.8,68.2 74.8,68.58 75.34,69.12 75.34,69.19 77.78,71.63 79.78,71.63 80.04,71.89 80.04,72.19 80.04,72.19 80.04,72.29 79.69,72.64 v1(79.69,73.04)
  BOTTOM w0.14: v1(47.37,20.07) R330.2
FPGA_DIP_SW3: length 77.3
  TOP w0.14: v1(77.69,74.04) U31.AG33 ; S4.2 v1(49.91,20.07)
  L9_SIGNAL w0.095: v1(77.69,74.04) 77.73,74.04 78.23,73.53 79.76,73.53 80.26,73.03 80.26,72.28 80.27,72.28 80.27,71.8 80.26,71.8 80.26,71.19 80.04,70.97 80.04,70.89 79.84,70.69 78.84,70.69 77.37,69.22 76.45,69.22 75.18,67.95 75.06,67.95 74.17,67.06 74.17,66.93 73.91,66.67 68.58,66.67 67.06,65.15 67.06,40.64 62.36,35.94 62.36,35.43 58.1,31.18 57.59,31.18 49.91,23.5 v1(49.91,20.07)
  BOTTOM w0.14: v1(49.91,20.07) R329.2
FPGA_DIP_SW4: length 78.1
  TOP w0.14: v1(78.69,74.04) U31.AH33 ; S4.1 v1(52.45,20.07)
  L9_SIGNAL w0.095: v1(78.69,74.04) 78.69,74.12 79.12,74.55 80.77,74.55 81.15,74.17 81.15,70.99 80.55,70.39 80.54,70.39 80.34,70.19 80.34,70.18 79.63,69.47 78.11,69.47 77.22,68.58 76.13,68.58 75.04,67.49 75.04,66.89 74.84,66.69 74.64,66.69 74.35,66.39 69.25,66.39 69.04,66.19 69.04,65.89 68.84,65.69 68.35,65.69 67.34,64.67 67.34,41.89 67.44,41.79 67.44,40.39 63.59,36.53 63.59,35.62 59.56,31.6 59.56,31.11 52.45,24 v1(52.45,20.07)
  BOTTOM w0.14: v1(52.45,20.07) R328.2
FPGA_GPIO_PB1: length 69.7
  TOP w0.14: R192.2 v1(103,21.84) ; v1(77.69,68.04) U31.AG27
  L20_SIGNAL w0.095: v1(103,21.84) 102.49,21.34 91.69,21.34 91.31,21.72 91.31,27.56 89.53,29.34 89.53,62.23 86.23,65.53 79.63,65.53 79.12,66.04 79.12,67.18 78.74,67.56 78.11,67.56 77.69,67.98 v1(77.69,68.04)
FPGA_GPIO_PB2: length 55.3
  TOP w0.14: v1(77.69,67.04) U31.AG26
  L18_SIGNAL w0.095: v1(98.68,26.54) 96.27,26.54 v1(88.77,34.04)
  L20_SIGNAL w0.095: v1(88.77,34.04) 88.77,60.96 85.18,64.56 79.67,64.56 78.49,65.74 78.49,66.29 77.74,67.04 v1(77.69,67.04)
  BOTTOM w0.14: R190.2 v1(98.68,26.54)
FPGA_LED0_1P8: length 135.9
  TOP w0.14: v1(75.69,73.04) U31.AE32 ; v1(151.38,18.16) 151.63,17.92 U37.8
  L22_SIGNAL w0.095: v1(151.38,18.16) 150.5,18.16 144.53,12.19 111.51,12.19 108.46,15.24 97.41,15.24 95.12,17.53 95.12,33.27 88.65,39.75 82.68,39.75 81.74,40.69 81.54,40.69 70.04,52.19 70.04,66.19 69.98,66.25 69.98,66.8 70.34,67.16 70.34,67.19 71.54,68.39 71.57,68.39 72.14,68.96 72.14,70.99 72.83,71.69 72.84,71.69 73.04,71.89 73.04,71.9 73.83,72.69 73.84,72.69 74.04,72.89 74.04,72.9 74.18,73.04 v1(75.69,73.04)
FPGA_LED0_3P3: length 4
  TOP w0.14: U37.16 156.82,17.42 157.23,17.02 157.23,15.49 R203.2
FPGA_LED1_1P8: length 135.9
  TOP w0.14: v1(151.89,18.55) 152.15,18.55 152.28,18.42 U37.7 ; v1(75.69,74.04) U31.AE33
  L22_SIGNAL w0.095: v1(151.89,18.55) 150.34,18.55 144.37,12.57 111.66,12.57 108.62,15.62 97.57,15.62 95.5,17.68 95.5,33.43 88.8,40.13 83.19,40.13 81.63,41.69 81.54,41.69 70.34,52.89 70.34,66.19 73.13,68.98 73.13,71.1 73.66,71.63 74.45,71.63 75.47,72.64 75.82,72.64 76.07,72.9 76.07,73.66 v1(75.69,74.04)
FPGA_LED1_3P3: length 2.9
  TOP w0.14: R202.2 157.61,16.76 157.61,17.27 156.96,17.92 U37.17
FPGA_LED2_1P8: length 130
  TOP w0.14: v1(73.69,71.04) U31.AC30 ; v1(151.38,19.18) 151.64,19.18 151.71,19.11 152.08,19.11 152.08,19.11 152.27,18.92 U37.6
  L22_SIGNAL w0.095: v1(151.38,19.18) 150.25,19.18 144.16,13.08 111.87,13.08 108.83,16.13 97.78,16.13 96.01,17.89 96.01,33.64 89.01,40.64 83.44,40.64 82.04,42.04 82.04,42.19 71.04,53.19 71.04,65.19 70.99,65.24 70.99,65.79 71.34,66.13 71.34,66.19 73.69,68.54 v1(73.69,71.04)
FPGA_LED2_3P3: length 2.2
  TOP w0.14: U37.18 157.6,18.42 R201.2
FPGA_LED3_1P8: length 129.2
  TOP w0.14: v1(151.89,19.56) 152.03,19.42 U37.5 ; v1(74.69,71.04) U31.AD30
  L22_SIGNAL w0.095: v1(151.89,19.56) 149.74,19.56 143.89,13.72 112.14,13.72 110.67,15.19 110.33,15.19 109.93,15.59 109.93,15.93 109.09,16.76 98.04,16.76 96.65,18.16 96.65,33.91 89.28,41.28 84.2,41.28 83.79,41.69 83.54,41.69 71.34,53.89 71.34,65.19 74.34,68.19 74.34,70.69 v1(74.69,71.04)
FPGA_LED3_3P3: length 2.1
  TOP w0.14: R196.2 157.73,18.92 U37.19
FPGA_LED4_1P8: length 129.5
  TOP w0.14: v1(77.69,71.04) U31.AG30 ; U37.4 152.17,19.92 v1(151.89,20.19)
  L22_SIGNAL w0.095: v1(151.89,20.19) 149.83,20.19 143.74,14.1 112.3,14.1 110.98,15.41 110.42,15.41 110.15,15.68 110.15,16.24 109.25,17.14 98.2,17.14 97.03,18.32 97.03,34.06 89.44,41.66 84.84,41.66 82.81,43.69 82.54,43.69 72.04,54.19 72.04,64.19 71.9,64.33 71.9,64.75 77.69,70.54 v1(77.69,71.04)
FPGA_LED4_3P3: length 2.7
  TOP w0.14: R195.2 157.48,20.32 157.48,20.07 156.83,19.42 U37.20
FPGA_LED5_1P8: length 130.7
  TOP w0.14: v1(151.89,20.96) 152.43,20.42 U37.3 ; v1(78.69,71.04) U31.AH30
  L22_SIGNAL w0.095: v1(78.69,71.04) 78.69,70.18 77.6,69.09 77.24,69.09 72.34,64.19 72.34,54.89 72.54,54.69 72.69,54.69 73.34,54.04 73.34,53.89 74.54,52.69 74.82,52.69 75.34,52.17 75.34,51.89 75.54,51.69 75.82,51.69 76.34,51.17 76.34,50.89 76.54,50.69 76.82,50.69 77.34,50.17 77.34,49.89 77.54,49.69 77.82,49.69 78.34,49.17 78.34,48.89 78.54,48.69 78.82,48.69 79.34,48.17 79.34,47.89 79.54,47.69 79.82,47.69 80.34,47.17 80.34,46.89 80.54,46.69 80.82,46.69 81.34,46.17 81.34,45.89 81.54,45.69 81.82,45.69 82.34,45.17 82.34,44.89 82.54,44.69 82.82,44.69 84.34,43.17 84.34,42.89 84.54,42.69 84.82,42.69 85.47,42.04 89.59,42.04 97.41,34.22 97.41,18.47 98.36,17.53 109.63,17.53 111.08,16.07 111.08,15.85 112.45,14.48 143.58,14.48 150.06,20.96 v1(151.89,20.96)
FPGA_LED5_3P3: length 3.8
  TOP w0.14: R194.2 157.1,21.59 157.1,20.32 156.7,19.92 U37.21
FPGA_PCA9545_RESETB: length 177.5
  TOP w0.14: v1(73.69,64.04) U31.AC23 ; R159.1 172.72,45.59 v1(172.72,44.96) U34.2
  L5_SIGNAL w0.095: v1(171.7,83.95) 171.07,83.95 170.74,83.62 161.41,83.62 159.13,85.91 155.21,85.91 151.07,90.04 143.36,90.04 129.9,103.51 112.8,103.51 102.51,93.22 99.47,93.22 97.79,91.54 97.79,89 95.15,86.36 83.19,86.36 74.12,77.29 74.12,69.8 74.17,69.75 74.17,64.52 v1(73.69,64.04)
  L7_SIGNAL w0.095: v1(171.7,83.95) 171.7,82.68 168.4,79.38 168.4,65.53 168.91,65.02 168.91,49.4 171.58,46.74 171.58,46.1 v1(172.72,44.96)
FPGA_RESETB: length 63.9
  TOP w0.14: v1(78.69,68.04) U31.AH27 ; R319.1 R315.2 v1(91.95,22.35)
  L20_SIGNAL w0.095: v1(78.69,68.04) 79.28,68.04 80.34,66.98 80.34,66.89 80.68,66.55 86.49,66.55 90.42,62.61 90.42,31.88 91.95,30.35 v1(91.95,22.35)
  BOTTOM w0.14: U43.4 89.27,19.67 v1(91.95,22.35)
FPGA_SCL: length 135.6
  TOP w0.14: v1(80.69,67.04) U31.AK26
  L20_SIGNAL w0.095: v1(80.69,67.04) 80.79,67.04 81.31,67.56 86.87,67.56 90.93,63.5 90.93,51.05 98.17,43.81 107.31,43.81 111.76,39.37 118.87,39.37 119.25,39.75 121.41,39.75 122.17,38.99 125.48,38.99 127.13,37.34 129.03,37.34 141.73,24.64 157.23,24.64 159,22.86 159,15.11 162.69,11.43 177.8,11.43 v1(178.82,12.45)
  BOTTOM w0.14: R338.2 v1(178.82,12.45)
FPGA_SDA: length 128
  TOP w0.14: v1(80.69,68.04) U31.AK27
  L20_SIGNAL w0.095: v1(171.45,14.1) 170.43,13.08 162.43,13.08 160.15,15.37 160.15,22.73 157.35,25.53 142.11,25.53 129.79,37.85 127.76,37.85 126.62,38.99 126.62,39.37 125.22,40.77 111.25,40.77 107.7,44.32 98.3,44.32 91.44,51.18 91.44,64.14 87,68.58 81.35,68.58 80.81,68.04 v1(80.69,68.04)
  BOTTOM w0.14: R327.2 v1(171.45,14.1)
FPGA_SPI_CLK: length 177.3
  TOP w0.14: v1(181.61,42.93) 180.82,43.71 U32.7 ; v1(76.69,71.04) U31.AF30
  L5_SIGNAL w0.095: v1(76.69,71.04) 76.69,71.14 76.2,71.63 76.2,77.72 83.78,85.3 95.59,85.3 98.85,88.56 98.85,91.1 99.91,92.16 102.95,92.16 113.24,102.45 129.46,102.45 142.92,88.98 150.63,88.98 154.77,84.85 158.69,84.85 160.98,82.56 v1(172.34,82.56)
  L7_SIGNAL w0.095: v1(172.34,82.56) 168.78,79 168.78,65.73 169.29,65.22 169.29,49.78 172.09,46.99 172.59,46.99 174.5,45.08 174.5,43.81 176.15,42.16 180.85,42.16 v1(181.61,42.93)
FPGA_SPI_CS: length 165.4
  TOP w0.14: v1(176.91,42.93) 177.57,43.59 U32.2 ; v1(76.69,74.04) U31.AF33
  L5_SIGNAL w0.095: v1(172.34,81.79) 160.66,81.79 158.37,84.07 154.45,84.07 150.31,88.21 142.68,88.21 135.85,95.04 135.85,95.06 135.58,95.34 135.55,95.34 129.16,101.73 113.54,101.73 103.25,91.44 100.2,91.44 99.57,90.81 99.57,88.27 95.89,84.58 84.07,84.58 77.22,77.72 77.22,74.55 76.71,74.04 v1(76.69,74.04)
  L7_SIGNAL w0.095: v1(172.34,81.79) 169.16,78.61 169.16,65.91 169.67,65.41 169.67,53.56 176.15,47.09 176.15,43.69 v1(176.91,42.93)
FPGA_SPI_EN: length 39.9
  TOP w0.14: RN10.13 v1(192.53,50.93) ; U32.16 176.92,52.31 v1(176.78,52.45) ; U32.1 v1(176.92,43.95) ; v1(181.74,52.32) 181.47,52.06 U32.9 ; v1(181.61,43.94) 181.47,44.08 U32.8
  L16_SIGNAL w0.095: v1(176.92,43.95) 176.92,52.31 v1(176.78,52.45)
  L18_SIGNAL w0.095: v1(192.53,50.93) 191.89,50.29 187.45,50.29 186.56,51.18 182.88,51.18 v1(181.74,52.32)
  L20_SIGNAL w0.095: v1(181.61,43.94) 180.85,44.7 177.67,44.7 v1(176.92,43.95) ; v1(181.74,52.32) 180.97,51.56 177.67,51.56 v1(176.78,52.45)
  BOTTOM w0.14: R296.1 181.23,51.82 v1(181.74,52.32)
FPGA_SPI_MISO: length 166.8
  TOP w0.14: v1(74.69,75.04) U31.AD34 ; v1(181.74,53.34) 180.82,52.43 U32.10
  L5_SIGNAL w0.095: v1(174.62,83.31) 173.74,83.31 173.61,83.44 171.52,83.44 171.32,83.24 161.26,83.24 158.97,85.53 155.05,85.53 150.91,89.66 143.2,89.66 129.74,103.12 112.96,103.12 102.67,92.84 99.62,92.84 98.17,91.38 98.17,88.84 95.31,85.98 83.44,85.98 74.69,77.23 v1(74.69,75.04)
  L7_SIGNAL w0.095: v1(181.74,53.34) 180.21,54.86 174.24,54.86 172.21,56.9 172.21,62.17 171.32,63.06 171.32,67.69 170.81,68.2 170.18,68.2 169.93,68.45 169.93,76.96 174.62,81.66 v1(174.62,83.31)
FPGA_SPI_MOSI: length 158.4
  TOP w0.14: v1(76.69,75.04) U31.AF34 ; U32.15 v1(177.57,52.43)
  L5_SIGNAL w0.095: v1(76.69,75.04) 76.69,77.71 83.93,84.94 95.74,84.94 99.21,88.41 99.21,90.95 100.05,91.8 103.1,91.8 113.39,102.09 129.31,102.09 142.77,88.62 150.48,88.62 154.62,84.49 158.54,84.49 160.83,82.2 173.32,82.2 v1(173.86,81.66)
  L7_SIGNAL w0.095: v1(177.57,52.43) 176.91,53.09 173.35,53.09 170.05,56.39 170.05,65.66 169.52,66.19 169.52,77.32 v1(173.86,81.66)
HEADER_GPIO00_1P8: length 48.7
  TOP w0.14: v1(74.69,65.04) U31.AD24
  L9_SIGNAL w0.095: P9.18 77.85,20.45 74.17,24.13 74.17,64.52 v1(74.69,65.04)
HEADER_GPIO01_1P8: length 48.1
  TOP w0.14: v1(73.69,65.04) U31.AC24
  L9_SIGNAL w0.095: v1(73.69,65.04) 73.67,65.04 73.15,64.52 73.15,22.86 75.31,20.7 P9.16
HEADER_GPIO02_1P8: length 50.2
  TOP w0.14: v1(74.69,66.04) U31.AD25
  L9_SIGNAL w0.095: P9.14 72.77,21.08 72.14,21.72 72.14,65.15 72.39,65.41 73.28,65.41 73.31,65.44 74.07,65.44 74.67,66.04 v1(74.69,66.04)
HEADER_GPIO03_1P8: length 50.4
  TOP w0.14: v1(73.69,66.04) U31.AC25
  L9_SIGNAL w0.095: v1(73.69,66.04) 73.66,66.04 73.28,65.66 71.63,65.66 71.12,65.15 71.12,39.37 70.74,38.99 70.74,21.59 70.23,21.08 P9.12
HEADER_GPIO04_1P8: length 54.3
  TOP w0.14: v1(75.69,65.04) U31.AE24
  L7_SIGNAL w0.095: P9.10 71.37,22.48 75.31,22.48 77.22,24.38 v1(77.22,27.69)
  L9_SIGNAL w0.095: v1(75.69,65.04) 76.57,65.04 77.22,64.39 v1(77.22,27.69)
HEADER_GPIO05_1P8: length 53.6
  TOP w0.14: v1(75.69,64.04) U31.AE23
  L7_SIGNAL w0.095: P9.8 70.36,24 v1(75.18,24)
  L9_SIGNAL w0.095: v1(75.18,24) 76.2,25.02 76.2,63.5 75.69,64.01 v1(75.69,64.04)
HEADER_GPIO06_1P8: length 60.8
  TOP w0.14: v1(76.69,67.04) U31.AF26
  L7_SIGNAL w0.095: P9.6 68.96,25.15 75.18,25.15 76.07,26.04 76.07,27.56 76.84,28.32 v1(78.23,28.32)
  L9_SIGNAL w0.095: v1(78.23,28.32) 78.23,65.28 77.85,65.66 77.34,65.66 76.69,66.31 v1(76.69,67.04)
HEADER_GPIO07_1P8: length 60
  TOP w0.14: v1(75.69,67.04) U31.AE26
  L7_SIGNAL w0.095: P9.4 67.44,26.16 v1(75.18,26.16)
  L9_SIGNAL w0.095: v1(75.69,67.04) 75.67,67.04 75.1,66.46 75.1,35.62 75.18,35.53 v1(75.18,26.16)
INITB: length 186.5
  TOP w0.14: v1(65.69,48.04) U31.T8 ; RN9.10 178.46,73.26 v1(177.55,74.17) ; v1(140.46,100.58) 140.82,100.22 U22.8
  L7_SIGNAL w0.095: v1(177.55,74.17) 176.4,75.31 176.4,83.19 174.88,84.71 174.24,84.71 169.8,89.15 153.29,89.15 145.54,96.9 145.54,99.06 144.02,100.58 v1(140.46,100.58)
  L16_SIGNAL w0.095: v1(139.7,58.55) 136.65,55.5 132.08,55.5 126.75,50.17 126.75,46.23 124.97,44.45 114.68,44.45 113.54,45.59 111.51,45.59 110.62,44.7 97.28,44.7 95,46.99 87,46.99 86.49,46.48 68.58,46.48 67.56,47.5 66.29,47.5 65.75,48.04 v1(65.69,48.04)
  L18_SIGNAL w0.095: v1(139.7,58.55) 139.7,97.41 141.22,98.93 141.22,99.82 v1(140.46,100.58)
  BOTTOM w0.14: v1(65.69,48.04) 65.52,48.21 R305.1
JTAG_TCK: length 153.5
  TOP w0.14: v1(61.69,48.04) U31.M8 ; P3.6 v1(144.18,141.06)
  L5_SIGNAL w0.095: v1(144.18,141.06) 143.51,141.73 141.6,141.73 140.97,141.1 140.97,140.46 135.74,135.23 119.45,135.23 114.7,130.48 114.7,123.37 108.23,116.89 108.23,102.41 103.45,97.64 93.17,97.64 86.94,91.42 77.32,91.42 73.53,87.63 73.53,83.95 72.9,83.31 72.9,79.38 70.1,76.58 70.1,57.02 70.04,56.96 70.04,56.89 62.84,49.69 62.77,49.69 62.1,49.02 62.1,48.39 61.76,48.04 v1(61.69,48.04)
JTAG_TDI: length 160.1
  TOP w0.14: v1(60.69,48.04) U31.L8 ; P3.10 v1(148.18,141)
  L5_SIGNAL w0.095: v1(60.69,48.04) 60.74,48.04 61.34,48.64 61.34,49.19 68.54,56.39 68.58,56.39 69.22,57.02 69.22,77.37 71.56,79.71 71.71,79.71 72.14,80.14 72.14,86.74 77.17,91.78 86.79,91.78 93.02,98 103.3,98 107.87,102.56 107.87,117.04 114.34,123.52 114.34,130.63 119.31,135.59 135.59,135.59 139.05,139.05 139.05,141.59 140.08,142.62 146.56,142.62 v1(148.18,141)
JTAG_TDO: length 155.2
  TOP w0.14: P3.8 v1(146.18,141.1) ; v1(62.69,48.04) U31.N8
  L5_SIGNAL w0.095: v1(146.18,141.1) 145.41,140.34 141.99,140.34 136.14,134.49 119.76,134.49 115.44,130.18 115.44,123.06 108.97,116.59 108.97,102.11 103.76,96.9 93.47,96.9 87.25,90.68 77.72,90.68 75.31,88.27 75.31,83.95 74.04,82.68 74.04,77.85 72.26,76.07 72.26,56.77 71.89,56.39 71.54,56.39 71.34,56.19 71.34,55.89 70.84,55.39 70.54,55.39 70.34,55.19 70.34,54.89 69.84,54.39 69.54,54.39 69.34,54.19 69.34,53.89 68.84,53.39 68.54,53.39 68.34,53.19 68.34,52.89 66.84,51.39 66.54,51.39 66.34,51.19 66.34,50.89 65.84,50.39 65.54,50.39 65.34,50.19 65.34,49.89 64.84,49.39 64.54,49.39 64.34,49.19 64.34,48.89 63.84,48.39 63.54,48.39 63.19,48.04 v1(62.69,48.04)
JTAG_TMS: length 149.3
  TOP w0.14: P3.4 v1(142.18,141.16) ; v1(62.69,49.04) U31.N9
  L5_SIGNAL w0.095: v1(142.18,141.16) 135.89,134.87 119.6,134.87 115.06,130.33 115.06,123.22 108.59,116.74 108.59,102.27 103.6,97.28 93.31,97.28 87.09,91.06 77.47,91.06 73.91,87.5 73.91,83.44 73.53,83.06 73.53,78.99 71.12,76.58 71.12,57.02 71.04,56.95 71.04,56.89 63.19,49.04 v1(62.69,49.04)
MGT_ALT_CLK_N: length 61.7
  TOP w0.102: v1(191.77,37.72) 191.9,37.72 R167.2
  BOTTOM w0.102: v1(191.77,37.72) 192.17,37.72 192.37,37.92 192.51,37.92 192.94,37.5 192.94,36.86 192.53,36.45 191.33,36.45 188.31,39.47 179.83,39.47 178.79,40.51 168.78,40.51 168.38,40.11 154.34,40.11 151.7,37.47 147.07,37.47 C326.1 146.28,37.44 145.4,37.44 145.03,37.8 R306.1 144.65,37.47 143.76,37.47 R307.2 142.98,37.44 142.01,37.44 R343.2 140.94,37.44 140.21,37.44 139.67,37.97 U42.6
MGT_ALT_CLK_P: length 61.4
  TOP w0.102: R166.2 192.02,38.35 v1(191.77,38.35)
  BOTTOM w0.102: U42.7 139.7,36.7 140.21,37.21 140.97,37.21 R343.1 141.99,37.21 151.77,37.21 154.39,39.84 168.49,39.84 168.93,40.28 178.7,40.28 179.74,39.24 188.21,39.24 191.24,36.22 192.63,36.22 193.17,36.76 193.17,37.59 192.61,38.15 192.37,38.15 192.17,38.35 v1(191.77,38.35)
MGTREFCLK1_117_C_N: length 78.6
  TOP w0.14: v1(63.69,45.04) U31.P5
  L16_SIGNAL w0.089: v1(128.46,36.32) 128.71,36.07 129.16,36.07 129.41,35.81 129.41,34.54 127.76,32.89 118.49,32.89 117.86,33.53 114.94,33.53 113.03,35.43 111.89,35.43 109.35,37.97 68.2,37.97 66.09,40.08 66.09,44.78 65.46,45.41 64.06,45.41 v1(63.69,45.04)
  BOTTOM w0.14: C329.2 129.03,36.32 v1(128.46,36.32)
MGTREFCLK1_117_C_P: length 77.7
  TOP w0.14: v1(63.69,46.04) U31.P6
  L16_SIGNAL w0.089: v1(128.46,35.56) 128.71,35.81 129.05,35.81 129.16,35.71 129.16,34.65 127.66,33.15 118.6,33.15 117.96,33.78 115.04,33.78 113.14,35.69 111.99,35.69 109.45,38.23 68.3,38.23 66.34,40.19 66.34,44.89 65.56,45.67 64.06,45.67 v1(63.69,46.04)
  BOTTOM w0.14: C330.2 129.03,35.56 v1(128.46,35.56)
MGTREFCLK1_117_N: length 3.8
  BOTTOM w0.102: U42.2 133.1,36.7 132.59,36.19 132.08,36.19 131.95,36.07 131.06,36.07 C329.1
MGTREFCLK1_117_P: length 3.8
  BOTTOM w0.102: U42.1 133.1,35.43 132.56,35.97 132.17,35.97 132.05,35.84 131.09,35.84 C330.1
MGTREFCLK1_118_C_N: length 89.5
  TOP w0.14: v1(57.69,45.04) U31.H5
  L16_SIGNAL w0.089: v1(128.46,39.12) 128.71,38.86 129.65,38.86 130.17,38.33 130.17,33.68 128.08,31.58 111.19,31.58 106.19,36.58 65.05,36.58 61.09,40.53 61.09,43.18 60.84,43.43 60.44,43.43 60.09,43.79 60.09,44.14 59.79,44.44 59.44,44.44 59.09,44.79 59.09,45.14 58.81,45.41 58.06,45.41 v1(57.69,45.04)
  BOTTOM w0.102: C327.2 129.03,39.12 v1(128.46,39.12)
MGTREFCLK1_118_C_P: length 88.7
  TOP w0.14: v1(57.69,46.04) U31.H6
  L16_SIGNAL w0.089: v1(128.46,38.35) 128.71,38.61 129.54,38.61 129.92,38.23 129.92,33.78 127.97,31.83 111.3,31.83 106.3,36.83 65.15,36.83 61.34,40.64 61.34,43.29 60.94,43.69 60.55,43.69 60.34,43.89 60.34,44.24 59.89,44.69 59.55,44.69 59.34,44.89 59.34,45.24 58.92,45.67 58.06,45.67 v1(57.69,46.04)
  BOTTOM w0.102: v1(128.46,38.35) 129.03,38.35 C328.2
MGTREFCLK1_118_N: length 3.8
  BOTTOM w0.102: C327.1 131.09,38.84 132.05,38.84 132.17,38.71 132.59,38.71 133.12,39.24 U42.4
MGTREFCLK1_118_P: length 3.8
  BOTTOM w0.102: C328.1 131.06,38.61 131.95,38.61 132.08,38.48 132.59,38.48 133.1,37.97 U42.3
Net_7: length 0.7
  TOP w0.14: v1(75.69,75.04) 75.19,74.54
Net_8: length 0.7
  TOP w0.14: v1(75.69,69.04) 75.19,68.54
Net_160: length 0.9
  TOP w0.14: 12.07,40.13 v1(12.7,39.5)
Net_161: length 0.9
  TOP w0.14: 12.07,38.86 v1(12.7,38.23)
Net_162: length 0.9
  TOP w0.14: 12.07,37.59 v1(12.7,36.96)
Net_163: length 0.9
  TOP w0.14: 12.07,35.05 v1(12.7,34.42)
Net_164: length 0.9
  TOP w0.14: 6.98,75.69 v1(7.62,75.06)
Net_165: length 0.9
  TOP w0.14: 4.45,75.69 v1(5.08,75.06)
Net_1121: length 0.9
  TOP w0.14: 12.07,33.78 v1(12.7,33.15)
Net_1122: length 0.9
  TOP w0.14: 14.61,26.16 v1(15.24,25.53)
PCA9545_RESETB_1P8: length 35.4
  TOP w0.14: U34.4 171.77,40.2 v1(171.07,39.5) ; U37.9 v1(151.91,17.42)
  L7_SIGNAL w0.095: v1(171.07,39.5) 169.67,38.1 169.67,30.1 156.99,17.42 v1(151.91,17.42)
PCA9545_RESETB_3P3: length 37.5
  TOP w0.14: U36.3 185.65,25.43 185.8,25.27 v1(186.06,25.27) R185.1 ; v1(156.59,16.13) 156.84,16.38 156.84,16.76 156.69,16.92 U37.15
  L9_SIGNAL w0.095: v1(156.59,16.13) 159.26,16.13 161.67,18.54 163.96,18.54 164.59,19.18 170.31,19.18 174.12,22.99 183.77,22.99 v1(186.06,25.27)
PCA9545_SCL_MAIN_1P8: length 6.7
  TOP w0.14: v1(181.74,14.1) R205.1 182.68,14.15 Q9.2
  BOTTOM w0.14: v1(181.74,14.1) R326.1 R338.1
PCA9545_SCL_MAIN_3P3: length 17.4
  TOP w0.14: U36.18 179.43,25.43 181.74,23.11 R198.1 v1(181.74,20.7) Q9.3
  BOTTOM w0.14: P11.2 186.56,20.7 v1(181.74,20.7)
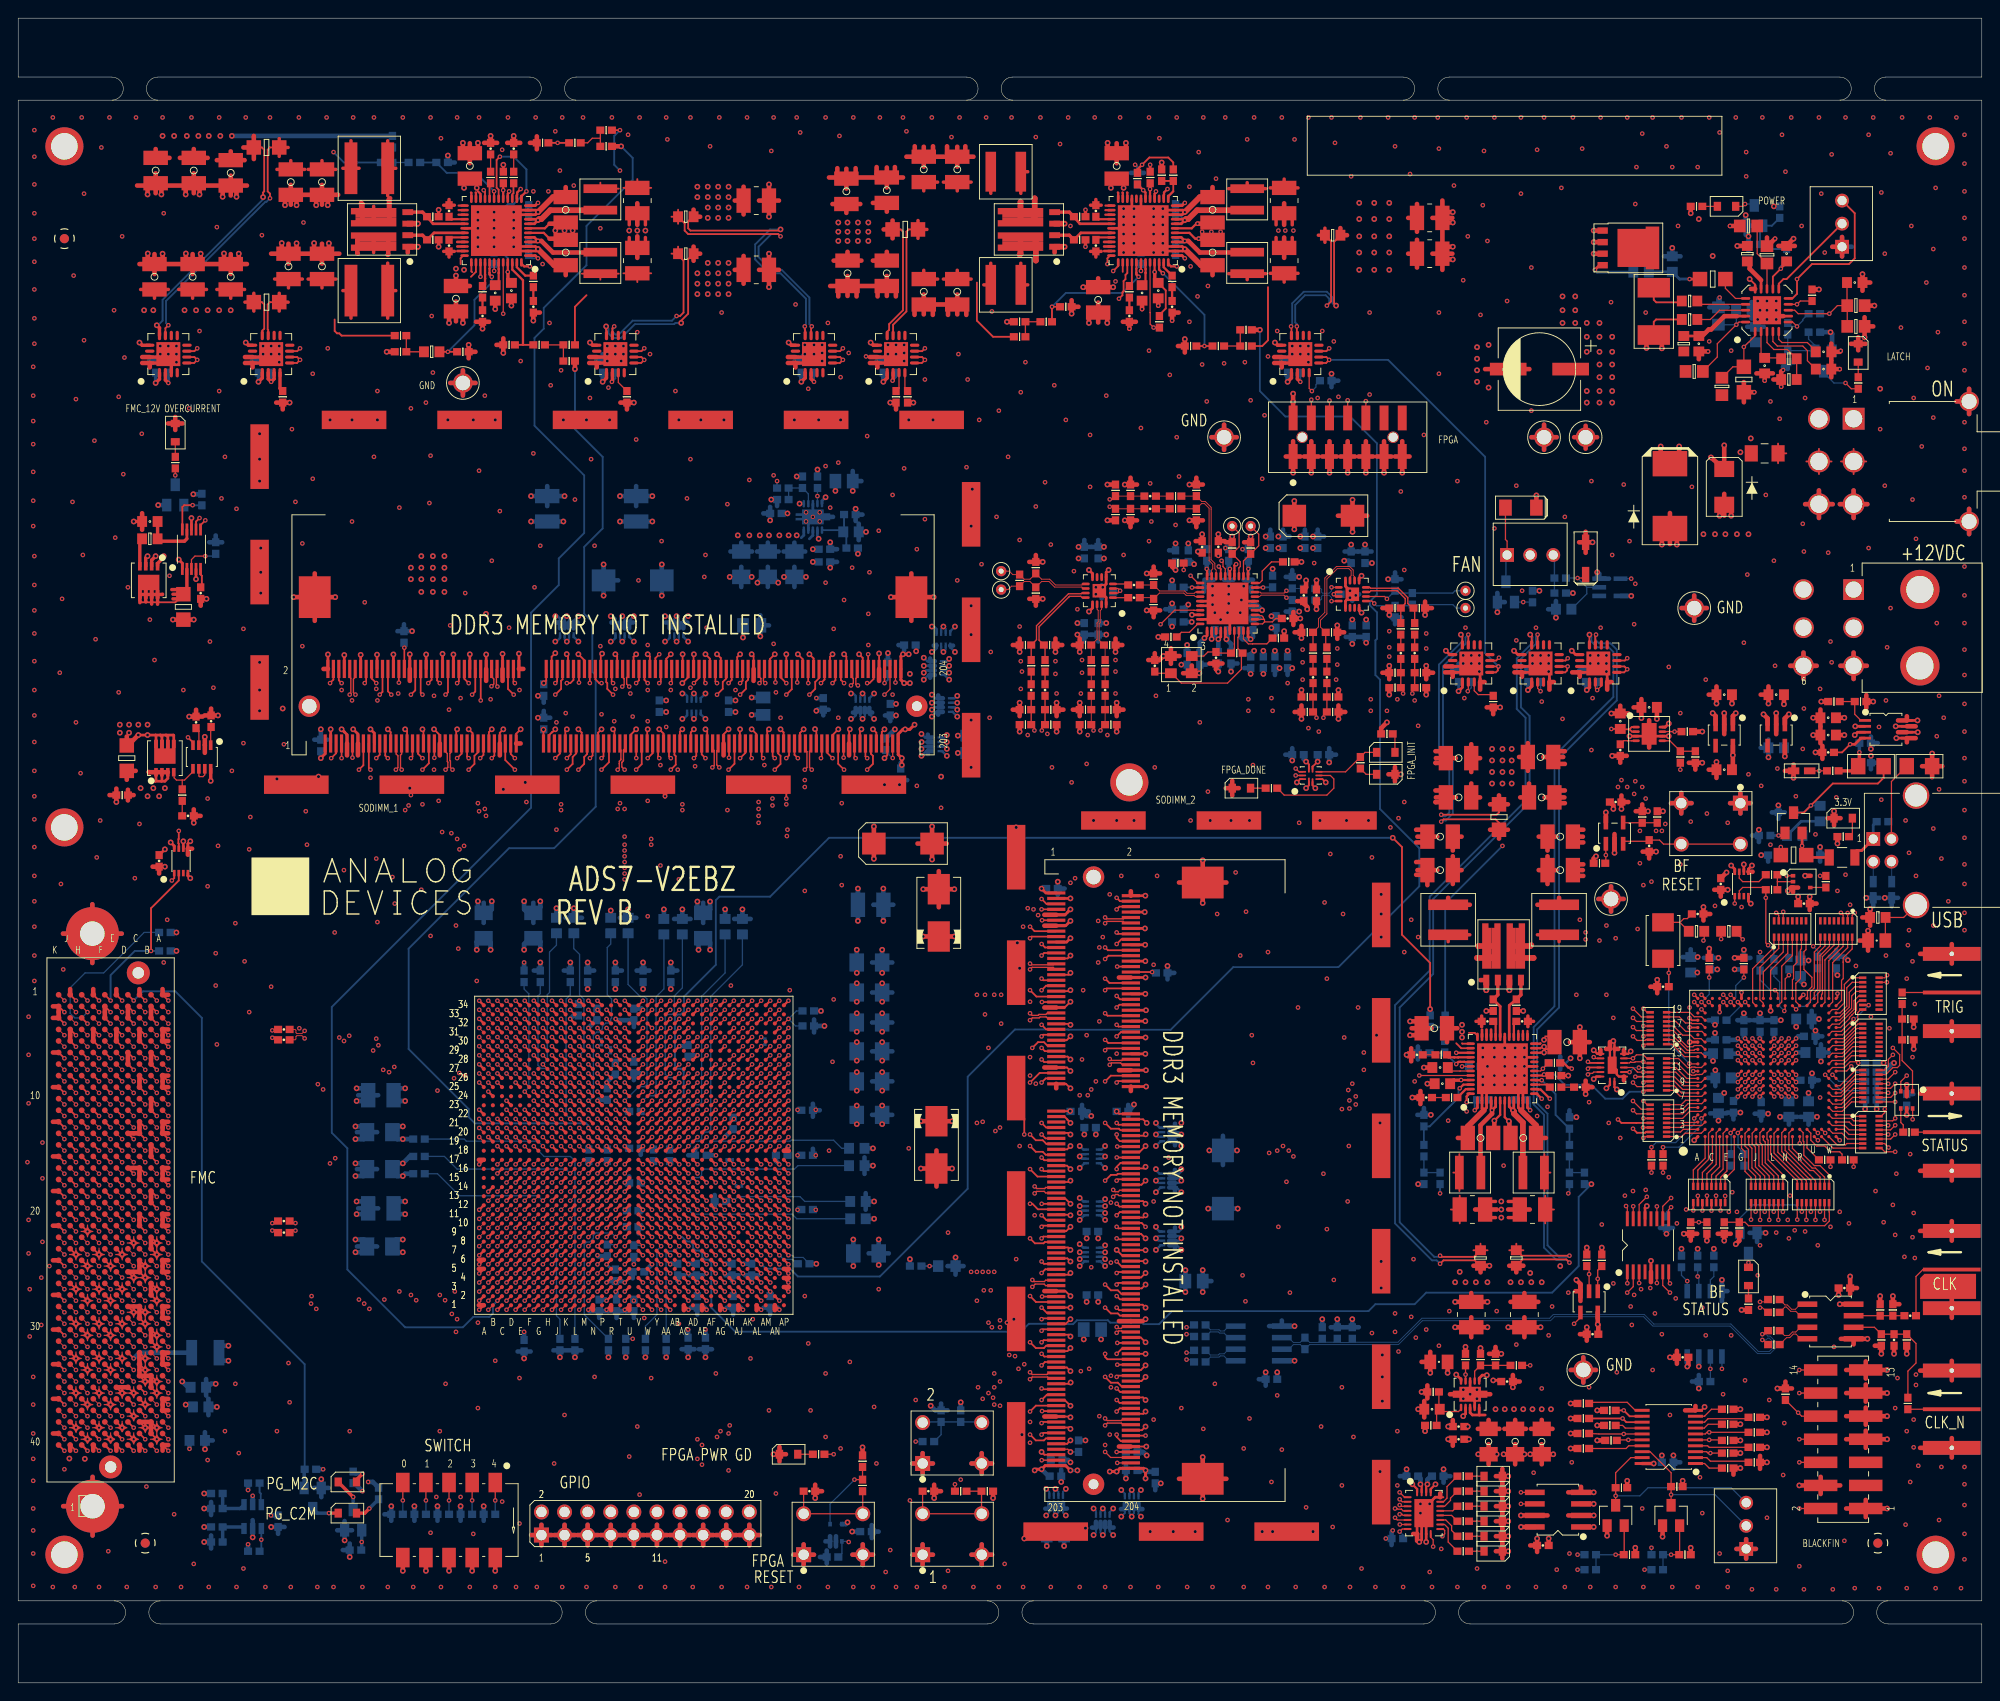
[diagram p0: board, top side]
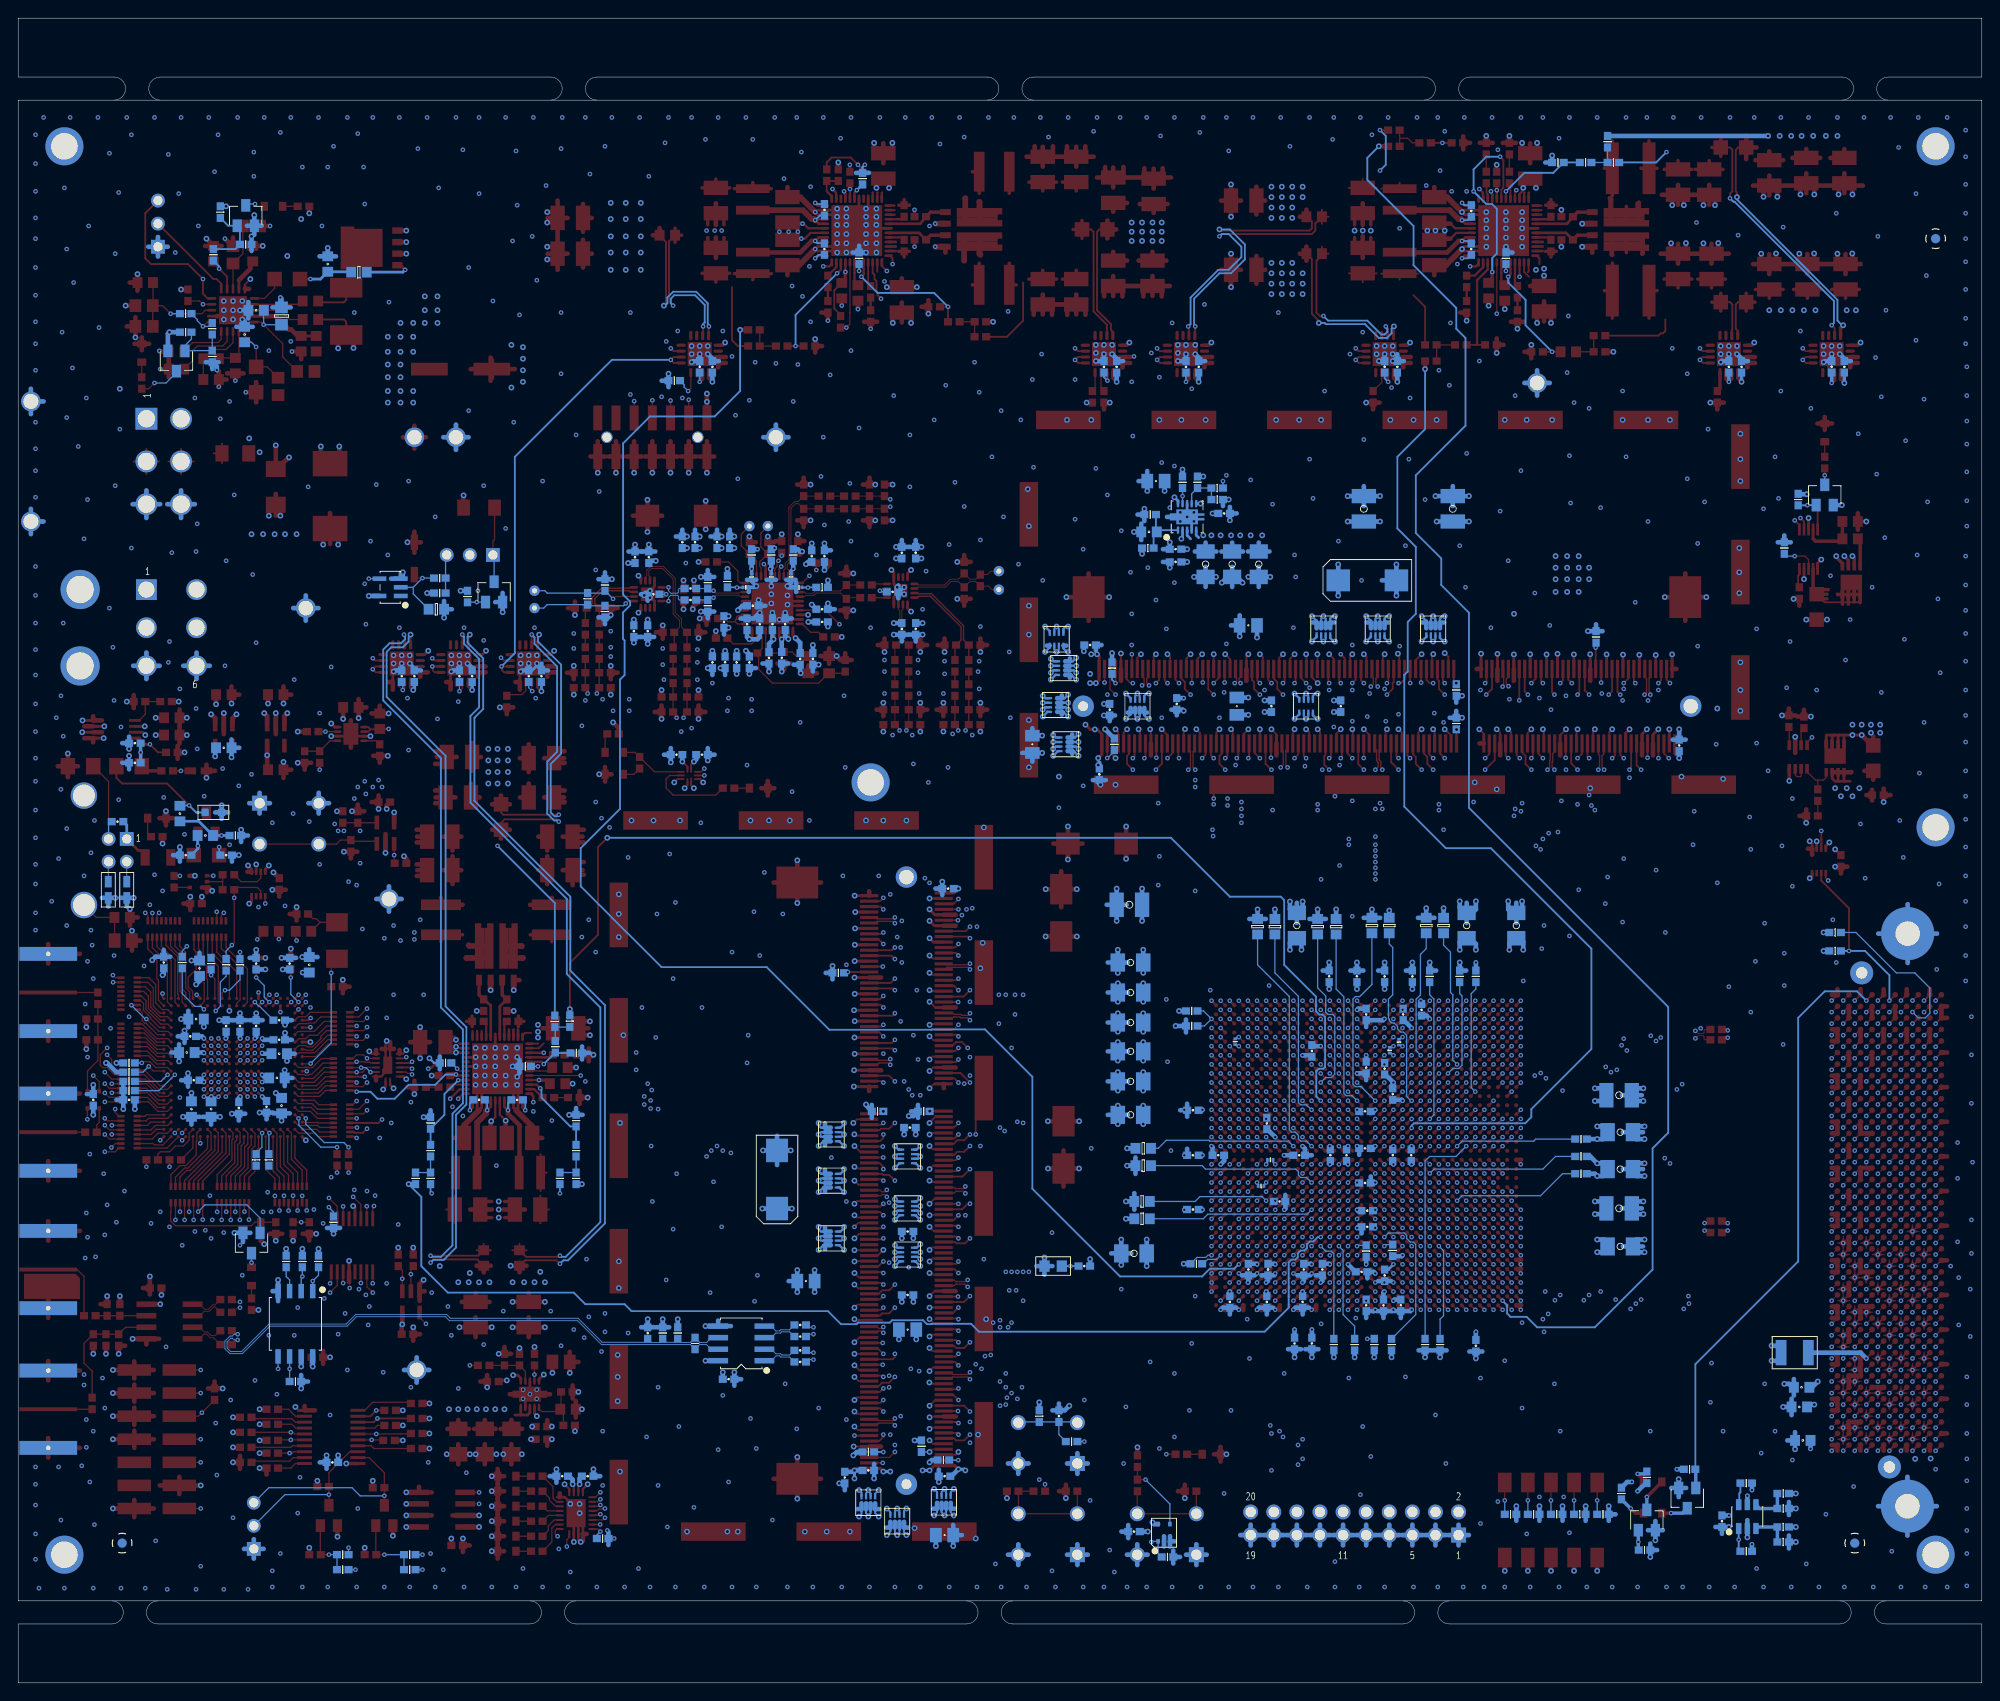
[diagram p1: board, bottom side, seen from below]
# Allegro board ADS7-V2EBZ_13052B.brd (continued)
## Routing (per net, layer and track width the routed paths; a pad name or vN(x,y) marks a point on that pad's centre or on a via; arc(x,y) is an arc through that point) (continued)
PCA9545_SDA_MAIN_1P8: length 7.9
  TOP w0.14: Q8.2 176.58,14.15 R204.1 v1(175.64,14.1)
  BOTTOM w0.14: v1(175.64,14.1) R327.1 R339.1
PCA9545_SDA_MAIN_3P3: length 22.6
  TOP w0.14: U36.19 177.3,24.78 175.64,23.11 R197.1 v1(175.64,20.57) Q8.3
  BOTTOM w0.14: v1(175.64,20.57) 178.31,20.57 179.2,21.46 188.34,21.46 P11.3
PG0: length 14
  TOP w0.14: R155.1 R156.2 189.87,50.67 190.25,50.29 198.63,50.29 199.14,50.8 199.14,51.79 199.11,51.82 RN11.16
PG7: length 16.2
  TOP w0.14: R154.1 v1(184.78,50.67) R382.2 ; RN11.9 v1(195.61,50.95)
  L18_SIGNAL w0.095: v1(184.78,50.67) 185.8,49.66 189.61,49.66 190.5,48.77 193.42,48.77 v1(195.61,50.95)
PMU_#3_VCAP: length 3
  TOP w0.14: U16.2 173.41,109.42 v1(173.61,109.22) 174.06,109.67 U16.3
  BOTTOM w0.14: C206.1 173.61,109.98 v1(173.61,109.22)
PMU_#6_VCAP: length 3.3
  TOP w0.381: U4.3 28.14,143.45 v1(27.81,143.13) 27.49,143.45 U4.2
  BOTTOM w0.381: C159.1 v1(27.81,143.13)
PMU_SCL: length 416.6
  TOP w0.203: v1(99.7,146.81) 99.39,146.5 U7.7 ; U36.13 176.81,28.68 v1(176.4,29.08) R178.1 ; U4.7 30.68,146.5 v1(30.99,146.81) ; U9.11 193.58,153.92 194.09,154.43 194.44,154.43 P2.2 ; U10.6 20.05,127.36 v1(20.57,127.89) ; v1(144.15,146.81) 143.84,146.5 U8.7 ; v1(170.37,112.71) 170.12,112.47 U15.7 ; v1(19.68,146.81) 19.38,146.5 U3.7 ; v1(176.91,112.72) 176.66,112.47 U16.7 ; v1(68.83,146.81) 68.52,146.5 U5.7 ; U14.7 162.5,112.47 v1(162.81,112.78) ; U6.7 90.37,146.5 v1(90.68,146.81)
  L5_SIGNAL w0.203: v1(20.57,127.89) 20.57,127.25 20.07,126.75 18.92,126.75 18.03,127.63 18.03,145.16 v1(19.68,146.81) 25.53,146.81 26.54,147.83 29.97,147.83 v1(30.99,146.81) 32.26,148.08 67.56,148.08 v1(68.83,146.81) 82.8,146.81 84.2,148.21 89.28,148.21 v1(90.68,146.81) 94.36,146.81 95.63,148.08 98.42,148.08 v1(99.7,146.81) 112.14,146.81 113.92,148.59 121.98,148.59 122.01,148.56 122.34,148.56 122.37,148.59 134.62,148.59 135.25,147.96 137.95,147.96 137.96,147.97 142.99,147.97 v1(144.15,146.81) 153.92,146.81 171.96,164.85 201.3,164.85 202.06,164.08 202.06,162.05 P2.2 ; v1(176.91,112.72) 175.97,113.67 172.47,113.67 171.51,112.71 v1(170.37,112.71) 169.16,113.92 166.24,113.92 165.1,112.78 v1(162.81,112.78)
  L9_SIGNAL w0.203: v1(176.91,112.72) 179.32,110.31 179.32,103.51 173.48,97.66 173.48,94.62 171.95,93.08 171.95,86.63 174.24,84.33 175.64,84.33 176.4,83.57 176.4,80.77 173.99,78.36 173.99,53.98 171.95,51.93 171.95,43.45 174.88,40.51 174.88,30.48 176.28,29.08 v1(176.4,29.08)
  L20_SIGNAL w0.203: v1(144.15,146.81) 150.37,146.81 164.34,132.84 169.93,132.84 176.53,126.24 176.53,113.1 v1(176.91,112.72)
PMU_SDA: length 464.5
  TOP w0.203: U14.5 162.47,111.17 162.69,111.38 162.69,111.74 v1(162.76,111.82) U14.6 ; U9.10 195.07,152.3 195.58,152.81 v1(195.58,154.43) 197.23,156.08 201.29,156.08 201.93,156.72 201.93,161.67 P2.3 ; U8.5 143.8,145.2 v1(144.15,145.54) 143.84,145.85 U8.6 ; U7.6 99.39,145.85 v1(99.7,145.54) 99.35,145.2 U7.5 ; U3.6 19.38,145.85 v1(19.68,145.54) 19.34,145.2 U3.5 ; U6.6 90.37,145.85 v1(90.68,145.54) 90.34,145.2 U6.5 ; U15.6 v1(170.36,111.82) 170.31,111.76 170.31,111.38 170.09,111.17 U15.5 ; U5.6 68.52,145.85 v1(68.83,145.54) 68.49,145.2 U5.5 ; U4.6 30.68,145.85 v1(30.99,145.54) 30.65,145.2 U4.5 ; R172.1 v1(176.53,29.97) 177.18,29.33 U36.12 ; v1(19.94,128.14) 19.55,127.75 U10.7 ; U16.5 176.57,111.17 v1(176.91,111.51) 176.6,111.82 U16.6
  L5_SIGNAL w0.203: P2.3 196.09,163.07 195.45,163.7 172.34,163.7 154.18,145.54 v1(144.15,145.54) 142.75,144.15 138.3,144.15 137.16,143 116.97,143 116.08,143.89 110.34,143.89 110.32,143.88 106.57,143.88 104.9,145.54 102.97,145.54 102.96,145.53 102.53,145.53 102.51,145.54 v1(99.7,145.54) 98.42,144.27 93.6,144.27 92.33,145.54 v1(90.68,145.54) 89.41,144.27 84.07,144.27 82.8,145.54 v1(68.83,145.54) 67.12,143.83 53.09,143.83 51.37,145.54 v1(30.99,145.54) 30.1,144.65 24.51,144.65 23.62,145.54 v1(19.68,145.54) 19.68,143.01 19.95,142.75 19.95,130.59 19.94,130.58 v1(19.94,128.14) ; v1(162.76,111.82) 163.52,111.82 164.85,110.49 169.04,110.49 v1(170.36,111.82) 171.39,111.82 172.85,110.36 175.77,110.36 v1(176.91,111.51)
  L16_SIGNAL w0.203: v1(183.77,74.3) 180.09,70.61 180.09,60.2 176.02,56.13 176.02,41.28 176.53,40.77 v1(176.53,29.97)
  L18_SIGNAL w0.203: v1(183.77,74.3) 183.77,77.09 182.37,78.49 182.37,88.14 184.91,90.68 184.91,98.55 183.9,99.57 183.9,113.03 179.2,117.73 179.2,141.22 183.39,145.41 183.39,151.77 188.59,156.97 193.04,156.97 v1(195.58,154.43)
  BOTTOM w0.203: v1(144.15,145.54) 150.62,145.54 161.29,134.87 161.29,113.28 v1(162.76,111.82)
PROGB: length 143
  TOP w0.14: v1(178.69,71.12) 178.83,71.26 RN9.14 ; v1(66.69,48.04) U31.U8
  L3_SIGNAL w0.095: v1(67.56,37.85) 67.56,41.02 67.18,41.4 67.18,47.55 v1(66.69,48.04)
  L16_SIGNAL w0.095: v1(178.69,71.12) 177.93,70.36 176.91,70.36 176.53,69.98 176.53,64.01 172.21,59.69 137.16,59.69 134.87,57.4 130.05,57.4 128.52,55.88 127.76,55.88 126.87,54.99 126.87,52.83 125.73,51.69 125.73,48.77 125.22,48.26 120.52,48.26 119.25,49.53 116.84,49.53 114.68,47.37 108.33,47.37 107.57,48.13 89.15,48.13 88.65,48.64 67.18,48.64 66.69,48.15 v1(66.69,48.04)
  BOTTOM w0.14: R310.1 v1(67.56,37.85)
PWRGD_LED: length 76.8
  TOP w0.14: v1(151.89,16.64) 152.17,16.92 U37.10 ; v1(178.69,74.17) 179.1,73.76 RN9.9
  L16_SIGNAL w0.095: v1(151.89,16.64) 153.67,16.64 159.64,22.61 159.64,25.4 161.93,27.69 168.02,27.69 169.67,29.34 169.67,43.94 171.32,45.59 171.32,50.55 174.75,53.98 174.75,56.64 178.18,60.07 178.18,62.36 179.58,63.75 179.58,73.28 v1(178.69,74.17)
  BOTTOM w0.14: v1(151.89,16.64) 152.27,16.26 R341.1
RD_RDY: length 137.4
  TOP w0.14: v1(83.69,70.04) U31.AN29 ; RN10.11 v1(191.53,50.93)
  L3_SIGNAL w0.095: v1(191.53,50.93) 191.52,50.94 191.52,54.86 189.1,57.28 184.15,57.28 182.18,59.25 182.18,73.09 177.04,78.23 157.99,78.23 156.08,76.33 120.4,76.33 119.76,75.69 117.98,75.69 116.46,74.17 111.12,74.17 109.86,72.9 109.86,71.76 106.68,68.58 97.41,68.58 96.52,69.47 84.26,69.47 v1(83.69,70.04)
RDWRB: length 152.4
  TOP w0.14: v1(79.69,67.04) U31.AJ26 ; RN9.16 178.84,70.26 v1(178.69,70.1)
  L16_SIGNAL w0.095: v1(79.69,67.04) 79.69,67.12 79.25,67.56 79.25,71.5 79.38,71.63 79.88,71.63 80.34,72.08 80.34,72.19 80.54,72.39 80.65,72.39 81.15,72.9 81.15,75.95 86.23,81.03 88.39,81.03 92.71,85.34 95.25,85.34 96.39,86.49 96.39,87.88 100.46,91.95 102.49,91.95 112.52,101.98 153.92,101.98 160.53,95.38 173.35,95.38 173.99,94.74 176.4,94.74 177.8,93.34 178.82,93.34 179.71,94.23 180.21,94.23 v1(180.72,93.73)
  L18_SIGNAL w0.095: v1(180.72,93.73) 180.72,93.34 180.97,93.09 180.97,71.25 179.83,70.1 v1(178.69,70.1)
SCL: length 210.9
  TOP w0.14: P5.202 v1(120.84,24.2) ; U36.16 v1(177.04,26.73) 175.82,26.73 R182.1 ; P6.202 v1(96.45,110.05) ; U38.6 v1(165.23,19.68) ; U12.37 129.28,117.99 129.27,118.01 127.15,118.01 v1(125.6,116.46)
  L9_SIGNAL w0.095: v1(177.04,26.73) 172.41,22.1 169.42,22.1 167,19.68 v1(165.23,19.68) 164.59,20.32 162.05,20.32 157.99,24.38 148.84,24.38 147.83,23.37 125.98,23.37 125.16,24.2 v1(120.84,24.2) ; v1(96.45,110.05) 96.45,112.08 96.77,112.39 96.77,115.44 98.38,117.05 125.01,117.05 v1(125.6,116.46)
  L22_SIGNAL w0.095: v1(125.6,116.46) 124.21,115.06 124.21,107.7 128.4,103.51 128.4,85.09 129.92,83.57 129.92,53.98 126.75,50.8 126.75,25.78 125.16,24.2 v1(120.84,24.2)
SDA: length 228.4
  TOP w0.14: v1(128.91,121.79) 129.7,120.99 U12.31 ; P6.200 95.86,109.32 v1(95.25,108.71) ; U36.15 v1(176.53,27.38) 173.81,27.38 R179.1 ; U38.5 v1(165.23,20.96) ; v1(119.51,25.4) 120.11,24.79 P5.200
  L9_SIGNAL w0.095: v1(128.91,121.79) 125.98,118.87 116.2,118.87 115.06,117.73 98.04,117.73 96.27,115.95 96.27,112.78 95.76,112.27 95.76,109.22 v1(95.25,108.71) ; v1(176.53,27.38) 172.01,22.86 168.78,22.86 166.88,20.96 v1(165.23,20.96) 164.47,21.72 161.93,21.72 158.37,25.27 148.21,25.27 147.19,24.26 126.24,24.26 124.97,25.53 122.05,25.53 121.54,26.04 120.14,26.04 v1(119.51,25.4)
  L22_SIGNAL w0.095: v1(119.51,25.4) 119.76,25.4 120.4,26.04 122.81,26.04 123.44,26.67 125.22,26.67 126.11,27.56 126.11,51.06 129.29,54.24 129.29,83.3 127.76,84.83 127.76,103.24 123.57,107.43 123.57,115.57 125.98,117.98 125.98,119.38 126.62,120.02 127.13,120.02 v1(128.91,121.79)
SMA_GPIO0_N: length 135.4
  TOP w0.102: v1(191.52,41.28) 191.77,41.28 192.28,40.77 R162.2
  TOP w0.14: v1(76.69,72.04) U31.AF31
  L20_SIGNAL w0.089: v1(76.69,72.04) 76.32,71.67 76.32,70.98 76.34,70.96 76.34,70.89 76.55,70.69 90.2,70.69 91.42,69.47 97.41,69.47 102.87,64.01 121.18,64.01 121.69,64.52 139.68,64.52 155.17,49.02 178.79,49.02 182.35,45.47 187.58,45.47 190.25,42.8 190.25,41.28 191.13,40.39 192.3,40.39 192.79,40.87 192.79,41.04 192.43,41.4 191.64,41.4 v1(191.52,41.28)
SMA_GPIO0_P: length 136.6
  TOP w0.102: v1(191.52,41.91) 192.15,41.91 R161.2
  TOP w0.14: v1(75.69,72.04) U31.AE31
  L20_SIGNAL w0.089: v1(75.69,72.04) 76.06,71.67 76.06,70.87 76.09,70.85 76.09,70.79 76.44,70.44 90.09,70.44 91.31,69.22 97.3,69.22 102.76,63.75 121.28,63.75 121.79,64.26 139.57,64.26 155.07,48.77 178.69,48.77 182.25,45.21 187.47,45.21 189.99,42.69 189.99,41.17 191.03,40.13 192.41,40.13 193.04,40.77 193.04,41.15 192.53,41.66 191.77,41.66 v1(191.52,41.91)
SMA_GPIO_J5: length 172.8
  TOP w0.14: v1(74.69,70.04) U31.AD29 ; U30.6 v1(208.29,61.99)
  L5_SIGNAL w0.095: v1(208.29,61.99) 208.28,61.98 208.28,59.56 203.07,54.36 186.06,54.36 179.32,61.09 179.32,74.17 176.4,77.09 145.03,77.09 135.63,86.49 129.13,86.49 125.71,89.92 118.88,89.92 118.8,90 115.44,90 115.36,89.92 113.67,89.92 109.47,85.73 109.47,83.69 103.25,77.47 97.92,77.47 96.14,75.69 91.82,75.69 89.03,72.9 88.52,72.9 87,71.37 87,70.61 85.98,69.6 75.18,69.6 74.74,70.04 v1(74.69,70.04)
SMA_GPIO_J6: length 174.5
  TOP w0.14: v1(75.69,70.04) U31.AE29 ; v1(207.65,66.8) 207,66.15 U30.3
  L5_SIGNAL w0.095: v1(75.69,70.04) 77.15,70.04 77.8,70.69 77.84,70.69 78.04,70.89 78.04,70.93 78.8,71.69 78.84,71.69 79.04,71.89 79.04,77.01 80.14,78.11 80.14,78.74 84.71,83.31 95.76,83.31 98.55,86.11 99.5,86.11 101.03,87.63 101.03,88.58 107.57,95.12 116.97,95.12 117.73,94.36 134.05,94.36 145.23,83.19 155.83,83.19 158.24,80.77 181.98,80.77 183.32,79.43 183.32,70.7 183.31,70.68 183.31,64.34 184.33,63.31 187.64,63.31 189.23,61.72 199.26,61.72 205.23,67.69 206.76,67.69 v1(207.65,66.8)
SYS_CLK_N: length 85.7
  TOP w0.102: C56.2 R63.2 R62.1 120.29,130.2 v1(120.02,130.2)
  TOP w0.14: v1(81.69,71.04) U31.AL30
  L7_SIGNAL w0.089: v1(120.02,130.2) 119.74,129.92 116.48,129.92 110.74,124.18 110.74,119.74 107.82,116.82 107.82,105.13 95.65,92.96 94.26,92.96 86.33,85.04 86.33,71.36 85.66,70.69 82.09,70.69 81.74,71.04 v1(81.69,71.04)
  BOTTOM w0.102: v1(81.69,71.04) 81.91,71.04 R670.2
SYS_CLK_P: length 85.8
  TOP w0.102: C57.2 R66.1 R65.1 120.65,129.29 120.52,129.41 120.04,129.41 v1(120.02,129.39)
  TOP w0.14: v1(81.69,70.04) U31.AL29
  L7_SIGNAL w0.089: v1(120.02,129.39) 119.74,129.67 116.59,129.67 111,124.08 111,119.63 108.08,116.71 108.08,105.03 95.76,92.71 94.36,92.71 86.59,84.94 86.59,71.26 85.77,70.44 81.99,70.44 81.69,70.13 v1(81.69,70.04)
  BOTTOM w0.102: v1(81.69,70.04) 81.91,70.04 R670.1
UNNAMED_1_CAP_I16_N1: length 49.1
  TOP w0.203: v1(65.69,56.04) U31.T16 ; v1(68.69,56.04) U31.V16 ; v1(68.69,57.04) U31.V17
  L7_SIGNAL w0.254: v1(68.69,56.04) 68.66,56.01 68.07,56.01 67.56,56.52 66.17,56.52 v1(65.69,56.04) ; v1(68.69,56.04) v1(68.69,57.04) ; v1(68.69,56.04) 68.69,56.02 69.22,55.5 69.22,49.02 69.26,48.98 69.26,48.86 69.51,48.61 69.63,48.61 69.77,48.47 69.87,48.47 70.12,48.22 70.12,48.11 70.26,47.98 70.26,47.86 70.51,47.61 70.63,47.61 70.77,47.47 70.87,47.47 71.12,47.22 71.12,47.11 71.26,46.98 71.26,46.86 71.51,46.61 71.63,46.61 71.75,46.48 86.23,46.48 87.88,44.83 99.19,44.83 v1(100.2,45.85)
  BOTTOM w0.203: E3.2 v1(100.2,45.85) C308.1
UNNAMED_1_CAP_I46_N2: length 11.5
  TOP w0.14: C336.2 S5.3 S5.4 92.86,21.06 92.84,21.08
UNNAMED_1_CMOSNC7SZ125_I41_A: length 3.4
  TOP w0.14: R134.1 193.42,88.14 ; 193.42,88.14 R135.1 ; 193.42,88.14 U26.2
UNNAMED_1_CMOSNC7SZ125_I41_Y: length 1.7
  TOP w0.14: R136.1 197.05,87.5 U26.4
UNNAMED_1_DIOLED_I22_P: length 1.7
  TOP w0.14: DS15.A R126.1
UNNAMED_1_DIOLED_I25_P: length 2.1
  TOP w0.14: DS16.A 148.21,99.95 R118.1
UNNAMED_1_DIOLED_I29_N: length 7.2
  TOP w0.14: U22.5 145.94,100.22 148.08,102.36 DS17.C
UNNAMED_1_DIOLED_I29_P: length 2.1
  TOP w0.14: DS17.A 151.37,104.15 R119.1
UNNAMED_1_ICNC7WZ08K_I31_Y1: length 4.1
  TOP w0.14: U25.7 189.23,89.22 189.23,88.52 189.61,88.14 191.39,88.14 R134.2
UNNAMED_1_ICXC7VX330T_I1_M10: length 11.9
  TOP w0.14: v1(72.69,48.04) U31.AB8
  BOTTOM w0.14: v1(72.69,48.04) 72.14,47.49 71.5,47.49 71.24,47.23 71.24,40.85 71.25,40.85 R308.1
UNNAMED_1_ICXC7VX330T_I1_M20: length 11.6
  TOP w0.14: v1(70.69,48.04) U31.Y8
  BOTTOM w0.14: v1(70.69,48.04) 70.23,47.58 70.23,40.51 68.96,39.24 R309.1
UNNAMED_1_ICXC7VX330T_I2_IOL3PT: length 4.5
  TOP w0.14: v1(84.69,73.04) U31.AP32
  BOTTOM w0.14: R274.2 85.47,72.26 v1(84.69,73.04) 85.57,73.91 R272.1
UNNAMED_1_RES_I23_N2: length 9.7
  TOP w0.14: R126.2 139.19,97.66 143.89,97.66 144.65,98.42 144.65,99.44 144.27,99.82 U22.4
UNNAMED_5_ICXC7VX330T_I9_MGTRRE: length 3.1
  TOP w0.14: v1(83.69,47.04) U31.AN7
  BOTTOM w0.14: v1(83.69,47.04) 84.14,46.59 85.11,46.59 85.6,46.1 85.73,46.1
UNNAMED_10_ADSPBF52XV3_I35_EMU: length 6.1
  TOP w0.14: R153.1 200.53,58.17 200.28,58.42 199.26,58.42 198.63,59.06 197.74,59.06 197.1,59.69 197.1,60.47 U29.T2
UNNAMED_10_ADSPBF52XV3_I35_TDO: length 3.1
  TOP w0.14: R152.1 196.68,58.85 U29.T1
UNNAMED_10_ADSPBF52XV3_I35_US_1: length 3.4
  TOP w0.14: U29.H19 v1(189.88,74.89)
  BOTTOM w0.14: v1(189.88,74.89) 189.41,74.42 189.36,74.42 C260.1
UNNAMED_10_ADSPBF52XV3_I35_USBV: length 34
  TOP w0.14: CR2.1 v1(198.02,100.33) R128.1 ; U29.E19 v1(187.48,74.89)
  L7_SIGNAL w0.095: v1(187.48,74.89) 187.48,74.9 186.94,75.44 186.94,76.45 187.96,77.47 187.96,86.11 192.15,90.3 192.15,96.65 193.93,98.42 196.12,98.42 v1(198.02,100.33)
UNNAMED_10_ADSPBF52XV3_I35_USBX: length 9.6
  TOP w0.14: U29.A19 v1(184.28,74.89) ; R138.2 v1(187.24,81.83)
  L7_SIGNAL w0.095: v1(187.24,81.83) 187.2,81.79 187.2,81.03 185.29,79.12 185.29,77.6 184.66,76.96 184.66,75.27 v1(184.28,74.89)
UNNAMED_10_CAP_I42_N1: length 6.5
  TOP w0.14: C105.1 205.3,84.18 R139.1 207.31,84.2 P8.G2
UNNAMED_10_CAP_I105_N1: length 6.1
  TOP w0.381: v1(202.44,102.36) 202.44,100.97 E1.1 201.8,100.33 R128.2
  BOTTOM w0.381: C227.1 v1(202.44,102.36) C226.1
UNNAMED_10_CAP_I111_N1: length 23.6
  TOP w0.203: R131.2 v1(193.8,91.95) ; Q6.3 196.32,95.73 v1(197.1,96.52) 199.52,98.93 204.47,98.93 205.1,99.57 E1.2
  L7_SIGNAL w0.203: v1(193.8,91.95) 194.94,93.09 194.94,94.36 v1(197.1,96.52)
  BOTTOM w0.203: V1.1 196.34,95.76 v1(197.1,96.52) 198.08,96.52 C233.2 ; C238.1 193.8,91.19 v1(193.8,91.95)
UNNAMED_10_CAP_I113_N1: length 7.7
  TOP w0.305: Q6.2 v1(196.14,92.08) 196.14,91.52 R131.1 196.85,90.81 F3.2
  BOTTOM w0.305: C236.1 196.14,91.77 v1(196.14,92.08) 196.18,92.11 C237.1
UNNAMED_10_CAP_I113_N2: length 6.9
  TOP w0.305: Q6.1 193.98,93.22 v1(193.55,93.22)
  BOTTOM w0.305: R247.2 v1(193.55,93.22) C237.2 196.04,94.78 C233.1
UNNAMED_10_CAP_I121_N1: length 5.2
  TOP w0.305: F3.1 201.94,91.33 202.18,91.57 202.69,91.57 P8.1
  BOTTOM w0.305: P8.1 203.96,94.36 204.34,94.74
UNNAMED_10_CAP_I121_N2: length 10.7
  TOP w0.14: E2.1 205.96,99.15 P8.4
  BOTTOM w0.14: P8.4 205.96,94.39 C235.2
UNNAMED_11_ADP1715B_I46_SS: length 4.1
  TOP w0.203: v1(201.42,103.25) 200.53,102.36 C89.2
  TOP w0.305: v1(201.42,103.25) 201.93,103.25 202.61,103.93 U21.4
UNNAMED_11_ADP7105_I21_EN: length 4.1
  TOP w0.14: R122.1 R120.2 181.61,103.63 181.27,103.63 181.25,103.64 U18.5
UNNAMED_11_ADP7105_I21_SS: length 1.9
  TOP w0.14: U18.4 177.4,103.64 177.38,103.63 176.96,103.63 176.94,103.64 176.54,103.64 C86.1
UNNAMED_11_DIOLED_I23_P: length 2.2
  TOP w0.14: DS7.A 201.67,93.46 R132.1
UNNAMED_12_ADSPBF52XV3_I42_PF0: length 5.9
  TOP w0.14: RN6.1 187.68,55.47 188.68,56.47 U29.F1
UNNAMED_12_ADSPBF52XV3_I42_PF1: length 5.8
  TOP w0.14: RN6.2 187.18,55.61 187.88,56.31 U29.E1
UNNAMED_12_ADSPBF52XV3_I42_PF2: length 6.8
  TOP w0.14: U29.E2 187.88,60.88 187.45,60.45 187.45,56.52 186.68,55.74 RN6.3
UNNAMED_12_ADSPBF52XV3_I42_PF3: length 5.8
  TOP w0.14: RN6.4 186.18,54.62 186.18,55.88 187.08,56.78 U29.D1
UNNAMED_12_ADSPBF52XV3_I42_PF4: length 6.8
  TOP w0.14: RN6.5 185.68,56.01 186.69,57.02 186.69,60.5 U29.D2
UNNAMED_12_ADSPBF52XV3_I42_PF5: length 5.9
  TOP w0.14: RN6.6 185.18,56.15 186.28,57.25 U29.C1
UNNAMED_12_ADSPBF52XV3_I42_PF6: length 6.9
  TOP w0.14: U29.C2 185.85,60.47 185.85,57.58 184.68,56.41 RN6.7
UNNAMED_12_ADSPBF52XV3_I42_PF7: length 6
  TOP w0.14: U29.B1 185.48,57.72 184.18,56.42 RN6.8
UNNAMED_12_ADSPBF52XV3_I42_PF8: length 4.6
  TOP w0.14: RN7.1 182.91,60.1 183.27,60.47 185.05,60.47 U29.B2
UNNAMED_12_ADSPBF52XV3_I42_PF9: length 3.6
  TOP w0.14: U29.A2 183.06,60.89 182.77,60.6 RN7.2
UNNAMED_12_ADSPBF52XV3_I42_PF10: length 4.5
  TOP w0.14: U29.B3 185.1,61.32 182.98,61.32 182.76,61.1 RN7.3
UNNAMED_12_ADSPBF52XV3_I42_PF11: length 3.5
  TOP w0.14: RN7.4 182.88,61.6 182.93,61.64 184.46,61.64 184.52,61.69 U29.A3
UNNAMED_12_ADSPBF52XV3_I42_PF12: length 4.7
  TOP w0.14: RN7.5 183,62.1 183.77,62.87 185.05,62.87 U29.B5
UNNAMED_12_ADSPBF52XV3_I42_PF13: length 3.7
  TOP w0.14: RN7.6 183,62.6 183.69,63.29 U29.A5
UNNAMED_12_ADSPBF52XV3_I42_PF14: length 4.6
  TOP w0.14: RN7.7 182.99,63.1 183.6,63.72 185.1,63.72 U29.B6
UNNAMED_12_ADSPBF52XV3_I42_PF15: length 3.6
  TOP w0.14: U29.A6 183.34,64.09 182.85,63.6 RN7.8
UNNAMED_12_ADSPBF52XV3_I42_PG0: length 8
  TOP w0.14: U29.R2 196.25,60.52 196.25,59.62 196.33,59.54 196.33,58.05 197.49,56.9 198.12,56.9 199.11,55.91 RN11.1
UNNAMED_12_ADSPBF52XV3_I42_PG1: length 7.1
  TOP w0.14: RN11.2 198.61,55.63 197.61,56.63 197.24,56.63 195.08,58.79 U29.P1
UNNAMED_12_ADSPBF52XV3_I42_PG2: length 8.1
  TOP w0.14: RN11.3 198.12,54.63 198.12,55.63 197.38,56.36 197,56.36 194.69,58.67 194.69,60.5 U29.P2
UNNAMED_12_ADSPBF52XV3_I42_PG3: length 6.9
  TOP w0.14: U29.N1 194.28,58.58 196.59,56.26 197.61,55.25 197.61,54.62 RN11.4
UNNAMED_12_ADSPBF52XV3_I42_PG4: length 7.8
  TOP w0.14: RN11.5 197.11,55.24 193.9,58.44 193.9,60.52 U29.N2
UNNAMED_12_ADSPBF52XV3_I42_PG5: length 6.8
  TOP w0.14: RN11.6 196.61,55.23 193.48,58.36 U29.M1
UNNAMED_12_ADSPBF52XV3_I42_PG6: length 7.7
  TOP w0.14: RN11.7 196.11,55.22 193.05,58.28 193.05,60.46 193.48,60.89 U29.M2
UNNAMED_12_ADSPBF52XV3_I42_PG7: length 6.7
  TOP w0.14: RN11.8 195.61,55.22 192.68,58.15 U29.L1
UNNAMED_12_ADSPBF52XV3_I42_PG8: length 7.2
  TOP w0.14: RN10.1 194.03,55.91 192.41,57.53 192.41,59.69 192.28,59.82 192.28,60.49 U29.L2
UNNAMED_12_ADSPBF52XV3_I42_PG9: length 6.2
  TOP w0.14: U29.K1 191.88,59.71 192.09,59.5 192.09,57.21 193.53,55.77 RN10.2
UNNAMED_12_ADSPBF52XV3_I42_PG10: length 7.1
  TOP w0.14: RN10.3 193.03,55.76 191.76,57.03 191.76,59.17 191.5,59.43 191.5,60.52 U29.K2
UNNAMED_12_ADSPBF52XV3_I42_PG11: length 6.1
  TOP w0.14: RN10.4 192.53,55.76 191.39,56.9 191.39,59.06 191.08,59.37 U29.J1
UNNAMED_12_ADSPBF52XV3_I42_PG12: length 7
  TOP w0.14: RN10.5 192.03,55.75 191.01,56.77 191.01,58.93 190.65,59.28 190.65,60.47 U29.J2
UNNAMED_12_ADSPBF52XV3_I42_PG13: length 6
  TOP w0.14: RN10.6 191.53,55.74 190.63,56.64 190.63,58.8 190.28,59.15 U29.H1
UNNAMED_12_ADSPBF52XV3_I42_PG14: length 6.9
  TOP w0.14: U29.H2 190.28,60.87 189.87,60.45 189.87,59.06 190.25,58.67 190.25,56.52 191.03,55.73 RN10.7
UNNAMED_12_ADSPBF52XV3_I42_PG15: length 5.9
  TOP w0.14: RN10.8 190.53,55.6 189.87,56.26 189.87,58.42 189.48,58.81 U29.G1
UNNAMED_12_ADSPBF52XV3_I42_PH0: length 3.8
  TOP w0.14: RN8.2 182.1,65.68 182.89,64.89 U29.A7
UNNAMED_12_ADSPBF52XV3_I42_PH1: length 4.7
  TOP w0.14: U29.B7 185.1,64.52 182.75,64.52 182.09,65.18 RN8.1
UNNAMED_12_ADSPBF52XV3_I42_PH2: length 3.8
  TOP w0.14: U29.A8 183.1,65.69 182.12,66.67 181.24,66.67 RN8.4
UNNAMED_12_ADSPBF52XV3_I42_PH3: length 4.8
  TOP w0.14: U29.B8 185.06,65.28 183.01,65.28 182.11,66.18 RN8.3
UNNAMED_12_ADSPBF52XV3_I42_PH4: length 3.9
  TOP w0.14: RN8.6 182.26,67.68 183.44,66.49 U29.A9
UNNAMED_12_ADSPBF52XV3_I42_PH5: length 4.9
  TOP w0.14: RN8.5 182.25,67.18 183.36,66.07 185.05,66.07 U29.B9
UNNAMED_12_ADSPBF52XV3_I42_PH6: length 5
  TOP w0.14: U29.B10 185.12,66.93 184.85,66.93 184.83,66.92 184.52,66.92 184.51,66.93 184.44,66.93 184.36,66.84 183.98,66.84 183.89,66.93 183.64,66.93 182.39,68.18 RN8.7
UNNAMED_12_ADSPBF52XV3_I42_PH7: length 4.9
  TOP w0.14: U29.B11 185.08,67.69 184.41,67.69 184.36,67.74 184,67.74 183.93,67.68 183.56,67.68 182.56,68.68 RN8.8
UNNAMED_12_ADSPBF52XV3_I42_PH8: length 4
  TOP w0.14: RN9.1 181.84,70.26 183.2,68.89 U29.A12
UNNAMED_12_ADSPBF52XV3_I42_PH9: length 5
  TOP w0.14: U29.B12 185.05,69.32 183.29,69.32 181.84,70.76 RN9.2
UNNAMED_12_ADSPBF52XV3_I42_PH10: length 4.2
  TOP w0.14: RN9.3 181.85,71.26 183.52,69.6 184.28,69.6 184.37,69.69 U29.A13
UNNAMED_12_ADSPBF52XV3_I42_PH11: length 5.3
  TOP w0.14: U29.B13 185.06,70.1 184.28,70.1 184.15,69.98 183.52,69.98 182.63,70.87 182.63,71.12 181.99,71.76 RN9.4
UNNAMED_12_ADSPBF52XV3_I42_PH12: length 5
  TOP w0.14: RN9.5 182,72.26 183.01,71.25 183.9,71.25 184.28,70.87 185.04,70.87 185.41,70.49 U29.B14
UNNAMED_12_ADSPBF52XV3_I42_PH13: length 4.9
  TOP w0.14: RN9.6 182.26,72.76 183.35,71.67 185.13,71.67 185.48,71.32 U29.B15
UNNAMED_12_ADSPBF52XV3_I42_PH14: length 4.7
  TOP w0.14: RN9.7 182.65,73.26 183.31,72.59 183.95,72.59 184.02,72.52 185.05,72.52 U29.B16
UNNAMED_12_ADSPBF52XV3_I42_PH15: length 4.6
  TOP w0.14: RN9.8 183.8,73.76 184.28,73.28 185.09,73.28 U29.B17
UNNAMED_12_ADSPBF52XV3_I42_PPIC: length 3.2
  TOP w0.14: U29.G2 v1(189.08,60.49)
  BOTTOM w0.14: 189.74,58.17 189.74,58.29 189.1,58.93 189.1,60.47 v1(189.08,60.49)
UNNAMED_12_ADSPBF52XV3_I42_PPIF: length 2.9
  TOP w0.14: U29.F2 v1(188.28,60.49)
  BOTTOM w0.14: v1(188.28,60.49) 188.34,60.43 188.34,58.17
UNNAMED_12_ADSPBF52XV3_I42_SCL: length 7.7
  TOP w0.14: U29.A4 v1(184.28,62.09) ; 179.58,58.17 v1(179.58,58.93)
  BOTTOM w0.14: v1(184.28,62.09) 184.28,61.47 182.25,59.44 180.09,59.44 v1(179.58,58.93)
UNNAMED_12_ADSPBF52XV3_I42_SDA: length 7.3
  TOP w0.14: 180.85,58.17 v1(180.85,58.93) ; U29.B4 v1(185.08,62.09)
  BOTTOM w0.14: v1(180.85,58.93) 182.63,58.93 185.04,61.34 185.04,62.05 v1(185.08,62.09)
UNNAMED_12_DIOLED_I83_N: length 1.6
  TOP w0.14: DS32.C v1(190.25,46.23)
  BOTTOM w0.14: v1(190.25,46.23) Q14.3
UNNAMED_12_DIOLED_I83_P: length 1.4
  TOP w0.14: DS32.A R165.1
UNNAMED_14_ADM6306_I147_MRN: length 13.3
  TOP w0.14: S2.3 S2.4 180.9,92.27 180.47,92.71 C100.2 179.2,92.58 176.66,92.58 176.46,92.39 U24.3
UNNAMED_14_ADM6306_I147_RSTIN: length 3.8
  TOP w0.14: U24.4 176.49,94.62 R129.1 R130.2
UNNAMED_14_ADSPBF52XV3_I94_A_10: length 4.6
  TOP w0.14: RN4.8 202.59,74.07 202.25,73.73 202.25,72.84 201.99,72.57 201.86,72.57 200.58,71.29 U29.Y15
UNNAMED_14_ADSPBF52XV3_I94_A_11: length 4.6
  TOP w0.14: RN3.1 202.28,72.49 200.66,70.87 199.45,70.87 U29.W14
UNNAMED_14_ADSPBF52XV3_I94_A_12: length 3.6
  TOP w0.14: RN3.2 202.16,71.99 200.66,70.48 199.88,70.48 U29.Y14
UNNAMED_14_ADSPBF52XV3_I94_A_13: length 4.5
  TOP w0.14: RN3.3 202.05,71.49 200.66,70.1 199.49,70.1 U29.W13
UNNAMED_14_ADSPBF52XV3_I94_A_14: length 3.5
  TOP w0.14: U29.Y13 200.63,69.69 201.93,70.99 RN3.4
UNNAMED_14_ADSPBF52XV3_I94_A_15: length 4.4
  TOP w0.14: U29.W12 199.45,69.27 200.58,69.27 201.81,70.49 RN3.5
UNNAMED_14_ADSPBF52XV3_I94_A_16: length 3.4
  TOP w0.14: RN3.6 201.69,69.99 200.59,68.89 U29.Y12
UNNAMED_14_ADSPBF52XV3_I94_A_17: length 4.3
  TOP w0.14: RN3.7 201.7,69.49 200.67,68.47 199.45,68.47 U29.W11
UNNAMED_14_ADSPBF52XV3_I94_A_18: length 3.3
  TOP w0.14: RN3.8 201.58,68.99 200.68,68.09 U29.Y11
UNNAMED_14_ADSPBF52XV3_I94_ABE0: length 8.3
  TOP w0.14: U29.V19 198.65,74.87 198.65,79.53 200.15,81.03 200.15,82.03 RN1.13
UNNAMED_14_ADSPBF52XV3_I94_ABE1: length 7.3
  TOP w0.14: RN1.12 199.65,81.16 198.37,79.88 198.37,75.82 198.28,75.72 U29.V20
UNNAMED_14_ADSPBF52XV3_I94_AD_1: length 8.4
  TOP w0.14: RN1.15 201.15,80.88 199.5,79.23 199.5,74.92 U29.W19
UNNAMED_14_ADSPBF52XV3_I94_AD_2: length 8.3
  TOP w0.14: RN1.16 201.65,80.74 200.65,79.75 200.65,79.29 200.66,79.28 200.66,77.47 200.48,77.29 200.48,75.09 U29.Y19
UNNAMED_14_ADSPBF52XV3_I94_AD_3: length 6.5
  TOP w0.14: U29.W18 199.45,74.07 200.05,74.07 200.79,74.8 200.79,76.84 201.52,77.57 RN4.1
UNNAMED_14_ADSPBF52XV3_I94_AD_4: length 5.5
  TOP w0.14: RN4.2 201.66,77.07 201.05,76.47 201.05,74.43 200.31,73.69 U29.Y18
UNNAMED_14_ADSPBF52XV3_I94_AD_5: length 6.2
  TOP w0.14: RN4.3 201.92,76.57 201.32,75.97 201.32,74.32 200.28,73.28 199.47,73.28 U29.W17
UNNAMED_14_ADSPBF52XV3_I94_AD_6: length 5
  TOP w0.14: RN4.4 202.1,76.07 201.59,75.55 201.59,74.21 200.27,72.89 U29.Y17
UNNAMED_14_ADSPBF52XV3_I94_AD_7: length 5.7
  TOP w0.14: U29.W16 199.45,72.47 200.23,72.47 201.85,74.09 201.85,75.04 202.38,75.57 RN4.5
UNNAMED_14_ADSPBF52XV3_I94_AD_8: length 4.7
  TOP w0.14: U29.Y16 200.36,72.09 201.35,73.08 201.35,73.21 201.62,73.48 201.62,73.48 202.12,73.98 202.12,74.74 202.45,75.07 RN4.6
UNNAMED_14_ADSPBF52XV3_I94_AD_9: length 6.4
  TOP w0.14: v1(201.8,73.03) 200.44,71.67 199.43,71.67 199.08,71.32 U29.W15 ; v1(203.45,74.55) 202.83,74.55 RN4.7
  BOTTOM w0.14: v1(201.8,73.03) 201.93,73.03 v1(203.45,74.55)
UNNAMED_14_ADSPBF52XV3_I94_ADDR: length 7.4
  TOP w0.14: RN1.14 200.65,81.01 199.08,79.44 U29.W20
UNNAMED_14_ADSPBF52XV3_I94_AMS0: length 8.7
  TOP w0.14: U29.J19 191.07,74.49 190.7,74.85 190.7,78.56 193.04,80.9 193.04,82 RN2.1
UNNAMED_14_ADSPBF52XV3_I94_AMS1: length 8.6
  TOP w0.14: U29.K19 191.88,74.76 191.5,75.14 191.5,78.73 193.57,80.79 RN2.2
UNNAMED_14_ADSPBF52XV3_I94_AMS2: length 8.2
  TOP w0.14: RN2.5 195.07,80.01 193.9,78.84 193.9,74.9 193.49,74.49 U29.M19
UNNAMED_14_ADSPBF52XV3_I94_AMS3: length 7.5
  TOP w0.14: RN2.4 194.57,80.27 192.68,78.38 U29.L20
UNNAMED_14_ADSPBF52XV3_I94_AOEN: length 3.4
  TOP w0.14: U29.N20 194.28,77.44 v1(194.69,77.85)
  BOTTOM w0.14: v1(194.69,77.85) R261.1
UNNAMED_14_ADSPBF52XV3_I94_ARDY: length 6.5
  TOP w0.14: U29.P19 v1(195.48,74.09)
  BOTTOM w0.14: R260.2 197.87,75.82 196.47,74.42 195.81,74.42 v1(195.48,74.09)
UNNAMED_14_ADSPBF52XV3_I94_AREN: length 4.2
  TOP w0.14: U29.M20 193.48,75.89 v1(193.17,76.2)
  BOTTOM w0.14: v1(193.17,76.2) 192.66,76.2 191.52,77.34 R263.1
UNNAMED_14_ADSPBF52XV3_I94_AWEN: length 5.5
  TOP w0.14: U29.N19 194.28,74.01 v1(194.18,73.91)
  BOTTOM w0.14: v1(194.18,73.91) 193.68,74.42 193.68,77.09 193.04,77.72 R262.1
UNNAMED_14_ADSPBF52XV3_I94_BM_1: length 4.5
  TOP w0.14: v1(202.31,68.2) 202.18,68.33 201.42,68.33 200.78,67.69 199.48,67.69 U29.W10
  BOTTOM w0.14: R275.2 v1(202.31,68.2)
UNNAMED_14_ADSPBF52XV3_I94_BM_2: length 4.5
  TOP w0.14: U29.Y9 v1(199.48,66.89)
  BOTTOM w0.14: R277.1 200.2,66.17 v1(199.48,66.89)
UNNAMED_14_ADSPBF52XV3_I94_BM_3: length 5.7
  TOP w0.14: U29.W9 v1(198.68,66.89)
  BOTTOM w0.14: R278.1 200.42,65.15 v1(198.68,66.89)
UNNAMED_14_ADSPBF52XV3_I94_BMOD: length 3.7
  TOP w0.14: U29.Y10 199.9,67.31 201.04,67.31 v1(201.55,67.82)
  BOTTOM w0.14: v1(201.55,67.82) 202.18,67.18 R276.2
UNNAMED_14_ADSPBF52XV3_I94_CLKI: length 15.2
  TOP w0.14: v1(183.75,68.13) 183.77,68.13 183.77,68.09 U29.A11 ; C106.1 v1(181.48,78.11) 181.48,79.02 Y2.1
  BOTTOM w0.14: v1(183.75,68.13) 181.48,70.39 v1(181.48,78.11)
UNNAMED_14_ADSPBF52XV3_I94_CLKO: length 7.6
  TOP w0.14: U29.K20 191.88,78.21 194.07,80.4 RN2.3
UNNAMED_14_ADSPBF52XV3_I94_D_10: length 3.1
  TOP w0.14: RN5.3 201.69,61.33 201.33,61.69 U29.Y3
UNNAMED_14_ADSPBF52XV3_I94_D_11: length 4.1
  TOP w0.14: U29.W3 199.45,61.32 200.81,61.32 201.3,60.83 RN5.4
UNNAMED_14_ADSPBF52XV3_I94_D_12: length 3.2
  TOP w0.14: U29.Y2 200.73,60.89 201.29,60.33 RN5.5
UNNAMED_14_ADSPBF52XV3_I94_D_13: length 4.2
  TOP w0.14: U29.W2 199.5,60.47 200.52,60.47 201.16,59.83 RN5.6
UNNAMED_14_ADSPBF52XV3_I94_D_14: length 4.2
  TOP w0.14: RN5.7 201.06,59.33 200.91,59.18 199.99,59.18 U29.W1
UNNAMED_14_ADSPBF52XV3_I94_D_15: length 5.1
  TOP w0.14: U29.V1 199.54,58.83 RN5.8
UNNAMED_14_ADSPBF52XV3_I94_DA_1: length 4.6
  TOP w0.14: U29.W8 199.49,65.28 200.41,65.28 202.04,66.91 RN12.2
UNNAMED_14_ADSPBF52XV3_I94_DA_2: length 3.6
  TOP w0.14: U29.Y7 199.88,64.9 200.41,64.9 201.92,66.41 RN12.3
UNNAMED_14_ADSPBF52XV3_I94_DA_3: length 4.5
  TOP w0.14: RN12.4 201.8,65.91 200.41,64.52 199.45,64.52 U29.W7
UNNAMED_14_ADSPBF52XV3_I94_DA_4: length 3.5
  TOP w0.14: U29.Y6 200.49,64.09 201.81,65.41 RN12.5
UNNAMED_14_ADSPBF52XV3_I94_DA_5: length 4.4
  TOP w0.14: U29.W6 199.5,63.67 200.44,63.67 201.69,64.91 RN12.6
UNNAMED_14_ADSPBF52XV3_I94_DA_6: length 3.4
  TOP w0.14: RN12.7 201.7,64.41 200.58,63.29 U29.Y5
UNNAMED_14_ADSPBF52XV3_I94_DA_7: length 4.3
  TOP w0.14: U29.W5 199.5,62.87 200.03,62.87 200.53,62.87 201.58,63.91 RN12.8
UNNAMED_14_ADSPBF52XV3_I94_DA_8: length 3
  TOP w0.14: U29.Y4 199.89,62.48 201.8,62.48 201.96,62.33 RN5.1
UNNAMED_14_ADSPBF52XV3_I94_DA_9: length 4
  TOP w0.14: RN5.2 201.82,61.83 201.55,62.1 199.47,62.1 U29.W4
UNNAMED_14_ADSPBF52XV3_I94_DATA: length 3.6
  TOP w0.14: U29.Y8 200.31,65.69 202.03,67.41 RN12.1
UNNAMED_14_ADSPBF52XV3_I94_NMIN: length 4.5
  TOP w0.14: R140.2 v1(185.93,77.6) ; U29.B19 v1(185.08,74.89)
  BOTTOM w0.14: v1(185.08,74.89) 185.93,75.74 v1(185.93,77.6)
UNNAMED_14_ADSPBF52XV3_I94_SA10: length 8.2
  TOP w0.14: RN1.11 199.15,81.04 198.11,80 198.11,76.07 197.87,75.83 197.87,74.88 U29.U19
UNNAMED_14_ADSPBF52XV3_I94_SCAS: length 7.2
  TOP w0.14: U29.U20 197.48,75.94 197.84,76.3 197.84,80.24 198.65,81.05 RN1.10
UNNAMED_14_ADSPBF52XV3_I94_SCKE: length 6.9
  TOP w0.14: RN2.6 195.57,79.24 195.2,78.87 195.2,77.47 195.08,77.35 U29.P20
UNNAMED_14_ADSPBF52XV3_I94_SMSN: length 8
  TOP w0.14: RN2.7 196.07,80.75 195.96,80.64 195.96,77.47 195.45,76.96 195.45,74.93 195.88,74.51 U29.R19
UNNAMED_14_ADSPBF52XV3_I94_SRAS: length 8.1
  TOP w0.14: U29.T19 197.05,74.87 197.05,76.02 197.49,76.45 197.49,80.39 198.15,81.05 RN1.9
UNNAMED_14_ADSPBF52XV3_I94_SWEN: length 7.4
  TOP w0.14: U29.T20 196.73,75.34 196.73,76.08 197.22,76.57 197.22,77.61 196.34,78.49 196.34,79.24 196.34,79.25 196.34,79.68 196.34,79.68 196.34,80.44 196.57,80.66 RN2.8
UNNAMED_14_ADSPBF52XV3_I94_VRSE: length 4.8
  TOP w0.14: U29.F19 v1(188.28,74.89) ; R141.2 v1(189.74,77.6)
  BOTTOM w0.14: v1(188.28,74.89) 188.3,74.89 188.85,75.44 188.85,76.71 v1(189.74,77.6)
UNNAMED_14_ADSPBF52XV3_I94_XTAL: length 17.4
  TOP w0.14: U29.A10 v1(184.17,67.29) ; v1(185.29,81.66) 185.38,81.75 R137.1
  L7_SIGNAL w0.095: v1(185.29,81.66) 183.01,79.38 183.01,70.36 184.17,69.2 v1(184.17,67.29)
UNNAMED_14_CAP_I115_N1: length 5
  TOP w0.14: 184.02,84.58 183.52,84.07 183.13,84.07 182.72,83.66 182.69,83.66 ; 182.69,83.66 Y2.2 ; 182.69,83.66 R137.2
UNNAMED_14_ICMX25U3235F_I151_WP: length 2.8
  BOTTOM w0.14: U41.3 186.06,44.32 186.44,44.7 R299.2
UNNAMED_15_ADP5054_I113_CFG12: length 2.8
  TOP w0.14: R147.2 v1(167.64,67.56) 167.39,67.31 U27.18
  BOTTOM w0.14: v1(167.64,67.56) R147.2
UNNAMED_15_ADP5054_I113_RT: length 1.7
  TOP w0.14: U27.42 v1(158.75,67.81)
  BOTTOM w0.14: R46.2 159.51,67.81 v1(158.75,67.81)
UNNAMED_15_ADP5054_I113_SW31: length 11
  TOP w0.305: U27.5 162.44,63.38 v1(162.05,62.99) 161.95,63.1 U27.4
  TOP w0.508: v1(162.05,62.99) 162.05,62.61 160.78,61.34 160.78,57.32 L11.1
  BOTTOM w0.203: v1(162.05,62.99) 162.05,63.75 C282.2
UNNAMED_15_ADP5054_I113_VDD: length 2.7
  TOP w0.14: U27.43 158.54,67.31 158.54,67.31 157.57,67.31 C114.2
UNNAMED_15_CAP_I13_N2: length 12.4
  TOP w0.305: U27.34 161.44,71.85 ; U27.33 161.95,71.86 ; U27.35 160.95,71.85
  TOP w0.381: 160.91,72.19 C110.2 ; C110.2 160.91,73.36 ; C110.2 160.29,72.77 ; 159.6,82.3 L9.1 157.23,81.53
  TOP w0.635: 160.53,81.03 160.56,81.06 Q7.8 Q7.7 162.49,80.19 162.04,79.74 160.41,79.74 160.4,79.76
UNNAMED_15_CAP_I14_N2: length 12.7
  TOP w0.254: 165.44,71.72 U27.26 ; 165.95,71.71 U27.25 ; 164.95,71.73 U27.27
  TOP w0.381: C111.2 166.61,72.77 ; C111.2 165.99,72.19 ; C111.2 165.99,73.36 ; 167.04,82.3 L10.1 169.42,81.53
  TOP w0.635: 166.37,81.15 166.28,81.06 Q7.5 Q7.6 164.16,80.19 164.6,79.74 166.61,79.74 166.62,79.76
UNNAMED_15_CAP_I42_N2: length 10.9
  TOP w0.305: U27.9 164.44,63.1 v1(164.34,62.99) 163.95,63.38 U27.8
  TOP w0.635: L12.1 165.44,61.63 164.47,62.61 164.47,62.87 v1(164.34,62.99)
  BOTTOM w0.203: C281.2 164.34,63.88 v1(164.34,62.99)
UNNAMED_15_CAP_I71_N2: length 1.4
  TOP w0.14: R146.1 C113.2
UNNAMED_15_CAP_I84_N2: length 1.5
  TOP w0.14: R150.1 C117.2
UNNAMED_15_CAP_I87_N2: length 1.4
  TOP w0.14: C116.2 R149.1
UNNAMED_15_RES_I100_N2: length 3.2
  BOTTOM w0.14: R265.1 156.84,72.09 R264.2 155.27,72.14 R266.2
UNNAMED_15_RES_I105_N2: length 3.6
  BOTTOM w0.14: 156.34,56.13 154.56,56.13 154.56,57.91
UNNAMED_15_RES_I106_N2: length 3.4
  BOTTOM w0.14: 172.21,56.13 170.56,56.13 170.56,57.91
UNNAMED_16_ADCMP671_I40_INH: length 4.1
  BOTTOM w0.381: U44.3 24.66,17.14 R336.1 R337.2
UNNAMED_16_ADCMP671_I40_INL: length 4.2
  BOTTOM w0.381: U44.4 24.41,19.18 R325.2 R324.1
UNNAMED_16_ADM1170_I73_GATE: length 4.5
  TOP w0.14: R125.1 18.03,99.31 ; 18.03,99.31 17.4,99.31 17.14,99.57 17.14,100.14 Q5.4 ; 18.03,99.31 18.29,99.31 19.22,100.24 U17.5
UNNAMED_16_ADM1170_I73_SENSE: length 2.2
  TOP w0.14: U17.7 20.52,99.89 20.32,99.7 19.94,99.7 19.87,99.77 U17.6
UNNAMED_16_ADM1170_I73_SS: length 2
  TOP w0.14: C73.1 19.87,104.72 U17.3
UNNAMED_16_ADM1170_I73_TIMER: length 2
  TOP w0.14: U17.1 21.17,105.12 21.21,105.16
UNNAMED_16_CAP_I78_N1: length 1.7
  TOP w0.14: C90.1 18.03,97.03
UNNAMED_16_DIOLED_I37_N: length 3
  TOP w0.381: DS39.C v1(34.16,18.67)
  BOTTOM w0.381: v1(34.16,18.67) 32.92,18.67 Q15.3
UNNAMED_16_DIOLED_I37_P: length 3.1
  TOP w0.381: DS39.A 38.1,18.67 v1(38.61,19.18)
  BOTTOM w0.381: v1(38.61,19.18) R334.1
UNNAMED_16_DIOLED_I63_N: length 3.8
  TOP w0.381: v1(36.83,20.45) 35.19,22.09 DS40.C
  BOTTOM w0.381: Q16.3 v1(36.83,20.45)
UNNAMED_16_DIOLED_I63_P: length 2.3
  TOP w0.381: v1(37.85,22.99) 37.2,22.34 DS40.A
  BOTTOM w0.381: v1(37.85,22.99) 37.08,22.99 R321.1
UNNAMED_17_ADM1293_I1_ADR1: length 3.3
  TOP w0.14: R110.2 162.05,108.71 160.53,108.71 160.09,109.15 U14.3
UNNAMED_17_ADM1293_I1_VCAP: length 2.2
  TOP w0.14: v1(159.38,109.09) 159.44,109.15 U14.2
  BOTTOM w0.14: C210.1 159.77,109.47 v1(159.38,109.09)
UNNAMED_17_ADM1293_I33_VCAP: length 2.2
  TOP w0.14: v1(167.39,109.09) 167.06,109.42 U15.2
  BOTTOM w0.14: v1(167.39,109.09) C208.1
UNNAMED_17_ADM1293_I59_ADR1: length 2.2
  TOP w0.14: U7.3 96.85,142.44 R56.2
UNNAMED_17_ADM1293_I59_ADR2: length 2.1
  TOP w0.14: U7.4 97.5,142.41 R57.2
UNNAMED_17_ADM1293_I59_VCAP: length 1.9
  TOP w0.381: U7.2 96.19,143.31 v1(96.14,143.26)
  BOTTOM w0.203: C153.1 96.52,143.64 v1(96.14,143.26)
UNNAMED_17_ADM1293_I68_ADR2: length 3.7
  TOP w0.14: v1(142.24,142.11) 141.95,142.41 U8.4
  BOTTOM w0.14: R221.2 142.68,142.81 142.68,142.56 v1(142.24,142.11)
UNNAMED_17_ADM1293_I68_VCAP: length 2.2
  TOP w0.381: v1(140.97,143.13) 140.64,143.45 U8.2
  BOTTOM w0.203: C151.1 v1(140.97,143.13)
UNNAMED_17_ADM1293_I77_ADR2: length 2.1
  TOP w0.381: U4.4 28.79,142.41 R53.2
UNNAMED_17_ADM1293_I86_VCAP: length 2.4
  TOP w0.381: v1(16.51,143) 16.18,143.33 U3.2
  BOTTOM w0.381: v1(16.51,143) C161.1
UNNAMED_17_ADM1293_I97_ADR1: length 2.4
  TOP w0.14: R55.2 65.98,143.06 U5.3
UNNAMED_17_ADM1293_I97_VCAP: length 2.2
  TOP w0.381: v1(65.28,143.13) 65.33,143.18 U5.2
  BOTTOM w0.203: v1(65.28,143.13) 65.66,143.51 C157.1
UNNAMED_17_ADM1293_I106_VCAP: length 2.2
  TOP w0.381: U6.2 87.18,143.45 v1(87.5,143.13)
  BOTTOM w0.203: C155.1 v1(87.5,143.13)
UNNAMED_18_CN204P2GND_I14_N69: length 2.8
  TOP w0.14: P6.201 v1(96.16,101.74)
  BOTTOM w0.14: R246.2 95.38,102.49 96.12,101.74 v1(96.16,101.74)
UNNAMED_18_CN204P2GND_I32_N67: length 2.6
  TOP w0.14: P5.197 115.4,25.69 v2(115.7,25.4)
  BOTTOM w0.14: R317.2 v2(115.7,25.4)
UNNAMED_18_CN204P2GND_I32_N69: length 2.6
  TOP w0.14: P5.201 v1(112.54,24.49)
  BOTTOM w0.14: v1(112.54,24.49) 113.52,24.49 R318.2
UNNAMED_19_AD9577_I478_LDO: length 5.8
  TOP w0.14: 137.01,116.99 137.03,116.97 137.03,116.71 ; 137.01,116.99 U12.12 ; 137.01,116.99 136.91,117.09 136.91,117.22 136.73,117.4 136.52,117.4 136.42,117.5 U12.13 ; U12.11 136.82,116.5 137.03,116.71 ; 137.03,116.71 137.89,116.71 138.27,117.09 C64.2
UNNAMED_19_AD9577_I478_MARGIN: length 4.6
  TOP w0.14: U12.20 136.49,120.99 136.78,121.28 136.78,122.3 137.8,123.32 R76.2
UNNAMED_19_AD9577_I478_MAXBW: length 3.2
  TOP w0.14: U12.40 129.7,116.5 128.78,115.57 127.89,115.57 R91.2
UNNAMED_19_AD9577_I478_OUT0N: length 7.1
  TOP w0.102: C59.1 R72.2 125.5,120.12 128.26,120.12 128.51,119.86 129.3,119.86 129.44,119.99 U12.33
UNNAMED_19_AD9577_I478_OUT0P: length 7.1
  TOP w0.102: C63.1 124.71,119.38 R78.2 125.48,119.89 128.16,119.89 128.42,119.63 129.29,119.63 129.42,119.5 U12.34
UNNAMED_19_AD9577_I478_OUT2N: length 5.7
  TOP w0.102: U12.17 136.49,119.5 136.65,119.66 139.17,119.66 v1(139.45,119.38)
  BOTTOM w0.102: C191.1 R238.2 139.83,119.38 v1(139.45,119.38)
UNNAMED_19_AD9577_I478_OUT2P: length 5.6
  TOP w0.102: U12.18 136.55,119.99 136.65,119.89 139.19,119.89 v1(139.45,120.14)
  BOTTOM w0.102: v1(139.45,120.14) 139.83,120.14 R226.2 C190.1
UNNAMED_19_AD9577_I478_OUT3N: length 6.6
  TOP w0.14: U12.22 134.72,123.42 R75.2 136.4,125.09 136.4,126.37 W2.1
UNNAMED_19_AD9577_I478_OUT3P: length 6.6
  TOP w0.14: W1.1 134.24,126.49 134.24,124.97 R74.2 134.37,123.32 134.37,122.81 134.22,122.66 U12.23
UNNAMED_19_AD9577_I478_REFSEL: length 4.6
  TOP w0.14: R93.2 137.29,114.3 135.73,114.3 135.72,114.29 135.26,114.29 134.72,114.84 U12.9
UNNAMED_19_AD9577_I478_SSCG: length 7.2
  TOP w0.14: U12.26 132.72,122.55 132.47,122.8 132.47,123.31 132.33,123.44 v1(132.31,123.44) ; R73.2 v1(128.14,122.43)
  L22_SIGNAL w0.095: v1(132.31,123.44) 130.56,123.44 129.54,122.43 v1(128.14,122.43)
UNNAMED_19_AD9577_I478_VSM: length 2.4
  TOP w0.305: U12.25 v1(133.22,122.55)
  BOTTOM w0.381: v1(133.22,122.55) 133.1,122.43 C175.1
  BOTTOM w0.508: R229.2 133.1,122.67 v1(133.22,122.55)
UNNAMED_19_AD9577_I478_VSOB0A: length 2.5
  TOP w0.203: U12.32 v1(129.06,120.5)
  BOTTOM w0.203: C199.1 129.7,120.5 v1(129.06,120.5) 129.03,120.52 R239.2
UNNAMED_19_AD9577_I478_VSOB1A: length 2.4
  TOP w0.254: U12.30 130.72,122.52 v1(130.68,122.56)
  BOTTOM w0.381: v1(130.68,122.56) 130.94,122.3 C176.1
  BOTTOM w0.508: R230.2 v1(130.68,122.56)
UNNAMED_19_AD9577_I478_VSOB2B: length 2.6
  TOP w0.203: U12.19 v1(136.88,120.5)
  BOTTOM w0.203: R227.2 136.91,120.52 v1(136.88,120.5) 136.24,120.5 C193.1
UNNAMED_19_AD9577_I478_VSOB3B: length 2.3
  TOP w0.254: U12.21 135.22,122.52 v1(135.25,122.56)
  BOTTOM w0.381: C174.1 v1(135.25,122.56)
  BOTTOM w0.508: R228.2 v1(135.25,122.56)
UNNAMED_19_ADCLK944_I308_Q0: length 6.5
  TOP w0.102: R89.1 119.51,114.05 R90.2 118.85,114.71 118.85,116.49 118.97,116.62 118.97,117.96 119.12,118.11 U11.15
UNNAMED_19_ADCLK944_I308_Q0N: length 6.5
  TOP w0.102: U11.14 118.62,118.11 118.75,117.98 118.75,116.71 118.62,116.59 118.62,114.81 R87.2 R88.1
UNNAMED_19_ADCLK944_I308_Q1: length 10.5
  TOP w0.152: U11.12 116.98,119.39 116.84,119.53 115.61,119.53 115.55,119.47 115.54,119.47 112.24,116.18 112.24,114.71 R86.2 112.9,114.05 R85.1
UNNAMED_19_ADCLK944_I308_Q1N: length 10.9
  TOP w0.152: R84.1 R83.2 111.96,114.76 111.96,116.3 115.48,119.81 116.89,119.81 116.97,119.89 U11.11
UNNAMED_19_ADCLK944_I308_Q2: length 10.5
  TOP w0.102: U11.10 117.1,120.39 116.94,120.55 113.95,120.55 113.34,121.16 112.52,121.16 R77.2 111.25,121.16 110.62,121.16 R70.2 109.22,120.65 108.84,120.27 W10.1
UNNAMED_19_ADCLK944_I308_Q2N: length 10.5
  TOP w0.102: U11.9 117.08,120.89 116.97,120.78 114.05,120.78 113.41,121.41 112.52,121.41 R71.2 111.25,121.41 110.62,121.41 110.11,121.92 109.35,121.92 108.97,122.3 W8.1
UNNAMED_19_ADCLK944_I308_VREF: length 2.6
  TOP w0.14: U11.2 120.91,119.89 v1(121.16,120.14) 120.91,120.39 U11.3
  BOTTOM w0.14: v1(121.16,120.14) 121.03,120.02 C202.2
UNNAMED_19_ADCLK944_I355_Q0: length 12.5
  TOP w0.102: R97.2 143.19,116.14 143.19,116.9 143.89,117.6 143.89,121.44 145.04,122.58 146.3,122.58 146.56,122.33 146.56,121.79 146.44,121.67 U13.15
  TOP w0.14: R96.1 143.76,114.05 R97.2
UNNAMED_19_ADCLK944_I355_Q0N: length 13.2
  TOP w0.102: R94.2 142.96,116.17 142.96,117.06 143.66,117.75 143.66,121.53 144.94,122.81 146.4,122.81 146.79,122.42 146.79,121.82 146.93,121.67 U13.14
  TOP w0.14: R94.2 R95.1
UNNAMED_19_ADCLK944_I355_Q1: length 8.3
  TOP w0.152: 153.54,116.59 153.54,118.11 R82.2 153.29,118.24 152.79,118.74 152.79,119.39 151.75,120.42 148.69,120.42 148.6,120.51 U13.12
UNNAMED_19_ADCLK944_I355_Q1N: length 7.6
  TOP w0.152: U13.11 148.59,120.01 148.72,120.14 151.64,120.14 152.51,119.27 152.5,119.26 152.5,118.76 152.51,118.75 152.51,118.73 R79.2 152.02,116.59
UNNAMED_19_ADCLK944_I355_Q2: length 11.6
  TOP w0.14: U13.10 150.24,119.51 v1(150.5,119.25)
  BOTTOM w0.14: W11.1 157.99,120.14 157.73,119.89 R236.2 151.64,119.89 151.38,120.14 v1(150.5,119.25)
UNNAMED_19_ADCLK944_I355_Q2N: length 11.4
  TOP w0.14: U13.9 148.83,119.01 v1(149.1,118.75)
  BOTTOM w0.14: v1(149.1,118.75) 149.35,118.49 R237.2 153.16,118.49 153.29,118.62 157.73,118.62 158.12,118.24 W9.1
UNNAMED_19_ADCLK944_I355_VREF: length 2
  TOP w0.14: U13.2 144.9,120.01 v1(144.65,119.76) 144.9,119.51 U13.3
  BOTTOM w0.14: 145.41,119.76 v1(144.65,119.76)
UNNAMED_19_CAP_I319_N1: length 1.5
  TOP w0.102: R68.2 125.09,129.16
UNNAMED_19_CAP_I321_N1: length 1.5
  TOP w0.102: R67.2 125.09,130.56
UNNAMED_19_CAP_I331_N1: length 1.4
  TOP w0.102: 119.51,111.25 C78.1
UNNAMED_19_CAP_I334_N1: length 1.4
  TOP w0.102: 117.98,111.25 C77.1
UNNAMED_19_CAP_I342_N1: length 1.4
  TOP w0.152: C76.1 112.9,111.25
UNNAMED_19_CAP_I347_N1: length 1.4
  TOP w0.152: C75.1 111.38,111.25
UNNAMED_19_CAP_I362_N1: length 1.4
  TOP w0.14: R96.2 C70.1
UNNAMED_19_CAP_I366_N1: length 1.4
  TOP w0.14: R95.2 C69.1
UNNAMED_19_CAP_I375_N1: length 1.4
  TOP w0.152: C72.1 R81.2
UNNAMED_19_CAP_I380_N1: length 1.4
  TOP w0.152: C71.1 R80.2
UNNAMED_20_ADP5054_I24_CFG12: length 2.8
  TOP w0.254: R5.2 v1(123.7,164.21) 123.95,163.96 U2.18
  BOTTOM w0.254: v1(123.7,164.21) R5.2
UNNAMED_20_ADP5054_I24_CFG34: length 3.5
  TOP w0.203: R7.1 R8.2 127,164.08
  TOP w0.254: 127,164.08 126.45,163.53 U2.13
UNNAMED_20_ADP5054_I24_RT: length 1.7
  TOP w0.254: U2.42 v1(123.45,155.33)
  BOTTOM w0.203: R216.2 123.44,155.33 v1(123.45,155.33)
UNNAMED_20_ADP5054_I24_SW11: length 13.3
  TOP w0.305: U2.34 119.41,158.02 ; U2.35 119.42,157.52 ; U2.33 119.4,158.52
  TOP w0.381: 110.24,156.17 L6.1 111,153.8 ; C24.2 119.08,157.48 ; C24.2 118.49,156.86 ; C24.2 117.91,157.48
  TOP w0.635: 111.89,156.46 111.9,156.48 111.9,158.61 111.45,159.06 Q2.7 Q2.8 110.2,157.19 110.11,157.1
UNNAMED_20_ADP5054_I24_SW21: length 13
  TOP w0.254: 119.55,162.52 U2.25 ; 119.53,161.52 U2.27 ; 119.54,162.02 U2.26
  TOP w0.381: 110.24,163.87 L5.1 111,166.24 ; 117.91,162.56 C18.2 ; C18.2 118.49,163.18 ; C18.2 119.08,162.56
  TOP w0.635: 110.24,162.94 110.2,162.91 Q2.5 Q2.6 111.32,160.73 111.77,161.18 111.77,163.31 111.76,163.32
UNNAMED_20_ADP5054_I24_SW31: length 10.9
  TOP w0.305: U2.4 128.16,158.52 v1(128.27,158.62) 127.88,159.02 U2.5
  TOP w0.508: v1(128.27,158.62) 128.65,158.62 129.92,157.35 133.95,157.35 L8.1
  BOTTOM w0.203: C146.2 128.02,158.37 v1(128.27,158.62)
UNNAMED_20_ADP5054_I24_SW41: length 10.9
  TOP w0.305: U2.9 128.16,161.02 v1(128.27,160.91) 127.88,160.52 U2.8
  TOP w0.635: L7.1 129.63,162.01 128.65,161.04 128.4,161.04 v1(128.27,160.91)
  BOTTOM w0.203: v1(128.27,160.91) 127.76,161.42 C144.2
UNNAMED_20_ADP5054_I24_VDD: length 2.7
  TOP w0.254: U2.43 123.95,155.54 123.96,155.54 123.96,155.11 123.95,155.11 123.95,154.14 C45.2
UNNAMED_20_CAP_I5_N2: length 1.5
  TOP w0.254: R26.1 C47.2
UNNAMED_20_CAP_I9_N2: length 1.4
  TOP w0.254: R25.1 C50.2
UNNAMED_20_RES_I31_N2: length 3.6
  TOP w0.14: R47.1 R49.2 R48.2
UNNAMED_20_RES_I78_N2: length 3.3
  TOP w0.14: R41.2 R22.2 R23.1
UNNAMED_21_ADP5054_I24_RT: length 1.7
  TOP w0.14: U1.42 v1(52.33,155.33)
  BOTTOM w0.14: R217.2 52.33,156.08 v1(52.33,155.33)
UNNAMED_21_ADP5054_I24_SW11: length 19.6
  TOP w0.305: U1.35 48.3,157.52 ; U1.34 48.29,158.02 ; U1.33 48.28,158.52
  TOP w0.381: 39.08,157.36 Q1.8 ; C21.2 47.96,157.48 ; C21.2 46.79,157.48 ; C21.2 47.37,156.86 ; L2.1 40.63,156.19 ; L2.1 40.63,150.14 ; L2.1 41.52,153.16
  TOP w0.508: Q1.7 Q1.8 ; Q1.7 37.65,159.06 37.29,158.7 37.29,157.28 37.34,157.23 ; Q1.7 40.33,159.06 40.69,158.7 40.69,157.15 40.64,157.1
UNNAMED_21_ADP5054_I24_SW21: length 25.1
  TOP w0.254: 48.41,161.52 U1.27 ; 48.42,162.02 U1.26 ; 48.43,162.52 U1.25
  TOP w0.381: L1.1 40.63,169.65 ; L1.1 40.63,163.6 ; L1.1 41.52,166.62 ; 46.79,162.56 C12.2 ; C12.2 47.37,163.18 ; C12.2 47.96,162.56 ; Q1.5 39.08,162.43
  TOP w0.508: 40.89,163.32 40.77,163.19 ; 40.77,163.19 40.82,163.15 40.82,161.09 40.46,160.73 Q1.6 ; 40.77,163.19 40.77,162.05 40.46,161.74 Q1.5 ; Q1.5 37.9,161.74 37.72,161.93 37.72,162.81 37.85,162.69 37.85,161.04 38.16,160.73 Q1.6 ; Q1.5 Q1.6
UNNAMED_21_ADP5054_I24_SW31: length 10.9
  TOP w0.305: U1.4 57.04,158.52 v1(57.15,158.62) 56.76,159.02 U1.5
  TOP w0.508: L4.1 62.83,157.35 58.8,157.35 57.53,158.62 v1(57.15,158.62)
  BOTTOM w0.203: C147.2 56.39,158.62 v1(57.15,158.62)
UNNAMED_21_ADP5054_I24_SW41: length 10.8
  TOP w0.305: U1.8 56.76,160.52 v1(57.15,160.91) 57.04,161.02 U1.9
  TOP w0.635: L3.1 58.51,162.01 57.53,161.04 57.28,161.04 v1(57.15,160.91)
  BOTTOM w0.203: 56.13,161.29 56.52,160.91 v1(57.15,160.91)
UNNAMED_21_ADP5054_I24_VDD: length 2.7
  TOP w0.254: U1.43 52.83,155.54 52.84,155.54 52.84,155.11 52.83,155.11 52.83,154.14 C36.2
UNNAMED_21_CAP_I3_N2: length 1.9
  TOP w0.14: R4.1 C3.2
UNNAMED_21_CAP_I5_N2: length 1.5
  TOP w0.254: R21.1 C38.2
UNNAMED_21_CAP_I9_N2: length 1.4
  TOP w0.254: R20.1 C49.2
UNNAMED_21_CAP_I83_N2: length 1.9
  TOP w0.14: R2.1 C2.2
UNNAMED_21_RES_I100_N1: length 3.4
  BOTTOM w0.14: 41.15,168.91 R210.2 R208.1
UNNAMED_21_RES_I103_N2: length 3.7
  TOP w0.14: R32.1 R31.2 R30.2
UNNAMED_21_RES_I104_N2: length 3.8
  TOP w0.14: R54.2 R36.2 R35.1
UNNAMED_21_RES_I105_N2: length 4.1
  TOP w0.14: R38.1 62.61,169.42 63.12,169.93 64.01,169.93 ; 64.01,169.93 R39.2 ; 64.01,169.93 R40.2
UNNAMED_22_ADM1178_I115_GATE: length 6.4
  TOP w0.305: U10.9 18.55,125.86
  TOP w0.381: C55.2 R211.1 15.59,125.6 18.28,125.6 18.55,125.86
UNNAMED_22_ADM1178_I115_SENSE: length 18.1
  TOP w0.203: 17.59,119.19 17.27,118.87 15.37,118.87 ; 13.38,119.09 13.59,118.87 14.1,118.87 ; 14.1,118.87 14.73,118.87 ; 14.1,118.87 14.03,118.94 ; 15.37,118.87 14.73,118.87 ; 15.37,118.87 15.33,118.91 ; 14.73,118.87 14.68,118.93
  TOP w0.381: 15.88,119.76 15.85,119.74 Q4.8 ; 16.89,120.27 17.78,120.27 18.16,119.89 R273.2 ; Q4.7 Q4.8 ; Q4.7 Q4.6 ; Q4.7 14.68,118.67 ; Q4.8 15.33,118.66 ; 17.65,119.25 R273.2 ; 17.65,119.25 17.59,119.19 ; 17.65,119.25 17.02,119.25 ; R273.2 17.02,119.76 ; R273.2 18.55,120.15 U10.2 ; Q4.6 Q4.5 13.38,118.83 ; Q4.6 14.03,118.93
UNNAMED_22_ADM1178_I115_TIMER: length 2.1
  TOP w0.203: C62.2 20.19,120.65 20.19,121.79 20.05,121.94 U10.5
UNNAMED_22_ADM1276_I200_ENABLE: length 12.9
  TOP w0.14: C48.2 201.08,151.54 R29.1 ; R29.1 200.03,151.51 v1(199.14,150.62) 195.71,150.62 195.33,151 U9.8 ; R29.1 R51.2
  BOTTOM w0.14: v1(199.14,150.62) R342.2
UNNAMED_22_ADM1276_I200_FLB: length 7.4
  TOP w0.14: U9.13 R18.2 191.2,157.23 R17.1
UNNAMED_22_ADM1276_I200_GATE: length 3.7
  TOP w0.14: R231.1 187.71,153.42 188.82,152.3 U9.16
UNNAMED_22_ADM1276_I200_ISET: length 7.5
  TOP w0.14: U9.3 192.28,147.45 193.04,146.69 194.53,146.69 R257.1 R258.2
UNNAMED_22_ADM1276_I200_OV: length 8.8
  TOP w0.14: U9.1 190.98,148.2 v1(189.74,146.96) R60.2 188.53,144.78 R59.1
  BOTTOM w0.14: C149.2 190.26,147.49 v1(189.74,146.96)
UNNAMED_22_ADM1276_I200_SENSE: length 5.7
  TOP w0.14: R245.1 186.06,149.99 187.07,151 U9.18
UNNAMED_22_ADM1276_I200_SENSE_1: length 5.5
  TOP w0.14: U9.17 184.99,151.65 R27.1
UNNAMED_22_ADM1276_I200_SS: length 7.7
  TOP w0.14: U9.4 192.93,147.56 193.42,147.07 196.22,147.07 196.72,146.56 196.72,145.45 C54.2
UNNAMED_22_ADM1276_I200_TIMER: length 5.5
  TOP w0.14: C52.2 197.65,146.52 196.72,147.45 193.93,147.45 193.58,147.8 U9.5
UNNAMED_22_ADM1276_I200_UV: length 11.4
  TOP w0.14: U9.20 189.2,149.7 v1(188.91,149.42) 186.82,147.32 186.82,145.86 R58.1
  BOTTOM w0.14: C150.2 188.91,150.98 v1(188.91,149.42) R538.2
UNNAMED_22_ADM1276_I200_VCAP: length 4.9
  TOP w0.14: U9.2 191.63,146.15 C53.2 193.75,145.76 R257.2
UNNAMED_22_ADM1276_I200_VCC: length 7.7
  TOP w0.305: 188.98,150.35 U9.19 ; R244.1 C51.2 185.17,148.17
  TOP w0.508: 188.98,150.35 187.6,150.35 186.14,148.89 185.88,148.89 185.17,148.17
UNNAMED_22_ADM1276_I200_VOUT: length 3.6
  TOP w0.305: 191.63,154.32 U9.14
  TOP w0.508: R206.1 190.37,156.12 190.37,155.57 191.63,154.32
UNNAMED_22_CAP_I213_N1: length 6.1
  TOP w0.305: R231.2 v1(183.77,154.43)
  BOTTOM w0.305: R518.1 179.2,155.23 C148.1 182.66,154.43 v1(183.77,154.43)
UNNAMED_22_CN6P_I262_N1: length 21.6
  L11_POWER w0.381: 200.48,120.27 P7.1 ; P7.1 201.8,118.95 ; P7.1 203.12,120.27 ; P7.1 201.8,121.59 ; 196.61,139.06 S1.4 ; S1.4 197.99,137.68 ; S1.4 199.38,139.06 ; S1.4 197.99,140.45 ; 194.97,120.27 P7.4 ; P7.4 197.61,120.27 ; P7.4 196.29,118.95 ; P7.4 196.29,121.59 ; 200.42,139.06 S1.1 ; S1.1 201.8,137.68 ; S1.1 203.19,139.06 ; S1.1 201.8,140.45
UNNAMED_22_DIOLED_I216_N: length 2.2
  TOP w0.14: DS13.C 189.61,162.43 v1(189.87,162.69)
  BOTTOM w0.14: Q10.3 190.73,162.69 v1(189.87,162.69)
UNNAMED_22_DIOLED_I216_P: length 1.7
  TOP w0.14: DS13.A R199.1
UNNAMED_22_DIOLED_I315_P: length 1.7
  TOP w0.14: R52.1 DS18.A
UNNAMED_22_DIOLED_I318_P: length 1.7
  TOP w0.14: DS14.A R61.1
UNNAMED_22_FSFUSE_I289_N1: length 14.1
  TOP w0.203: S1.5 199.38,134.37 ; S1.5 197.99,135.75 ; S1.5 197.99,132.98 ; S1.5 196.61,134.37 ; S1.2 203.19,134.37 ; S1.2 200.42,134.37 ; S1.2 201.8,135.75 ; S1.2 201.8,132.98 ; 193.5,134.17 F1.1 ; F1.1 194.4,135.25 ; F1.1 193.5,136.34
UNNAMED_22_RES_I56_N2: length 3.1
  TOP w0.381: R211.2 13.38,125.61 Q4.4
UNNAMED_22_RES_I206_N2: length 4.6
  TOP w0.203: R27.2 182.88,152.02 182.74,151.88 180.1,151.88 179.83,152.15 R50.2
UNNAMED_22_RES_I212_N2: length 5.4
  TOP w0.305: v1(173.35,155.45) 173.86,155.96 Q3.4
  BOTTOM w0.305: R518.2 173.61,155.19 v1(173.35,155.45)
UNNAMED_22_RES_I217_N2: length 7.5
  BOTTOM w0.203: R214.2 192.02,157.73 R215.1 191.52,159.99 Q10.1 192.81,160.3 R212.1
UNNAMED_22_RES_I227_N1: length 7.1
  BOTTOM w0.14: R219.1 R220.1 196.52,146.56 Q11.1 197.56,147.12 196.85,147.83 R218.2
